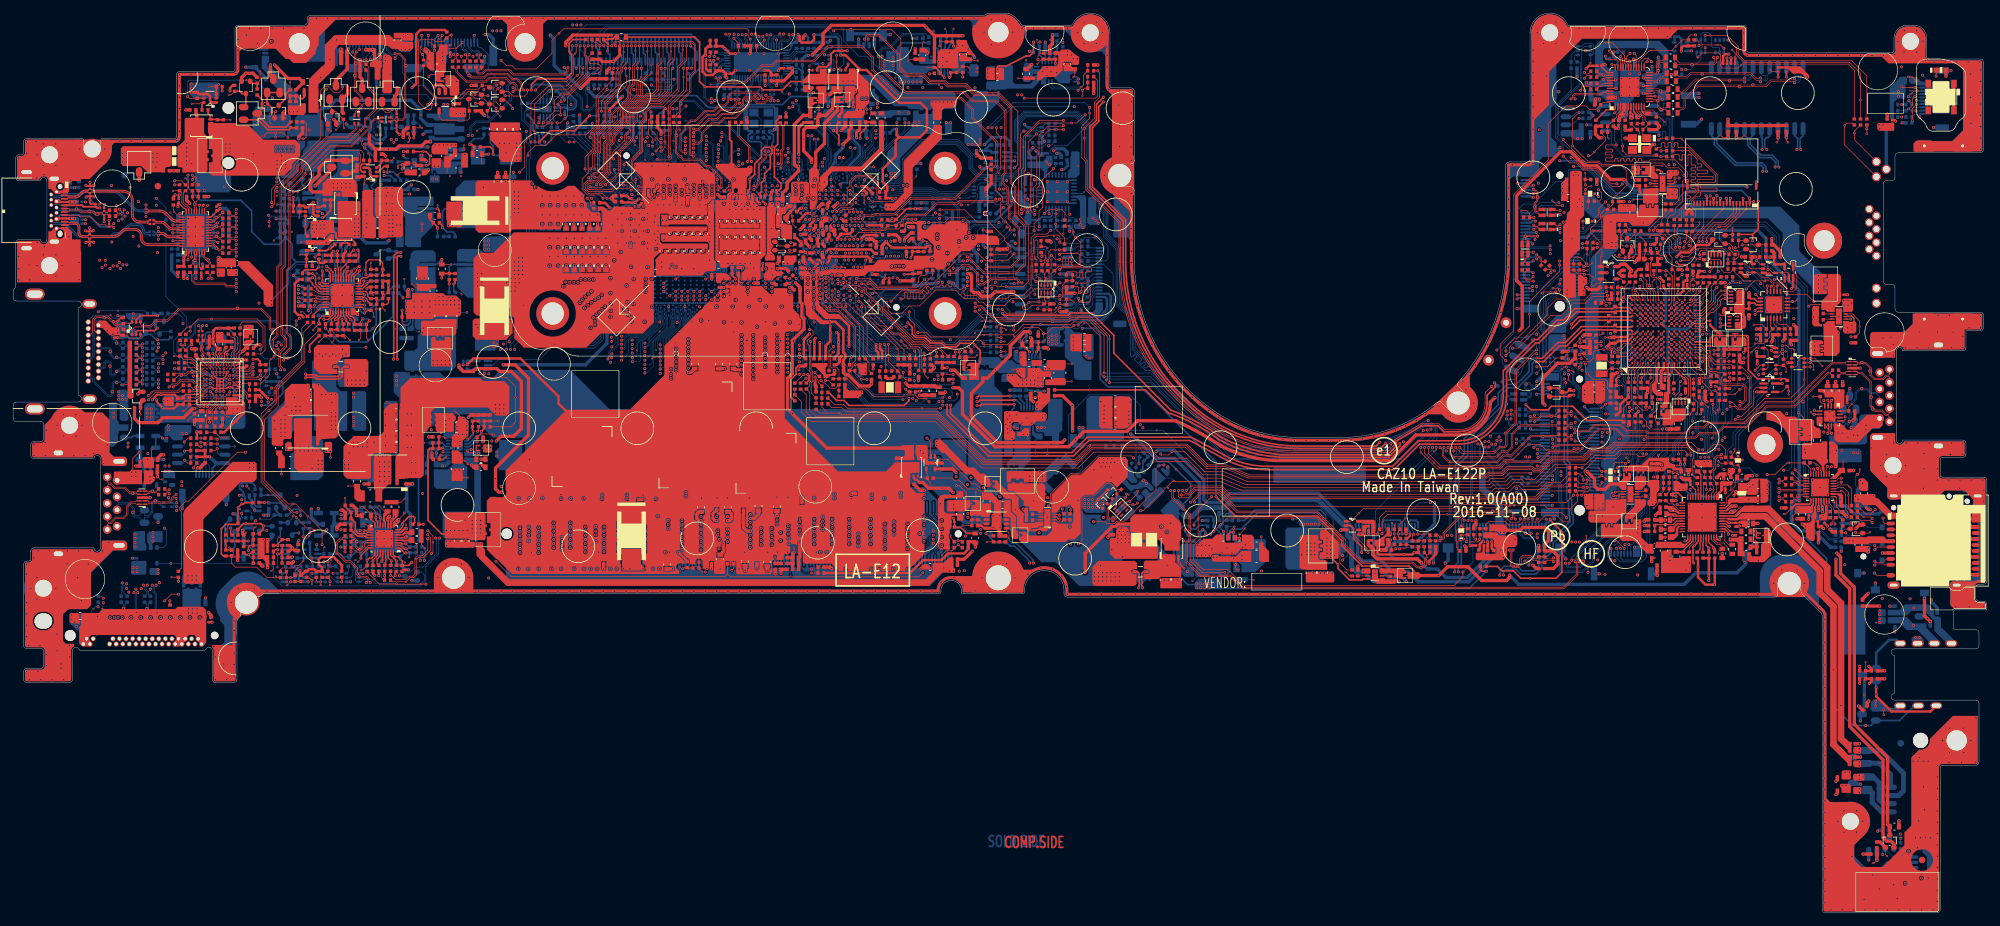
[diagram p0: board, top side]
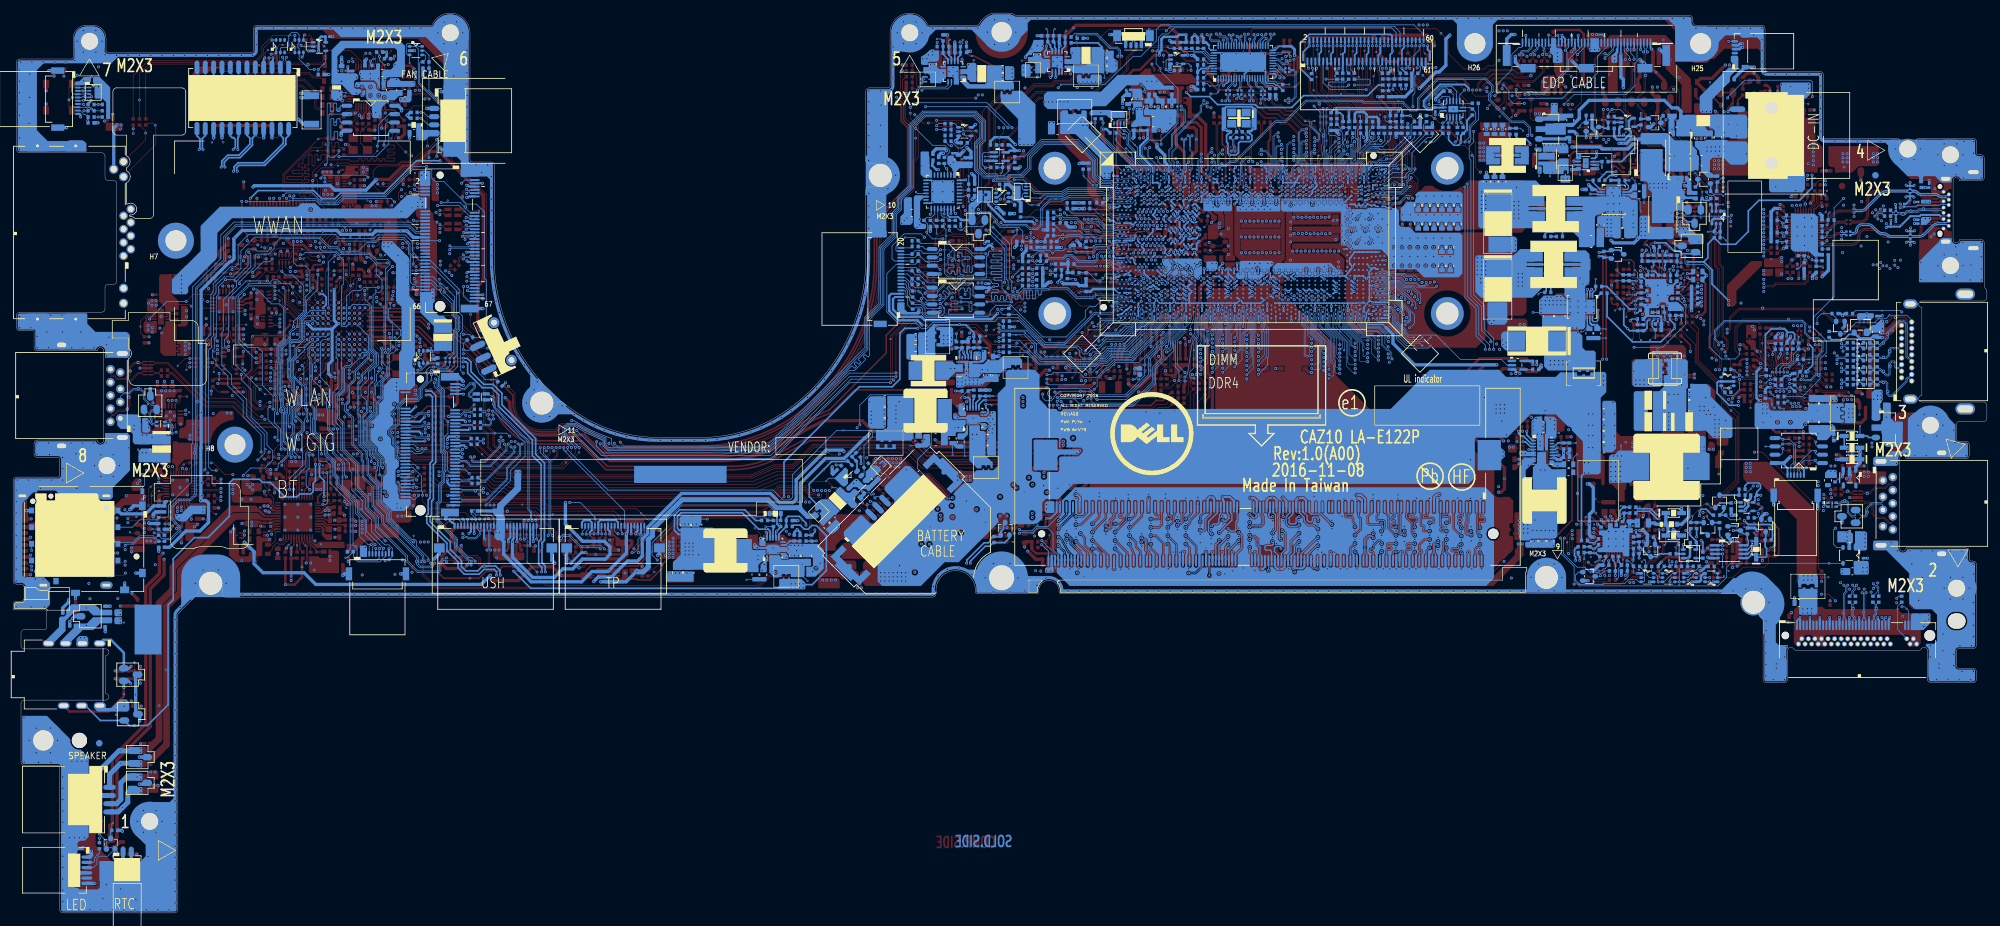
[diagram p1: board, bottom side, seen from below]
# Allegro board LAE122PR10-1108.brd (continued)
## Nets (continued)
ESPI_IO2: JESPI.5 RC368.2 UE1.G6
ESPI_IO2_R: RC368.1 UC1.BB13
ESPI_IO3: JESPI.6 RC369.2 UE1.L5
ESPI_IO3_R: RC369.1 UC1.AY12
ESPI_RESET#: UC1.BA11 UE1.K6
EXPANDER_ALERT#: T267.1(TP-1) UE2.7
EXPANDER_GPU_SMCLK: RE525.1 UE1.M4 UE2.19
EXPANDER_GPU_SMDAT: RE524.1 UE1.M7 UE2.20
FAN1_PWM: JFAN1.2 RE48.2 UE1.L10
FAN1_TACH: JFAN1.3 RE51.2 UE1.E3
FB_1.8VALW: PC503.2 PR501.2 PR506.1 PU501.6
FB_+1VALWP: PR306.2 PR308.2 PR311.1 PU301.4
FB_IA: PR645.2 PR648.2 PR650.1 PU602.17
FB_VSA: PR646.1 PR649.1 PR652.1 PU602.25
FCCM_GT: PR671.2 PU602.11
FCCM_IA: PR659.2 PU602.21
FCCM_VSA: PR679.2 PU602.29
FIVR_EN: RC217.1 RC218.1 RC219.1
FIVR_EN_R: JXDP1.45 RC126.2 RC132.1 RC217.2
GPIO126: RE5.1 UE1.E12
GPP_B23: RC317.1 UC1.AM7
GPP_C5: RC25.1 UC1.W1
GPP_C8: RC405.1 UC1.AB1
GPP_E23: T120.1(TP-1) UC1.N12
GPU_B+: PC664.1 PC665.1 PC672.1 PC673.1 PC679.1 PC688.1 PJP602.1 PU612.5
GT1P: PL612.3 PR674.2
GT_SNUB1: PC678.1 PR676.2
GT_SW1: PL612.4 PR676.1 PU612.4
H_CATERR#: RC79.1 UC1.D63
H_CPU_SVIDALRT#: RC153.1 UC1.B63
H_CPUPWRGD: CC300.1 RC77.2 UC1.A68
H_CPUPWRGD_R: RC77.1 T9.1(TP-1)
H_PROCHOT#: CC310.1 PC605.2 PR678.1 PR926.1 RC83.1 RC84.1 RE288.2
H_PROCHOT#_R: RC84.2 UC1.C65
H_PROCHOT#_R1: RE288.1 UE1.H13
H_THERMTRIP#: CC312.1 QE4.3 RC80.1 RD14.2 UC1.C63
H_VCCST_PWRGD_XDP: CC307.1 JXDP1.39 RC123.2 RC124.2
HDA_BIT_CLK: RC93.2 UC1.AY22
HDA_BIT_CLK_R: CC27.1 RA17.1 RC93.1 UA1.6
HDA_RST#: CC331.1 RC95.2 UC1.AW22
HDA_RST#_R: RA50.1 RC95.1
HDA_SDIN0: CC332.1 RA9.1 UC1.BA21
HDA_SDIN0_R: RA9.2 UA1.8
HDA_SDOUT: CC333.1 RC94.2 RC187.1 RC223.2 UC1.BB22
HDA_SDOUT_R: RC94.1 UA1.5
HDA_SYNC: RC92.2 UC1.BA22
HDA_SYNC_R: RC92.1 UA1.10
HDD_DET#: RPC4.1 UC1.H2
HDMI_CEC: JHDMI1.13 RV19.1
HDMI_CLKN: CV38.1 LV12.1 LV38.1 RV17.1
HDMI_CLKP: CV37.1 LV12.2 LV37.1 RV16.1
HDMI_CTRL_CLK: JHDMI1.15 QV3.6 RV22.1
HDMI_CTRL_DATA: JHDMI1.16 QV3.3 RV23.1
HDMI_HPD: JHDMI1.19 QV5.1 RV21.1
HDMI_L_CLKN: JHDMI1.12 LV12.4 LV38.2 RV35.1
HDMI_L_CLKP: JHDMI1.10 LV12.3 LV37.2 RV35.2
HDMI_L_TX_N0: JHDMI1.9 LV9.4 LV36.2 RV32.1
HDMI_L_TX_N1: JHDMI1.6 LV6.4 LV34.2 RV29.1
HDMI_L_TX_N2: JHDMI1.3 LV3.4 LV32.2 RV26.1
HDMI_L_TX_P0: JHDMI1.7 LV9.3 LV35.2 RV32.2
HDMI_L_TX_P1: JHDMI1.4 LV6.3 LV33.2 RV29.2
HDMI_L_TX_P2: JHDMI1.1 LV3.3 LV31.2 RV26.2
HDMI_OB: QV4.1 RV10.2 RV11.2 RV12.2 RV13.2 RV14.2 RV15.2 RV16.2 RV17.2
HDMI_TX_N0: CV36.2 LV9.1 LV36.1 RV15.1
HDMI_TX_N1: CV34.2 LV6.1 LV34.1 RV13.1
HDMI_TX_N2: CV32.2 LV3.1 LV32.1 RV11.1
HDMI_TX_P0: CV35.2 LV9.2 LV35.1 RV14.1
HDMI_TX_P1: CV33.2 LV6.2 LV33.1 RV12.1
HDMI_TX_P2: CV31.2 LV3.2 LV31.1 RV10.1
HOST_DEBUG_TX: JDEG1.8 RE73.2 RE306.2 RZ132.1 UE1.G11
HOST_SD_WP#: QR1.2 RC292.1 UC1.W10
HP_OUT_L: CA43.2 RA7.1 UA1.32
HP_OUT_R: CA44.2 RA8.1 UA1.33
HV_GATE1_A: RT64.1 UT5.B9
HV_GATE2_A: RT65.1 UT5.A9
HW_GPS_DISABLE#: DZ6.1 RE12.1 UE1.H5
HW_GPS_DISABLE#_R: DZ6.2 JNGFF2.18
I2C1_SCK_TP: RZ21.2 RZ29.1 UC1.U9
I2C1_SCK_TP_R: JKBTP1.2 RZ29.2 RZ117.2 RZ347.2
I2C1_SDA_TP: RZ20.2 RZ26.1 UC1.U8
I2C1_SDA_TP_R: JKBTP1.3 RZ26.2 RZ116.2 RZ346.2
I_ADP: PR935.2 UE1.B11
I_BATT: PR947.2 RE64.2
I_BATT_R: CE3.1 RE64.1 UE1.J4
I_SYS: PR620.1 PR936.2 RE312.2
I_SYS_R: CE4.1 RE312.1 RE313.1 UE1.J5
ILIM_SEL: RI13.1 UI3.4
ILMT_+1VALWP: PR307.2 PR310.1 PU301.3
ILMT_DDR: PR205.1 PR207.2 PU200.17
IMON_IA: PC625.2 PR629.2 PU602.14
IMON_VSA: PC643.1 PR651.1 PU602.23
IMVP_VR_ON: PR616.1 RE304.1 UE3.4 UE4.2
IMVP_VR_ON_EC: RE304.2 RPE10.2 UE1.N7 UE3.1
INT_SPK_L+: CA22.1 LA6.1 UA1.42
INT_SPK_L-: CA23.1 LA7.1 UA1.43
INT_SPK_R+: CA19.1 LA8.1 UA1.45
INT_SPK_R-: CA24.1 LA9.1 UA1.44
INT_SPKR_L+: DA6.3 JSPK1.1 LA6.2
INT_SPKR_L-: DA6.2 JSPK1.2 LA7.2
INT_SPKR_R+: DA7.2 JSPK1.3 LA8.2
INT_SPKR_R-: DA7.3 JSPK1.4 LA9.2
INTRUDER#: RC69.1 UC1.AP16
IR_CAM_DET#: JIR1.6 RC345.1 UC1.H5
ISH_I2C2_SCL: RC362.1 RZ76.1 UC1.AD12
ISH_I2C2_SCL_R: JNGFF2.32 RZ76.2
ISH_I2C2_SDA: RC363.1 RZ77.1 UC1.AD11
ISH_I2C2_SDA_R: JNGFF2.34 RZ77.2
ISH_UART0_CTS#: RZ80.1 UC1.U4
ISH_UART0_CTS#_R: JNGFF1.62 RZ80.2
ISH_UART0_RTS#: RZ81.1 UC1.U3
ISH_UART0_RTS#_R: JNGFF1.64 RZ81.2
ISH_UART0_RXD: RZ78.1 UC1.U1
ISH_UART0_RXD_R: JNGFF1.58 RZ78.2
ISH_UART0_TXD: RZ79.1 UC1.U2
ISH_UART0_TXD_R: JNGFF1.60 RZ79.2
ISUMN_GT: PC624.2 PC626.2 PC641.1 PH602.2 PL612.2 PR632.1 PR633.2 PR638.1
ISUMN_IA: PC642.2 PC645.1 PC646.2 PH605.2 PL610.2 PR640.2 PR644.2 PR656.2
ISUMN_VSA: PC633.2 PC637.2 PC644.1 PH604.2 PL614.2 PR636.2 PR641.2 PR643.1
ISUMP_GT: PC624.1 PC626.1 PR628.1 PR633.1 PR674.1 PU602.7
ISUMP_IA: PC642.1 PC646.1 PR656.1 PR657.1 PR661.2 PU602.19
ISUMP_VSA: PC633.1 PC637.1 PR624.2 PR642.1 PR643.2 PU602.27
ITP_PMODE: JXDP1.46 RC115.1 UC1.E8
JDIMM1_EVENT#: JDIMM1.134 RD14.1
JTAG_CLK: JDEG1.4 RPE7.3 UE1.C8
JTAG_RST#: CE30.1 JTAG1.1 RE63.1 RE65.1 UE1.G13
JTAG_TDI: JDEG1.2 RPE7.1 UE1.E9
JTAG_TDO: JDEG1.5 RPE7.4 UE1.F6
JTAG_TMS: JDEG1.3 RPE7.2 UE1.C5
KB_DET#: JKBTP1.20 RC288.1 UC1.D8
LAN_ACTLED_YEL#: QL1.6 RL14.1
LAN_ACTLED_YEL_R#: JLOM1.10 RL14.2
LAN_DISABLE#_R: RL5.1 RL7.2 RL9.1 UL1.3
LAN_MDIN0: RL72.1 UL1.14
LAN_MDIN0_L: RL72.2 TL1.11
LAN_MDIN1: RL74.1 UL1.18
LAN_MDIN1_L: RL74.2 TL1.5
LAN_MDIN2: RL76.1 UL1.21
LAN_MDIN2_L: RL76.2 TL1.7
LAN_MDIN3: RL78.1 UL1.24
LAN_MDIN3_L: RL78.2 TL1.1
LAN_MDIP0: RL71.1 UL1.13
LAN_MDIP0_L: RL71.2 TL1.12
LAN_MDIP1: RL73.1 UL1.17
LAN_MDIP1_L: RL73.2 TL1.6
LAN_MDIP2: RL75.1 UL1.20
LAN_MDIP2_L: RL75.2 TL1.8
LAN_MDIP3: RL77.1 UL1.23
LAN_MDIP3_L: RL77.2 TL1.2
LAN_TEST_EN: RL12.1 UL1.30
LAN_WAKE#: RC323.1 RL70.1 UC1.AM15 UE1.L3 UL1.2
LCD_CBL_DET#: JEDP1.40 RC287.1 UC1.AC3
LCD_TST: JEDP1.29 RE20.1 UE1.D1
LCD_VCC_TEST_EN: DV3.2 UE1.E1
LED_10_GRN#: QL2.6 RL19.1
LED_10_GRN_R#: JLOM1.11 RL19.2
LED_100_ORG#: QL1.3 RL20.1
LED_100_ORG_R#: JLOM1.13 RL20.2
LG1_ISL88738: PQ905.6 PU901.9
LG2_ISL88738: PQ904.6 PU901.7
LID_CL#: JLED1.5 RE26.1 UZ10.2
LID_CL#_NB: CE8.1 RE25.2 RE26.2 UE1.N11
LID_CL#_PCH: T268.1(TP-1) UC1.AW7
LINE1_L: CA43.1 UA1.22
LINE1_R: CA44.1 UA1.21
LM393_P: PC949.2 PC1201.2 PD1801.1 PR950.2 PU903.5 PU1201.8
LOM_ACTLED_YEL#: QL1.1 UL1.26
LOM_CABLE_DETECT#: RE505.1 UE1.D2 UL2.4
LOM_SPD10LED_GRN#: QL2.1 RL30.2 UL1.25 UL2.2
LOM_SPD100LED_ORG#: QL1.4 RL29.2 UL1.27 UL2.1
LPS_PROTECT#: PR1248.2 PT1.1(TP-1)
LPSS_UART2_RXD: JUART1.3 RC330.1 RC402.1 UC1.AD1
LPSS_UART2_TXD: JUART1.2 RC331.1 RC403.1 UC1.AD2
LX1_ISL88738: PC930.2 PL902.1 PQ905.7 PR923.1 PU901.10
LX2_ISL88738: PL902.2 PQ904.7 PR921.1 PR924.1 PU901.6
LX_1.8VALW: PL501.1 PR502.1 PU501.3
LX_1V_PRIM: PL404.1 PR409.1 PU402.2 PU402.3
LX_1VS_VCCIO: PL402.1 PR405.1 PU401.2 PU401.3
LX_3V: PC102.2 PL100.1 PR106.1 PU100.6 PU100.19 PU100.20
LX_5V: PC114.2 PL101.1 PR112.1 PU102.6 PU102.19 PU102.20
LX_DDR: PC205.2 PL201.1 PR202.1 PU200.11
M2280_DEVSLP: JNGFF3.38 RN37.2 UC1.J3
M2280_PCIE_SATA#: JNGFF3.69 RPC4.4 UC1.G4
M3042_DEVSLP: JNGFF2.30 UC1.J2
M3042_PCIE#_SATA: RPC4.2 UC1.H3 UE1.J12
MASK_BASE_LEDS#: QZ7.5 UZ10.4
ME_FW_EC: RC221.1 SW1.1 UE1.G12
ME_FWP: RC221.2 RC223.1 SW1.3
ME_RESET#: RC225.1 RC227.1 UC12.2
ME_SUS_PWR_ACK: RC74.1 UC1.AR13 UE1.B13
MEC_XTAL1: CE28.1 UE1.A1 YE1.1
MEC_XTAL2: CE29.1 RE290.2 YE1.2
MEC_XTAL2_R: RE290.1 UE1.A3
MEDIACARD_IRQ#: RR19.1 UC1.AN8 UR1.32
MEM_INTERLEAVED: RC371.1 RC372.1 UC1.P2
MEM_SMBCLK: CC320.1 QC2.6 RC12.1 UC1.R7
MEM_SMBDATA: QC2.3 RC14.1 UC1.R8
MPHYP_PWR_EN: RC387.1 UC1.AM10
MSCLK: JDEG1.6 RE30.1 RE72.2 UE1.H10
MSDATA: JDEG1.7 RE75.2 RE86.1 UE1.G9
MUX1_DP_SEL: RT89.1 UT9.23
MUX1_DPEQ0: RT139.1 RT140.1 RT306.1 UT9.14
MUX1_DPEQ1: RT247.1 RT248.1 RT303.1 UT9.2
MUX1_FLIP_SEL: RT69.1 RT375.1 UT9.21
MUX1_FLIP_SEL_R: RT69.2 UT5.B2
MUX1_I2C_EN: RT145.1 RT300.1 RT301.1 UT9.17
MUX1_SSEQ0: RT137.1 RT138.1 RT302.1 UT9.11
MUX1_SSEQ1: RT135.1 RT136.1 RT305.1 UT9.3
MUX1_USB_EQ0: RT143.1 RT144.1 RT304.1 UT9.38
MUX1_USB_EQ1: RT141.1 RT142.1 RT307.1 UT9.35
MUX1_USB_SEL: RT90.1 RT376.1 UT9.22
NB_PSID: PD4.2 PD4.3 PJPDC1.1 PL3.2
NRB_BIT: RC186.1 UC1.AR7
NTC_IA: PR635.2 PU602.15
NVME_LED#: JNGFF3.10 RN100.1
ONE_DIMM#: RC267.1 RC268.1 UC1.AP7
OTG_ID: RT74.1 UT5.E10
OTGEN/CMIN: PR919.2 PR960.2 PU901.20
PANEL_BKEN_EC: DV2.2 UE1.J9
PANEL_BKLEN: DV2.3 UC1.R12
PANEL_ID: CE47.1 RE300.2 UE1.J10
PBAT_CHARGER_SMBCLK: PD2.3 PR922.1 PRP1.3 RE43.1 UE1.N2
PBAT_CHARGER_SMBDAT: PD1.2 PR920.1 PRP1.2 RE37.1 UE1.M3
PBAT_PRES#: PD1.3 PR1.2 PR931.1 PRP1.1 UE1.F9
PBAT_PRES#_C: PBATT1.6 PRP1.8
PBAT_SMBCLK_C: PBATT1.4 PRP1.6
PBAT_SMBDAT_C: PBATT1.5 PRP1.7
PBATT+_C: PBATT1.1 PBATT1.2 PBATT1.3 PC1.1 PL1.1 PL2.1
PCH_ALW_ON: RPE10.3 RZ65.1 UE1.M8
PCH_BATLOW#: RC72.1 UC1.AU13
PCH_CL_CLK1: JNGFF1.42 UC1.G3
PCH_CL_DATA1: JNGFF1.40 UC1.G2
PCH_CL_RST1#: JNGFF1.38 UC1.G1
PCH_DPWROK: CC266.1 RC215.1 RC220.1 RE536.2 UC1.BB20 UE7.1
PCH_DPWROK_EC: RE34.1 UE1.F8
PCH_JTAG_TCK: JXDP1.55 RC86.1 UC1.B56
PCH_JTAG_TDI: CC304.1 RC81.1 RC229.2 UC1.D59
PCH_JTAG_TDO: CC303.1 RC82.1 RC230.2 UC1.A56
PCH_JTAG_TMS: RC130.1 RC228.2 UC1.C59
PCH_PCIE_WAKE#: RC67.1 RE274.2 UC1.BB15 UE1.L1
PCH_PLTRST#: RC60.1 RC62.1 RC244.1 UC1.AN10 UC7.1 UC7.2
PCH_PLTRST#_5105: RE340.1 UE1.K1 UE6.4
PCH_PLTRST#_AND: CZ61.1 JNGFF1.52 JNGFF1.66 JNGFF2.42 JNGFF3.50 RC65.1 RC325.1 RZ114.1 UC7.4 UR1.1
PCH_PLTRST#_EC: RC244.2 RE375.2 UE6.2
PCH_POPIRCOMP: RC89.1 UC1.AU16
PCH_PWROK: PR614.1 RC411.1 UC1.BA20
PCH_RSMRST#: RE342.1 RE363.2 RE364.2 UZ6.1
PCH_RSMRST#_AND: RC75.1 RC124.1 RC215.2 UC1.AY17 UZ6.4
PCH_RSMRST#_GPIO204: RE363.1 UE1.H2
PCH_RTCRST#: CC25.1 CMOS1.1 JAPS1.9 RC57.1 RE94.2 UC1.AM16
PCH_RTCX1: CC23.1 RC54.2 UC1.AM18 YC2.1
PCH_RTCX2: RC54.1 RC296.1 UC1.AM20
PCH_RTCX2_R: CC26.1 RC296.2 YC2.2
PCH_SMB_ALERT#: RC23.1 UC1.R10
PCH_SPI_CLK: JSPI1.13 RC35.1 UC1.AV2
PCH_SPI_CLK_0_R: RC29.1 RPC1.6 UC5.6
PCH_SPI_CLK_1_R: RC28.1 RC408.2 UC6.6
PCH_SPI_CLK_2_R: RZ60.2 RZ63.2 UZ12.19
PCH_SPI_CLK_R1: JSPI1.14 RC35.2 RC408.1 RPC1.3 RZ60.1
PCH_SPI_CS#0: JSPI1.11 RC36.1 UC1.AU3
PCH_SPI_CS#0_R1: JSPI1.12 RC36.2 RC37.1
PCH_SPI_CS#0_R2: RC37.2 UC5.1
PCH_SPI_CS#1: JSPI1.19 RC32.2 UC1.AU2
PCH_SPI_CS#1_R1: JSPI1.20 RC32.1 RC42.1
PCH_SPI_CS#1_R2: RC42.2 UC6.1
PCH_SPI_CS#2: RZ61.1 UC1.AU1
PCH_SPI_CS#2_R: RZ61.2 RZ113.1 UZ12.20
PCH_SPI_D0: JSPI1.17 RC10.2 RC33.1 UC1.AV3
PCH_SPI_D0_0_R: RPC1.7 UC5.5
PCH_SPI_D0_1_R: RC409.2 UC6.5
PCH_SPI_D0_2_R: RZ59.2 UZ12.21
PCH_SPI_D0_R1: JSPI1.18 RC33.2 RC409.1 RPC1.2 RZ59.1
PCH_SPI_D1: JSPI1.15 RC34.1 UC1.AW3
PCH_SPI_D1_0_R: RPC1.8 UC5.2
PCH_SPI_D1_1_R: RC410.2 UC6.2
PCH_SPI_D1_2_R: RZ58.2 UZ12.24
PCH_SPI_D1_R1: JSPI1.16 RC34.2 RC410.1 RPC1.1 RZ58.1
PCH_SPI_D2: JSPI1.9 RC11.2 RC38.1 UC1.AW2
PCH_SPI_D2_0_R: RC39.2 UC5.3
PCH_SPI_D2_1_R: RC43.2 UC6.3
PCH_SPI_D2_R1: JSPI1.10 RC30.1 RC38.2 RC39.1 RC43.1
PCH_SPI_D3: JSPI1.7 RC40.1 UC1.AU4
PCH_SPI_D3_0_R: RPC1.5 UC5.7
PCH_SPI_D3_1_R: RC407.2 UC6.7
PCH_SPI_D3_R1: JSPI1.8 RC31.1 RC40.2 RC316.1 RC407.1 RPC1.4
PCH_SPI_DO2_XDP: JXDP1.60 RC11.1
PCH_SPI_DO_XDP: RC10.1 RC128.1 RC133.1
PCI_CLK_LPC1: RC22.1 UC1.AY9
PCIE_PRX_C_DTX_N1: CR14.2 UR1.8
PCIE_PRX_C_DTX_N9: CL2.2 UL1.39
PCIE_PRX_C_DTX_P1: CR13.2 UR1.7
PCIE_PRX_C_DTX_P9: CL1.2 UL1.38
PCIE_PRX_DTX_N1: CR14.1 UC1.H13
PCIE_PRX_DTX_N3: JNGFF1.43 UC1.H16
PCIE_PRX_DTX_N4: JNGFF1.67 UC1.G15
PCIE_PRX_DTX_N9: CL2.1 UC1.E22
PCIE_PRX_DTX_N11: JNGFF3.29 UC1.E28
PCIE_PRX_DTX_N12: JNGFF3.43 UC1.E30
PCIE_PRX_DTX_P1: CR13.1 UC1.G13
PCIE_PRX_DTX_P3: JNGFF1.41 UC1.G16
PCIE_PRX_DTX_P4: JNGFF1.65 UC1.F15
PCIE_PRX_DTX_P9: CL1.1 UC1.E23
PCIE_PRX_DTX_P11: JNGFF3.31 UC1.E27
PCIE_PRX_DTX_P12: JNGFF3.41 UC1.F30
PCIE_PTX_C_DRX_N1: CR12.2 UR1.4
PCIE_PTX_C_DRX_N3: CZ13.2 JNGFF1.37
PCIE_PTX_C_DRX_N4: CZ15.2 JNGFF1.61
PCIE_PTX_C_DRX_N9: CL6.2 UL1.42
PCIE_PTX_C_DRX_N11: CN69.1 JNGFF3.35
PCIE_PTX_C_DRX_N12: CN71.1 JNGFF3.47
PCIE_PTX_C_DRX_P1: CR11.2 UR1.3
PCIE_PTX_C_DRX_P3: CZ12.2 JNGFF1.35
PCIE_PTX_C_DRX_P4: CZ14.2 JNGFF1.59
PCIE_PTX_C_DRX_P9: CL5.2 UL1.41
PCIE_PTX_C_DRX_P11: CN70.1 JNGFF3.37
PCIE_PTX_C_DRX_P12: CN72.1 JNGFF3.49
PCIE_PTX_DRX_N1: CR12.1 UC1.B17
PCIE_PTX_DRX_N3: CZ13.1 UC1.D17
PCIE_PTX_DRX_N4: CZ15.1 UC1.B19
PCIE_PTX_DRX_N9: CL6.1 UC1.B23
PCIE_PTX_DRX_N11: CN69.2 UC1.D24
PCIE_PTX_DRX_N12: CN71.2 UC1.A25
PCIE_PTX_DRX_P1: CR11.1 UC1.A17
PCIE_PTX_DRX_P3: CZ12.1 UC1.C17
PCIE_PTX_DRX_P4: CZ14.1 UC1.A19
PCIE_PTX_DRX_P9: CL5.1 UC1.A23
PCIE_PTX_DRX_P11: CN70.2 UC1.C24
PCIE_PTX_DRX_P12: CN72.2 UC1.B25
PCIE_RCOMPN: RC45.1 UC1.F5
PCIE_RCOMPP: RC45.2 UC1.E5
PCIE_WAKE#: JNGFF1.55 JNGFF1.70 JNGFF2.46 JNGFF3.54 RE274.1 RE275.2
PCIE_WAKE#_R: RE35.1 RE275.1 UE1.N13
PD1_GPIO2: RT71.1 UT5.D10
PD1_GPIO6: RT75.1 UT5.G10
PD1_GPIO7: RT339.1 UT5.D7
PD1_GPIO8: RT76.1 RT377.1 UT5.H6
PD#: CA31.1 DA8.2 RA18.1 RA48.2 RA50.2 UA1.47
PECI_EC: RE60.2 UC1.A54
PECI_EC_R: RE60.1 UE1.K13
PGOOD_3V: PR107.2 PR119.1 PU100.9
PGOOD_5V: PR113.2 PR120.1 PU102.9
PLTRST_LAN#: RC62.2 UL1.36
PLTRST_TPM#: RC60.2 RC325.2 UZ12.17
PM_LANPHY_ENABLE: RL7.1 UC1.AW17
PME#: T115.1(TP-1) UC1.AU11
POA_WAKE#: JUSH1.4 RE324.1 UE1.E4
PORT80_DET#: RE512.1 RE513.1 RZ131.1 UE1.K4
POWER_SW#_MB: CE10.1 JAPS1.11 RE33.2 SW3.2 SW3.4
POWER_SW_IN#: CE12.1 RE31.2 RE33.1 UE1.D5
PRIM_PWRGD_GPIO024: RE361.1 RE362.1 UE1.C1
PROCHOT#_ISL88738: PQ1216.1 PR926.2 PU901.23
PS_ID: PR4.1 PR5.2 UE1.L11
PWM1_GT: PR680.1 PU602.12 PU612.8
PWM_IA: PR662.1 PU602.22 PU610.8
PWM_SA: PR606.1 PU614.3
PWM_VSA: PR606.2 PU602.30
REM_DIODE1_N: CE24.1 CE35.1 QE3.3 UE1.A8
REM_DIODE1_P: CE24.2 CE35.2 QE3.1 QE3.2 UE1.A7
REM_DIODE2_N: CE26.1 CE37.2 CE46.2 QE5.3 QE7.1 QE7.2 UE1.A10
REM_DIODE2_P: CE26.2 CE37.1 CE46.1 QE5.1 QE5.2 QE7.3 UE1.A9
REM_DIODE4_N: CE27.1 CE39.1 QE6.3 UE1.A11
REM_DIODE4_P: CE27.2 CE39.2 QE6.1 QE6.2 UE1.B10
RES_BIAS: RL13.1 UL1.12
RESET_OUT#_R: CC33.1 JXDP1.47 RC128.2 RC129.2
RING2: LA10.1 RA5.2 UA1.17
RING2_R: CA4.1 CA13.2 DA3.3 JHP1.4 LA10.2
RJ45_MDIN0: JLOM1.2 TL1.14
RJ45_MDIN1: JLOM1.6 TL1.20
RJ45_MDIN2: JLOM1.5 TL1.18
RJ45_MDIN3: JLOM1.8 TL1.24
RJ45_MDIP0: JLOM1.1 TL1.13
RJ45_MDIP1: JLOM1.3 TL1.19
RJ45_MDIP2: JLOM1.4 TL1.17
RJ45_MDIP3: JLOM1.7 TL1.23
RTCRST_ON: QE12.2 RE93.1 RE514.2 RE515.2
RTCRST_ON_GPIO122: RE515.1 UE1.F11
RTCRST_ON_GPIO141: RE514.1 UE1.B6
RTD3_CIO_PWR_EN: T18.1(TP-1) UC1.AC2
RUN_ON: PR402.1 QE2.2 RE280.2 RE292.1 RZ320.1 RZ345.1 UE5.4 UZ3.5 UZ4.3 UZ35.2
RUN_ON#: QE2.5 QE2.6 RE68.1
RUN_ON_EC: RE292.2 RPE10.4 UE1.E8 UE5.2
RUNPWROK: QE2.3 RE67.1 UC8.1 UC8.4 UC8.10 UC8.13 UE1.G3
SA_LGATE: PQ501.8 PU614.5
SA_SNUB: PC622.1 PR627.2
SA_SW: PL614.4 PQ501.9 PR619.2 PR627.1 PU614.8
SA_UGATE: PQ501.1 PU614.1
SATA_LED_EN: QZ2.5 UE2.14
SATA_PRX_DTX_N1: JNGFF2.35 UC1.G21
SATA_PRX_DTX_P1: JNGFF2.33 UC1.F21
SATA_PTX_C_DRX_N1: CZ10.2 JNGFF2.39
SATA_PTX_C_DRX_P1: CZ11.2 JNGFF2.41
SATA_PTX_DRX_N1: CZ10.1 UC1.D21
SATA_PTX_DRX_P1: CZ11.1 UC1.C21
SATALED#: QZ2.4 RN100.2 RN101.2 RPC4.3 UC1.H1
SBIOS_TX: RE306.1 UC1.AB2
SD/MMCCD#: JSD1.9 UR1.30
SD/MMCCLK: RR5.1 UR1.17
SD/MMCCLK_R: CR21.1 JSD1.5 RR5.2
SD/MMCCMD: RR6.1 UR1.19
SD/MMCCMD_R: JSD1.3 RR6.2
SD/MMCDAT0/RCLK+: RR10.1 UR1.16
SD/MMCDAT0/RCLK+_R: JSD1.7 RR10.2
SD/MMCDAT1/RCLK-: RR9.1 UR1.15
SD/MMCDAT1/RCLK-_R: JSD1.8 RR9.2
SD/MMCDAT2: RR8.1 UR1.21
SD/MMCDAT2_R: JSD1.1 RR8.2
SD/MMCDAT3: RR7.1 UR1.20
SD/MMCDAT3_R: JSD1.2 RR7.2
SD_GPIO: RR3.2 UR1.28
SD_RCOMP: RC96.1 UC1.AB7
SD_UHS2_D0N: JSD1.19 UR1.25
SD_UHS2_D0P: JSD1.18 UR1.26
SD_UHS2_D1N: JSD1.21 UR1.23
SD_UHS2_D1P: JSD1.22 UR1.22
SDWP: QR1.1 UR1.29
SHD_CLK: RE374.1 UE1.J8
SHD_CLK_R1: RE374.2 UE9.6
SHD_CS#: RE98.1 RE364.1 UE1.M5 UE9.1
SHD_IO0: CE503.1 QE13.5 RE366.1 RE530.1 UE1.J7
SHD_IO0_R1: RE366.2 RE367.1
SHD_IO0_R2: RE367.2 UE9.5
SHD_IO1: RE368.1 UE1.L6
SHD_IO1_R1: RE368.2 RE369.1
SHD_IO1_R2: RE369.2 UE9.2
SHD_IO2: RE360.1 RE370.1 UE1.L7
SHD_IO2_R1: RE370.2 RE371.1 RE376.1
SHD_IO2_R2: RE371.2 UE9.3
SHD_IO3: RE372.1 UE1.M6
SHD_IO3_R1: RE372.2 RE373.1 RE377.1
SHD_IO3_R2: RE373.2 UE9.7
SIM_DET: JNGFF2.58 JSIM1.2
SIO_EXT_SCI#: RC237.1 RE341.1 UC1.AN7
SIO_EXT_SCI#_EC: RE341.2 UE1.M1
SIO_EXT_SMI#: RC346.1 RE338.1 UC1.A6
SIO_EXT_SMI#_EC: RE338.2 UE1.K7
SIO_EXT_WAKE#: RC283.1 UC1.AC1 UE1.M12
SIO_PWRBTN#: CC269.1 JXDP1.41 RC241.1 UC1.BA15 UE1.K11
SIO_RCIN#: RC13.1 RE339.1 UC1.AW13
SIO_RCIN#_EC: RE339.2 UE1.N3
SIO_SLP_A#: JAPS1.6 UC1.AN16 UE1.M11
SIO_SLP_LAN#: RC68.1 RC344.1 UC1.AW15 UE1.H9 UZ2.5
SIO_SLP_S0#: JAPS1.15 PR425.1 PR426.1 RZ112.1 RZ363.1 UC1.AT11 UZ35.1
SIO_SLP_S3#: JAPS1.2 QE11.2 RE280.1 UC1.AP15 UE1.K9 UE3.2 UE5.1
SIO_SLP_S4#: JAPS1.5 PR208.1 PR513.1 UC1.BA16 UE1.N12 UZ21.4 UZ34.2
SIO_SLP_S5#: JAPS1.4 UC1.AY16 UE1.N8
SIO_SLP_SUS#: PR312.2 PR406.1 PR504.1 RE349.1 RZ64.1 UC1.AN15 UZ34.1
SIO_SLP_WLAN#: RZ71.1 UC1.BB17 UE1.D9
SLEEVE: LA11.1 RA6.2 UA1.18
SLEEVE_R: CA1.2 CA12.1 DA3.2 JHP1.3 LA11.2
SLOT2_CONFIG_0: JNGFF2.13 RPE9.4 UE1.N9
SLOT2_CONFIG_1: JNGFF2.61 RPE9.3 UE1.M10
SLOT2_CONFIG_2: JNGFF2.67 RPE9.2 UE1.N10
SLOT2_CONFIG_3: JNGFF2.1 RPE9.1 UE1.F4
SLOT2_SATA_LED#: JNGFF2.10 RN101.1
SM_RCOMP0: RC5.1 UC1.AR18
SM_RCOMP1: RC6.1 UC1.AT18
SM_RCOMP2: RC7.1 UC1.AU18
SML0_SMBCLK: CC318.1 RC19.1 RC347.1 UC1.R9 UL1.28
SML0_SMBDATA: RC20.1 RC348.1 UC1.W2 UL1.31
SML1_SMBCLK: CC319.1 RC15.1 UC1.W3 UE1.D8
SML1_SMBDATA: RC17.1 UC1.V3 UE1.E11
SNB_+1VALWP: PC302.1 PR303.2
SNUB_1.8VALW: PC506.1 PR502.2
SNUB_1V_PRIM: PC419.1 PR409.2
SNUB_1VS_VCCIO: PC401.1 PR405.2
SNUB_CHG1: PC940.1 PR923.2
SNUB_CHG2: PC941.1 PR924.2
SPKR: RA12.2 RC183.1 UC1.AW5
SPKR_R: CA27.1 CA72.1 RA12.1 RA51.1
SRTCRST#: CC24.1 RC56.1 UC1.AN18
SS_1V_PRIM: PC420.1 PR428.1 PU402.7
SS_1VS_VCCIO: PC410.1 PR427.1 PU401.7
SUSACK#: UC1.AP11 UE1.K12
SUSCLK: RC48.1 RN99.2 RZ56.2 UC1.BA17
SUSCLK_R: JNGFF3.68 RN99.1
SW2_DP1_AUXN: CT81.1 CT116.1 RV70.1 UV7.29
SW2_DP1_AUXN_C: CT116.2 RT131.1 UT9.25
SW2_DP1_AUXP: CT80.1 CT115.1 RV76.1 UV7.28
SW2_DP1_AUXP_C: CT115.2 RT130.1 UT9.24
SW2_DP1_CADET: RV73.1 UV7.33
SW2_DP1_HPD: RT73.1 RT380.1 UV7.38
SW2_DP1_HPD_R: RT73.2 UT5.C10
SW2_DP1_N0: CT104.1 UV7.39
SW2_DP1_N0_C: CT104.2 UT9.10
SW2_DP1_N1: CT106.1 UV7.36
SW2_DP1_N1_C: CT106.2 UT9.13
SW2_DP1_N2: CT108.1 UV7.34
SW2_DP1_N2_C: CT108.2 UT9.16
SW2_DP1_N3: CT110.1 UV7.31
SW2_DP1_N3_C: CT110.2 UT9.19
SW2_DP1_P0: CT103.1 UV7.40
SW2_DP1_P0_C: CT103.2 UT9.9
SW2_DP1_P1: CT105.1 UV7.37
SW2_DP1_P1_C: CT105.2 UT9.12
SW2_DP1_P2: CT107.1 UV7.35
SW2_DP1_P2_C: CT107.2 UT9.15
SW2_DP1_P3: CT109.1 UV7.32
SW2_DP1_P3_C: CT109.2 UT9.18
SW2_DP2_AUXN: CV150.1 RV71.1 UV7.27
SW2_DP2_AUXN_C: CV150.2 JNGFF1.20
SW2_DP2_AUXP: CV149.1 RV77.1 UV7.26
SW2_DP2_AUXP_C: CV149.2 JNGFF1.22
SW2_DP2_CADET: RV74.1 UV7.43
SW2_DP2_HPD: JNGFF1.31 UV7.48
SW2_DP2_N0: CV156.1 UV7.49
SW2_DP2_N0_C: CV156.2 JNGFF1.32
SW2_DP2_N1: CV152.1 UV7.46
SW2_DP2_N1_C: CV152.2 JNGFF1.26
SW2_DP2_N2: CV148.1 UV7.44
SW2_DP2_N2_C: CV148.2 JNGFF1.25
SW2_DP2_N3: CV145.1 UV7.41
SW2_DP2_N3_C: CV145.2 JNGFF1.19
SW2_DP2_P0: CV157.1 UV7.50
SW2_DP2_P0_C: CV157.2 JNGFF1.34
SW2_DP2_P1: CV153.1 UV7.47
SW2_DP2_P1_C: CV153.2 JNGFF1.28
SW2_DP2_P2: CV147.1 UV7.45
SW2_DP2_P2_C: CV147.2 JNGFF1.27
SW2_DP2_P3: CV146.1 UV7.42
SW2_DP2_P3_C: CV146.2 JNGFF1.21
SW2_PS8338_CFG0: RV85.1 UV7.59
SW2_PS8338_P0: RV95.1 UV7.60
SW2_PS8338_P1: RV93.1 RV94.1 UV7.1
SW2_PS8338_PC10: RV90.1 RV91.1 UV7.56
SW2_PS8338_PC11: RV83.1 RV84.1 UV7.55
SW2_PS8338_PC20: RV81.1 RV82.1 UV7.54
SW2_PS8338_PC21: RV79.1 RV80.1 UV7.53
SW2_PS8338_PEQ: RV87.1 RV88.1 UV7.8
SW2_PS8338_SW: RV89.1 UV7.18
SW_+1VALWP: PL301.1 PR303.1 PR304.2 PU301.10
SW_USB20_N1: LI7.1 UI3.11
SW_USB20_P1: LI7.4 UI3.10
SYS_LED_MASK#: QL1.2 QL1.5 QL2.2 RE21.1 UE1.A12 UZ10.1
SYS_PWROK: RC129.1 RE56.1 UC1.B6 UE1.G4
SYS_RESET#: CC302.1 JAPS1.13 RC224.2 RC291.1 UC1.B5
SYS_RESET#_R: RC224.1 RC290.2 UC12.4
TBT_FORCE_PWR: T19.1(TP-1) UC1.B7
TBT_RESET_N_EC_R: RE95.2 UE1.L8
TBTA_AUXN_C: CT81.2 RT95.1 UT5.J2
TBTA_AUXP_C: CT80.2 RT96.1 UT5.J1
TBTA_BOT_N: RT122.2 UT5.L7
TBTA_BOT_N_R: DT20.1 JUSBC1.B7 RT122.1
TBTA_BOT_P: RT123.2 UT5.K7
TBTA_BOT_P_R: DT19.1 JUSBC1.B6 RT123.1
TBTA_CC1: CT86.1 DT7.1 JUSBC1.A5 RT104.2 UT5.L9
TBTA_CC2: CT85.1 DT16.1 JUSBC1.B5 RT105.2 UT5.L10
TBTA_DBG_CTL1: RT106.1 UT5.E4
TBTA_DBG_CTL2: RT107.1 UT5.D5
TBTA_DEBUG1: RT92.2 UT5.L2
TBTA_DEBUG2: RT93.2 UT5.K2
TBTA_DEBUG3: RT89.2 UT5.L3
TBTA_DEBUG4: RT90.2 UT5.K3
TBTA_LSRX_R: RT88.2 UT5.K4
TBTA_LSTX_R: RT87.2 UT5.L4
TBTA_MRESET: RT86.1 UT5.E11
TBTA_RESET_N_EC_R: RT110.2 UT5.F11
TBTA_ROM_CLK_PD: RT54.2 UT5.A3
TBTA_ROM_CLK_PD_R: JDB1.2 RT54.1 UT6.6
TBTA_ROM_CS#_PD: RT57.2 UT5.B3
TBTA_ROM_CS#_PD_R: JDB1.5 RT51.2 RT57.1 UT6.1
TBTA_ROM_DI_PD: RT55.2 UT5.B4
TBTA_ROM_DI_PD_R: JDB1.3 RT55.1 UT6.5
TBTA_ROM_DO_PD: RT56.2 UT5.A4
TBTA_ROM_DO_PD_R: JDB1.4 RT52.2 RT56.1 UT6.2
TBTA_ROM_HOLD#_PD: RT50.2 UT6.7
TBTA_ROM_WP#_PD: RT53.2 UT6.3
TBTA_ROSC: RT100.1 UT5.G2
TBTA_RX1N: DT14.1 JUSBC1.B10 UT9.31
TBTA_RX1P: DT13.1 JUSBC1.B11 UT9.30
TBTA_RX2N: DT9.1 JUSBC1.A10 UT9.39
TBTA_RX2P: DT10.1 JUSBC1.A11 UT9.40
TBTA_SBU1: DT8.1 JUSBC1.A8 RT108.2 RT132.2
TBTA_SBU1_R: RT108.1 UT5.K8
TBTA_SBU2: DT15.1 JUSBC1.B8 RT109.2 RT133.2
TBTA_SBU2_R: RT109.1 UT5.L8
TBTA_TOP_N: RT121.1 UT5.L6
TBTA_TOP_N_R: DT12.1 JUSBC1.A7 RT121.2
TBTA_TOP_P: RT120.1 UT5.K6
TBTA_TOP_P_R: DT11.1 JUSBC1.A6 RT120.2
TBTA_TX1N: CT96.1 UT9.34
TBTA_TX1N_C: CT96.2 DT6.1 JUSBC1.A3
TBTA_TX1P: CT95.1 UT9.33
TBTA_TX1P_C: CT95.2 DT5.1 JUSBC1.A2
TBTA_TX2N: CT98.1 UT9.36
TBTA_TX2N_C: CT98.2 DT18.1 JUSBC1.B3
TBTA_TX2P: CT97.1 UT9.37
TBTA_TX2P_C: CT97.2 DT17.1 JUSBC1.B2
TDI_XDP: JXDP1.56 RC229.1 UC8.5
TDO_XDP: CC306.1 JXDP1.52 RC230.1 UC8.2
THERMATRIP1#: RE301.1 UE1.B12
THERMATRIP2#: CE36.1 QE4.1 RE69.2 UE1.H3
TOUCH_SCREEN_DET#: JEDP1.32 RV8.1 UC1.AY5
TOUCH_SCREEN_PD#: JEDP1.5 RC272.1 UC1.A7
TOUCHPAD_INTR#: JKBTP1.5 RC414.1 RE318.2 UC1.BA5
TP_LAN_JTAG_TCK: RL2.1 UL1.35
TP_LAN_JTAG_TDI: T88.1(TP-1) UL1.32
TP_LAN_JTAG_TDO: T89.1(TP-1) UL1.34
TP_LAN_JTAG_TMS: RL1.1 UL1.33
TPM_GPIO4: T283.1(TP-1) UZ12.13
TPM_LPM#: QZ9.1 RZ111.1 RZ363.2 UZ12.3
TPM_PIRQ#: RZ69.2 UC1.AP8 UZ12.18
TPM_TYPE: RC349.1 UC1.AY7
TRST#_XDP: JXDP1.54 UC8.12
TUSB546A_SBU1_R: RT132.1 UT9.27
TUSB546A_SBU2_R: RT133.1 UT9.26
TYPEC_ID: CE62.1 RE343.1 UE1.F2
UART_MISO: RT82.1 RT83.1 UT5.F2
UART_MOSI: RT81.1 RT83.2 UT5.E2
UG1_ISL88738: PQ905.1 PU901.11
UG2_ISL88738: PQ904.1 PU901.5
UIM_CLK: CZ38.1 JNGFF2.24 JSIM1.C3
UIM_DATA: CZ39.1 JNGFF2.26 JSIM1.C7 RZ335.2
UIM_RESET: CZ40.1 JNGFF2.22 JSIM1.C2
UPD1_ALERT#: RE91.1 RT60.1 UE1.F10
UPD1_SMBCLK: QT1.1 RE303.1 RT58.1 UE1.C3
UPD1_SMBCLK_Q: QT1.6 RT58.2 RT67.1 RT92.1 RT375.2 UT5.B5
UPD1_SMBDAT: QT1.4 RE302.1 RT59.1 UE1.B4
UPD1_SMBDAT_Q: QT1.3 RT59.2 RT66.1 RT93.1 RT376.2 UT5.A5
UPD1_SMBUS_ALERT#: RT60.2 RT68.1 UT5.B6
UPD2_ALERT#: RE92.1 UE1.F5
UPD2_SMBCLK: RPE12.3 UE1.D7
UPD2_SMBDAT: RPE12.4 UE1.E7
USB2_ID: RC337.1 RT74.2 UC1.AG3
USB2_VBUSSENSE: RC338.1 UC1.AG4
USB3_PRX_C_DTX_N6: CT112.2 UT9.4
USB3_PRX_C_DTX_P6: CT111.2 UT9.5
USB3_PRX_DTX_N1: DI4.1 DI4.9 JUSB1.5 UC1.H8
USB3_PRX_DTX_N2: LI16.4 RI28.1 UC1.J6
USB3_PRX_DTX_N3: DI1.1 DI1.9 JUSB2.5 UC1.J10
USB3_PRX_DTX_N6: CT112.1 UC1.G11
USB3_PRX_DTX_P1: DI4.2 DI4.8 JUSB1.6 UC1.G8
USB3_PRX_DTX_P2: LI16.1 RI27.1 UC1.H6
USB3_PRX_DTX_P3: DI1.2 DI1.8 JUSB2.6 UC1.H10
USB3_PRX_DTX_P6: CT111.1 UC1.F11
USB3_PRX_L_DTX_N2: JNGFF2.21 LI16.3 RI28.2
USB3_PRX_L_DTX_P2: JNGFF2.23 LI16.2 RI27.2
USB3_PTX_C_DRX_N1: CI13.1 DI4.4 DI4.7 JUSB1.8
USB3_PTX_C_DRX_N2: CI29.1 LI17.1 RI30.1
USB3_PTX_C_DRX_N3: CI5.1 DI1.4 DI1.7 JUSB2.8
USB3_PTX_C_DRX_N6: CT114.2 UT9.7
USB3_PTX_C_DRX_P1: CI16.1 DI4.5 DI4.6 JUSB1.9
USB3_PTX_C_DRX_P2: CI30.1 LI17.4 RI29.1
USB3_PTX_C_DRX_P3: CI4.1 DI1.5 DI1.6 JUSB2.9
USB3_PTX_C_DRX_P6: CT113.2 UT9.8
USB3_PTX_DRX_N1: CI13.2 UC1.C13
USB3_PTX_DRX_N2: CI29.2 UC1.B13
USB3_PTX_DRX_N3: CI5.2 UC1.B15
USB3_PTX_DRX_N6: CT114.1 UC1.D16
USB3_PTX_DRX_P1: CI16.2 UC1.D13
USB3_PTX_DRX_P2: CI30.2 UC1.A13
USB3_PTX_DRX_P3: CI4.2 UC1.A15
USB3_PTX_DRX_P6: CT113.1 UC1.C16
USB3_PTX_L_DRX_N2: JNGFF2.27 LI17.2 RI30.2
USB3_PTX_L_DRX_P2: JNGFF2.29 LI17.3 RI29.2
USB20_N1: UC1.AB9 UI3.2
USB20_N1_R: DI5.2 JUSB1.2 LI7.2
USB20_N2: LI3.1 UC1.AD6
USB20_N2_R: DI2.3 JUSB2.2 LI3.2
USB20_N4: LI8.1 RI48.1 UC1.AD9
USB20_N4_L: JNGFF2.9 LI8.2 RI48.2
USB20_N5: LZ1.1 UC1.AJ1
USB20_N5_R: DV8.1 JEDP1.12 LZ1.2
USB20_N7: LI9.1 RI50.1 UC1.AH1
USB20_N7_L: JNGFF1.5 LI9.2 RI50.2
USB20_N8: LV27.3 UC1.AF8
USB20_N8_R: DV4.2 JEDP1.2 LV27.4
USB20_N9: UC1.AG1 UT5.K5
USB20_N10: JUSH1.8 UC1.AH7
USB20_P1: UC1.AB10 UI3.3
USB20_P1_R: DI5.3 JUSB1.3 LI7.3
USB20_P2: LI3.4 UC1.AD7
USB20_P2_R: DI2.2 JUSB2.3 LI3.3
USB20_P4: LI8.4 RI47.1 UC1.AD10
USB20_P4_L: JNGFF2.7 LI8.3 RI47.2
USB20_P5: LZ1.4 UC1.AJ2
USB20_P5_R: DV7.1 JEDP1.13 LZ1.3
USB20_P7: LI9.4 RI49.1 UC1.AH2
USB20_P7_L: JNGFF1.3 LI9.3 RI49.2
USB20_P8: LV27.2 UC1.AF9
USB20_P8_R: DV4.3 JEDP1.3 LV27.1
USB20_P9: UC1.AG2 UT5.L5
USB20_P10: JUSH1.9 UC1.AH8
USB_OC0#: RPC3.3 UC1.A9 UI3.13
USB_OC1#: RPC3.2 UC1.C9 UI1.3
USB_OC2#: RPC3.1 UC1.D9
USB_OC3#: RPC3.4 UC1.B9
USB_PWR_EN1#: RPE11.3 UE1.K3 UI1.4
USB_PWR_EN2#: RPE11.4 UE1.G5
USB_PWR_SHR_LFT_EN#: RPE11.2 UE1.J3 UI3.6
USB_PWR_SHR_VBUS_EN: RPE11.1 UE1.J2 UI3.5
USBCOMP: RC44.1 UC1.AB6
USH_DET#: DZ7.2 RE526.2 RZ87.1 UE1.C13
USH_DET#_R: DZ7.1 JUSH1.26 RZ87.2
USH_PWR_STATE#: JUSH1.22 RZ10.2 UE2.9
USH_RST#_R: JUSH1.21 RZ114.2
USH_SMBCLK: CZ62.1 JUSH1.11 RZ8.2 UE1.B3
USH_SMBDAT: CZ63.1 JUSH1.12 RZ9.2 UE1.E5
VCI_IN1#: RE507.1 UE1.B5
VCI_IN2#: RE508.1 UE1.D4
VCT_LAN_R1: RL3.1 UL1.6
VGA_ID: RE84.1 RE85.1 UE1.H11
VID0_PRIM_CORE: PR408.2 PR418.2 PR420.1 PU402.9
VID0_VCCIO: PR414.2 PR416.1 PU401.9
VID1_PRIM_CORE: PR411.2 PR417.2 PR419.1 PU402.8
VID1_VCCIO: PR413.2 PR415.1 PU401.8
VIDALERT_N: PR604.2 PR625.1 RC152.1 RC153.2
VIDALERT_N_B: PR625.2 PU602.36
VIDSCLK: CC321.1 PR601.2 PR618.1 UC1.A63
VIDSCLK_B: PR618.2 PU602.37
VIDSOUT: PR605.2 PR626.1 RC157.1 UC1.D64
VIDSOUT_B: PR626.2 PU602.35
VRALERT#: RC73.1 UC1.AM11
VSA_SEN+: PC640.2 PC650.1 PC652.1 PR649.2 RC168.2 UC1.H20
VSA_SEN-: PC649.1 PC650.2 PU602.26 RC166.1 UC1.H21
VSET_5105: CE38.1 RE77.1 UE1.C9
WIGIG_32KHZ: JNGFF1.50 RZ56.1
WLAN_COEX1: JNGFF1.48 RZ130.2
WLAN_COEX2: JNGFF1.46 RZ129.2
WLAN_COEX3: JNGFF1.44 RZ128.2
WLAN_WIGIG60GHZ_DIS#: DZ1.1 RE8.1 UE1.L13
WLAN_WIGIG60GHZ_DIS#_R: DZ1.2 JNGFF1.56
WRST#: CE500.1 RE6.2 UE2.4
WWAN_COEX1: JNGFF2.56 RZ130.1
WWAN_COEX2: JNGFF2.54 RZ129.1
WWAN_COEX3: JNGFF2.52 RZ128.1
WWAN_PWR_EN: CZ198.1 JNGFF2.6 RZ43.1
WWAN_RADIO_DIS#: DZ5.1 RE10.1 UE1.M2
WWAN_RADIO_DIS#_R: DZ5.2 JNGFF2.8
WWAN_WAKE#: JNGFF2.15 RE38.1 UE1.M13
XCLK_BIASREF: RC52.1 RC324.1 UC1.E42
XDP_DBRESET#: CC32.1 JXDP1.48 RC137.1 RC290.1 UC12.1
XDP_JTAGX: CC305.1 RC87.1 RC328.2 UC1.A59
XDP_OBS0: JXDP1.21 RC239.2
XDP_OBS0_R: RC239.1 UC1.C55
XDP_OBS1: JXDP1.23 RC240.2
XDP_OBS1_R: RC240.1 UC1.D55
XDP_OBS2_R: T10.1(TP-1) UC1.B54
XDP_OBS3_R: T11.1(TP-1) UC1.C56
XDP_PRSNT_PIN1: JXDP1.1 RC121.1 RC122.1
XDP_TMS: JXDP1.58 RC228.1 UC8.9
XTAL24_IN: CC21.1 RC46.2 UC1.E37 YC1.3
XTAL24_OUT: RC46.1 RC295.1 UC1.E35
XTAL24_OUT_R: CC22.1 RC295.2 YC1.1
XTALI: CL14.1 RL11.2 UL1.10 YL1.1
XTALO: RL11.1 RL34.2 UL1.9
XTALO_R: CL13.1 RL34.1 YL1.3
Z2805: RL18.1 TL1.22
Z2806: RL16.1 TL1.16
Z2807: RL17.1 TL1.21
Z2808: RL15.1 TL1.15
N04748: PC939.1 PR929.1 PU901.3
N16399089: PD901.1 PD903.1 PD904.1 PR916.2
N16400770: PR901.3 PR910.1
N16404606: PD905.3 PR939.2 PR950.1
N16404788: PD905.1 PU903.1
N16775301: PC208.2 PR204.2 PR206.1 PU200.16
N16775385: PC218.1 PU200.3
N16775433: PC204.1 PR202.2
N16775513: PC205.1 PR203.2
N16775517: PR203.1 PU200.12
N16776853: PC207.1 PU200.14
N16783014: PC111.1 PR104.1 PR105.1 PU100.16 PU100.17
N16783095: PC113.2 PR108.1
N16783134: PC127.2 PR117.1
N16783223: PC119.1 PU102.16 PU102.17
N16784595: PC102.1 PR100.2
N16784799: PC114.1 PR111.2
N17185092: PQ1204.6 PR1214.2 PR1218.2
N17188126: PR1211.2 PU1200.1
N17188417: PR1215.2 PU1200.2
N17263481: PR612.2 PR614.2 PU602.39
N17264741: PR616.2 PU602.40
N17335638: PC515.2 PR515.2 PR516.1 PU503.3
N17340170: PQ1205.1 PR1215.1 PR1226.2
N17370862: PC4.2 PQ4.4 PQ5.1 PR11.2 PR16.1
N17370885: PQ5.2 PR10.2 PR15.1
N17370921: PQ1.6 PR15.2
N17370927: PQ7.1 PR16.2
N17370961: PL3.1 PQ2.1 PR3.1 PR6.2
N17370983: PQ2.3 PR3.2 PR5.1
N17370995: PQ3.2 PR6.1 PR8.2
N17370999: PQ2.2 PQ3.1 PR7.2
N17371029: PC6.1 PQ9.4 PR12.2 PR18.1
N17371043: PQ6.1 PR18.2
N17371182: PQ6.2 PR23.2
N17371184: PR23.1 PU1.4
N17371196: PR21.2 PU1.1
N17371207: PQ8.1 PR22.1 PR27.1
N17372066: PQ1.3 PR17.2 PR19.2
N17372074: PQ1.5 PR25.1
N17372833: PC1206.1 PR1201.2 PR1203.1 PR1219.1 PU1201.3
N17479322: PQ1215.2 PR1251.2 PR1252.1
N17494434: PC1211.1 PD1205.1 PQ1212.1 PR1238.1 PR1239.2 PR1246.1 PR1255.2 PU1201.5
N17509431: PC947.1 PR935.1 PR947.1 PR949.2
N17509921: PD905.2 PR941.2
N17522701: PR942.2 PU903.2
N17670003: PR936.1 PR948.1 PU901.30
N17739728: PQ1205.3 PR1221.2 PR1224.1
N17747591: PQ8.3 PR26.2 PR28.1
N17747606: PQ8.2 PR29.2
N17765266: PR933.2 PR951.2 PU901.26
N17768164: PQ1210.5 PR1245.2
N17769037: PQ1207.6 PQ1211.4 PR1230.1 PR1258.2
N17769560: PQ1211.5 PR1233.1 PR1242.2
N17769738: PQ1211.2 PR1235.1 PR1257.2
N17770477: PQ1207.2 PQ1207.3 PR1232.1
N17771093: PQ1207.5 PR1241.2
N17771333: PQ1208.6 PQ1211.1 PR1234.1 PR1261.2
N17771663: PQ1208.2 PQ1208.3 PR1259.1
N17772624: PQ1208.5 PR1244.2 PR1260.2 PR1261.1
N17801240: PC1210.1 PQ1206.4 PR1228.2 PR1229.1
N17802718: PC1202.2 PQ1213.4 PQ1215.1 PR1205.2 PR1212.1
N17804163: PC1203.2 PQ1202.4 PQ1203.1 PR1207.2 PR1213.1
N17890941: PR1216.1 PU1200.4
N17892124: PQ1214.6 PR1252.2
N18264144: PQ7.2 PR20.1
N18265642: PQ1201.2 PR1216.2
N18265900: PQ1201.5 PR1220.2
N18266224: PC1213.1 PD1205.2 PR1238.2 PR1240.2 PR1243.1 PU1201.7
N18266545: PC1214.1 PQ1209.5 PR1243.2
N18267253: PQ1212.2 PR1248.1 PR1249.1 PR1250.1
N18268286: PQ1205.2 PR1225.2
N18277029: PR404.2 PR425.2 PU401.14
N18277134: PR410.2 PR426.2 PU402.14
N18278112: PR620.2 PU602.1
N18278782: PC930.1 PR914.2
N18278920: PR920.2 PU901.21
N18278998: PR922.2 PU901.22
N18287403: PQ1.2 PR19.1
N18287500: PR22.2 PU1.2
N18288083: PR946.1 PU903.4
N18288371: PQ1204.5 PR1218.1
N18288510: PQ1204.2 PR1223.1
N18290168: PR949.1 PU901.29
N18290418: PR423.1 PR424.1 PU402.5
N18325201: CL16.1 TL1.3
N18325205: CL17.1 TL1.4
N18325209: CL20.1 TL1.9
N18325213: CL21.1 TL1.10
N18364501: RV97.1 UV7.20
N18366912: CV96.1 UV7.17
N18421193: PL614.3 PR624.1
N18490882: RI14.2 UI3.16
N18762046: CA33.1 RA17.2
N18762152: CZ127.1 UZ5.10
N18762172: CZ126.1 UZ5.12
N18762349: CA51.1 RA44.1 UA1.27
N18762353: CA53.1 UA1.7
N18762355: CA52.1 UA1.39
N18762401: RA53.1 RA54.1 UA1.20
N18762411: CA29.1 UA1.35
N18762416: CA29.2 UA1.37
N18762426: CA35.1 UA1.28
N18762428: CA49.1 UA1.34
N18762438: CA25.1 UA1.19
N20151644: PR901.2 PR909.1
N20880735: PC307.2 PR308.1
N24606174: PC313.1 PU301.5
N27076067: PC944.1 PR934.2
N27077001: PR917.2 PR937.2
N28424999: T113.1(TP-1) UC1.AW71
N28425002: T114.1(TP-1) UC1.AW70
N28489601: RC222.1 SW1.2
N28769860: PR421.2 PR422.1 PU401.5
N28810563: CZ110.1 UZ2.10
N28811129: CZ114.1 UZ3.10
N28856399: T16.1(TP-1) UC1.BA70
N28856402: T17.1(TP-1) UC1.BA68
N28857231: T12.1(TP-1) UC1.BB68
N28857234: T13.1(TP-1) UC1.BB69
N28857237: T14.1(TP-1) UC1.AK13
N28857240: T15.1(TP-1) UC1.AK12
N28861827: RC120.1 UC1.C64
N28938912: CC8.1 RC29.2
N28938914: CC7.1 RC28.2
N29708559: T126.1(TP-1) UC1.AY4
N29708561: T127.1(TP-1) UC1.BB3
N29708639: T130.1(TP-1) UC1.BB5
N30342894: QV4.2 RV18.2
N31877076: JEDP1.21 LV1.1
N32590572: CZ117.1 UZ4.12
N32592963: CZ118.1 UZ4.10
N32594166: CZ109.1 UZ2.12
N32595008: RZ70.2 RZ71.2 UZ2.3
N32817808: CZ113.1 UZ3.12
N32818355: RZ64.2 RZ65.2 UZ3.3
N32819772: CZ121.1 UZ8.6
N33612393: CD31.2 RD18.1
N35551576: PQ1209.2 PQ1209.3 PR1236.1
N35551581: PQ1209.6 PR1229.2
N35551592: PC1212.1 PR1237.2 PR1247.1 PU1201.6
N35551655: PC1205.1 PR1208.2 PR1217.1 PU1201.2
N35551713: PQ1201.6 PR1212.2
N35551785: PQ1203.2 PR1202.2 PR1209.1
N35551806: PQ1204.3 PR1209.2
N35551822: PQ1201.3 PR1213.2
N36626863: CT90.1 RT111.2 UT7.3
N36827741: RZ120.2 UZ26.4 UZ34.4
N38749366: QV2.1 RV5.2
N38749387: QV7.1 QV8.2 RV6.1
N38798736: RT97.2 RT98.1 RT99.1 UT5.F10
N38798744: RT85.1 UT5.G4
N38798745: RT84.1 UT5.F4
N38798858: RT63.1 UT5.F1
N38798904: RT105.1 UT5.K10
N38798905: RT104.1 UT5.K9
N38798908: RT103.1 UT5.L11
N38798948: RT85.2 T220.1(TP-1)
N38798949: RT84.2 T219.1(TP-1)
N38799002: CT87.1 UT5.H7
N38799008: RT101.1 UT5.D6
N39468508: PC647.2 PR650.2
N39468570: PC629.2 PR639.1
N39469485: PH601.2 PR610.1 PR631.2
N39469718: PC627.1 PR632.2
N39469776: PH603.2 PR635.1 PR647.2
N39469798: PR679.1 PU614.7
N39469812: PH602.1 PR628.2
N39469818: PC631.1 PR630.2
N39469863: PC632.1 PR636.1 PU602.28
N39469888: PC627.2 PR638.2 PU602.8
N39469908: PC617.2 PR621.1
N39469972: PR678.2 PU602.38
N39469996: PC611.2 PU614.2
N39469998: PC611.1 PR619.1
N39470055: PC630.1 PR640.1 PU602.20
N39470129: PC640.1 PR646.2
N39470145: PC601.1 PR652.2
N39470169: PC630.2 PR644.1
N39470173: PC632.2 PR641.1
N39470189: PH604.1 PR642.2
N39470248: PC621.2 PR623.1
N39470250: PR621.2 PR622.2 PR623.2 PU602.5
N39470270: PH605.1 PR657.2
N39470326: PC616.2 PR617.2 PU602.4
N39470328: PC614.2 PR617.1
N39470344: PR610.2 PU602.3
N39470375: PC613.2 PR613.2 PU602.2
N39470446: PC603.1 PR602.1 PU602.34
N39470448: PC604.1 PR603.1 PU602.33
N39470528: PR608.1 PU602.32
N39470532: PR611.1 PU602.31
N39470546: PC639.2 PR645.1
N39473183: PL610.3 PR661.1
N39473185: PC671.2 PU612.7
N39473187: PR672.2 PU612.6
N39473189: PC671.1 PR672.1
N39473240: PR671.1 PU612.1
N39473270: PC655.2 PU610.7
N39473272: PR660.2 PU610.6
N39473274: PC655.1 PR660.1
N39473308: PR659.1 PU610.1
N41288260: JNGFF2.17 RZ326.1
N41303246: CZ38.2 RZ334.1
N44311288: QE11.3 RE70.1 RE90.2
N44311298: QE4.2 RE70.2
N44321668: RE57.1 RE58.1 UE1.B1
N44321726: RE318.1 UE1.G2
N44321827: RE349.2 UE1.N4
N44321953: CE57.1 RE350.2
N44725169: CZ197.1 RZ345.2 UZ8.3
N44851953: JNGFF2.59 T225.1(TP-1)
N44905504: JDIMM1.162 T50.1(TP-1)
N44907662: JDIMM1.165 T51.1(TP-1)
N45160305: JESPI.8 RE375.1
N45499007: QZ3.1 RZ25.1
N45523002: RE13.2 RE14.1 UE2.1
N45523004: RE15.2 RE16.1 UE2.2
N45523094: RE17.2 RE18.1 UE2.3
N45601552: RT378.1 UT5.D1
N45601554: RT379.1 UT5.D2
N46166384: RT380.2 UT9.32
N46226517: CZ56.1 RZ63.1
N46226641: RZ112.2 RZ362.2 UZ12.29
N46226670: RZ62.1 UZ12.27
N46226856: QZ9.2 RZ113.2
N46293588: JNGFF2.48 RZ131.2
N46293598: JNGFF2.50 RZ132.2
N46460386: QE12.1 RE94.1
N47527449: QE13.1 RE34.2 RE348.1 RE536.1 RE537.2 UE7.3
N47527453: QE13.3 QE13.6
N47527563: CE5.1 UE7.4
N119328643: PC938.1 PR930.1 PR931.2 PU901.25
N132000604: PC934.1 PR921.2
N132005053: PR917.3 PR938.2
N4758359918: PR932.1 PU901.27

Pads without a net: FD1 1; FD2 1; FD3 1; FD4 1; JAPS1 16 17 18; JDIMM1 87 88 91 92 95 97 100 101 104 105; JEDP1 16 20; JHDMI1 14; JIR1 3; JKBTP1 10 17; JNGFF1 6 16 17; JNGFF2 12 14 16 20 36 38 40 44 45 47 51 53 55 57 60; JNGFF3 5 6 7 8 11 13 17 19 20 22 23 24 25 26 28 30 32 34 36 40 42 44 46 48 56 58 67; JSD1 16; JSIM1 1 C4 C6 C8; JSPI1 4 21; JUSH1 2 17; PBATT1 11 12; PD2 2; PRP1 4 5; PU100 10 15; PU102 10; PU200 18 19; PU301 2; PU401 4; PU402 4; PU503 2 6 7; PU602 13; PU901 13; QL2 3 4 5; QZ7 1 2 6; RC22 2; RC405 2; RPE12 1 2 7 8; RT75 2; RT87 1; RT88 1; RT110 1; RT339 2; RZ326 2; UA1 4 11 12 15 23 24 48; UC1 A3 A4 A11 A21 A26 A27 A29 A31 A33 A36 A38 A45 A47 A52 A65 A69 AB3 AB4 AB12 AB13 AB62 AC63 AD3 AD4 AE62 AE63 AF6 AF7 AF11 AF12 AF13 AF64 AF65 AF66 AF67 AF68 AF69 AF70 AF71 AG62 AG69 AG70 AH3 AH9 AH10 AH11 AH12 AH65 AH66 AH68 AH69 AH70 AH71 AJ3 AJ62 AK6 AK7 AK9 AK10 AK62 AK64 AK65 AK66 AK67 AK70 AL25 AL27 AL61 AL63 AM1 AM2 AM3 AM4 AM5 AN1 AN2 AN3 AN21 AN22 AN25 AN27 AN43 AN45 AN46 AN48 AN50 AN52 AN53 AN55 AN56 AN60 AN61 AN65 AN66 AP1 AP2 AP3 AP4 AP13 AP21 AP22 AP25 AP27 AP30 AP33 AP37 AP40 AP43 AP45 AP46 AP48 AP50 AP52 AP53 AP55 AP56 AP60 AP61 AP65 AP66 AR21 AR22 AR25 AR27 AR30 AR32 AR33 AR37 AR38 AR40 AR56 AR60 AR61 AR65 AR66 AT5 AT21 AT22 AT25 AT27 AT30 AT32 AT33 AT37 AT38 AT40 AT60 AT61 AT65 AT66 AU5 AU21 AU22 AU25 AU27 AU30 AU33 AU37 AU40 AU56 AU58 AU60 AU61 AU63 AU65 AU66 AW1 AW20 AW42 AW44 AW46 AW48 AW68 AW69 AY1 AY2 AY20 AY21 AY42 AY43 AY44 AY46 AY47 AY48 B2 B3 B11 B21 B26 B27 B29 B31 B33 B36 B38 B45 B47 B52 B69 B70 BA3 BA4 BA7 BA8 BA9 BA42 BA43 BA44 BA46 BA47 BA48 BB2 BB4 BB7 BB9 BB11 BB42 BB44 BB46 BB48 BB57 BB66 C2 C4 C7 C8 C11 C12 C15 C19 C20 C23 C27 C28 C29 C31 C32 C33 C36 C37 C38 C54 C70 C71 D1 D3 D4 D5 D7 D12 D15 D19 D20 D23 D27 D28 D29 D31 D32 D33 D36 D37 D38 D54 D71 E1 E2 E3 E10 E16 E20 E25 E38 E40 E61 F6 F10 F16 F18 F20 F25 F52 F60 F61 F65 G18 G61 G65 H11 H63 J1 J4 J5 J68 J71 K45 K46 L6 M1 M2 M3 M4 N1 N2 N3 N9 N11 P1 P3 P62 U6 U7 V1 V2 V62 W4 W7 W12; UD1 1; UE1 B8 B9 F7 J6; UE2 5 6 8 10 11; UE4 1; UE6 1; UI3 9 15; UR1 31; UT5 C1; UT7 4; UV7 2 4 14 58; UV24 3; UZ12 2 4 5 6 7 10 11 12 15 25 26 28 30 31; YC1 2 4

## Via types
v1: diameter 0.305, hole 0.152, TOP to BOTTOM, 664 vias
v2: diameter 0.457, hole 0.203, TOP to BOTTOM, 5412 vias
v3: diameter 0.508, hole 0.254, TOP to BOTTOM, 81 vias
v4: diameter 0.406, hole 0.203, TOP to BOTTOM, 250 vias

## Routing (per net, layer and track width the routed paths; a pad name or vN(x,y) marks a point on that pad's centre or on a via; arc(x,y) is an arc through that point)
0.6V_DDR_VTT_ON: length 18.3
  TOP w0.112: v2(71.14,82.24) 71.78,81.61 75.21,81.61 76.54,80.27 v4(76.54,78.6) 76.54,74.83 75.84,74.13 PR210.1
  BOTTOM w0.112: RD19.1 69.2,82.86 UD1.4 70.97,82.86 71.14,82.69 v2(71.14,82.24)
1.8V_PRIM_PWRGD: length 124
  TOP w0.112: v2(263.68,81.42) RE360.2 ; RE361.2 247.13,77.72 248.18,76.67 248.91,76.67 v2(249.35,77.11)
  IN2 w0.124: v2(249.35,77.11) 248.96,77.51 247.97,77.51 246.62,78.85 245.73,78.85 245.31,79.28 244.42,79.28 244.22,79.08 242.08,79.08 240.86,80.3 237.39,80.3 234.62,77.53 234.62,76.85 234.21,76.44 231.29,76.44 230.73,75.89 230.73,75.19 226.8,71.25 226.25,71.25 225.25,70.25 220.8,70.25 220.56,70.01 216.64,70.01 216.23,70.42 v2(216.23,70.97)
  IN3 w0.135: v2(249.35,77.11) 251.31,77.11 252.75,78.56 253,78.56 255.24,80.81 260.7,80.81 260.91,80.61 262.86,80.61 v2(263.68,81.42)
  BOTTOM w0.112: PU501.5 171.06,67.08 PR517.1 171.07,67.92 171.07,71.28 169.8,72.55 169.8,73.26 170.1,73.57 v1(174.22,73.57) 175.21,73.57 181.96,66.81 181.96,63.36 182.35,62.98 183.42,62.98 184.92,64.48 210.08,64.48 216.23,70.62 v2(216.23,70.97)
2.5VSP: length 1.8
  TOP w0.112: PJP506.1 v1(146.66,64.2)
3.3V_CAM_EN#: length 155.7
  TOP w0.112: RC311.1 v1(128.93,87.4) 128.93,89.55 126.16,92.32 125.5,92.32 123.88,93.93 v2(123.88,94.16) ; QZ1.2 56.2,122.6 56.73,122.07 57.31,122.07 v2(57.76,122.52)
  IN2 w0.076: 127.78,95.66 126.22,95.66 126.07,95.5 124.8,95.5 124.33,95.03 124.33,94.61 v2(123.88,94.16)
  IN2 w0.124: v2(57.76,122.52) 58.66,123.42 60.35,123.42 63.88,126.95 72.01,126.95 73.69,125.27 74,125.27 74.17,125.44 75.37,125.44 75.99,124.82 79.48,124.82 81.75,127.09 89.18,127.09 90.24,128.15 104.01,128.15 104.28,128.43 108.51,128.43 109.01,128.93 117.3,128.93 117.81,128.42 118.92,128.42 119.62,129.12 122.88,129.12 124.02,127.98 125.31,127.98 125.69,128.37 130.98,128.37 131.54,127.81 138.83,127.81 139.53,127.1 139.53,125.3 138.61,124.38 138.61,122.59 139.63,121.57 139.63,119.18 137.41,116.95 137.41,112.77 138.39,111.8 138.39,110.96 141.84,107.5 141.84,105.35 140.26,103.76 140.26,101.23 138.71,99.68 138.71,98.37 137.56,97.23 137.56,95.9 136.34,94.67 133.73,94.67 133.31,95.08 130.15,95.08 129.77,95.46 129.16,95.46 128.97,95.66 127.78,95.66
  BOTTOM w0.102: UC1.AT15 124.14,94.45 123.88,94.2 v2(123.88,94.16)
3.3V_TS_EN: length 171.5
  TOP w0.112: v2(47.73,125.6) 47.28,125.16 47.28,121.61 47.95,120.94 QV7.2 ; RC282.1 144.85,85.8 144.49,85.8 144.28,86 141.87,86 141.41,86.47 139.72,86.47 138.77,87.41 137.29,87.41 132.66,92.04 132.66,93.37 130.88,95.15 v1(130.68,95.15) 130.44,95.15 129.66,95.93 v2(129.3,95.93)
  IN2 w0.124: v2(129.3,95.93) 129.62,95.93 130.23,95.32 133.4,95.32 133.82,94.89 136.18,94.89 137.31,96.02 137.31,97.36 138.46,98.51 138.46,101.05 139.77,102.36 139.77,103.59 141.62,105.44 141.62,107.41 138.16,110.87 138.16,111.7 137.18,112.68 137.18,117.04 139.41,119.27 139.41,121.48 138.36,122.53 138.36,124.51 139.28,125.42 139.28,127.02 138.72,127.58 131.39,127.58 130.83,128.14 125.79,128.14 125.4,127.75 123.93,127.75 122.79,128.9 119.71,128.9 118.89,128.08 109.78,128.08 109.66,128.2 104.37,128.2 104.1,127.93 90.41,127.93 89.29,126.81 81.79,126.81 79.58,124.6 75.89,124.6 75.27,125.22 74.26,125.22 74.09,125.05 73.59,125.05 71.92,126.72 63.97,126.72 59.1,121.85 56.08,121.85 53.1,124.84 48.49,124.84 v2(47.73,125.6)
  BOTTOM w0.076: UC1.AP5 129.48,95.75 v2(129.3,95.93)
3.3V_WWAN_EN: length 47.9
  TOP w0.107: UE1.C6 v2(247.88,87.46)
  TOP w0.112: v2(280,87.84) RZ40.2 281.32,88.47 v1(281.32,89.41) 281.32,90.23 280.2,91.34 UZ4.5
  IN1 w0.119: v2(280,87.84) 279.37,87.84 274.29,82.76 268.36,82.76 267.28,83.85 267.28,85.76 265.59,87.45 v2(265.59,87.48)
  IN3 w0.135: v2(265.59,87.48) 262.31,87.48 260.81,85.98 260.81,85.41 260.07,84.67 257.34,84.67 256.42,85.58 256.42,87.48 256.06,87.85 255.71,87.85 255.71,87.85 248.22,87.85 247.88,87.52 v2(247.88,87.46)
3V5V_EN: length 70.7
  TOP w0.254: v2(151.88,78.8) 147.06,78.8 v2(146.84,78.57)
  IN3 w0.203: v2(184.39,58.19) 183.46,57.26 180.13,57.26 179.85,57.54 174.5,57.54 173.12,58.91 168.5,58.91 167.66,58.08 166.61,58.08 166.28,57.75 161.1,57.75 160.4,58.44 160.4,64.04 157.38,67.07 150.62,67.07 146.01,71.68 146.01,77.9 146.68,78.57 v2(146.84,78.57)
  BOTTOM w0.112: v2(151.88,78.8) v1(151.37,78.8)
  BOTTOM w0.254: PU102.12 184.51,57.21 184.51,58.07 v2(184.39,58.19) 183.79,58.79 PR114.2 183.97,58.93 184.33,59.28 184.33,60.34 184.87,60.88 PD100.1 ; PU100.12 154.01,77.78 153.44,78.34 PC128.1 152.56,78.8 PR116.1 v2(151.88,78.8)
3V_FB: length 1.9
  BOTTOM w0.254: PU100.13 154.46,78.24 154.33,78.37 PC113.1
3V_SN: length 1.2
  BOTTOM w0.102: PC112.1 v1(163.99,71.26)
3V_VIN: length 0.7
  TOP w0.112: v2(154.54,72.95) v1(154.54,72.27)
  vias: v2(153.9,72.95)
5V_FB: length 3
  BOTTOM w0.112: v1(186.09,58.93) PC127.1
  BOTTOM w0.254: PC127.1 184.86,58.57 184.94,58.49 PU102.13
5V_SN: length 1.3
  TOP w0.112: PC125.1 v4(190.14,57.34)
5V_VIN: length 1
  BOTTOM w0.112: v1(179.67,50.62) 180.3,51.26 180.43,51.26
+0.6V_DDR_VTT: length 84.5
  TOP w1.016: 71.4,55.19 71.4,54.37 75.4,50.37 139.25,50.37 140.54,51.65
  IN3 w1.016: 72.27,57.14 72.27,59.1 72.67,59.5 72.67,69.28
  vias: v2(70.78,56.27) v2(71.41,56.27) v2(72.16,71) v2(72.73,71) v2(142.64,52.12) v2(143.25,52.12) v4(141.76,52.59)
+0.6VSP: length 0.9
  TOP w0.127: 69.96,70.17 69.43,70.17 v4(69.19,70.41)
  vias: v2(70.34,70.03) v2(70.92,70.04)
+0.9V_LAN: length 6
  TOP w0.203: UL1.40 244.04,126.93 v2(244.14,127.03) ; UL1.37 242.87,128.13 242,129 CL10.1 ; UL1.16 248.42,124.93 v2(248.37,124.98) ; UL1.22 v2(248.37,127.33) ; UL1.43 v2(244.19,125.73)
  TOP w0.381: v2(242.53,129.36) 242.19,129.36 CL10.1
  vias: v1(249.41,121.74) v2(244.14,124.34) v2(247.64,121.25) v2(248.58,121.97)
+1.0V_AMPHYPLL: length 23.9
  TOP w0.457: CC264.1 124.1,108.1 124.1,107.6 v2(123.97,107.47)
  IN2 w0.254: v2(130.06,122.54) 130.06,122.38 129.59,121.91 129.59,116.29 127.91,114.62 127.91,112.23 126.1,110.41 126.1,109.07 126.1,109.07 126.1,108.13 126.07,108.1 126.07,108.09 125.8,107.82 125.79,107.82 125.78,107.81 124.31,107.81 v2(123.97,107.47)
  BOTTOM w0.102: v2(130.06,122.54) v1(130.06,121.93)
  BOTTOM w0.254: RC169.2 130.58,123.58 129.65,123.58 CC219.1 130.06,122.62 v2(130.06,122.54) ; UC1.K15 v2(123.97,107.47) UC1.L15
+1.0V_APLL: length 9.7
  TOP w0.127: CC314.1 124.52,104.94 125.02,105.43 v4(125.02,106.27)
  IN2 w0.508: v2(130.1,118.12) 130.1,115.73 129.01,114.64 129.01,112.48
  BOTTOM w0.254: v2(124.59,104.15) 124.59,103.99 UC1.V15
  BOTTOM w0.508: LC2.2 129.94,118.27 v2(130.1,118.12)
+1.0V_APLLEBB: length 21.6
  TOP w0.254: v2(129.06,118.12) 129.06,118.82 v4(129.48,119.24) 129.89,119.66 CC325.1 130.9,120.6 RC310.2
  TOP w0.381: CC218.1 121.43,104.96 122.01,105.54 v2(122.01,105.76)
  IN2 w0.254: v2(122.01,105.76) 122.01,105.87 122.6,106.46 122.6,106.63 123.37,107.4 123.37,107.68 123.95,108.27 124.86,108.27 125.18,108.58 125.18,111.02 127.38,113.22 127.38,114.77 129.06,116.44 v2(129.06,118.12)
  BOTTOM w0.254: UC1.N18 122.31,106.2 122.01,105.83 v2(122.01,105.76)
+1.0V_CLK1: length 8.8
  TOP w0.508: v2(126.44,117.21) 126.47,117.21 127.34,118.08 127.34,119.33 127.66,119.64 RC302.2
  BOTTOM w0.203: 124.9,114.13 124.61,113.84 124.61,113.1 124.61,113.1 UC1.A14
  BOTTOM w0.508: v2(126.44,117.21) 126.44,116.72 v1(126.31,116.6) 125.25,115.53 125.25,114.48 124.9,114.13
+1.0V_CLK2: length 14
  TOP w0.508: v2(125.56,122.95) 125.56,122.32 v1(124.41,121.18) 123.62,120.38 123.62,117.33 122.27,115.99 122.27,113.9 122.07,113.7 122.07,113.37
  BOTTOM w0.254: UC1.K19 121.69,107.78 v2(122.01,107.46)
  BOTTOM w0.508: RC170.2 126.76,124.61 CC220.1 125.56,123.42 v2(125.56,122.95)
+1.0V_CLK3: length 11.4
  TOP w0.508: RC303.2 126.77,119.92 v2(126.13,119.29)
  IN2 w0.381: v2(126.13,119.29) 124,117.16 123.8,117.16 122.22,115.58 122.22,113.22 121.28,112.28 121.28,112.15
  BOTTOM w0.254: v2(120.79,107.46) 120.7,107.46 120.39,107.06 UC1.L21
+1.0V_CLK4: length 24.4
  IN2 w0.508: v2(124.17,122.95) 124.17,118.49 120.98,115.3 120.98,113.73 120.22,112.96 119.58,112.96 117.68,111.06 117.68,109.18 118.59,108.27 118.59,107.22 120.06,105.76 120.69,105.76 v2(120.71,105.74)
  BOTTOM w0.229: v2(120.71,105.74) 120.71,105.95 120.96,106.2 UC1.N20
  BOTTOM w0.508: RC173.2 CC226.1 v2(124.17,122.95)
+1.0V_CLK5: length 20.4
  TOP w0.127: v1(122.53,106.25) 121.8,106.25 121.39,106.66 v2(121.38,106.66)
  TOP w0.356: RC52.2 120.8,106.66 v2(121.38,106.66)
  IN2 w0.381: v2(121.38,106.66) 121.39,106.66 121.39,107.66 ; 122.91,111.59 122.91,112.41 124.51,114.01 124.51,116.88 125.86,118.22 126.19,118.22 127.34,119.38 v2(127.34,122.95)
  BOTTOM w0.254: v2(121.38,106.66) 121.39,106.66 121.39,106.67 121.67,107.04 UC1.L19
  BOTTOM w0.508: v2(127.34,122.95) 127.34,123.48 CC221.1 127.66,124.83 RC171.2
+1.0V_CLK6: length 8.7
  BOTTOM w0.203: 127.42,113.97 127.09,113.64 UC1.A10
  BOTTOM w0.381: 127.42,113.97 129.01,115.56 129.01,116.9 127.86,118.04 v1(127.86,118.37) CC216.1 127.87,119.31 RC300.2
+1.0V_DTS: length 18.4
  IN3 w0.381: v2(148.14,106.65) 145.48,106.65 144.87,107.26 142.86,107.26 142.27,107.85 140.46,107.85 139.25,106.64 134.64,106.64 v2(133.91,105.9)
  BOTTOM w0.203: UC1.T1 132.64,105.16 133.01,105.53 133.53,105.53
  BOTTOM w0.381: 133.53,105.53 v2(133.91,105.9)
  BOTTOM w0.508: RC301.2 148.17,106.63 v2(148.14,106.65)
+1.0V_MPHYAON: length 2.6
  TOP w0.508: CC203.1 123.2,108.1 122.66,107.56 v2(122.66,107.46)
  BOTTOM w0.254: v2(133.03,107.58) 132.32,107.58 UC1.L1 ; v2(122.66,107.46) UC1.K17
  vias: v2(133.63,107.58) v4(135.61,108.75)
+1.0V_MPHYGT: length 11.3
  BOTTOM w0.254: UC1.N17 122.99,106.12 v2(123.33,105.78) 123.64,105.47 UC1.P16 ; UC1.P15 124.6,105.67 v2(124.6,105.78) 124.6,105.89 UC1.N15 ; UC1.N16 v2(123.95,106.59)
  BOTTOM w0.356: CC281.1 131.13,125.27 130.83,124.98 RC169.1
  BOTTOM w0.457: RC169.1 131.3,124.72 131.66,124.37 v2(131.66,123.39)
  BOTTOM w2.032: 137.33,118.71 134.14,115.52 134.14,114.25
  vias: v2(133.75,112.75) v2(133.75,112.14) v2(134.39,112.75) v2(134.39,112.14) v2(137.07,120.07) v2(137.39,120.58) v2(137.71,120.07) v2(138.02,120.58) v4(134.99,122.05)
+1.0V_PRIM: length 41.3
  TOP w0.254: CZ105.1 118.46,126.77 117.18,125.49 114.26,125.49 113.8,125.94 v4(105.41,125.94) 104.57,126.78 104.57,132.83 103.85,133.55 RC216.1
  TOP w0.508: v2(121.36,101.54) 120.74,102.16 CC206.1
  BOTTOM w0.254: UC1.AK20 v2(121.36,98.24) ; UC1.P18 122.34,105.42 v2(122.67,105.76) ; v2(122.01,103.27) 122.34,102.94 UC1.Y18 122.34,102.66 UC1.AB17 ; UC1.AB19 v2(121.36,101.54) UC1.AB20
  BOTTOM w0.508: v2(150.92,107.57) 150.71,107.57 RC301.1
  vias: v2(126.45,126.8) v2(127.21,126.8) v2(127.97,126.8) v2(128.83,122.49) v2(129.42,122.5) v2(140.01,123.65) v2(140.6,123.65) v2(141.18,123.65) v2(141.77,123.65) v2(142.35,123.65) v2(142.93,123.65) v2(143.52,123.65) v2(157.73,87.72) v2(157.73,87.08) v2(158.29,88) v2(158.29,87.39) v2(158.29,86.78) v2(158.93,88) v2(158.93,87.39) v2(158.93,86.78)
+1.0V_PRIM_CORE: length 3.7
  TOP w0.127: v2(147.31,117.17) v4(147.31,118.02)
  TOP w0.457: v2(122.01,100.75) 121.88,100.62 CC205.1
  BOTTOM w0.254: 120.69,104.01 120.69,103.98 120.4,103.69 UC1.V21 ; 120.69,104.01 121.01,103.69 UC1.V20 ; 120.69,104.01 v2(120.69,104.11) ; UC1.AF19 121.69,100.43 v2(122.01,100.75) 122.01,100.66 UC1.AF18
  vias: v2(145.2,102.98) v2(145.5,117.17) v2(146.1,117.17) v2(146.27,102.97) v2(146.71,117.17) v2(147.07,101.71) v2(147.07,101.15)
+1.0V_PRIM_COREP: length 8.7
  TOP w0.254: v2(149.97,128.66) 149.97,128.98 150.14,129.14 151.33,129.14 154.32,130.67 v1(154.62,130.67) 154.86,130.67 155.46,131.27 v2(155.46,132.79)
  BOTTOM w0.254: PR423.2 v2(155.46,132.79)
  vias: v2(149.97,127.96) v2(149.97,127.38)
+1.0V_PRIM_XDP: length 29.1
  TOP w0.127: v4(90.51,131.44) 90.61,131.54 v2(90.61,132.22)
  TOP w0.254: RC216.2 91.65,133.55 91.36,133.26 CC29.1 CC28.1 90.55,133.17 RC115.2 90.61,132.51 v2(90.61,132.22)
  BOTTOM w0.254: JXDP1.43 90.91,130.86 90.61,131.16 v2(90.61,132.22) JXDP1.44 90.61,133.7 90.88,133.97 103.22,133.97 104.62,132.57 104.62,128.79 RC138.2
+1.0V_SRAM: length 17.3
  TOP w0.381: v2(120.72,100.7) 120.59,100.83 CC217.1
  TOP w0.762: RC309.2 132.29,116.41 129.34,113.45 124.74,113.45 123.65,112.36
  BOTTOM w0.254: UC1.T19 v2(121.33,104.08) UC1.T20 ; UC1.AF21 v2(120.72,100.7) UC1.AF20
  vias: v2(122.9,110.88) v2(122.9,110.23) v4(123.58,111.44)
+1.0V_VCCST: length 543.6
  TOP w0.254: RE59.2 255.04,98.61 254.81,98.84 253.8,98.84 v2(253.41,99.22) ; 265.02,103.45 v2(265.02,102.5) ; 265.02,103.45 265.86,104.29 v4(265.86,105.29) v2(265.86,108.49) ; 265.02,103.45 RE90.1
  TOP w0.381: v2(120.11,107.46) 119.9,107.46 CC202.1 ; v2(92.84,124.46) 90.89,122.52 v2(90.89,122.24)
  TOP w0.508: 125.27,123.91 124.86,123.51 124.86,122.69 123.79,121.61 RZ151.2 122.59,121.37 CC195.1 122.59,120.12 122.24,119.77 120.83,119.77 120.44,119.38 v2(120.44,117.97) 120.44,116.18 121.61,115.01 v2(121.61,114.48)
  IN1 w0.254: v2(161.11,56.22) 160.91,56.02 147.72,56.02 145.59,53.88 142.16,53.88 141.27,53 130.2,53 127.15,49.95 73.56,49.95 v2(72.44,51.06)
  IN1 w0.508: v2(53.59,117.23) 49.58,117.23 45.35,113.01 v2(45.35,112.7)
  IN2 w0.254: v2(121.61,114.48) 121.61,113.5 120.29,112.18 120.29,111.75 119.71,111.16 119.71,109.81 119.73,109.79 119.73,109.2 119.64,109.11 119.64,107.93 v2(120.11,107.46)
  IN2 w0.508: v2(63.21,116.79) 62.95,117.04 62.95,118.25 63.99,119.29 68.68,119.29 69.84,120.45 79.3,120.45 80.04,119.71 88.43,119.71 90.89,122.17 v2(90.89,122.24) 91.82,122.24 92.69,121.36 v2(94.5,121.36) 94.55,121.36 95.35,122.15 96.07,122.15 96.75,121.47 97.79,121.47 98.26,121.95 98.26,122.5 99.02,123.27 101.44,123.27 101.79,122.91 101.79,122.31 102.81,121.29 109.21,121.29 111.64,118.86 119.55,118.86 v2(120.44,117.97) ; v2(45.35,112.7) 45.35,108.94 44.22,107.81 44.22,96.15 44.34,96.03 44.34,94.21 44.99,93.56 v2(44.99,91.83)
  IN3 w0.254: v2(44.99,91.83) 44.99,89.65 42.51,87.16 42.51,83.01 40.47,80.97 39.39,80.97 38.31,79.89 38.31,77.15 37.78,76.62 37.78,71.87 34,68.08 34,60.45 37.03,57.41 37.03,55.61 38.68,53.96 40.66,53.96 43.46,51.17 50.95,51.17 51.03,51.08 54.5,51.08 54.84,50.74 59.29,50.74 59.76,51.22 62.71,51.22 66.07,54.57 68.78,54.57 70.99,52.36 71.91,52.36 72.44,51.83 v2(72.44,51.06) ; v2(265.02,102.5) 263.9,103.62 254.1,103.62 252.75,102.27 252.75,99.88 v2(253.41,99.22) ; v2(161.11,56.22) 161.11,56.02 161.51,55.62 178.69,55.62 179.63,56.55 183.95,56.55 185.24,57.84 185.24,58.31 185.42,58.5 195.5,58.5 196.25,57.75 198.65,57.75 199.11,57.29 199.11,54.32 200.1,53.33 203.86,53.33 204.68,54.14 209.36,54.14 210.56,52.94 213.23,52.94 213.94,52.23 218.62,52.23 219.48,53.1 225.61,53.1 225.81,52.9 227.56,52.9 230.49,49.97 247.72,49.97 250.16,52.41 250.16,56.2 249.2,57.16 249.2,62.44 250.75,63.99 256.84,63.99 257.54,63.3 262.58,63.3 263.42,64.15 263.42,67.5 264.06,68.13 264.06,69.43 263.79,69.7 263.79,72.72 265.91,74.84 269.82,74.84 270.74,73.92 278.15,73.92 280.63,76.4 280.63,80.34 275.59,85.38 275.59,93.36 274.47,94.47 274.47,96.11 270.98,99.6 270.98,103.38 v2(265.86,108.49)
  BOTTOM w0.152: v2(121.61,114.48) 121.97,114.12 121.97,113.15 UC1.A18
  BOTTOM w0.254: v2(120.11,107.46) 120.08,107.49 120.08,107.57 UC1.K21 120.39,107.94 120.54,108.09 120.82,108.09 UC1.K20
  BOTTOM w0.381: RC79.2 96.29,121.83 96.01,122.11 94.87,122.11 94.5,121.74 v2(94.5,121.36) ; RC218.2 v2(92.84,124.46) ; v2(94.5,121.36) 92.95,121.36 92.66,121.07 RC152.2 92.67,120.65 RC157.2 RC120.2 ; v2(94.5,121.36) RC80.2 ; RC71.2 v2(90.89,122.24)
  BOTTOM w0.508: v2(53.59,117.23) 53.95,117.23 54.68,116.5 58.65,116.5 58.94,116.79 v2(63.21,116.79) ; PR605.1 PR604.1 PR601.1 PC602.1 v2(44.99,91.83)
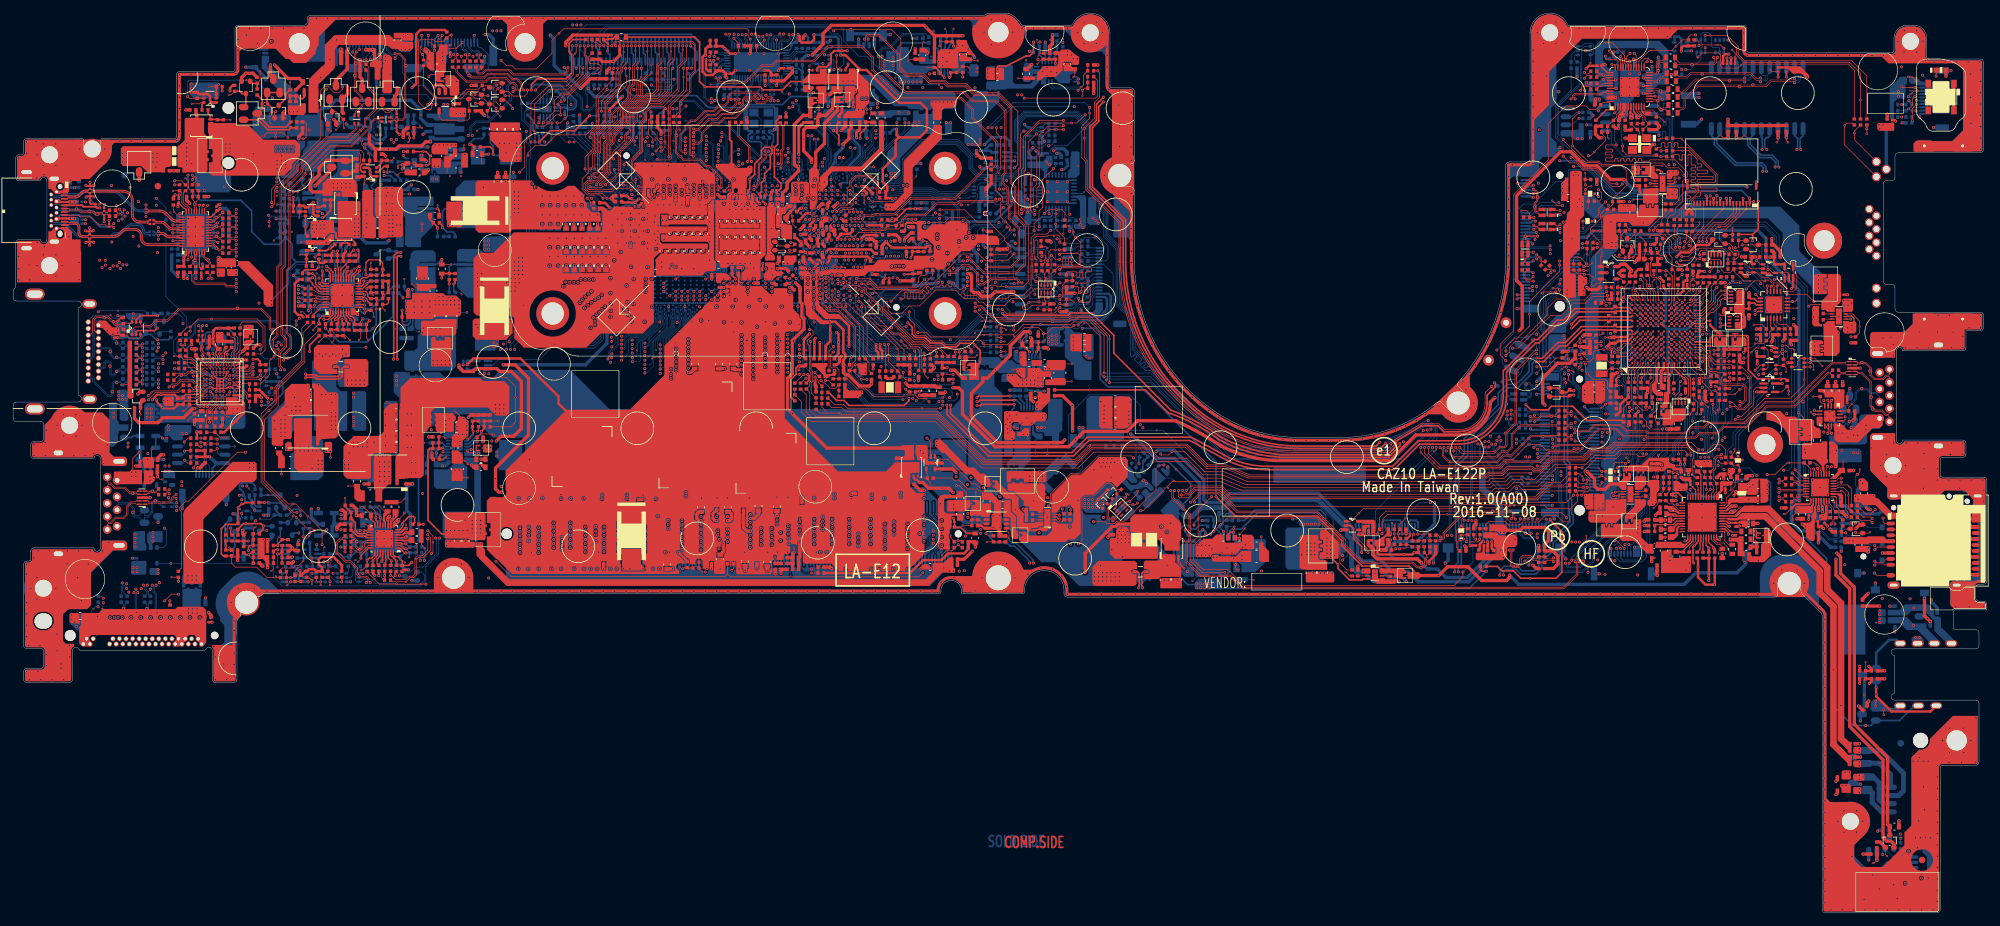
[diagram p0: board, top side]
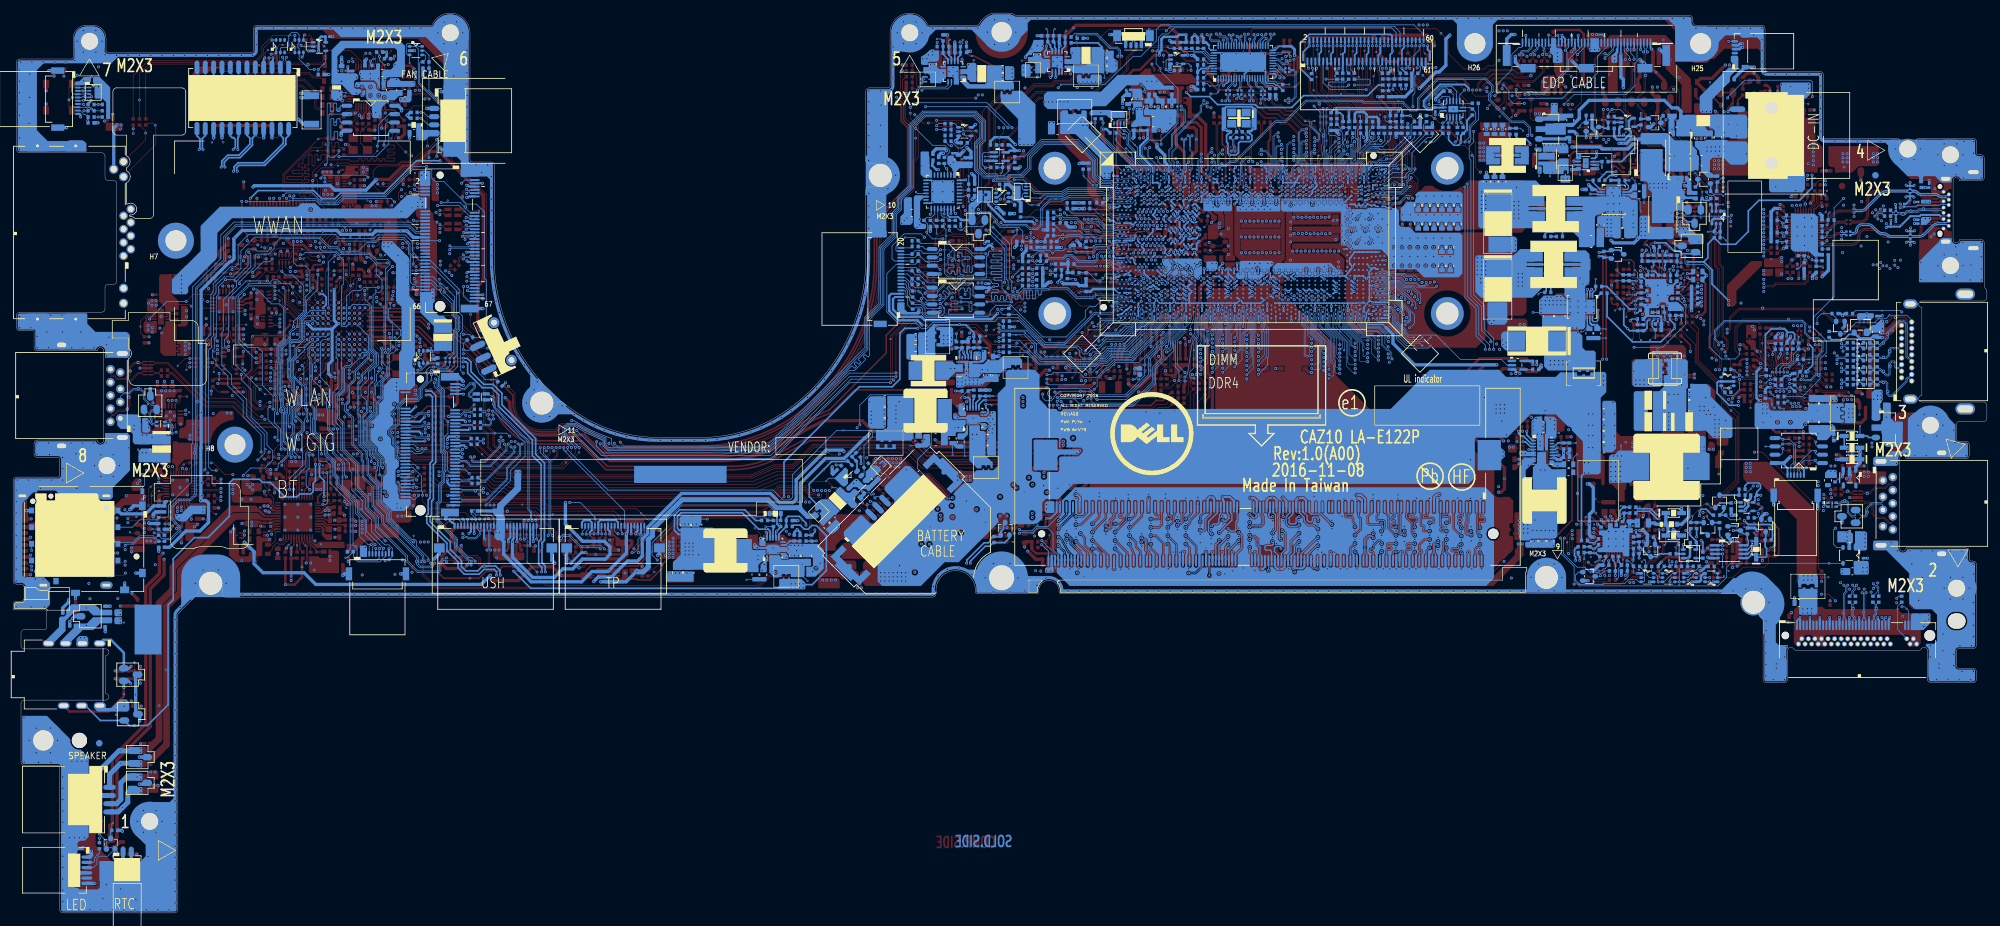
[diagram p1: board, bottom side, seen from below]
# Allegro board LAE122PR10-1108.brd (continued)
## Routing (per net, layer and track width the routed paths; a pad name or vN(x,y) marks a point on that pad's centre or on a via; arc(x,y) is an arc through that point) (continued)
+1.0V_VCCST_C: length 1.3
  BOTTOM w0.127: v2(128.31,125.23) 128.31,125.7 v1(128.92,126.31)
+1.0V_VCCSTG: length 79.7
  TOP w0.254: RC130.2 99.08,122.34 v2(99.39,122.64) ; v2(80.13,117.55) 81.84,119.27 v4(83.22,119.27) 85.54,119.27 v2(87.83,121.56)
  TOP w0.508: CC199.1 117.14,108.86 RC143.2 117.24,109.78 117.91,110.45 117.91,111.36 119.64,113.1 v2(119.64,113.86) 119.29,113.86 119.02,114.12 119.02,120.23 120.41,121.61 RZ151.1
  IN2 w0.254: v2(119.64,113.86) 119.86,113.86 120.18,114.17 120.18,116.76 118.61,118.33 111.49,118.33 109.01,120.81 101.22,120.81 v2(99.39,122.64)
  BOTTOM w0.203: v2(119.64,113.86) 119.65,113.84 UC1.A22
  BOTTOM w0.254: v2(80.13,117.55) 80.13,117.41 80.48,117.05 81.2,117.05 82,117.85 RC135.2 ; v2(99.39,122.64) 99.91,122.12 RC82.2 ; v2(99.39,122.64) 99.19,122.64 99.07,122.76 89.37,122.76 89.11,122.5 RC83.2 v2(87.83,121.56) ; v2(99.39,122.64) 99.02,122.27 RC81.2 98.53,122.01 98.07,121.55 RC87.2
  BOTTOM w0.305: v2(80.13,117.55) 80.13,118.52 RC134.2 79.74,118.87 79.21,119.4 79.21,120.84 RC131.2
+1.0V_VCCSTG_C: length 0.6
  TOP w0.102: 123.62,123.71 v1(124.24,123.71)
+1.0V_VCCSTG_R: length 0.5
  BOTTOM w0.254: v2(121.07,109.54) UC1.G20
  vias: v1(120.78,111.14)
+1.0VO_DSW: length 2.3
  TOP w0.102: v2(132.87,96.78) v1(132.87,97.31)
  TOP w0.381: CC204.1 132.54,96.45 v2(132.87,96.78)
  BOTTOM w0.305: v2(132.87,96.78) 132.66,96.99 132.3,96.99 UC1.AL1
+1.0VS_VCCIO: length 239.8
  TOP w0.254: v2(209.12,71.61) 208.3,70.8 195.99,70.8 arc(186.44,72.7) 178.35,78.11 177.51,78.95 arc(171.3,88.25) 169.11,99.23 169.11,105.51 164.06,110.56 164.06,119.9 165.04,120.88 165.04,123.29 v2(166.11,124.37)
  TOP w0.381: v2(253.41,100.04) 254.08,100.7 255.32,100.7 256.46,101.85 258.28,101.85 258.92,102.49 QE11.1
  TOP w0.508: RC2.2 102.75,109.02 v2(102.75,107.96)
  IN1 w0.254: v2(138.33,126.69) 138.33,126.38 138.01,126.06 138.01,125.68 138.33,125.36 138.96,125.36 139.89,126.29 146.93,126.29 147.41,125.8 155.28,125.8 156.2,124.88 158.42,124.88 158.94,124.37 v2(166.11,124.37)
  IN2 w0.254: v2(209.12,71.61) 209.85,72.35 210.82,72.35 211.12,72.65 216,72.65 217.65,74.31 222.73,74.31 224.59,76.16 224.59,78.93 225.54,79.88 232.67,79.88 233.37,80.58 233.37,87.56 242.14,96.33 242.34,96.33 244.64,98.63 247.36,98.63 248.27,99.54 249.91,99.54 250.51,98.94 252.32,98.94 v2(253.41,100.04)
  IN3 w0.508: v2(102.75,107.96) 103.51,107.2 106.51,107.2 107.15,106.56 107.15,97.78 v2(108.27,96.66)
  BOTTOM w0.203: UC1.AK30 115.35,98.22 v2(115.58,98.22) ; v2(115.58,98.22) 115.81,98.22 UC1.AK28 ; v2(115.58,98.22) UC1.AL30 ; UC1.AM30 115.12,97.07 UC1.AL30 ; UC1.AL30 v2(115.58,96.66)
  BOTTOM w0.254: RC132.2 92.72,126.24 94.34,124.61 104.1,124.61 105.9,122.81 111.04,122.81 111.48,123.25 117.21,123.25 118.43,124.47 121.31,124.47 v2(121.94,125.11) ; UC1.AL42 v2(109.18,96.66) UC1.AM42 v2(108.27,96.66) ; UC1.AM28 v2(115.58,96.66) ; v2(114.67,96.66) UC1.AM30
  vias: v2(135.15,126.69) v2(135.79,126.69) v2(136.42,126.69) v2(137.06,126.69) v2(137.69,126.69) v4(115.66,97.29)
+1.2V_DDR_B+: length 0.4
  BOTTOM w0.102: 65.61,73.18 v1(65.17,73.18)
  vias: v2(65.87,75.07) v2(65.87,74.43) v2(65.87,73.8) v2(66.51,75.32)
+1.2V_DDRP: length 22.8
  TOP w0.254: PR204.1 PC208.1 63.46,70.81 63.21,70.56 63.21,59.85 65.28,57.78 65.89,57.78 66.32,57.35
  TOP w0.508: v2(69.87,68.27) 70.18,67.97 PC209.1
  BOTTOM w1.016: 70.76,61.09 70.76,66.42
  vias: v2(66,58.3) v2(66.64,58.3) v2(67.27,58.3) v2(67.91,58.3) v2(68.54,58.3) v2(69.18,58.3) v2(69.94,59.83) v2(69.94,59.19) v2(69.94,58.56) v2(69.94,57.92) v2(70.57,59.83) v2(70.57,59.19) v2(70.57,58.56) v2(70.57,57.92) v2(71.21,59.83) v2(71.21,59.19) v2(71.21,58.56) v2(71.21,57.92) v4(68.87,59.89)
+1.2V_LDO: length 1.5
  TOP w0.127: v2(271.78,61.15) 271.75,61.15 271.14,60.54 v4(271.14,59.93)
  vias: v2(271.78,61.73) v2(275.41,60.11) v2(275.77,60.59)
+1.2V_MEM: length 77.7
  TOP w0.381: 84.29,76.46 83.08,77.67 83.08,78.75 77.29,84.54 70.12,84.54 v2(69.15,83.58)
  BOTTOM w0.152: v2(114.59,90.14) 114.58,90.14 UC1.BB32
  BOTTOM w0.178: v2(119.75,89.76) 119.61,89.9 119.61,91.05 UC1.BB23 ; v2(105.97,90.33) UC1.BB47
  BOTTOM w0.203: v2(109.52,90.1) 109.52,90.99 UC1.BB41 ; v2(103.47,90.11) 103.52,90.16 UC1.BB51
  BOTTOM w0.254: UC1.AU42 v2(109.17,94.12) ; UC1.AU28 v2(115.58,94.15) ; UC1.AU23 v2(118.32,94.16) ; UC1.AU35 v2(111.93,94.12)
  BOTTOM w0.305: JDIMM1.199 127.72,63.13 v2(127.68,63.18) ; JDIMM1.154 v2(116.48,55) ; JDIMM1.148 v2(114.98,55) ; v2(111.48,55) JDIMM1.142 ; JDIMM1.130 108.48,52.84 108.1,52.46 v2(107.72,52.46) 107.31,52.46 106.97,52.8 JDIMM1.124 ; v2(112.16,63.26) 111.66,63.26 111.22,62.82 JDIMM1.141 ; JDIMM1.241 138.23,62.83 138.17,62.88 138.17,63.31 138.63,63.78 v2(138.79,63.78) ; v2(95.98,63.71) 95.34,63.71 94.72,63.1 JDIMM1.75 ; v2(78.97,54.94) JDIMM1.12 ; JDIMM1.220 132.97,53.7 v2(132.97,52.46) ; JDIMM1.54 89.47,54.7 v2(89.18,55) ; JDIMM1.136 109.97,52.75 110.28,52.45 v2(110.59,52.45) ; JDIMM1.129 108.22,62.92 108.58,63.27 v2(108.83,63.27) 109.31,63.27 109.72,62.86 JDIMM1.135 ; v2(122.35,55) 122.47,54.87 JDIMM1.178 ; JDIMM1.33 84.22,63.38 83.81,63.8 v2(83.47,63.8) ; v2(117.97,55) 117.97,53.7 JDIMM1.160 ; JDIMM1.96 v2(99.97,55) ; JDIMM1.123 106.72,61.9 106.72,62.77 v2(107.25,63.3) ; JDIMM1.163 118.72,63.1 118.44,63.38 v2(118.06,63.38) 117.99,63.38 117.72,63.12 JDIMM1.159 ; JDIMM1.117 105.22,62.94 104.92,63.24 v2(104.88,63.24) 104.1,63.24 103.72,62.87 JDIMM1.111 ; JDIMM1.112 103.97,52.84 104.28,52.54 v2(105.69,52.54) 105.47,52.75 JDIMM1.118 ; JDIMM1.153 116.23,62.73 116.38,62.89 116.38,63.39 v2(116.37,63.39) 116.34,63.42 115.34,63.42 114.72,62.81 JDIMM1.147
  BOTTOM w0.381: UD1.5 69.16,84.16 CD32.1 v2(69.15,83.58)
  vias: v4(78.66,69.11)
+1.2V_MEM_CPUCLK: length 3.2
  TOP w0.127: v2(110.09,96.66) 109.97,96.66 v4(109.64,96.33)
  TOP w0.305: v2(110.09,96.66) 109.55,97.21 RC231.1 CC297.1
  BOTTOM w0.152: v2(110.09,96.66) 110.03,96.66 UC1.AM40
+1.8V_3.3V_ALW_VTR3: length 20.5
  TOP w0.254: UE1.N5 258.52,87.06 CE21.1 258.53,87.58 258.99,88.03 PJP21.2 PJP20.2 264.09,88.03 v4(264.23,87.9) 264.35,87.78 264.35,82.82 265.72,81.45 270,81.45 RE340.2
+1.8V_PGPPF: length 8.7
  TOP w0.381: v2(123.9,100.75) 123.9,100.86 124.26,101.22 125.28,101.22 v1(125.31,101.19) 125.77,101.19 125.8,101.16 130.66,101.16 131.25,100.57 RC304.2
  BOTTOM w0.254: UC1.AF16 123.89,100.59 123.89,100.68 123.87,100.7 123.87,100.72 v2(123.9,100.75)
+1.8V_PRIM: length 244.7
  TOP w0.381: v2(133.07,102.41) 133.07,102.23 133.86,101.45 139.01,101.45 139.22,101.65 v2(139.68,101.65) 139.7,101.64 139.7,100.87 RC234.1
  TOP w0.508: v2(154.98,88.43) 154.78,88.62 154.06,88.62 151.91,86.47 151.91,85.04 v4(149.68,82.82) 148.41,81.54 RC212.1 147.74,80.97 145.97,79.21 145.97,75.7 149.96,71.72 159.8,71.72 v2(160.23,72.15) ; v2(133.07,102.41) 132.4,101.74 CC212.1 RC304.1
  IN1 w0.508: v2(155.66,94.33) 155.66,94.7 156.02,95.06 156.5,95.06 157.01,94.55 157.01,90.13 156.25,89.37 155.66,89.37 155.58,89.29 155.58,89.28 154.98,88.68 v2(154.98,88.43) ; v2(262.36,86.65) 263.03,87.33 264.18,87.33 264.81,86.7 265.51,86.7 266.83,85.38 266.83,79.36 v2(267.31,78.88)
  IN2 w0.508: v2(247.51,51.53) 245.83,49.86 211.8,49.86 v2(211.17,50.48)
  IN3 w0.508: v2(170.25,73.04) 169.9,72.68 162.99,72.68 162.46,72.15 v2(160.23,72.15) ; v2(139.68,101.65) 139.68,103.25 142.93,106.5 144.79,106.5 145.61,105.67 148.49,105.67 149.82,104.34 150.66,104.34 152.31,102.69 153.08,102.69 155,100.77 155,95.81 155.66,95.15 v2(155.66,94.33) ; v2(267.31,78.88) 267.31,78.19 261.02,71.9 261.02,69.44 262.17,68.29 262.17,66.32 261.26,65.41 260.26,65.41 259.84,65.83 251.39,65.83 247.29,61.72 247.29,60.72 246.85,60.27 246.85,57.73 248.23,56.35 248.23,52.25 v2(247.51,51.53)
  BOTTOM w0.203: UC1.AA1 132.11,102.49 132.97,102.49 133.04,102.41 v2(133.07,102.41)
  BOTTOM w0.508: v2(205.68,52.12) 207.33,50.48 v2(211.17,50.48) ; 180.74,61.54 180.74,65.49 176.93,69.3 174.08,69.3 170.99,72.4 170.89,72.4 v2(170.25,73.04) ; v2(139.68,101.65) 139.53,101.8 RC313.1
  BOTTOM w0.762: v2(205.68,52.12) 205.55,51.99 204.69,51.99 203.93,52.75 203.93,56.89 203.28,57.54 203.28,58.5 198.77,63 185.69,63 184.47,61.78 180.99,61.78 179.67,60.46
+1.8V_RUN: length 169.4
  TOP w0.254: 213.41,51.55 213.41,52.16 212.67,52.89 205.53,52.89 202.42,56.01 202.42,56.77 198.69,60.49 186.23,60.49 v2(183.26,63.46)
  TOP w0.508: CA65.1 265.63,56.35 v2(265.45,56.53) ; CA65.1 264.76,55.83 RA3.2 ; CA65.1 CA66.1 ; 213.93,51.44 v4(217.2,51.44) 218.53,52.77 221.63,52.77 223.73,50.68 227.52,50.68 228,51.16 v2(228,51.48)
  IN2 w0.254: v2(162.89,89.14) 162.81,89.06 161.14,89.06 160.45,89.75 153.26,89.75 152.27,90.74 150.44,90.74 149.53,91.65 149.53,93 150.19,93.66 150.19,97.04 149.5,97.72 147.6,97.72 146.4,98.92 143.89,98.92 143.31,99.5 142.16,99.5 141.57,98.91 v2(141.57,96.15)
  BOTTOM w0.254: v2(141.57,96.15) 141.57,96.21 140.98,96.8 RC363.2 RC362.2 ; v2(162.89,89.14) 164.84,89.14 165.61,88.38 165.61,81.39 166.77,80.22 171.78,80.22 183.26,68.74 v2(183.26,63.46)
  BOTTOM w0.508: v2(228,51.48) 229.38,50.09 254.6,50.09 256.37,51.87 262.64,51.87 263.99,53.22 263.99,55.07 v2(265.45,56.53)
+1.8V_RUN_AUDIO: length 8.2
  TOP w0.127: CA69.1 263.54,53.73 v4(263.82,53.45)
  TOP w0.203: UA1.36 259.53,56.99 259.61,56.91 v2(259.99,56.91) ; v2(261.47,58.94) 261.31,58.94 260.92,59.34 UA1.40
  IN2 w0.508: v2(261.47,58.94) 260.69,58.94 259.99,58.24 v2(259.99,56.91) 261.62,56.91 v2(261.67,56.96)
+1.8V_RUN_CARD: length 20.2
  TOP w1.016: 283.13,62.7 283.92,62.7 286.08,60.54 293.64,60.54 295.13,59.04 297.71,59.04
  IN2 w1.016: 276.27,61.56 278.36,61.56 279.75,62.95
  vias: v2(275.66,61.78) v2(275.66,61.2) v2(280.67,63.49) v2(281.06,63.08) v4(283.42,63.64)
+1.8V_RUN_UZ8:
  vias: v1(209.93,52.3)
+1.8VALWP: length 11.9
  BOTTOM w0.254: 178.2,62.24 179.41,63.45 179.41,65.42 v4(177.19,67.64) 176.01,68.82 173.65,68.82 173.56,68.9 PC503.1 PR501.1
+1VALWP: length 8
  BOTTOM w0.254: 160.45,89.65 155.51,89.65 v4(155.22,89.36) 154.34,88.48 PC307.1 154.33,87.95 PR306.1
  vias: v2(161.5,87.83) v2(161.5,87.2) v2(161.5,86.56) v2(161.5,85.93)
+1VALWP_B+: length 0.9
  TOP w0.102: v2(153.08,82.84) 152.33,82.84 v1(152.26,82.76)
  vias: v2(153.35,82.32)
+1VS_VCCIOP: length 7.4
  BOTTOM w0.102: PC422.1 134.77,128.12 134.43,127.77 v1(134.43,127.33)
  BOTTOM w0.254: PC406.1 134.77,131.98 135.45,132.66 PR421.1
+2.5V_MEM: length 3.3
  TOP w0.127: v4(143.71,65.16) 144.16,65.16 145.2,64.12 145.2,62.74
  vias: v2(143.28,62.24) v2(143.28,61.61)
+2.5V_VIN:
  vias: v1(152.54,59.54)
+3.3V_1.8V_ESPI: length 1.9
  TOP w0.127: v1(146.9,85.06) 146.56,84.72 RC21.2
+3.3V_1.8V_PGPPA: length 34.5
  TOP w0.254: v2(136.29,89.99) 136.99,89.29 136.99,88.26 137.51,87.74 138.88,87.74 139.73,86.89 141.42,86.89 142,86.31 143.71,86.31 144.24,86.85 146.26,86.85 v1(146.43,86.69) 147.32,85.8 147.32,83.93 146.76,83.37
  IN1 w0.254: v2(136.29,89.99) 135.65,90.64 129.48,90.64 127.02,93.09 127.02,96.46 127.02,96.46 127.02,96.92 126.13,97.8 125.28,97.8 v2(124.73,97.25)
  BOTTOM w0.254: v2(124.73,97.25) 124.73,97.38 UC1.AK15
+3.3V_1.8V_PGPPG: length 18
  TOP w0.254: RC234.2 137.9,100.85 RC235.2 137.02,100.86 CC326.1 137.01,100.32 136.75,100.06 v2(136.75,99.9)
  IN2 w0.254: v2(136.75,99.9) 136.75,98.82 136.02,98.08 131.99,98.08 130.01,100.06 125.25,100.06 v2(124.6,100.7)
  BOTTOM w0.254: UC1.AD15 124.29,101.12 124.6,100.8 v2(124.6,100.7)
+3.3V_ALW: length 362.7
  TOP w0.127: v2(38.19,60.65) v4(38.89,60.65)
  TOP w0.254: v2(261.49,81.09) 260.96,81.09 RE37.2 ; UE2.18 265.58,92.72 265.31,92.99 CE1.1 CE2.1 263.59,92.12
  TOP w0.305: JAPS1.3 v2(263.56,108.96) ; v2(261.62,108.96) 261.56,108.9 JAPS1.7
  TOP w0.356: CE53.1 268.29,99.11 UE3.5
  TOP w0.381: v2(249.44,101.94) RE84.2 250.39,102.26 RE79.1 ; UE6.5 v2(269.52,80.73) ; CZ104.1 141.49,67.7 UZ34.5 ; v2(43.71,52.21) 43.71,51.59 PR1234.2 44.47,52.09 PR1232.2 45.03,52.4 45.88,52.4 PR1230.2 PR1233.2 47.08,52.65 46.57,53.16 46.57,53.92 46.89,54.24 48.86,54.24 v2(49.62,53.48) 50.06,53.03 PR1231.2 ; RE25.1 258.42,96.98 RE35.2 RE38.2 RE8.2 256.63,97.42 256.82,97.61 RE300.1 257.66,97.85 v2(257.71,97.8) ; RE362.2 248.79,77.72 RE343.2 248.8,77.19 v2(248.73,77.11) ; UE3.5 269.82,98.9 269.88,98.83 UE4.5 ; UE5.5 264.99,98.96 264.83,99.12 CE52.1 ; QZ2.2 v2(270.34,83.89) ; RE12.2 v2(261.52,79.96) ; PR933.1 54.82,51.74 v2(55.09,51.47) ; RE301.2 247.17,97.7 247.6,98.13 RE5.2 ; 265.72,84.83 265.64,84.91 265.64,85.61 v2(265.62,85.63) ; 265.72,84.83 CZ93.1 ; 265.72,84.83 UZ10.5 ; RE91.2 RE83.2 250.54,99.13 RE63.2 v2(251.17,99.77) ; v2(143.2,81.39) 142.63,81.39 RC68.2 ; v2(258.66,80.27) RE10.2 RE43.2 ; v2(38.77,78.48) 37.49,79.77 RT68.2
  TOP w0.457: RE15.1 RE13.1 v2(265.58,88.15) ; RE301.2 RE21.2 246.28,97.61 v2(246.53,97.86)
  TOP w0.508: CE60.1 RE98.2 261.42,85.96 v2(261.4,85.95) RE524.2 RE525.2 ; RE526.1 221.33,55.75 v2(221.13,55.95) ; CE52.1 v2(265.45,100.02) ; v2(59.43,118.24) 59.43,119.2 59.94,119.71 PR28.2 ; PR307.1 157.49,86.19 v2(157.69,85.99) ; v2(142,79.42) 141.83,79.25 RC214.1 ; v2(121.73,130.82) 123.39,132.48 123.39,134.07 124.66,135.34 138.77,135.34 v4(139.15,134.96) 140.36,133.75 ; CZ104.1 143.11,67.69 v2(143.66,67.14) ; RE303.2 RE512.2 239.27,86.35 238.65,86.35 v2(238.64,86.35) ; RE303.2 RE302.2 ; RE303.2 RE68.2 ; RE377.2 254.93,106.78 v2(255.37,107.22) 255.81,106.78 RE376.2 ; RE348.2 241.43,95.06 240.08,95.06 v2(239.75,95.39) ; RE69.1 268.29,100.63 CE53.1 v2(267.69,100.02) ; RZ9.1 234.67,52.51 235.35,53.2 235.35,54.4 234.55,55.21 RZ8.1 233.32,56.2 233.92,56.79 233.92,58.19 233.34,58.77 230.03,58.77 229.6,58.34 227.66,58.34 227.65,58.33 227.33,58.65 ; PR410.1 v2(165.25,129.3) ; PR4.2 44.09,118.93 43.53,118.37 v2(43.53,118.05) ; PR418.1 157.88,132.09 158.34,132.55 v2(158.34,133.88) ; 140.36,133.75 PR414.1 v2(144.69,133.75) ; 140.36,133.75 PR404.1 ; v2(269.58,87.18) 269.92,87.52 RE17.1 ; RE11.2 v2(247.04,79.39) ; UE7.5 244.61,98.56 244.94,98.89 CE6.1 245.63,98.89 246.53,97.99 v2(246.53,97.86) ; v2(270.93,86.64) 270.79,86.78 RE6.1 CE61.1
  IN1 w0.381: v2(221.13,55.95) 220.37,55.95 220.05,56.27 220.05,57.03 220.56,57.54 226.12,57.54 v2(226.59,58.01)
  IN1 w0.508: v2(63.71,73.67) 64.49,72.9 v2(64.49,70.1)
  IN2 w0.381: v2(49.62,53.48) 50.68,52.41 54.15,52.41 v2(55.09,51.47)
  IN2 w0.508: v2(143.66,67.14) 143.66,68.36 141.76,70.27 141.76,71.74 137.59,75.91 v2(137.59,78.14) ; v2(43.71,52.21) 43.51,52 41.86,52 40.99,52.87 40.99,59.75 40.09,60.65 v2(38.19,60.65) 39.01,61.48 39.01,63.05 37.74,64.32 37.74,76.44 38.86,77.56 v2(38.86,77.87) ; v2(288.25,4.51) 288.25,6.96 285.32,9.89 285.32,23.4 277.98,30.74 277.98,53.27 281.35,56.65 281.35,62.27 282.7,63.61 282.7,67.79 281.65,68.84 277.65,68.84 276.95,69.54 276.95,71.22 276.55,71.61 275.78,71.61 272.87,74.53 272.87,78.63 270.76,80.73 v2(269.52,80.73)
  IN3 w0.508: v2(162.24,62.91) 162.24,61.75 162.82,61.16 165.56,61.16 166.01,61.62 171,61.62 171.5,62.12 172.24,62.12 173.26,61.1 177.54,61.1 178.16,60.48 181.39,60.48 181.89,59.97 181.89,59.09 v2(181.25,58.45)
  BOTTOM w0.254: PU200.13 65.68,69.31
  BOTTOM w0.305: JKBTP1.15 207.05,58.13 207.27,57.91 v2(207.27,57.8)
  BOTTOM w0.381: v2(121.73,130.82) 121.78,130.77 UZ35.5 ; v2(43.71,52.21) 43.41,52.21 42.77,52.84 PR1259.2 ; PR413.1 144.68,133.74 v2(144.69,133.75) ; PR1235.2 50.07,53.02 v2(49.62,53.48) ; PR107.1 180.82,58.02 v2(181.25,58.45) 181.7,58.01 PR113.1
  BOTTOM w0.457: PR205.2 64.48,70.11 v2(64.49,70.1) PC206.1 64.59,69.48 64.87,69.2 64.88,69.2 64.98,69.1 65.47,69.1 65.68,69.31
  BOTTOM w0.508: v2(59.43,118.24) 59.43,118.95 60.15,119.66 PR29.1 ; 226.26,56.93 225.94,56.61 225.94,54.66 221.77,50.48 214.09,50.48 212.51,52.06 210.08,52.06 207.27,54.86 v2(207.27,57.8) ; RE74.1 v2(287.78,120.47) ; UE9.8 242.04,123.07 241.53,122.57 v2(241.53,122.31) ; PR1225.1 38.95,60.73 PR1224.2 v2(38.19,60.65) ; PR417.1 v2(158.34,133.88) ; JLED1.6 v2(288.25,4.51) ; 227.61,61.29 RE532.1 ; RE505.2 v2(252.63,127.84)
  BOTTOM w1.016: 226.46,61.35 226.46,62.06 223.82,64.7 223.82,66.33
  vias: v2(67.55,121.87) v2(68.16,121.87) v2(68.77,121.87) v2(152.91,85.62) v2(157.48,114.48) v2(157.91,114.07) v2(165.49,69.26) v2(165.49,68.63) v2(165.75,68.03) v2(166.13,69.26) v2(166.06,68.63) v2(166.38,68.03) v2(166.65,68.63) v2(166.76,69.26) v2(167.02,68.03) v2(167.23,68.67) v2(167.4,69.26) v2(167.82,68.71) v2(168.74,69.26) v2(169.3,69.26) v2(169.3,68.63) v2(223.48,67.2) v2(224.12,67.2) v2(227.15,58.01) v2(252.12,109.56) v2(252.27,112.99) v2(252.75,109.56) v2(252.91,112.99) v2(253.12,110.18) v2(253.39,109.56) v2(253.52,112.99) v2(253.54,75.93) v2(254.13,75.93) v2(260.83,86.73) v2(263.49,90.8) v2(263.49,89.8) v2(263.56,94.51) v2(263.56,93.51) v2(278.92,93.36) v2(278.92,92.66) v2(279.55,93.36) v2(279.55,92.66) v2(280.06,92.97) v2(287.23,125.23) v2(287.23,124.53) v4(164.64,67.55)
+3.3V_ALW2: length 95
  TOP w0.254: RE57.2 245.1,75.1 239.74,75.1 237.59,77.25 234.36,77.25 233.83,76.72 231.23,76.72 v2(230.47,77.48) ; PR104.2 v4(163.98,79.74) 172.49,79.74 176.07,76.16 176.33,76.16 arc(180.14,74.44) 183.67,72.2 arc(188.15,70.32) 192.94,69.48 209.55,69.48 211.25,71.18 v2(211.25,71.54)
  IN3 w0.254: v2(230.47,77.48) 225.02,77.48 219.86,72.32 211.58,72.32 211.25,71.99 v2(211.25,71.54)
+3.3V_ALW_DSW: length 176.8
  TOP w0.381: RC72.2 v2(131.02,82.94) ; v2(127.34,86.37) 127.34,89.48 126.05,90.77
  TOP w0.508: RC214.2 140.64,80.16 140.46,80.34 CC280.1 CC279.1 138.95,80.35 RC243.2 RC67.2 136.41,80.35 v2(135.98,80.78) ; v2(86.44,125.69) 87.95,127.2 v4(89.01,127.2) RC241.2
  IN1 w0.508: v2(131.02,82.94) 131.46,82.51 134.49,82.51 135.98,81.02 v2(135.98,80.78) ; v2(81.83,133.85) 82.11,134.13 107.31,134.13 109,132.45 116.29,132.45 119.45,129.28 122.74,125.99 129.97,125.99 131.55,124.42 132.66,124.42 132.9,124.66 139.02,124.66 139.18,124.82 146.31,124.82 146.4,124.74 v2(153.03,124.74) ; v2(148.13,101.46) 148.13,100.93 146.91,99.7 146.91,94.46 147.22,94.14 v2(147.22,91.97)
  IN2 w0.508: v2(127.34,86.37) 127.6,86.37 v2(131.02,82.94) 131.02,83.13 133.31,85.42 134.39,85.42 136.36,87.39 v2(142.78,87.39) ; v2(153.03,124.74) 152.47,124.18 150.74,124.18 147.01,120.45 147.01,118.86 147.55,118.32 148.18,118.32 149.09,117.4 149.09,102.42 v2(148.13,101.46) ; v2(122.65,100.73) 122.66,100.71 v2(122.66,98.24)
  IN3 w0.508: v2(142.78,87.39) 143.08,87.39 147.22,91.53 v2(147.22,91.97)
  BOTTOM w0.254: v2(122.65,100.73) 122.62,100.75 122.62,100.89 UC1.AD18 ; v2(122.66,98.24) 122.66,98.33 UC1.AJ17
  BOTTOM w0.305: UC1.AD17 122.65,100.83 v2(122.65,100.73)
  BOTTOM w0.508: v2(86.44,125.69) 83.91,128.22 83.44,128.22 82.42,129.24 82.42,133.25 v2(81.83,133.85) ; v2(148.13,101.46) 147.8,101.79 RC323.2
+3.3V_ALW_PCH: length 476.9
  TOP w0.254: v2(225.7,80.84) 225.8,80.73 225.8,80.19 224.56,78.94 224.56,77.78 arc(223.26,74.66) 220.15,73.37 217.96,73.37 217.04,74.28 214.59,74.28 210.72,71.93 210.72,71.18 209.4,69.86 193.25,69.86 arc(188.53,70.73) 184.07,72.5 arc(180.36,74.84) 176.38,76.67 167.69,85.35 167.69,88.07 164.29,91.48 161.05,91.48 160.71,91.13 151,91.13 v2(150.72,91.42) ; RC187.2 124.27,79.36 125.5,78.13 126.59,78.13 127.34,77.38 135.76,77.38 136.47,78.09 v2(136.47,78.45) ; RC23.2 133.51,105.42 134.19,105.42 RC12.2 136.16,107.39 v4(137.45,107.39) v2(138.31,107.39)
  TOP w0.305: JAPS1.1 v2(264.56,108.96)
  TOP w0.381: RC183.2 RC73.2 ; RC73.2 RC387.2 RC74.2 ; RC73.2 RC344.2 142.23,83.08 v2(142.29,83.15)
  TOP w0.457: CC209.1 121.39,102.8 v2(121.39,103.26)
  TOP w0.508: RC211.1 144.65,81.54 143.43,82.76 v2(142.8,82.76)
  TOP w1.016: 141.93,70.8 145.34,67.4 146.2,67.4 147.17,66.43
  IN2 w0.254: v2(225.7,80.84) 226.67,81.81 226.67,87.16 229.74,90.23 229.74,110.02 234.42,114.69 v2(235.63,114.69)
  IN2 w0.381: v2(119.8,99.02) 119.8,101.31 120.61,102.12 120.61,102.48 v2(121.39,103.26)
  IN2 w0.508: v2(138.87,105.24) 138.87,106.83 v2(138.31,107.39) 138.31,107.39 136.84,108.87 136.84,111.16 135.84,112.16 135.84,119.19 135.26,119.77 135.26,120.86 136.41,122.01 v2(136.46,122.01) ; v2(152.14,108.62) 152.26,108.74 152.26,112.32 151.6,112.98 151.6,117.78 v2(154.06,120.24)
  IN3 w0.254: v2(148.31,65.26) 150.34,65.26 151.76,63.84 151.76,61.33 156.06,57.03 162.38,57.03 163.44,55.97 178.46,55.97 179.4,56.91 183.79,56.91 184.88,57.99 184.88,58.46 185.28,58.85 195.65,58.85 196.4,58.1 200.8,58.1 202.68,56.21 208.37,56.21 211.28,53.3 213.41,53.3 214.1,52.61 218.46,52.61 219.3,53.45 225.76,53.45 225.96,53.25 227.71,53.25 230.63,50.33 247.58,50.33 249.01,51.76 249.01,56.65 248,57.66 248,61.75 251.49,65.24 259.54,65.24 259.99,64.78 261.52,64.78 262.92,66.18 262.92,69.33 263.41,69.82 263.41,73.1 267.66,77.35 277.65,77.35 278.73,78.43 278.73,80.02 278.22,80.53 278.22,82.05 275.16,85.11 275.16,93.15 274.06,94.24 274.06,95.88 270.34,99.6 270.34,102.31 264.56,108.09 v2(264.56,108.96)
  BOTTOM w0.254: v2(235.63,114.69) 239.25,114.69 244.21,109.73 250.86,109.73 251.69,108.9 253.67,108.9 254.91,110.15 263.37,110.15 v2(264.56,108.96) ; UC1.AK17 123,97.8 123,97.36 v2(122.93,97.28) ; UC1.AJ21 120.17,98.66 v2(119.8,99.02) ; v2(225.7,80.84) RC222.2 ; v2(121.39,103.26) 121.39,103.46 121.61,103.69 UC1.V19
  BOTTOM w0.305: JSPI1.5 166.35,93.91 166.65,93.61
  BOTTOM w0.381: v2(145.08,105.07) 145.43,105.43 149.57,105.43 152.14,108 v2(152.14,108.62) ; UC7.5 154.52,119.79 v2(154.06,120.24) ; 166.65,93.61 166.65,92.02 165.52,90.89 162.33,90.89 161.85,90.41 158.62,90.41 158.49,90.54 151.6,90.54 v2(150.72,91.42) ; RC347.2 v2(144.11,101.48) RC283.2
  BOTTOM w0.508: RC17.2 RC15.2 RC25.2 RC348.2 v2(143.79,104.15) ; RC331.2 RC330.2 146.91,100.44 146.36,100.99 v2(146.36,101.65) ; RC400.2 v2(138.31,107.39) RC371.2
  vias: v2(137.06,78.45) v2(140.69,71.89) v2(140.69,71.31)
+3.3V_ALW_PCH_UZ3: length 6.8
  TOP w1.016: 150.46,64.59 151.41,63.64 152.17,63.64 152.68,63.13 v1(152.68,61.48) 153.44,60.72 153.44,59.51
+3.3V_ALW_UE1: length 46.5
  TOP w0.127: v2(243.25,87.74) v4(242.52,87.74)
  TOP w0.203: UE1.K2 v2(254.28,84.26) ; 245.97,87.97 246.26,88.26 247.08,88.26 UE1.B7 ; CE13.1 258.06,90.3 257.62,89.86 v2(255.88,89.86)
  TOP w0.254: UE1.H1 252.15,83.72 252.15,82.33 252.28,82.19 ; UE1.M9 v2(255.88,89.86) ; UE1.G8 v2(251.08,89.86)
  TOP w0.356: v2(251.79,95.08) 251.46,95.41 CE19.1
  TOP w0.381: CE14.1 243.89,87.81 CE23.1 245.81,87.81 245.97,87.97 ; CE15.1 252.22,81.72 252.25,81.75 v2(252.25,81.8) 252.28,81.84 252.28,82.19
  TOP w0.508: v2(243.25,87.74) 243.83,87.74 CE14.1 ; RE314.2 252.21,79.34 252.21,81.15 CE15.1
  IN2 w0.381: v2(251.08,89.86) 251.08,89.27 250.59,88.78 246.22,88.78 245.18,87.74 v2(243.25,87.74)
  IN2 w0.457: v2(254.28,84.26) 252.25,82.22 v2(252.25,81.8)
  BOTTOM w0.457: 252.09,89.01 252.09,84.21 252.65,83.65 252.65,82.21 v2(252.25,81.8) ; 252.09,89.01 251.25,89.86 ; 252.09,89.01 255.04,89.01 v2(255.88,89.86) ; v2(251.79,95.08) 251.79,90.36 251.29,89.86 251.25,89.86 ; 251.25,89.86 v2(251.08,89.86)
+3.3V_ALWP: length 29.2
  IN1 w0.254: v2(155.73,78.59) 156.83,78.59 158.04,79.79 165.23,79.79 166.32,78.7 166.32,77.4 v2(166.2,77.29) ; v2(166.2,76.66) 166.43,76.66 166.7,76.92 166.7,78.88 165.4,80.17 157.72,80.17 v2(157.12,79.58)
  BOTTOM w0.254: v2(155.73,78.59) 155.16,78.59 154.91,78.33 PU100.14 ; PR108.2 v2(157.12,79.58)
  vias: v2(166.2,76.02) v2(166.2,75.39) v2(166.2,74.75) v4(165.7,77.95)
+3.3V_CAM:
  vias: v1(57.53,127.81) v2(56.7,130.58) v2(56.7,129.97)
+3.3V_CPS: length 24.7
  TOP w0.203: UT9.28 26.37,107.27 26.23,107.41 26.04,107.41 25.23,108.21 CT121.1 ; CT118.1 28.37,98.5 UT9.6 ; CT120.1 30.96,106.89 30.16,106.1 UT9.20
  TOP w0.356: v2(28.89,98.93) 28.89,98.44 CT118.1
  TOP w0.381: v2(24.7,109.48) 24.41,109.19 RT308.2 ; CT120.1 31.23,107.11 v2(31.55,107.43) ; RT246.1 v2(25.11,97.01) ; v2(25.11,107.71) 25.11,108.15 25.23,108.29 CT121.1
  TOP w0.508: v2(26.88,108.21) 26.43,108.67 RT131.2
  BOTTOM w0.508: RT141.2 25.11,106.3 v2(25.42,106.61) ; RT135.2 v2(27.84,96.72) ; v2(31.55,107.43) 32.36,107.43 32.87,106.92 RT145.2 RT139.2 RT137.2 ; v2(26.58,96.73) 26.58,97.08 RT247.2 ; v2(25.11,97.01) 24.15,97.97 RT143.2
  vias: v1(32.84,99.67) v2(31.27,99.92) v2(31.27,99.32)
+3.3V_CPS_R1: length 3.3
  TOP w0.203: 26.24,100.24 26.37,100.38 UT9.1
  TOP w0.381: 26.24,100.24 26,100 v1(26,99.81) CT122.1 RT246.2
+3.3V_HDD_M2:
  vias: v2(26.69,46.37) v2(26.69,45.73) v2(27.33,46.37) v2(27.33,45.73) v2(28.03,46.37) v2(28.03,45.73) v4(12.83,45.21) v4(18.85,45.83) v4(21.93,45.77)
+3.3V_LAN: length 341.3
  TOP w0.254: v2(166.11,123.66) 165.4,122.94 165.4,120.7 164.44,119.75 164.44,110.72 169.49,105.66 169.49,99.23 arc(171.65,88.4) 177.78,79.22 178.62,78.38 arc(186.59,73.05) 195.99,71.18 207.62,71.18 v2(208.2,71.77)
  TOP w0.381: v2(254.15,131.39) 254.15,131.9 254.46,132.21 RL29.1 RL30.1
  TOP w0.508: RL5.2 241.15,119.96 RL6.2 241.07,119.89 241.07,118.76 241.64,118.18 v2(242.02,118.18) ; v2(241.03,124.09) 241.03,123.3 RL4.2
  IN1 w0.254: v2(166.11,123.66) 158.63,123.66 157.98,124.31 156.08,124.31 155.03,125.36 146.98,125.36 v2(146.55,125.8)
  IN2 w0.254: v2(144.11,102.37) 143.25,103.23 143.25,107.91 145.11,109.77 145.11,115.25 144.7,115.66 144.7,124.61 145.89,125.8 v2(146.55,125.8) ; 241.17,119.42 v2(232.51,119.42)
  IN2 w0.508: 253.15,129.74 251.84,128.43 251.84,114.67 250.32,113.14 250.32,109.68 251.01,108.98 256.27,108.98 257.53,107.72 261.23,107.72 263.64,105.31 266.75,105.31 273.71,98.35 275.8,98.35 276.9,97.26 276.9,86.1 277.58,85.42 280.94,85.42 281.44,85.93 281.44,88.52 284.95,92.03 284.95,94.18 283.88,95.25 JLOM1.9
  IN2 w1.016: 284.58,120.99 284.58,127.54 282.64,129.49 255.87,129.49 255.14,130.21 254.27,130.21
  IN3 w0.254: v2(208.2,71.77) 209.13,72.15 210.39,72.15 211.1,72.86 219.73,72.86 224.86,77.99 224.86,78.4 228.95,82.48 228.95,89.3 229.6,89.95 229.6,98.03 230.05,98.47 230.05,110.6 232.51,113.07 v2(232.51,119.42)
  BOTTOM w0.254: RL70.2 v2(144.11,102.37) RC19.2 143.48,102.88 RC20.2
  BOTTOM w0.381: RL2.2 243.8,130.58 v2(243.8,131.27) RL1.2 ; v2(254.15,131.39) 254.15,133.23 253.77,133.61 CL15.1 253.11,132.78 UL2.5
  BOTTOM w0.508: v2(284.88,120.15) 285.38,119.66 JLOM1.12
  vias: v2(241.67,124.09) v2(246.78,113.36) v2(247.36,113.68) v2(247.36,112.98) v2(284.25,120.15) v4(284.35,119.52)
+3.3V_LAN_OUT: length 4.2
  TOP w0.203: UL1.15 v2(250.15,124.53) ; UL1.19 v2(248.39,126.13) ; v2(246.85,130.19) 246.88,130.16 UL1.29
  BOTTOM w0.508: CL29.1 247.1,129.93 v2(246.85,130.19)
  vias: v1(247.97,126.54) v2(244.82,121.49) v2(245.45,122.06)
+3.3V_LAN_UZ2: length 1.4
  TOP w0.102: 249.87,113.9 249.9,113.94 v1(251.24,113.94)
+3.3V_M_TPM: length 5.9
  TOP w0.112: v2(162.58,104.93) v4(162.58,105.76)
  BOTTOM w0.254: CZ54.1 156.72,106.12 158.05,106.12 158.33,106.4 UZ12.22
  BOTTOM w0.381: CZ54.1 156.25,105.65 QZ9.3
  vias: v2(154.54,107.48) v2(154.53,106.83) v2(162.99,104.53)
+3.3V_MMI_AUX:
  vias: v4(272.95,70.7)
+3.3V_MMI_IN: length 1.9
  TOP w0.127: v4(271.99,76.27) 272.78,75.49 272.78,74.71
  vias: v2(272.64,59.24) v2(273.07,58.86) v2(273.75,72.82) v2(273.76,72.26)
+3.3V_PDA_VOUT: length 2.6
  TOP w0.076: UT5.H2 30.27,83.22 30.27,84.09 30.09,84.27
  TOP w0.112: 30.09,84.27 30.06,84.3
  TOP w0.254: CT83.1 29.95,85.08 29.95,84.42 30.06,84.3
+3.3V_PGPPB: length 8.4
  TOP w0.381: v2(123.98,99.08) 124.32,99.42 CC265.1 124.46,100.09 v1(126.08,100.09) 126.57,100.09 126.57,100.09 130.17,100.09 130.64,99.62 RC305.2
  BOTTOM w0.254: UC1.AG15 124.29,99.39 v2(123.98,99.08)
+3.3V_PGPPC: length 18.1
  TOP w0.127: v1(137.6,101.92) 137.11,102.41 RC306.2
  TOP w0.457: v2(123.33,102.43) 123.33,101.95 CC207.1 ; v2(136.45,102.44) 136.83,102.82 RC306.2
  IN3 w0.457: v2(136.45,102.44) 136.45,102.86 135.42,103.88 125.15,103.88 124.59,103.33 123.9,103.33 123.33,102.75 v2(123.33,102.43)
  BOTTOM w0.254: v2(123.33,102.43) 123.64,102.74 UC1.Y16
+3.3V_PGPPD: length 14.5
  TOP w0.457: RC307.2 136.76,103.71 v1(136.02,102.96) 135.79,102.73 v2(135.79,102.44)
  IN3 w0.457: v2(135.79,102.44) 135.79,102.65 135.15,103.29 125.36,103.29 124.65,102.59 124.65,102.59 124.67,102.58 124.67,102.58 v2(124.68,102.58)
  BOTTOM w0.254: UC1.Y15 124.41,102.85 v2(124.68,102.58)
+3.3V_PGPPE: length 17
  TOP w0.127: v2(123.33,104.1) 123.27,104.1 122.85,103.68 v1(122.32,103.68)
  TOP w0.508: CC208.1 123.4,103.4 123.4,104.03 v2(123.33,104.1) ; RC308.2 136.49,104.6 v2(136.42,104.66)
  IN2 w0.254: v2(123.33,104.1) 123.33,104.06 123.9,103.49 130.61,103.49 131.52,104.4 136.17,104.4 v2(136.42,104.66)
  BOTTOM w0.254: v2(123.33,104.1) 123.33,104.21 UC1.T16
+3.3V_RTC_LDO: length 192.6
  TOP w0.508: PR105.2 159.89,78.85 v4(161.4,77.34) v2(161.4,73.49) ; v2(277.71,53.92) 277.71,51.51 279.8,49.41 279.8,28.41 284.88,23.33 284.88,11.5 285.46,10.93 286.09,10.93 286.55,10.47 PD3.3
  IN1 w0.508: v2(212.24,50.53) 224.22,50.53 225.85,52.16 228.61,52.16 229.83,50.95 237.2,50.95 240.08,53.83 v2(241.41,53.83)
  IN2 w0.508: v2(174.13,70.35) 173,70.35 172.62,70.74 163.23,70.74 161.4,72.57 v2(161.4,73.49) ; v2(241.41,53.83) 242.36,52.88 251.11,52.88 252.2,51.79 263.02,51.79 267.31,56.07 272.31,56.07 274.46,53.92 v2(277.71,53.92)
  BOTTOM w0.508: v2(212.24,50.53) 211.56,51.22 209.55,51.22 207.11,53.66 205.59,53.66 204.85,54.39 204.85,57.01 204.02,57.84 204.02,58.8 198.86,63.96 185.32,63.96 183.92,62.56 181.91,62.56 181.41,63.07 181.41,66.03 176.87,70.56 174.34,70.56 v2(174.13,70.35)
+3.3V_RUN: length 471.6
  TOP w0.254: RC282.2 145.96,85.9 v2(145.54,86.32) ; RC137.2 85.29,133.17 84.69,132.56 84.69,131.33 85.1,130.91 85.1,128.05 84.23,127.19 79.86,127.19 78.96,126.29 78.96,125.48 v2(78.95,125.47) ; v2(21.94,89.16) 21.56,88.78 18.95,88.78 18.76,88.59 QV3.2 ; v2(21.99,91.07) 19.39,91.07 18.76,90.43 QV3.5
  TOP w0.356: v2(55.75,130.92) 55.97,130.71 CA7.1
  TOP w0.381: v2(60.77,125.84) 61.42,126.48 61.42,134.01 62.04,134.63 65.76,134.63 RV8.2 ; RV87.2 115.49,126.87 CV82.1 116.36,126.17 v2(116.33,126.14) ; v2(134.59,119.52) 134.59,119.52 134.59,118.62 134.96,118.25 ; RD8.1 136.68,51.83 138.64,53.8 141.44,53.8 142.45,54.81 144.87,54.81 145.52,55.46 RD6.1 ; v2(133.91,108.98) 133.02,108.98 RC178.2 RC175.2 133.17,110.17 133.17,110.81 132.48,111.49 132.48,113.42 134.45,115.39 134.45,117.74 134.96,118.25 ; CV83.1 118.69,128.79 v2(118.72,128.81) ; 134.96,118.25 138.14,118.25 139.22,119.33 139.22,122.57 138.25,123.53 135.01,123.53 130.01,128.53 129.06,128.53 126.8,130.79 v2(126.06,130.79) ; CV81.1 106.2,133.06 RV70.2 105.87,132.17 105.48,131.79 v2(105.48,130.76) 105.3,130.76 105.03,130.49 105.03,128.28 105.56,127.75 106.58,127.75 107.08,128.26 RV71.2 ; v2(224.62,56.56) 224.66,56.52 CZ67.1 224.62,55.98 CZ72.1 ; v2(122.01,133.91) 122.01,133.17 121.56,132.73 120.1,132.73 119.81,133.02 CV85.1 119.81,133.69 v2(119.59,133.91)
  TOP w0.457: v2(108.73,127.31) 108.57,127.47 CV84.1 108.14,128.4 RV71.2 ; v2(135.1,102.44) 135.1,102.83 134.53,103.4 RC287.2 133.4,103.4 RC413.2 ; RC13.2 v2(136.61,82.88) RC27.2 RC414.2 RC186.2 ; PR612.1 43.5,92.53 v2(43.46,92.57)
  TOP w0.508: v2(118.72,128.81) 118.72,128.17 117.42,126.87 CV82.1 ; RV18.1 18.49,75.4 19.14,74.75 22.06,74.75 22.82,75.51 25.97,75.51 27.37,76.91 v2(27.58,76.91) ; v2(239.79,67.31) 240.92,66.18 240.92,65.1 241.43,64.59 242.51,64.59 243.32,65.41 244.56,65.41 ; v2(148.23,109.99) 148.23,110.48 148.99,111.25 RC176.2 ; v2(146.61,55.79) 146.61,56.44 RD10.1 146.45,56.59 RD4.1 RD6.1 ; v2(146.76,116.22) 146.76,115.79 147.46,115.09 RC177.2 ; v2(214.55,53.35) 213.92,53.99 207.8,53.99 207.16,54.62 207.16,55.13 ; v2(73.62,71.96) 74.34,72.68 76.25,72.68 77.43,73.86 77.43,81.04 75.91,82.56 74.13,82.56 73.7,82.99 70.51,82.99 70.08,82.56 68.58,82.56 67.92,83.22 v2(67.92,83.53) ; RC59.2 139.91,83.58 v2(140.36,83.13) 139.91,82.69 RC190.2 ; v2(50.95,125.93) 50.95,124.88 QV8.3 50.14,122.12 RV6.2 ; v2(58.51,125.82) 58.51,124.9 58.13,124.52 QZ1.3
  TOP w3.048: 27.46,54.11 27.46,60.65 33.9,67.1
  IN1 w0.508: v2(242.09,72.62) 241.07,72.62 239.98,73.71 239.98,77.55 239.61,77.93 239.04,77.93 238.53,78.43 238.53,80 237.6,80.93 237.6,83.8 v2(236.94,84.46) ; v2(108.21,124.06) 108.73,124.58 v2(108.73,127.31) ; v2(144.77,99.41) 143.83,98.47 143.83,97.47 v2(142.55,96.2) ; v2(146.61,55.79) 147.8,56.98 155.33,56.98 v2(156.3,57.96)
  IN2 w0.508: v2(158.51,116.22) 157.2,116.22 154.65,113.66 v2(154.65,112.73)
  IN2 w0.762: 154.15,66.36 149.35,66.36 148.82,66.89 148.13,66.89 143.94,71.08 143.94,72.12 140.28,75.78 140.28,79.28 141.71,80.71 141.71,82.21 140.78,83.13 v2(140.36,83.13)
  IN3 w0.508: v2(156.79,66) 156.79,64.5 156.3,64.01 v2(156.3,57.96) ; v2(154.65,112.73) 154.58,112.66 150.9,112.66 v2(148.23,109.99) ; v2(247.04,55.76) 247.04,54.94 244.46,52.36 241.51,52.36 240.45,51.31 231.4,51.31 228.26,54.44 226.53,54.44 225.41,55.56 224.99,55.56 224.62,55.93 v2(224.62,56.56) ; v2(236.94,84.46) 237.92,85.44 237.92,88.45 240.33,90.87 240.33,97.51 241.94,99.11 242.58,99.11 244.79,101.32 244.79,107.03 242.77,109.05 242.77,119.53 v2(240.69,121.61)
  BOTTOM w0.203: v2(108.73,127.31) 108.49,127.31 108.29,127.51 108.29,127.8 108.43,127.94 UV7.21 ; 118.51,132.28 118.51,131.84 118.22,131.54 UV7.51 ; UV7.5 115.51,126.78 115.8,126.49 115.93,126.49 116.21,126.21 116.25,126.21 v2(116.33,126.14) ; 107.21,132.14 107.81,132.15 108.42,131.54 UV7.30 ; UV7.57 118.39,129.14 v2(118.72,128.81)
  BOTTOM w0.254: RV93.2 RV95.2 RV85.2 ; RV85.2 RV91.2 ; RV85.2 119.7,128.76 118.78,128.76 v2(118.72,128.81) ; RC403.2 144.74,99.39 144.74,99.41 v2(144.77,99.41) ; RC345.2 134.5,108.47 134.16,108.47 133.91,108.72 v2(133.91,108.98) ; QC2.2 150.71,109.1 149.66,110.15 149.66,110.9 RC319.2 ; v2(55.75,130.92) JEDP1.10
  BOTTOM w0.305: JUSH1.19 224.45,57.07 224.62,56.89 v2(224.62,56.56) ; v2(78.95,125.47) 78.95,125.74 79.52,126.31 83.31,126.31 85.8,123.83 85.8,123.01 85.29,122.51 84.53,122.51 84.25,122.79 CC30.1 82.79,122.79 UC8.14 ; RC403.2 RC402.2
  BOTTOM w0.381: RC291.2 148.85,116.23 149.1,115.98 UC12.5 ; RC291.2 148.11,116.39 148.82,117.1 RC225.2 ; RC291.2 v2(147.37,116.23) ; RC267.2 139.24,97.62 RC237.2 139.99,97.74 RC292.2 ; 107.21,132.14 105.99,132.14 105.48,131.62 105.48,130.77 v2(105.48,130.76) ; 118.51,132.28 118.97,132.74 RV79.2 119.34,133.42 119.59,133.68 v2(119.59,133.91) ; RV19.2 21.68,91.39 v2(21.99,91.07) 22.31,91.39 RV20.2 ; v2(126.06,130.79) 126.06,131.25 125.75,131.56 125.75,133.24 125.4,133.59 123.34,133.59 123.02,133.91 v2(122.01,133.91) RV81.2 RV83.2 ; RC272.2 134.15,119.52 v2(134.59,119.52)
  BOTTOM w0.457: v2(21.94,89.16) 21.66,89.45 QV5.2 ; RC278.2 RC292.2 v2(139.99,99.64) ; RE48.1 240.24,122.06 v2(240.69,121.61) 240.24,121.17 RE51.1
  BOTTOM w0.508: v2(108.21,124.06) 108.35,124.21 RV89.2 ; v2(216.56,62.56) 216.56,59.3 213.92,56.67 210.62,56.67 209.76,55.81 209.76,54.66 210.49,53.94 213.97,53.94 v2(214.55,53.35) 215.44,52.46 216.94,52.46 218.26,51.14 221.53,51.14 224.62,54.24 v2(224.62,56.56) ; RC51.2 RC189.2 RC47.2 RC50.2 143.47,95.64 142.96,96.15 142.6,96.15 v2(142.55,96.2) ; v2(158.51,116.22) 158.8,116.51 160.06,116.51 160.56,116 RZ89.1 ; v2(154.65,112.73) 154.21,112.29 RZ362.1 ; RE67.2 236.26,84.62 236.42,84.46 v2(236.94,84.46) ; v2(67.92,83.53) 67.92,83.23 RD19.2 ; v2(55.38,125.82) 55.38,127.07 55.75,127.44 v2(55.75,130.92)
  vias: v2(26.63,51.38) v2(26.63,50.75) v2(27.27,51.38) v2(27.27,50.75) v2(27.9,51.38) v2(27.9,50.75) v2(34,97.95) v2(34,97.36) v2(36.03,68.54) v2(36.03,67.91) v2(36.03,67.27) v2(36.66,68.54) v2(36.66,67.91) v2(36.66,67.27) v2(148.23,109.36) v2(154.88,66.58) v2(154.89,66) v2(155.52,66.58) v2(155.52,66) v2(156.15,66.58) v2(156.16,66) v2(156.79,66.58) v2(267.51,76.21) v2(268.1,76.21) v4(156.4,67.27)
+3.3V_RUN_AUDIO: length 0.8
  TOP w0.127: 250.66,69.05 v4(250.66,69.81)
  vias: v2(248.94,67.64) v2(251.15,67.7) v2(261.49,67.6) v2(261.45,67)
+3.3V_RUN_AUDIO_DVDD: length 1.1
  TOP w0.127: v1(261.66,64.45) 261.71,64.5 LA14.1
+3.3V_RUN_AUDIO_IO: length 4.4
  TOP w0.203: CA55.1 256.33,64.49 UA1.9
  TOP w0.381: CA55.1 255.52,65.82 CA56.1
  TOP w0.508: CA56.1 254.42,66.11 LA12.1
+3.3V_RUN_CARD: length 7.2
  IN2 w1.016: 274.34,60.49 274.39,60.44 274.39,58.34 275.89,56.84 278.85,56.84
  vias: v2(275.08,61.91) v2(275.08,61.33) v2(279.73,56.72) v2(280.31,56.72) v4(279.08,56.55)
+3.3V_RUN_DIMM1: length 7.7
  TOP w0.254: RD10.2 145.46,57.86 v1(145.37,57.95) 145.19,57.95 144.4,58.75 143.55,58.75 CD27.1 143.42,59.6 CD28.1 143.38,60.06 v2(143.28,60.16)
  BOTTOM w0.254: JDIMM1.255 141.73,61.07 142.63,60.16 v2(143.28,60.16)
+3.3V_RUN_UZ3:
  vias: v4(155.47,62.8)
+3.3V_SPI: length 80.2
  TOP w0.508: RC30.2 RC31.2 161.72,94.51 v2(161.75,94.48) ; v2(145.36,97.46) 145.74,97.46 146.03,97.18 146.03,94.92 146.37,94.58 146.99,94.58 147.53,94.03 148.94,94.03 v4(149.59,94.69) v2(152.44,94.69) ; v2(151.47,101.29) 151.4,101.22 RC41.1
  IN2 w0.508: v2(161.75,94.48) 160.7,95.53 160.7,98.36 160.2,98.87 158.49,98.87 158.14,98.51 156.26,98.51 155.52,99.25 155.52,99.85 154.08,101.29 v2(151.47,101.29)
  IN3 w0.254: v2(145.36,97.46) 145.14,97.46 143.29,95.62 133.12,95.62 131.77,96.96 130.55,96.96 129.56,97.95 124.28,97.95 v2(123.94,98.29)
  IN3 w0.508: v2(152.44,94.69) 151.47,95.66 v2(151.47,101.29) ; v2(161.75,94.48) 161.69,94.42 161.69,90.74 162.23,90.21 v2(162.23,89.65)
  BOTTOM w0.254: UC1.AJ16 123.64,98.59 v2(123.94,98.29)
  BOTTOM w0.305: 167.22,94.11 166.92,94.41 JSPI1.6
  BOTTOM w0.381: UC6.8 152.64,101.23 CC9.1 151.81,101.83 151.47,101.48 v2(151.47,101.29) ; UC5.8 152,95.32 CC10.1 151.98,95.09 152.38,94.69 v2(152.44,94.69) ; v2(162.23,89.65) 162.94,90.36 165.79,90.36 167.22,91.79 167.22,94.11
+3.3V_TBTA_FLASH: length 78.2
  TOP w0.203: CT84.1 30.88,85.55 30.88,85.13 31.16,84.85 31.16,84.16 31.02,84.02 UT5.G1
  TOP w0.305: RT66.2 RT67.2 37.62,84.08 37.29,84.41 v2(36.55,84.41)
  TOP w0.381: RT53.1 27.98,73.28 27.96,73.29 27.96,73.34 ; RT52.1 RT50.1 29.23,70.48 CT70.1 ; CT70.1 27.99,69.56 RT51.1 ; CT70.1 v2(29.93,69.56) ; CT84.1 30.5,86.82 v2(30.5,87.96) 30.5,88.78 30.9,89.18 v4(31.49,89.18) RT378.2 RT379.2 ; 27.96,73.34 28.54,73.34 RT98.2 ; 27.96,73.34 v2(27.96,73.37) ; RT95.2 v2(27.19,86.62)
  IN1 w0.254: v2(27.19,86.62) 29.42,86.62 30.5,87.7 v2(30.5,87.96)
  IN2 w0.508: 29.49,72.65 29.55,72.59 30.31,72.59 31.14,73.42 33.58,73.42 35.3,75.14 35.3,83.6 36.12,84.41 v2(36.55,84.41) 36.55,86.02 35.86,86.7 27.27,86.7 v2(27.19,86.62) ; 29.49,72.65 28.78,73.37 v2(27.96,73.37) ; 29.49,72.65 29.49,70 v2(29.93,69.56)
  BOTTOM w0.254: RT107.2 33.74,82.95 33.74,88.16 32.85,89.05 30.83,89.05 30.31,88.53 ; 30.31,88.53 29.55,88.53 29.28,88.26 29.28,87.53 29.55,87.26 RT106.2 ; 30.31,88.53 30.5,88.34 v2(30.5,87.96) ; RT76.2 26.54,83.53 26.54,86.17 27,86.62 v2(27.19,86.62)
  BOTTOM w0.305: 31.14,68.59 30.38,67.83 JDB1.1
  BOTTOM w0.508: UT6.8 30.9,68.59 v2(29.93,69.56)
+3.3V_TP: length 19.7
  TOP w0.381: RZ116.1 214.08,54.95 RZ20.1 v2(213.45,54.94) 213.16,54.65 v4(211.92,54.65) 208.09,54.65 207.86,54.87 207.86,56.08 ; v2(215.72,53.33) 215.72,53.66 216.76,54.7 RZ21.1 216.75,54.95 RZ117.1
  TOP w0.508: v2(212.22,57.8) 212.22,58.47 RZ19.1
  IN3 w0.508: v2(209.8,57.8) 209.8,58.02 210.27,58.49 211.82,58.49 212.22,58.1 v2(212.22,57.8)
  BOTTOM w0.305: JKBTP1.9 210.05,58.44 209.8,58.19 v2(209.8,57.8)
  BOTTOM w0.381: v2(213.45,54.94) 214.13,54.94 215.72,53.35 v2(215.72,53.33)
+3.3V_TSP: length 6.1
  TOP w0.508: QV8.1 49.17,126.95 v4(50.42,128.2) 50.89,128.66 50.89,129.54 CV19.1 CV18.1
  BOTTOM w0.254: JEDP1.1 51.25,131.88 v2(51.08,131.71)
+3.3V_VCCHDA: length 18.9
  TOP w0.127: v2(122.01,98.24) 121.65,97.88 v4(121.65,97.76)
  TOP w0.254: LC1.2 137.89,97.43 CC324.1 137.02,97.39 136.29,97.39 136.27,97.37 v2(135.74,97.37) ; CC313.1 122.55,98.89 122.01,98.35 v2(122.01,98.24)
  IN2 w0.254: v2(135.74,97.37) 131.61,97.37 130.99,97.99 124.28,97.99 124.03,97.74 122.36,97.74 122.01,98.09 v2(122.01,98.24)
  BOTTOM w0.254: UC1.AJ19 v2(122.01,98.24)
+3.3V_VDD_DCIN: length 104.6
  TOP w0.508: 55.19,116.42 PC9.1 PR17.1 ; 55.19,116.42 54.25,117.36 v2(54.25,118.61) ; 55.19,116.42 55.22,116.44 v4(57.17,116.44) 58.29,116.44 58.81,116.96 62.23,116.96 62.85,117.57 v2(63.59,117.57) ; v2(38.76,56.91) 38.75,56.89 PR1206.1 PR1208.1
  IN2 w0.508: v2(46.61,96.78) 46.61,97.37 45.69,98.28 45.41,98.28 44.88,98.82 44.88,106.59 46.76,108.47 46.76,111.72 48.01,112.97 48.01,118.25 49.38,119.62 53.25,119.62 v2(54.25,118.61)
  IN3 w0.508: v2(46.61,96.78) 46.95,96.78 47.31,96.43 47.31,92.76 46.06,91.51 46.06,89.42 43.39,86.75 43.39,82.5 40.37,79.48 40.37,77.82 38.67,76.12 38.67,64.44 39.71,63.4 39.71,57.86 v2(38.76,56.91)
  BOTTOM w0.381: PU1.5 54.11,121.18 54.54,120.75 54.54,119.43 54.25,119.14 v2(54.25,118.61) 54.51,118.61 55.19,117.93 56.36,117.93 56.78,118.35 PR27.2
  BOTTOM w0.508: PU2.3 64.2,118.02 63.98,118.24 PC10.1 v2(63.59,117.57) ; PD1801.3 39.45,57.29 39.08,56.91 v2(38.76,56.91)
+3.3V_VDD_PIC: length 105.5
  TOP w0.254: v2(31.85,125.33) PR1236.2 ; PR1240.1 PR1254.2 34.25,58.5 35.11,59.36 v4(35.47,59.36) 37.77,59.36 v2(38.12,59) 38.12,58.56 37.5,57.94 PR1237.1 ; PR1253.1 v2(45.57,99.26)
  IN1 w0.254: v2(38.12,59) 38.12,59.51 37.3,60.34 36.47,60.34 35.77,61.03 35.77,62.49 35.27,63 v2(34.82,63)
  IN1 w1.016: 33.96,64.39 33.96,70.28 38.16,74.48 38.16,76.52
  IN2 w0.254: v2(31.85,125.33) 30.22,125.33 28.34,123.45 28.34,115.15 26.64,113.45 v2(26.64,112.49)
  IN2 w1.016: 26.54,65.72 31.24,65.72 33.62,63.35
  BOTTOM w0.254: v2(39.35,93.36) 41.88,95.89 41.88,98.04 43.1,99.26 43.14,99.26 ; PD1801.2 39.41,59 v2(38.12,59) ; QT1.2 40.9,81.04 41.1,80.84 41.1,79.25 39.25,77.4 37.87,77.4 v2(37.83,77.37) ; PC1204.1 34.48,63.7 v2(34.45,63.68) ; PC1204.1 35.06,64.17 34.49,64.74 34.49,65.29 34.76,65.56 36.42,65.56 36.84,65.14 PR1226.1 ; PC1204.1 35.33,63.43 35.33,62.88 PU1200.5 ; 43.14,99.26 v2(45.57,99.26) ; 43.14,99.26 42.51,99.9 42.51,102 PR1214.1 40.52,101.95 38.29,101.95 36.35,103.9 36.35,107.03 34.72,108.66 28.54,108.66 26.64,110.55 v2(26.64,112.49)
  BOTTOM w0.381: QT1.5 QT1.2
  vias: v2(25.69,65.75) v2(25.69,65.14) v2(35.42,88.9) v2(35.71,89.42) v2(37.83,77.98) v2(39.35,92.73)
+3.3V_VDD_PIC_PDA: length 10.4
  TOP w0.203: UT5.B1 33.52,83.7 34.46,84.64 34.46,85.1 v2(35,85.63) ; v2(30.43,84.59) 30.52,84.5 UT5.H1
  TOP w0.508: CT74.1 35.48,86.12 v2(35,85.63)
  IN2 w0.381: v2(35,85.63) 33.32,83.96 31.06,83.96 v2(30.43,84.59)
+3.3V_WLAN: length 19.4
  BOTTOM w2.032: 242.37,100.44 241.35,99.43 241.35,93.64 240.51,92.8 240.51,85.38 240.87,85.02 240.87,81.93
  vias: v2(241.63,61.73) v2(242.21,62.37) v2(242.21,61.73) v2(242.29,80.82) v2(242.29,80.24) v2(242.29,79.63) v2(243.57,102.22) v2(243.57,101.59) v2(244.21,102.22) v2(244.21,101.59) v4(243.02,102.07) v4(243.42,105.33) v4(248.36,105.22)
+3.3V_WLAN_UZ2: length 1.9
  TOP w0.102: 248.52,108.77 246.85,108.77 v1(246.71,108.63)
+3.3V_WWAN: length 7.2
  BOTTOM w2.54: 273.63,97.62 270.86,100.39 270.86,103.63
  vias: v2(236.76,94.95) v2(236.76,94.35) v2(236.76,93.76) v2(237.7,112.47) v2(238.09,112.91) v2(238.34,108.34) v2(238.34,107.71) v2(238.47,112.47) v2(238.66,108.85) v2(239.04,108.34) v2(239.04,107.71) v2(275.04,97.17) v2(275.04,96.53) v2(275.04,95.9) v2(275.04,95.26) v2(275.04,94.63) v4(237.51,102.78)
+3.3V_WWAN_UZ4: length 2.2
  TOP w0.127: 275.65,92.75 273.8,92.75 v4(273.57,92.52)
+5V_ALW: length 327.9
  TOP w0.203: v2(243.82,63.61) 243.83,63.6 244.57,63.6 244.81,63.83 UZ5.4 ; v2(253.21,111.47) 252.94,111.2 UZ2.4 ; v2(159.41,60.04) 159.29,60.04 159,60.34 UZ3.4 ; UZ4.4 279.49,90.94 279.55,91.01 280.11,91.01 280.44,90.68 280.44,90.12
  TOP w0.254: v2(200.75,54.21) v4(201.85,53.12) 201.85,52.53 203.61,50.76 205.54,50.76 205.66,50.89 UZ8.4
  TOP w0.305: v2(127.09,131.46) v4(126.22,131.46) 125.12,131.46 124.61,130.95 124.61,129.68 123.95,129.02 122.73,129.02 122.44,128.73 UZ19.3 ; v2(127.21,129.44) 127.21,129.16 126.83,128.78 UZ21.3 ; UZ26.3 137.19,66.3 137.44,66.05 137.69,66.05 138.11,65.63
  TOP w0.381: v2(225.26,56.59) 225.28,56.56 CZ64.1 225.28,55.56 CZ69.1 ; v2(44.19,90.87) 43.89,91.17 43.41,91.17 42.9,91.68 42.9,95.96 43.53,96.59 PR602.2 ; v2(33.04,125.33) 33.04,125.77 33.48,126.2 PR7.1
  TOP w0.457: v2(62.94,114.63) 62.94,114.64 62.69,114.9 PC685.1
  TOP w0.508: v2(143.2,64.12) 142.57,64.76 v4(141.54,64.76) 139.46,64.76 138.58,65.63 138.11,65.63 ; PC677.1 60.15,94.99 v2(60.22,95.07) ; LED3.2 v2(294.47,127.59) ; v2(248.5,58.18) RA53.2
  IN1 w0.508: v2(44.19,90.87) 45.13,90.87 46.28,92.01 52.07,92.01 52.45,91.63 v2(52.45,91.27) ; v2(159.41,60.04) 159.07,60.04 158.16,60.95 152.62,60.95 152.45,61.12 147.1,61.12 144.11,64.12 v2(143.2,64.12) ; v2(60.67,111.01) 61.77,112.11 61.77,113.96 62.44,114.63 v2(62.94,114.63)
  IN2 w0.508: 255.88,111.05 255.88,113.86 253.06,116.67 253.06,124.65 256.51,128.1 282.59,128.1 283.55,127.14 283.55,119.9 283.91,119.54 291.01,119.54 294.47,123.01 v2(294.47,127.59) ; 255.88,111.05 253.63,111.05 v2(253.21,111.47) ; 255.88,111.05 255.88,110.43 257.95,108.35 261.54,108.35 263.98,105.92 267.42,105.92 274.09,99.25 275.98,99.25 277.52,97.71 277.52,89.99 v2(278.34,89.16) ; v2(43.27,63.64) 43.27,63.96 39.8,67.42 39.8,75.64 43.56,79.4 43.56,88.7 44.19,89.33 v2(44.19,90.87) ; v2(60.67,111.01) 59.71,110.06 59.71,107.83 60.29,107.26 60.29,102.67 60.22,102.6 v2(60.22,95.07) 59.65,95.07 58.63,94.05 58.63,86.84 59.21,86.27 59.21,83.7 57.19,81.68 57.19,79.8 59.28,77.7 59.28,70.29 59.33,70.24 59.33,64.53 59.9,63.96 v2(62.38,63.96) ; v2(279.04,53.1) 278.64,52.69 278.64,31.1 285.98,23.76 285.98,10.48 287.04,9.41 v2(288.76,9.41)
  BOTTOM w0.203: PU610.2 59.29,109.92 59.68,110.31 ; v2(60.22,95.07) 60.5,94.8 PU612.2
  BOTTOM w0.254: PU614.6 62.87,114.56 v2(62.94,114.63)
  BOTTOM w0.305: v2(225.26,56.59) 225.26,56.95 224.95,57.25 JUSH1.18
  BOTTOM w0.508: 59.68,110.31 PC661.1 60.15,110.48 60.67,111 v2(60.67,111.01) ; JLED1.1 289.03,8.51 288.76,8.77 v2(288.76,9.41) ; DT1.2 v2(22.95,69.16) ; JUART1.1 v2(128.81,133.23)
  vias: v2(18.25,52.65) v2(18.25,52.02) v2(18.88,52.65) v2(18.88,52.02) v2(20.41,76.85) v2(20.41,76.21) v2(20.41,75.58) v2(21.04,76.85) v2(21.04,76.21) v2(21.04,75.58) v2(73.05,134.5) v2(73.68,134.5) v2(74.32,134.5) v2(85.24,135.39) v2(85.88,135.39) v2(86.51,135.39) v2(146.84,128.85) v2(146.84,128.22) v2(162.3,127.15) v2(162.28,126.55) v2(200.15,57.14) v2(200.15,56.55) v2(200.15,55.97) v2(200.15,55.38) v2(200.15,54.8) v2(200.16,54.21) v2(200.73,56.55) v2(200.73,55.97) v2(200.73,55.38) v2(200.73,54.8) v2(201.32,54.47) v2(275.18,74.53) v2(276.19,79.61) v2(276.82,79.61) v2(277.46,79.61) v2(278.09,79.61) v2(279.49,89.23) v2(279.49,88.59) v2(280.12,89.55) v2(280.12,88.91)
+5V_ALW2: length 2.9
  TOP w0.102: v2(185.96,58.04) v4(185.96,58.61)
  TOP w0.254: v2(185.96,58.04) 185.44,58.04 185.13,57.73 PC126.1
  BOTTOM w0.254: PU102.15 185.84,57.91 v2(185.96,58.04)
+5V_ALW_PDA: length 5
  TOP w0.203: v2(30.05,79.51) 30.52,79.04 UT5.H10
  IN1 w0.508: v2(33.51,77.47) 33.5,77.47 32.54,78.43 31.13,78.43 v2(30.05,79.51)
  vias: v2(33.51,76.83) v2(33.51,76.2) v2(34.15,77.47) v2(34.15,76.83) v2(34.15,76.2) v4(34.1,74.8)
+5V_ALWP: length 37.7
  BOTTOM w0.254: 198.86,57.72 199.34,57.72 199.95,58.33 199.95,60.67 199.16,61.45 189.2,61.45 187.58,59.83 186.68,59.83 PR117.2 ; PC120.1 199.17,58.34 199.49,58.66 199.49,60.49 198.98,61 189.6,61 187.11,58.51 185.65,58.51 185.39,58.25 PU102.14
  vias: v2(197.14,56.38) v2(197.14,55.79) v2(197.14,55.21) v2(197.14,54.63) v2(197.73,56.38) v2(197.73,55.79) v2(197.73,55.21) v2(197.73,54.63) v2(198.31,56.38) v2(198.31,55.79) v2(198.31,55.21) v2(198.31,54.63) v4(196.29,54.6)
+5V_PD_VDD: length 6.6
  TOP w0.127: RT393.1 21.09,70.7 v4(21.17,70.78)
  BOTTOM w0.508: v2(20.51,69.16) DT1.1 ; DT1.1 19.33,68.62 19.97,67.99 UT7.1 ; DT1.1 DT2.1
+5V_RUN: length 116.1
  TOP w0.381: v2(206.55,57.8) 206.5,57.85 CZ92.1 ; v2(223.99,56.59) 223.8,56.59 223.45,56.25 CZ66.1 223.45,55.5 CZ71.1
  IN1 w0.508: v2(223.99,56.59) 223.99,55.19 224.79,54.39 232.96,54.39 236.05,57.48 239.36,57.48 240.31,58.43 v2(240.31,60.51) v2(240.89,60.51) v2(241.48,60.51) v2(242.11,60.51)
  IN2 w1.016: 239.61,117.36 240.99,115.97 240.99,113.31 244.05,110.25 246.62,110.25 248.75,108.11 255.91,108.11 257.17,106.85 260.87,106.85 263.9,103.83 265.17,103.83 273.4,95.59 273.4,90.12 ; 33.68,65.23 32.03,66.88 25.49,66.88 25.17,67.19 ; 17.65,72.48 17.65,72.48 17.65,73.24 16.35,74.55 14.82,74.55 14.11,75.27 14.11,79.55 16.9,82.35 16.9,90.34
  IN3 w1.016: 22.31,68.4 21.8,68.91 21.8,70.37 20.85,71.32 18.38,71.32
  BOTTOM w0.305: JUSH1.20 223.95,56.63 v2(223.99,56.59) ; JKBTP1.16 v2(206.55,57.8)
  vias: v2(17.51,71.64) v2(17.5,71.06) v2(18.31,91.35) v2(18.31,90.75) v2(23.14,68.15) v2(23.77,68.15) v2(34.95,65.1) v2(35.58,65.1) v2(238.34,118.06) v2(239.04,118.06) v2(273.9,86.75) v2(273.9,86.12) v2(274.47,87.07) v2(274.47,86.43) v2(274.47,85.8) v2(274.47,85.16) v4(243.76,61.89)
+5V_RUN_AUDIO:
  vias: v2(247.52,59.68) v2(247.52,59.09) v2(247.52,58.52) v2(247.52,57.95) v2(264.21,65.34) v2(264.21,64.53) v2(264.62,64.93) v2(265.05,65.31) v4(248.46,55.92)
+5V_RUN_AUDIO_UZ5:
  vias: v1(247.69,61.57)
+5V_RUN_PVDD_L:
  vias: v1(261.5,59.51) v2(264.44,63.05) v2(264.36,59.6) v2(264.36,59.02) v2(265.81,63.05)
+5V_RUN_UZ4:
  vias: v4(278.06,88.44)
+5V_TBT_VBUS: length 4.3
  TOP w0.127: v2(22.75,72.41) v4(23.43,72.41)
  BOTTOM w0.254: DT2.2 DT3.1 22.44,72.72 v2(22.75,72.41) 23.15,72.01 CT93.1
+5V_TBTA_VBUS_D: length 4
  BOTTOM w0.127: DT3.2 v1(19.33,74.19)
  BOTTOM w0.254: UT8.3 17.99,72.49 18.22,72.72 DT3.2
+5V_USB_CHG_PWR:
  vias: v2(278.03,73.16) v2(278.66,73.16) v2(280.38,72.85) v2(281.01,72.85) v2(282.28,74.31) v2(282.28,73.67) v4(279.54,72.53)
+DV33_18:
  vias: v1(278.42,62.99)
+GND_CHASSIS: length 16.2
  TOP w0.508: RL15.2 RL16.2 268.87,120.05 v4(265.96,120.05) RL17.2 RL18.2 v2(261.26,121.02)
  IN1 w0.508: v2(261.26,121.02) v2(257.22,121.02)
  BOTTOM w0.508: CL22.2 256.47,120.26 v2(257.22,121.02)
+VBUS_DC_SS: length 63.9
  IN2 w0.508: v2(45.43,61.61) 46.95,63.13 56.36,63.13 58.11,64.88 58.11,69.51 57.06,70.56 56.35,70.56 54.99,71.92 54.99,83.8 57.3,86.11 57.3,94.61 58.3,95.62 58.3,97.89 57.55,98.64 57.55,102.28 v2(57.27,102.56)
  BOTTOM w0.508: v2(57.27,102.56) 56.88,102.17 53.76,102.17 v1(53.24,102.69) v2(52.67,103.26) ; v2(45.43,61.61) 45.43,60.34 46.51,59.26 PD903.2
  vias: v2(52.06,105.8) v2(52.06,105.17) v2(52.06,104.53) v2(52.06,103.9) v2(52.06,103.26) v2(52.67,105.8) v2(52.67,105.17) v2(52.67,104.53) v2(52.67,103.9)
+VCC1V8A_TBTA_LDO: length 2.5
  TOP w0.076: 28.15,84.53 28.09,84.59
  TOP w0.203: 28.15,84.53 28.21,84.53 28.47,84.26 28.73,84.26 UT5.K1
  TOP w0.508: CT73.1 27.85,84.83 28.09,84.59
+VCC1V8D_TBTA_LDO: length 14.3
  TOP w0.203: v2(34.49,83.15) 34.19,83.15 UT5.A2
  TOP w0.381: RT97.1 32.15,73.29 v1(32.61,73.74) 35.1,76.24 35.1,77.73 34.71,78.13 v2(34.49,78.13) ; CT72.1 35.3,83.15 v2(34.49,83.15)
  BOTTOM w0.381: v2(34.49,78.13) 34.72,78.13 35.1,78.51 35.1,82.54 v2(34.49,83.15)
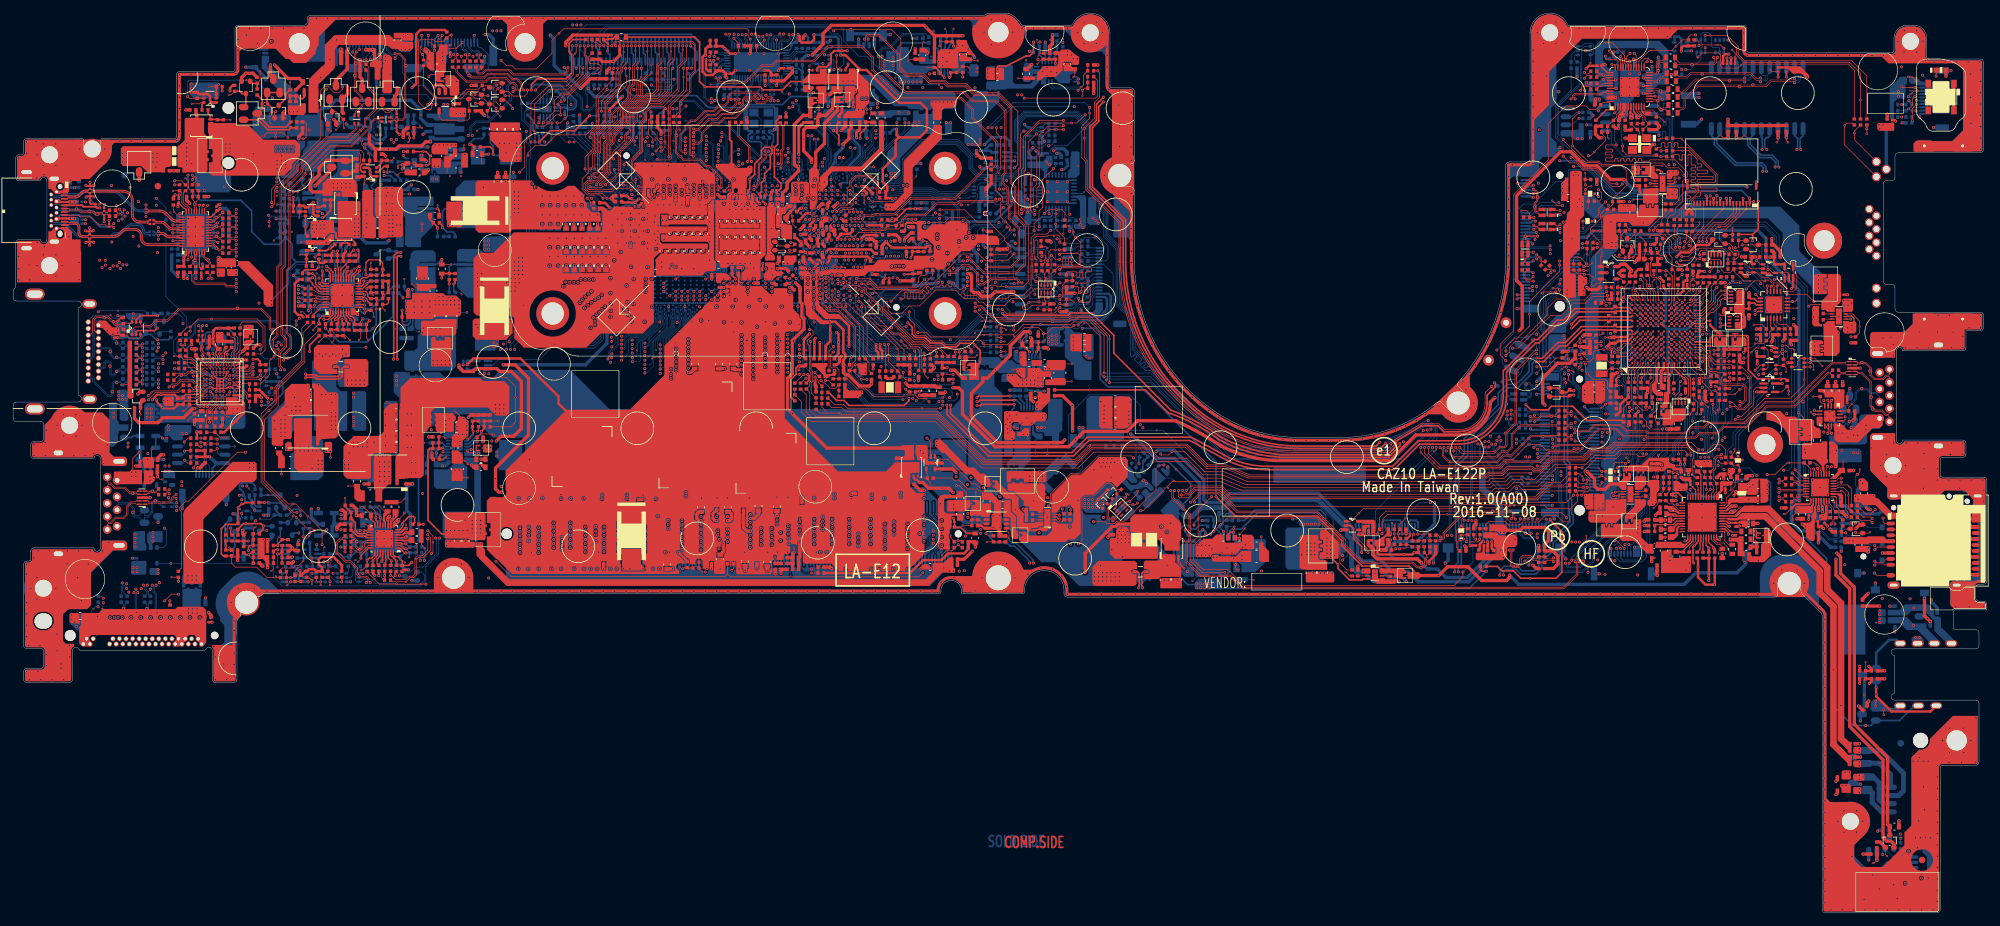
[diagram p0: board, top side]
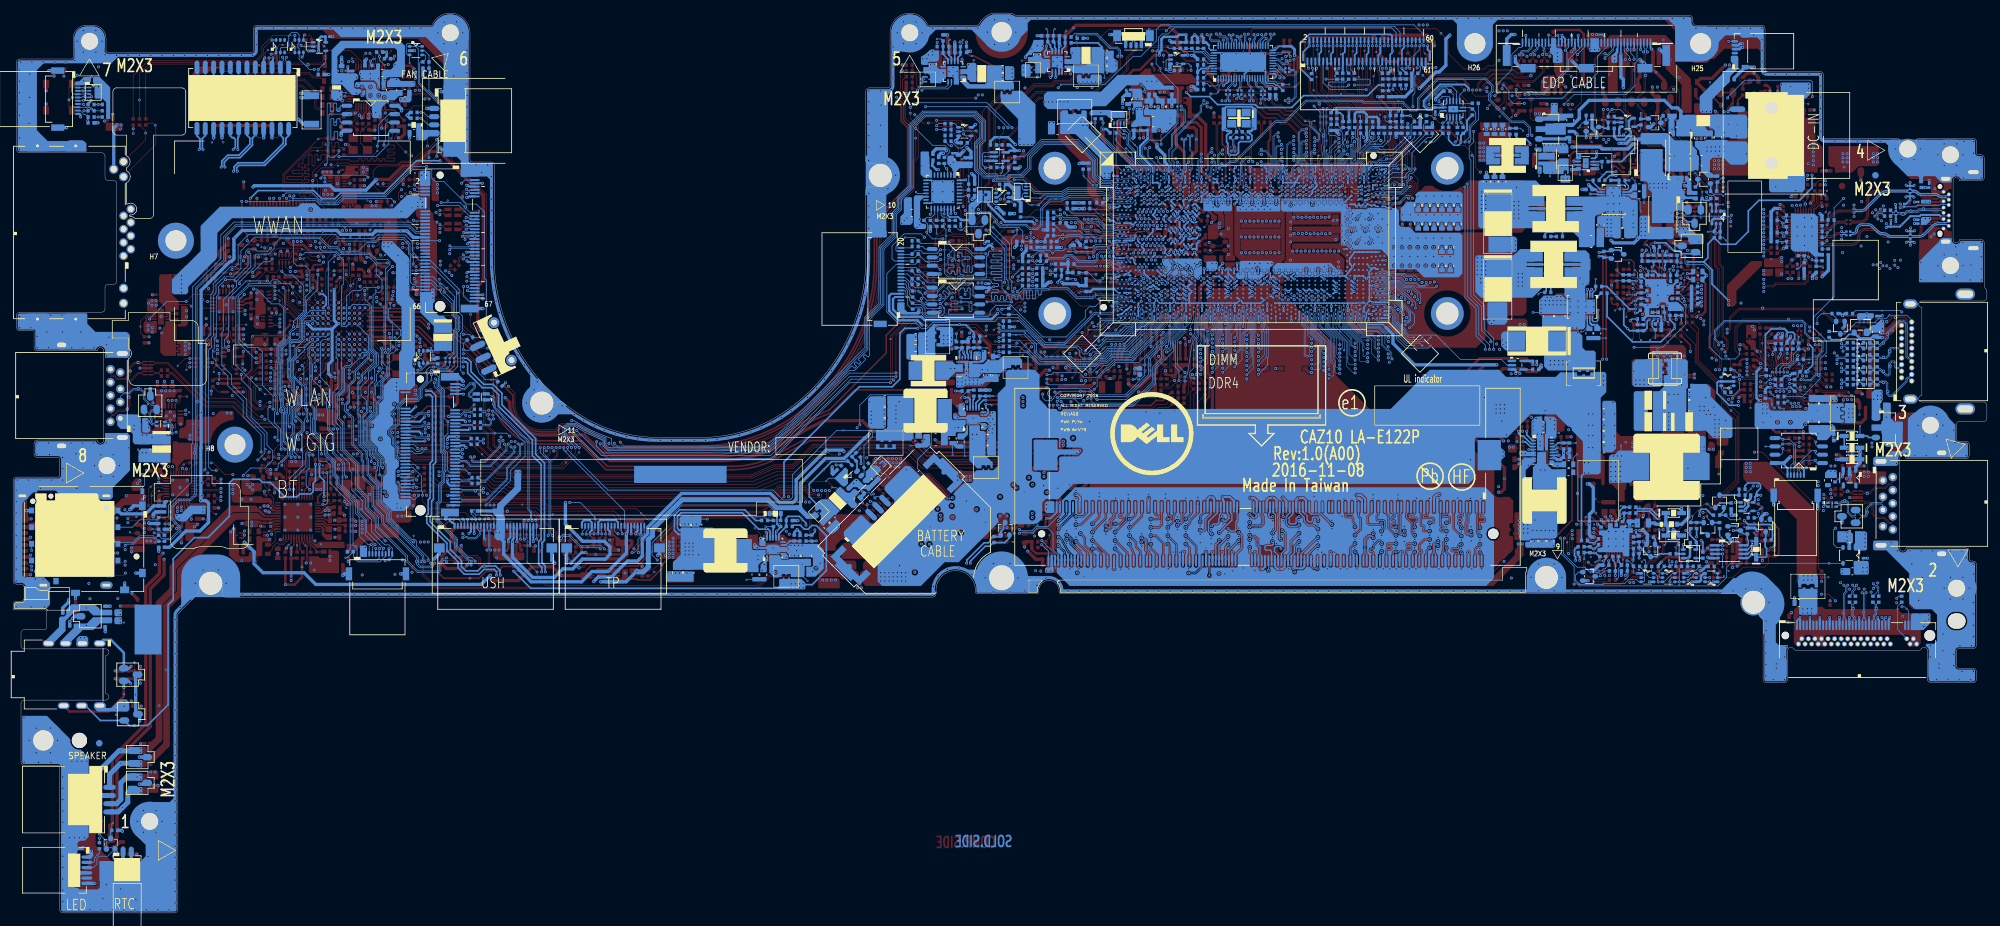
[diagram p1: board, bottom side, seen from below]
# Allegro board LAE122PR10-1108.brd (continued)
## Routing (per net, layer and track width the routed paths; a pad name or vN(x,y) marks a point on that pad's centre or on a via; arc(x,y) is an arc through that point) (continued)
+VCC_1P8: length 23.6
  TOP w0.127: v4(139.27,102.2) 138.99,102.47 v2(138.63,102.47)
  TOP w0.457: CC222.1 126.71,104.15 126.34,104.52 v2(126.34,104.81)
  IN3 w0.254: 131.23,104.36 126.64,104.36 126.34,104.66 v2(126.34,104.81) 126.34,105.01 126.67,105.34 131.18,105.34 131.47,105.05 131.47,104.6 131.23,104.36
  IN3 w0.508: 131.47,104.85 135.39,104.85 136.83,103.41 137.7,103.41 v2(138.63,102.47)
  BOTTOM w0.254: UC1.U12 UC1.U11 126.43,104.72 v2(126.34,104.81)
  BOTTOM w0.508: RC313.2 138.12,101.97 v2(138.63,102.47)
+VCC_CORE: length 47.9
  TOP w0.305: v2(114.69,109.62) 114.68,109.62 114.49,109.43 PC1050.1 ; RC140.2 109.17,117.92 109.45,117.64 109.45,114.26 v2(109.98,113.73)
  BOTTOM w0.127: UC1.K42 108.72,108.69 108.67,108.74 ; UC1.K42 108.72,107.98 ; UC1.K42 109.03,108.36 ; UC1.K37 111.16,108.36 ; UC1.K37 111.47,108.66 ; UC1.K37 111.47,108.02 ; UC1.AL40 110.42,97.53 110.42,97.53 ; UC1.AL40 109.77,97.53 109.77,97.53 ; UC1.AL40 110.09,97.88 ; UC1.AL40 110.09,97.2 ; 113.29,108.69 UC1.K33 ; UC1.K33 113.29,107.92 ; UC1.K33 112.99,108.36 ; UC1.J37 111.01,108.52 ; UC1.J37 110.68,108.83 ; UC1.J37 111.31,108.83 ; UC1.J37 111.01,109.16 ; 113.41,97.53 UC1.AL33 ; UC1.AL33 113.75,97.87 ; UC1.AL33 114.06,97.53 ; UC1.AL33 113.75,97.2 ; UC1.AK35 112.69,97.99 ; UC1.AK35 112.38,98.34 ; UC1.AK35 112.04,97.99 ; UC1.AK35 112.38,97.66 ; 109.18,109.16 UC1.J40 ; UC1.J40 108.86,108.83 ; UC1.J40 109.49,108.83 ; UC1.J40 109.18,108.52 ; UC1.K38 110.86,108.36 ; UC1.K38 110.55,108.68 ; UC1.K38 110.55,108 ; UC1.AK40 109.64,97.64 ; UC1.AK40 109.95,97.99 ; UC1.AK40 109.64,98.37 ; UC1.AK40 109.33,97.99 ; 111.47,97.63 111.47,97.64 UC1.AK37 ; 111.52,98.32 111.52,98.05 UC1.AK37 ; 107.81,108.69 UC1.K43 107.81,107.95 107.81,107.94 ; 112.84,108.5 UC1.J33 ; UC1.J33 113.14,108.83 ; UC1.J33 112.84,109.13 ; UC1.J33 112.49,108.83 ; UC1.AK33 112.99,97.99 ; UC1.AK33 113.29,97.63 ; UC1.AK33 113.29,98.34 ; UC1.AK33 113.63,97.99 ; UC1.AL37 111.6,97.53 111.6,97.53 ; UC1.AL37 111.92,97.18 111.93,97.17 ; UC1.AL37 111.92,97.83 111.93,97.83 ; UC1.AL37 112.23,97.53 ; UC1.AK38 110.55,97.65 110.55,97.65 ; UC1.AK38 110.55,98.4 ; UC1.AK38 110.23,97.99 ; 109.64,107.97 UC1.K40 ; UC1.K40 109.33,108.36 ; UC1.K40 109.64,108.68 ; 114.36,108.83 UC1.J30 114.67,109.12 ; UC1.AK37 111.5,97.96 111.85,97.96 ; 112.38,107.97 UC1.K35 ; UC1.K35 112.69,108.36 ; UC1.K35 112.38,108.69
  BOTTOM w0.203: UC1.A30 114.7,113.45 v2(114.45,113.7) ; v2(109.98,113.73) 109.74,113.49 UC1.A39 ; v2(112.22,113.7) UC1.A34 ; UC1.A44 107.26,113.96 v2(107.29,113.96)
  BOTTOM w0.254: UC1.G37 111.22,109.54 v2(111,109.54) 110.8,109.54 UC1.G38 ; UC1.G32 114.54,109.62 v2(114.69,109.62) 114.79,109.62 UC1.G30 ; UC1.G35 112.59,109.5 v2(112.83,109.5) 113.09,109.5 UC1.G33 ; UC1.G42 108.97,109.54 v2(109.17,109.54) 109.39,109.54 UC1.G40 ; UC1.AM35 v2(111.92,96.66) UC1.AM37 v2(111.01,96.66) UC1.AM38
  BOTTOM w0.508: PC1173.1 v2(85.43,109.29) ; PC1006.1 v2(83.02,106.44) ; PC1013.1 v2(84.22,106.44) ; PC1072.1 v2(85.43,106.44) ; PC1009.1 v2(83.02,109.29) ; PC1172.1 v2(84.22,109.29) ; PC1010.1 v2(81.81,109.29) ; PC1075.1 v2(86.64,106.44) ; PC1174.1 v2(86.64,109.29) ; PC1071.1 v2(80.61,109.29) ; PC1069.1 v2(80.61,106.44) ; PC1070.1 v2(81.81,106.44)
  vias: v2(71.33,108.47) v2(71.33,107.83) v2(71.33,107.2) v2(71.33,106.56) v2(71.33,105.93) v2(72.03,108.47) v2(72.03,107.83) v2(72.03,107.2) v2(72.03,106.56) v2(72.03,105.93) v2(73.81,111.52) v2(75.02,111.52) v2(75.14,106.75) v2(75.14,106.12) v2(75.75,106.75) v2(75.75,106.12) v2(76.22,111.52) v2(76.35,109.93) v2(76.35,109.29) v2(76.35,108.66) v2(76.35,108.02) v2(76.35,107.39) v2(76.35,106.75) v2(76.99,109.93) v2(76.99,109.29) v2(76.99,108.66) v2(76.99,108.02) v2(76.99,107.39) v2(76.99,106.75) v2(87.84,106.44) v2(89.05,106.44) v2(108.48,105.48) v2(108.48,103.07) v2(108.48,100.66) v2(108.91,99.02) v2(109.18,108.14) v2(109.18,107.28) v2(109.55,99.02) v2(109.62,107.71) v2(109.75,105.48) v2(109.75,103.07) v2(109.75,100.66) v2(110.09,107.28) v2(110.54,107.71) v2(110.77,99.02) v2(111.01,108.14) v2(111.01,107.28) v2(111.02,105.48) v2(111.02,103.07) v2(111.02,100.66) v2(111.45,107.71) v2(111.5,99.02) v2(111.92,107.28) v2(111.91,98.32) v2(112.29,105.48) v2(112.29,103.07) v2(112.29,100.66) v2(112.34,99.02) v2(112.39,107.71) v2(112.84,108.14) v2(112.84,98.32) v2(112.85,107.28) v2(113.31,107.71) v2(113.56,105.48) v2(113.56,103.07) v2(113.56,100.66) v2(113.77,107.28) v4(71.65,110.64)
+VCC_CORE_G0: length 1.2
  TOP w0.254: v2(114.62,108.07) 114.22,108.47 T122.1
  BOTTOM w0.254: UC1.K32 114.33,108.36 v2(114.62,108.07)
+VCC_CORE_G1: length 2.2
  TOP w0.254: T123.1 114.11,98.35 114.22,98.46 v2(114.22,99.05)
  BOTTOM w0.254: v2(114.22,99.05) 114.22,98.84 114.21,98.83 UC1.AK32
+VCC_GT: length 34.3
  BOTTOM w0.127: UC1.J50 104.05,108.83 104.05,108.83 ; UC1.J50 103.69,108.52 ; UC1.J50 103.35,108.83 ; UC1.K56 100.19,108.36 ; UC1.K56 100.49,108 ; UC1.K56 100.8,108.36 ; UC1.K56 100.49,108.7 ; UC1.J48 104.26,108.83 104.26,108.83 ; UC1.J48 104.61,108.52 ; UC1.J48 104.96,108.83 104.97,108.83 ; UC1.R63 96.68,105.34 ; UC1.R63 97.29,105.34 ; UC1.R63 96.99,105.02 ; UC1.R63 96.99,105.68 ; UC1.K58 99.58,107.99 ; UC1.K58 99.58,108.67 ; UC1.K58 99.27,108.36 ; UC1.K58 99.88,108.36 ; UC1.K53 102.32,108.06 ; UC1.K53 102.02,108.36 ; UC1.K53 102.32,108.7 ; 99.46,108.83 99.45,108.83 UC1.J58 ; 97.48,107.97 97.46,107.95 UC1.L62 97.84,107.62 ; UC1.J52 102.78,108.52 ; UC1.J52 103.14,108.83 ; UC1.J52 102.43,108.83 ; 97.17,106.71 UC1.M62 ; UC1.M62 97.46,107.02 ; UC1.M62 97.77,106.71 ; UC1.M62 97.46,106.44 ; 104.15,108.67 UC1.K50 ; UC1.K50 103.85,108.36 ; UC1.K50 104.15,108.05 ; UC1.K50 104.46,108.36 ; UC1.J58 98.79,108.83 98.76,108.8 ; UC1.J58 99.12,108.52 ; UC1.J55 101.32,108.83 ; UC1.J55 100.58,108.83 ; UC1.J55 100.95,108.52 ; 97.46,102.72 UC1.Y62 ; UC1.Y62 97.18,103.05 ; UC1.Y62 97.77,103.05 ; 98.66,108.01 UC1.K60 ; UC1.K60 98.36,108.36 ; UC1.K60 98.97,108.36 ; UC1.K60 98.66,108.67 ; 102.27,108.83 UC1.J53 ; UC1.J53 101.56,108.83 ; UC1.J53 101.86,108.52 ; 107.05,108.83 UC1.J43 107.35,108.46 ; 101.71,108.36 UC1.K55 ; UC1.K55 101.41,108.67 ; UC1.K55 101.1,108.36 ; UC1.K55 101.41,108.01 101.4,108.01 ; UC1.N63 96.69,106.25 ; UC1.N63 96.99,106.56 ; UC1.N63 96.99,105.91 ; UC1.N63 97.27,106.25 ; 104.76,108.36 UC1.K48 ; UC1.K48 105.07,108.63 ; UC1.K48 105.37,108.36 ; UC1.K48 105.07,107.99 ; UC1.J45 106.79,108.83 ; UC1.J45 106.44,108.52 ; UC1.J45 106.09,108.83 106.09,108.83 ; UC1.J46 105.15,108.83 105.15,108.83 ; UC1.J46 105.52,108.52 ; UC1.J46 105.9,108.83 105.91,108.83 ; 98.21,108.52 UC1.J60 98.55,108.83 ; UC1.T62 97.46,105.19 ; UC1.T62 97.17,104.88 ; UC1.T62 97.76,104.88 ; UC1.T62 97.46,104.59 ; UC1.K52 103.24,107.97 ; UC1.K52 103.24,108.7 ; UC1.K52 103.54,108.36 ; 96.99,107.46 UC1.L63 ; UC1.L63 97.31,107.17 ; UC1.L63 96.99,106.86 ; UC1.L63 96.68,107.17 ; 96.73,102.6 UC1.AA63 ; UC1.AA63 97.27,102.6 ; UC1.AA63 96.99,102.29 ; UC1.AA63 96.99,102.9 ; 97.27,103.51 UC1.W63 ; UC1.W63 96.99,103.21 ; UC1.W63 96.68,103.51 ; 100.37,108.83 UC1.J56 ; UC1.J56 100.04,108.52 ; UC1.J56 99.69,108.83 99.69,108.83
  BOTTOM w0.203: v2(94.87,113.98) UC1.A66 ; v2(97.35,113.92) UC1.A62 ; v2(104.93,113.47) 104.84,113.38 104.84,113.04 UC1.A48 ; v2(102.34,113.9) 102.28,113.85 102.28,113.02 UC1.A53 ; v2(99.83,113.93) UC1.A58
  vias: v2(70.76,97.48) v2(70.76,96.85) v2(70.76,96.21) v2(70.76,95.58) v2(71.4,97.48) v2(71.4,96.85) v2(71.4,96.21) v2(71.4,95.58) v2(75.21,96.72) v2(75.21,96.09) v2(75.21,95.45) v2(75.21,94.82) v2(75.84,96.72) v2(75.84,96.09) v2(75.84,95.45) v2(75.84,94.82) v2(76.35,99.26) v2(76.35,98.63) v2(76.35,97.99) v2(76.35,97.36) v2(76.48,96.72) v2(76.48,96.09) v2(76.48,95.45) v2(76.48,94.82) v2(76.99,99.9) v2(76.99,99.26) v2(76.99,98.63) v2(76.99,97.99) v2(76.99,97.36) v2(77.11,96.72) v2(77.11,96.09) v2(77.62,99.9) v2(77.62,99.26) v2(77.62,98.63) v2(77.62,97.99) v2(77.62,97.36) v2(81.75,102.88) v2(81.75,100.09) v2(83.02,102.88) v2(83.02,100.09) v2(84.29,102.88) v2(84.29,100.09) v2(85.49,102.88) v2(85.49,100.09) v2(86.7,102.88) v2(86.7,100.09) v2(87.91,102.88) v2(87.91,100.09) v2(89.11,102.88) v2(89.11,100.09) v2(90.32,102.88) v2(90.32,100.09) v2(92.11,105.8) v2(92.11,103.97) v2(92.11,102.14) v2(92.76,106.65) v2(92.76,104.88) v2(92.76,103.05) v2(93.41,105.8) v2(93.41,102.14) v2(94.06,106.65) v2(94.06,104.88) v2(94.06,103.97) v2(94.06,103.05) v2(94.71,105.8) v2(94.71,102.14) v2(95.36,106.65) v2(95.36,104.88) v2(95.36,103.05) v2(96.01,103.97) v2(96.64,106.65) v2(96.61,105.78) v2(96.64,102.15) v2(96.66,101.26) v2(97.72,105.34) v2(97.72,103.51) v2(97.81,106.24) v2(97.86,102.53) v2(98.14,101.99) v2(98.22,107.96) v2(98.24,103.97) v2(98.24,103.04) v2(98.27,104.85) v2(98.77,100.91) v2(99.13,107.96) v2(100.05,107.96) v2(100.04,100.91) v2(100.07,103.57) v2(100.22,106.09) v2(100.96,107.96) v2(101.34,103.57) v2(101.31,100.91) v2(101.39,106.06) v2(101.88,107.96) v2(102.51,103.57) v2(102.56,106.06) v2(102.58,100.91) v2(103.72,106.06) v2(103.67,103.6) v2(103.85,100.91) v2(104.62,107.96) v2(104.94,106.06) v2(104.89,103.57) v2(105.12,100.91) v2(105.48,107.96) v4(91.29,104.91)
+VCC_GTUS: length 27.7
  TOP w0.112: v2(100.96,98.51) 100.57,98.51 v4(100.34,98.74)
  BOTTOM w0.127: 102.88,97.05 UC1.AM52 ; UC1.AM52 103.24,97.37 ; UC1.AM52 103.58,97.05 ; 99.58,97.36 UC1.AM58 ; UC1.AM58 99.91,97.05 ; UC1.AM58 99.26,97.05 ; 102.78,97.2 UC1.AL53 ; UC1.AL53 103.07,97.53 ; UC1.AL53 102.43,97.53 ; UC1.AL53 102.78,97.86 ; UC1.AM56 100.14,97.05 ; UC1.AM56 100.49,97.38 ; UC1.AM56 100.87,97.05 ; UC1.AK53 102.32,98.31 ; UC1.AK53 102.65,97.99 ; UC1.AK53 102.32,97.66 ; 101.41,97.64 UC1.AK55 ; UC1.AK55 101.41,98.35 ; UC1.AK55 101.05,97.99 101.05,97.99 ; 107.81,98.31 UC1.AK43 ; UC1.AK43 108.14,97.99 ; UC1.AK43 107.81,97.66 ; UC1.AK43 107.44,97.99 ; 106.89,97.64 UC1.AK45 ; UC1.AK45 106.89,98.32 ; UC1.AK45 107.22,97.99 ; UC1.AK45 106.6,97.99 ; 104.15,97.65 UC1.AK50 ; UC1.AK50 104.15,98.32 ; UC1.AK50 104.51,97.99 ; UC1.AK56 100.86,97.99 100.86,97.99 ; UC1.AK56 100.49,97.7 ; UC1.AK56 100.49,98.4 ; 102.67,97.05 UC1.AM53 ; UC1.AM53 102.32,97.38 ; UC1.AM53 101.96,97.05 ; 104.5,97.05 UC1.AM50 ; UC1.AM50 104.15,97.41 ; UC1.AM50 103.79,97.05 ; UC1.AL60 99.12,97.86 ; UC1.AL60 99.48,97.53 ; UC1.AL60 98.8,97.53 ; UC1.AL60 99.12,97.2 ; 105.58,97.99 UC1.AK46 ; UC1.AK46 106.31,97.99 ; UC1.AK46 105.98,98.31 ; UC1.AK46 105.98,97.62 ; 108.72,98.34 UC1.AK42 ; UC1.AK42 108.42,97.99 ; UC1.AK42 108.72,97.72 ; UC1.AL43 108.27,97.88 ; UC1.AL43 108.52,97.53 ; UC1.AL43 107.92,97.53 ; UC1.AK52 103.24,97.65 ; UC1.AK52 102.87,97.99 ; UC1.AK52 103.24,98.3 ; 105.42,97.99 UC1.AK48 ; UC1.AK48 104.75,97.99 ; UC1.AK48 105.07,98.3 ; UC1.AK48 105.07,97.69 ; UC1.AM48 105.07,97.42 ; UC1.AM48 105.42,97.05 ; UC1.AM48 104.7,97.05 ; UC1.AL56 100.95,97.2 ; UC1.AL56 100.53,97.53 ; UC1.AL56 100.95,97.8 ; UC1.AL56 101.31,97.53 ; 104.95,97.53 UC1.AL50 ; UC1.AL50 104.61,97.18 ; UC1.AL50 104.61,97.86 ; UC1.AL50 104.28,97.53 ; 99.58,97.66 UC1.AK58 ; UC1.AK58 99.58,98.32 ; UC1.AK58 99.26,97.99 ; 98.37,97.99 UC1.AK60 ; UC1.AK60 98.66,97.62 ; UC1.AK60 98.99,97.99 ; 106.08,97.53 UC1.AL46 ; UC1.AL46 106.44,97.9 ; UC1.AL46 106.75,97.53
+VCC_SA: length 25.4
  TOP w0.254: PC1147.1 116.69,110.17 117.02,110.5 117.02,111.19 115.97,112.23 115.97,116.7 116.48,117.21 116.48,119.77 116.23,120.03 116.23,120.74 RC168.1
  TOP w0.381: PC1147.1 116.31,109.78 v2(116.52,109.57)
  BOTTOM w0.127: UC1.AK25 117.87,98.34 ; UC1.AK25 117.56,97.99 117.55,98 ; UC1.AK25 118.22,97.99 118.22,97.99 ; UC1.K23 119.09,108.36 ; UC1.K23 118.48,108.36 ; UC1.K23 118.78,108.06 ; UC1.K23 118.78,108.67 ; UC1.J27 116.8,108.83 ; UC1.J27 116.5,108.52 ; UC1.J27 116.19,108.83 ; 119.24,108.52 UC1.J22 118.93,108.83 ; 116.84,108.09 116.95,108.2 UC1.K27 ; UC1.K25 117.87,108.06 ; UC1.K25 118.17,108.36 ; UC1.K25 117.87,108.67 ; 115.12,108.67 UC1.K30 115.12,108.06 ; UC1.J23 118.02,108.83 ; UC1.J23 118.63,108.83 ; UC1.J23 118.32,108.52 ; UC1.K27 116.65,108.36 ; UC1.K27 116.95,108.67 ; 118.43,97.99 118.44,97.99 UC1.AK23 118.78,98.36 118.78,98.36 ; UC1.K28 116.34,108.36 ; UC1.K28 116.04,108.06 ; UC1.K28 116.04,108.67
  BOTTOM w0.203: UC1.G27 UC1.G25
  BOTTOM w0.254: UC1.G27 116.67,109.57 v2(116.52,109.57) 116.32,109.57 UC1.G28 ; UC1.G25 118.12,109.54 v2(118.3,109.54) 118.53,109.54 UC1.G23
  vias: v2(74.13,117.36) v2(74.83,117.36) v2(75.59,117.36) v2(76.66,117.37) v2(76.66,116.67) v2(76.66,116.04) v2(76.66,115.4) v2(76.66,114.77) v2(77.24,117.37) v2(77.24,116.67) v2(77.24,116.04) v2(77.24,115.4) v2(77.24,114.77) v2(116.5,108.14) v2(116.94,105.14) v2(116.94,104.51) v2(117.41,99.01) v2(117.87,107.64) v2(118.01,99.01) v4(75.09,115.89)
+VCC_SFR_OC: length 41.7
  TOP w0.508: 135.74,70.88 123.98,70.88 v4(118.71,76.15) 117.99,76.86 117.99,81.54 118.71,82.26 118.71,87.26 120.48,89.04 120.48,90.63 120.17,90.94 120.17,92.9 119.89,93.18 CC288.1 119.89,95.39 v2(119.2,96.07)
  BOTTOM w0.254: v2(119.24,98.22) UC1.AL23
+VDDA_AVDD1: length 1.3
  TOP w0.203: 254.93,56.21 255.53,56.81 UA1.26
  vias: v1(253.8,56.2)
+VSS_PLL:
  vias: v1(251.09,82.41)
GND: length 2614.3
  TOP w0.127: v4(67.28,76.58) 68.05,75.82 PC203.2
  TOP w0.203: v2(30.94,79.51) 31.02,79.6 UT5.G8 ; UT5.E6 UT5.F6 ; UT5.E6 UT5.E7 ; UT5.E6 UT5.E5 ; UT5.F6 UT5.F5 ; UT5.F6 UT5.F7 ; UT5.F6 UT5.G6 ; UT5.B7 UT5.A7 34.17,80.33 34.39,80.33 v2(34.49,80.22) 34.24,79.97 UT5.A8 ; UT5.F5 UT5.E5 ; UT5.F5 UT5.G5 ; UZ5.11 v2(246.4,63.83) ; UT5.E8 UT5.D8 32.69,80.15 v2(32.99,80.15) 33.35,80.15 UT5.B8 ; UT5.E8 UT5.E7 ; UT5.E8 32.02,79.6 v2(32.1,79.51) ; UT5.E8 UT5.F8 ; UT5.E7 UT5.F7 ; UT5.F7 UT5.G7 ; UT5.F7 UT5.F8 ; UT5.A6 v2(34.49,80.97) ; UT5.F8 UT5.G8 ; UT5.F8 v2(31.52,79.51) ; UT5.G8 UT5.H8 30.34,80.15 v2(30.05,80.15) ; UT5.G8 UT5.G7 ; UT5.G5 UT5.H4 30.52,82.29 v2(30.35,82.46) ; UT5.G5 UT5.G6 ; UZ2.11 249.45,111.2 v2(249.39,111.26) ; v2(30.05,81.9) 30.09,81.9 UT5.H5 ; UT5.L1 28.85,83.47 v2(28.6,83.73) ; v2(34.49,83.75) 34.3,83.75 UT5.A1 ; UT5.G6 UT5.G7 ; UT5.E5 32.49,81.94 32.49,82.26 v2(32.69,82.46) ; UZ3.11 v2(157.57,60.34) ; UZ4.11 v2(278.17,90.94)
  TOP w0.254: DT7.2 11.83,108.11 11.71,108.23 v2(11.71,108.74) DT6.2 ; DT6.2 12.23,109.27 v2(12.33,109.17) ; DT6.2 11.25,109.27 v2(11.12,109.14) ; PC621.1 45.17,86.57 v2(45.17,85.61) ; DT10.2 12.16,102.35 v2(12.27,102.25) ; DT10.2 11.19,102.35 v2(11.06,102.22) ; DT10.2 v2(11.64,101.82) ; UE1.A13 v2(246.28,93.86) ; CE1.2 264.7,93.65 265.28,93.65 265.72,93.22 UE2.17 ; v2(113.66,109.6) 113.99,109.93 113.99,111.34 v2(114.47,111.82) 114.47,112.73 115.35,113.61 v2(115.35,115.57) 115.62,115.84 115.62,116.39 115.26,116.75 114.48,116.75 113.99,116.27 113.99,115.25 112.98,114.24 112.98,112.62 v2(112.22,111.85) 112.22,110.37 PC1085.2 ; DT5.2 12.16,110.84 v2(12.29,110.97) ; DT5.2 v2(11.71,111.37) ; DT5.2 11.19,110.84 v2(11.08,110.95) ; v2(11.02,104.02) 11.12,103.92 DT9.2 ; RPE10.6 259.68,100.66 v2(259.91,100.89) 260.18,100.61 RPE10.5 ; v2(13.93,108.02) 13.87,107.96 DT11.2 ; v2(165.02,62.42) 165.02,62.75 PD2.1 PD1.1 ; RPE10.7 259.18,100.69 v2(258.93,100.95) 258.68,100.7 RPE10.8 ; CZ111.2 250.77,113.29 v2(251.1,112.96) ; DT9.2 v2(11.64,104.45) ; DT9.2 12.1,103.92 v2(12.23,104.05) ; v2(243.57,85.94) 243.5,85.87 243.5,84.97 CE29.2 ; CC27.2 118.48,78.69 118.48,81.34 119.28,82.14 119.28,83.07 119.59,83.39 v2(119.78,83.39) ; v2(121.05,82.08) 121.25,81.88 121.25,81.2 CC332.2 ; v2(247.88,85.86) UE1.C4 ; DT8.2 v2(14.63,105.61) ; v2(257.94,86.46) CE21.2 ; v2(277.38,75.77) 277.63,75.52 UI3.14 ; UE1.E6 v2(249.48,87.46) ; DT12.2 v2(13.87,105.4) ; UE1.A6 246.28,87.46 ; UE1.H4 v2(252.68,85.86)
  TOP w0.305: PC1148.2 119.09,107.61 118.46,106.98 CC202.2 ; DV8.2 v2(58.42,122.52) ; JUSBC1.A1 6.65,109.9 JUSBC1.B12 ; JAPS1.10 260.06,108.9 v2(260.12,108.96) ; DV7.2 58.42,119.14 v2(58.84,118.72) ; JAPS1.8 261.06,108.9 v2(261,108.96) ; v2(257.93,109.33) 258.06,109.21 JAPS1.14 ; v2(212.81,57.78) 212.81,57.52 212.4,57.11 CZ81.2 ; JAPS1.12 v2(259.06,108.96) ; v2(270.91,95.18) 271.18,95.45 UE4.3
  TOP w0.356: CR6.2 v2(273.56,60.01) ; CC313.2 122.83,99.57 v2(123.33,99.08) ; v2(263.66,85.47) 263.9,85.71 CE22.2 ; CR3.2 274.98,59.61 274.98,58.99 CR26.2 ; v2(250.87,96.9) 251.46,96.31 CE19.2 ; CE13.2 258.53,89.63 259.61,88.56 v2(260.08,88.56) ; v2(276.43,58.99) 275.96,59.46 CR7.2
  TOP w0.381: RC1.2 126.52,105.49 v2(126.16,105.85) ; JAPS1.19 v2(265.56,111.47) ; UE5.3 263.83,97.06 v2(264.21,97.06) ; PC1084.2 112.08,109.45 v2(111.97,109.55) 111.97,109.56 PC1085.2 ; v2(110.03,131.01) 109.24,131.01 v4(108.44,131.82) 108.09,132.17 RV76.2 107.1,132.18 CV81.2 ; DI1.3 v2(20.92,63.32) ; v2(286.79,120.73) 286.78,120.73 286.62,120.89 CL19.2 ; UE6.3 v2(265.63,79.43) ; v2(110.03,128.47) 109.52,127.96 CV84.2 ; CC264.2 125.05,107.71 v2(125.61,108.27) ; PQ1.1 54.65,112.33 54.38,112.6 v2(54.38,112.91) 54.38,113.36 54.11,113.63 PQ1.4 ; CR19.1 282.61,61.48 v2(282.95,61.48) ; v2(55.7,51.45) 55.71,51.46 PR932.2 ; v2(262.98,58.98) 262.77,58.98 262.7,58.9 CA45.2 ; PC1042.2 100.93,108.64 100.93,109.53 v2(100.95,109.54) ; CE20.2 250.99,78.32 v2(250.54,78.32) ; PC644.2 47.37,99.12 v2(46.58,99.12) 46.59,99.13 PQ1214.4 ; PC651.1 PC654.1 56.31,96.33 PC645.2 v2(57.17,95.71) PC647.1 ; v2(31.52,108.02) 31.29,108.02 CT120.2 ; PC1052.2 110.29,109.35 v2(110.09,109.54) 109.96,109.54 109.66,109.24 PC1053.2 ; v2(115.5,109.6) 115.5,109.95 PC1147.2 ; CN61.2 v2(30.31,44.33) ; v2(125.54,102.65) 125.54,102.87 126.08,103.41 CC323.2 126.17,103.54 127.49,103.54 127.86,103.91 CC222.2 ; CV85.2 120.39,133.63 v2(120.67,133.91) ; CI19.2 v2(279.4,77.76) ; PR1222.2 44.3,107.83 PQ1201.4 44.95,107.59 v2(45.72,108.37) 45.72,106.61 46.04,106.29 PQ1201.1 ; v2(267.57,97.43) 267.19,97.43 267.03,97.6 UE3.3 ; CV83.2 116.9,128.79 v2(116.58,128.47) ; CT72.2 35.05,84.31 v2(34.49,83.75) ; v2(60.25,52.3) 59.5,52.3 PC937.1 ; CE14.2 244.17,86.87 244.52,87.22 CE23.2 246.05,87.22 246.28,87.46 ; CL10.2 240.09,129.17 v2(239.63,128.71) ; v2(15.92,87.73) 15.45,87.73 CV40.2 ; v2(126.26,122.95) 126.26,122.06 125.82,121.61 RC3.2 ; CE57.2 247.1,75.93 v2(247.64,76.46) ; CD29.2 102.7,53.65 v2(101.35,55) ; v2(113.75,108.14) 113.28,108.61 PC1051.2 ; PC649.2 PC652.2 50.3,100.43 50.62,100.75 v2(50.62,100.93) ; v2(262.43,64.27) 262.43,63.96 CA47.2 ; v2(114.4,128.47) 115.12,128.47 115.48,128.12 RV88.2 115.49,127.79 CV82.2 ; CT88.2 19.32,68.87 CT89.2 ; CE15.2 251.64,81.63 v2(251.67,81.67) ; CC314.2 123.94,104.14 v2(123.98,104.1) ; CE12.2 244.35,75.94 244.87,76.46 244.87,77.54 245.64,78.31 245.76,78.31 RE58.2 v2(246.09,79.39) ; CL17.2 261.73,130.35 v2(261.71,130.38) ; CL16.2 260.53,130.66 260.82,130.95 v2(261.39,130.95) ; v2(221.95,55.98) 221.99,56.02 CZ66.2 ; v2(246.55,101.72) QE12.3 246.19,100.56 RE93.2 ; CT121.2 25.23,109.42 v2(25.3,109.48) ; CZ101.2 v2(127.98,122.95) ; PC1152.2 PC1153.2 119.33,102.91 119.83,102.4 v2(120.03,102.4) ; 280.19,83.07 v2(281.39,83.07) ; v2(113.66,109.6) 113.9,109.36 PC1050.2 ; CC320.2 132.29,104.85 v2(130.08,104.85) ; RC89.2 125.49,83.56 125.91,83.98 CC270.2 125.91,84.59 v2(126.19,84.87) ; v2(95.34,107.65) 95.34,107.81 PC1044.2 ; PQ1214.1 v2(45.62,101.02) ; CC28.2 CC29.2 ; CC214.2 132.4,85.7 132.07,86.02 v2(132.07,86.69) ; CA10.2 v2(260.86,64.07) ; v2(94.06,102.14) 94.07,102.13 PC1043.2 ; v2(255.04,95.29) CE25.2 ; PC1040.2 v2(99.12,109.54) ; v2(125.63,97.3) 125.72,97.22 CC223.2 ; PQ1209.1 30.33,123.57 30,123.9 30,124.53 29.66,124.87 PQ1209.4 28.28,124.87 PC1214.2 v2(27.15,125.12) ; v2(104.61,109.54) 104.61,109.54 PC1041.2 ; CZ119.2 v2(279.49,94.24) ; UZ10.3 268.26,86.13 267.99,86.4 v2(267.86,86.4) ; CZ122.2 247.79,109.97 CZ109.2 ; v2(90.94,107.49) 90.15,108.28 RC163.2 ; v2(105.56,130.16) 105.56,128.74 105.9,128.4 RV77.2 ; CV12.2 v2(66.58,130.62) ; CZ93.2 v2(265.71,83.7) ; v2(28.66,96.72) CT118.2 ; RC166.2 v2(117.75,121.99) ; JAPS1.20 v2(255.06,111.67) ; v2(244.56,119.66) CL7.2 ; CC204.2 v2(133.45,96.78)
  TOP w0.457: RT64.2 RT65.2 ; v2(64.16,125.93) 64.51,126.29 65.2,126.29 65.85,125.64 UV24.2 ; v2(106.44,96.66) 106.44,96.66 CC250.2 ; v2(118.32,95.37) 118.6,95.37 CC288.2 ; v2(250.79,119.84) 250.4,119.45 CL14.2 ; PC207.2 63.84,69.34 v2(63.84,70.11) ; RV73.2 RV74.2 112.34,131.14 v2(112.22,131.01) ; CC211.2 122.27,104.59 121.99,104.31 v2(121.99,104.08) ; CE40.2 254.14,98.12 v2(254.28,97.98) ; CC205.2 121.39,99.71 v2(122.03,99.08) ; RC316.2 160.36,91.69 v2(159.47,91.69) ; v2(120.71,98.19) 120.55,98.35 CC213.2 ; v2(118.32,96.01) 117.85,96.01 CC176.2 ; v2(29.88,87.96) RT96.2 29.88,86.33 CT83.2 ; v2(107.19,59.8) 106.92,59.8 106.6,60.12 106.6,60.86 CD14.2 ; CC217.2 120.03,101.82 v2(120.03,102.4) ; CE31.2 v2(254.79,79.26) ; RC114.2 96.77,109.41 v2(97.2,108.98) ; v2(123.31,106.57) 123.31,107.15 CC203.2 ; CC208.2 124.31,103.07 123.98,102.74 v2(123.98,102.43) ; v2(115.5,109.6) 115.43,109.53 CC199.2 ; CE5.2 245.06,97.12 v2(244.63,97.55) 245.06,97.98 CE6.2 ; CE47.2 v2(255.93,97.23) ; v2(122.7,103.24) 122.7,102.94 122.53,102.77 CC209.2 122.53,102.11 122.67,101.96 CC207.2 ; CC26.2 133.2,81.48 v2(133.58,81.48) 133.93,81.48 CC23.2 ; v2(116.42,98.26) 117.72,98.26 RC167.2 ; v2(118.13,105.28) 117.75,105.66 PC1060.2 117.75,106.21 CC202.2 ; v2(122.17,81.1) 122.17,80.45 CC333.2 122.31,79.46 CC331.2 ; v2(95.98,63.1) 95.87,62.99 CD13.2 ; CC206.2 120,103.48 v2(119.92,103.4) ; RL9.2 244.09,119.66 v2(244.56,119.66) ; PC1207.2 42.18,56.01 v2(42.54,55.64) 42.04,55.13 PC1206.2 ; v2(280.3,75.07) 280.58,75.35 RI14.1 ; v2(56.74,115.38) 56.41,115.71 PC9.2 ; RE14.2 v2(265.58,89.04) ; v2(128.47,118.2) 128.47,119.01 128.98,119.52 CC325.2 ; UE7.2 v2(242.84,97.61) ; v2(108.27,95.37) 108.26,95.38 CC251.2 ; v2(92.41,132.22) 92.41,130.77 91.45,129.8 v4(91.39,129.8) 89.74,129.8 CC32.2 CC306.2 ; CC308.2 RC86.2 98.21,119.72 98.71,119.22 v2(98.71,118.69) ; v2(115.58,96.01) 116,96.01 CC177.2 ; v2(112.84,96.01) 112.86,96.04 CC179.2 ; v2(37.62,86.62) 37.12,86.62 CT74.2 ; v2(108.27,94.74) 108.74,94.74 CC178.2 ; v2(251.15,68.31) 250.98,68.48 CA68.2 CA67.2 ; CC224.2 130.99,97.34 v2(130.89,97.45) ; RT99.2 31.9,74.42 v2(31.9,74.81) RT86.2 ; PC1212.2 v2(38.12,56.91) ; CE52.2 v2(263.29,100.02) ; v2(250.52,104.07) 250.58,104.01 RZ38.1 ; v2(119.68,115.68) 119.68,119.77 120.45,120.53 CC195.2 ; CE36.2 v2(267.94,102.86) ; CL13.2 246.43,119.37 v2(245.58,119.37) RL3.2 ; PR1227.2 v2(26.31,122.44) ; v2(242.81,86.27) 242.81,86.35 243.33,86.87 CE14.2 ; PR1219.2 v2(42.54,54.24) ; RE77.2 CE38.2
  TOP w0.508: CD12.2 v2(106.4,52.45) ; v2(123.28,100.73) 123.28,100.08 CC265.2 ; RC90.2 91.48,109.36 v2(91.1,108.98) 91.62,108.47 RC91.2 ; CA24.2 277.93,18.26 v2(277.71,18.04) ; CT89.2 v2(18.69,68.15) ; CD7.2 v2(100.47,52.46) ; PC218.2 v2(71.59,71.85) ; PC1131.2 v2(89.11,101.48) ; CE62.2 248.8,79.14 v2(249.01,79.35) CE54.2 RE20.2 ; PC1008.2 v2(73.81,112.91) ; CD9.2 89.98,52.46 v2(89.97,52.46) ; CR22.2 278.66,61.1 v2(279.36,60.4) ; CD1.2 109.13,61.16 109.45,60.84 109.45,60.13 109.12,59.8 v2(108.83,59.8) ; CA31.2 264.35,66.67 v2(264.95,66.67) ; PC1072.2 v2(85.43,105.04) ; YL1.4 249.74,117.17 v2(250.07,117.17) ; CI34.2 v2(276.44,81.04) ; v2(108.21,56.29) 108.2,56.29 108.2,55.1 CD6.2 ; v2(146.12,55.15) 144.89,53.92 CD23.2 CD24.2 ; v2(61.11,114.31) 61.44,113.98 PC685.2 ; v2(281.46,23.76) CA22.2 ; v2(239.15,87.93) 239.39,88.17 240.18,88.17 RE513.2 ; RA52.1 260.04,66.88 CA61.2 v2(260.63,66.2) ; PC1.2 167.16,57.68 v2(166.78,57.3) ; PR206.2 v2(63.33,72.59) ; CR15.2 280.34,67.45 v2(280.36,67.47) ; CC296.2 109.95,82.81 v2(110.97,82.81) ; PC1133.2 v2(87.91,101.48) ; CC218.2 v2(119.9,104.18) ; v2(158.11,102.28) 157.9,102.5 CC7.2 ; CC269.2 90.44,128.39 v2(90.84,128.79) ; v2(111.13,98.34) 111.05,98.41 CC297.2 ; YL1.2 v2(245.58,118.13) ; PR1249.2 PR1210.2 v2(34.2,53.74) ; CA23.2 v2(281.27,25.79) ; JSD1.6 v2(284.78,54.87) ; v2(111.76,121.25) 111.76,120.64 RC141.2 ; v2(41.38,122.24) 41.12,121.98 QV2.3 ; DV4.1 53.17,127.14 52.84,127.47 CA6.2 v2(52.84,130.12) ; v2(22.95,69.85) 22.52,69.85 22.01,69.34 RT393.2 ; RA38.2 281.75,47.86 v2(282.61,48.72) ; RA37.2 248.73,59.95 248.5,59.73 v2(248.5,59.7) ; v2(116.41,99.03) 116.65,99.27 PC1057.2 ; CD11.2 111.28,58.75 111.81,58.21 v2(112.31,58.21) ; v2(67.02,123.3) 67.02,123.33 67.09,123.4 CV17.2 ; PC219.2 v2(71.27,69.18) ; PC1286.2 PR945.2 50.21,61.42 v2(49.95,61.42) ; RD16.2 CD25.2 CD26.2 119.85,54.35 v2(119.85,56.46) ; PC1216.2 v2(24.47,113.17) PC1208.2 ; PR953.2 42.94,55.24 v2(42.54,55.64) ; v2(39.2,129.3) 39.2,127.61 PD4.1 ; CC326.2 v2(136.09,100.06) ; v2(28.15,67.86) 28.45,67.86 CT70.2 ; CE16.2 253.5,73.79 CE59.2 v2(251.89,73.79) ; RD9.2 124.47,52.72 v2(124.71,52.48) ; JSD1.14 v2(297.94,60.08) ; v2(138.8,64.42) 138.19,64.42 CZ102.2 ; CC294.2 103.25,82.41 v2(102.87,82.41) ; CD16.2 120.18,63.36 v2(120.19,63.37) ; RR4.2 v2(269.39,61.76) ; CZ104.2 139.14,68.6 ; v2(48.87,120.97) 49.25,120.58 QV7.3 ; DT4.1 v2(19.2,111.71) ; v2(27.65,74.46) RT103.2 27.7,75.13 CT82.2 ; PR1217.2 PC1205.2 v2(38.75,52.67) ; RE85.2 249.44,100.85 v2(249.44,101.32) ; QR1.3 281.33,59.21 v2(280.73,58.61) ; RT130.2 v2(29.81,109.23) ; v2(116.39,60.56) 116.36,60.59 CD5.2 ; v2(119.78,83.39) 120.56,83.39 RC5.2 ; v2(250.47,51.45) 250.47,51.51 250.46,51.52 RA36.2 RA35.2 ; PC1217.2 v2(248.94,98.93) ; v2(49.33,58.43) 49.33,58.76 49.82,59.26 PR960.1 ; CI33.2 v2(277.65,81.04) ; CE3.2 v2(256.89,81.47) ; PC1136.2 v2(86.7,98.69) ; CT73.2 27.19,85.99 v2(27.18,86) ; v2(71.27,68.48) 71.78,67.97 PC209.2 ; CZ63.2 232.05,52.51 v2(231.54,53.02) ; CD10.2 v2(113.31,52.59) ; PC1138.2 v2(85.49,98.69) ; CA64.2 v2(249.64,53.58) ; JSD1.20 298.3,54.28 v2(298.04,54.54) ; PC2.1 v2(281.84,8.96) ; CR5.2 v2(271.74,60.09) ; RE18.2 RE16.2 268.07,87.25 v2(267.87,87.04) ; v2(291.2,47.95) 291.2,45.3 v2(291.62,44.88) 292.07,44.42 v2(292.07,44.41) ; PC1137.2 v2(85.49,101.48) ; PR310.2 v2(156.18,88.57) ; RL13.2 250.79,120 v2(250.79,119.84) ; CC28.2 85.28,133.84 84.2,132.77 v2(84.2,132.22) ; PC1013.2 v2(84.22,105.04) ; RE95.1 260.6,91.93 v2(260.6,91.49) ; RD18.2 v2(116.1,51.7) ; v2(71.82,121.61) 71.32,122.1 RV2.2 RV3.1 ; v2(277.71,20.08) 277.93,20.29 CA19.2 ; CC295.2 v2(108.35,83.01) ; RZ40.1 v2(280.01,86.93) ; PC1180.2 v2(84.29,101.48) ; v2(260.39,54.81) 260.39,54.11 ; CE1.2 v2(264.45,94.55) ; v2(222.86,59.84) 222.86,59.29 222.53,58.96 RZ10.1 ; PR407.2 PC411.2 v2(164.63,124.94) ; v2(29.74,45.79) 30.14,45.4 CN60.2 ; PC1134.2 v2(87.91,98.69) ; CE53.2 269.2,100.91 268.25,101.86 CE36.2 ; v2(275.79,58.61) 275.49,58.91 CR26.2 ; RA39.2 v2(281.16,31.53) ; v2(246.09,79.39) RE55.2 ; CR21.2 277.19,58.1 v2(276.81,58.48) ; CZ197.2 v2(204.87,52.87) ; PC1064.2 v2(89.05,105.04) ; v2(271.27,89.67) 271.7,89.24 CE500.2 271.69,89.06 CE61.2 ; CD3.2 v2(111.53,52.21) ; PC1129.2 v2(90.32,98.69) ; PC1130.2 v2(90.32,101.48) ; PR8.1 36.54,128.04 v2(35.47,128.04) 34.81,127.38 PQ3.3 ; CC215.2 v2(148.36,103.91) ; v2(127.68,63.79) 127.86,63.97 CD15.2 ; v2(135.13,96.38) 136.92,96.38 CC324.2 ; CZ198.2 v2(241.27,111.07) ; v2(258.04,77.94) 257.78,78.19 RE313.2 CE4.2 ; v2(236.9,85.64) 236.14,85.64 RE56.2 ; RV1.2 v2(69.79,126.19) ; CZ110.2 v2(247.17,111.77) ; v2(298.04,57.27) 298.3,57.01 JSD1.17 ; PC111.2 155.03,78.34 v2(155.45,77.93) ; PC1132.2 v2(89.11,98.69) ; CD4.2 v2(114.9,52.14) ; PC1179.2 v2(84.29,98.69) ; PC313.2 155.15,87.55 v2(154.99,87.72) ; v2(37.79,78.57) 37.49,78.88 RT64.2 ; v2(120.68,99.02) 120.41,99.3 PC1058.2 ; CE38.2 243.51,93.59 v2(242.95,93.59) ; CE8.2 v2(260.82,96.09) ; CA46.2 v2(265.83,59.38) ; CC280.2 CC279.2 138.94,78.92 v2(138.11,78.92) ; CC8.2 v2(158.58,92.86) ; CZ109.2 v2(247.17,110.88) ; v2(139.72,52.46) 139.41,52.78 CD22.2 138.63,52.78 v2(138.31,52.47) ; v2(263.65,83.91) 263.26,83.91 RE342.2 CE60.2 ; CD8.2 113.56,60.81 112.9,60.14 v2(112.31,60.14) ; PC1075.2 v2(86.64,105.04) ; v2(107.33,109.57) 107.74,109.15 RC324.2 ; QV4.3 19.33,79.46 v2(19,79.13) ; CI31.2 v2(278.73,81.04) ; v2(285.52,121.78) CL18.2 ; v2(34.99,58.32) 34.99,57.77 PC1213.2 ; RE537.1 v2(245.39,108.47) ; v2(69.35,75.56) 69.71,75.92 PC221.2 PR209.2 PR212.2 PC222.2 ; CZ62.2 v2(232.43,56.03) ; CR25.2 CR4.2 v2(275.06,56.42) ; RE65.2 CE30.2 247.78,99.91 JTAG1.2 v2(247.05,99.19) ; PC1011.2 v2(87.84,105.04) ; RC349.2 v2(137.95,81.16) ; CD2.2 104.48,61.16 104.16,60.84 104.16,60.15 104.51,59.8 v2(104.79,59.8) ; JSD1.23 v2(298.04,51.55) ; SW3.1 v2(295.67,125.35) ; UZ6.3 202.31,58.42 v2(202.25,58.35) ; CE2.2 v2(264.45,90.59) ; CT122.2 v2(26,96.75) ; v2(255.23,66.81) CA56.2 ; SW3.3 v2(295.67,123.38) ; PC401.2 v2(137.44,131.77) ; v2(129.96,102.71) 130.01,102.75 RC44.2 130.92,102.75 131.33,102.35 RC96.2 131.48,102.31 CC212.2 ; PC1135.2 v2(86.7,101.48) ; PC1012.2 v2(75.02,112.91) ; v2(39.83,129.28) 41.87,127.24 43.61,127.24 CV15.2 44.16,126.58 CV14.2 ; PC3.2 v2(287.3,14.04)
  GND1 w0.203: 10.99,83.56 JHDMI1.5 ; JHDMI1.5 10.99,82.64 ; JHDMI1.5 11.91,82.64 ; JHDMI1.5 11.91,83.56 ; JHDMI1.5 10.87,83.1 ; JHDMI1.5 12.03,83.1 ; 6.27,101.63 JUSBC1.2 ; JUSBC1.2 6.27,103.07 ; JUSBC1.2 7.43,102.35 ; JUSBC1.2 5.12,101.63 ; JUSBC1.2 7.43,101.63 ; H24.1 4.6,51.23 ; H24.1 3.33,50.77 ; H24.1 5.87,50.77 ; H24.1 5.87,48.23 ; H24.1 6.33,49.5 ; H24.1 3.33,48.23 ; H24.1 4.6,47.77 ; H24.1 2.87,49.5 ; JUSB1.7 285.87,79.73 ; JUSB1.7 285.04,78.9 ; JUSB1.7 285.87,78.07 ; JUSB1.7 285.23,78.27 ; JUSB1.7 285.23,79.54 ; JUSB1.7 286.5,78.27 ; JUSB1.7 286.5,79.54 ; 14.8,56.05 JUSB2.12 ; JUSB2.12 17.47,55.22 ; JUSB2.12 16.13,55.22 ; JUSB2.12 14.8,56.88 ; JUSB2.12 16.13,56.88 ; JUSB2.12 14.8,55.22 ; JUSB2.12 17.47,56.88 ; JUSB2.12 17.47,56.05 ; 10.37,91.97 JHDMI1.20 ; JHDMI1.20 12.93,93.73 ; JHDMI1.20 10.37,93.73 ; JHDMI1.20 11.65,91.97 ; JHDMI1.20 12.93,92.85 ; JHDMI1.20 11.65,93.73 ; 285.37,49.97 JSD1.10 ; JSD1.10 287.63,49.97 ; JSD1.10 285.37,50.7 ; JSD1.10 286.5,49.25 ; JSD1.10 287.63,50.7 ; JSD1.10 286.5,50.7 ; JSD1.10 285.37,49.25 ; JSD1.10 287.63,49.25 ; 164.1,132.47 H38.1 ; H38.1 165.37,135.47 ; H38.1 165.37,132.93 ; H38.1 162.83,132.93 ; H38.1 165.83,134.2 ; H38.1 162.83,135.47 ; H38.1 164.1,135.93 ; H38.1 162.37,134.2 ; 299.3,62.85 JSD1.12 ; JSD1.12 299.3,64.3 ; JSD1.12 298.17,64.3 ; JSD1.12 298.17,63.57 ; 279.9,12.22 H16.1 ; H16.1 278.63,15.22 ; H16.1 281.17,15.22 ; H16.1 281.17,12.68 ; H16.1 278.63,12.68 ; H16.1 278.17,13.95 ; H16.1 281.63,13.95 ; H16.1 279.9,15.68 ; 139.87,91.4 H3.1 ; H3.1 143.56,89.84 ; H3.1 140.44,89.84 ; H3.1 142,89.27 ; H3.1 143.56,92.96 ; H3.1 144.13,91.4 ; H3.1 140.44,92.96 ; H3.1 142,93.53 ; H2.1 143.56,111.99 ; H2.1 144.13,113.55 ; H2.1 142,111.42 ; H2.1 140.44,111.99 ; H2.1 143.56,115.11 ; H2.1 140.44,115.11 ; H2.1 139.87,113.55 ; H2.1 142,115.68 ; 13.7,63.08 JUSB2.7 ; JUSB2.7 14.33,63.28 ; JUSB2.7 13.7,61.81 ; JUSB2.7 15.16,62.45 ; JUSB2.7 14.97,61.81 ; JUSB2.7 14.33,61.62 ; JUSB2.7 14.97,63.08 ; 287.78,131.63 H29.1 ; H29.1 287.32,132.9 ; H29.1 289.05,131.17 ; H29.1 289.05,134.63 ; H29.1 290.32,131.63 ; H29.1 290.78,132.9 ; H29.1 290.32,134.17 ; H29.1 287.78,134.17 ; 1.62,94.35 JHDMI1.21 ; JHDMI1.21 1.62,95.38 ; JHDMI1.21 3.3,95.38 ; JHDMI1.21 4.98,94.35 ; JHDMI1.21 4.98,95.38 ; JUSB1.4 284.36,83.23 ; JUSB1.4 284.36,81.57 ; JUSB1.4 283.54,82.4 ; JUSB1.4 283.73,81.76 ; JUSB1.4 285,81.76 ; JUSB1.4 283.73,83.03 ; JUSB1.13 294.5,87.43 ; JUSB1.13 293.31,87.43 ; JUSB1.13 292.13,87.43 ; JUSB1.13 294.5,86.6 ; JUSB1.13 292.13,86.6 ; JSD1.11 287.63,62.85 ; JSD1.11 287.63,64.3 ; JSD1.11 286.5,62.85 ; JSD1.11 286.5,64.3 ; JSD1.11 287.63,63.57 ; JSD1.11 285.37,62.85 ; JSD1.11 285.37,63.57 ; JSD1.11 285.37,64.3 ; H9.1 235.37,135.47 ; H9.1 232.83,132.93 ; H9.1 235.83,134.2 ; H9.1 232.37,134.2 ; H9.1 232.83,135.47 ; H9.1 234.1,135.93 ; H9.1 235.37,132.93 ; H9.1 234.1,132.47 ; H37.1 152.08,134.3 ; H37.1 148.12,134.3 ; H37.1 150.1,132.32 ; H37.1 151.55,135.75 ; H37.1 148.65,132.85 ; H37.1 150.1,136.28 ; H37.1 151.55,132.85 ; H37.1 148.65,135.75 ; 296.1,49.25 JSD1.13 ; JSD1.13 297.23,49.97 ; JSD1.13 297.23,50.7 ; JSD1.13 296.1,50.7 ; JSD1.13 294.97,50.7 ; JSD1.13 294.97,49.25 ; JSD1.13 297.23,49.25 ; JSD1.13 294.97,49.97 ; JUSBC1.3 2.05,113.67 ; JUSBC1.3 3.27,113.67 ; JUSBC1.3 2.05,112.23 ; JUSBC1.3 0.83,112.95 ; JUSBC1.3 0.83,113.67 ; JUSBC1.3 3.27,112.95 ; JUSBC1.3 3.27,112.23 ; JUSBC1.3 0.83,112.23 ; 5.7,54.75 JUSB2.13 ; JUSB2.13 8.07,53.92 ; JUSB2.13 8.07,54.75 ; JUSB2.13 6.88,53.92 ; JUSB2.13 5.7,53.92 ; JUSB2.11 8.07,70.15 ; JUSB2.11 6.88,70.98 ; JUSB2.11 8.07,70.98 ; JUSB2.11 5.7,70.98 ; JUSB2.11 5.7,70.15 ; JUSB1.10 285.4,72.5 ; JUSB1.10 285.4,71.67 ; JUSB1.10 282.73,72.5 ; JUSB1.10 284.06,73.33 ; JUSB1.10 285.4,73.33 ; JUSB1.10 282.73,71.67 ; JUSB1.10 282.73,73.33 ; JUSB1.10 284.06,71.67 ; 274.41,101.01 H7.1 ; H7.1 277.93,102.5 ; H7.1 273.87,102.5 ; H7.1 277.39,101.01 ; H7.1 275.9,104.53 ; H7.1 277.39,103.99 ; H7.1 274.41,103.99 ; H7.1 275.9,100.47 ; 1.62,76.85 JHDMI1.23 ; JHDMI1.23 1.62,75.82 ; JHDMI1.23 3.3,75.82 ; JHDMI1.23 4.98,76.85 ; JHDMI1.23 4.98,75.82 ; JUSB1.12 285.4,86.13 ; JUSB1.12 285.4,85.3 ; JUSB1.12 282.73,85.3 ; JUSB1.12 284.06,84.47 ; JUSB1.12 285.4,84.47 ; JUSB1.12 282.73,86.13 ; JUSB1.12 284.06,86.13 ; JUSB1.12 282.73,84.47 ; 12.54,84.14 JHDMI1.8 ; JHDMI1.8 12.42,84.6 ; JHDMI1.8 12.54,85.06 ; JHDMI1.8 13.58,84.6 ; JHDMI1.8 13.46,85.06 ; JHDMI1.8 13.46,84.14 ; SW1.4 225.54,83.52 ; SW1.4 225.54,85.04 ; SW1.4 225.78,84.28 ; SW1.4 224.78,85.29 ; SW1.4 223.78,84.28 ; SW1.4 224.02,83.52 ; SW1.4 224.02,85.04 ; SW1.4 224.78,83.28 ; 82.2,111.42 H1.1 ; H1.1 80.64,115.11 ; H1.1 80.64,111.99 ; H1.1 82.2,115.68 ; H1.1 84.33,113.55 ; H1.1 80.07,113.55 ; H1.1 83.76,111.99 ; H1.1 83.76,115.11 ; 226.44,89.99 SW1.5 ; SW1.5 226.68,89.23 ; SW1.5 228.45,89.99 ; SW1.5 228.2,89.23 ; SW1.5 227.44,91 ; SW1.5 227.44,88.99 ; SW1.5 226.68,90.75 ; SW1.5 228.2,90.75 ; 147.76,51.1 H10.1 ; H10.1 150.1,53.44 ; H10.1 148.4,49.4 ; H10.1 152.44,51.1 ; H10.1 151.8,49.4 ; H10.1 148.4,52.8 ; H10.1 151.8,52.8 ; 8.6,72.62 H23.1 ; H23.1 10.33,74.35 ; H23.1 9.87,73.08 ; H23.1 6.87,74.35 ; H23.1 7.33,73.08 ; H23.1 8.6,76.08 ; H23.1 9.87,75.62 ; H23.1 7.33,75.62 ; 76.51,131.06 H26.1 ; H26.1 76.51,134.04 ; H26.1 79.49,131.06 ; H26.1 80.03,132.55 ; H26.1 75.97,132.55 ; H26.1 78,130.52 ; H26.1 78,134.58 ; H26.1 79.49,134.04 ; JUSB2.10 17.47,68.85 ; JUSB2.10 16.13,68.02 ; JUSB2.10 16.13,69.68 ; JUSB2.10 14.8,68.02 ; JUSB2.10 14.8,69.68 ; JUSB2.10 14.8,68.85 ; JUSB2.10 17.47,69.68 ; JUSB2.10 17.47,68.02 ; 64.92,51.15 H28.1 ; H28.1 67.1,53.33 ; H28.1 68.7,49.55 ; H28.1 67.1,48.97 ; H28.1 65.5,52.75 ; H28.1 68.7,52.75 ; H28.1 65.5,49.55 ; H28.1 69.28,51.15 ; H20.1 297.55,24.85 ; H20.1 296.1,24.32 ; H20.1 294.65,24.85 ; H20.1 296.1,28.28 ; H20.1 294.65,27.75 ; H20.1 298.08,26.3 ; H20.1 294.12,26.3 ; H20.1 297.55,27.75 ; H8.1 268.93,71.4 ; H8.1 265.41,69.91 ; H8.1 265.41,72.89 ; H8.1 266.9,73.43 ; H8.1 268.39,72.89 ; H8.1 268.39,69.91 ; H8.1 266.9,69.37 ; H8.1 264.87,71.4 ; 0.83,101.35 JUSBC1.4 ; JUSBC1.4 3.27,101.35 ; JUSBC1.4 3.27,102.07 ; JUSBC1.4 0.83,102.07 ; JUSBC1.4 2.05,102.07 ; JUSBC1.4 3.27,100.63 ; JUSBC1.4 2.05,100.63 ; JUSBC1.4 0.83,100.63 ; 12.54,82.06 JHDMI1.2 ; JHDMI1.2 13.58,81.6 ; JHDMI1.2 13.46,81.14 ; JHDMI1.2 13.46,82.06 ; JHDMI1.2 12.54,81.14 ; JHDMI1.2 12.42,81.6 ; JHDMI1.2 13,81.02 ; H4.1 84.33,91.4 ; H4.1 82.2,89.27 ; H4.1 83.76,92.96 ; H4.1 83.76,89.84 ; H4.1 80.07,91.4 ; H4.1 80.64,92.96 ; H4.1 80.64,89.84 ; H4.1 82.2,93.53 ; JLOM1.15 298.68,89.72 ; JLOM1.15 298.68,90.55 ; JLOM1.15 297,89.72 ; JLOM1.15 295.32,89.72 ; JLOM1.15 295.32,90.55 ; 4.28,116.87 H14.1 ; H14.1 7.28,115.6 ; H14.1 3.82,115.6 ; H14.1 5.55,117.33 ; H14.1 6.82,114.33 ; H14.1 5.55,113.87 ; H14.1 6.82,116.87 ; H14.1 4.28,114.33 ; H33.1 287.67,69.47 ; H33.1 286.4,66.47 ; H33.1 287.67,66.93 ; H33.1 288.13,68.2 ; H33.1 285.13,66.93 ; H33.1 285.13,69.47 ; H33.1 286.4,69.93 ; H33.1 284.67,68.2 ; 5.55,96.97 H15.1 ; H15.1 6.82,97.43 ; H15.1 3.82,98.7 ; H15.1 4.28,99.97 ; H15.1 5.55,100.43 ; H15.1 6.82,99.97 ; H15.1 7.28,98.7 ; H15.1 4.28,97.43 ; JLOM1.14 292.83,89.72 ; JLOM1.14 289.47,89.72 ; JLOM1.14 291.15,89.72 ; JLOM1.14 292.83,90.55 ; JLOM1.14 289.47,90.55 ; JUSB1.11 294.5,71.2 ; JUSB1.11 293.31,70.37 ; JUSB1.11 294.5,70.37 ; JUSB1.11 292.13,70.37 ; JUSB1.11 292.13,71.2 ; JLOM1.17 298.68,116.95 ; JLOM1.17 298.68,117.78 ; JLOM1.17 295.32,116.95 ; JLOM1.17 295.32,117.78 ; JLOM1.17 297,117.78 ; JHDMI1.22 12.93,79.23 ; JHDMI1.22 10.37,77.47 ; JHDMI1.22 11.65,77.47 ; JHDMI1.22 11.65,79.23 ; JHDMI1.22 10.37,79.23 ; JHDMI1.22 12.93,77.47 ; JHDMI1.22 12.93,78.35 ; 15.2,59.58 JUSB2.4 ; JUSB2.4 16.47,58.31 ; JUSB2.4 16.66,58.95 ; JUSB2.4 15.83,59.78 ; JUSB2.4 15.83,58.12 ; JUSB2.4 16.47,59.58 ; JLOM1.16 292.83,116.95 ; JLOM1.16 292.83,117.78 ; JLOM1.16 291.15,117.78 ; 10.87,86.1 JHDMI1.11 ; JHDMI1.11 11.91,86.56 ; JHDMI1.11 12.03,86.1 ; JHDMI1.11 10.99,85.64 ; JHDMI1.11 11.91,85.64 ; JHDMI1.11 10.99,86.56 ; H25.1 43.6,134.58 ; H25.1 42.11,131.06 ; H25.1 45.09,131.06 ; H25.1 43.6,130.52 ; H25.1 45.09,134.04 ; H25.1 42.11,134.04 ; H25.1 41.57,132.55 ; H25.1 45.63,132.55 ; 5.12,112.67 JUSBC1.1 ; JUSBC1.1 6.27,111.23 ; JUSBC1.1 7.43,111.95 ; JUSBC1.1 7.43,112.67 ; JUSBC1.1 6.27,112.67 ; JUSBC1.B12 6.99,109.56 ; JUSBC1.B12 7.08,109.95 ; JUSBC1.B12 6.6,109.47 ; JUSBC1.B12 6.21,110.34 ; JUSBC1.B1 6.99,104.74 ; JUSBC1.B1 6.6,104.83 ; JUSBC1.B1 6.21,103.96 ; JHDMI1.17 12.03,89.1 ; JHDMI1.17 10.99,89.56 ; JHDMI1.17 10.87,89.1 ; JHDMI1.17 11.91,88.64 ; JHDMI1.17 10.99,88.64 ; JHDMI1.17 11.91,89.56
  VCC w0.203: JUSB2.4 16.47,59.58 ; JUSB2.4 15.83,59.78 ; JUSB2.4 15.2,59.58 ; JUSB2.4 16.66,58.95 ; JUSB2.4 16.47,58.31 ; JUSB2.4 15.83,58.12 ; 291.15,89.72 JLOM1.14 ; JLOM1.14 292.83,89.72 ; JLOM1.14 289.47,89.72 ; JUSBC1.1 7.43,112.67 ; JUSBC1.1 6.27,112.67 ; JUSBC1.1 7.43,111.95 ; H20.1 297.55,27.75 ; H20.1 296.1,24.32 ; H20.1 294.65,27.75 ; H20.1 297.55,24.85 ; H20.1 296.1,28.28 ; H20.1 294.65,24.85 ; H20.1 298.08,26.3 ; H20.1 294.12,26.3 ; 284.06,84.47 JUSB1.12 ; JUSB1.12 282.73,85.3 ; JUSB1.12 284.06,86.13 ; JUSB1.12 282.73,84.47 ; JUSB1.12 282.73,86.13 ; JUSB1.12 285.4,86.13 ; JUSB1.12 285.4,84.47 ; JUSB1.12 285.4,85.3 ; JSD1.10 287.63,50.7 ; JSD1.10 287.63,49.25 ; JSD1.10 285.37,49.97 ; JSD1.10 286.5,49.25 ; JSD1.10 285.37,49.25 ; JSD1.10 287.63,49.97 ; JSD1.10 286.5,50.7 ; JSD1.10 285.37,50.7 ; 294.97,50.7 JSD1.13 ; JSD1.13 297.23,50.7 ; JSD1.13 294.97,49.25 ; JSD1.13 296.1,49.25 ; JSD1.13 297.23,49.25 ; JSD1.13 297.23,49.97 ; JSD1.13 296.1,50.7 ; JSD1.13 294.97,49.97 ; H14.1 6.82,114.33 ; H14.1 5.55,113.87 ; H14.1 3.82,115.6 ; H14.1 4.28,114.33 ; H14.1 6.82,116.87 ; H14.1 7.28,115.6 ; H14.1 4.28,116.87 ; 283.54,82.4 JUSB1.4 ; JUSB1.4 284.36,81.57 ; JUSB1.4 284.36,83.23 ; JUSB1.4 285,81.76 ; JUSB1.4 283.73,81.76 ; JUSB1.4 283.73,83.03 ; JUSB2.7 14.97,61.81 ; JUSB2.7 14.97,63.08 ; JUSB2.7 15.16,62.45 ; 285.13,69.47 H33.1 ; H33.1 286.4,69.93 ; H33.1 285.13,66.93 ; H33.1 287.67,69.47 ; H33.1 288.13,68.2 ; H33.1 287.67,66.93 ; H33.1 286.4,66.47 ; H33.1 284.67,68.2 ; JSD1.11 287.63,62.85 ; JSD1.11 286.5,62.85 ; JSD1.11 285.37,62.85 ; JSD1.11 285.37,64.3 ; JSD1.11 287.63,63.57 ; JSD1.11 285.37,63.57 ; JSD1.11 287.63,64.3 ; JSD1.11 286.5,64.3 ; H16.1 281.17,12.68 ; H16.1 278.63,12.68 ; H16.1 281.63,13.95 ; H16.1 279.9,15.68 ; H16.1 278.17,13.95 ; H16.1 278.63,15.22 ; H16.1 281.17,15.22 ; H16.1 279.9,12.22 ; JUSBC1.B1 6.6,104.83 ; JUSBC1.B1 6.83,104.86 ; JUSBC1.B1 6.99,104.74 ; 292.72,70.37 JUSB1.11 ; JUSB1.11 292.13,70.79 ; JUSB1.11 292.13,70.37 ; JUSB1.10 285.4,71.67 ; JUSB1.10 285.4,73.33 ; JUSB1.10 282.73,73.33 ; JUSB1.10 282.73,72.5 ; JUSB1.10 284.06,71.67 ; JUSB1.10 285.4,72.5 ; JUSB1.10 282.73,71.67 ; JUSB1.10 284.06,73.33 ; 12.54,84.14 JHDMI1.8 ; JHDMI1.8 13.46,84.14 ; JHDMI1.8 12.42,84.6 ; JHDMI1.8 13.58,84.6 ; JHDMI1.8 12.54,85.06 ; JHDMI1.8 13.46,85.06 ; JHDMI1.20 12.93,93.73 ; JHDMI1.20 11.65,93.73 ; JHDMI1.20 12.93,92.85 ; JHDMI1.20 11.65,91.97 ; 14.8,68.02 JUSB2.10 ; JUSB2.10 16.13,69.68 ; JUSB2.10 16.13,68.02 ; JUSB2.10 14.8,68.85 ; JUSB2.10 14.8,69.68 ; JHDMI1.17 12.03,89.1 ; JHDMI1.17 11.91,88.64 ; JHDMI1.17 11.91,89.56 ; 292.13,87.43 JUSB1.13 ; JUSB1.13 293.31,87.43 ; JUSB1.13 294.5,87.43 ; JHDMI1.21 4.98,95.38 ; JHDMI1.21 3.3,95.38 ; JHDMI1.21 1.62,95.38 ; 16.13,55.22 JUSB2.12 ; JUSB2.12 16.13,56.88 ; JUSB2.12 14.8,55.22 ; JUSB2.12 14.8,56.88 ; JUSB2.12 14.8,56.05 ; 299.3,62.85 JSD1.12 ; JSD1.12 298.17,63.57 ; JSD1.12 298.17,64.3 ; JSD1.12 299.3,64.3 ; H15.1 6.82,99.97 ; H15.1 3.82,98.7 ; H15.1 4.28,99.97 ; H15.1 7.28,98.7 ; H15.1 5.55,96.97 ; H15.1 4.28,97.43 ; H15.1 5.55,100.43 ; H15.1 6.82,97.43 ; JUSBC1.3 3.27,112.95 ; JUSBC1.3 2.05,113.67 ; JUSBC1.3 3.27,113.67 ; JUSBC1.B12 7.08,109.95 ; JUSBC1.B12 6.99,109.56 ; JUSBC1.B12 7.11,109.72 ; 13,81.02 JHDMI1.2 ; JHDMI1.2 12.42,81.6 ; JHDMI1.2 13.46,82.06 ; JHDMI1.2 13.58,81.6 ; JHDMI1.2 12.54,81.14 ; JHDMI1.2 13.46,81.14 ; JHDMI1.2 12.54,82.06 ; 5.7,70.98 JUSB2.11 ; JUSB2.11 6.88,70.98 ; JUSB2.11 8.07,70.98 ; JHDMI1.11 12.03,86.1 ; JHDMI1.11 11.91,86.56 ; JHDMI1.11 11.91,85.64 ; JUSBC1.4 3.27,101.35 ; JUSBC1.4 3.27,100.63 ; JUSBC1.4 2.05,100.63 ; H24.1 5.87,48.23 ; H24.1 6.33,49.5 ; H24.1 4.6,47.77 ; H24.1 3.33,48.23 ; H24.1 3.33,50.77 ; H24.1 5.87,50.77 ; H24.1 4.6,51.23 ; 5.7,53.92 JUSB2.13 ; JUSB2.13 6.88,53.92 ; JUSB2.13 8.07,53.92 ; 6.87,74.35 H23.1 ; H23.1 9.87,75.62 ; H23.1 7.33,75.62 ; H23.1 7.33,73.08 ; H23.1 10.33,74.35 ; H23.1 9.87,73.08 ; H23.1 8.6,72.62 ; H23.1 8.6,76.08 ; JHDMI1.22 11.65,79.23 ; JHDMI1.22 12.93,78.35 ; JHDMI1.22 11.65,77.47 ; JHDMI1.22 12.93,77.47 ; JHDMI1.22 12.93,79.23 ; 295.32,89.72 JLOM1.15 ; JLOM1.15 295.32,90.34 ; JLOM1.15 296.16,89.72 ; 6.27,101.63 JUSBC1.2 ; JUSBC1.2 7.43,102.35 ; JUSBC1.2 7.43,101.63 ; 285.04,78.9 JUSB1.7 ; JUSB1.7 285.23,79.54 ; JUSB1.7 285.23,78.27 ; JHDMI1.5 11.91,83.56 ; JHDMI1.5 12.03,83.1 ; JHDMI1.5 11.91,82.64
  GND2 w0.203: JUSBC1.4 2.05,102.07 ; JUSBC1.4 0.83,101.35 ; JUSBC1.4 3.27,102.07 ; JUSBC1.4 3.27,101.35 ; JUSBC1.4 3.27,100.63 ; JUSBC1.4 0.83,102.07 ; JUSBC1.4 0.83,100.63 ; JUSBC1.4 2.05,100.63 ; 226.68,89.23 SW1.5 ; SW1.5 227.44,88.99 ; SW1.5 228.2,89.23 ; SW1.5 227.44,91 ; SW1.5 228.45,89.99 ; SW1.5 226.68,90.75 ; SW1.5 226.44,89.99 ; SW1.5 228.2,90.75 ; JUSB2.13 8.07,54.75 ; JUSB2.13 5.7,54.75 ; JUSB2.13 8.07,53.92 ; JUSB2.13 5.7,53.92 ; JUSB2.13 6.88,53.92 ; 232.83,135.47 H9.1 ; H9.1 235.37,132.93 ; H9.1 232.37,134.2 ; H9.1 235.83,134.2 ; H9.1 232.83,132.93 ; H9.1 234.1,132.47 ; H9.1 234.1,135.93 ; H9.1 235.37,135.47 ; JUSBC1.3 3.27,113.67 ; JUSBC1.3 0.83,113.67 ; JUSBC1.3 0.83,112.95 ; JUSBC1.3 2.05,113.67 ; JUSBC1.3 0.83,112.23 ; JUSBC1.3 3.27,112.95 ; JUSBC1.3 3.27,112.23 ; JUSBC1.3 2.05,112.23 ; H29.1 289.05,134.63 ; H29.1 290.32,134.17 ; H29.1 287.78,134.17 ; H29.1 289.05,131.17 ; H29.1 287.78,131.63 ; H29.1 287.32,132.9 ; H29.1 290.32,131.63 ; H29.1 290.78,132.9 ; 42.11,134.04 H25.1 ; H25.1 43.6,134.58 ; H25.1 42.11,131.06 ; H25.1 45.63,132.55 ; H25.1 43.6,130.52 ; H25.1 45.09,134.04 ; H25.1 45.09,131.06 ; H25.1 41.57,132.55 ; 67.1,48.97 H28.1 ; H28.1 69.28,51.15 ; H28.1 68.7,52.75 ; H28.1 67.1,53.33 ; H28.1 68.7,49.55 ; H28.1 65.5,52.75 ; H28.1 64.92,51.15 ; H28.1 65.5,49.55 ; JHDMI1.20 11.65,93.73 ; JHDMI1.20 10.37,93.73 ; JHDMI1.20 10.37,91.97 ; JHDMI1.20 11.65,91.97 ; JHDMI1.20 12.93,93.73 ; JHDMI1.20 12.93,92.85 ; H23.1 8.6,76.08 ; H23.1 6.87,74.35 ; H23.1 10.33,74.35 ; H23.1 7.33,73.08 ; H23.1 7.33,75.62 ; H23.1 8.6,72.62 ; H23.1 9.87,75.62 ; H23.1 9.87,73.08 ; 293.31,70.37 JUSB1.11 ; JUSB1.11 294.5,71.2 ; JUSB1.11 292.13,70.37 ; JUSB1.11 292.13,71.2 ; JUSB1.11 294.5,70.37 ; JUSBC1.1 6.27,112.67 ; JUSBC1.1 5.12,112.67 ; JUSBC1.1 7.43,111.95 ; JUSBC1.1 6.27,111.23 ; JUSBC1.1 7.43,112.67 ; 6.27,101.63 JUSBC1.2 ; JUSBC1.2 5.12,101.63 ; JUSBC1.2 6.27,103.07 ; JUSBC1.2 7.43,102.35 ; JUSBC1.2 7.43,101.63 ; 78,130.52 H26.1 ; H26.1 80.03,132.55 ; H26.1 79.49,131.06 ; H26.1 75.97,132.55 ; H26.1 78,134.58 ; H26.1 79.49,134.04 ; H26.1 76.51,131.06 ; H26.1 76.51,134.04 ; JUSB2.4 15.83,59.78 ; JUSB2.4 15.2,59.58 ; JUSB2.4 16.47,59.58 ; JUSB2.4 15.83,58.12 ; JUSB2.4 16.66,58.95 ; JUSB2.4 16.47,58.31 ; JUSB2.11 6.88,70.98 ; JUSB2.11 8.07,70.15 ; JUSB2.11 8.07,70.98 ; JUSB2.11 5.7,70.98 ; JUSB2.11 5.7,70.15 ; 286.5,49.25 JSD1.10 ; JSD1.10 287.63,50.7 ; JSD1.10 287.63,49.25 ; JSD1.10 286.5,50.7 ; JSD1.10 285.37,49.25 ; JSD1.10 287.63,49.97 ; JSD1.10 285.37,50.7 ; JSD1.10 285.37,49.97 ; JUSB2.10 16.13,69.68 ; JUSB2.10 17.47,68.02 ; JUSB2.10 14.8,68.85 ; JUSB2.10 16.13,68.02 ; JUSB2.10 17.47,69.68 ; JUSB2.10 14.8,68.02 ; JUSB2.10 17.47,68.85 ; JUSB2.10 14.8,69.68 ; H15.1 5.55,100.43 ; H15.1 4.28,99.97 ; H15.1 6.82,99.97 ; H15.1 5.55,96.97 ; H15.1 7.28,98.7 ; H15.1 3.82,98.7 ; H15.1 6.82,97.43 ; H15.1 4.28,97.43 ; H3.1 143.56,89.84 ; H3.1 142,93.53 ; H3.1 142,89.27 ; H3.1 143.56,92.96 ; H3.1 140.44,92.96 ; H3.1 144.13,91.4 ; H3.1 139.87,91.4 ; H3.1 140.44,89.84 ; JUSB1.10 284.06,73.33 ; JUSB1.10 285.4,71.67 ; JUSB1.10 282.73,72.5 ; JUSB1.10 285.4,73.33 ; JUSB1.10 285.4,72.5 ; JUSB1.10 282.73,73.33 ; JUSB1.10 282.73,71.67 ; JUSB1.10 284.06,71.67 ; H38.1 165.37,132.93 ; H38.1 164.1,132.47 ; H38.1 165.83,134.2 ; H38.1 162.37,134.2 ; H38.1 162.83,132.93 ; H38.1 162.83,135.47 ; H38.1 165.37,135.47 ; H38.1 164.1,135.93 ; 297,89.72 JLOM1.15 ; JLOM1.15 298.68,89.72 ; JLOM1.15 295.32,89.72 ; JLOM1.15 295.32,90.55 ; JLOM1.15 298.68,90.55 ; JHDMI1.21 4.98,94.35 ; JHDMI1.21 4.98,95.38 ; JHDMI1.21 1.62,95.38 ; JHDMI1.21 1.62,94.35 ; JHDMI1.21 3.3,95.38 ; H4.1 83.76,92.96 ; H4.1 80.07,91.4 ; H4.1 80.64,92.96 ; H4.1 84.33,91.4 ; H4.1 80.64,89.84 ; H4.1 82.2,89.27 ; H4.1 82.2,93.53 ; H4.1 83.76,89.84 ; 148.65,135.75 H37.1 ; H37.1 152.08,134.3 ; H37.1 148.12,134.3 ; H37.1 148.65,132.85 ; H37.1 151.55,135.75 ; H37.1 151.55,132.85 ; H37.1 150.1,132.32 ; H37.1 150.1,136.28 ; 3.33,48.23 H24.1 ; H24.1 5.87,50.77 ; H24.1 6.33,49.5 ; H24.1 4.6,51.23 ; H24.1 2.87,49.5 ; H24.1 4.6,47.77 ; H24.1 5.87,48.23 ; H24.1 3.33,50.77 ; JLOM1.16 292.83,116.95 ; JLOM1.16 292.83,117.78 ; JLOM1.16 291.15,117.78 ; JSD1.11 287.63,63.57 ; JSD1.11 287.63,62.85 ; JSD1.11 286.5,64.3 ; JSD1.11 287.63,64.3 ; JSD1.11 286.5,62.85 ; JSD1.11 285.37,63.57 ; JSD1.11 285.37,64.3 ; JSD1.11 285.37,62.85 ; 4.28,114.33 H14.1 ; H14.1 6.82,114.33 ; H14.1 3.82,115.6 ; H14.1 5.55,117.33 ; H14.1 5.55,113.87 ; H14.1 4.28,116.87 ; H14.1 7.28,115.6 ; H14.1 6.82,116.87 ; H2.1 143.56,111.99 ; H2.1 140.44,111.99 ; H2.1 143.56,115.11 ; H2.1 142,111.42 ; H2.1 142,115.68 ; H2.1 139.87,113.55 ; H2.1 144.13,113.55 ; H2.1 140.44,115.11 ; JUSB1.4 285,81.76 ; JUSB1.4 284.36,83.23 ; JUSB1.4 283.73,81.76 ; JUSB1.4 284.36,81.57 ; JUSB1.4 283.73,83.03 ; JUSB1.4 283.54,82.4 ; 284.06,84.47 JUSB1.12 ; JUSB1.12 285.4,85.3 ; JUSB1.12 282.73,85.3 ; JUSB1.12 285.4,84.47 ; JUSB1.12 284.06,86.13 ; JUSB1.12 285.4,86.13 ; JUSB1.12 282.73,84.47 ; JUSB1.12 282.73,86.13 ; 286.4,66.47 H33.1 ; H33.1 284.67,68.2 ; H33.1 287.67,66.93 ; H33.1 286.4,69.93 ; H33.1 285.13,69.47 ; H33.1 288.13,68.2 ; H33.1 287.67,69.47 ; H33.1 285.13,66.93 ; 6.21,110.34 JUSBC1.B12 ; JUSBC1.B12 6.37,110.46 ; JUSBC1.B12 6.09,110.18 ; H7.1 275.9,104.53 ; H7.1 277.39,101.01 ; H7.1 274.41,101.01 ; H7.1 273.87,102.5 ; H7.1 274.41,103.99 ; H7.1 277.93,102.5 ; H7.1 275.9,100.47 ; H7.1 277.39,103.99 ; 285.04,78.9 JUSB1.7 ; JUSB1.7 285.23,78.27 ; JUSB1.7 285.87,78.07 ; JUSB1.7 285.23,79.54 ; JUSB1.7 286.5,79.54 ; JUSB1.7 285.87,79.73 ; JUSB1.7 286.5,78.27 ; JHDMI1.17 12.03,89.1 ; JHDMI1.17 10.87,89.1 ; JHDMI1.17 11.91,88.64 ; JHDMI1.17 10.99,89.56 ; JHDMI1.17 10.99,88.64 ; JHDMI1.17 11.91,89.56 ; 278.63,12.68 H16.1 ; H16.1 281.17,15.22 ; H16.1 278.63,15.22 ; H16.1 279.9,12.22 ; H16.1 281.63,13.95 ; H16.1 281.17,12.68 ; H16.1 279.9,15.68 ; H16.1 278.17,13.95 ; JHDMI1.5 12.03,83.1 ; JHDMI1.5 10.87,83.1 ; JHDMI1.5 11.91,82.64 ; JHDMI1.5 10.99,83.56 ; JHDMI1.5 10.99,82.64 ; JHDMI1.5 11.91,83.56 ; 14.33,61.62 JUSB2.7 ; JUSB2.7 13.7,63.08 ; JUSB2.7 15.16,62.45 ; JUSB2.7 14.33,63.28 ; JUSB2.7 14.97,63.08 ; JUSB2.7 14.97,61.81 ; JUSB2.7 13.7,61.81 ; H10.1 151.8,49.4 ; H10.1 148.4,52.8 ; H10.1 147.76,51.1 ; H10.1 150.1,53.44 ; H10.1 148.4,49.4 ; H10.1 151.8,52.8 ; H10.1 152.44,51.1 ; 12.54,81.14 JHDMI1.2 ; JHDMI1.2 13.58,81.6 ; JHDMI1.2 13.46,82.06 ; JHDMI1.2 13.46,81.14 ; JHDMI1.2 13,81.02 ; JHDMI1.2 12.54,82.06 ; JHDMI1.2 12.42,81.6 ; JHDMI1.11 12.03,86.1 ; JHDMI1.11 11.91,85.64 ; JHDMI1.11 11.91,86.56 ; JHDMI1.11 10.87,86.1 ; JHDMI1.11 10.99,86.56 ; JHDMI1.11 10.99,85.64 ; JUSB1.13 293.31,87.43 ; JUSB1.13 292.13,86.6 ; JUSB1.13 292.13,87.43 ; JUSB1.13 294.5,86.6 ; JUSB1.13 294.5,87.43 ; 224.02,83.52 SW1.4 ; SW1.4 224.78,83.28 ; SW1.4 224.78,85.29 ; SW1.4 223.78,84.28 ; SW1.4 225.78,84.28 ; SW1.4 224.02,85.04 ; SW1.4 225.54,83.52 ; SW1.4 225.54,85.04 ; 264.87,71.4 H8.1 ; H8.1 268.93,71.4 ; H8.1 268.39,72.89 ; H8.1 265.41,72.89 ; H8.1 266.9,73.43 ; H8.1 265.41,69.91 ; H8.1 266.9,69.37 ; H8.1 268.39,69.91 ; 294.97,50.7 JSD1.13 ; JSD1.13 294.97,49.25 ; JSD1.13 294.97,49.97 ; JSD1.13 297.23,50.7 ; JSD1.13 296.1,50.7 ; JSD1.13 296.1,49.25 ; JSD1.13 297.23,49.97 ; JSD1.13 297.23,49.25 ; JHDMI1.22 12.93,79.23 ; JHDMI1.22 10.37,77.47 ; JHDMI1.22 11.65,77.47 ; JHDMI1.22 11.65,79.23 ; JHDMI1.22 10.37,79.23 ; JHDMI1.22 12.93,77.47 ; JHDMI1.22 12.93,78.35 ; JSD1.12 299.3,64.3 ; JSD1.12 299.3,62.85 ; JSD1.12 298.17,63.57 ; JSD1.12 298.17,64.3 ; H1.1 83.76,115.11 ; H1.1 84.33,113.55 ; H1.1 82.2,111.42 ; H1.1 80.64,111.99 ; H1.1 80.64,115.11 ; H1.1 82.2,115.68 ; H1.1 83.76,111.99 ; H1.1 80.07,113.55 ; JLOM1.17 297,117.78 ; JLOM1.17 295.32,116.95 ; JLOM1.17 295.32,117.78 ; JLOM1.17 298.68,117.78 ; JLOM1.17 298.68,116.95 ; 14.8,56.88 JUSB2.12 ; JUSB2.12 17.47,56.88 ; JUSB2.12 14.8,56.05 ; JUSB2.12 14.8,55.22 ; JUSB2.12 17.47,56.05 ; JUSB2.12 16.13,56.88 ; JUSB2.12 17.47,55.22 ; JUSB2.12 16.13,55.22 ; 1.62,76.85 JHDMI1.23 ; JHDMI1.23 4.98,75.82 ; JHDMI1.23 3.3,75.82 ; JHDMI1.23 1.62,75.82 ; JHDMI1.23 4.98,76.85 ; 12.54,85.06 JHDMI1.8 ; JHDMI1.8 13.46,84.14 ; JHDMI1.8 13.58,84.6 ; JHDMI1.8 13.46,85.06 ; JHDMI1.8 12.42,84.6 ; JHDMI1.8 12.54,84.14 ; H20.1 296.1,28.28 ; H20.1 298.08,26.3 ; H20.1 297.55,24.85 ; H20.1 294.65,24.85 ; H20.1 294.12,26.3 ; H20.1 296.1,24.32 ; H20.1 294.65,27.75 ; H20.1 297.55,27.75 ; 289.47,90.55 JLOM1.14 ; JLOM1.14 291.15,89.72 ; JLOM1.14 292.83,90.55 ; JLOM1.14 292.83,89.72 ; JLOM1.14 289.47,89.72
  BOTTOM w0.127: PC124.2 v4(194.94,60.04) ; v4(69.14,91.57) v2(67.92,91.57)
  BOTTOM w0.152: UC1.AW10 126.89,92.99 128.05,92.99 UC1.AW8
  BOTTOM w0.178: UC1.H71 91.22,109.1 v2(91.1,108.98) ; UC1.BB26 118.26,90.61 118.26,90.1 v2(118.32,90.05) ; UC1.BB64 96.21,90.48 v2(96.21,90.13) ; UC1.AT71 91.19,94.49 v2(91.01,94.49) ; UC1.BB34 113.28,90.74 113.28,89.43 v2(113.31,89.4) ; UC1.BB60 98.56,90.14 v2(98.52,90.1) ; UC1.AM71 91.83,96.84 91.08,96.84 v2(91.02,96.79) ; UC1.BB30 115.91,90.36 115.91,89.97 v2(116.04,89.84) ; UC1.BB55 101.16,90.62 v2(101.16,90.03) ; v2(108.3,90.06) 108.33,90.08 UC1.BB43 ; UC1.BB38 110.94,91 110.94,90.05 v2(110.97,90.03)
  BOTTOM w0.203: UC1.C1 132.98,112.35 v2(133.06,112.42) ; v2(115.61,108.14) 115.61,108.8 UC1.J28 ; v2(94.55,92.83) UC1.AY66 UC1.BA66 ; v2(94.55,92.83) 94.66,92.83 94.93,93.1 UC1.AW66 95.09,93.01 96.06,93.01 UC1.AW64 96.59,92.96 96.62,92.99 96.92,92.99 96.95,92.96 UC1.AW62 97.82,92.96 97.85,92.99 98.14,92.99 98.17,92.96 UC1.AW60 99.04,92.96 99.08,92.99 99.37,92.99 99.4,92.96 UC1.AW57 100.32,92.96 100.35,92.99 100.64,92.99 100.68,92.96 UC1.AW55 101.55,92.96 101.58,92.99 101.87,92.99 101.9,92.96 UC1.AW53 102.77,92.96 102.8,92.99 103.1,92.99 103.13,92.96 UC1.AW51 103.94,92.96 103.97,92.99 104.26,92.99 104.29,92.96 UC1.AW49 105.2,92.96 105.23,92.99 105.52,92.99 105.55,92.96 UC1.AW47 106.36,92.96 106.39,92.99 106.69,92.99 106.72,92.96 UC1.AW45 107.59,92.96 107.64,93.01 107.79,93.01 107.81,92.99 107.87,92.99 107.87,93 107.88,92.99 107.91,92.99 107.94,92.96 108.43,92.96 UC1.AW43 ; v2(94.55,92.83) 94.1,93.29 UC1.AV68 ; UC1.AV68 94.06,93.3 94.06,93.67 94.11,93.72 94.11,93.9 94.06,94.07 UC1.AT68 94.06,94.88 94.09,94.91 94.09,95.2 94.06,95.23 UC1.AP68 94.06,96.1 94.09,96.13 94.09,96.43 94.06,96.46 UC1.AM68 ; UC1.AV68 93.87,93.29 93.68,93.1 ; v2(60.83,95.07) 60.9,95.01 PU612.3 ; v2(126.55,93.51) UC1.AU10 ; v2(126.55,93.51) UC1.AW10 126.86,92.96 126.86,92.7 v2(126.86,92.47) 126.86,91.75 UC1.BA10 ; v2(126.55,93.51) 126.01,92.96 UC1.AW12 125.27,92.96 125.24,92.99 124.95,92.99 124.92,92.96 UC1.AW14 124.1,92.96 v2(123.83,93.23) 123.55,92.95 123.26,92.95 UC1.AW16 122.85,92.96 122.82,92.99 122.53,92.99 122.5,92.96 UC1.AW18 121.58,92.96 121.55,92.99 121.25,92.99 121.22,92.96 UC1.AW21 120.43,92.96 120.4,92.99 120.11,92.99 120.08,92.96 UC1.AW23 119.11,92.96 119.08,92.99 118.78,92.99 118.75,92.96 UC1.AW26 117.88,92.96 117.85,92.99 117.55,92.99 117.52,92.96 UC1.AW28 116.65,92.96 116.62,92.99 116.33,92.99 116.3,92.96 UC1.AW30 115.43,92.96 115.39,92.99 115.1,92.99 115.07,92.96 UC1.AW32 114.24,92.96 v2(113.75,93.45) 113.38,93.09 UC1.AW34 112.9,92.96 112.87,92.99 112.57,92.99 112.54,92.96 UC1.AW36 111.67,92.96 111.64,92.99 111.35,92.99 111.32,92.96 UC1.AW38 110.6,92.96 v2(110.09,93.47) ; v2(133.06,100.13) 132.79,99.86 UC1.AF1 ; v2(94.55,96.64) 94.25,96.94 UC1.AM68 ; v2(110.09,108.14) UC1.J38 ; UC1.F40 v2(110.09,109.54) UC1.F38 ; v2(101.86,98.22) UC1.AL55 ; UC1.F1 132.48,110.47 v2(132.59,110.58) ; v2(100.04,98.22) UC1.AL58 ; UC1.K70 93.1,107.74 93.25,107.95 ; UC1.K71 91.61,107.74 91.36,107.49 v2(90.94,107.49) ; v2(117.23,107.91) 117.41,108.09 UC1.J25 ; v2(111.92,108.14) UC1.J35 ; UC1.BA1 132.35,91.21 131.96,91.32 UC1.BA2 ; UC1.D39 v2(109.74,111.85) UC1.B39 ; RV97.2 107.76,125.9 107.76,125.95 108.01,126.2 108.33,126.2 108.61,126.48 109.62,126.48 109.91,126.77 UV7.19 ; UC1.AL64 96.24,97.16 96.19,97.11 95.81,97.11 95.77,97.16 UC1.AL65 95.6,97.16 95.56,97.11 95.18,97.11 95.13,97.16 UC1.AL66 ; UC1.AM68 94.06,97.33 94.15,97.42 94.15,97.69 93.74,98.1 UC1.AK68 93.8,98.17 v2(94.14,98.51) 94.14,98.63 94.39,98.87 UC1.AH67 ; PU610.3 59.35,109.52 59.44,109.62 v2(60.41,109.62) ; UC1.P20 120.92,105.25 120.52,105.25 120.41,105.36 UC1.P21 ; v2(113.75,108.14) UC1.J32 ; UC1.G43 107.61,109.29 v2(107.33,109.57) ; UC1.AG71 v2(91.59,99.5) ; UC1.AF15 124.37,100.25 124.8,100.25 125.2,100.65 v2(125.45,100.65) 125.13,100.96 UC1.AD13 125.13,101.32 v2(125.53,101.71) ; v2(59.46,133.93) 58.57,133.93 58.25,133.61 JEDP1.15 ; UC1.AF63 97.09,99.75 97.09,99.04 UC1.AH63 ; UC1.AV1 132.96,93.17 v2(133.05,93.09) ; UC1.D48 UC1.D47 105.85,111.36 105.88,111.33 106.17,111.33 106.2,111.36 106.58,111.36 UC1.D45 UC1.D44 ; v2(103.69,98.22) UC1.AL52
  BOTTOM w0.254: UC1.G60 98.36,109.59 v2(98.26,109.59) ; UC1.AM60 98.52,97.05 98.45,97.12 97.82,97.12 UC1.AM61 ; v2(122.67,104.08) 122.67,104.21 UC1.T17 UC1.P17 ; UC1.AP18 122.41,95.73 v2(121.98,95.37) ; UV2.2 20.47,88.21 20.99,88.21 21.8,87.4 v2(21.99,87.4) 23.67,87.4 RV21.2 ; v2(121.98,95.37) 121.8,95.37 UC1.AR20 v2(121.07,94.74) 121.35,94.45 UC1.AT20 UC1.AU20 121.52,93.02 121.55,92.99 ; v2(121.98,95.37) UC1.AP20 121.1,95.94 v2(121.08,95.94) 121.52,96.39 UC1.AN20 ; UC1.AN63 96.72,96.31 96.58,96.16 96.56,96.16 v2(96.38,96.01) ; UC1.L20 121.04,106.98 120.59,106.54 120.59,106.41 UC1.N21 120.39,106.25 120.01,106.63 v2(120.01,106.72) ; UC1.AW18 v2(122.01,92.27) UC1.BA18 ; v2(59.4,93.8) 59.4,93.88 PH601.1 ; UC1.BB18 121.94,90.94 121.94,90.19 v2(122.04,90.09) ; JXDP1.26 v2(96.01,132.22) 96.01,131.15 96.31,130.85 JXDP1.25 ; v2(12.27,102.25) 12.16,102.35 DT10.2 ; v2(122.7,103.24) 122.34,103.6 UC1.V18 ; v2(122.7,103.24) 122.99,102.95 UC1.Y17 ; v2(122.7,103.24) 122.99,103.53 UC1.V17 ; UC1.AU15 124.18,93.82 123.89,93.6 v2(123.83,93.23) ; UC1.AL45 107.35,97.45 ; 107.35,97.45 106.96,97.05 UC1.AM45 v2(106.44,96.66) ; 107.35,97.45 107.35,97.43 107.72,97.05 UC1.AM43 ; CC21.2 115.52,118.8 115.59,118.8 115.82,118.56 115.82,117.54 115.64,117.36 v4(115.64,116.93) 115.64,115.87 v2(115.35,115.57) 114.38,115.57 114.02,115.94 114.02,117.38 113.79,117.61 112.23,117.61 111.97,117.87 111.97,118.55 112.23,118.81 112.24,118.81 CC22.2 ; UC1.AR28 v2(115.58,94.74) UC1.AT28 ; v2(94.55,96.64) 95.04,97.13 UC1.AL66 ; DT6.2 12.23,109.27 v2(12.33,109.17) ; DT6.2 11.25,109.27 v2(11.12,109.14) ; DT6.2 v2(11.71,108.74) 12.33,108.11 DT15.2 ; UC1.D62 97.36,111.33 v2(97.36,111.85) 97.35,111.85 UC1.B62 ; JNGFF3.1 28.95,44.53 v2(28.45,45.03) ; UC1.U10 127.08,103.85 UC1.W9 v2(128.07,102.7) ; UC1.A5 130.6,113.77 v2(131.09,113.77) ; JNGFF1.36 238.04,71.9 v2(237.97,71.97) ; UC1.AB18 122.34,101.89 v2(122.01,101.57) 122.01,101.5 UC1.AD19 ; v2(100.03,110.81) 100.01,110.81 100.47,110.59 UC1.E56 ; UC1.E11 126.1,110.77 125.99,110.87 v2(125.99,111.12) 126.34,111.36 UC1.D11 UC1.D10 UC1.B10 ; UZ12.16 160.83,108.22 v2(160.6,108.44) ; UC1.C5 129.96,112.01 v2(129.72,111.77) 129.72,111.5 UC1.D6 ; UC1.AT2 131.05,94.56 v2(130.94,94.44) 130.83,94.56 UC1.AT4 ; UC1.D14 v2(124.61,111.81) UC1.B14 ; UC1.AD16 123.28,100.81 v2(123.28,100.73) 123.28,100.62 UC1.AF17 ; UC1.D58 v2(99.83,111.84) UC1.B58 ; UC1.G45 106.63,109.55 v2(106.47,109.55) ; DT9.2 12.1,103.92 v2(12.23,104.05) ; DT9.2 11.12,103.92 v2(11.02,104.02) ; DT9.2 v2(11.64,104.45) ; UC1.W6 v2(129.96,102.71) 130.16,102.51 UC1.AA4 UC1.AA2 ; v2(108.27,96.01) UC1.AN42 ; UC1.AW36 v2(112.11,92.45) UC1.BA36 ; UC1.D44 v2(107.26,111.84) UC1.B44 ; v2(111.92,95.37) UC1.AP35 ; UC1.AR11 126.36,95.1 v2(126.55,95.3) 127.01,95.75 UC1.AP10 127.33,95.44 127.59,95.44 UC1.AR8 ; v2(59.46,115.48) 59.46,115.28 59.68,115.06 PU614.4 ; v2(96.38,95.37) UC1.AP63 ; UC1.AR50 v2(103.71,94.78) UC1.AR52 v2(102.78,94.78) ; v2(96.64,98.48) UC1.AK63 UC1.AM61 ; v2(96.64,98.48) UC1.AH63 ; v2(96.64,98.48) UC1.AH64 ; UC1.AK11 125.74,97.3 v2(125.63,97.3) 125.47,97.3 125.22,97.05 UC1.AM13 ; DT5.2 12.16,110.84 v2(12.29,110.97) ; DT5.2 11.19,110.84 v2(11.08,110.95) ; DT5.2 v2(11.71,111.37) ; UC1.AP32 v2(114.67,95.37) ; UC1.AL35 v2(112.84,96.66) ; v2(127.47,108.23) UC1.J8 ; v2(111.13,98.34) 111.01,98.22 UC1.AL38 ; UZ12.23 v2(157.83,106.62) ; UC1.AL2 131.2,97.45 v2(130.89,97.45) ; UC1.B53 v2(102.31,111.84) UC1.D53 102.1,111.11 102.1,110.79 102.29,110.59 UC1.E53 102.78,110.13 102.78,109.75 UC1.G52 ; JXDP1.8 v2(101.41,132.22) 101.41,131.3 101.71,131 JXDP1.7 ; v2(232.09,79.09) 232.15,79.15 JNGFF1.7 ; UC1.AW62 v2(97.38,92.45) UC1.BA62 ; UC1.AP38 v2(110.09,96.02) ; JXDP1.13 99.91,130.96 99.61,131.26 v2(99.61,132.22) JXDP1.14 ; PR428.2 157.25,131.19 PU402.6 ; v2(130.89,97.45) UC1.AJ4 ; v2(130.89,97.45) 130.65,97.21 UC1.AL4 ; UV7.11 113.11,127.92 112.55,128.47 v2(112.22,128.47) ; UC1.AR43 v2(108.27,95.37) UC1.AP42 ; UC1.BA23 v2(119.57,92.45) UC1.AW23 ; UC1.D66 v2(94.87,111.84) UC1.B66 ; UC1.D25 117.22,111.36 ; 117.22,111.36 117.29,111.44 117.29,111.86 ; 117.22,111.36 UC1.D26 ; UC1.AA65 v2(96.01,102.14) ; UC1.AT35 v2(111.92,94.74) UC1.AR35 ; v2(104.82,90.33) 104.74,90.41 UC1.BA49 ; JXDP1.50 v2(88.81,132.22) 88.81,131.92 89.11,131.62 JXDP1.49 ; UC1.AF4 130.2,99.86 v2(129.88,99.54) 129.88,99.12 UC1.AH6 ; UC1.L4 130.64,107.64 v2(130.93,107.64) 131.26,107.64 UC1.L2 ; UC1.AF2 UC1.AF1 ; v2(30.05,81.9) 30.77,81.9 RT101.2 ; UC1.AT63 v2(96.38,94.74) UC1.AR63 ; UC1.AN28 v2(115.58,96.01) UC1.AN30 ; UC1.BA71 91.28,91.15 v2(91.01,90.88) 91.21,90.69 UC1.BB70 ; UV7.19 109.91,128.35 v2(110.03,128.47) ; UC1.G6 128.4,109.52 v2(128.39,109.53) ; UC1.BA32 114.58,92.36 114.67,92.45 ; UC1.F32 114,109.94 v2(113.66,109.6) 113.33,109.94 UC1.F33 ; v2(91.06,92.92) 91.24,93.1 UC1.AV71 UC1.AV70 UC1.AV69 v2(93.57,93.1) 93.68,93.1 ; JXDP1.2 v2(103.21,132.22) 104.16,131.27 JXDP1.62 ; JXDP1.61 85.51,129.08 v2(85.8,128.79) 85.8,128.94 86.11,129.25 JXDP1.59 ; UC1.T21 120.16,104.52 119.9,104.27 v2(119.9,104.18) ; UC1.AP70 v2(93.45,95.67) UC1.AP68 ; v2(119.28,109.6) 119.58,109.29 UC1.G22 119.63,109.22 119.63,108.43 UC1.K22 ; v2(119.28,109.6) UC1.F22 ; v2(119.28,109.6) 119.13,109.6 UC1.F23 ; v2(171.53,68.5) 171.52,68.51 171.52,69.4 PR506.2 ; 114.67,92.45 114.58,92.54 UC1.AW32 ; 114.67,92.45 v2(114.67,92.46) ; v2(94.06,102.14) UC1.AA68 ; v2(11.06,102.22) 11.19,102.35 DT10.2 ; DT11.2 13.87,107.96 v2(13.93,108.02) ; PU401.6 141.38,132.02 v2(141.18,132.21) ; UC1.AW53 v2(102.34,92.45) UC1.BA53 ; UC1.BA28 v2(117.09,92.45) UC1.AW28 ; UC8.7 81.05,122.3 v2(81.3,122.55) ; UC1.U67 v2(94.71,103.97) UC1.U66 ; UC1.J42 v2(108.27,108.14) ; v2(125.54,102.65) 125.54,102.79 UC1.W13 ; v2(105.52,96.66) 105.62,96.66 105.98,96.97 UC1.AM46 105.98,97.07 UC1.AL48 ; UC1.U69 v2(92.76,103.97) UC1.U70 ; UC1.B18 v2(122.13,111.81) UC1.D18 ; v2(95.26,110.81) UC1.E65 ; UC1.K61 97.75,108.43 v2(97.2,108.98) 96.83,109.35 UC1.G63 ; v2(121.99,104.08) 121.99,104.17 UC1.T18 122.34,104.71 UC1.P19 ; DT12.2 v2(13.87,105.4) ; UC1.AB8 128.41,102.13 128.7,101.85 v2(128.7,101.73) 128.7,101.49 128.38,101.18 UC1.AD8 128.38,100.96 128.69,100.65 v2(128.69,100.61) ; v2(112.84,96.01) UC1.AN33 ; UC1.AM61 v2(97.29,96.66) ; v2(99.12,109.54) UC1.G58 ; v2(99.12,95.37) UC1.AP58 ; JEDP1.25 v2(63.25,133.81) ; UC1.B48 104.81,112.31 104.82,112.31 105.02,112.11 105.02,111.81 UC1.D47 105.46,111.11 105.58,110.99 v2(105.58,110.86) 105.6,110.84 105.73,110.84 UC1.E46 ; JXDP1.31 94.51,130.87 94.21,131.17 v2(94.21,132.22) JXDP1.32 ; v2(111.92,96.01) UC1.AN35 ; v2(127.47,96.65) 127.48,96.65 127.88,97.05 UC1.AM8 128.38,97.51 UC1.AK8 ; UC1.BA2 UC1.AY3 130.96,91.97 130.49,92.44 v2(130.39,92.44) ; UC1.L18 122.3,107.04 v2(122.02,106.67) 121.69,106.25 UC1.N19 121.69,106.09 v2(121.35,105.76) 121.35,105.63 121.08,105.36 UC1.P20 ; v2(111.78,119.7) 111.76,119.72 v2(111.76,121.25) 111.76,122.69 111.96,122.9 115.92,122.9 116.08,122.74 116.08,119.57 v2(115.97,119.47) ; UC1.B34 v2(112.22,111.85) UC1.D34 ; UC1.R13 125.42,105.62 v2(125.42,105.85) 125.42,106.11 UC1.N13 ; RC122.2 98.11,128.06 JXDP1.19 98.11,130.98 97.81,131.28 97.81,132.22 v2(97.81,132.22) JXDP1.20 ; UC1.AR58 v2(99.12,94.74) UC1.AT58 ; v2(115.58,95.37) UC1.AP28 ; UC1.Y19 121.58,102.74 121.15,102.74 UC1.Y20 UC1.Y21 120.39,102.94 v2(119.92,103.4) ; v2(91.06,91.8) UC1.AY71 ; UC1.F35 111.99,109.55 v2(111.97,109.55) 111.85,109.55 UC1.F37 ; v2(30.05,80.15) 29.88,80.15 CT87.2 ; UC1.G10 126.84,109.46 v2(126.56,109.46) ; v2(118.32,96.01) UC1.AN23 ; UC1.AW41 v2(109.63,92.45) UC1.BA41 ; UC1.BB6 UC1.BA6 v2(129.27,92.42) 129.27,92.92 UC1.AW6 ; UC1.AW57 v2(99.86,92.45) UC1.BA57 ; UC1.K63 UC1.K64 v2(95.99,107.65) UC1.K65 v2(95.34,107.65) UC1.K66 ; UC1.AR16 123.72,94.74 v2(123.81,94.74) UC1.AR15 ; UC1.BA14 v2(124.43,92.44) UC1.AW14 ; UC1.L8 v2(128.67,106.86) ; 117.29,111.86 v2(117.29,111.86) ; 117.29,111.86 117.69,111.86 UC1.C25 ; UC1.L16 v2(123.31,106.57) UC1.L17 ; v2(115.5,109.6) 115.85,109.94 UC1.F28 116.3,110.2 116.69,110.2 UC1.F27 ; UZ12.9 160.83,111.72 v2(160.6,111.49) ; v2(109.18,96.01) UC1.AN40 ; UC1.U63 v2(96.66,103.97) UC1.U64 ; PU200.15 65.59,70.21 v2(65.49,70.31) ; v2(100.95,109.54) UC1.G55 ; JNGFF1.51 v2(232.2,68.15) ; v2(97.94,101.22) UC1.AD62 ; UC1.AR55 v2(100.95,94.78) ; UC1.N6 129.69,106.09 v2(129.41,105.81) ; UC1.J11 126.07,107.99 v2(125.61,108.27) 125.18,108.01 UC1.J13 ; JNGFF1.1 232.68,80.65 232.47,80.44 232.12,80.44 232.12,80.44 v2(232.11,80.44) ; UC1.AB16 123.98,102.35 v2(123.98,102.43) 124.29,102.12 UC1.AB15 ; v2(107.15,92.45) UC1.BA45 ; UC1.AT23 v2(118.32,94.74) UC1.AR23 ; v2(118.32,95.37) UC1.AP23 ; v2(120.03,102.4) 120.39,102.05 UC1.AB21 ; v2(126.79,100.61) 126.79,100.3 UC1.AF10 ; PU200.4 v2(69.79,70.66) ; v2(155.57,111.78) 155.64,111.72 UZ12.32 ; UC1.AT42 v2(108.27,94.74) UC1.AR42 ; v2(94.2,90.16) UC1.BB67 ; UC1.K16 124.27,108.51 UC1.H15 v2(123.81,108.93) ; 93.25,107.95 UC1.K68 UC1.K67 v2(94.75,107.65) ; JXDP1.37 92.71,130.79 92.41,131.09 v2(92.41,132.22) JXDP1.38 ; JEDP1.39 v2(70.25,133.81) ; UC1.AR45 v2(106.44,94.74) UC1.AR46 ; JEDP1.28 v2(64.75,133.81) 64.25,133.31 JEDP1.27 ; v2(104.61,109.54) UC1.G48 ; UC1.F2 v2(130.96,110.55) UC1.F4 ; v2(94.24,109.54) UC1.G66 ; UC1.T15 123.98,104.21 v2(123.98,104.1) 123.98,104.02 UC1.V16 ; v2(121.98,110.81) UC1.E18 ; UC1.E50 104.1,110.59 v2(103.69,111) ; UC1.F68 UC1.D69 93.01,110.97 v2(93.01,110.97) ; UC1.L11 126.71,107.07 126.71,106.8 127.08,106.43 UC1.N10 126.54,105.85 v2(126.16,105.85) ; v2(91.1,111.03) 91.24,110.9 UC1.E71 ; UC1.A67 94.2,113.49 93.78,113.91 v2(93.78,114.09) ; v2(100.95,96.66) 100.99,96.66 101.41,97.02 UC1.AM55 ; UC1.F13 v2(124.71,110.21) UC1.E15 ; v2(127.47,110.18) UC1.F8 ; DT10.2 v2(11.64,101.82) ; v2(116.41,99.03) 116.41,98.99 116.95,98.45 UC1.AK27 ; UC1.AR53 v2(101.86,94.78) ; UC1.F42 108.98,110.2 v2(109.16,110.2) ; v2(89.11,128.79) 89.11,128.67 CC33.2 ; JEDP1.8 v2(54.75,131.65) ; v2(114.67,98.22) UC1.AL32 ; v2(62.86,131.71) 62.75,131.82 JEDP1.24 ; UC1.B22 v2(119.65,111.85) UC1.D22 ; JEDP1.23 v2(62.25,133.81) ; v2(96.01,105.8) UC1.N65 ; v2(121.92,108.93) UC1.H18 UC1.K18 ; UC1.B71 91.59,113.05 v2(91.59,113.37) 92.19,113.37 UC1.A70 ; UV7.52 116.71,131.14 v2(116.58,131.01) ; v2(92.58,100.77) UC1.AE69 UC1.AE68 UC1.AE67 UC1.AE66 UC1.AE65 UC1.AE64 UC1.AF63 ; UC1.B30 114.47,112.11 v2(114.47,111.82) 114.47,111.55 UC1.D30 ; UC1.AN37 v2(111.01,96.01) UC1.AN38 ; UC1.AU38 v2(110.09,93.47) ; UC1.E6 v2(128.36,110.91) ; UC1.AM25 UC1.AM27 v2(116.5,96.66) ; UC1.AL28 116.5,98.19 v2(116.42,98.26) ; UC1.R6 130.08,104.85 v2(130.08,104.85) 130.08,104.85 130.4,105.16 UC1.T4 UC1.T2 ; UC1.G5 v2(129.35,109.6) ; v2(94.06,105.8) UC1.N68 ; UC1.E21 120.37,110.83 v2(120.16,110.83) ; JEDP1.4 v2(52.75,131.65) ; UC1.AK69 93.07,98.17 93.25,98.35 93.56,98.35 UC1.AK68 ; UC1.AN32 v2(114.67,96.02) ; v2(99.12,96.01) UC1.AN58 ; v2(104.61,94.74) UC1.AR48 ; v2(129.3,94.74) UC1.AR5 ; v2(113.75,93.45) UC1.AU32 ; JEDP1.6 v2(53.75,131.65) ; v2(100.04,94.1) UC1.AT56 ; DT8.2 v2(14.63,105.61)
  BOTTOM w0.305: v2(232.32,69.42) 232.4,69.42 232.63,69.65 JNGFF1.45 ; JXDP1.63 84.86,131.3 85.19,131.63 v2(85.19,132.22) ; JUSH1.10 228.95,57.08 v2(228.82,56.95) ; JUSH1.25 v2(221.45,56.61) ; JNGFF1.18 240.14,76.4 v2(239.37,77.18) ; v2(14.8,45.03) 14.8,44.86 14.95,44.71 JNGFF3.57 ; v2(243.45,55.54) JESPI.9 ; v2(231.9,105.48) 231.43,105.48 231.2,105.25 JNGFF2.19 ; v2(11.02,108.39) 11.01,108.41 CT99.2 ; JNGFF1.24 238.72,74.9 v2(238,75.63) ; JNGFF1.33 234.27,72.65 234.54,72.38 v2(234.54,72.17) ; JNGFF2.31 231.25,102.25 v2(231.48,102.02) ; v2(234.53,66.05) 234.53,65.54 234.14,65.15 JNGFF1.63 ; JKBTP1.12 208.55,59.55 208.88,59.88 211.24,59.88 211.55,59.57 JKBTP1.6 211.55,57.88 v2(211.62,57.81) ; JNGFF3.15 v2(25.45,45.03) ; JKBTP1.1 214.05,59.54 213.75,59.85 212.85,59.85 212.55,59.54 JKBTP1.4 212.55,58.34 212.81,58.08 v2(212.81,57.78) ; JNGFF1.29 231.33,73.65 v2(231.17,73.81) ; JNGFF1.75 v2(234.49,62.15) ; v2(231.61,110.95) 231.41,110.95 231.21,110.75 JNGFF2.5 ; v2(231.77,74.89) 232.03,75.15 JNGFF1.23 ; v2(234.49,63.65) JNGFF1.69 ; JNGFF2.63 v2(229.14,94.25) ; v2(16.63,45.03) 16.63,44.81 16.45,44.63 JNGFF3.51 ; v2(231.68,70.96) 231.99,71.27 232.5,71.27 232.62,71.15 JNGFF1.39 ; JNGFF2.65 229.26,93.75 v2(229.14,93.62) ; v2(28.15,67.86) 27.88,67.59 JDB1.6 ; JKBTP1.19 205.05,57.94 v2(205.22,57.77) ; v2(290.41,121.36) 290.41,121.61 290.64,121.84 JDEG1.10 ; v2(205.84,57.83) 205.84,57.95 205.55,58.24 JKBTP1.18 ; v2(232.05,103.78) 231.99,103.72 231.38,103.72 231.35,103.75 JNGFF2.25 ; v2(231.57,99.43) 231.39,99.25 JNGFF2.43 ; JNGFF2.37 v2(231.61,100.75) ; v2(231.27,57.86) 230.95,58.18 JUSH1.6 ; v2(231.61,109.1) 231.35,109.1 231.21,109.25 JNGFF2.11 ; v2(28.45,45.03) JNGFF3.3 ; UC1.AB21 UC1.AD21 120.48,101.26 120.95,101.26 UC1.AD20 ; JUSH1.24 v2(221.95,55.98) ; PR412.1 v2(136.99,133.36) ; JNGFF1.30 238.86,73.4 v2(238.46,73) ; v2(230.45,57.85) JUSH1.7 ; JNGFF3.39 v2(19.45,45.03) ; JNGFF3.21 v2(23.95,45.03) ; JNGFF3.33 v2(20.95,45.03) ; v2(96.38,96.64) 96.34,96.69 UC1.AL64 ; v2(231.57,97.6) 231.42,97.75 JNGFF2.49 ; JNGFF1.57 v2(234.53,66.65) ; JNGFF3.45 v2(17.95,45.03) ; JNGFF2.3 v2(229.21,111.25) ; JNGFF3.27 v2(22.45,45.03) ; JNGFF3.9 v2(26.95,45.03)
  BOTTOM w0.356: CC30.2 v2(84.03,121.69) ; v2(159.74,113.33) 160.06,113.33 160.68,113.96 160.68,114.29 160.55,114.41 CZ75.2 ; UC12.3 v2(152.58,114.68)
  BOTTOM w0.381: JIR1.4 37.69,131.7 37.43,131.96 v2(37.23,131.96) ; CZ51.2 156.89,115.83 CZ52.2 ; v2(29.88,87.96) 29.88,87.76 30.44,87.2 RT100.2 ; PC604.2 43.31,97.8 v2(42.7,97.19) 43.29,96.59 PC603.2 ; v2(37.23,132.54) 37.62,132.54 37.85,132.3 JIR1.5 ; v2(97.18,122.14) CC305.2 ; RC227.2 151.8,117.65 151.18,118.27 v4(150.49,118.27) 149.12,118.27 v2(148,117.16) ; CC9.2 152.36,102.41 v2(152.68,102.09) ; CI7.2 v2(18.18,54.09) ; PC944.2 55.7,52.11 v2(55.7,51.45) ; PU1201.4 42.39,54.09 v2(42.54,54.24) ; v2(238.59,83.2) 238.86,83.46 QE2.1 ; CZ54.2 v2(156.32,104.62) ; CT100.2 v2(8.79,111.71) ; CT101.2 11.01,105.69 v2(11.02,105.7) ; RT81.2 32.22,87.89 v2(31.77,88.34) ; PH603.1 PR662.2 v2(56.04,111.09) ; CD32.2 v2(68.57,83.58) ; RT71.2 33.74,79.83 33.42,80.15 v2(32.99,80.15) ; CC22.2 112.42,119.21 112.1,119.21 111.78,119.53 v2(111.78,119.7) ; RV80.2 120.23,133.47 v2(120.67,133.91) 121.12,133.47 RV82.2 ; PQ1207.4 v2(45.53,51.78) ; CL8.2 CL3.2 v2(249.71,129.04) ; v2(247.55,124.66) 247.25,124.95 CL9.2 ; v2(94.7,117.68) 94.42,117.96 94.42,118.46 94.5,118.54 CC321.2 CC312.2 ; PQ1208.1 v2(41.68,50.48) ; v2(43.46,93.2) 43.53,93.13 43.71,93.13 43.99,92.85 PC602.2 ; PC601.2 50.62,101.4 v2(50.62,100.93) ; PC949.1 45.25,54.35 v2(45.5,54.1) PU903.3 ; v2(152.53,95.95) 152.51,95.93 CC10.2 ; v2(56.01,118.63) 56.01,119.59 PU1.3 ; DE1.2 v2(239.74,120.15) ; v2(40.04,107.01) PQ1204.1 ; v2(40.07,105.85) 40.15,105.85 40.16,105.85 41.6,105.85 41.89,105.57 PQ1204.4 ; v2(15.95,91.07) 16,91.02 CV39.2 ; PQ1210.1 v2(53.3,51.78) ; v2(288.82,123.84) 289.28,123.38 RE86.2 ; v2(115.97,119.47) 115.73,119.23 115.35,119.23 CC21.2 ; CL15.2 v2(252,133.61) ; CC316.2 v2(148.11,89.36) ; PQ1208.4 43.15,51.78 43.56,51.37 43.56,50.75 43.83,50.48 PQ1207.1 v2(44.94,50.48) ; RT82.2 31.14,87.91 v2(31.14,88.34) ; PC1204.2 35.98,63.26 36.35,62.89 36.35,62.03 36.78,61.6 v2(36.78,61.4) 36.88,61.3 PU1200.3 ; PQ1210.4 v2(51.42,50.48) ; UV2.2 19.36,87.62 17.66,87.62 17.38,87.89 CV41.2 ; RT377.2 29.69,82.26 v2(30.05,81.9) ; v2(11.02,105.12) 11.01,105.1 CT102.2 ; UD1.3 71.95,82.86 71.78,82.69 v2(71.78,82.24) ; v2(236.9,85.64) 236.99,85.73 QE2.4
  BOTTOM w0.406: UL2.3 v2(255.7,131.44) ; v2(157.12,117.65) 157.12,117.75 156.68,118.2 UC7.3
  BOTTOM w0.457: v2(90.84,128.79) 90.84,128.39 CC307.2 ; v2(83.99,123.96) 83.99,124.2 82.89,125.3 RC136.2 ; PC206.2 63.57,69.85 v2(63.84,70.11) 63.59,70.37 PR207.1 ; v2(90,118.25) CC301.2 CC310.2 ; CC303.2 CC304.2 99.02,119 v2(98.71,118.69) ; RC338.2 RC337.2 138.21,114.32 v2(138.3,114.23) ; PC1201.1 35.37,58.7 v2(34.99,58.32) ; QE13.2 v2(239.55,131.48) ; v2(154.84,131.39) 155.27,131.39 PR424.2 ; v2(109.4,124.06) 109.24,124.22 CV96.2 ; v2(159.47,91.69) 159.65,91.51 UC5.4 ; RC65.2 156.89,117.42 v2(157.12,117.65) ; CC318.2 v2(140.98,101.47) ; PC410.2 PR427.2 141.3,132.33 v2(141.18,132.21) ; CMOS1.2 129.72,83.04 v2(129.82,82.94)
  BOTTOM w0.508: JRTC1.2 v2(282.7,8.05) ; v2(292.25,47.71) 292.25,47.39 293.14,46.51 CA13.1 ; UT7.2 20.92,66.88 20.85,66.81 v2(20.85,66.5) ; PC1012.2 v2(75.02,112.91) ; JFAN1.6 235.31,116.36 v2(235.66,116.71) ; PC1061.2 v2(76.22,112.91) ; JNGFF1.76 234.77,60.43 v2(234.77,60.06) ; CL4.2 v2(250.66,130.48) ; v2(236.57,53.96) 235.77,54.75 JUSH1.28 ; JKBTP1.21 v2(216.37,53.34) ; DA3.1 291.27,45.22 v2(291.62,44.88) ; v2(282.95,61.48) 282.36,62.07 JSIM1.5 ; JESPI.11 250.21,51.7 v2(250.47,51.45) ; CN64.2 v2(29.3,48.03) ; JUSH1.27 218.62,53.77 v2(218.18,53.33) ; JEDP1.44 70.93,128.8 71.83,129.7 v2(71.83,130.62) ; v2(291.75,5.29) JLED1.8 ; JDEG1.12 v2(295.24,128.44) ; DA1.1 282.03,36.05 v4(282.03,33.26) 282.03,30.64 DA2.1 281.43,30.05 v2(281.43,29.27) ; PC1013.2 v2(84.22,105.04) ; PC1174.2 v2(86.64,107.9) ; JSIM1.6 v2(282.02,51.82) ; PC312.2 150.65,84.85 v2(150.52,84.97) ; JNGFF2.69 v2(229.13,92.15) ; v2(159.47,97.42) UC6.4 ; v2(158.99,115.83) 159.36,115.83 159.69,115.49 RZ111.2 ; RC372.2 v2(138.36,108.28) RC401.2 ; v2(15.92,87.73) 16.75,87.73 CV41.2 ; v2(126.26,122.95) 126.26,122.41 CC220.2 ; JEDP1.42 52.1,129.38 v2(52.84,130.12) ; CA12.2 v2(292.07,44.41) ; JSIM1.8 v2(291.2,47.95) ; v2(280.03,59.47) 279.93,59.37 CZ40.2 ; CE32.2 v2(240.31,118.17) ; v2(154.99,87.72) 155.22,87.49 PR311.2 PR302.2 ; PC1071.2 v2(80.61,107.9) ; v2(133.63,133.93) 132.69,133.93 JUART1.5 132.2,134.06 127.81,134.06 JUART1.6 ; CC319.2 140.28,105.02 139.85,104.58 v2(138.87,104.58) ; JKBTP1.22 202.22,54.83 v2(202.54,54.52) ; CZ39.2 v2(278.52,55.14) ; JRTC1.3 v2(280.15,8.61) ; PQ909.3 51.73,56.34 PR927.2 51.73,57.7 52.34,58.32 v2(52.87,58.32) ; PR948.2 59.04,53.03 59.78,52.3 v2(60.25,52.3) ; PC1176.2 v2(83.02,101.48) ; v2(127.98,122.95) 127.98,122.41 CC221.2 ; PC1075.2 v2(86.64,105.04) ; PC10.2 62.9,119.15 v2(62.44,118.69) ; JFAN1.5 v2(235.48,125.21) ; PC1070.2 v2(81.81,105.04) ; CZ52.2 156.42,115.62 v2(155.84,116.2) ; v2(86.31,121.67) RC113.2 86.32,120.65 RC112.2 RC110.2 ; JFAN1.1 v2(237.68,122.66) ; CE503.2 v2(238.26,127.53) ; CC300.2 RC109.2 v2(84.48,120.47) ; RV84.2 124.19,132.74 v2(124.49,133.04) ; v2(50.73,120.31) 51.23,119.82 PQ6.3 ; v2(232.13,81.04) 232.84,81.75 JNGFF1.77 ; v2(154.59,108.78) 154.21,109.16 RZ62.2 ; PC1009.2 v2(83.02,107.9) ; v2(276.81,58.48) 276.82,58.49 RZ334.2 ; v2(157.24,132.78) PC420.2 PR428.2 ; PC416.2 v2(148.49,127.46) ; PC1177.2 v2(81.75,101.48) ; JEDP1.45 73.15,133.26 72.48,133.93 v2(71.91,133.93) ; PC1072.2 v2(85.43,105.04) ; v2(121.15,130.75) 120.83,130.75 120.27,130.19 RV90.2 ; DI5.1 v2(279.8,79.96) ; PC128.2 PR116.2 v2(151.84,79.72) ; v2(35.43,128.95) JIR1.8 38.49,127.29 CZ3.2 ; PC1146.2 v2(73.8,119.48) ; v2(250.72,118.57) 250.72,118.95 250.4,119.26 UE9.4 ; JDB1.7 v2(32.48,62.24) ; JSIM1.4 v2(291.02,64.74) ; CZ41.2 CZ37.2 278.99,61.15 279.36,60.78 v2(279.36,60.4) ; v2(290.11,9.93) 290.24,9.81 JLED1.7 ; JSIM1.C5 v2(298.67,61.35) ; PC1008.2 v2(73.81,112.91) ; RZ25.2 284.19,12.58 v2(284.06,12.46) ; JRTC1.4 v2(286.5,4.3) ; v2(281.46,19.63) 280.95,19.63 280.76,19.82 DA7.1 ; JESPI.12 v2(241.67,51.7) ; PR505.2 PC505.2 175.91,67.04 v2(175.91,68.01) ; RC268.2 RC4.2 138.31,95.65 138.58,95.93 140.71,95.93 v2(140.93,96.15) ; JEDP1.43 62.1,128.8 v2(63.23,129.93) ; PC1172.2 v2(84.22,107.9) ; PC1142.2 v2(76.21,119.48) ; PC1175.2 v2(81.75,98.69) ; PC1178.2 v2(83.02,98.69) ; UZ35.3 124.47,129.36 124.47,128.64 v2(124.43,128.6) ; PC1010.2 v2(81.81,107.9) ; JSIM1.7 v2(283.71,50.3) ; PC1173.2 v2(85.43,107.9) ; v2(160.96,103.95) CZ56.2 ; PC415.2 v2(148.49,128.66) ; JDEG1.11 v2(292.57,119.74) ; JUART1.4 v2(131.21,133.23) ; v2(121.25,126.03) 120.95,126.03 120.47,125.55 RV94.2 ; v2(33.5,60.86) 33.85,60.86 34.35,60.35 PQ1212.3 ; PC1069.2 v2(80.61,105.04) ; PC661.2 v2(61.68,110.31) ; JLED1.4 v2(290.73,6.11) ; JDB1.8 v2(25.78,61.63) ; JEDP1.41 48.91,130.75 v2(49.87,131.71) ; v2(155.38,116.69) 154.77,116.08 CZ58.2 CZ57.2 ; PC1006.2 v2(83.02,105.04) ; PR103.2 v2(181.15,59.83) ; PQ1216.3 v2(60.77,50.67) ; RC219.2 88.62,124.46 87.6,125.48 v2(87.6,125.69) RC139.2 ; PC1144.2 v2(75,119.48) ; v2(147.27,113.78) 147.51,113.54 CC302.2 ; v2(256.86,124.32) 255.53,124.32 CL22.1 255.6,124.98 v2(256.86,124.98) ; DI2.1 v2(22.08,59.51) ; DA6.1 v2(281.46,23.76)
  vias: v2(0.85,115.12) v2(0.85,100.06) v2(0.84,98.21) v2(0.84,96.52) v2(0.87,112.08) v2(0.86,102.22) v2(2.03,117.57) v2(2.03,115.85) v2(2.04,51.65) v2(2.07,53.16) v2(2.06,47.32) v2(2.06,45.59) v2(2.06,43.86) v2(2.06,42.14) v2(2.06,36.83) v2(2.44,98.79) v2(2.37,40.75) v2(2.51,96.52) v2(2.49,35.55) v2(2.69,49.5) v2(3.14,54.14) v2(3.17,71.45) v2(3.17,69.72) v2(3.52,117.65) v2(3.64,115.6) v2(3.58,112.06) v2(3.64,98.7) v2(3.65,51.15) v2(3.65,47.85) v2(3.68,102.23) v2(3.82,55.21) v2(3.78,36.83) v2(4.1,40.75) v2(4.21,35.55) v2(4.6,117.25) v2(4.6,113.95) v2(4.6,100.35) v2(4.6,97.05) v2(4.72,112.57) v2(4.75,101.57) v2(4.86,71.7) v2(4.9,69.72) v2(5.04,73.61) v2(5.05,39.42) v2(5.05,37.69) v2(5.55,55.21) v2(5.55,51.15) v2(5.55,47.85) v2(5.94,35.55) v2(6.5,117.25) v2(6.5,113.95) v2(6.5,100.35) v2(6.5,97.05) v2(6.5,49.5) v2(6.69,74.35) v2(6.67,42.52) v2(6.7,39.97) v2(7.29,37.96) v2(7.29,37.32) v2(7.45,115.6) v2(7.45,98.7) v2(7.65,76) v2(7.65,72.7) v2(7.67,35.55) v2(7.92,110.42) v2(8.05,103.52) v2(8.23,53.2) v2(8.27,55.21) v2(8.51,103.11) v2(8.61,40.77) v2(8.61,39.04) v2(8.85,45.41) v2(8.85,44.78) v2(9.23,69.71) v2(9.36,44.33) v2(9.55,76) v2(9.55,72.7) v2(9.61,43.7) v2(9.8,51.12) v2(10.04,99.17) v2(10.04,96.56) v2(9.99,55.21) v2(10.14,116.5) v2(10.5,74.35) v2(10.96,69.71) v2(11.1,114.85) v2(11.44,53.2) v2(11.72,55.21) v2(12.29,70.05) v2(13,114.85) v2(13.61,55.19) v2(13.75,68.51) v2(13.95,116.5) v2(14.37,71.36) v2(14.59,56.5) v2(14.76,98.26) v2(15.01,110.91) v2(15.04,102.3) v2(15.33,76.21) v2(15.33,75.58) v2(15.78,107.8) v2(16.05,105.54) v2(16.18,99.17) v2(16.27,117.66) v2(16.34,98.25) v2(16.63,50.31) v2(17.42,106.75) v2(17.64,48.91) v2(17.8,110.63) v2(17.99,117.66) v2(18.29,103.13) v2(18.69,49.37) v2(19.07,108.47) v2(19.15,101.69) v2(19.51,49.44) v2(19.72,117.66) v2(19.71,85.56) v2(19.71,83.7) v2(19.71,81.88) v2(20.24,107.94) v2(20.24,106.18) v2(20.85,65.9) v2(20.91,49.35) v2(21.3,57.99) v2(21.3,57.35) v2(21.3,56.72) v2(21.45,117.66) v2(21.42,66.24) v2(21.84,107.91) v2(21.92,85.66) v2(21.98,100.68) v2(22.12,104.5) v2(22.12,102.73) v2(22.15,83.73) v2(22.15,80.1) v2(22.06,52.36) v2(22.06,51.76) v2(22.3,50.36) v2(22.83,83.78) v2(22.95,78.12) v2(23.14,67.32) v2(23.18,117.66) v2(23.24,85.38) v2(23.52,78.12) v2(23.65,74.27) v2(23.65,73.67) v2(23.67,63.31) v2(23.77,67.32) v2(24.9,117.73) v2(24.9,61.35) v2(25.35,127.82) v2(25.35,126.1) v2(25.35,124.37) v2(25.35,122.64) v2(25.35,120.91) v2(25.35,119.19) v2(25.74,73.1) v2(26.38,73.1) v2(26.66,104.6) v2(26.66,103.19) v2(27.07,127.82) v2(27.15,126.38) v2(27.15,125.74) v2(27.49,81.85) v2(27.77,106.02) v2(27.77,104.6) v2(27.77,103.19) v2(27.77,101.78) v2(28.8,127.82) v2(28.89,104.6) v2(28.89,103.19) v2(29.13,110.15) v2(29.46,89.55) v2(30.53,127.82) v2(30.57,40.61) v2(30.8,39.04) v2(30.82,35.56) v2(31.27,97.42) v2(32.09,37.96) v2(32.09,37.33) v2(32.26,127.82) v2(32.55,35.56) v2(33.19,47.35) v2(33.65,44.51) v2(33.67,43.06) v2(33.67,41.34) v2(33.67,39.61) v2(33.67,37.88) v2(33.67,36.16) v2(33.93,128) v2(34,107.26) v2(34,105.48) v2(34,103.71) v2(34,101.93) v2(34,100.15) v2(34,96.59) v2(34,94.75) v2(34.24,131.49) v2(34.24,129.77) v2(34.28,134.88) v2(34.28,133.16) v2(34.37,49.4) v2(35.55,133.85) v2(36,134.88) v2(36.73,49.4) v2(37.73,134.88) v2(38.66,49.08) v2(39.46,134.88) v2(40.09,116.79) v2(40.09,116.15) v2(40.09,86.5) v2(40.73,116.79) v2(40.73,116.15) v2(40.79,75.19) v2(40.79,74.56) v2(40.79,73.92) v2(40.79,73.29) v2(40.79,72.65) v2(40.92,49.08) v2(41.18,134.88) v2(41.36,116.79) v2(41.36,116.15) v2(41.43,75.89) v2(41.43,75.19) v2(41.43,74.56) v2(41.43,73.92) v2(41.43,73.29) v2(41.43,72.65) v2(42,116.79) v2(42,116.15) v2(42.12,76.02) v2(42.44,76.59) v2(42.51,49.08) v2(42.63,116.79) v2(42.63,116.15) v2(42.76,76.02) v2(43.08,77.23) v2(43.08,76.59) v2(43.46,95.06) v2(43.58,90.64) v2(43.71,77.23) v2(43.71,76.59) v2(44.23,49.08) v2(44.32,134.88) v2(45.3,79.39) v2(45.3,78.75) v2(45.3,76.6) v2(45.3,75.97) v2(45.96,49.08) v2(46.19,136.41) v2(47.69,49.08) v2(47.92,136.41) v2(48.61,95.69) v2(48.61,94.17) v2(48.61,92.64) v2(49.41,49.08) v2(49.64,136.41) v2(50.13,95.69) v2(50.13,94.17) v2(50.13,92.64) v2(50.49,68.97) v2(50.49,68.34) v2(50.49,67.7) v2(51.09,68.97) v2(51.09,68.34) v2(51.09,67.7) v2(51.14,49.08) v2(51.37,136.41) v2(51.66,95.69) v2(51.66,94.17) v2(51.66,92.64) v2(51.84,79.26) v2(51.84,78.62) v2(51.84,71.7) v2(51.84,71.07) v2(51.9,75.58) v2(51.9,74.94) v2(51.9,74.31) v2(52.54,71.7) v2(52.54,71.07) v2(52.87,49.08) v2(53.1,136.41) v2(53.24,71.7) v2(53.24,71.07) v2(53.94,71.7) v2(53.94,71.07) v2(54.6,49.08) v2(54.82,136.41) v2(55.08,130.12) v2(55.4,58.15) v2(55.4,57.04) v2(55.4,55.92) v2(55.98,110.51) v2(55.98,109.32) v2(55.98,108.13) v2(55.98,106.93) v2(56.02,106.35) v2(56.32,49.08) v2(56.52,58.15) v2(56.52,57.04) v2(56.52,55.92) v2(56.55,136.41) v2(56.63,106.35) v2(56.73,76.08) v2(56.73,74.37) v2(56.73,72.72) v2(56.73,71.26) v2(56.86,110.51) v2(56.86,109.32) v2(56.86,108.13) v2(56.86,106.93) v2(57.24,106.35) v2(57.25,105.69) v2(57.25,105.1) v2(57.25,104.52) v2(57.25,103.94) v2(57.25,103.33) v2(57.64,58.15) v2(57.64,57.04) v2(57.64,55.92) v2(57.73,110.51) v2(57.73,109.32) v2(57.73,108.13) v2(57.73,106.93) v2(57.85,106.35) v2(57.83,105.69) v2(57.83,105.1) v2(57.83,104.52) v2(57.83,103.94) v2(57.83,103.33) v2(58.05,49.08) v2(58.28,136.41) v2(58.32,76.08) v2(58.32,74.37) v2(58.32,72.72) v2(58.32,71.26) v2(58.44,104.89) v2(58.46,106.35) v2(59.03,104.89) v2(59.78,49.08) v2(59.9,93.28) v2(59.9,92.4) v2(59.9,91.53) v2(60.01,136.41) v2(60.09,133.93) v2(61.1,93.28) v2(61.1,92.4) v2(61.1,91.53) v2(61.5,49.08) v2(61.73,136.41) v2(62.29,93.28) v2(62.29,92.4) v2(62.29,91.53) v2(63.23,49.08) v2(63.27,131.32) v2(63.46,136.41) v2(63.49,93.28) v2(63.49,92.4) v2(63.49,91.53) v2(64.29,117.1) v2(64.29,93.36) v2(64.29,92.72) v2(64.74,51.15) v2(64.92,117.1) v2(64.9,93.99) v2(64.9,93.36) v2(64.9,92.72) v2(65.19,136.41) v2(65.51,93.99) v2(65.51,93.36) v2(65.51,92.72) v2(65.61,123.25) v2(65.56,117.1) v2(65.92,53.2) v2(65.92,49.1) v2(66,56.69) v2(66.13,117.1) v2(66.09,93.36) v2(66.09,92.72) v2(66.22,123.25) v2(66.32,104.84) v2(66.41,93.86) v2(66.62,105.32) v2(66.58,56.69) v2(66.67,93.36) v2(66.67,92.72) v2(66.76,117.1) v2(66.91,136.41) v2(66.98,104.84) v2(67,93.86) v2(67.17,56.69) v2(67.26,93.36) v2(67.26,92.72) v2(67.4,117.1) v2(67.61,74.75) v2(67.61,74.14) v2(67.61,73.54) v2(67.84,72.97) v2(67.75,56.69) v2(67.92,93.36) v2(67.92,92.72) v2(67.92,92.14) v2(68.04,71.85) v2(68.04,71.27) v2(68.29,130.62) v2(68.34,56.69) v2(68.28,53.2) v2(68.28,49.1) v2(68.48,72.97) v2(68.64,136.41) v2(68.67,75.39) v2(68.92,56.69) v2(69.14,74.88) v2(69.14,74.24) v2(69.14,73.61) v2(69.11,72.97) v2(69.46,51.15) v2(70.06,130.62) v2(70.37,136.41) v2(70.48,89.74) v2(70.81,89.22) v2(70.9,49.08) v2(71.12,89.74) v2(71.8,102.46) v2(71.8,101.83) v2(71.8,101.19) v2(72.1,136.41) v2(72.41,102.46) v2(72.41,101.83) v2(72.41,101.19) v2(72.63,49.08) v2(73.24,86.94) v2(73.24,86.31) v2(73.75,86.62) v2(73.68,70.29) v2(73.68,69.66) v2(73.82,136.41) v2(74.36,49.08) v2(75.08,90.31) v2(75.46,89.86) v2(75.55,136.41) v2(75.84,90.31) v2(76.08,49.08) v2(77.04,63.2) v2(76.97,52.46) v2(77.23,58.1) v2(77.23,56.83) v2(77.23,55.56) v2(77.28,136.41) v2(77.81,49.08) v2(78.54,56.72) v2(78.47,52.46) v2(78.56,58.88) v2(78.67,63.18) v2(79.01,136.41) v2(79.54,49.08) v2(80.06,58.1) v2(80.06,56.83) v2(80.06,55.56) v2(80.07,52.45) v2(80.64,63.26) v2(80.73,136.41) v2(81.27,49.08) v2(82,52.46) v2(82.35,58.85) v2(82.35,57.58) v2(82.35,56.31) v2(82.46,136.41) v2(82.99,49.08) v2(83.48,63.15) v2(83.47,52.46) v2(83.61,57.26) v2(83.61,55.35) v2(84.19,136.41) v2(84.17,96.2) v2(84.72,49.08) v2(84.94,63.19) v2(84.89,58.85) v2(84.89,57.58) v2(84.89,56.31) v2(85.47,52.46) v2(85.91,136.41) v2(86.05,96.15) v2(86.45,49.08) v2(86.9,63.22) v2(86.97,52.46) v2(87.17,93.94) v2(87.17,58.21) v2(87.17,56.94) v2(87.17,55.67) v2(87.64,136.41) v2(87.78,96.58) v2(87.97,52.46) v2(88.09,93.1) v2(88.17,49.08) v2(88.42,90.79) v2(88.75,58.91) v2(88.76,56.62) v2(88.97,52.46) v2(89.2,93.81) v2(89.37,136.41) v2(89.71,92.01) v2(89.73,63.74) v2(89.72,63.13) v2(89.9,49.08) v2(90.02,58.21) v2(90.02,56.94) v2(90.02,55.67) v2(91.03,83.96) v2(90.97,52.46) v2(91.1,136.41) v2(91.21,85.24) v2(91.63,49.08) v2(91.97,52.46) v2(92.21,58.81) v2(92.19,57.56) v2(92.19,55.74) v2(92.33,117.77) v2(92.7,86.73) v2(92.7,84.9) v2(92.82,136.41) v2(92.97,52.46) v2(93.36,49.08) v2(93.49,63.78) v2(93.5,63.14) v2(93.48,58.47) v2(93.48,56.57) v2(93.97,52.46) v2(94.33,86.68) v2(94.33,84.65) v2(94.55,136.41) v2(95.08,49.08) v2(95.97,52.46) v2(96.24,84.97) v2(96.24,83) v2(96.28,136.41) v2(96.27,58.24) v2(96.27,56.97) v2(96.27,55.7) v2(96.81,49.08) v2(97.47,52.46) v2(97.94,63.13) v2(98,136.41) v2(98.22,60.5) v2(98.47,52.46) v2(98.54,49.08) v2(98.59,85.35) v2(98.59,82.94) v2(98.78,99.24) v2(98.78,98.51) v2(98.96,105.61) v2(99.18,102.68) v2(99.35,55) v2(99.4,100.91) v2(99.59,105.61) v2(99.73,136.41) v2(99.79,59.86) v2(99.79,58.59) v2(100.22,81.51) v2(100.26,49.08) v2(100.67,100.91) v2(100.8,106.06) v2(100.75,103.57) v2(101.02,84.69) v2(101,82.75) v2(101.46,136.41) v2(101.92,103.55) v2(101.94,100.91) v2(101.91,59.16) v2(101.91,57.89) v2(101.91,56.62) v2(101.91,55.35) v2(101.97,106.06) v2(101.99,49.08) v2(102.42,117.02) v2(102.49,64.11) v2(102.5,63.51) v2(102.87,86.24) v2(102.87,84.34) v2(103.14,106.06) v2(103.09,103.55) v2(103.19,136.41) v2(103.21,100.91) v2(103.65,118.37) v2(103.65,116.62) v2(103.72,49.08) v2(104.28,103.6) v2(104.36,106.06) v2(104.48,100.91) v2(104.79,58.53) v2(104.79,57.26) v2(104.79,55.99) v2(104.91,136.41) v2(105.45,49.08) v2(105.54,103.6) v2(105.59,118.4) v2(105.56,116.52) v2(105.61,114.76) v2(105.58,106.09) v2(105.75,100.91) v2(106.09,107.88) v2(106.07,105.37) v2(106.07,104.35) v2(106.07,103.34) v2(106.07,102.32) v2(106.09,99.53) v2(106.64,136.41) v2(106.89,123.86) v2(107.17,49.08) v2(107.35,57.67) v2(107.38,130.25) v2(107.48,115.82) v2(107.8,117.71) v2(107.85,105.48) v2(107.85,103.07) v2(107.85,100.66) v2(108.37,136.41) v2(108.83,58.53) v2(108.83,57.26) v2(108.9,49.08) v2(109.12,105.48) v2(109.12,103.07) v2(109.12,100.66) v2(110.09,136.41) v2(110.39,105.48) v2(110.39,103.07) v2(110.39,100.66) v2(110.64,123.48) v2(110.63,49.08) v2(110.97,86.81) v2(110.97,84.84) v2(111.12,114.23) v2(111.66,105.48) v2(111.66,103.07) v2(111.66,100.66) v2(111.82,136.41) v2(112.31,56.33) v2(112.36,49.08) v2(112.75,87.45) v2(112.75,85.48) v2(112.75,83.45) v2(112.75,81.41) v2(112.93,105.48) v2(112.93,103.07) v2(112.93,100.66) v2(113.03,124.57) v2(113.55,136.41) v2(113.97,58.66) v2(113.97,57.39) v2(113.97,56.12) v2(114.08,49.08) v2(114.4,131.01) v2(114.58,86.43) v2(114.58,84.53) v2(114.68,124.67) v2(115.28,136.41) v2(115.56,104.34) v2(115.59,101.69) v2(115.56,100.4) v2(115.6,58.02) v2(115.6,56.75) v2(115.81,49.08) v2(116.42,86.88) v2(116.42,84.97) v2(116.42,83.07) v2(116.39,59.29) v2(116.53,123.84) v2(116.68,103.5) v2(117,136.41) v2(117.54,49.08) v2(117.68,115.53) v2(118.01,87.51) v2(118.01,85.61) v2(118.01,83.7) v2(118.11,58.43) v2(118.21,122.77) v2(118.17,57.11) v2(118.18,56.27) v2(118.73,136.41) v2(119.3,123.85) v2(119.26,49.08) v2(119.78,85.29) v2(119.85,59) v2(119.85,57.73) v2(120.15,96.81) v2(120.46,136.41) v2(120.99,49.08) v2(121.25,125.42) v2(121.62,52.46) v2(121.98,97.28) v2(122.03,63.25) v2(122.04,59.42) v2(122.04,58.15) v2(122.04,56.88) v2(122.19,136.41) v2(122.72,49.08) v2(122.98,55) v2(123.33,98.24) v2(123.32,60.37) v2(123.32,58.47) v2(123.58,115.01) v2(123.91,136.41) v2(123.98,55) v2(124.45,49.08) v2(124.78,59.42) v2(124.78,58.15) v2(124.78,56.88) v2(124.91,98.48) v2(124.99,119.29) v2(125.12,82.69) v2(125.13,63.85) v2(125.13,63.23) v2(125.31,125.14) v2(125.42,99.53) v2(125.64,136.41) v2(125.94,125.14) v2(126.17,49.08) v2(126.68,99.55) v2(126.85,52.43) v2(127.37,136.41) v2(127.37,59.42) v2(127.37,58.15) v2(127.37,56.88) v2(127.9,49.08) v2(128.77,57.82) v2(128.77,55.91) v2(129.09,136.41) v2(129.26,79.44) v2(129.36,124.17) v2(129.63,49.08) v2(129.82,82.31) v2(129.96,124.17) v2(130.62,59.42) v2(130.62,58.15) v2(130.62,56.88) v2(130.71,52.45) v2(130.82,136.41) v2(130.82,63.8) v2(130.82,63.19) v2(131.35,49.08) v2(131.95,52.41) v2(132.55,136.41) v2(132.68,129.83) v2(132.68,129.24) v2(132.74,63.23) v2(132.81,58.68) v2(132.81,57.41) v2(132.81,56.14) v2(133.08,49.08) v2(134.07,130.38) v2(134.07,129.8) v2(134.07,129.22) v2(134.08,52.44) v2(134.21,59.64) v2(134.21,57.73) v2(134.28,136.41) v2(134.81,49.08) v2(135.03,98.63) v2(135.21,64.01) v2(135.25,63.46) v2(136,136.41) v2(136.26,58.68) v2(136.26,57.41) v2(136.26,56.14) v2(136.29,52.43) v2(136.54,49.08) v2(137.73,136.41) v2(138.23,70.47) v2(138.26,49.08) v2(138.66,70.06) v2(138.79,63.19) v2(138.77,59.83) v2(138.77,58.56) v2(138.77,57.29) v2(139.46,136.41) v2(139.99,49.08) v2(140.19,58.24) v2(140.19,56.37) v2(141.01,129.8) v2(141.18,136.41) v2(141.35,50.39) v2(141.46,59.2) v2(141.46,57.94) v2(141.46,56.65) v2(141.63,130.43) v2(141.63,129.18) v2(142.18,120.5) v2(142.25,129.8) v2(142.82,120.5) v2(142.91,136.41) v2(143.22,98.31) v2(143.33,51.09) v2(143.91,132.15) v2(144.64,136.41) v2(144.68,132.24) v2(144.73,49.95) v2(145.5,131.71) v2(146.37,136.41) v2(146.45,130.49) v2(146.56,49.1) v2(147.59,51.1) v2(147.94,134.3) v2(148.49,128.07) v2(148.84,53.28) v2(148.84,48.92) v2(149.02,136.17) v2(149.02,132.43) v2(149.3,60.54) v2(149.3,58.74) v2(150.34,60.54) v2(150.34,58.74) v2(151.18,136.17) v2(151.18,132.43) v2(151.36,53.28) v2(151.36,48.92) v2(151.48,76.26) v2(151.48,75.3) v2(151.48,73.8) v2(151.53,73.19) v2(151.66,81.95) v2(151.82,75.78) v2(151.87,74.79) v2(151.87,74.23) v2(152.04,73.59) v2(152.14,75.28) v2(152.2,72.32) v2(152.26,134.3) v2(152.27,81.95) v2(152.61,51.1) v2(153.71,134.91) v2(153.69,74.7) v2(153.8,81.23) v2(153.8,80.63) v2(153.88,61.54) v2(154.41,81.23) v2(154.41,80.63) v2(154.46,75.45) v2(154.62,51.6) v2(155.01,81.23) v2(155.01,80.63) v2(155.22,74.69) v2(155.43,134.91) v2(155.46,82.57) v2(155.46,81.9) v2(155.61,81.23) v2(155.61,80.63) v2(156.14,81.58) v2(156.14,80.97) v2(156.14,80.36) v2(156.58,52.6) v2(156.78,81.58) v2(156.78,80.97) v2(156.78,80.36) v2(156.84,75.5) v2(156.88,128.28) v2(157.16,134.91) v2(157.22,75.93) v2(157.5,128.9) v2(157.5,127.66) v2(157.55,111.49) v2(157.55,109.97) v2(157.55,108.44) v2(158.13,128.28) v2(158.34,52.41) v2(158.89,134.91) v2(159.08,111.49) v2(159.08,109.97) v2(159.08,108.44) v2(159.78,51.37) v2(160.49,49.77) v2(160.62,134.91) v2(160.64,131.39) v2(160.62,130.82) v2(160.6,109.97) v2(160.62,48.6) v2(161.25,130.82) v2(161.5,130.25) v2(162.14,130.25) v2(162.2,134.2) v2(162.34,48.6) v2(162.39,73.99) v2(162.69,91.93) v2(162.99,73.99) v2(163.15,135.85) v2(163.15,132.55) v2(163.21,87.83) v2(163.21,87.23) v2(163.21,86.62) v2(163.21,85.99) v2(163.27,63) v2(163.27,62.42) v2(163.27,61.83) v2(163.45,84.87) v2(163.85,63) v2(163.85,62.42) v2(163.85,61.83) v2(164.01,84.62) v2(164.07,48.6) v2(164.44,63.05) v2(164.44,62.42) v2(164.44,61.83) v2(164.51,105.97) v2(164.93,105.56) v2(165.02,61.81) v2(165.05,135.85) v2(165.05,132.55) v2(165.33,105.15) v2(165.58,62.24) v2(165.8,48.6) v2(166.01,134.2) v2(166.01,62.7) v2(166.24,112.45) v2(166.64,132.04) v2(166.66,130.73) v2(166.66,129) v2(166.66,127.28) v2(166.93,125.54) v2(167.42,114.5) v2(167.42,110.4) v2(167.52,48.6) v2(167.99,77.23) v2(167.99,76.64) v2(167.99,76.06) v2(167.99,75.47) v2(167.99,74.89) v2(167.99,74.31) v2(168.45,123.18) v2(168.58,125.35) v2(168.55,120.1) v2(168.58,116.83) v2(169.25,48.6) v2(169.98,76.46) v2(169.98,75.88) v2(169.98,75.25) v2(169.98,74.66) v2(170.31,125.35) v2(170.34,123.68) v2(170.34,121.96) v2(170.34,120.23) v2(170.34,118.5) v2(170.34,116.77) v2(170.34,114.74) v2(170.34,109.71) v2(170.36,107.81) v2(170.36,106.08) v2(170.36,104.35) v2(170.36,102.63) v2(170.36,100.9) v2(170.36,99.17) v2(170.46,97.43) v2(170.64,95.81) v2(170.93,94.12) v2(170.98,48.6) v2(171.3,92.56) v2(171.73,91.04) v2(172.21,65.92) v2(172.26,89.53) v2(172.64,65.49) v2(172.71,48.6) v2(172.85,88.1) v2(173.51,86.71) v2(174.26,85.33) v2(174.43,48.6) v2(174.95,58.91) v2(175.18,83.86) v2(175.41,50.75) v2(175.77,58.1) v2(176.01,82.68) v2(176.05,50.75) v2(176.16,48.6) v2(176.74,50.75) v2(177.05,81.35) v2(177.38,50.75) v2(177.89,48.6) v2(178.28,79.98) v2(178.9,52.03) v2(179.61,48.6) v2(179.67,78.62) v2(180.47,56.05) v2(180.47,54.47) v2(180.81,77.63) v2(181.05,56.05) v2(181.05,54.47) v2(181.34,48.6) v2(181.64,56.05) v2(181.64,54.47) v2(182.17,76.58) v2(182.22,56.05) v2(182.22,54.47) v2(182.62,55.51) v2(183.07,48.6) v2(183.68,75.55) v2(184.17,54.89) v2(184.8,48.6) v2(184.94,55.64) v2(185.09,74.74) v2(185.7,54.87) v2(186.52,48.6) v2(186.74,73.95) v2(187.32,55.69) v2(187.7,56.12) v2(188.25,48.6) v2(188.35,73.32) v2(190.04,72.81) v2(189.98,48.6) v2(191.7,48.6) v2(191.78,72.41) v2(193.43,48.6) v2(193.46,72.19) v2(195.21,72.05) v2(195.16,48.6) v2(196.62,59.28) v2(196.94,72.05) v2(196.89,48.6) v2(197.2,59.28) v2(197.79,59.28) v2(198.02,51.83) v2(198.37,59.28) v2(198.6,51.83) v2(198.61,48.6) v2(198.66,72.05) v2(198.96,59.28) v2(199.19,51.83) v2(199.77,51.83) v2(200.34,48.6) v2(200.39,72.05) v2(200.36,51.83) v2(200.94,51.83) v2(202.09,72.06) v2(202.07,48.6) v2(203.83,72.11) v2(203.8,48.6) v2(205.52,48.6) v2(205.57,72.29) v2(207.25,48.6) v2(207.28,72.59) v2(207.48,51.83) v2(208.43,55.32) v2(208.98,73.04) v2(208.98,48.6) v2(209.83,56.84) v2(210.6,73.59) v2(210.7,48.6) v2(212.11,74.24) v2(212.43,48.6) v2(213.76,75.09) v2(214.16,48.6) v2(215.21,75.98) v2(215.89,48.6) v2(217.05,77.33) v2(217.61,48.6) v2(218.34,70.45) v2(218.97,75.7) v2(219.34,48.6) v2(219.48,70.45) v2(220.85,81) v2(221.05,59.87) v2(221.07,48.6) v2(221.33,79.8) v2(221.33,75.7) v2(221.99,82.42) v2(222.51,77.75) v2(222.81,83.54) v2(222.79,48.6) v2(223.79,85.06) v2(224.23,71.86) v2(224.52,48.6) v2(224.66,86.64) v2(224.81,71.86) v2(225.45,88.3) v2(226.1,89.97) v2(226.25,48.6) v2(226.38,72.57) v2(226.63,91.55) v2(226.66,55.32) v2(227.1,93.29) v2(227.29,55.32) v2(227.44,94.98) v2(227.62,75.91) v2(227.68,96.68) v2(227.85,112.28) v2(227.85,110.55) v2(227.85,108.82) v2(227.85,107.1) v2(227.85,105.37) v2(227.85,103.64) v2(227.85,101.92) v2(227.85,100.19) v2(227.81,98.45) v2(227.98,48.6) v2(228.42,114.06) v2(228.45,63.92) v2(229.32,112.85) v2(229.7,48.6) v2(230.15,114.06) v2(231.43,48.6) v2(231.54,131.56) v2(231.54,129.83) v2(231.54,128.1) v2(231.54,126.38) v2(231.54,124.65) v2(231.54,122.92) v2(231.54,121.19) v2(231.54,119.47) v2(231.54,117.74) v2(231.54,116.01) v2(231.54,114.29) v2(231.75,75.88) v2(232.19,134.2) v2(233.15,135.85) v2(233.15,132.55) v2(233.16,48.6) v2(233.58,127.62) v2(233.87,97.2) v2(234.19,100.52) v2(234.88,48.6) v2(235.05,135.85) v2(235.05,132.55) v2(235.62,99.38) v2(235.69,103.77) v2(236,134.2) v2(236.05,111.07) v2(236.05,110.44) v2(236.05,109.8) v2(236.14,105.32) v2(236.27,106.81) v2(236.29,88.01) v2(236.29,87.45) v2(236.61,48.6) v2(237.99,74.81) v2(238.34,48.6) v2(238.59,134.91) v2(239.3,96.21) v2(239.29,94.88) v2(239.29,94.31) v2(239.39,79.68) v2(239.39,79.04) v2(239.55,63.69) v2(239.65,126.64) v2(239.57,96.73) v2(239.75,62.09) v2(240.07,48.6) v2(240.32,134.91) v2(241.79,48.6) v2(242.05,134.91) v2(242.28,127.07) v2(243.52,48.6) v2(243.77,134.91) v2(244.02,53.71) v2(244.4,82.36) v2(245.01,127.2) v2(245.01,125.93) v2(245.01,124.66) v2(245.25,48.6) v2(245.39,107.83) v2(245.5,134.91) v2(246.02,107.83) v2(246.3,127.95) v2(246.28,127.2) v2(246.28,125.93) v2(246.28,124.66) v2(246.98,48.6) v2(247.23,134.91) v2(247.55,127.2) v2(247.55,125.93) v2(247.8,127.95) v2(248.7,48.6) v2(248.96,134.91) v2(249.81,62.27) v2(250.19,62.72) v2(250.43,48.6) v2(250.68,134.91) v2(251.29,111.2) v2(252.16,48.6) v2(252.41,134.91) v2(253.86,64.57) v2(253.88,48.6) v2(254.14,134.91) v2(254.44,64.57) v2(255.36,62.3) v2(255.36,60.34) v2(255.36,58.37) v2(255.61,48.6) v2(255.87,134.91) v2(257.33,62.3) v2(257.33,60.34) v2(257.33,58.37) v2(257.34,48.6) v2(257.59,134.91) v2(257.65,68.81) v2(258.26,68.82) v2(259.07,48.6) v2(259.32,134.91) v2(259.29,62.3) v2(259.29,60.34) v2(259.29,58.37) v2(260.07,90.56) v2(260.79,48.6) v2(261.05,134.91) v2(262.52,48.6) v2(262.77,134.91) v2(263.66,134.15) v2(263.66,132.42) v2(264.2,130.76) v2(264.25,48.6) v2(265.76,48.6) v2(265.92,130.76) v2(267.1,58.56) v2(267.19,93.78) v2(267.19,91.67) v2(267.23,65.23) v2(267.23,64.59) v2(267.23,63.96) v2(267.55,58.11) v2(267.65,130.76) v2(268.25,92.72) v2(268.24,50.25) v2(269.3,93.78) v2(269.3,91.67) v2(269.38,130.76) v2(269.42,52.3) v2(271.11,130.76) v2(271.78,52.3) v2(272.83,130.76) v2(272.96,50.25) v2(273.33,127.46) v2(274.15,65.99) v2(274.15,63.75) v2(274.28,91.83) v2(274.28,90.88) v2(274.56,130.76) v2(275.27,64.87) v2(275.26,46.57) v2(275.87,78.14) v2(275.87,73.32) v2(276.03,44.71) v2(276.03,42.99) v2(276.03,41.26) v2(276.03,39.53) v2(276.03,37.81) v2(276.03,36.08) v2(276.03,34.35) v2(276.03,32.62) v2(276.03,30.9) v2(276.03,29.17) v2(276.03,27.44) v2(276.03,25.72) v2(276.03,23.99) v2(276.03,22.26) v2(276.03,20.53) v2(276.03,18.81) v2(276.03,17.08) v2(276.03,15.35) v2(276.03,13.63) v2(276.03,11.9) v2(276.03,10.17) v2(276.03,8.44) v2(276.03,6.72) v2(276.03,4.99) v2(276.03,3.26) v2(276.03,1.53) v2(276.13,75.77) v2(276.29,130.76) v2(276.39,65.99) v2(276.39,63.75) v2(276.76,76.39) v2(276.76,75.14) v2(276.93,0.44) v2(277.61,68.06) v2(277.79,70.5) v2(278.01,130.76) v2(277.99,13.95) v2(278.6,70.5) v2(278.66,0.44) v2(278.95,15.6) v2(278.95,12.3) v2(279.74,130.76) v2(280.03,74.01) v2(280.41,70.17) v2(280.39,0.44) v2(280.85,15.6) v2(280.85,12.3) v2(281.02,70.17) v2(281.39,65.92) v2(281.47,130.76) v2(281.77,65.48) v2(281.8,13.95) v2(281.99,2.04) v2(282.12,0.44) v2(282.66,55.66) v2(282.66,55.07) v2(283.2,130.76) v2(283.31,5.78) v2(283.84,0.44) v2(284.33,3.64) v2(284.49,68.2) v2(284.76,47.93) v2(284.94,130.76) v2(284.88,87.67) v2(285.45,69.85) v2(285.45,66.55) v2(285.57,0.44) v2(286.46,86.64) v2(286.46,84.91) v2(286.52,71.66) v2(286.69,130.87) v2(287.04,2.2) v2(287.14,132.9) v2(287.3,51.47) v2(287.3,0.44) v2(287.35,69.85) v2(287.35,66.55) v2(288.1,134.55) v2(288.1,131.25) v2(288.33,86.16) v2(288.3,68.2) v2(288.43,71.65) v2(289,47.9) v2(289.03,0.44) v2(289.16,50.23) v2(289.46,23.12) v2(289.84,11.44) v2(290,134.55) v2(290,131.25) v2(290.05,86.16) v2(290.16,71.65) v2(290.22,23.12) v2(290.4,88.58) v2(290.6,11.44) v2(290.75,0.44) v2(290.95,132.9) v2(290.98,23.12) v2(291.11,70.04) v2(291.13,67.7) v2(291.08,51.47) v2(291.06,19.21) v2(291.18,15.71) v2(291.31,130) v2(291.36,11.44) v2(291.74,23.12) v2(291.78,86.16) v2(291.89,71.65) v2(292.12,11.44) v2(292.48,0.44) v2(292.66,129.75) v2(293.17,88.58) v2(293.15,69.45) v2(293.15,67.73) v2(293.15,66) v2(293.15,22.45) v2(293.15,20.72) v2(293.15,19) v2(293.15,17.27) v2(293.15,15.54) v2(293.15,13.82) v2(293.15,12.09) v2(293.15,10.36) v2(293.15,8.63) v2(293.15,6.91) v2(293.15,5.18) v2(293.15,3.45) v2(293.15,1.73) v2(293.27,91.15) v2(293.94,26.3) v2(294.38,129.75) v2(294.46,51.52) v2(294.88,66) v2(294.99,91.15) v2(295.02,28.17) v2(295.02,24.43) v2(294.96,22.95) v2(295.16,69.9) v2(295.32,86.18) v2(295.31,71.65) v2(295.55,88.56) v2(295.93,46.66) v2(296.11,129.75) v2(296.12,50.91) v2(296.54,64.74) v2(296.61,66) v2(296.84,22.95) v2(297.04,71.65) v2(297.04,69.92) v2(297.05,87.91) v2(297.05,86.18) v2(297.18,28.17) v2(297.18,24.43) v2(297.32,52.08) v2(297.31,50.91) v2(297.84,129.75) v2(298,89.22) v2(298,46.66) v2(298.19,127.93) v2(298.19,124.34) v2(298.27,120.38) v2(298.33,66) v2(298.26,26.3) v2(299.05,29.77) v2(299.01,22.97) v2(299.57,129.75) v2(299.74,128.52) v2(299.74,126.8) v2(299.74,125.07) v2(299.74,123.34) v2(299.74,121.61) v2(299.74,119.89) v2(299.74,118.16) v2(299.74,116.43) v2(299.73,90.94) v2(299.73,89.22) v2(300.06,66) v2(300.24,64.45) v2(300.24,62.72) v2(300.24,61) v2(300.24,59.27) v2(300.24,57.54) v2(300.24,55.81) v2(300.24,54.09) v2(300.24,52.36) v2(300.24,50.63) v2(300.24,46.66) v4(10.39,47.64) v4(26.72,105.9) v4(31.29,126.33) v4(32.18,110.7) v4(39.79,75.04) v4(39.9,73.73) v4(40.89,115.45) v4(41.58,77.15) v4(42.85,78.57) v4(51.2,70.11) v4(55.01,71.77) v4(56.96,77.86) v4(57.1,109.83) v4(66.04,55.97) v4(73.81,87.36) v4(104.49,97.6) v4(124.41,120.33) v4(128.67,78.9) v4(141.29,62.39) v4(142.64,131.18) v4(151.23,74.46) v4(152.84,75.94) v4(153.19,80.61) v4(158.95,128.1) v4(170.28,77.91) v4(177.75,53.33) v4(181.33,55.26) v4(227.02,54.16) v4(265.89,53.71) v4(283.08,70.9) v4(286.1,87.77) v4(290.3,14.01) v4(290.42,23.71)
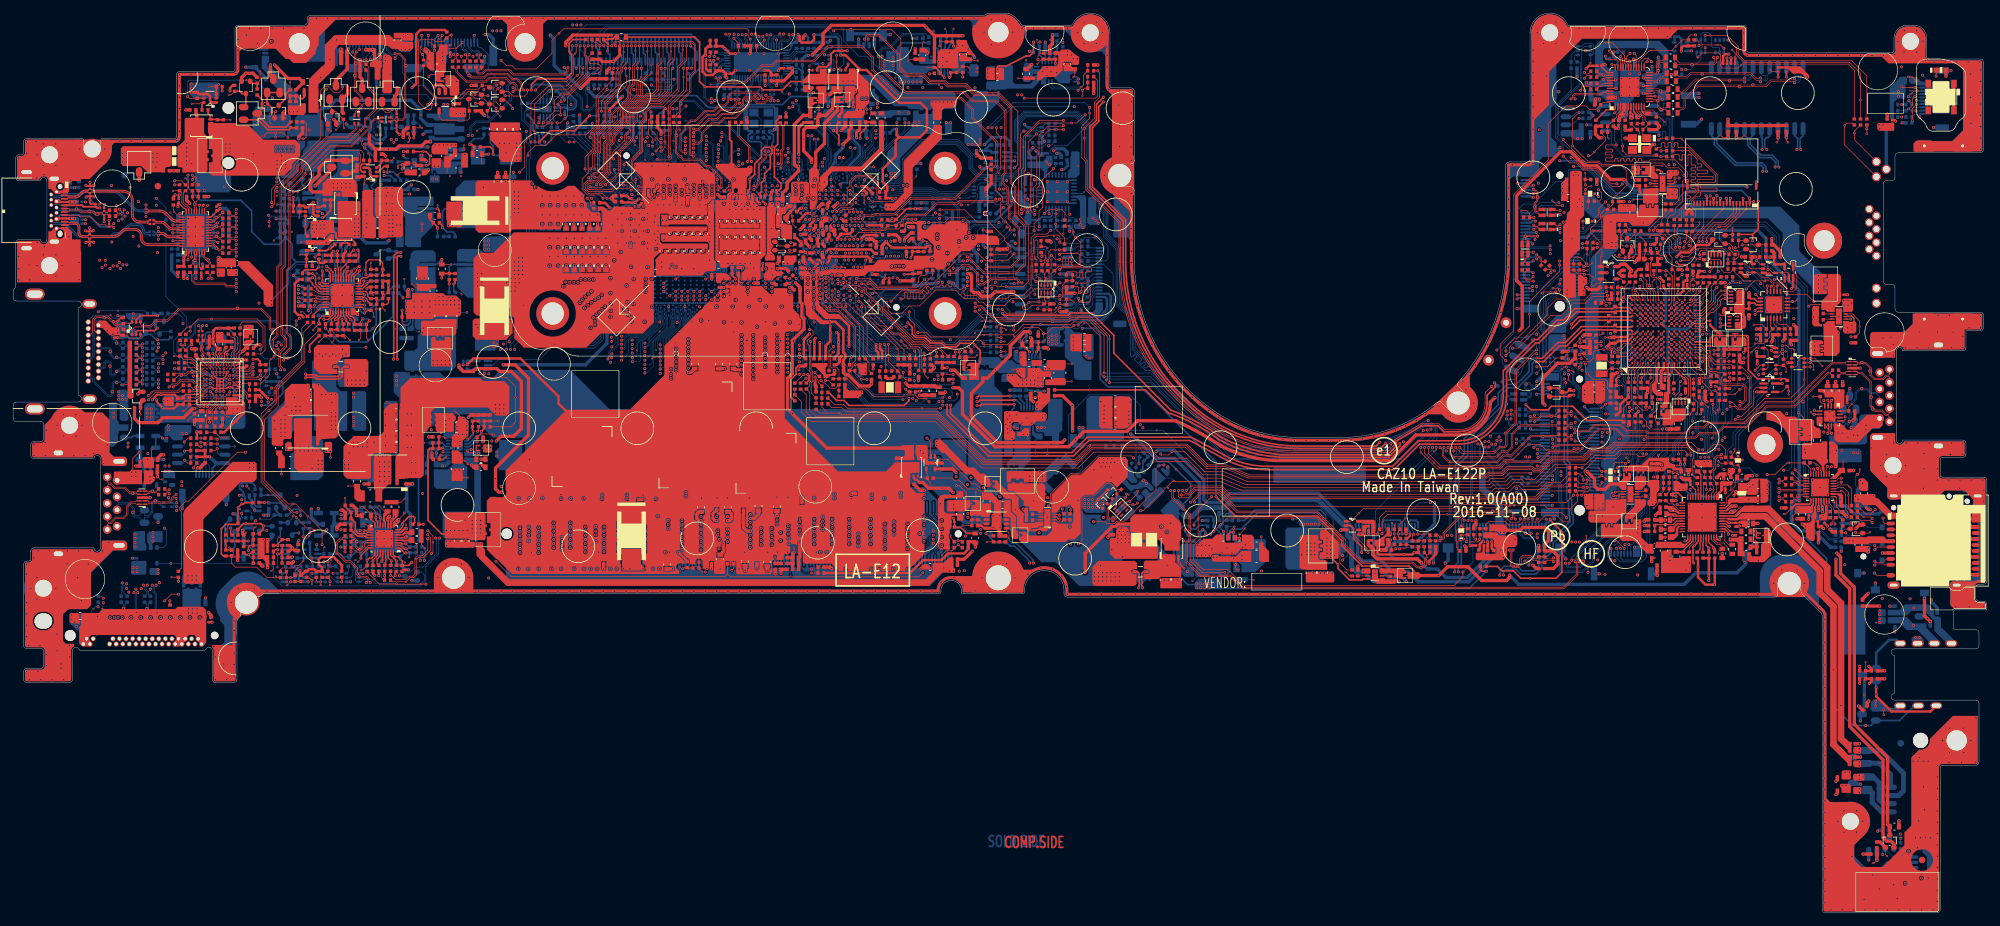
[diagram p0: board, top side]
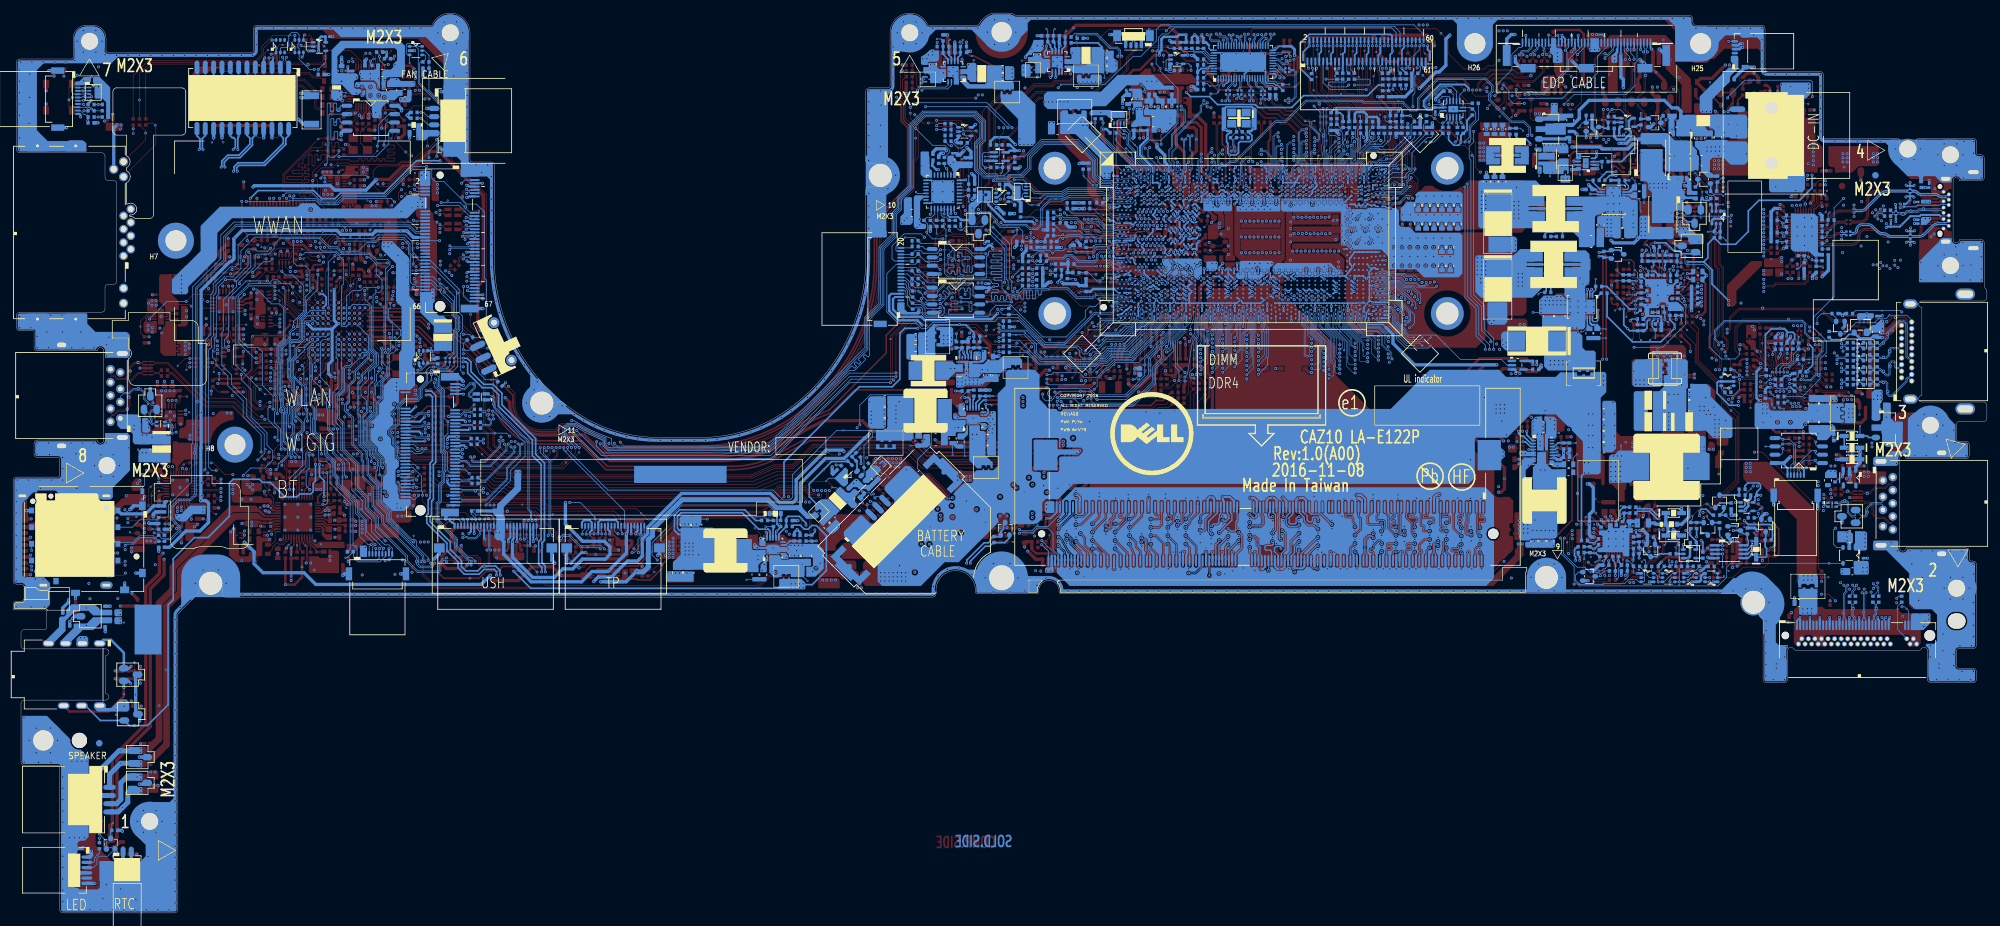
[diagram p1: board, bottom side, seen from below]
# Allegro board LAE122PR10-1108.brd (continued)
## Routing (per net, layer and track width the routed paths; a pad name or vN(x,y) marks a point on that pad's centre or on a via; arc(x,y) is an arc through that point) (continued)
GNDA: length 43
  TOP w0.102: v2(284.99,30.95) v4(284.99,30.21)
  TOP w0.127: v2(283.77,32.29) v4(283.77,31.51)
  TOP w0.203: v2(254.72,56.72) 254.93,56.72 255.13,56.92 UA1.25 ; v2(261.33,57.73) 261.33,58.01 260.8,58.54 UA1.38
  TOP w0.381: v2(253.34,62.88) 252.7,62.88 CA41.2 ; CA57.2 v2(261.96,57.58)
  TOP w0.508: CA2.2 v2(285.14,35.7) ; RA37.1 250.16,59.89 CA25.2 v2(251.74,59.89) ; RA38.1 v2(284.36,46.79) ; RA39.1 282.45,32.05 v2(282.71,32.31) ; CA3.2 v2(285.14,36.9)
  GND1 w0.203: 286.42,30.92 JHP1.5 ; JHP1.5 287.5,30.92 ; JHP1.5 288.58,30.92 ; JHP1.5 288.58,31.6 ; JHP1.5 286.42,31.6 ; 289.07,41.77 JHP1.7 ; JHP1.7 289.07,41.1 ; JHP1.7 290.15,41.77 ; JHP1.7 291.23,41.1 ; JHP1.7 291.23,41.77
  VCC w0.203: 289.07,41.77 JHP1.7 ; JHP1.7 291.23,41.77 ; JHP1.7 290.15,41.77 ; JHP1.5 288.58,30.92 ; JHP1.5 287.5,30.92 ; JHP1.5 286.42,30.92
  GND2 w0.203: JHP1.7 291.23,41.1 ; JHP1.7 291.23,41.77 ; JHP1.7 290.15,41.77 ; JHP1.7 289.07,41.77 ; JHP1.7 289.07,41.1 ; JHP1.5 288.58,31.6 ; JHP1.5 286.42,30.92 ; JHP1.5 288.58,30.92 ; JHP1.5 286.42,31.6 ; JHP1.5 287.5,30.92
  BOTTOM w0.508: CA1.1 286.66,43.58 v2(286.66,42.87) ; CA4.2 v2(285.9,46.76) ; DA2.2 v2(283.77,32.29)
  vias: v2(252.44,54.37) v2(252.44,53.73) v2(255.36,53.35) v2(265.45,58.24) v2(265.45,57.61) v2(289.84,41.97) v2(290.45,41.97) v4(254.85,52.28)
VBAT1_ISL88738: length 4.5
  TOP w0.203: PU901.31 57.52,54.53 v2(58.38,53.67)
  TOP w0.254: PR940.2 v2(58.38,53.67)
  BOTTOM w0.112: v1(59.66,53.45) 59.45,53.67 v2(58.38,53.67)
  BOTTOM w0.203: v2(58.38,53.67) 58.06,53.99 PC950.2
VBUS1_ECOK: length 406.7
  TOP w0.112: v2(264.05,95.13) 265.28,96.37 v4(266.89,96.37) 267.63,96.37 268.31,95.68 268.31,95.32 268.25,95.26 UE2.13
  TOP w0.254: PR1220.1 PR1222.1 42.7,107.85 v2(42.7,109.1)
  IN2 w0.124: v2(47.32,53.53) 46.7,52.91 43.71,52.91 43.33,52.53 42.12,52.53 41.54,53.11 41.54,61.38 38.19,64.73 38.19,76.27 39.9,77.99 39.9,81.1 39.2,81.8 39.2,83.7 41.3,85.8 41.3,92.82 40.89,93.23 40.89,103.92 41.55,104.58 41.55,107.76 42.7,108.9 v2(42.7,109.1) 42.57,108.97 39.48,108.97 36.94,111.52 32.92,111.52 31.56,112.88 31.56,117.88 37.15,123.47 39.74,123.47 42.34,126.07 46.15,126.07 47.8,127.72 62.18,127.72 62.81,128.36 74.85,128.36 75.13,128.08 79.85,128.08 83.48,131.71 103.72,131.71 104.29,132.28 109.12,132.28 109.37,132.03 117.36,132.03 117.78,132.45 134.17,132.45 136.17,134.44 144.68,134.44 148.47,130.64 154.72,130.64 155.22,131.14 156.59,131.14 159,128.73 159,124.09 161.67,121.42 161.67,118.22 163.29,116.6 163.29,110.6 167.69,106.19 167.69,90.43 169.61,88.51 169.61,86.03 172.1,83.54 172.1,80.97 181.65,71.42 184.74,71.42 186.43,69.73 206.48,69.73 207.76,68.44 221.11,68.44 221.79,69.12 225.87,69.12 226.88,70.12 228.77,70.12 231.53,72.89 232.49,72.89 233.8,74.2 234.73,74.2 235.18,74.66 235.18,75.61 235.86,76.28 235.86,77.13 236.57,77.84 240.05,77.84 240.74,77.15 244.56,77.15 245.94,75.77 249.34,75.77 249.76,76.19 252.47,76.19 253.34,77.05 257.86,77.05 258.77,76.14 v2(260.45,76.14)
  BOTTOM w0.112: PR1257.1 47.38,53.47 v2(47.32,53.53) ; v2(260.45,76.14) 260.45,78.76 260.68,78.99 260.68,83.92 260.49,84.11 260.49,86.51 259.5,87.5 259.5,92.28 260.07,92.86 261.32,92.86 263.59,95.13 v2(264.05,95.13)
VBUS2_ECOK: length 398.5
  TOP w0.112: v2(47.97,53.54) v1(47.97,53.03) PR1242.1 ; UE2.16 266.05,93.72 v2(265.48,94.3)
  IN2 w0.124: v2(47.97,53.54) 47.01,54.49 44.92,54.49 43.2,52.78 42.31,52.78 41.77,53.33 41.77,61.55 38.44,64.88 38.44,76.17 40.16,77.89 40.16,81.23 39.46,81.93 39.46,83.58 41.53,85.65 41.53,93.05 41.2,93.38 41.2,103.85 41.98,104.63 41.98,107.78 43.1,108.9 43.1,109.31 42.91,109.5 39.28,109.5 39.14,109.63 39.14,111.06 40.13,112.05 v2(40.18,112.05) 41.17,112.05 43.36,114.24 43.36,117.01 38.78,121.59 38.78,122.54 39.42,123.18 39.8,123.18 42.38,125.75 46.2,125.75 47.71,127.26 62.53,127.26 63.35,128.08 74.75,128.08 75.11,127.72 79.81,127.72 83.52,131.43 103.82,131.43 104.35,131.96 108.99,131.96 109.18,131.77 117.49,131.77 117.93,132.22 134.33,132.22 136.29,134.19 143.6,134.19 144.45,133.34 145.4,133.34 148.35,130.39 154.85,130.39 155.34,130.88 156.46,130.88 158.77,128.58 158.77,123.99 161.44,121.32 161.44,118.13 163.06,116.51 163.06,110.5 167.47,106.1 167.47,90.33 169.38,88.41 169.38,85.94 171.85,83.47 171.85,80.91 181.56,71.2 184.64,71.2 186.36,69.48 206.37,69.48 207.63,68.22 221.24,68.22 221.92,68.89 225.97,68.89 226.97,69.9 228.86,69.9 231.3,72.33 232.29,72.33 233.9,73.95 234.83,73.95 235.43,74.55 235.43,75.51 236.11,76.18 236.11,77.06 236.66,77.62 239.94,77.62 240.64,76.92 244.44,76.92 245.84,75.52 249.36,75.52 249.76,75.12 250.29,75.12 251.1,75.93 252.6,75.93 253.47,76.8 257.79,76.8 258.95,75.64 260.79,75.64 261.1,75.95 v2(261.1,76.82)
  BOTTOM w0.112: v2(40.18,112.05) 40.44,112.05 PR24.1 ; v2(261.1,76.82) 261.1,78.81 262.72,80.43 262.72,85.57 263.35,86.19 264.92,86.19 266.19,87.46 266.19,93.56 265.48,94.27 v2(265.48,94.3)
  BOTTOM w0.254: PR20.2 41.16,111.33 PR24.1
VBUS3_ECOK: length 2
  TOP w0.107: UE1.F13 250.68,94.51
  TOP w0.112: T264.1 250.52,94.68 250.68,94.51
VCC_GT_SENSE: length 61.7
  TOP w0.112: v2(87.46,108.98) 88.02,108.42 88.02,107.83 RC161.1
  TOP w0.203: PC620.1 50.28,88.9 PC617.1 50.25,89.79 PR622.1 50.11,89.95 v2(50.11,90.51)
  IN1 w0.119: v2(87.46,108.98) 87.2,108.72 80.21,108.72 78.37,106.87 78.37,105.91 72.16,99.71 72.16,93.53 68.63,90 57.38,90 56.75,90.63 55.01,90.63 54.63,91.01 54.04,91.01 53.65,90.61 52.2,90.61 51.64,91.16 50.76,91.16 50.52,90.93 50.49,90.93 50.11,90.55 v2(50.11,90.51)
  BOTTOM w0.076: UC1.J70 92.29,108.43 92.15,108.29 91.97,108.17 91.46,108.17 91.35,108.28 89.6,108.28 89.42,108.45 89.42,108.48 89.41,108.49
  BOTTOM w0.112: 89.41,108.49 88.49,109.41 87.9,109.41 v2(87.46,108.98)
  BOTTOM w0.203: PC618.2 50.11,90.21 v2(50.11,90.51)
VCCIO_SENSE: length 99.5
  TOP w0.112: v2(118.32,96.71) 117.83,96.71 RC165.1 ; v2(131.82,130.62) 131.99,130.45 131.99,128.87 135.87,124.99 144.78,124.99 146.09,123.69 149.62,123.69 151.03,122.27 151.03,112.91 150.64,112.51 150.64,111.25 151.4,110.49 151.4,108.02 151.64,107.79 151.64,105.82 153.11,104.35 153.11,99.71 152,98.61 148.46,98.61 v2(148.26,98.8)
  IN3 w0.135: v2(148.26,98.8) 148.11,98.65 146.53,98.65 146.19,99 145.03,99 142.92,96.89 142.31,96.89 141.8,97.4 137.45,97.4 137,96.94 135.56,96.94 134.64,97.86 131.85,97.86 130.58,99.13 125.13,99.13 124.26,99.99 119.44,99.99 118.48,99.04 118.48,97.62 118.73,97.37 118.73,96.88 118.55,96.71 v2(118.32,96.71)
  BOTTOM w0.076: UC1.AM23 v2(118.32,96.71)
  BOTTOM w0.112: v2(131.82,130.62) 131.99,130.8 131.99,131.55 132.45,132.01 133.46,132.01 135.57,134.12 138.95,134.12 PR422.2
VCCSA_B+: length 0.5
  BOTTOM w0.102: 66.56,112.8 v1(66.56,112.32)
  vias: v2(64.16,113.85) v2(64.77,113.85)
VCCSENSE: length 91.2
  TOP w0.112: RC140.1 110.39,120.22 110.39,118.44 112.03,116.8 112.03,114.74 v2(111.85,114.56)
  TOP w0.203: PC639.1 54.52,94.56 PR648.1 PC653.1 ; PC653.1 54.15,95.44 v2(53.9,95.18) ; PC653.1 55.37,95.44 PC651.2
  IN1 w0.119: v2(53.9,95.18) 54.14,95.43 55.74,95.43 59.76,99.45 59.76,101.52 61.13,102.89 70.81,102.89 71.14,103.22 74.62,103.22 77.71,106.31 77.71,107.12 80.47,109.87 91.07,109.87 93.55,112.36 95.63,112.36 96.67,111.31 96.67,110.12 97.88,108.91 107.58,108.91 108.02,109.36 108.02,113.65 109.39,115.02 111.39,115.02 v2(111.85,114.56)
  BOTTOM w0.076: UC1.E32 113.71,111.09 113.71,111.52 113.78,111.6 113.78,111.84 113.68,111.94 113.68,112.09 113.78,112.19 113.78,112.46
  BOTTOM w0.102: 113.78,112.46 113.71,112.54 113.71,114.47 112.89,115.28 112.3,115.28 112.06,115.05 112.06,114.77 v2(111.85,114.56)
VCCST_PWRGD: length 331.9
  TOP w0.112: UE4.4 271.18,97.9 271.74,97.34 271.74,95.3 271.2,94.76 270.38,94.76 270.13,95.01 270.13,95.46 269.02,96.57 v2(268.32,96.57) ; RE308.1 262.22,100.4 261.49,101.13 v2(261.49,101.36)
  IN1 w0.119: v2(74.38,65) 74.43,65.05 138.94,65.05 140.69,63.3 140.69,61.94 143.42,59.21 146.45,59.21 146.67,59.42 156.87,59.42 158.44,57.85 162.28,57.85 164.44,55.69 171.96,55.69 172.7,54.95 178.16,54.95 180.11,52.99 184.63,52.99 187.73,49.9 238.54,49.9 242.04,53.39 242.04,58.16 248.41,64.53 250.41,64.53 252.13,66.24 259.83,66.24 260.3,65.77 261.2,65.77 262.91,67.49 v2(262.91,70.28)
  IN3 w0.135: v2(79.17,111.16) 78.69,111.64 78.69,115.12 80.67,117.1 87.63,117.1 88.8,118.27 88.8,118.68 91.52,121.4 v2(91.69,121.4) ; v2(75.78,85.93) 75.75,85.9 75.75,73.19 74.52,71.96 74.52,65.14 v2(74.38,65)
  BOTTOM w0.112: v2(262.91,70.28) 262.91,72.91 265.66,75.65 265.66,78.08 267.99,80.41 267.99,81.84 269.8,83.64 269.8,84.17 270.35,84.73 270.35,85.79 270.05,86.09 270.05,87.54 269.75,87.85 269.75,93.94 269.39,94.3 269.39,95.54 268.35,96.57 v2(268.32,96.57) 267.02,96.57 264.92,98.68 264.92,100.07 265.25,100.4 265.25,100.88 264.9,101.23 263.83,101.23 263.5,100.9 261.95,100.9 v2(261.49,101.36) ; v2(91.69,121.4) 91.69,120.88 91.45,120.65 RC71.1 RC123.1 CC301.1 RC78.1 ; v2(75.78,85.93) 75.78,86.62 77.41,88.25 77.41,92.3 v1(77.76,92.65) 79.08,93.97 79.08,111.07 v2(79.17,111.16)
VCCST_PWRGD_CPU: length 9.5
  BOTTOM w0.076: UC1.B65 95.85,112.96 95.85,114.12 94.97,115 94.97,115.86 93.97,116.86 93.63,116.86
  BOTTOM w0.112: 93.63,116.86 91.98,116.86 v1(91.21,117.64) 90.89,117.96 RC78.2
VCCST_PWRGD_EC: length 18.1
  TOP w0.107: UE1.K10 v2(254.28,91.46)
  TOP w0.112: v2(254.23,100.09) 255.23,100.09 256.31,101.17 v1(256.65,101.17) 256.84,101.36 260.46,101.36 RE308.2
  IN1 w0.119: v2(254.23,100.09) 254.47,99.85 254.47,98.83 253.85,98.21 253.85,96.12 253.57,95.85 253.57,94.12 253.89,93.8 253.89,91.86 v2(254.28,91.46)
VCCSTG_EN: length 146.6
  TOP w0.112: v2(150.34,63.43) 149.43,64.35 147.18,64.35 146.88,64.64 145.44,64.64 144.09,65.99 143.34,65.99 143.03,66.3 RZ120.1 ; v2(121.25,128.47) 121.26,128.49 UZ19.4
  IN2 w0.124: v2(171.72,74.43) 171.55,74.6 171.55,78.8 170.27,80.08 170.27,82.82 167.8,85.28 167.8,87.76 165.88,89.68 165.88,103.68 165.88,103.68 165.88,105.44 161.48,109.85 161.48,115.85 159.02,118.31 159.02,120.96 154.22,125.76 154.03,125.76 148.34,125.76 147.01,127.1 146.4,127.1 146.4,127.09 145.79,127.09 144.76,128.12 141.04,128.12 140.55,128.61 138.5,128.61 138.26,128.37 132.35,128.37 131.9,128.82 126.73,128.82 126.51,129.04 124.73,129.04 124.26,129.5 v2(123.37,129.5) ; v2(150.34,63.43) 157.49,63.43 v2(157.61,63.32)
  BOTTOM w0.112: UZ35.4 122.88,129.04 RZ320.2 ; UZ35.4 122.53,129.54 123.33,129.54 v2(123.37,129.5) ; UZ35.4 121.61,129.47 v1(121.32,129.18) 121.25,129.11 v2(121.25,128.47) ; v2(171.72,74.43) 171.72,77.4 170.11,79 163.9,79 160.81,75.91 160.81,71.25 162.89,69.17 162.89,67.72 158.4,63.23 157.7,63.23 v2(157.61,63.32)
VDD_ISL88738: length 20.9
  TOP w0.112: PR919.1 50.49,58.43 v2(49.93,58.43)
  TOP w0.203: v2(53.45,58.32) 53.74,58.32 54.02,58.04 PU901.18
  TOP w0.254: v2(62.48,59.26) PR915.2
  IN1 w0.254: v2(49.93,58.43) 51.27,58.43 51.78,58.94 53.05,58.94 53.45,58.53 v2(53.45,58.32)
  IN2 w0.254: v2(62.48,59.26) 59.74,62 58.22,62 57.29,61.07 55.03,61.07 53.45,59.5 v2(53.45,58.32)
  BOTTOM w0.254: PC933.1 53.14,57.34 PR918.2 53.45,57.96 v2(53.45,58.32)
VDDP_ISL88738: length 5.7
  TOP w0.203: PU901.8 58.89,58.44 59.33,58.88 v2(59.33,59.26)
  TOP w0.254: PR915.1 61.16,59.51 61.16,60.31 v1(61.12,60.35) 61.03,60.44 60.29,60.44 59.33,59.49 v2(59.33,59.26)
  BOTTOM w0.254: PC932.2 59.19,59.26 v2(59.33,59.26)
VIN_1.8VALW: length 1.8
  BOTTOM w0.102: 168.72,67.37 168.34,66.99 167.87,66.99 v1(167.3,66.42)
VIN_1V_PRIM: length 1.3
  TOP w0.112: v1(161.5,127.42) 161.69,127.61 PC418.1
  vias: v2(160.3,129.4) v2(160.93,129.4)
VIN_1VS_VCCIO: length 1.3
  TOP w0.112: PC408.1 146.07,130.17 146.29,129.96 v1(147.01,129.96)
  vias: v2(144.42,130.86) v2(145.06,130.86)
VSS_GT_SENSE: length 62.6
  TOP w0.112: v2(88.1,108.98) 88.47,108.61 RC163.1
  TOP w0.203: PC620.2 50.7,90.26 v2(50.7,90.51) 50.7,90.61 50.33,90.97 PU602.6
  IN1 w0.119: v2(88.1,108.98) 87.59,108.47 80.31,108.47 78.61,106.77 78.61,105.81 72.41,99.6 72.41,93.43 68.73,89.76 57.27,89.76 56.65,90.38 54.91,90.38 54.53,90.76 54.15,90.76 53.75,90.37 52.09,90.37 51.54,90.92 50.86,90.92 50.7,90.75 v2(50.7,90.51)
  BOTTOM w0.076: UC1.J69 92.88,108.43 92.62,108.17 92.33,108.17 92.07,108 91.34,108 91.27,108.08 89.51,108.08 89.28,108.31 89.25,108.31 89.24,108.32
  BOTTOM w0.102: PC619.2 v1(50.52,87.64)
  BOTTOM w0.112: v2(88.1,108.98) 88.25,109.13 88.43,109.13 89.24,108.32
  BOTTOM w0.203: v2(50.7,90.51) 51,90.21 51,89.39 PC619.2
VSSIO_SENSE: length 98.5
  TOP w0.112: v2(119.31,96.71) 119.27,96.71 RC167.1 ; v2(132.4,130.62) 132.23,130.45 132.23,128.97 135.97,125.23 144.88,125.23 146.19,123.93 149.71,123.93 151.27,122.37 151.27,112.81 150.87,112.41 150.87,111.35 151.64,110.59 151.64,108.12 151.88,107.88 151.88,105.92 153.35,104.45 153.35,99.61 152.1,98.37 148.41,98.37 v2(148.26,98.22)
  IN3 w0.135: v2(119.31,96.71) 119.12,96.71 118.99,96.85 118.99,97.48 118.74,97.72 118.74,98.93 119.55,99.73 124.15,99.73 125.02,98.87 130.48,98.87 131.75,97.6 134.53,97.6 135.45,96.68 137.1,96.68 137.56,97.13 141.69,97.13 142.2,96.62 143.03,96.62 145.14,98.73 146.08,98.73 146.42,98.39 148.09,98.39 v2(148.26,98.22)
  BOTTOM w0.076: UC1.AM22 v2(119.31,96.71)
  BOTTOM w0.112: PR412.2 138.77,133.54 138.77,133.77 138.66,133.88 135.67,133.88 133.56,131.77 132.55,131.77 132.23,131.46 132.23,130.8 v2(132.4,130.62)
VSSSENSE: length 91
  TOP w0.112: RC141.1 110.63,120.22 110.63,118.53 112.27,116.9 112.27,114.78 v2(112.48,114.56)
  TOP w0.203: PC654.2 55.37,96.35 PC653.2 54.33,96.35 v2(53.9,95.92) 53.9,95.85 53.22,95.17 PU602.18
  IN1 w0.119: v2(53.9,95.92) 54.14,95.68 55.64,95.68 59.52,99.55 59.52,101.63 61.03,103.13 70.71,103.13 71.04,103.47 74.52,103.47 77.47,106.42 77.47,107.22 80.37,110.12 90.96,110.12 93.44,112.6 95.73,112.6 96.92,111.42 96.92,110.22 97.98,109.15 107.47,109.15 107.78,109.46 107.78,113.75 109.29,115.26 111.79,115.26 v2(112.48,114.56)
  BOTTOM w0.076: UC1.E33 113.29,111.39 113.15,111.54 113.15,111.79 113.23,111.87 113.23,112.16 113.16,112.22 113.16,112.53
  BOTTOM w0.102: 113.16,112.53 113.48,112.84 113.48,114.38 112.8,115.06 112.39,115.06 112.29,114.95 112.29,114.76 v2(112.48,114.56)
32KHZ_OUT: length 5.2
  TOP w0.107: UE1.F3 v2(250.28,85.06)
  TOP w0.112: CE54.1 249.5,81.42 v2(249.5,81.6)
  IN2 w0.124: v2(250.28,85.06) 250.28,82.38 v2(249.5,81.6)
+AC_IN: length 60.3
  TOP w0.254: PR1251.1 52.08,102.23 51.6,102.72 49.44,102.72 49.19,102.97 49.19,103.64 48.93,103.89 PQ1213.3
  IN3 w0.254: v2(36.96,59.82) 37.43,60.29 37.43,62.81 38.19,63.57 38.19,76.34 39.8,77.95 39.8,79.6 42.89,82.69 42.89,87.04 45.49,89.65 45.49,92.28 45.36,92.4 45.36,96.28 45.05,96.59 45.05,97.74 46.06,98.75 46.06,99.39 46.51,99.83 46.51,101.1 45.9,101.71 v2(45.9,103.8)
  BOTTOM w0.254: v2(36.96,59.82) 36.35,59.21 32.93,59.21 32.68,58.95 32.68,57.07 PR1255.1
  vias: v2(32.41,117.23) v2(32.41,116.62) v2(32.41,116.03) v2(33.04,117.23) v2(33.04,116.62) v2(33.04,116.03) v2(40.22,114.69) v2(40.22,114.08) v2(40.22,113.49) v2(40.85,114.69) v2(40.85,114.08) v2(40.85,113.49) v2(41.49,114.69) v2(41.49,114.08) v2(41.49,113.49) v2(45.59,104.89) v2(45.59,104.3) v2(46.2,104.89) v2(46.2,104.3) v2(46.51,105.42) v2(46.79,104.89) v2(46.79,104.3) v2(47.14,105.42) v2(47.37,104.89) v2(47.37,104.3) v4(36.61,115.76)
+BL_PWR_SRC: length 12.9
  TOP w1.524: 47.64,128.52 48.25,129.13 v4(48.25,130.14) 48.25,132.05 v4(49.3,133.11) 56.92,133.11
  vias: v2(59.14,131.65) v2(59.75,131.65) v2(60.35,131.65) v4(46.86,127.39)
+CHARGER_SRC:
  vias: v2(46.53,80.53) v2(47.01,79.07) v2(47.65,79.07) v2(48.47,79.07) v2(48.47,76.27) v2(48.47,75.64) v2(48.47,75) v2(48.47,74.37) v2(48.47,73.73) v2(49.11,79.07) v2(49.11,76.27) v2(49.11,75.64) v2(49.11,75) v2(49.11,74.37) v2(49.11,73.73) v4(48.56,77.84)
+COINCELL: length 4
  TOP w0.127: v1(283.31,7.59) 283.51,7.59 v2(283.95,8.03)
  TOP w0.508: v2(283.95,8.03) 283.95,8.03 PC2.2 283.93,8.98 PR2.1
  BOTTOM w0.508: JRTC1.1 v2(283.95,8.03)
+DC_IN: length 95.9
  TOP w0.508: v2(42.71,53.56) 42.5,53.35 PR1201.1
  IN2 w0.508: v2(45.13,119.38) 46,118.51 46,114.76 44.32,113.08 44.32,108.93 43.56,108.16 43.56,96.61 42.49,95.54 42.49,88.76 42.85,88.4 42.85,79.58 39.17,75.89 39.17,67.04 42.57,63.64 42.57,56.65 43.2,56.02 43.2,53.93 42.83,53.56 v2(42.71,53.56)
  BOTTOM w0.508: PU2.2 65.81,120.15 PC11.1 63.08,120.15 62.1,121.13 v1(62.1,121.66) 62.1,122.41 60.62,123.9 49.13,123.9 47.99,122.76 47.14,122.76 46.62,122.24 PR12.1
+DC_IN_SS: length 76.7
  TOP w0.127: v2(56.04,117.36) v1(55.41,117.36)
  IN2 w0.508: v2(46.51,61.67) 47.34,62.49 56.59,62.49 58.72,64.63 58.72,69.89 57.55,71.05 57.55,77.61 55.76,79.4 55.76,83.71 57.96,85.91 57.96,94.37 58.95,95.36 58.95,98.28 58.27,98.97 58.27,101.75 59.66,103.15 59.66,106.81 58.93,107.54 58.93,110.46 58.09,111.3 58.09,115.31 v2(56.04,117.36)
  BOTTOM w0.508: PD5.3 54.27,117.99 54.9,117.36 v2(56.04,117.36) ; PD904.2 v2(46.51,61.67)
+DCIN_JACK: length 4.9
  TOP w0.127: v2(40,118.95) 41.16,118.95 v4(41.86,118.25) ; v2(40,118.95) 38.64,118.95 v4(38.15,118.45) ; v2(40,118.95) v4(40,118.27)
+DCPRTC: length 9
  TOP w0.381: CC214.1 131.81,85.39 131.47,85.74 v2(131.47,86.69)
  BOTTOM w0.203: UC1.BB10 126.85,90.35 127.23,89.98 127.81,89.98 128.37,89.42 128.74,89.42 v1(130.76,87.39) v2(131.47,86.69)
+DDR_VREF_A_CA: length 6.4
  TOP w0.127: v2(118.97,55) v1(118.97,55.65)
  TOP w0.508: RD16.1 CD25.1 ; CD25.1 117.89,53.29 RD17.1 ; CD25.1 CD26.1 ; CD26.1 118.76,54.78 v2(118.97,55) ; CD26.1 RD15.2
  BOTTOM w0.305: v2(118.97,55) 118.97,53.7 JDIMM1.164
+DDR_VREF_A_DQ: length 1.1
  TOP w0.254: T132.1 v2(93.09,91.98)
  BOTTOM w0.203: v2(93.09,91.98) 93.34,91.73 UC1.AY68
+DDR_VREF_B_DQ: length 1.3
  TOP w0.254: v2(93.7,91.22) 94.13,90.79 T226.1
  BOTTOM w0.203: v2(93.7,91.22) 93.81,91.34 UC1.BA67
+DDR_VREF_CA: length 104.9
  TOP w0.508: RD17.2 CD31.1 v2(116.99,51.76) ; v2(74.38,64.15) 74,64.15 73.49,64.65 v4(73.49,66.2) 73.49,67.83 78.51,72.85 78.51,81.54 76.48,83.58 v2(74.67,83.58)
  IN1 w0.508: v2(74.38,64.15) 76.54,61.99 76.54,54.56 77.24,53.86 116.36,53.86 116.99,53.22 v2(116.99,51.76)
  BOTTOM w0.203: UC1.AY67 94.2,91.85 94.55,91.51 94.55,90.8 94.72,90.63 94.72,90.05 94.4,89.74 92.01,89.74 91.53,89.25
  BOTTOM w0.508: v2(74.67,83.58) 87.2,83.58 90.47,86.85 90.47,88.2 91.53,89.25
+EC_DEBUG_VCC: length 1.4
  TOP w0.127: v2(289.93,126.88) 289.33,127.48 v4(288.76,127.48)
+EDP_VDD:
  vias: v4(67.59,126.76)
+LCDVDD: length 5.2
  TOP w0.127: v4(68.43,132.73) 67.54,131.84 66,131.84 ; v4(63.33,127.53) 63.63,127.82 64.79,127.82 ; v4(66.58,132.31) 65.81,132.31
  vias: v2(65.43,131.13) v2(65.43,130.55) v2(65.43,129.98)
+LINE1-VREFO-L: length 2.3
  TOP w0.203: UA1.31 257.53,56.55 257.45,56.47 v1(257.45,56.03) RA57.1
+LINE1-VREFO-R: length 2.5
  TOP w0.203: RA58.1 257.01,55.46 257.01,56.5 257.13,56.61 UA1.30
+MIC2-VREFO: length 16.2
  TOP w0.203: 256.5,56.36 256.5,56.46 256.73,56.69 UA1.29
  TOP w0.254: v2(256.06,53.35) 255.93,53.48 255.93,55.79 v1(256.14,56.01) 256.5,56.36
  TOP w0.508: v2(250.22,60.63) 250.56,60.97 RA6.1 RA5.1
  IN2 w0.508: v2(250.22,60.63) 250.22,60.06 251.08,59.19 251.86,59.19 252.82,58.24 252.82,57.22 256.06,53.99 v2(256.06,53.35)
+PBATT: length 126.2
  TOP w0.254: v2(58.22,51.46) 58.22,51.9 PR940.1
  TOP w0.508: PL1.2 170.75,59.28 168.35,59.28 167.97,58.91 167.44,58.91 163.32,54.79 v2(163.32,51.93)
  IN1 w0.508: v2(163.32,51.93) 161.95,51.93 159.35,54.53 148.68,54.53 145.69,51.55 144.67,51.55 144.16,51.96 v2(144.14,52.11)
  IN3 w0.508: v2(58.22,51.46) 58.22,51.97 59.13,52.88 63.69,52.88 65.87,55.06 69.18,55.06 71.22,53.02 72.06,53.02 74.8,50.28 138.99,50.28 141.5,52.79 143.46,52.79 v2(144.14,52.11)
  vias: v4(176.35,59.42)
+PECI_VREF: length 7
  TOP w0.254: UE1.J11 v2(253.48,92.26)
  TOP w0.381: v2(253.96,94.37) 254.46,94.87 254.46,96.14 254.76,96.44 CE25.1 RE59.1
  BOTTOM w0.254: v2(253.48,92.26) 253.01,92.73 253.01,93.89 253.49,94.37 v2(253.96,94.37)
+PWR_SRC: length 145.4
  TOP w0.254: v2(224.46,52.11) 223.72,52.11 223.53,52.3 RZ85.1
  IN2 w0.508: v2(47.79,58.43) 48.58,59.22 52.07,59.22 54.57,61.72 57.02,61.72 57.94,62.63 62.7,62.63 63.21,63.14 63.21,64.23 60.67,66.77 v2(60.67,67.07)
  IN2 w1.524: 57.17,119.29 56.51,119.95 55.03,119.95 52.3,122.68 46,122.68 44.95,121.63
  IN3 w1.524: 58,116.47 58,112.22 59.14,111.07 59.14,107.58 60.48,106.25 60.48,99.07 58.57,97.16 58.57,95.13 57.62,94.18 57.62,86.31 56.41,85.1 56.41,83.26 57.36,82.31
  BOTTOM w0.254: PR102.2 181.82,59.12 180.77,59.12 180.16,58.51 179.59,58.51 179.03,59.07 178.33,59.07 176.81,57.54 176.81,52.2 178.95,50.05 180.2,50.05 v2(180.32,50.17) ; v2(224.46,52.11) 221.84,49.49 183.72,49.49 ; v2(61.3,67.07) 61.76,66.61 PR929.2
  BOTTOM w0.508: PD901.2 46.9,57.54 v2(47.79,58.43)
  vias: v2(42.13,122.17) v2(42.73,122.17) v2(43.31,122.17) v2(57.62,117.93) v2(58,117.49) v2(58.38,117.93) v2(58.42,81.86) v2(58.4,81.16) v2(58.42,80.49) v2(60.03,76.08) v2(60.03,74.37) v2(60.03,72.78) v2(60.03,70.94) v2(60.67,76.08) v2(60.67,74.37) v2(60.67,72.78) v2(60.67,70.94) v2(60.67,68.65) v2(61.3,68.65) v2(73.49,77.48) v2(73.49,76.85) v2(73.49,76.21) v2(74.13,77.48) v2(74.13,76.85) v2(74.13,76.21) v2(74.76,77.48) v2(74.76,76.85) v2(74.76,76.21) v2(164.72,51.88) v2(164.72,51.24) v2(164.72,50.61) v2(165.35,51.88) v2(165.35,51.24) v2(165.35,50.61) v2(165.99,51.88) v2(165.99,51.24) v2(165.99,50.61) v2(166.62,51.88) v2(166.62,51.24) v2(166.62,50.61) v2(167.26,51.88) v2(167.26,51.24) v2(167.26,50.61) v2(167.89,51.88) v2(167.89,51.24) v2(167.89,50.61) v2(168.53,51.88) v2(168.53,51.24) v2(168.53,50.61) v2(180.32,49.58) v2(180.9,50.17) v2(180.9,49.57) v2(181.54,50.17) v2(181.54,49.57) v2(182.17,50.17) v2(182.17,49.57) v4(165.66,52.94)
+PWR_SRC_AC:
  vias: v2(50.95,81.23) v2(50.95,80.59) v2(51.59,81.23) v2(51.59,80.59) v2(52.22,81.23) v2(52.22,80.59) v2(52.86,81.23) v2(52.86,80.59) v2(53.49,81.23) v2(53.49,80.59) v4(53.81,82.61)
+PWR_SRC_R: length 22.9
  TOP w0.254: v2(234.16,60.03) 234.16,59.9 235.95,58.11 235.95,51.92 235.06,51.03 v4(231.09,51.03) 229.69,51.03 228.57,52.14 226.82,52.14 226.12,52.84 RZ85.2
  BOTTOM w0.305: v2(234.16,60.03) 234.16,59.82 233.86,59.51 233.68,59.51 233.45,59.28 JUSH1.1
+REGCTL_PNP10: length 1.5
  BOTTOM w0.127: LL1.1 v1(249.96,125.07)
  vias: v2(246.53,121.78) v2(246.53,121.2) v2(250.79,124.41) v2(251.24,124.06)
+RREF: length 5.1
  TOP w0.127: v1(269.78,60.81) 270.04,60.81 RR4.1
  TOP w0.203: UR1.9 273.87,62.5 273.68,62.32
  TOP w0.305: RR4.1 271.55,62.32 273.68,62.32
+RSVD_VCC3P3_1: length 4
  TOP w0.203: RL6.1 v1(242.07,121.8) 242.71,122.44 243.87,122.44 244.08,122.64 UL1.1
+RTC_CELL: length 399.1
  TOP w0.381: v2(124.42,90.13) 125.27,90.13 126.49,88.91 126.49,85.46 126.77,85.18 126.77,84.62 CC270.1 126.49,83.95 RC69.2
  TOP w0.508: PD3.1 PC3.1 285.58,13.47 285.58,23.7 280.5,28.78 280.5,49.67 278.41,51.76 278.41,54.29 v2(277.84,54.85) ; v2(248.5,59.07) RA54.2 ; v2(143.18,80.08) 144.03,80.08 144.63,79.49 144.63,76.06 149.6,71.08 160.81,71.08 v4(161.88,72.15) 163.16,73.43 169.71,73.43 171.32,75.04 177.14,75.04 arc(180.69,73.24) 184.1,71.16 arc(188.1,69.64) 192.33,68.97 209.78,68.97 213.69,72.88 220.34,72.88 arc(223.62,74.32) 225.05,77.59 225.05,77.87 v2(225.74,78.56) ; v2(233.37,77.43) 233.03,77.77 233.03,81.56 235.29,83.82 237.13,83.82 237.81,84.5 RE507.2 RE508.2 ; v2(245.07,78.64) RE31.1 RE32.1 ; RC56.2 v2(130.77,80.66) 130.45,80.34 128.93,80.34 127.21,82.05 126.83,82.05 126.5,82.38 RC57.2 RC69.2 ; v2(229.45,88.78) 229.91,89.24 229.91,95.57 229.06,96.41 229.06,109.37 235.76,116.06 237.31,116.06 239.46,113.92 241.32,113.92 243.41,111.83 v2(245.42,111.83) ; RE324.2 246.21,74.43 v2(246.05,74.27)
  IN1 w0.508: v2(233.37,77.43) 237.82,77.43 239.13,76.13 239.13,73.18 241.16,71.14 242.5,71.14 243.64,72.27 243.64,72.53 245.31,74.21 245.99,74.21 v2(246.05,74.27) 246.05,75.38 245.07,76.36 v2(245.07,78.64) ; v2(130.77,80.66) 130.77,78.43 131.67,77.53 138.28,77.53 140.82,80.08 v2(143.18,80.08) ; v2(225.74,78.56) 225.77,78.59 225.77,79.4 229.45,83.08 v2(229.45,88.78)
  IN2 w0.508: v2(225.74,78.56) 231.01,78.56 232.14,77.43 v2(233.37,77.43) ; v2(277.84,54.85) 274.43,54.85 272.58,56.7 267.04,56.7 262.76,52.42 252.46,52.42 250.75,54.13 250.75,56.95 248.63,59.07 v2(248.5,59.07)
  IN3 w0.508: v2(277.84,54.85) 277.84,57.66 278.61,58.43 278.61,61.5 279.37,62.27 281.58,62.27 282.43,63.11 282.43,71.43 281.65,72.21 281.65,80.15 276.08,85.71 276.08,96.97 275.27,97.78 273.49,97.78 271.74,99.53 271.74,103.62 264.67,110.69 v2(264.16,110.69)
  BOTTOM w0.178: UC1.BB14 124.43,90.15 v2(124.42,90.13)
  BOTTOM w0.254: UC1.AK19 v2(121.07,97.34)
  BOTTOM w0.508: v2(245.42,111.83) 245.42,111.74 246.94,110.21 251.71,110.21 252.37,110.88 263.97,110.88 v2(264.16,110.69)
+RTC_CELL_VBAT: length 6.3
  TOP w0.127: v1(245.17,80.41) RE32.2
  TOP w0.254: RE32.2 244.24,81.14 CE11.1 244.22,81.39 v2(244.65,81.82) ; v2(246.18,84.28) 246.3,84.28 UE1.A2
  IN1 w0.254: v2(246.18,84.28) 246.18,83.35 v2(244.65,81.82)
+SDC_IN: length 49.3
  TOP w0.508: PR944.1 51.73,62.14 52.31,61.56 v2(52.31,60.59) PR943.1 ; PR10.1 51.84,114.96 51.59,114.7 PQ5.3 50.53,114.77 47.79,114.77 46.61,113.59 46.61,112.56 45.24,111.19 45.24,110.37 45.68,109.93 47.15,109.93 PC1203.1
  IN3 w0.508: v2(46.12,84.91) 46.06,84.85 46.06,81.23 44.47,79.64 44.47,74.62 40.85,71 40.85,69.07 46.82,63.11 51.2,63.11 52.31,61.99 v2(52.31,60.59)
  vias: v2(46.63,85.23) v2(47.14,84.91) v2(47.65,85.23) v2(48.16,84.91) v2(48.66,85.23) v2(48.79,111.2) v2(48.79,110.56) v2(49.17,84.91) v2(49.43,111.2) v2(49.43,110.56) v2(49.68,85.23) v2(50.06,111.2) v2(50.06,110.56) v2(50.19,84.91) v2(50.7,111.2) v2(50.7,110.56) v2(50.7,85.23) v2(51.33,111.2) v2(51.33,110.56) v4(50.18,85.9)
+SDREG2: length 1.4
  TOP w0.127: CR15.1 v1(278.79,68.86)
+SIM_PWR: length 100.1
  TOP w0.127: v2(240.71,103.99) v4(241.67,103.99)
  IN3 w0.508: v2(277.39,62.71) 277.22,62.89 v2(272.1,62.89)
  BOTTOM w0.305: JNGFF2.28 239,103
  BOTTOM w0.508: RZ335.1 276.87,55.75 274.39,58.23 272.24,58.23 270.93,59.54 270.93,62.44 271.33,62.85 272.07,62.85 v2(272.1,62.89) 272.1,70.85 272.07,70.89 272.07,94.92 267.66,99.32 267.47,99.32 267.07,99.73 267.07,102.8 265.81,104.06 251.38,104.06 250.79,103.47 245.95,103.47 245.43,103.99 v2(240.71,103.99) 239.72,103 239,103 ; v2(277.39,62.71) 277.65,62.46 CZ41.1 CZ37.1 279.28,62.06 280.5,60.84 284.22,60.84 JSIM1.C1
+TBTA_LDO_BMC: length 3.4
  TOP w0.203: UT5.E1 32.02,84.15 32.18,84.31 32.18,85.35 32.43,85.61 32.68,85.61 CT71.1
+TBTA_VBUS: length 1.2
  BOTTOM w0.381: CT100.1 v2(9.36,110.59) 9.38,110.62 CT189.1
  vias: v2(8.74,108.39) v2(8.74,105.88) v2(9.32,108.39) v2(9.35,105.88) v2(16.66,115.77) v2(16.66,115.14) v2(16.66,114.5) v2(17.3,115.77) v2(17.3,115.14) v2(17.3,114.5) v2(21.3,115.77) v2(21.3,115.14) v2(21.3,114.5) v2(21.93,115.77) v2(21.93,115.14) v2(21.93,114.5) v4(21.74,113.73)
+TBTA_VBUS_1: length 36.5
  TOP w0.508: v2(38.05,52.89) 37.96,52.89 PR1239.1 ; PR1227.1 27.85,121.81 27.99,121.68 PQ1206.5
  IN2 w0.508: 21.68,74.88 21.68,67.84 22.73,66.79 22.73,60.49 30.33,52.89 v2(38.05,52.89)
  vias: v2(16.09,79.45) v2(16.09,78.88) v2(16.09,78.31) v2(16.66,78.88) v2(16.66,78.31) v2(17.23,78.31) v2(26.44,117.3) v2(26.44,116.66) v2(26.44,116.03) v2(26.44,115.39) v2(26.44,114.69) v2(26.44,114.06) v2(28.47,77.2) v2(28.71,77.71) v2(29.04,77.2) v2(29.28,77.71) v2(29.6,77.2) v2(29.84,77.71) v2(34.49,78.88) v4(27.2,114.25)
+USB_EX2_PWR: length 3.5
  TOP w0.127: v4(19.2,70.27) 18.22,69.29 18.22,67.36 v2(18.06,67.19)
  vias: v2(18.06,66.56) v2(18.57,57.73) v2(18.57,57.1) v2(18.57,56.46) v2(18.57,55.83) v2(18.69,67.19) v2(18.69,66.56)
+UZ12_TPM:
  vias: v1(162.25,113.89)
+VCHGR:
  vias: v1(175.92,53)
+VHDMI_VCC: length 1.1
  TOP w0.254: RV22.2 16.46,90.77 v2(15.9,90.21)
  vias: v2(15.9,89.08) v2(15.9,88.47) v4(14.34,88.77)
+VR_CAP: length 24.8
  TOP w0.254: CE31.1 254.79,81.24 v2(254.53,81.49) v1(253.99,82.04) 253.08,82.94 UE1.J1 ; UE1.C10 v2(247.88,91.46)
  IN2 w0.381: v2(244.91,83.09) 249.17,83.09 v2(249.5,82.76)
  IN3 w0.381: v2(247.88,91.46) 246.99,91.46 245.88,90.35 245.88,85.21 244.91,84.24 v2(244.91,83.09) ; v2(249.5,82.76) 249.63,82.89 253.13,82.89 v2(254.53,81.49)
+Z4012: length 3.1
  TOP w0.102: v1(285.51,8.63) 285.25,8.89 PD3.2
  TOP w0.508: PD3.2 284.42,10.82 PR2.2
AC1_DISC#: length 51
  TOP w0.112: PR1244.1 40.71,52.3 41.01,52.59 42.7,52.59 43.08,52.98 43.52,52.98 43.52,52.97 v1(44.22,53.67) v2(44.22,57.35) ; RT72.1 v2(29.93,74.81)
  IN1 w0.119: v2(29.93,74.81) 28.73,74.81 26.91,73 26.91,67.84 24.42,65.35 23.58,65.35 22.95,64.72 22.95,60.4 26,57.35 v2(44.22,57.35)
  BOTTOM w0.254: PR939.1 v2(44.22,57.35)
AC1_DISC#_R: length 2.6
  TOP w0.076: UT5.G11 31.02,77.74 30.59,77.31
  TOP w0.112: 30.59,77.31 29.93,76.66 RT72.2
AC_DIS: length 306.2
  TOP w0.107: UE1.H12 252.7,93.08 252.7,95.13 252.82,95.25 252.82,97.1 252,97.92 v2(251.8,97.92) RE83.1
  IN2 w0.124: v2(49.91,55.79) 51.36,55.79 52.5,54.65 58.71,54.65 59.41,53.95 60.29,53.95 61.91,55.57 69.27,55.57 70.25,54.59 71.29,54.59 74.8,51.08 138.65,51.08 142.24,53.87 146.5,53.87 148.25,55.62 158.55,55.62 160.87,53.3 169.92,53.3 173.28,49.95 178.6,49.95 179.83,51.18 182.78,51.18 184.07,49.88 209.31,49.88 210.82,51.39 213.11,51.39 213.71,50.79 237.87,50.79 240.42,53.33 240.42,54.12 242.56,56.26 244.28,56.26 246.15,58.13 246.15,59.98 249.86,63.69 252.22,63.69 252.68,64.15 257.38,64.15 257.83,63.69 258.67,63.69 259.74,64.76 260.89,64.76 263.44,67.31 268.64,67.31 271.65,70.32 271.65,77.48 267.74,81.39 267.74,84.27 267.23,84.78 267.23,87.34 270.52,90.63 v2(271.28,90.63)
  IN3 w0.135: v2(251.8,97.92) 253.2,97.92 254.93,99.65 254.93,101.92 255.87,102.86 263.22,102.86 264.16,101.92 266.83,101.92 268.37,100.37 268.37,98.94 270.46,96.86 270.46,91.45 v2(271.28,90.63)
  BOTTOM w0.254: v2(49.91,55.79) 50.14,55.79 PQ909.2 50.55,57.03 PR927.1
AC_DISC#: length 388.5
  TOP w0.112: PR25.2 53.41,115.83 52.97,116.28 48.47,116.28 v1(47.59,115.4) 45.81,113.61 45.81,112.57 43.18,109.94 v2(42.7,109.94) ; PC1217.1 249.29,96.87 v2(249.29,95.64) 249.28,95.64 249.28,95.32 249.88,94.72 UE1.E13 ; PR1231.1 v2(50.06,50.48)
  IN2 w0.124: v2(265.94,82.09) 265.94,82.84 264.97,83.81 264.97,87.67 262.9,89.74 262.9,92.21 261.97,93.14 260.75,93.14 259.15,94.74 259.15,98.79 258.85,99.09 257.7,99.09 257.53,98.92 256.95,98.92 254.68,96.65 251.77,96.65 250.77,95.64 v2(249.29,95.64) ; v2(265.65,66.69) 265.17,66.21 262.74,66.21 261.06,64.53 259.87,64.53 258.8,63.46 257.73,63.46 257.3,63.89 252.78,63.89 252.34,63.45 249.95,63.45 246.43,59.93 246.43,58.06 244.39,56.01 242.67,56.01 240.67,54.02 240.67,53.23 238,50.56 213.62,50.56 213.02,51.16 210.91,51.16 209.4,49.65 183.98,49.65 182.68,50.95 179.97,50.95 178.71,49.69 173.18,49.69 169.79,53.08 160.77,53.08 158.46,55.39 148.38,55.39 146.6,53.62 142.29,53.62 138.72,50.86 74.71,50.86 71.2,54.36 70.15,54.36 69.17,55.35 62.14,55.35 61.43,54.63 61.43,52.06 60.31,50.93 50.95,50.93 50.49,50.48 v2(50.06,50.48) 50.06,51.51 48.73,52.84 48.73,53.54 47.52,54.75 44.79,54.75 43.08,53.03 42.44,53.03 42.02,53.45 42.02,61.64 38.7,64.97 38.7,76.08 40.41,77.8 40.41,81.35 39.71,82.05 39.71,83.45 41.81,85.55 41.81,93.28 41.48,93.61 41.48,103.69 42.24,104.46 42.24,107.68 43.36,108.8 43.36,109.43 42.85,109.94 v2(42.7,109.94)
  BOTTOM w0.112: v2(42.7,109.94) 42.7,109.79 42.27,109.36 41.61,109.36 PR1223.2 ; v2(265.65,66.69) 264.51,67.83 262.36,67.83 261.15,69.04 261.15,70.45 262.02,71.33 262.02,73.2 264.44,75.62 264.44,79.81 265.94,81.31 v2(265.94,82.09) ; PR1245.1 51.07,52.08 PQ1210.6 50.58,51.78 50.19,51.38 50.19,50.61 v2(50.06,50.48) PQ1211.3 49.19,50.48 47.89,51.78 PQ1211.6
AC_PRESENT: length 187.8
  TOP w0.107: UE1.K8 v2(254.28,89.86)
  TOP w0.112: v2(138.11,79.54) 137.6,79.54 RC243.1
  IN2 w0.124: v2(143.84,79.11) 145.01,77.94 145.01,74.48 147.12,72.37 147.12,71.99 149.68,69.43 150.06,69.43 150.59,68.9 159.18,68.9 162.58,65.49 170.7,65.49 174.07,62.12 202.45,62.12 203.62,60.95 213.97,60.95 215.02,59.91 220.13,59.91 221.09,58.94 236.05,58.94 236.35,59.23 242.07,59.23 243,60.17 243,61.15 245.33,63.48 245.33,64.93 247.62,67.22 249.12,67.22 251.23,69.33 256.94,69.33 v2(257.1,69.48)
  BOTTOM w0.076: UC1.AY15 123.55,91.53 123.55,91.25 123.44,91.14 123.44,89.28 125.42,87.3
  BOTTOM w0.112: v2(254.28,89.86) 254.69,90.27 256.1,90.27 256.37,90 256.37,87.36 257.76,85.97 257.76,84.96 258.45,84.27 258.45,81.77 257.82,81.13 257.82,79.81 256.95,78.94 256.95,77.32 257.68,76.59 257.68,75.65 256.72,74.69 256.72,73.71 257.88,72.54 257.88,70.27 v2(257.1,69.48) ; v2(143.84,79.11) 143.84,78.52 143.41,78.09 142.54,78.09 142.14,78.5 142.14,78.67 141.27,79.54 v2(138.11,79.54) 136.65,79.54 135.86,78.75 131.05,78.75 127.72,82.08 127.72,84.59 126.26,86.05 126.26,86.46 125.42,87.3
ACAV_IN: length 311.8
  TOP w0.107: UE1.C7 v2(247.88,88.26)
  TOP w0.112: v2(244.33,111.17) 243.48,111.17 241.17,113.49 239.31,113.49 237.62,115.17 v2(237.35,115.17)
  TOP w0.254: v2(43.52,56.78) 43.46,56.72 PR953.1
  IN1 w0.119: v2(247.88,88.26) 247.46,87.83 247.46,87.26 247.2,87.01 246.68,87.01 244.17,89.52 244.17,90.51 241.87,92.81 241.87,103.03 243.97,105.13 243.97,110.81 v2(244.33,111.17)
  IN2 w0.124: v2(230.32,53.64) 229.79,54.17 209.2,54.17 208.97,53.94 204.77,53.94 203.99,53.15 202.67,53.15 202.12,53.7 202.12,56.52 200.43,58.2 196.37,58.2 195.55,59.02 183.92,59.02 183.4,58.5 183.4,58.04 182.35,56.98 180.11,56.98 179.4,57.69 178.19,57.69 176.1,55.6 164.73,55.6 162.87,57.47 v2(145.08,57.47) ; v2(236.35,82.2) 236,82.54 236,85.41 237.59,87 237.59,87.5 238.69,88.6 240.44,88.6 241.27,87.77 242.52,87.77 242.94,87.35 246.06,87.35 246.97,88.26 v2(247.88,88.26)
  IN3 w0.135: v2(43.52,56.78) 44.54,56.78 44.98,57.22 50.1,57.22 52.81,54.52 58.61,54.52 59.07,54.06 60.63,54.06 62.48,55.92 69.77,55.92 71.83,53.86 72.62,53.86 75.26,51.22 135.79,51.22 138.63,54.06 142.7,54.06 145.08,56.45 v2(145.08,57.47)
  BOTTOM w0.112: v2(230.32,53.64) 230.33,53.64 230.83,54.15 231.23,54.15 232.98,55.9 232.98,57.04 235.84,59.9 235.84,62.3 235.43,62.71 235.43,65.19 234.95,65.67 234.95,67.17 234.78,67.34 234.78,70.12 235.19,70.52 235.19,79.58 235.92,80.31 235.92,81.77 v2(236.35,82.2) ; v2(237.35,115.17) 237.35,116.14 235.23,118.26 235.23,123.02 238.76,126.55 238.76,129.6 238.61,129.75 RE530.2 237.89,130.12 237.89,130.72 238.01,130.83 QE13.4
  BOTTOM w0.254: v2(43.52,56.78) 43.27,56.53 v1(43.27,56.14) PR946.2
ACAV_IN1: length 7.3
  BOTTOM w0.254: PR942.1 v1(49.33,54.75) 49.86,54.75 50.3,54.31 PQ909.1 51.4,54.31 52.81,55.71 PR928.1 PR918.1 53.72,56.58 PR925.1
ACAV_IN_NB: length 374.7
  TOP w0.107: v2(257.4,88.23) 257.03,87.86 UE1.N6
  TOP w0.203: PC1207.1 PR1203.2 40.28,56.22 v2(40.28,56.02) PR1206.2
  IN2 w0.124: v2(257.4,88.23) 257.91,87.72 258.25,87.72 261.21,84.76 261.8,84.76 262.22,84.34 262.22,80.29 262.38,80.12 262.38,76.41 260.81,74.84 259.11,74.84 258.29,75.66 255.58,75.66 255.38,75.46 251.32,75.46 250.52,74.66 249.55,74.66 249.19,75.02 242.05,75.02 240.82,76.24 238.99,76.24 238.29,76.94 237.02,76.94 236.84,76.76 236.84,75.88 236.19,75.23 236.19,74.24 235.14,73.19 234.22,73.19 232.6,71.58 231.69,71.58 229.33,69.22 227.48,69.22 226.45,68.18 222.91,68.18 222.25,67.52 207.31,67.52 206.04,68.79 186.09,68.79 184.36,70.52 181.2,70.52 171.17,80.54 171.17,83.19 168.71,85.66 168.71,88.13 166.79,90.05 166.79,105.82 162.38,110.22 162.38,116.23 160.76,117.85 160.76,121.04 155.08,126.73 148.66,126.73 147.28,128.11 147.28,129.02 146.68,129.61 144.54,129.61 142.77,131.39 141.42,131.39 140.18,132.63 135.89,132.63 134.62,131.37 131.07,131.37 130.14,130.44 127.01,130.44 126.52,129.94 125.1,129.94 124.46,130.58 124.46,130.8 124.03,131.23 118.79,131.23 117.63,130.06 108.54,130.06 108.04,129.56 104.83,129.56 103.95,130.44 83.81,130.44 80.19,126.82 74.59,126.82 74.23,127.17 63.78,127.17 60.33,123.72 58.32,123.72 v2(57.1,122.5)
  IN3 w0.135: v2(40.28,56.02) 40.38,56.02 41.6,54.8 43.6,54.8 44.92,53.48 v2(45.6,53.48)
  IN3 w0.254: v2(40.28,56.02) 40.28,63.57 39.2,64.65 39.2,75.89 40.94,77.63 40.94,79.37 43.87,82.3 43.87,86.53 46.57,89.23 46.57,91.26 47.88,92.57 47.88,96.57 48.54,97.23 52.86,97.23 54.85,99.22 54.85,109.84 53.57,111.12 53.57,114.73 55.37,116.54 v2(55.37,118.63)
  BOTTOM w0.112: PR1241.1 PR1258.1 v2(45.6,53.48) ; v2(55.37,118.63) 54.98,119.02 54.98,121.61 55.87,122.5 v2(57.1,122.5) 57.69,121.91 PR21.1
  BOTTOM w0.203: PR941.1 40.73,57.52 v1(40.59,57.38) 40.28,57.07 v2(40.28,56.02) 40.31,56.04 PU1201.1
ACIN_ISL88738: length 8.2
  TOP w0.127: PR944.2 v1(50.58,63.27)
  TOP w0.203: 53.71,57.85 53.92,57.64 PU901.19
  TOP w0.254: PR944.2 50.58,61.96 PR945.1 PC1286.1 52.13,59.5 52.13,58.34 52.63,57.85 53.71,57.85
ACOK_ISL88738: length 3.8
  TOP w0.112: v2(52.98,54.11) 52.98,53.99 v1(52.55,53.55)
  TOP w0.203: PU901.24 54.15,55.64 52.98,54.47 v2(52.98,54.11)
  BOTTOM w0.254: PR928.2 v2(52.98,54.11)
ADP_ISL88738: length 4
  TOP w0.112: 54.51,60.59 54.51,60.79 53.36,61.94 v1(52.89,61.94)
  TOP w0.203: PU901.16 55.12,59.44 54.51,60.06 54.51,60.59
ALW_PWRGD_3V_5V: length 38.7
  TOP w0.254: v2(205.43,54.95) 205.43,55.87 v1(204.7,56.6) 204.21,57.08 204.21,58.58 203.73,59.07 UZ6.2
  IN1 w0.254: v2(190.19,52.13) 190.77,51.55 195.9,51.55 196.73,52.39 202.87,52.39 v2(205.43,54.95)
  IN2 w0.254: v2(190.19,52.13) 185.9,52.13 184.71,53.33 180.06,53.33 178.33,55.05 v2(178.33,56.73)
  BOTTOM w0.254: v2(178.33,56.73) 178.37,56.69 PR119.2 179.04,56.7 PR120.2
ALWON: length 103.5
  TOP w0.107: v2(244.58,86.09) 245.32,86.83 246.45,86.83 UE1.A5
  TOP w0.112: v2(239.67,56.57) v1(239.67,57.5)
  IN2 w0.124: v2(202.56,53.81) 203.81,53.81 204.23,54.23 208.89,54.23 209.06,54.4 229.57,54.4 229.8,54.62 234.94,54.62 237.28,56.97 239.27,56.97 v2(239.67,56.57)
  BOTTOM w0.112: v2(244.58,86.09) 244.58,83.61 244.47,83.5 244.47,82.97 245.36,82.08 245.36,80.99 245.7,80.65 245.7,79.18 245.79,79.08 245.79,76.4 247.1,75.09 247.1,71.75 245.97,70.61 245.97,69.96 244.98,68.97 244.98,68.24 245.18,68.03 245.18,67.5 245.41,67.27 245.41,66.08 244.79,65.46 244.79,62.57 243.32,61.1 243.32,60.02 239.86,56.57 v2(239.67,56.57) ; v2(202.56,53.81) 203.35,54.59 203.35,56.44 201.12,58.67 201.12,59.89 198.83,62.19 185.63,62.19 184.33,60.88 PD100.2
  BOTTOM w0.254: PR114.1 183.74,59.89 PD100.2
AR_DET#: length 7.7
  BOTTOM w0.076: RC401.1 RC400.1 136.56,107.29 v1(135.66,107.29) 134.09,107.29 133.13,106.34 132.44,106.34 131.99,106.12 130.76,106.12 UC1.P4
AUD_HP_NB_SENSE: length 74.2
  TOP w0.254: RA60.2 254.67,68.45 v2(254.63,68.41)
  BOTTOM w0.254: v2(254.63,68.41) 254.63,65.85 254.99,65.49 254.99,64.25 255.34,63.89 257.02,63.89 257.48,63.43 259.28,63.43 261.5,65.64 262.71,65.64 263.19,66.13 267.18,66.13 267.74,65.57 267.74,60.51 271.03,57.22 273.09,57.22 276.31,54 276.31,47.75 277.09,46.98 277.09,31.74 280.26,28.56 v2(282.23,28.56) 282.99,28.56 DA2.3 287.41,29.34 289.67,31.6 JHP1.6
AUD_HP_OUT_L: length 41.1
  TOP w0.381: RA57.2 RA7.2 v4(258.34,51.36) v2(258.34,50.68) ; RA55.1 v2(281.32,37.6)
  IN3 w0.381: v2(258.34,50.68) 265.25,50.68 269.12,54.56 272.07,54.56 281.32,45.31 v2(281.32,37.6)
AUD_HP_OUT_L1: length 11.3
  TOP w0.102: RA55.2 v1(282.23,38.21)
  TOP w0.381: RA55.2 CA3.1 283.09,37.23 v2(282.73,37.6)
  BOTTOM w0.381: v2(282.73,37.6) 283.03,37.3 DA1.2 283.83,39.66 285.8,41.63 286.97,41.63 JHP1.1
AUD_HP_OUT_R: length 47.7
  TOP w0.381: RA58.2 256.69,53.97 v4(256.69,52.77) 256.69,51.19 257.83,50.05 v2(259.23,50.05) RA8.2 ; RA56.1 v2(281.32,35)
  IN3 w0.381: v2(259.23,50.05) 265.57,50.05 269.44,53.92 271.75,53.92 280.63,45.05 280.63,35.69 v2(281.32,35)
AUD_HP_OUT_R1: length 15.7
  TOP w0.381: JHP1.2 292.11,30.71 286.17,30.71 283.83,33.04 v4(283.83,33.35) v2(283.83,34.38) ; v2(282.79,35) 283.09,35.3 CA2.1 RA56.2
  BOTTOM w0.381: v2(283.83,34.38) DA1.3 283.16,35.37 v2(282.79,35)
AUD_NB_MUTE#: length 77.7
  TOP w0.107: v2(243.95,85.46) 244.07,85.46 244.16,85.38 245.8,85.38 UE1.A4
  TOP w0.112: DA8.1 262.79,69.38 262.6,69.19 v2(262.38,69.19) 262.37,69.2 262.24,69.2 261.95,69.49 RA48.1 261.77,69.8 262.23,70.25 v1(262.23,70.7)
  IN2 w0.124: v2(266.23,95.96) 266.07,95.8 266.07,84.34 266.56,83.85 266.56,78.82 266.09,78.35 266.09,74.92 262.38,71.21 v2(262.38,69.19)
  BOTTOM w0.112: v2(266.23,95.96) 266.23,96.18 263.83,98.59 263.83,100.33 263.72,100.44 261.8,100.44 260.93,101.31 260.93,101.97 260.09,102.8 254.02,102.8 252.58,101.36 251.43,101.36 250.7,100.62 246.35,100.62 245.38,99.66 243.66,99.66 243.29,99.29 243.29,98.86 243.95,98.19 v2(243.95,85.46)
AUD_PC_BEEP: length 5.5
  TOP w0.112: v1(249.93,61.73) 250.59,62.39 250.59,62.55 CA28.2 CA27.2 252.3,62.37 252.84,62.37 253.87,61.34 UA1.16
AUD_PWR_EN: length 171.5
  TOP w0.112: UZ5.3 244.45,64.23 244.38,64.16 v2(244.08,64.16) 243.97,64.04 v1(243.56,64.04) 243.43,63.92 243.43,63.33 243.55,63.21 244.55,63.21 244.77,63.43 UZ5.5
  IN2 w0.124: v2(144.71,105.55) 144.56,105.4 144.56,102.94 144.8,102.7 144.8,102.47 146.58,100.7 147.45,100.7 147.72,100.98 149.58,100.98 151.74,98.82 151.74,93.15 154.1,90.79 162.75,90.79 166.4,87.15 166.4,84.7 168.84,82.26 168.84,79.52 169.52,78.84 169.52,74.33 170.37,73.48 171.34,72.51 175.77,72.51 179.85,68.43 183.5,68.43 185.27,66.66 204.62,66.66 205.97,65.31 226.89,65.31 228.09,66.52 230.11,66.52 230.63,66 233.32,66 235.87,68.54 239.78,68.54 242.22,70.99 242.93,70.99 243.3,71.36 244.6,71.36 245.41,72.17 v2(248.47,72.17)
  IN3 w0.135: v2(144.71,105.55) 144.25,105.55 139.78,101.08 139.29,101.08 138.5,101.86 130.19,101.86 129.88,102.17 129.18,102.17 128.67,102.69 v2(128.67,102.71) ; v2(244.08,64.16) 244.36,64.16 247.01,66.81 247.01,69.58 247.45,70.01 247.45,71.15 v2(248.47,72.17)
  BOTTOM w0.076: UC1.W8 128.38,102.99 v2(128.67,102.71)
  BOTTOM w0.112: v2(144.71,105.55) 145.27,106.11 RC279.1
AUD_SENSE_A: length 11.2
  TOP w0.127: v2(254.02,68.41) 253.83,68.22 v1(253.5,68.22)
  TOP w0.254: v2(253.34,63.46) 253.19,63.61 252.86,63.61 CA41.1 252.93,64.02 253.67,64.02 254.28,63.41 UA1.13 ; v2(254.02,68.41) 254.02,68.9 RA60.1 RA59.2
  BOTTOM w0.254: v2(254.02,68.41) 254.02,66.61 253.34,65.92 v2(253.34,63.46)
AUD_SENSE_B: length 7
  TOP w0.112: RA61.2 252.72,67.31 v2(252.91,67.12) ; v2(253.52,62.29) 253.67,62.14 UA1.14
  BOTTOM w0.112: v2(253.52,62.29) 253.06,62.29 252.83,62.52 252.83,67.04 v2(252.91,67.12)
AUX1_SNOOP_EN#: length 2.6
  TOP w0.112: UT9.29 25.31,106.1 v1(24.53,106.87) 24.41,107 RT308.1
AUX_EN_WOWL: length 47.8
  TOP w0.107: v2(248.68,85.06) UE1.D3
  TOP w0.112: v2(249.91,104.07) 249.91,104.23 v1(250.18,104.5) 250.61,104.93 RZ38.2 251.17,105.73 RZ70.1
  IN1 w0.119: v2(257.38,84.06) 258.14,84.83 258.14,85.98 259.57,87.41 259.57,91.77 259.1,92.24 259.1,96.61 259.38,96.88 259.38,101.94 v2(259.54,102.09)
  IN2 w0.124: v2(249.91,104.07) 250.59,103.39 258.24,103.39 v2(259.54,102.09)
  IN3 w0.135: v2(257.38,84.06) 255.7,85.74 255.7,86.62 255.27,87.06 248.52,87.06 248.29,86.82 248.29,85.45 v2(248.68,85.06)
BAT1_LED#: length 131.9
  TOP w0.112: UE1.D10 v2(248.68,91.46)
  IN2 w0.124: v2(287.55,11.38) 287.04,11.89 287.04,12.27 288.14,13.36 288.14,23.6 280.02,31.72 280.02,54.2 282.14,56.32 282.14,61.91 283.49,63.26 283.49,69.48 281.33,71.64 277.9,71.64 277.2,72.34 275.97,72.34 273.71,74.6 273.71,79.01 270.46,82.26 v2(269.31,82.26) ; v2(255.97,94.94) 255.83,94.8 254.91,94.8 254.56,95.15 252.97,95.15 251.36,93.54 250.19,93.54 249.08,92.44 249.08,91.86 v2(248.68,91.46)
  IN3 w0.135: v2(255.97,94.94) 256.46,95.44 256.46,97.7 258.88,100.11 259.86,100.11 260.68,100.93 264.12,100.93 264.41,101.23 265.3,101.23 269.87,96.66 269.87,89.49 268.88,88.51 268.88,82.69 v2(269.31,82.26)
  BOTTOM w0.112: v2(269.31,82.26) v1(269.31,81.25) ; RZ28.1 v2(287.55,11.38)
BAT2_LED#: length 58.8
  TOP w0.112: v2(242.69,92.63) 242.32,93 RZ361.1 ; QZ2.1 271.38,84.94 v1(271.38,85.81) 271.13,86.07 270.61,86.07 270.2,86.47 v2(269.57,86.47) ; UE1.D11 v2(248.68,92.26)
  IN2 w0.124: v2(248.68,92.26) 248.68,92.6 251.79,95.7 v2(255.96,95.7)
  IN3 w0.135: v2(248.68,92.26) 249.07,92.64 249.07,94.86 247.87,96.06 243.5,96.06 242.37,94.93 242.37,92.94 v2(242.69,92.63) ; v2(269.57,86.47) 269.12,86.92 269.12,88.18 270.18,89.24 270.18,96.76 265.35,101.59 264.31,101.59 264.11,101.38 263.09,101.38 262.63,101.84 260.2,101.84 259.42,101.06 259.42,100.7 259.12,100.39 258.27,100.39 255.37,97.5 255.37,96.29 v2(255.96,95.7)
BAT2_LED#_R: length 93.4
  TOP w0.112: QZ2.3 271.6,83.24 271.87,83.51 271.87,84.08 272.33,84.54 QZ2.6 273.76,84.54 v2(273.77,84.53) 274.52,84.53 v1(275.63,83.42)
  IN2 w0.124: v2(287.55,12.01) 288.39,12.85 288.39,23.73 280.29,31.83 280.29,54.04 282.41,56.16 282.41,61.72 283.77,63.08 283.77,69.58 281.43,71.92 278,71.92 277.33,72.59 276.04,72.59 274.01,74.61 274.01,82.03 274.19,82.21 274.19,84.11 v2(273.77,84.53)
  BOTTOM w0.112: QZ3.2 286.49,10.95 v2(287.55,12.01)
BATT_WHITE#: length 148.3
  TOP w0.112: v2(237.44,53.76) 237.62,53.94 238.73,53.94 239.93,52.75 v2(239.93,51.93) ; RZ361.2 241.04,93.35 241.16,93.46 242.29,93.46 242.65,93.1 243.14,93.1 v2(243.27,92.97)
  IN2 w0.124: v2(239.93,51.93) 240.45,52.46 250.93,52.46 252.02,51.37 263.64,51.37 267.92,55.65 272.14,55.65 274.28,53.5 276.46,53.5 277.56,52.41 277.56,30.57 284.9,23.23 284.9,10.51 284.82,10.44 v2(284.82,8.9)
  BOTTOM w0.112: v2(237.44,53.76) 237.44,54.15 239.24,55.95 239.24,56.68 239.51,56.95 239.94,56.95 243.11,60.11 243.11,61.19 244.57,62.65 244.57,66.53 244.01,67.09 244.01,68.21 244.31,68.51 244.31,69.28 245.28,70.25 245.28,70.83 246.46,72.01 246.46,74.83 245.12,76.17 245.12,77.7 244.47,78.35 244.47,80.86 243.39,81.94 243.39,85.07 243.07,85.38 242.78,85.38 242.39,85.76 242.39,87.32 241.69,88.03 241.69,88.88 243.53,90.72 243.53,91.97 243.27,92.23 v2(243.27,92.97) ; v2(284.82,8.9) 284.82,9.39 QZ3.3 286.3,8.63 287.57,8.63 287.93,8.27 287.93,7.45 288.48,6.91 JLED1.3
BATT_YELLOW#: length 3.5
  BOTTOM w0.112: RZ28.2 287.55,9.13 v1(287.87,8.81) 288.26,8.42 288.26,7.91 288.47,7.71 JLED1.2
BBS_BIT6: length 12.6
  TOP w0.112: v2(130.24,95.95) 130.52,95.95 131.41,95.07 138.01,95.07 v1(139.61,96.67) 140.1,97.17 RC184.1
  BOTTOM w0.102: v2(130.24,95.95) 129.79,96.4 UC1.AN5
BC_CLK_ECE1117: length 79.3
  TOP w0.112: UE1.D13 248.98,93.57 248.98,94.64 248.35,95.26 248.35,96.23 247.97,96.61 v2(247.94,96.61) ; v2(208.53,57.81) 208.68,57.96 208.68,60.04 209.42,60.77 v1(218.5,60.77) 219.9,60.77 220.88,61.75 227.61,61.75 v2(228.05,62.19)
  IN3 w0.135: v2(247.94,96.61) 247.9,96.57 242.2,96.57 241.04,95.4 241.04,90.02 240.38,89.37 240.38,80.96 241.01,80.34 241.01,78.33 241.64,77.7 241.64,69.79 240.23,68.38 240.23,66.88 239.83,66.48 237.59,66.48 235.74,64.63 234,64.63 233.06,63.7 230.39,63.7 229.35,62.65 228.28,62.65 228.05,62.41 v2(228.05,62.19)
  BOTTOM w0.112: v2(208.53,57.81) 208.68,57.81 209.05,58.18 JKBTP1.11
BC_DAT_ECE1117: length 79.9
  TOP w0.107: UE1.D12 248.62,93.12 248.62,94.3 247.83,95.09 v2(247.83,95.54)
  TOP w0.112: v2(227.44,62.19) 227.38,62.25 v1(223.12,62.25) 220.68,62.25 219.7,61.26 209.15,61.26 208.19,60.3 RE365.1 207.9,58.2 v2(207.9,57.8)
  IN3 w0.135: v2(227.44,62.19) 227.44,61.6 227.64,61.39 228.83,61.39 230.62,63.18 233.28,63.18 234.21,64.12 236.01,64.12 237.23,65.33 239.92,65.33 240.74,66.16 240.74,68.16 243.29,70.71 243.29,73.53 242.19,74.64 242.19,77.91 241.58,78.52 241.58,80.53 240.9,81.21 240.9,89.16 243.74,92 243.74,94.8 244.75,95.82 247.55,95.82 v2(247.83,95.54)
  BOTTOM w0.112: v2(207.9,57.8) 207.9,57.97 208.05,58.13 JKBTP1.13
BC_INT#_ECE1117: length 59
  TOP w0.112: v1(216.51,70.38) 216.81,70.69 v2(216.81,70.97) ; UE1.E2 v2(249.48,84.26)
  IN2 w0.124: v2(249.48,84.26) 249.01,83.79 244.58,83.79 243.76,82.97 243.76,81.72 243.46,81.42 241.47,81.42 240.57,80.52 237.28,80.52 234.36,77.61 234.36,76.92 234.11,76.67 229.92,76.67 229.41,77.18 227.25,77.18 225.87,75.79 225.87,72.74 225.4,72.27 217.45,72.27 216.81,71.64 v2(216.81,70.97)
  BOTTOM w0.112: v2(216.81,70.97) 216.81,70.57 207.55,61.31 JKBTP1.14
BCM5882_ALERT#: length 56.1
  TOP w0.112: v2(230.22,60.01) 230.22,61.17 v1(230.45,61.4) ; UE1.G10 v2(251.08,91.46)
  IN3 w0.135: v2(251.08,91.46) 250.68,91.06 247.46,91.06 246.26,89.86 246.26,85.04 245.72,84.49 245.72,82.89 245.11,82.28 245.11,81.72 244.67,81.28 244.67,74.41 245.57,73.51 245.57,70.19 243.76,68.38 243.76,65.89 240.42,62.55 237.61,62.55 236.46,61.39 231.17,61.39 230.22,60.44 v2(230.22,60.01)
  BOTTOM w0.112: JUSH1.13 227.45,60.17 227.95,60.67 230.24,60.67 RE532.2 230.86,60.79 230.22,60.15 v2(230.22,60.01)
BEEP: length 28.4
  TOP w0.107: UE1.L9 v2(255.08,90.66)
  TOP w0.112: v2(249.93,66.46) RA13.2
  IN1 w0.119: v2(252.56,77.19) 252.56,81.23 253.08,81.76 253.08,90.05 253.29,90.26 254.84,90.26 255.08,90.5 v2(255.08,90.66)
  BOTTOM w0.112: v2(249.93,66.46) 250.24,66.76 250.24,68.64 251.84,70.24 251.84,73.06 252.56,73.78 v2(252.56,77.19)
BEEP_R: length 2.9
  TOP w0.112: CA28.1 251.43,64.3 CA62.1 RA45.1 RA13.1
BGATE_ISL88738: length 130.8
  TOP w0.203: PU901.32 57.92,54.64 58.25,54.3 58.63,54.3 v1(59.03,53.91) 59.27,53.67 PC937.2
  TOP w0.254: v2(60.73,53.47) 60.25,52.98 PC937.2 ; PQ906.4 177.54,53.4 v2(178.39,52.55)
  IN1 w0.254: v2(144.93,52.18) 145.36,52.18 148.21,55.03 159.84,55.03 161.54,53.33 177.61,53.33 v2(178.39,52.55)
  IN3 w0.254: v2(144.93,52.18) 143.52,53.6 138.78,53.6 136.02,50.84 75.05,50.84 72.35,53.54 71.61,53.54 69.59,55.56 62.89,55.56 60.79,53.47 v2(60.73,53.47)
BIA_PWM: length 14.8
  TOP w0.112: LV1.2 62.52,126.08 64.26,124.34 67.89,124.34 v1(68.64,125.09) 69.14,125.59 70.88,125.59 RV1.1 71.54,126.12 72.35,126.12 DV1.1
BIA_PWM_EC: length 241.9
  TOP w0.107: UE1.N1 v2(256.68,83.46)
  TOP w0.112: DV1.2 75.51,125.22 76.2,124.53 77.9,124.53 78.36,125 v2(78.36,125.47)
  IN2 w0.124: v2(255.85,75.01) 254.54,75.01 251.63,75.01 250.16,73.54 249.06,73.54 248.83,73.32 245.79,73.32 245.03,74.08 241.51,74.08 238.63,71.19 237.66,71.19 236.65,70.19 235.36,70.19 233.71,68.54 227.76,68.54 225.99,66.77 207.02,66.77 205.69,68.11 185.81,68.11 184.08,69.84 180.83,69.84 170.49,80.18 170.49,82.91 168.03,85.37 168.03,87.85 166.11,89.77 166.11,105.54 161.7,109.94 161.7,115.94 159.25,118.4 159.25,121.05 154.31,125.99 148.44,125.99 147.1,127.32 145.88,127.32 144.86,128.34 141.14,128.34 140.64,128.84 138.41,128.84 138.16,128.6 132.44,128.6 132,129.04 126.82,129.04 126.6,129.26 124.82,129.26 124.18,129.91 118.53,129.91 118,129.38 108.83,129.38 108.32,128.88 104.55,128.88 103.75,129.68 84.01,129.68 80.45,126.12 79.02,126.12 v2(78.36,125.47)
  BOTTOM w0.112: v2(256.68,83.46) 256.4,83.17 256.4,80.67 256.03,80.3 256.03,77 255.83,76.8 255.83,75.03 v2(255.85,75.01)
BL_PWR_SRC_ON: length 4.8
  TOP w0.254: RV4.1 CV14.1 ; CV14.1 43.32,124.59 43.74,124.17 44.1,124.17 44.35,124.42 QV1.3 ; CV14.1 RV5.1 CV13.1
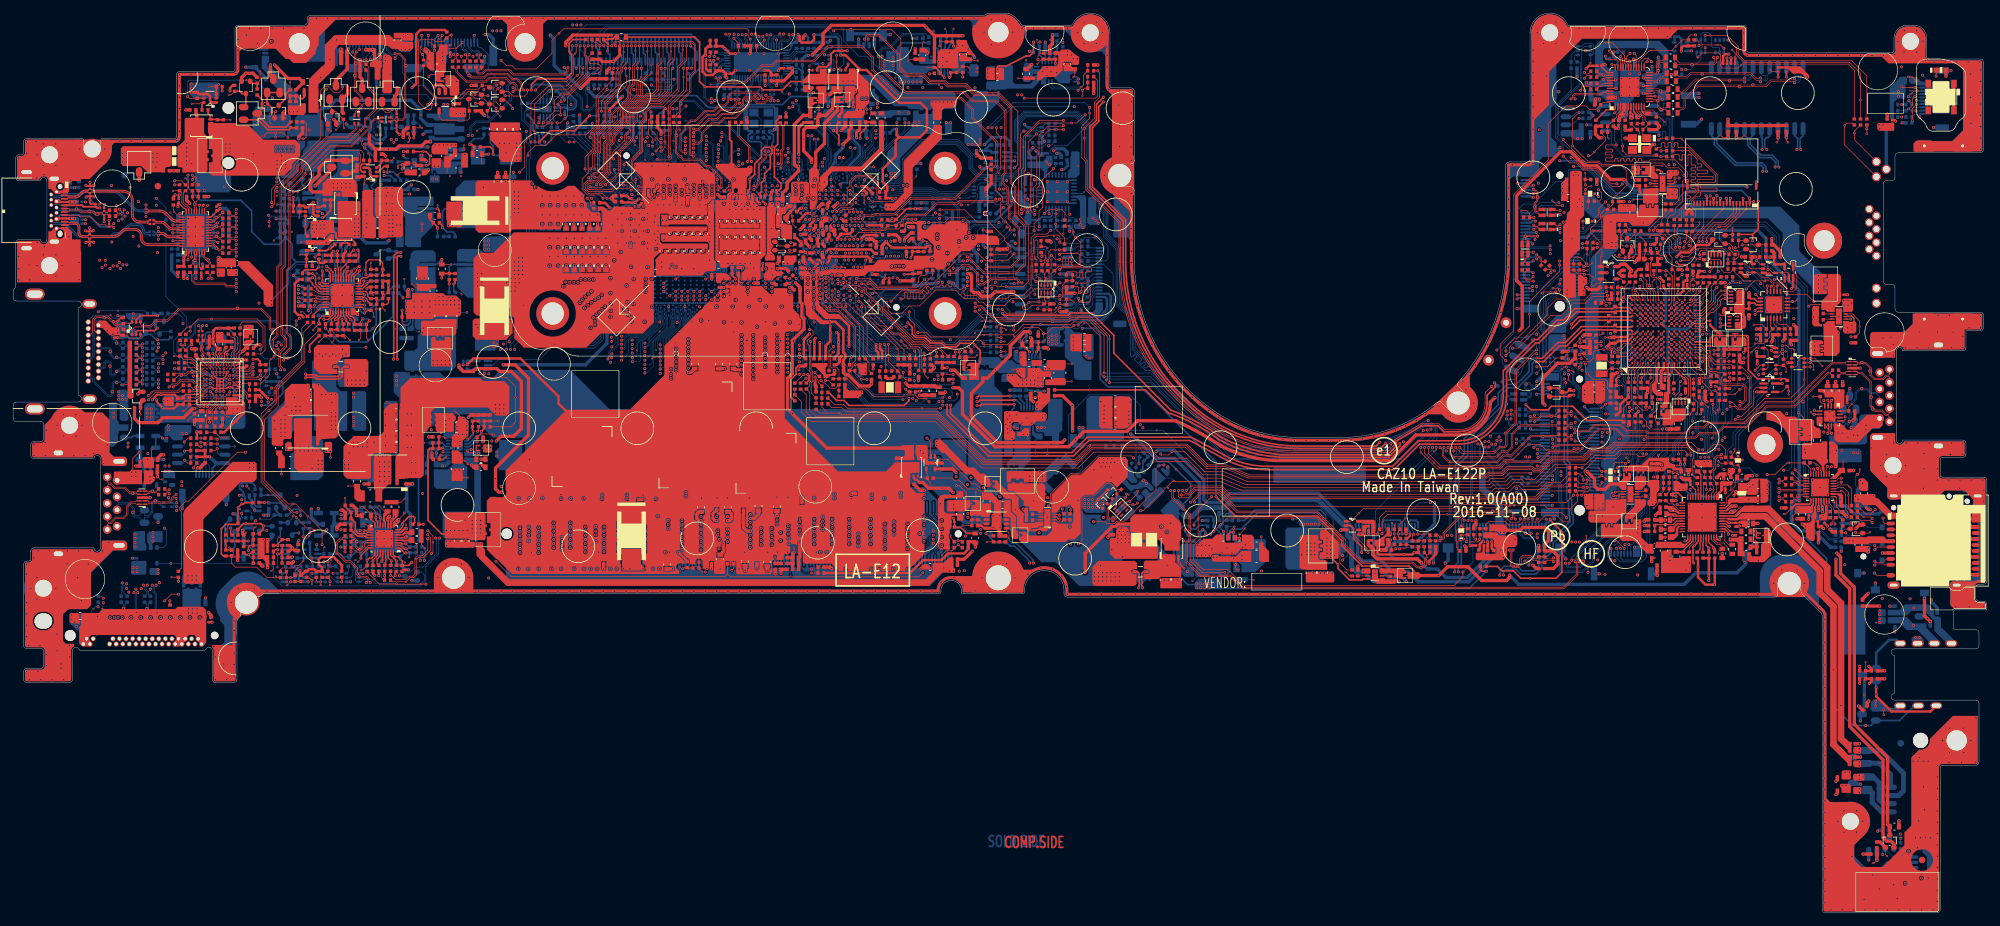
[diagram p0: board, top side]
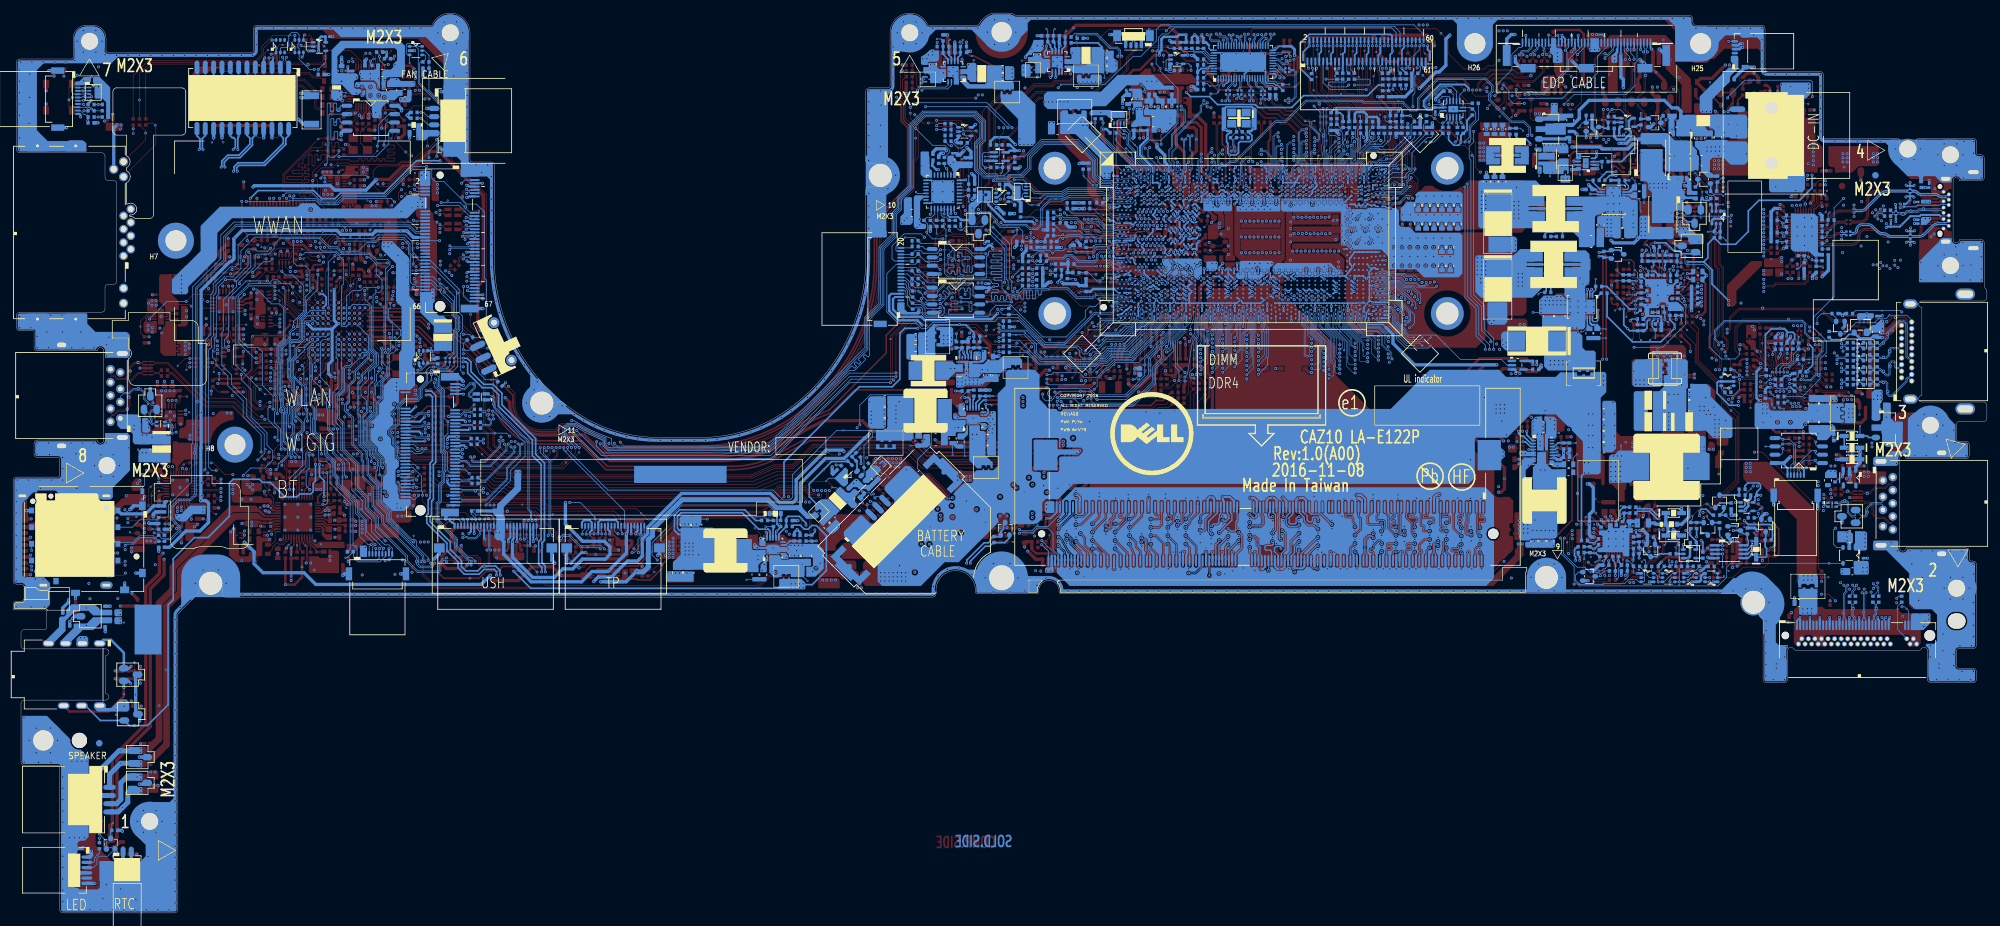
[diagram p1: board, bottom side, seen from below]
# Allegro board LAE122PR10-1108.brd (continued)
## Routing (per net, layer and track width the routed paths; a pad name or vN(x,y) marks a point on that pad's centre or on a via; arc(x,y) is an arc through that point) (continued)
BOARD_ID: length 12.6
  TOP w0.107: CE40.1 253.08,97.78 UE1.J13
  TOP w0.112: v1(249.3,103.06) 249.52,103.28 250.84,103.28 RE79.2 251.7,102.82 252.3,102.22 252.3,100.42 252.74,99.97 CE40.1
BOOT1_ISL88738: length 1.6
  TOP w0.112: PR914.1 56.62,61.22 v1(55.79,62.05)
BOOT2_ISL88738: length 2.2
  TOP w0.112: v1(61.54,54.95) 61.54,56.09 PC934.2
BREATH_LED#: length 36.1
  TOP w0.107: UE1.C11 v2(247.88,92.26)
  TOP w0.112: QZ7.4 266.17,83.53 v1(265.75,83.11) v2(265.39,82.75)
  IN2 w0.124: v2(247.88,92.26) 248.02,92.26 251.92,96.16 256.22,96.16 256.61,96.56 256.61,98.03 257.2,98.61 257.73,98.61 257.99,98.87 258.67,98.87 258.9,98.64 258.9,94.67 260.66,92.91 261.84,92.91 262.68,92.08 262.68,89.64 264.75,87.58 264.75,83.39 v2(265.39,82.75)
BREATH_LED#_Q: length 2.4
  TOP w0.112: v1(270.11,82.47) 270.11,83.09 RZ32.1 268.59,83.5 QZ7.3
BREATH_WHITE_LED_SNIFF#: length 112.5
  TOP w0.112: RZ32.2 269.71,85.16 v2(269.57,85.3) 269.88,85.61 v1(270.06,85.61) ; LED3.1 v2(292.97,127.59)
  IN3 w0.135: v2(292.97,127.59) 292.97,122.27 290.6,119.9 286.73,119.9 286.28,120.34 286.28,121.99 285.84,122.44 285.84,128.15 285.21,128.78 257.76,128.78 253.48,124.5 253.48,123.43 252.4,122.35 252.4,116.27 257.28,111.39 257.28,106.59 258.95,104.91 266.57,104.91 269.09,102.4 269.09,99.05 272.21,95.92 272.21,86.21 271.3,85.3 v2(269.57,85.3)
BST_3V: length 3.2
  BOTTOM w0.112: v1(155.73,69.7) 155.73,72.08 156.17,72.53 PR100.1
BST_5V: length 1
  TOP w0.112: v4(186.6,52.25) 186.24,52.6 v2(186.24,53.12)
BST_+1VALWP:
  vias: v1(154.14,85.22) v2(153.53,85.34) v2(153.53,84.73)
BST_+1VALWP_C: length 1.3
  TOP w0.112: PR304.1 v1(156.42,85.16)
BT_RADIO_DIS#: length 22.6
  TOP w0.107: UE1.C2 247.88,84.26 247.88,83.57 247.04,82.73 v2(247.04,81.54) RE11.1
  TOP w0.112: DZ2.1 243.84,67.54 v1(243.84,68.41) 244.12,68.69 245.45,68.69 v2(245.64,68.5)
  IN3 w0.135: v2(247.04,81.54) 247.76,80.82 247.76,79.12 247.14,78.5 247.11,78.5 245.79,77.18 245.79,75.98 246.91,74.86 246.91,70.19 245.64,68.92 v2(245.64,68.5)
BT_RADIO_DIS#_R: length 2.5
  TOP w0.112: v1(241.53,67.82) v2(242.04,67.32) DZ2.2
  BOTTOM w0.102: JNGFF1.54 241.96,67.4 v2(242.04,67.32)
CAM_MIC_CBL_DET#: length 128
  TOP w0.112: RC413.1 132.09,103.77 128.83,103.77 v1(128.22,103.16) 126.92,103.16 126.74,102.98 v2(126.74,102.7)
  IN2 w0.124: v2(71.72,125.55) 72.26,125.55 73.67,124.14 74.32,123.49 79.81,123.49 81.76,125.44 84.95,125.44 85.62,124.76 90.33,124.76 91.08,125.51 93.78,125.51 94.18,125.1 97.28,125.1 97.93,125.76 104.64,125.76 105.08,126.2 113.76,126.2 114.32,126.76 120.25,126.76 120.59,127.1 122.16,127.1 122.89,126.37 132.13,126.37 134.16,124.34 134.16,121.24 133.73,120.81 133.73,117.9 134.94,116.69 134.94,106.24 135.86,105.32 136.83,105.32 137.13,105.01 137.13,103.76 136.53,103.16 127.2,103.16 v2(126.74,102.7)
  BOTTOM w0.102: UC1.AB11 v2(126.74,102.7)
  BOTTOM w0.107: 59.31,130.66 57.75,132.21 JEDP1.14
  BOTTOM w0.112: v2(71.72,125.55) 71.72,124.61 71.26,124.16 64.73,124.16 62.69,126.2 61.19,126.2 59.31,128.08 59.31,130.66
CFG0: length 37.6
  TOP w0.112: v2(90.5,125.53) 89.22,124.25 v1(89.22,121.03) 89.22,120.21 87.91,118.9 v2(87.91,118.25)
  IN2 w0.124: v2(90.5,125.53) 90.7,125.74 94.34,125.74 v2(94.55,125.53)
  BOTTOM w0.076: 90.96,115.52 91.6,115.52 92.18,114.95 92.57,114.95 92.9,114.62 94.07,114.62 94.38,114.3 94.38,113.93 94.63,113.69 94.63,113.54 94.63,113.54 94.63,113.18 94.63,113.17 94.6,113.08 94.6,112.94 94.61,112.85 94.63,112.77 94.63,112.71 94.63,112.6 94.63,112.59 94.63,112.55 94.61,112.49 94.58,112.4 94.53,112.22 94.49,111.96 94.42,111.69 UC1.E68
  BOTTOM w0.112: RC126.1 90.5,125.99 v2(90.5,125.53) ; 90.96,115.52 90.64,115.52 v2(87.91,118.25) 87.72,118.44 87.72,120.17 RC113.1 ; v2(94.55,125.53) 100.06,125.53 101.11,126.58 JXDP1.9
CFG1: length 30.8
  TOP w0.112: v2(100.51,128.79) 100.29,128.57 v1(100.29,126.19) 100.29,125.16 98.58,123.44 97.09,123.44 95.96,122.32 95.96,121.02 95.48,120.53 95.48,116.28 93.69,114.49 93.34,114.49 93.06,114.21 v2(93.06,114.08)
  BOTTOM w0.076: UC1.B67 93.84,113.02 93.84,113.44 93.2,114.08 v2(93.06,114.08)
  BOTTOM w0.112: JXDP1.11 v2(100.51,128.79) ; v2(93.06,114.08) 92.82,114.08 92.51,114.39 90.44,114.39 86.32,118.5 RC112.1
CFG2: length 25.8
  TOP w0.112: v2(91.84,115.89) 93.39,117.44 93.39,118.53 94.1,119.23 94.1,121.59 96.69,124.19 98.22,124.19 99.31,125.28 v1(99.31,127.6) v2(99.31,128.79)
  BOTTOM w0.076: v2(91.84,115.89) 92.48,115.89 92.91,116.32 93.88,116.32 94.51,115.68 94.51,114.9 95.23,114.18 95.23,113.65 95.12,113.54 95.12,113.18 95.15,113.08 95.15,112.89 95.12,112.8 95.12,112.55 95.26,112.07 95.26,111.96 95.33,111.69 UC1.D65
  BOTTOM w0.112: JXDP1.15 v2(99.31,128.79)
CFG3: length 31.3
  TOP w0.112: v2(98.71,128.79) 98.71,125.19 v1(98.38,124.86) 97.96,124.44 96.64,124.44 93.88,121.68 93.88,119.35 93.17,118.63 93.17,117.8 91.34,115.97 91.34,115.1 v2(91.46,114.97)
  BOTTOM w0.076: v2(91.46,114.97) 91.69,114.74 92.54,114.74 92.83,114.45 94,114.45 94.21,114.24 94.21,113.88 94.47,113.62 94.47,113.21 94.41,113.09 94.41,112.94 94.47,112.75 94.47,112.58 94.38,112.32 UC1.D67
  BOTTOM w0.112: RC121.2 99.02,128.48 v2(98.71,128.79) JXDP1.17 ; v2(91.46,114.97) 90.44,114.97 87.21,118.2 RC110.1
CFG4: length 34
  TOP w0.112: v2(95.71,128.79) v1(95.71,127.46) 95.71,127.37 95.32,126.99 95.32,124.7 92.82,122.19 92.82,120.87 90.63,118.68 90.63,117.79 90.14,117.31 90.14,113.32 88.99,112.17 v2(88.62,112.17)
  BOTTOM w0.076: UC1.E70 92.16,111.01 91.96,111.21 91.63,111.21 91.34,111.49
  BOTTOM w0.112: JXDP1.27 v2(95.71,128.79) ; RC109.1 84.48,118.44 84.67,118.25 85.24,118.25 87.58,115.91 87.58,113.27 87.83,113.02 88.11,113.02 88.62,112.51 88.62,112.17 v2(88.62,112.17) 90.67,112.17 91.34,111.49
CFG5: length 23.2
  TOP w0.112: v2(89.69,113.45) 89.91,113.68 89.91,117.44 90.4,117.92 90.4,118.83 92.48,120.91 v1(92.48,121.72) 92.48,122.21 95.02,124.75 95.02,127.09 95.11,127.18 v2(95.11,128.79)
  BOTTOM w0.076: 91.51,112.53 92.05,112.53 92.23,112.36 92.54,112.36 93.28,111.62 UC1.C68
  BOTTOM w0.112: 91.51,112.53 90.57,113.47 89.71,113.47 v2(89.69,113.45) ; JXDP1.29 v2(95.11,128.79)
CFG6: length 23.6
  TOP w0.112: v2(88.62,113.45) 88.62,115.73 89.03,116.14 89.03,118.65 90.93,120.56 v1(90.93,121.13) 90.93,121.65 93.57,124.29 93.57,125.89 93.91,126.23 v2(93.91,128.79)
  BOTTOM w0.076: 91.59,111.84 91.98,111.84 92.29,111.54 UC1.D68
  BOTTOM w0.112: 91.59,111.84 90.52,112.91 89.15,112.91 v2(88.62,113.45) ; JXDP1.33 v2(93.91,128.79)
CFG7: length 25.8
  TOP w0.112: v2(93.31,128.79) 93.31,127.7 v1(93.44,127.58) 93.45,127.57 93.45,126.2 90.48,123.23 90.48,120.47 88.8,118.78 88.8,116.22 88.24,115.66 88.24,113.68 v2(88.01,113.45)
  BOTTOM w0.076: 92.29,113.85 92.57,113.57 92.57,113.11 92.73,112.95 92.73,112.54 92.97,112.3 UC1.C67
  BOTTOM w0.112: JXDP1.35 v2(93.31,128.79) ; 92.29,113.85 89.89,113.85 89.69,114.06 88.62,114.06 v2(88.01,113.45)
CFG8: length 30
  TOP w0.112: v2(100.81,132.22) 100.81,130.07 v1(100.27,129.53) 99.95,129.21 99.95,125.17 98.47,123.7 96.84,123.7 95.14,122 95.14,120.68 94.54,120.08 94.54,118.1 94.31,117.87 94.31,117.7 92.51,115.89 92.51,112.74 91.24,111.47 90.7,111.47 v2(90.27,111.03)
  BOTTOM w0.076: UC1.F71 92.17,110.45 90.7,110.45 90.27,110.88 v2(90.27,111.03)
  BOTTOM w0.112: JXDP1.10 v2(100.81,132.22)
CFG9: length 35.9
  TOP w0.112: v2(100.21,132.22) v1(100.21,131.35) 100.21,130.17 99.71,129.67 99.71,125.29 98.37,123.95 96.78,123.95 94.91,122.08 94.91,120.81 94.31,120.2 94.31,118.2 94.05,117.94 94.05,117.74 92.28,115.96 92.28,112.9 91.15,111.77 90.42,111.77 89.86,111.21 89.86,110.81 89.64,110.58 88.06,110.58 v2(87.88,110.75)
  BOTTOM w0.076: 89.9,109.62 91.5,109.62 91.63,109.49 91.89,109.49 92.01,109.55 92.15,109.55 92.38,109.48 92.51,109.48 92.73,109.56 92.98,109.56 UC1.G69
  BOTTOM w0.102: v2(87.88,110.75) 89.02,109.62 89.9,109.62
  BOTTOM w0.112: JXDP1.12 v2(100.21,132.22)
CFG10: length 30.9
  TOP w0.112: v2(89.46,111.03) 89.46,111.24 91.06,112.84 91.06,116.89 91.55,117.38 91.55,118.25 93.67,120.36 93.67,121.8 96.57,124.7 97.61,124.7 98.3,125.39 98.3,129.14 99.01,129.86 v2(99.01,132.22)
  BOTTOM w0.076: v2(89.46,111.03) 89.89,111.47 90.42,111.47 90.7,111.19 90.7,110.88 90.95,110.63 91.94,110.63 91.96,110.65 92.56,110.65 UC1.F70
  BOTTOM w0.112: JXDP1.16 v2(99.01,132.22)
CFG11: length 31.9
  TOP w0.112: v2(88.85,111.03) 90.83,113.02 90.83,116.98 91.31,117.46 91.31,118.35 93.46,120.49 93.46,121.89 96.5,124.94 97.42,124.94 98.04,125.56 98.04,129.3 98.41,129.67 v1(98.41,130.92) v2(98.41,132.22)
  BOTTOM w0.076: v2(88.85,111.03) 89.61,110.27 91.77,110.27 92.33,110.03 92.59,110.03 92.66,109.95 93.13,109.95 93.2,109.93 UC1.G68
  BOTTOM w0.112: JXDP1.18 v2(98.41,132.22)
CFG12: length 33.5
  TOP w0.112: v2(95.41,132.22) 95.41,129.84 v1(95.24,129.67) 94.64,129.07 94.64,126.25 94.03,125.64 94.03,124.09 92.1,122.16 92.1,120.91 89.48,118.3 89.48,115.96 89.28,115.76 89.28,112.99 88.96,112.68 88.58,112.68 88.16,112.26 88.16,111.95 87.91,111.69 87.48,111.69 86.94,111.16 86.94,110.4 87.6,109.74 89.71,109.74 v2(90.47,108.98)
  BOTTOM w0.076: v2(90.47,108.98) 90.85,108.6 91.25,108.6 91.52,108.86 91.92,108.86 92.06,108.81 92.16,108.81 92.29,108.86 92.53,108.86 UC1.H70
  BOTTOM w0.112: JXDP1.28 v2(95.41,132.22)
CFG13: length 29.6
  TOP w0.112: v2(87.7,112.1) 88.49,112.89 88.87,112.89 89.05,113.07 89.05,115.86 89.25,116.06 89.25,118.55 91.27,120.57 91.27,121.66 93.8,124.19 93.8,125.79 94.38,126.38 94.38,129.2 94.81,129.62 v1(94.81,131.47) v2(94.81,132.22)
  BOTTOM w0.076: 87.94,111.74 88.24,111.44 88.24,110.81 89.22,109.82 91.72,109.82 UC1.G71
  BOTTOM w0.112: JXDP1.30 v2(94.81,132.22) ; 87.94,111.74 87.7,111.97 v2(87.7,112.1)
CFG14: length 33.3
  TOP w0.112: v2(89.86,108.98) 89.36,109.48 87.5,109.48 86.69,110.3 86.69,111.92 87.6,112.84 87.6,115.35 88.57,116.32 88.57,118.88 90.26,120.58 90.26,123.42 92.58,125.74 92.58,128 92.86,128.28 92.86,129 v1(93.42,129.56) 93.61,129.76 v2(93.61,132.22)
  BOTTOM w0.076: UC1.H69 93.14,109.37 92.68,109.37 92.52,109.31 92.37,109.31 92.16,109.37 92.04,109.37 91.93,109.33 91.52,109.33 91.45,109.39 90.28,109.39 v2(89.86,108.98)
  BOTTOM w0.112: JXDP1.34 v2(93.61,132.22)
CFG15: length 29.8
  TOP w0.112: v2(93.01,132.22) v1(93.01,131.27) 93.01,129.8 92.61,129.4 92.61,128.36 92.3,128.05 92.3,125.84 90.05,123.59 90.05,120.7 88.34,118.98 88.34,116.44 87.15,115.25 v2(87.15,113.45)
  BOTTOM w0.076: 88.16,111.9 88.44,111.62 88.44,110.86 89.27,110.02 91.46,110.02 91.48,110.05 91.84,110.05 92.14,109.91 92.14,109.9 92.15,109.9 92.29,109.76 UC1.G70
  BOTTOM w0.112: JXDP1.36 v2(93.01,132.22) ; v2(87.15,113.45) 87.15,113.14 87.55,112.74 87.91,112.74 88.16,112.48 88.16,111.9
CFG16: length 29.1
  TOP w0.112: v2(95.24,110.23) 94.84,110.63 94.84,111.26 94.19,111.92 94.19,114.68 95.7,116.19 95.7,120.44 96.28,121.03 96.28,122.19 97.27,123.19 98.78,123.19 101.22,125.63 101.22,129.02 102.01,129.81 v1(102.01,131.63) v2(102.01,132.22)
  BOTTOM w0.102: v2(95.24,110.23) 95.34,110.33 96.4,110.33 96.73,110.65 UC1.E63
  BOTTOM w0.112: JXDP1.6 v2(102.01,132.22)
CFG17: length 30.2
  TOP w0.112: v2(95.24,109.64) 95.65,110.06 95.65,112.02 94.41,113.27 94.41,114.6 95.91,116.1 95.91,120.33 96.49,120.91 96.49,122.11 97.32,122.93 99.08,122.93 v1(100.62,124.48) 101.45,125.3 101.45,128.87 102.61,130.03 v2(102.61,132.22)
  BOTTOM w0.102: UC1.F63 96.74,110 96.43,109.69 95.29,109.69 v2(95.24,109.64)
  BOTTOM w0.112: JXDP1.4 v2(102.61,132.22)
CFG18: length 35.2
  TOP w0.112: v2(94.14,110.81) 93.83,110.5 91.78,110.5 91.3,110.02 87.68,110.02 87.2,110.5 87.2,111.06 87.6,111.47 87.98,111.47 88.19,111.67 88.8,111.67 90.37,113.24 90.37,117.21 90.85,117.69 90.85,118.55 93.03,120.73 93.03,122.07 95.58,124.62 95.58,126.81 96.61,127.84 v1(96.61,131.37) v2(96.61,132.22)
  BOTTOM w0.102: UC1.E66 v2(94.14,110.81)
  BOTTOM w0.112: JXDP1.24 v2(96.61,132.22)
CFG19: length 36.6
  TOP w0.112: v2(97.21,132.22) v1(97.21,129.35) 97.21,128.06 95.86,126.71 95.86,124.6 93.24,121.98 93.24,120.64 91.08,118.48 91.08,117.59 90.6,117.1 90.6,113.12 88.92,111.44 88.29,111.44 88.06,111.21 87.73,111.21 87.45,110.93 87.45,110.58 87.76,110.27 91.11,110.27 92.23,111.39 94.19,111.39 94.54,111.05 94.54,110.6 v2(94.14,110.21)
  BOTTOM w0.102: UC1.F66 v2(94.14,110.21)
  BOTTOM w0.112: JXDP1.22 v2(97.21,132.22)
CFG_RCOMP: length 2.5
  TOP w0.127: RC114.1 v1(97.69,109.12)
  TOP w0.381: RC114.1 98.18,110.59 v2(98.18,110.89)
  BOTTOM w0.254: UC1.E60 v2(98.18,110.89)
CLK_ITPXDP_N: length 16
  TOP w0.104: RC297.1 101.32,120.34 101.32,119.39 101.09,119.16 v3(101.09,118.53) 101.09,116.01 102.15,114.96 104.64,114.96 105.64,113.96 106.11,113.96 106.77,113.29 106.78,113.29 107.12,112.95 107.12,112.95 108,112.06 108,110.58 107.82,110.4 107.54,110.4 v2(107.38,110.25)
  BOTTOM w0.089: v2(107.38,110.25) 107.69,109.94 UC1.F43
CLK_ITPXDP_N_R: length 26.2
  TOP w0.104: RC297.2 101.5,121.94 101.72,122.17 v3(101.72,123.37) 101.72,123.65 103.27,125.2 103.27,127.61 103.98,128.32 103.98,132.42 103.55,132.85 91.63,132.85 91.4,132.63 91.4,132.41 v2(91.21,132.22)
  BOTTOM w0.104: JXDP1.42 v2(91.21,132.22)
CLK_ITPXDP_P: length 15.9
  TOP w0.104: v2(107.38,110.83) 107.61,110.6 107.74,110.6 107.8,110.66 107.8,111.98 v3(106.8,112.97) 106.02,113.75 105.55,113.75 104.55,114.76 102.06,114.76 100.89,115.93 100.89,118.21 100.86,118.24 100.86,118.84 100.89,118.87 100.89,119.25 101.12,119.47 101.12,120.12 100.71,120.52 RC298.1
  BOTTOM w0.089: v2(107.38,110.83) 107.62,110.59 UC1.E43
CLK_ITPXDP_P_R: length 26
  TOP w0.104: v2(91.81,132.22) 91.72,132.22 91.6,132.33 91.6,132.55 91.71,132.65 103.47,132.65 103.78,132.34 103.78,128.41 103.07,127.7 103.07,125.28 101.49,123.71 101.49,123.08 101.52,123.05 101.52,122.25 101.04,121.77 101.04,121.72 100.76,121.44 RC298.2
  BOTTOM w0.104: JXDP1.40 v2(91.81,132.22)
CLK_PCIE_N0: length 229.5
  TOP w0.104: v2(269.03,64.13) 269.24,64.35 272.73,64.35 272.81,64.27 UR1.6
  IN1 w0.119: v2(226.66,72.05) 226.55,71.94 226.55,70.49 225.6,69.54 196.16,69.54 arc(186.24,71.51) 177.83,77.13 177.1,77.86 arc(170.39,87.9) 168.03,99.75 168.03,106.47 163.76,110.74 163.76,112.98 155.17,121.58 139.18,121.58 138.76,121.15 133.55,121.15 132.8,120.39 119.82,120.39 116.84,117.41 113.36,117.41 113.04,117.09 110.22,117.09 107.88,114.75 107.54,114.75 v2(107.39,114.6) ; v2(230.45,69.53) 230.45,70.55 230.85,70.95 230.85,71.31 231.27,71.73 232.74,71.73 234.11,70.36 243.69,70.36 246.28,72.95 249.12,72.95 250.8,74.62 252.19,74.62 252.84,75.27 254.93,75.27 255.3,75.64 260.85,75.64 262.19,76.98 268.58,76.98 271.46,74.09 271.46,69.39 270.41,68.34 270.41,64.73 269.92,64.24 269.13,64.24 v2(269.03,64.13)
  BOTTOM w0.076: v2(107.39,114.6) 107.56,114.77 107.69,114.77 107.85,114.61 107.85,114.04 107.66,113.86 107.66,113.72 107.51,113.56 107.51,113.18 107.54,113.08 107.54,112.89 107.51,112.8 107.51,112.55 107.55,112.41 107.61,112.2 107.65,112.07 107.65,111.8 UC1.D42
  BOTTOM w0.104: v2(226.66,72.05) 226.66,71.08 228.85,68.89 230.57,68.89 230.67,68.99 230.67,69.31 v2(230.45,69.53)
CLK_PCIE_N1: length 170.3
  IN1 w0.119: v2(107.47,117.18) 107.74,116.9 107.92,116.9 109.14,118.12 112.7,118.12 112.97,118.39 116.56,118.39 119.44,121.27 132.44,121.27 133.82,122.65 138.97,122.65 139.17,122.45 155.51,122.45 164.62,113.34 164.62,111.11 168.91,106.82 168.91,99.75 arc(171.2,88.24) 177.72,78.48 178.45,77.75 arc(186.59,72.31) 196.19,70.4 212.96,70.4 214.17,71.61 220.83,71.61 222.04,70.4 225.24,70.4 225.46,70.62 225.46,71.29 v2(225.27,71.48)
  BOTTOM w0.076: UC1.B42 108.21,112.93 108.21,113.68 108.43,113.9 108.43,116.72 108.18,116.98 107.66,116.98 v2(107.47,117.18)
  BOTTOM w0.104: JNGFF1.49 232.73,68.65 232.73,68.65 232.58,68.8 231.77,68.8 231.04,68.07 227.93,68.07 225.45,70.55 225.45,71.3 v2(225.27,71.48)
CLK_PCIE_N2: length 174.7
  IN1 w0.119: v2(107.97,118.96) 108.17,118.76 112.3,118.76 112.59,119.05 116.21,119.05 119.11,121.96 132.19,121.96 133.57,123.34 139.26,123.34 139.48,123.11 155.76,123.11 165.26,113.61 165.26,111.38 169.57,107.07 169.57,99.75 arc(171.81,88.49) 178.19,78.95 178.92,78.22 arc(186.85,72.92) 196.21,71.05 212.49,71.05 213.7,72.26 221.25,72.26 222.46,71.04 223.25,71.04 223.37,71.16 223.37,71.31 v2(223.17,71.5)
  BOTTOM w0.076: v2(107.97,118.96) 108.17,118.77 108.42,118.77 108.77,118.42 108.77,113.76 108.57,113.56 108.57,112.69 108.8,112.46 108.8,112.15 108.5,111.85 UC1.D41
  BOTTOM w0.104: JNGFF1.73 232.48,62.65 232.33,62.8 228.62,62.8 225.35,66.07 225.35,67.85 223.39,69.81 223.39,71.29 v2(223.17,71.5)
CLK_PCIE_N3: length 154.6
  IN1 w0.119: v2(43.13,89.68) 43.31,89.86 45.48,89.86 46.53,90.91 47.56,90.91 48.97,89.51 56.2,89.51 56.79,88.91 61.42,88.91 61.99,88.34 68.52,88.34 73.25,93.07 73.25,99.24 79.48,105.47 79.48,106 80.55,107.08 87.77,107.08 88.71,108.02 91.15,108.02 93.67,110.55 93.67,111.06 93.84,111.22 95.58,111.22 95.83,110.97 95.83,109.41 96.87,108.37 107.93,108.37 108.7,109.14 108.7,113 109.84,114.14 110.37,114.14 v2(110.56,113.95)
  IN3 w0.135: v2(15.99,45.06) 15.82,45.23 15.82,46.57 16.38,47.13 21.74,47.13 23.77,49.16 23.77,53.48 29.42,59.13 29.42,65.01 37.29,72.87 37.29,79.92 39.33,81.97 39.33,86.62 42.56,89.85 42.96,89.85 v2(43.13,89.68)
  BOTTOM w0.076: v2(110.56,113.95) 110.36,114.16 109.57,114.16 109.5,114.08 109.5,113.16 109.48,113.08 109.47,113.03 109.45,112.99 109.45,112.97 109.46,112.92 109.46,112.89 109.5,112.8 109.5,112.55 109.49,112.53 109.36,112.07 109.36,111.96 109.28,111.69 UC1.D40
  BOTTOM w0.104: v2(15.99,45.06) 15.8,44.87 15.8,44.62 15.95,44.47 JNGFF3.53
CLK_PCIE_N4: length 224.5
  TOP w0.104: v2(237.98,124.11) 237.78,124.32 237.78,124.57 237.95,124.74 242.04,124.74 242.39,125.1 242.67,125.1 242.83,124.93 UL1.45
  IN1 w0.119: v2(110.55,116.42) 110.82,116.15 112.84,116.15 113.66,116.98 117.18,116.98 120.15,119.95 132.28,119.95 133.18,119.04 137.28,119.04 139.38,121.14 155,121.14 163.34,112.81 163.34,110.56 167.6,106.29 167.6,99.75 arc(169.99,87.74) 176.8,77.56 177.52,76.83 arc(186.07,71.12) 196.14,69.12 225.78,69.12 227.1,70.44 227.1,72.64 226.16,73.58 226.16,77.17 227.09,78.1 227.09,78.68 230.74,82.33 230.74,93.27 232.48,95.01 232.48,99.51 232.85,99.88 232.85,113.57 233.59,114.31 233.59,122.5 235.92,124.84 237.52,124.84 237.76,124.59 237.76,124.33 v2(237.98,124.11)
  BOTTOM w0.076: UC1.B40 109.07,112.91 108.81,113.16 108.81,113.56 108.94,113.69 108.94,115.35 109.82,116.24 110.36,116.24 v2(110.55,116.42)
CLK_PCIE_P0: length 229.2
  TOP w0.104: v2(269.03,64.72) 269.19,64.55 272.72,64.55 272.84,64.67 UR1.5
  IN1 w0.119: v2(107.39,115.24) 107.39,115.11 107.53,114.97 107.79,114.97 110.13,117.31 112.95,117.31 113.27,117.63 116.75,117.63 119.73,120.61 132.71,120.61 133.46,121.37 138.66,121.37 139.09,121.79 155.26,121.79 163.98,113.07 163.98,110.83 168.25,106.56 168.25,99.75 arc(170.59,87.99) 177.26,78.02 177.98,77.29 arc(186.32,71.72) 196.16,69.76 225.51,69.76 226.34,70.59 226.34,71.78 v2(226.07,72.05) ; v2(231.03,69.53) 231.03,69.57 230.67,69.94 230.67,70.46 231.07,70.86 231.07,71.22 231.36,71.51 232.65,71.51 234.02,70.14 243.78,70.14 246.37,72.73 249.21,72.73 250.89,74.4 252.29,74.4 252.93,75.05 255.02,75.05 255.4,75.42 260.95,75.42 262.28,76.76 268.48,76.76 271.25,74 271.25,69.48 270.19,68.43 270.19,64.82 269.83,64.46 269.29,64.46 v2(269.03,64.72)
  BOTTOM w0.076: v2(107.39,115.24) 107.35,115.2 107.35,115.09 107.49,114.95 107.76,114.95 108.02,114.68 108.02,113.97 107.84,113.78 107.84,113.66 107.67,113.49 107.67,113.21 107.73,113.09 107.73,112.94 107.67,112.75 107.67,112.58 107.76,112.32 107.78,112.31 107.78,112.25 107.82,112.1 107.82,112.09 107.9,112.01 UC1.C42
  BOTTOM w0.104: v2(226.07,72.05) 226.46,71.66 226.46,70.99 228.77,68.69 230.65,68.69 230.87,68.91 230.87,69.37 v2(231.03,69.53)
CLK_PCIE_P1: length 170.1
  IN1 w0.119: v2(225.85,71.48) 225.68,71.3 225.68,70.53 225.33,70.18 221.95,70.18 220.74,71.4 214.26,71.4 213.05,70.18 196.19,70.18 arc(186.5,72.11) 178.29,77.6 177.56,78.32 arc(171,88.16) 168.69,99.75 168.69,106.73 164.4,111.02 164.4,113.25 155.42,122.24 139.08,122.24 138.88,122.43 133.91,122.43 132.53,121.05 119.53,121.05 116.65,118.17 113.06,118.17 112.79,117.9 109.23,117.9 108.02,116.68 107.74,116.68 v2(107.47,116.41)
  BOTTOM w0.076: v2(107.47,116.41) 107.29,116.41 107.15,116.55 107.15,116.73 107.23,116.81 108.11,116.81 108.26,116.65 108.26,113.97 108.04,113.75 108.04,113.41 UC1.A42
  BOTTOM w0.104: JNGFF1.47 232.73,69.15 232.58,69 231.69,69 230.96,68.27 228.01,68.27 225.65,70.64 225.65,71.27 v2(225.85,71.48)
CLK_PCIE_P2: length 174.7
  IN1 w0.119: v2(107.97,118.33) 108.19,118.55 112.39,118.55 112.68,118.83 116.3,118.83 119.2,121.74 132.28,121.74 133.66,123.12 139.17,123.12 139.39,122.9 155.66,122.9 165.05,113.52 165.05,111.29 169.35,106.98 169.35,99.75 arc(171.61,88.41) 178.03,78.79 178.76,78.06 arc(186.77,72.71) 196.21,70.84 212.59,70.84 213.79,72.04 221.16,72.04 222.37,70.83 223.34,70.83 223.59,71.07 223.59,71.34 v2(223.75,71.5)
  BOTTOM w0.076: v2(107.97,118.33) 107.97,118.47 108.09,118.59 108.35,118.59 108.6,118.34 108.6,113.83 108.39,113.63 108.39,112.69 108.09,112.39 108.09,112.29 108.35,112.03 108.42,112.03 108.5,112.11 UC1.C41
  BOTTOM w0.104: v2(223.75,71.5) 223.59,71.34 223.59,69.89 225.55,67.93 225.55,66.15 228.7,63 232.33,63 232.48,63.15 JNGFF1.71
CLK_PCIE_P3: length 154.6
  IN1 w0.119: v2(43.13,90.26) 43.31,90.08 45.39,90.08 46.44,91.13 47.65,91.13 49.06,89.72 56.29,89.72 56.88,89.13 61.51,89.13 62.08,88.56 68.43,88.56 73.03,93.16 73.03,99.34 79.26,105.56 79.26,106.1 80.46,107.3 87.68,107.3 88.62,108.24 91.06,108.24 93.46,110.64 93.46,111.15 93.75,111.44 95.67,111.44 96.05,111.06 96.05,109.5 96.96,108.59 107.84,108.59 108.48,109.23 108.48,113.09 109.75,114.36 110.39,114.36 v2(110.56,114.54)
  IN3 w0.135: v2(15.41,45.06) 15.58,45.23 15.58,46.67 16.28,47.37 21.64,47.37 23.53,49.26 23.53,53.58 29.18,59.23 29.18,65.11 37.04,72.97 37.04,80.02 39.09,82.07 39.09,86.72 42.46,90.09 42.96,90.09 v2(43.13,90.26)
  BOTTOM w0.076: v2(110.56,114.54) 110.36,114.33 109.5,114.33 109.33,114.15 109.33,113.18 109.31,113.13 109.3,113.09 109.3,113.06 109.29,113.02 109.29,112.94 109.3,112.9 109.3,112.85 109.31,112.82 109.33,112.77 109.33,112.58 109.25,112.32 UC1.C40
  BOTTOM w0.104: v2(15.41,45.06) 15.6,44.87 15.6,44.62 15.45,44.47 JNGFF3.55
CLK_PCIE_P4: length 224.4
  TOP w0.104: v2(237.35,124.11) 237.58,124.34 237.58,124.65 237.86,124.94 241.95,124.94 242.31,125.3 242.8,125.3 242.83,125.33 UL1.44
  IN1 w0.119: v2(237.35,124.11) 237.55,124.31 237.55,124.5 237.43,124.62 236.02,124.62 233.8,122.41 233.8,114.22 233.07,113.48 233.07,99.79 232.7,99.42 232.7,94.92 230.96,93.18 230.96,82.24 227.31,78.59 227.31,78.01 226.38,77.08 226.38,73.67 227.32,72.73 227.32,70.35 225.87,68.9 196.14,68.9 arc(185.98,70.92) 177.37,76.67 176.64,77.4 arc(169.79,87.66) 167.38,99.75 167.38,106.2 163.12,110.47 163.12,112.72 154.91,120.93 139.47,120.93 137.37,118.83 133.09,118.83 132.19,119.73 120.24,119.73 117.27,116.76 113.75,116.76 112.93,115.94 110.78,115.94 v2(110.51,115.67)
  BOTTOM w0.076: UC1.A40 109.07,113.57 109.11,113.62 109.11,115.28 109.89,116.06 110.84,116.06 110.92,115.99 110.92,115.7 110.84,115.62 110.56,115.62 v2(110.51,115.67)
CLK_TP_SIO_I2C_DAT: length 82.3
  TOP w0.112: CZ81.1 RZ23.2 ; CZ81.1 212.63,56.2 213.02,55.81 RZ346.1 ; CZ81.1 212.24,55.76 211.99,55.51 v2(211.22,55.51) ; UE1.E10 v2(249.48,91.46) ; v2(217.38,56.74) 217.56,56.91 217.83,56.91 218.08,57.16 218.08,57.86 221.24,61.02 228.2,61.02 228.41,60.81 228.41,60.29 v2(228.24,60.12)
  IN3 w0.135: v2(249.48,91.46) 249.08,91.86 248.52,91.86 248.29,92.09 248.29,92.88 248.58,93.17 248.58,94.46 248,95.03 247.62,95.03 247.32,95.34 246.73,95.34 246.66,95.27 245.69,95.27 243.99,93.57 243.99,91.65 241.21,88.86 241.21,85.86 241.58,85.48 242.99,85.48 243.12,85.35 243.12,74.16 243.55,73.73 243.55,70.59 241,68.04 241,66.02 240.23,65.25 240.23,64.73 239.98,64.47 237.42,64.47 235.87,62.93 230.82,62.93 228.45,60.55 228.45,60.37 228.27,60.2 228.27,60.15 v2(228.24,60.12)
  BOTTOM w0.112: v2(211.22,55.51) 211.22,55.51 211.44,55.73 214.3,55.73 215.99,57.41 216.87,57.41 217.03,57.25 217.03,57.1 v2(217.38,56.74)
CLK_TP_SIO_R: length 4.9
  TOP w0.112: RZ23.1 211.02,57.44 v2(211.02,57.8) 211.02,58.24 RZ19.2 211.28,59.32 v1(212.11,60.15)
  BOTTOM w0.112: JKBTP1.7 211.05,57.82 v2(211.02,57.8)
CLKDET#: length 9.9
  BOTTOM w0.076: UC1.AY8 127.79,92.01 127.79,90.92 128.57,90.13 129.11,90.13 130.33,88.91
  BOTTOM w0.102: 134.64,87.49 T258.1
  BOTTOM w0.112: 130.33,88.91 130.83,88.91 131.9,87.84 134.29,87.84 134.64,87.49
CLKREQ_PCIE#0: length 215.2
  TOP w0.112: UR1.2 272.24,65.87 271.04,67.07 v2(271.04,67.08) ; v2(235.62,98.79) 235.62,97.83 231,93.21 v4(231,91.26) 231,89.47 229.04,87.51 228.65,87.51 227.42,86.29 v2(227.42,85.67) ; v2(146.56,92.37) 146.58,92.39 147.48,92.39 149.34,90.54 160.91,90.54 161.16,90.79 163.89,90.79 166.7,87.98 166.7,81.38 v2(166.56,81.25)
  IN1 w0.119: v2(244.7,100.3) 244.96,100.56 244.96,105.28 246.49,106.82 246.49,108.19 v2(246.24,108.45) ; v2(215.42,73.65) 215.7,73.37 216.25,73.37 216.42,73.53 221.98,73.53 223.98,75.53 223.98,81.05 226.53,83.6 226.53,84.78 v2(227.42,85.67)
  IN2 w0.124: v2(235.62,98.79) 236.84,100.01 244.41,100.01 v2(244.7,100.3) ; v2(246.24,108.45) 248.73,105.96 260.46,105.96 267.01,99.4 268.17,99.4 272.38,95.2 272.38,90.69 271.89,90.21 270.46,90.21 267.46,87.2 267.46,84.88 267.97,84.37 267.97,81.49 271.88,77.57 271.88,70.23 271.04,69.39 v2(271.04,67.08) ; v2(147.6,96.99) 147.99,96.59 147.99,96.09 146.97,95.07 146.97,92.78 v2(146.56,92.37)
  BOTTOM w0.112: v2(147.6,96.99) 147.17,97.42 RC373.1 ; v2(215.42,73.65) 215.47,73.6 215.47,73.39 211.39,69.31 185.13,69.31 173.05,81.39 166.71,81.39 v2(166.56,81.25)
CLKREQ_PCIE#0_R: length 24.3
  IN3 w0.135: v2(145.38,96.85) 143.85,95.32 132.15,95.32 130.85,96.62 129.17,96.62 128.65,97.14 127.38,97.14 127.02,96.78 127.02,95.95 127.49,95.48 v2(127.49,94.87)
  BOTTOM w0.102: UC1.AR10 127.26,95.1 v2(127.49,94.87)
  BOTTOM w0.112: RC189.1 144.81,97.42 v2(145.38,96.85) 145.95,97.42 RC373.2
CLKREQ_PCIE#1: length 114.1
  TOP w0.112: v2(174.82,69.98) 174.82,69.93 174.93,69.82 176.03,69.82 v4(176.55,70.34) 178.44,70.34 181.51,67.27 184.44,67.27 187.94,65.81 224.7,65.81 225.12,66.23 227.13,66.23 227.99,67.1 230.83,67.1 230.84,67.09 231.14,67.09 v2(231.23,67)
  IN2 w0.124: v2(147.6,96.4) 145.59,94.4 145.59,88.04 150.39,83.24 150.39,73.29 152.07,71.61 160.97,71.61 162.26,70.32 172.45,70.32 173.26,69.51 174.35,69.51 v2(174.82,69.98)
  BOTTOM w0.112: v2(231.23,67) 231.23,67.01 231.87,67.65 JNGFF1.53 ; RC374.1 147.04,96.4 v2(147.6,96.4)
CLKREQ_PCIE#1_R: length 22.5
  IN2 w0.124: v2(129.31,94.12) 129.85,93.58 129.85,92.03 130.86,91.03 136.65,91.03 140.57,94.94 142.91,94.94 144.03,96.07 145.19,96.07 v2(145.37,96.24)
  BOTTOM w0.097: UC1.AT7 129.17,94.12 v2(129.31,94.12)
  BOTTOM w0.112: RC374.2 145.66,96.53 v2(145.37,96.24) 145.08,96.53 RC47.1
CLKREQ_PCIE#2: length 124
  TOP w0.112: v1(241.76,65.14) 242.06,65.44 v2(242.06,65.67)
  IN2 w0.124: v2(242.06,65.67) 241.32,65.67 240.98,65.33 237.63,65.33 236.37,64.07 233.63,64.07 233.12,63.56 230.46,63.56 230.35,63.45 227.87,63.45 227.66,63.66 204.86,63.66 203.65,64.88 184.81,64.88 182.84,66.85 176.01,66.85 174.9,67.96 174.9,69.33 175.21,69.63 175.21,70.34 174.39,71.15 169.67,71.15 167.41,73.41 167.41,81.68 165,84.09 165,86.63 163.36,88.26 160.41,88.26 159.68,88.99 154.13,88.99 153.29,88.15 150.25,88.15 148.12,90.27 148.12,94.33 v2(147.72,94.73)
  BOTTOM w0.112: v2(242.06,65.67) 241.91,65.52 241.91,64.19 241.62,63.9 JNGFF1.68 ; RC375.1 146.91,95.54 v2(147.72,94.73)
CLKREQ_PCIE#2_R: length 23.6
  IN2 w0.124: v2(145.38,95.64) 145.21,95.81 144.13,95.81 143.01,94.69 140.63,94.69 136.74,90.8 130.32,90.8 128,93.12 128,93.58 127.54,94.04 v2(127.48,94.04)
  BOTTOM w0.097: UC1.AT8 127.71,94.45 127.48,94.22 v2(127.48,94.04)
  BOTTOM w0.112: RC375.2 v2(145.38,95.64) RC50.1
CLKREQ_PCIE#3: length 178.2
  TOP w0.112: v2(139.74,85.29) RC376.1
  IN1 w0.119: v2(145.41,65.31) 141.71,65.31 140.6,66.42 73.55,66.42 72.54,65.42 72.54,63.19 73.05,62.69 73.05,56.37 72.08,55.4 69.98,55.4 69.23,56.15 63.81,56.15 63.05,55.39 61.8,55.39 59.1,52.69 52.53,52.69 51.46,53.76 49.91,53.76 49.37,54.3 47.27,54.3 45.88,52.91 41.36,52.91 40.12,51.66 33.54,51.66 31.44,49.56 23.29,49.56 21.03,47.29 v2(13.74,47.29)
  IN3 w0.135: JNGFF3.52 16.2,42.51 13.74,44.97 v2(13.74,47.29) ; v2(145.41,65.31) 145.41,68.59 143.36,70.65 143.36,77.68 143,78.04 142.49,78.04 142.16,78.37 142.16,78.73 141.86,79.03 141.5,79.03 139.74,80.8 v2(139.74,85.29)
CLKREQ_PCIE#3_R: length 20
  TOP w0.112: RC59.1 RC376.2 138.82,85.3 v2(138.77,85.35)
  IN3 w0.127: 133.56,90.31 128.17,90.31 126.07,92.4 126.07,93.68 v2(126.57,94.17)
  IN3 w0.135: v2(138.77,85.35) 138.52,85.35 133.56,90.31
  BOTTOM w0.097: v2(126.57,94.17) 126.85,94.45 UC1.AT10
CLKREQ_PCIE#4: length 163.7
  TOP w0.112: v2(227.42,84.21) 226.57,85.06 226.57,86.73 228.63,88.79 228.63,109.55 233.88,114.81 233.88,120.38 236.55,123.05 239.65,123.05 240.18,122.52 241.16,122.52 RL4.1 242.23,123.58 243.15,123.58 UL1.48 ; v2(166.2,82.33) 166.2,88.03 163.7,90.54 161.31,90.54 160.92,90.14 v4(158.35,90.14) 158.26,90.24 148.2,90.24 146.68,91.76 v2(146.56,91.76)
  IN1 w0.119: v2(211.81,71.84) 212.65,72.68 222.33,72.68 224.84,75.19 224.84,80.68 227.42,83.26 v2(227.42,84.21)
  IN2 w0.124: v2(148.44,96.96) 148.27,96.79 148.27,96.04 147.2,94.96 147.2,94.49 147.7,93.99 147.7,91.7 147.5,91.5 146.81,91.5 v2(146.56,91.76)
  BOTTOM w0.112: v2(211.81,71.84) 211.81,71.16 210.79,70.14 185.48,70.14 173.31,82.31 166.23,82.31 v2(166.2,82.33) ; RC377.1 147.09,98.31 v2(148.44,96.96)
CLKREQ_PCIE#4_R: length 26.6
  IN2 w0.124: v2(127.55,93.41) 127.55,93.06 130.04,90.57 136.84,90.57 140.7,94.44 144.76,94.44 145.85,95.52 145.85,97.77 145.54,98.08 v2(145.36,98.08)
  BOTTOM w0.097: v2(127.55,93.41) 127.55,93.43 127.93,93.8 UC1.AU8
  BOTTOM w0.112: RC51.1 145.13,98.31 v2(145.36,98.08) 145.6,98.31 RC377.2
CLKREQ_PCIE#5_R: length 18.3
  TOP w0.112: v1(139.33,81.61) 138.82,82.12 RC190.1 138.35,83.16 138.35,85.89 137.84,86.4 136.78,86.4 135.05,88.12 134.06,88.12 132.68,89.51 131.98,89.51 129.91,91.58 129.91,92.44 129.11,93.24 v2(128.84,93.24)
  BOTTOM w0.076: UC1.AU7 v2(128.84,93.24)
CLKRUN#: length 162.2
  TOP w0.107: RE337.1 255.99,76.63 v2(255.42,76.06)
  TOP w0.112: v2(136.61,85.1) RC27.1
  IN2 w0.124: v2(136.61,85.1) 137.15,84.57 143.1,84.57 147.7,79.97 147.7,72.17 149.91,69.96 150.24,69.96 150.85,69.35 159.44,69.35 162.84,65.94 170.93,65.94 174.03,62.85 178.34,62.85 178.86,63.37 180.38,63.37 181.17,62.57 202.64,62.57 203.81,61.4 214.16,61.4 215.2,60.36 218.66,60.36 219.37,61.07 225.85,61.07 227.53,59.39 235.87,59.39 236.16,59.68 241.88,59.68 242.55,60.35 242.55,61.36 244.88,63.69 244.88,65.16 248.01,68.29 249.48,68.29 251.18,69.99 v2(253.72,69.99)
  BOTTOM w0.076: 128.62,88.96 128.47,88.96 127.71,89.72 127.05,89.72 126.56,90.22 126.56,92.15 126.24,92.46 UC1.AW11
  BOTTOM w0.112: 128.62,88.96 131.28,86.31 134.3,86.31 v1(134.59,86.02) 135.06,85.55 136.17,85.55 v2(136.61,85.1) ; v2(253.72,69.99) 253.72,71.44 255.42,73.15 v2(255.42,76.06)
CLKRUN#_EC: length 7.6
  TOP w0.107: UE1.L2 255.1,84.24 255.1,82.05 v1(255.31,81.85) 255.52,81.63 255.52,78.09 RE337.2
CMOUT: length 16.3
  BOTTOM w0.112: PQ1216.2 62.2,51.97 62.66,51.51 62.66,50.75 62.02,50.1 58.52,50.1 v1(58.42,50.2) 55.19,50.2 54.6,50.8 53.35,50.8 53.03,50.48 PQ1210.3 52.3,50.48 52.16,50.62 52.16,51 52.28,51.13 ; PR951.1 52.16,52.09 52.16,51.26 52.28,51.13 ; PQ1210.2 52.28,51.13
COMP_IA: length 4.3
  TOP w0.203: PU602.16 53.42,94.37 v2(53.54,94.24)
  BOTTOM w0.112: v2(53.54,94.24) v1(54.86,94.24)
  BOTTOM w0.203: v2(53.54,94.24) 53.24,94.55 PR639.2 52.12,94.55 PC636.2
COMP_ISL88738: length 5.4
  TOP w0.203: PU901.28 56.32,53.8 v2(56.16,53.64)
  BOTTOM w0.112: PR934.1 55.66,52.96 56.13,52.49 56.13,51.14 v1(56.37,50.9)
  BOTTOM w0.254: PC943.1 56.12,53.68 v2(56.16,53.64) 55.66,53.14 PR934.1
COMP_VSA: length 3.5
  TOP w0.203: v2(51,97.88) 50.73,97.61 PU602.24
  BOTTOM w0.203: PC628.1 49.99,97.23 PR630.1
  BOTTOM w0.229: v2(51,97.88) 50.64,97.88 50,97.24 PC628.1
CONTACTLESS_DET#: length 172.3
  TOP w0.112: v2(220.87,51.98) 220.87,51.27 219.53,49.93 187.51,49.93 185.06,52.37 181.3,52.37 v1(180.52,53.15) 179.83,53.84 179.83,56.04 181.53,57.75 v2(182.45,57.75)
  IN1 w0.119: v2(142.52,98.94) 142.16,98.59 140.41,98.59 137.01,101.99 137.01,102.68 136.57,103.11 126.54,103.11 v2(126.13,102.7)
  IN2 w0.124: v2(182.45,57.75) 182.14,57.43 180.01,57.43 179.5,57.95 178.1,57.95 176.01,55.85 164.83,55.85 161.44,59.24 148.41,59.24 146.68,60.97 146.68,64.83 145.16,66.36 145.16,67.57 142.34,70.39 142.34,71.84 138.59,75.59 138.59,80.41 140.08,81.9 v2(140.89,81.9)
  IN3 w0.135: v2(140.89,81.9) 141.2,82.21 141.2,83.27 141.77,83.85 143.64,83.85 144.83,85.04 144.83,88.11 148.85,92.13 148.85,92.52 149.26,92.93 149.26,94.5 148.68,95.08 148.68,96.35 149.28,96.95 149.28,98.65 148.43,99.5 148.15,99.5 147.62,100.03 146.36,100.03 145.67,100.71 144.91,100.71 144.52,100.32 144.16,100.32 142.78,98.94 v2(142.52,98.94)
  BOTTOM w0.102: UC1.W11 v2(126.13,102.7)
  BOTTOM w0.107: v2(220.87,51.98) 222.4,53.51 222.4,57.19 222.45,57.24
  BOTTOM w0.112: JUSH1.23 222.45,57.24 ; RC278.1 v2(142.52,98.94)
CORE_SW: length 1
  TOP w0.112: v2(62.28,105.08) v4(62.28,104.05)
CORE_VID0: length 71.1
  TOP w0.112: v2(156.13,130.12) 156.13,130.72 156.5,131.09 PR408.1
  IN1 w0.119: v2(138.58,125.85) 139.3,126.57 147.27,126.57 147.66,126.19 155.69,126.19 156.13,126.63 v2(156.13,130.12)
  IN2 w0.124: v2(138.58,125.85) 137.84,125.11 137.84,122.09 138.73,121.2 138.73,119.55 136.5,117.32 136.5,112.4 137.48,111.42 137.48,110.1 139.63,107.95 139.63,106.06 140.13,105.55 140.13,104.6 138.76,103.23 138.52,103.23 137.91,102.63 137.91,98.72 136.8,97.61 136.8,96.28 135.87,95.34 134.01,95.34 133.58,95.77 131.36,95.77 130.02,97.1 126.37,97.1 126.06,96.79 126.06,96.41 v2(125.64,95.99)
  BOTTOM w0.102: v2(125.64,95.99) 125.68,95.99 UC1.AN11
CORE_VID1: length 80.4
  IN1 w0.119: v2(136.33,125.85) 135.04,125.85 134.64,126.25 134.64,126.95 135.02,127.33 138.58,127.33 139.11,126.8 146.56,126.8 147.47,127.71 147.47,128.92 149.17,130.62 156.6,130.62 158.71,132.73 v2(159.92,132.73)
  IN2 w0.076: 125.81,96.94 125.35,96.94 125.14,96.73 125.14,96.4 v2(124.8,96.06)
  IN2 w0.124: 125.81,96.94 126.26,97.39 130.05,97.39 131.45,95.99 133.68,95.99 134.1,95.57 135.72,95.57 136.55,96.4 136.55,97.74 137.69,98.88 137.69,102.72 138.42,103.46 138.67,103.46 139.91,104.69 139.91,105.46 139.4,105.96 139.4,107.86 137.26,110.01 137.26,111.33 136.28,112.31 136.28,117.42 138.5,119.64 138.5,121.11 137.56,122.05 137.56,124.61 v2(136.33,125.85)
  BOTTOM w0.102: UC1.AN13 125.14,96.4 v2(124.8,96.06)
  BOTTOM w0.112: v2(159.92,132.73) 159.93,132.71 PR411.1
CPU_B+: length 15.1
  TOP w0.254: PR603.2 44.08,97.72 44.41,98.05 46.12,98.05 v2(46.58,98.51)
  IN3 w0.254: v2(46.58,98.51) 46.79,98.51 47.67,99.4 52.56,99.4 53.87,100.71 v2(53.87,104.53)
  vias: v2(53.87,107.07) v2(53.87,106.44) v2(53.87,105.17) v2(63.9,111.91) v2(63.97,84.21) v2(63.97,83.58) v2(64.54,111.91) v2(64.6,84.21) v2(64.6,83.58) v2(65.24,84.21) v2(65.24,83.58) v2(65.87,84.21) v2(65.87,83.58) v2(66.51,84.21) v2(66.51,83.58) v4(53.36,103.24)
CPU_DP1_AUXN: length 14.9
  IN1 w0.076: v2(103.71,109.54) 103.55,109.54 103.16,109.94 103.16,111.22 103.56,111.62 103.56,111.78 103.54,111.8 103.54,111.85 103.51,111.87 103.51,111.88
  IN1 w0.119: v2(102.42,117.6) 102.68,117.86 102.86,117.86 102.98,117.74 102.98,114.14 103.51,113.61 103.51,111.88
  BOTTOM w0.102: UC1.G50 104.1,109.47 103.89,109.59 v2(103.71,109.54)
  BOTTOM w0.104: v2(102.42,117.6) 102.34,117.67 101.92,117.67 101.68,117.92 101.68,118.78 102.96,120.06 102.96,120.56 102.77,120.75 T281.1
CPU_DP1_AUXP: length 15.2
  IN1 w0.076: v2(103.71,110.3) 103.73,110.27 103.73,109.98 103.66,109.9 103.44,109.9 103.33,110.01 103.33,111.15 103.73,111.55 103.73,111.88
  IN1 w0.119: v2(102.42,118.19) 102.52,118.08 102.97,118.08 103.2,117.85 103.2,114.23 103.73,113.7 103.73,111.88
  BOTTOM w0.102: UC1.F50 103.75,110.16 103.7,110.29 v2(103.71,110.3)
  BOTTOM w0.104: T282.1 103.27,120.72 103.16,120.61 103.16,119.97 101.88,118.69 101.88,118 102.01,117.87 102.17,117.87 102.42,118.12 v2(102.42,118.19)
CPU_DP1_CTRL_CLK: length 140.5
  TOP w0.112: RC175.1 131.82,110.15 131.82,111.31 130.67,112.47 128.4,112.47 127.42,111.49 127.42,110.83 127.08,110.5 127.08,107.93 126.97,107.82 125.79,107.82 124.92,106.94 v2(124.82,106.94) ; v2(39.58,88.42) 39.01,88.98 39.01,90.67 37.72,91.96 25.32,91.96 23.55,90.2 21.88,90.2 21.03,89.35 18.56,89.35 18.11,88.9 QV3.1
  IN1 w0.076: v2(124.82,106.94) 125.05,107.17 125.05,107.28 124.49,107.83 121.72,107.83 121.49,107.61 121.49,107.35 120.87,106.74 120.87,106.7 120.86,106.69
  IN1 w0.119: v2(39.58,88.42) 39.75,88.59 42.11,88.59 42.54,88.16 55.55,88.16 56.21,87.5 60.7,87.5 61.31,86.89 70.57,86.89 74.58,90.9 78.02,90.9 81.28,87.64 88.87,87.64 90.35,89.11 96.49,89.11 98.73,91.35 98.73,93.36 100.58,95.21 103.48,95.21 107.92,99.65 116.27,99.65 117.05,100.43 117.05,101.46 119.23,103.64 119.23,104.89 120.64,106.3 120.64,106.47 120.86,106.69
  BOTTOM w0.102: UC1.L13 v2(124.82,106.94)
CPU_DP1_CTRL_DATA: length 139.3
  TOP w0.112: v2(39.58,89) 39.33,89 39.25,89.08 39.25,90.77 37.82,92.2 v3(34.17,92.2) 25.22,92.2 23.46,90.43 21.78,90.43 20.94,89.59 19.58,89.59 19.41,89.76 QV3.4 ; RC178.1 131.59,109.5 131.59,111.21 130.57,112.23 128.5,112.23 127.66,111.39 127.66,110.82 127.98,110.5 127.98,108.02 127.47,107.52 126.05,107.52 v2(125.47,106.94)
  IN1 w0.076: 120.68,106.87 120.7,106.88 120.73,106.88 121.28,107.44 121.28,107.69 121.63,108.04 124.57,108.04 125.25,107.36 125.25,107.17 v2(125.47,106.94)
  IN1 w0.119: v2(39.58,89) 39.75,88.83 42.21,88.83 42.65,88.4 55.65,88.4 56.31,87.74 60.81,87.74 61.42,87.13 70.47,87.13 74.48,91.15 78.12,91.15 81.38,87.89 88.77,87.89 90.24,89.36 96.39,89.36 98.48,91.45 98.48,93.46 100.48,95.46 103.38,95.46 107.82,99.9 116.17,99.9 116.8,100.53 116.8,101.57 118.98,103.75 118.98,104.99 120.39,106.4 120.39,106.57 120.68,106.87
  BOTTOM w0.102: UC1.L12 v2(125.47,106.94)
CPU_DP1_HPD: length 177.8
  IN1 w0.119: v2(40.21,109.99) 40.46,109.74 40.46,105.69 38.2,103.43 38.2,92.82 34.71,89.33 30.39,89.33 29.08,88.02 26.58,88.02 25.87,88.73 v2(25.87,89.86)
  IN2 w0.124: v2(40.21,109.99) 40.26,109.99 45.43,115.16 45.43,118.34 44.3,119.47 42.49,119.47 40.94,121.02 40.94,122.51 42.19,123.76 53.2,123.76 55.83,121.13 59.55,121.13 62.28,123.86 69.26,123.86 70.92,122.2 72.17,122.2 73.1,121.27 81.71,121.27 82.8,122.36 86.69,122.36 86.82,122.24 88.53,122.24 89.47,123.18 97.64,123.18 98.63,124.17 102.89,124.17 103.99,123.07 111,123.07 111.3,123.38 116.67,123.38 117.32,124.03 117.32,124.8 117.83,125.31 119.68,125.31 120.81,124.18 128.48,124.18 129.3,125 131.55,125 132.56,123.99 132.56,122.11 132.1,121.65 132.1,115.68 130.55,114.13 130.55,110.17 130.99,109.74 130.99,108.34 130.35,107.71 130.35,107 129.74,106.39 128.53,106.39 v2(128.04,106.88)
  BOTTOM w0.076: v2(128.04,106.88) UC1.L9
  BOTTOM w0.112: QV5.3 22.96,90.7 23.6,91.34 RV20.1 v1(24.87,91.39) 25.17,91.39 25.87,90.69 v2(25.87,89.86)
CPU_DP1_N0: length 132.5
  IN1 w0.076: 100.65,111.26 100.65,111.17 100.56,111.09 100.56,110.72 100.65,110.63 100.81,110.63 100.94,110.75 v2(100.94,110.86)
  IN1 w0.119: 100.65,111.26 100.65,112.34 101.18,112.87 101.18,116.64 100.71,117.11 100.71,119.76 95.38,125.1 88.31,125.1 88.13,125.27 82.94,125.27 80.99,123.33 72.59,123.33 72.28,123.02 69.56,123.02 69.19,123.39 67.82,123.39 67.28,123.94 48.76,123.94 46.36,121.54 38.18,121.54 35.34,118.69 35.34,94.48 34.02,93.17 25.61,93.17 23.54,91.09 23.54,86.58 21.43,84.48 21.43,82.17 21.77,81.82 22.45,81.82 22.62,81.65 22.62,81.33 22.44,81.16 22.28,81.16 22.17,81.27 v2(22.15,81.27)
  BOTTOM w0.076: UC1.E55 101.26,110.54 101,110.67 v2(100.94,110.86)
  BOTTOM w0.104: CV32.1 21.62,81.07 21.96,81.07 v2(22.15,81.27)
CPU_DP1_N1: length 126.7
  IN1 w0.119: v2(99.12,110.81) 98.92,110.62 98.59,110.62 98.46,110.49 97.98,110.49 97.8,110.66 97.8,111.38 99.43,113.01 99.43,118.91 98.96,119.37 97.06,119.37 95.14,121.3 95.14,121.86 94.1,122.9 89.44,122.9 88.96,123.38 88.13,123.38 87.61,123.9 84.52,123.9 82.11,121.5 72.72,121.5 72.34,121.12 71.35,121.12 71.05,121.42 66.99,121.42 66.56,121.85 48.74,121.85 46.98,120.09 39.18,120.09 37.13,118.05 37.13,93.66 34.12,90.65 25.32,90.65 24.88,90.21 24.88,85.12 22.68,82.92 22.34,82.92 v2(22.15,83.11)
  BOTTOM w0.089: v2(99.12,110.81) 99.34,110.59 UC1.E58
  BOTTOM w0.104: v2(22.15,83.11) 21.96,82.92 21.62,82.92 CV34.1
CPU_DP1_N2: length 128.7
  IN1 w0.076: v2(101.88,110.22) 101.88,110.12 101.75,109.99 101.6,109.99 101.51,110.08 101.51,111.15 101.8,111.44 101.8,111.85 101.82,111.87 101.82,111.9
  IN1 w0.119: v2(22.15,86.79) 22.33,86.61 22.53,86.61 22.77,86.84 22.77,91.53 25.11,93.86 33.81,93.86 34.65,94.71 34.65,118.97 38.62,122.94 44.49,122.94 46.68,125.13 67.47,125.13 68.51,124.09 80.85,124.09 83.1,126.34 95.04,126.34 101.36,120.03 101.36,117.37 101.82,116.91 101.82,111.9
  BOTTOM w0.076: v2(101.88,110.22) 101.9,110.16 UC1.F53
  BOTTOM w0.104: v2(22.15,86.79) 21.96,86.6 21.62,86.6 CV36.1
CPU_DP1_N3: length 127.7
  IN1 w0.076: v2(100.04,110.23) 100.04,110.08 99.94,109.99 99.75,109.99 99.67,110.07 99.67,111.16 99.36,111.46 99.36,111.9
  IN1 w0.119: 99.36,111.9 99.36,111.93 100.54,113.1 100.54,116.37 100.07,116.84 100.07,119.49 99.4,120.17 98.4,120.17 95.02,123.55 89.73,123.55 89.25,124.03 88.42,124.03 87.84,124.61 83.39,124.61 82.16,123.39 82.16,122.83 81.48,122.14 72.47,122.14 72.24,122.38 69.29,122.38 68.95,122.72 60.94,122.72 60.4,123.25 49.1,123.25 46.67,120.83 38.44,120.83 36.05,118.44 36.05,93.73 33.62,91.29 24.89,91.29 24.22,90.63 24.22,85.8 23.18,84.77 23.02,84.77 v2(22.83,84.95)
  BOTTOM w0.076: v2(100.04,110.23) 100.03,110.21 100.06,110.09 100.41,109.91 UC1.F56
  BOTTOM w0.104: v2(22.83,84.95) 22.64,84.76 21.62,84.76 CV38.2
CPU_DP1_P0: length 132.5
  IN1 w0.076: 100.43,111.26 100.43,111.2 100.39,111.16 100.39,110.65 100.58,110.45 100.83,110.45 100.92,110.36 v2(100.92,110.18)
  IN1 w0.119: v2(22.15,80.68) 22.41,80.94 22.53,80.94 22.84,81.24 22.84,81.75 22.54,82.04 21.87,82.04 21.65,82.26 21.65,84.39 23.76,86.49 23.76,91 25.7,92.95 34.11,92.95 35.56,94.39 35.56,118.6 38.27,121.32 46.45,121.32 48.85,123.72 67.19,123.72 67.73,123.17 69.1,123.17 69.47,122.8 72.37,122.8 72.68,123.11 81.08,123.11 83.03,125.06 88.04,125.06 88.22,124.88 95.29,124.88 100.5,119.67 100.5,117.01 100.96,116.55 100.96,112.96 100.43,112.43 100.43,111.26
  BOTTOM w0.076: UC1.F55 101.35,110.11 101.11,110.24 v2(100.92,110.18)
  BOTTOM w0.104: CV31.1 21.62,80.87 21.96,80.87 v2(22.15,80.68)
CPU_DP1_P1: length 126.7
  IN1 w0.119: v2(22.15,82.52) 22.32,82.7 22.77,82.7 25.1,85.03 25.1,90.12 25.41,90.43 34.21,90.43 37.35,93.57 37.35,117.96 39.27,119.87 47.07,119.87 48.83,121.64 66.46,121.64 66.9,121.2 70.96,121.2 71.26,120.9 72.43,120.9 72.81,121.28 82.2,121.28 84.61,123.68 87.52,123.68 88.04,123.16 88.87,123.16 89.35,122.68 94,122.68 94.92,121.77 94.92,121.21 96.97,119.16 98.87,119.16 99.21,118.82 99.21,113.1 97.59,111.47 97.59,110.57 97.89,110.27 98.55,110.27 98.68,110.4 98.9,110.4 v2(99.12,110.18)
  BOTTOM w0.076: v2(99.12,110.18) UC1.F58
  BOTTOM w0.104: v2(22.15,82.52) 21.96,82.71 21.62,82.71 CV33.1
CPU_DP1_P2: length 128.6
  IN1 w0.076: 101.6,111.9 101.6,111.87 101.63,111.84 101.63,111.51 101.33,111.22 101.33,110 101.52,109.82 101.75,109.82 101.86,109.7 v2(101.86,109.54)
  IN1 w0.119: 101.6,111.9 101.6,116.81 101.14,117.28 101.14,119.94 94.95,126.12 83.19,126.12 80.94,123.87 68.42,123.87 67.38,124.91 46.77,124.91 44.58,122.72 38.71,122.72 34.87,118.88 34.87,94.62 33.9,93.65 25.2,93.65 22.99,91.44 22.99,86.75 22.62,86.39 22.33,86.39 v2(22.15,86.21)
  BOTTOM w0.076: UC1.G53 102.31,109.32 101.9,109.55 v2(101.86,109.54)
  BOTTOM w0.104: v2(22.15,86.21) 21.96,86.4 21.62,86.4 CV35.1
CPU_DP1_P3: length 127.7
  IN1 w0.076: 99.14,111.9 99.16,111.89 99.16,111.42 99.49,111.08 99.49,110 99.67,109.82 99.95,109.82 100.04,109.73 v2(100.04,109.54)
  IN1 w0.119: v2(22.83,84.36) 23.02,84.55 23.27,84.55 24.44,85.71 24.44,90.53 24.98,91.08 33.71,91.08 36.27,93.64 36.27,118.35 38.53,120.61 46.76,120.61 49.19,123.03 60.31,123.03 60.85,122.5 68.86,122.5 69.2,122.16 72.15,122.16 72.38,121.92 81.57,121.92 82.38,122.74 82.38,123.3 83.48,124.39 87.75,124.39 88.33,123.81 89.16,123.81 89.64,123.33 94.93,123.33 98.31,119.95 99.31,119.95 99.85,119.4 99.85,116.75 100.32,116.28 100.32,113.19 99.14,112.02 99.14,111.9
  BOTTOM w0.076: UC1.G56 100.45,109.46 100.2,109.59 v2(100.04,109.54)
  BOTTOM w0.104: v2(22.83,84.36) 22.64,84.56 21.62,84.56 CV37.2
CPU_DP2_AUXN: length 22.6
  IN1 w0.076: 105.22,111.88 105.22,111.86 105.2,111.84 105.2,111.54 105.02,111.37 104.45,111.37 104.22,111.14 104.22,110.68 104.33,110.58 104.44,110.58 104.61,110.74 v2(104.61,110.81)
  IN1 w0.119: v2(106.37,123.56) 106.19,123.74 105.99,123.74 105.87,123.62 105.87,122.93 106.25,122.55 106.25,114.49 106.16,114.4 106.16,113.63 105.22,112.69 105.22,111.88
  BOTTOM w0.076: v2(104.61,110.81) UC1.E48
  BOTTOM w0.104: CV95.1 106.12,128.62 105.57,128.62 105.23,128.28 105.23,124.36 105.85,123.75 106.18,123.75 v2(106.37,123.56)
CPU_DP2_AUXN_C: length 2.5
  BOTTOM w0.104: CV95.2 107.07,128.59 107.2,128.59 107.34,128.73 107.34,128.77 107.75,129.18 107.79,129.18 108.07,129.46 108.39,129.46 108.47,129.54 UV7.25
CPU_DP2_AUXP: length 22.7
  IN1 w0.076: 105,111.88 105,111.86 105.02,111.84 105.02,111.61 104.95,111.54 104.37,111.54 104.04,111.21 104.04,110.61 104.25,110.4 104.53,110.4 104.61,110.32 v2(104.61,110.18)
  IN1 w0.119: 105,111.88 105,112.79 105.94,113.72 105.94,114.49 106.03,114.58 106.03,122.46 105.65,122.84 105.65,123.71 105.89,123.96 106.19,123.96 v2(106.37,124.14)
  BOTTOM w0.076: v2(104.61,110.18) UC1.F48
  BOTTOM w0.104: CV94.1 106.08,128.42 105.66,128.42 105.43,128.2 105.43,124.45 105.93,123.95 106.18,123.95 v2(106.37,124.14)
CPU_DP2_AUXP_C: length 2.4
  BOTTOM w0.104: UV7.24 108.47,129.14 108.36,129.26 108.15,129.26 v3(107.71,128.81) 107.28,128.39 107.04,128.39 CV94.2
CPU_DP2_CTRL_CLK: length 84.7
  TOP w0.076: v2(128.83,105.85) 128.75,105.92 128.75,106.05 128.9,106.2 129.65,106.2 129.67,106.18 129.69,106.18
  TOP w0.112: 129.69,106.18 131.09,106.18 131.32,106.41 134.36,106.41 136.74,108.79 143.54,108.79 148.36,113.61 148.69,113.61 RC176.1 149.31,113.62 149.62,113.62 149.92,113.92 149.92,117.63 146.28,121.27 146.28,122.56 144.47,124.37 135.29,124.37 131.07,128.59 131.07,130.48 129.33,132.22 124.12,132.22 121.92,130.02 116.25,130.02 115.56,129.32 114.06,129.32 111.48,126.74 107.71,126.74 107.52,126.93 107.52,127.13 v2(107.72,127.33)
  BOTTOM w0.102: UC1.N7 129.04,106.01 128.87,105.85 v2(128.83,105.85)
  BOTTOM w0.112: v2(107.72,127.33) 107.68,127.29 107.61,127.29 107.49,127.41 107.49,127.56 107.64,127.71 107.97,127.71 108.02,127.77 108.02,128.09 108.27,128.34 UV7.22
CPU_DP2_CTRL_DATA: length 84.9
  TOP w0.076: 129.69,106.42 129.67,106.42 129.65,106.4 128.82,106.4 v2(128.24,105.83)
  TOP w0.112: v2(107.08,127.33) 107.28,127.13 107.28,126.83 107.61,126.5 111.58,126.5 114.16,129.08 115.65,129.08 116.35,129.78 122.02,129.78 124.22,131.98 129.23,131.98 130.83,130.38 130.83,128.49 135.2,124.13 144.37,124.13 146.04,122.46 146.04,121.17 149.68,117.53 149.68,114.02 149.52,113.86 149.31,113.86 RC177.1 148.67,113.85 148.26,113.85 143.44,109.03 136.64,109.03 134.27,106.65 131.22,106.65 130.99,106.42 129.69,106.42
  BOTTOM w0.076: v2(128.24,105.83) 128.38,105.97 UC1.N8
  BOTTOM w0.112: v2(107.08,127.33) 107.08,127.5 108.33,128.74 UV7.23
CPU_DP2_HPD: length 38.1
  IN2 w0.124: v2(129.28,106.84) 129.28,106.99 130.76,108.47 130.76,109.56 130.3,110.02 130.3,114.41 131.85,115.96 131.85,121.75 132.32,122.23 132.32,123.87 131.42,124.78 129.39,124.78 128.57,123.95 120.71,123.95 119.78,124.88 v2(118.24,124.88)
  BOTTOM w0.102: UC1.L7 v2(129.28,106.84)
  BOTTOM w0.107: v2(118.24,124.88) 117.39,124.88 v1(117.13,125.14) 116.99,125.28 116.99,126.12 116.31,126.8 UV7.3
CPU_DP2_N0: length 26.5
  TOP w0.104: v2(115.37,123.82) 115.48,123.82 115.54,123.88 115.54,123.99 115.59,124.04 115.59,124.14 115.48,124.24 115.09,124.24 114.99,124.14 114.99,123.88 114.54,123.43 113.31,123.43 112.5,124.24 111.56,124.24 111.3,123.99 111.3,123.27 109.74,121.72 108.08,121.72 107.27,120.9 106.03,120.9 104.47,119.34 104.03,119.34 103.82,119.13 103.75,119.13 103.65,119.03 v2(103.65,118.96)
  BOTTOM w0.076: 104.42,114.07 104.41,114.06 104.41,114.05 104.37,114.01 104.37,114 104.27,113.9 104.27,113.78 104.28,113.78 arc(104.3,113.62) 104.36,113.48 arc(104.41,113.34) 104.38,113.2 arc(104.34,113) 104.38,112.79 arc(104.39,112.69) 104.39,112.59 arc(104.35,112.49) 104.29,112.41 arc(104.29,112.4) 104.28,112.4 104.25,112.37 104.09,112.37 104.02,112.29 104.02,112.18 103.99,112.15 103.99,112.09 104.07,112.01 UC1.C50
  BOTTOM w0.089: 104.42,114.07 104.68,114.33 104.68,118.96 104.29,119.35 104.1,119.35 104.01,119.27 104.01,118.81 103.92,118.72 103.73,118.72 103.63,118.83 103.63,118.93 v2(103.65,118.96)
  BOTTOM w0.104: v2(115.37,123.82) 115.45,123.82 115.56,123.93 115.56,124.6 CV87.1
CPU_DP2_N0_C: length 2.3
  BOTTOM w0.104: UV7.7 114.71,126.86 114.81,126.75 114.81,126.45 115.52,125.73 115.52,125.58 CV87.2
CPU_DP2_N1: length 26.4
  TOP w0.104: v2(113.46,124.14) 113.46,124.14 113.56,124.04 113.76,124.04 113.89,124.17 113.89,124.42 113.33,124.98 109.53,124.98 108.99,124.44 108.99,123.55 108.44,123 107.58,123 106.76,122.17 105.47,122.17 104,120.71 103.29,120.71 102.44,119.86 102.44,119.38 101.78,118.72 101.78,116.37 101.98,116.17 102.23,116.17 102.42,116.35 v2(102.42,116.43)
  BOTTOM w0.076: UC1.C52 103.08,112.11 103.08,112.27 103.01,112.34 102.83,112.34 102.78,112.38 102.72,112.58 102.72,112.75 102.78,112.94 102.78,113.09 102.76,113.13 102.73,113.16 102.73,113.2 102.72,113.21 102.72,113.47 102.75,113.49 102.75,113.49 102.86,113.59 102.86,113.69 102.87,113.7
  BOTTOM w0.089: v2(102.42,116.43) 102.39,116.4 102.39,116.29 102.5,116.18 102.83,116.18 103.01,116 103.01,113.85 102.87,113.7
  BOTTOM w0.104: CV89.1 113.77,124.61 113.77,124.52 113.89,124.39 113.89,124.17 113.76,124.04 113.56,124.04 v2(113.46,124.14)
CPU_DP2_N1_C: length 2
  BOTTOM w0.104: UV7.10 113.51,126.87 113.62,126.77 113.62,125.91 113.77,125.76 113.77,125.6 CV89.2
CPU_DP2_N2: length 19.6
  TOP w0.104: v2(111.75,123.82) 111.85,123.82 111.92,123.75 111.92,123.65 111.99,123.59 111.99,123.31 109.99,121.31 108.3,121.31 107.47,120.47 106.37,120.47 104.88,118.98 104.88,117.91 104.37,117.4 103.99,117.4 103.65,117.74 v2(103.65,117.79)
  BOTTOM w0.076: 104.06,117.79 104.24,117.79 104.51,117.52 104.51,114.47 104.02,113.97 104.02,113.92 103.85,113.75 103.85,113.14 103.98,113.02 104.11,113.02 104.16,113.07 104.16,113.26 UC1.A50
  BOTTOM w0.089: 104.06,117.79 v2(103.65,117.79)
  BOTTOM w0.104: CV91.1 111.94,124.6 111.94,124 111.76,123.82 v2(111.75,123.82)
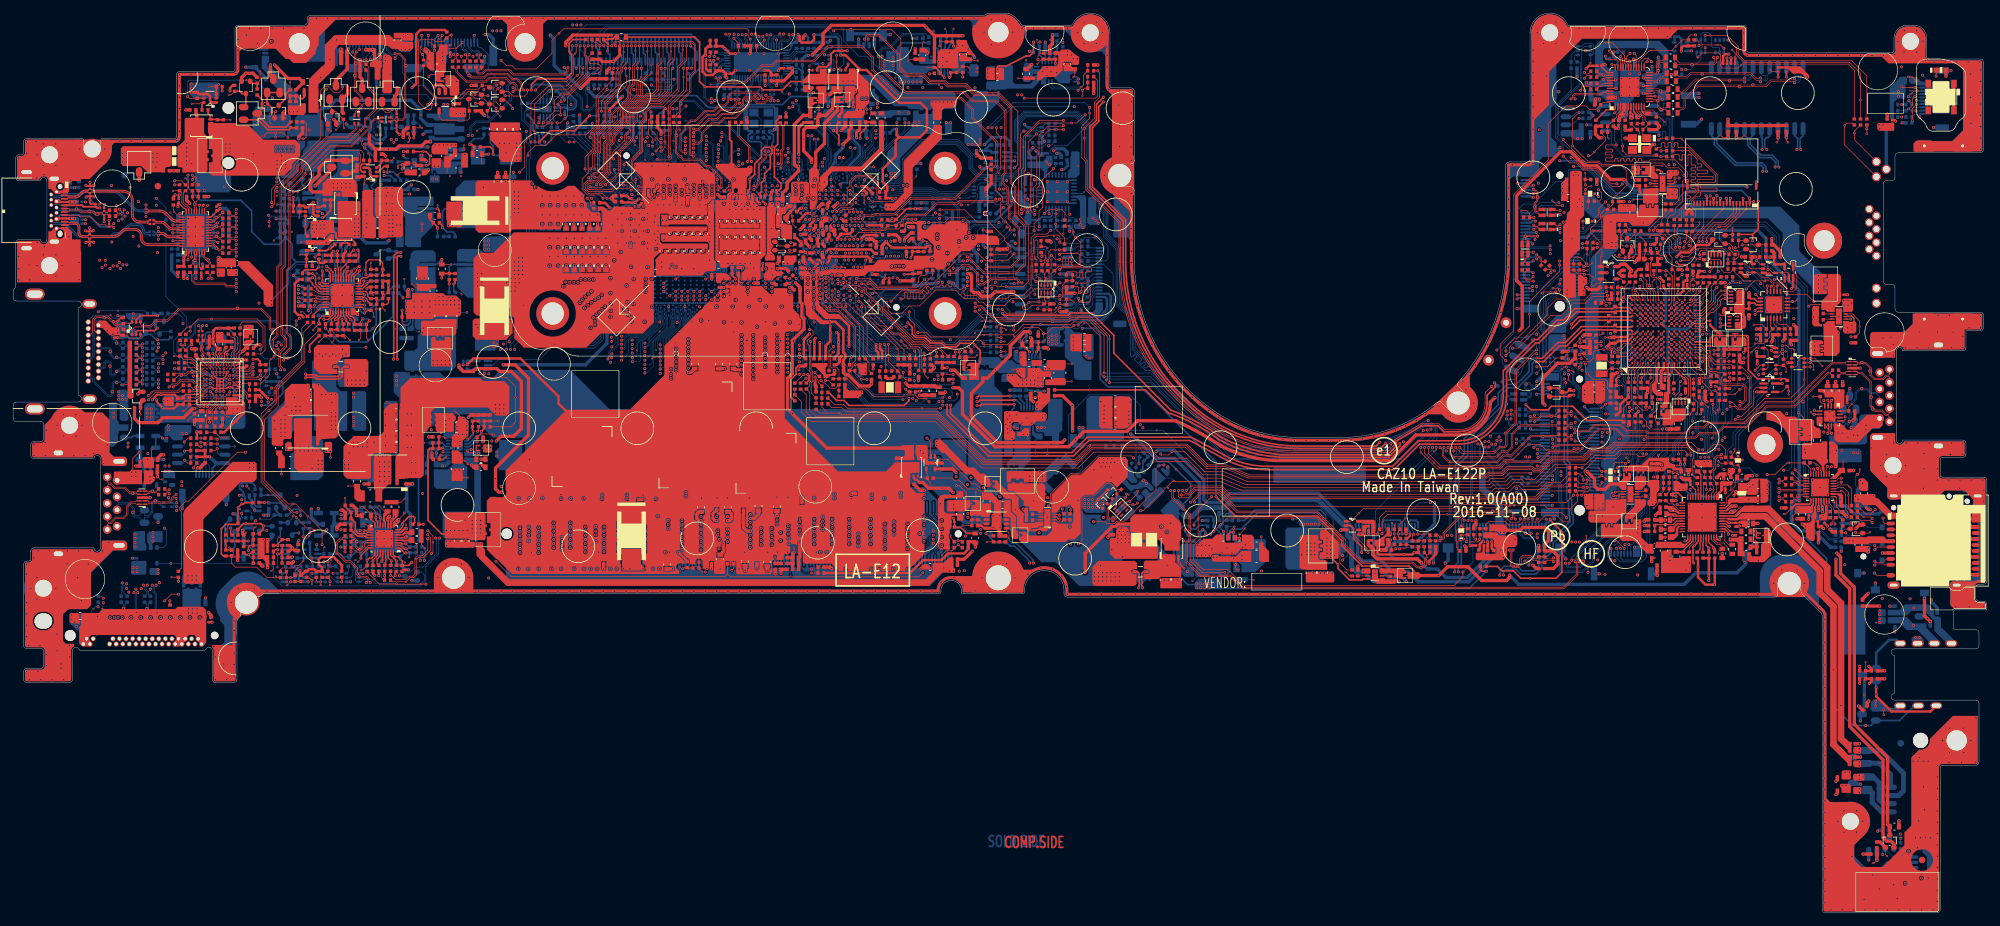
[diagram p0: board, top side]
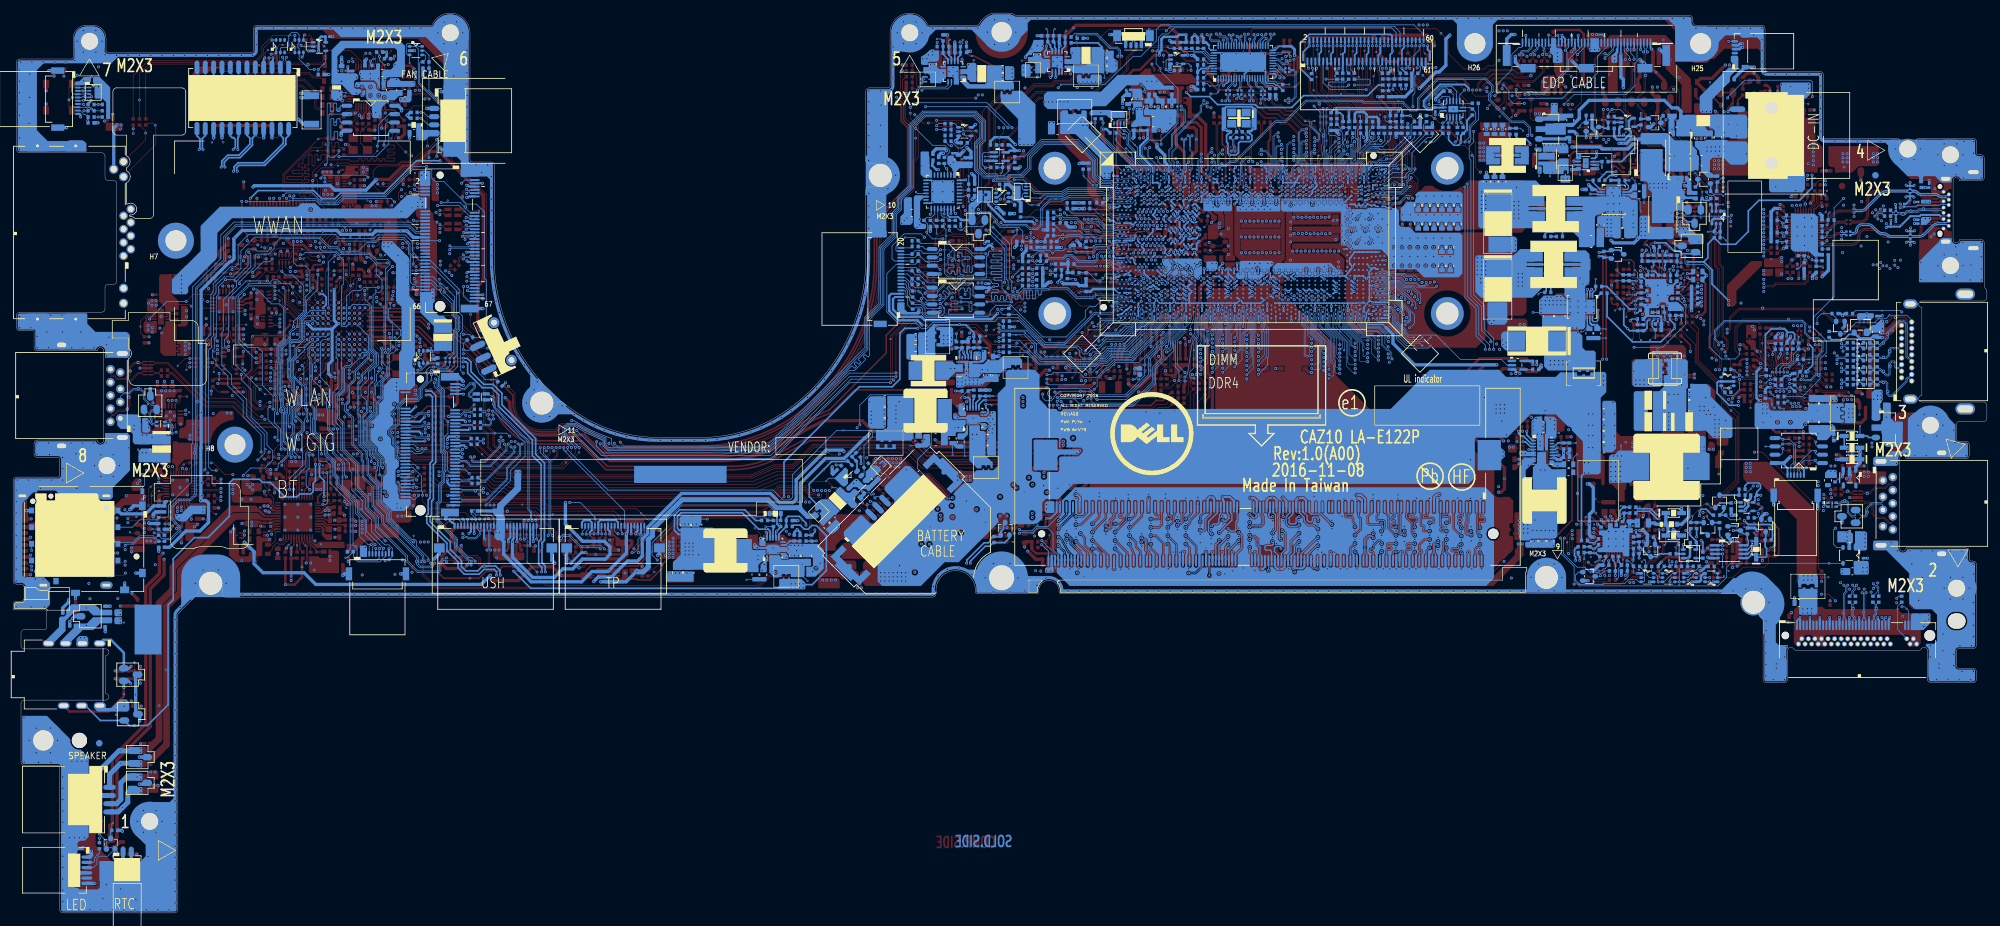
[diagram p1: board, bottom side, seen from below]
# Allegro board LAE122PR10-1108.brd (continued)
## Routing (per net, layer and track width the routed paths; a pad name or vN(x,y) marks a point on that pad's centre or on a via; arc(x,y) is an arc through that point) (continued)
CPU_DP2_N2_C: length 2.2
  BOTTOM w0.104: CV91.2 111.98,125.53 111.98,125.96 112.42,126.4 112.42,126.76 112.31,126.87 UV7.13
CPU_DP2_N3: length 19.8
  TOP w0.104: v2(109.98,124.08) 109.98,123.3 109.23,122.55 107.74,122.55 106.93,121.74 105.67,121.74 104.16,120.23 103.45,120.23 103.01,119.79 103.01,115.72 103.23,115.5 103.51,115.5 v2(103.63,115.37)
  BOTTOM w0.076: UC1.D51 103.55,111.82 103.27,112.1 103.27,112.51 103.47,112.72 103.47,112.79 103.29,112.98 103.29,113.96 103.43,114.11 103.43,114.27 104,114.84 104,115.51 103.91,115.61 103.71,115.61 103.63,115.53 v2(103.63,115.37)
  BOTTOM w0.104: v2(109.98,124.08) 110.16,124.26 110.16,124.6 CV93.1
CPU_DP2_N3_C: length 2.7
  BOTTOM w0.104: CV93.2 110.19,125.52 110.19,125.69 110.5,125.99 110.94,125.99 111.21,126.26 111.21,126.69 111.11,126.8 UV7.16
CPU_DP2_P0: length 26.6
  TOP w0.104: v2(115.95,123.82) 115.79,123.99 115.79,124.22 115.57,124.45 115.01,124.45 114.79,124.22 114.79,123.96 114.46,123.63 113.39,123.63 112.58,124.44 111.47,124.44 111.1,124.07 111.1,123.36 109.66,121.92 107.99,121.92 107.18,121.11 105.95,121.11 104.38,119.54 v2(103.65,119.54)
  BOTTOM w0.076: 104.55,113.94 104.45,113.83 104.45,113.78 arc(104.46,113.67) 104.5,113.57 arc(104.57,113.36) 104.54,113.14 arc(104.51,112.99) 104.53,112.85 arc(104.56,112.7) 104.55,112.56 arc(104.53,112.49) 104.51,112.43 arc(104.51,112.43) 104.51,112.43 arc(104.5,112.41) 104.49,112.39 104.49,112.36 104.49,112.36 arc(104.49,112.36) 104.49,112.35 104.49,112.35 104.49,112.35 104.49,112 104.11,111.62 UC1.D50
  BOTTOM w0.089: v2(103.65,119.54) 104.37,119.54 104.87,119.04 104.87,114.25 104.55,113.94
  BOTTOM w0.104: v2(115.95,123.82) 115.76,124.02 115.76,124.66 CV86.1
CPU_DP2_P0_C: length 2.3
  BOTTOM w0.104: UV7.6 115.11,126.88 115.01,126.78 115.01,126.53 115.72,125.82 115.72,125.59 CV86.2
CPU_DP2_P1: length 26.4
  TOP w0.104: v2(102.42,115.83) 102.28,115.97 101.9,115.97 101.58,116.29 101.58,118.8 102.24,119.46 102.24,119.94 103.21,120.91 103.92,120.91 105.38,122.38 106.67,122.38 107.5,123.2 108.35,123.2 108.79,123.63 108.79,124.52 109.45,125.18 113.41,125.18 114.09,124.5 114.09,124.35 v2(114.3,124.14)
  BOTTOM w0.076: UC1.D52 102.77,111.69 102.69,111.96 102.69,112.07 102.63,112.29 102.61,112.35 102.55,112.55 102.55,112.77 102.61,112.97 102.61,113.04 102.56,113.09 102.56,113.16 102.55,113.17 102.55,113.54 102.69,113.67 102.69,113.77 102.73,113.81 102.73,113.82 102.74,113.83
  BOTTOM w0.089: v2(102.42,115.83) 102.42,115.86 102.55,116 102.75,116 102.83,115.92 102.83,113.92 102.74,113.83
  BOTTOM w0.104: v2(114.3,124.14) 114.09,124.35 114.09,124.47 113.99,124.58 113.99,124.67 CV88.1
CPU_DP2_P1_C: length 2
  BOTTOM w0.104: CV88.2 113.97,125.56 113.97,125.84 113.82,125.99 113.82,126.82 113.91,126.91 UV7.9
CPU_DP2_P2: length 19.6
  TOP w0.104: v2(103.65,117.2) 104.45,117.2 105.08,117.83 105.08,118.9 106.45,120.27 107.55,120.27 108.39,121.11 110.07,121.11 112.19,123.23 112.19,123.68 v2(112.33,123.82)
  BOTTOM w0.076: UC1.B50 104.08,112.66 103.67,113.07 103.67,113.82 103.85,113.99 103.85,114.05 104.34,114.54 104.34,117.45 104.18,117.61 103.98,117.61 103.65,117.28 v2(103.65,117.2)
  BOTTOM w0.104: CV90.1 112.14,124.54 112.14,124.49 112.14,124.48 112.14,124.02 v2(112.33,123.82)
CPU_DP2_P2_C: length 2.2
  BOTTOM w0.104: CV90.2 112.18,125.51 112.18,125.88 112.62,126.32 112.62,126.77 112.71,126.86 UV7.12
CPU_DP2_P3: length 20
  TOP w0.104: v2(110.56,124.08) 110.56,124.08 110.18,123.7 110.18,123.22 109.31,122.35 107.82,122.35 107.01,121.54 105.75,121.54 104.25,120.03 103.54,120.03 103.21,119.71 103.21,115.8 103.32,115.7 103.43,115.7 103.63,115.9 v2(103.63,116)
  BOTTOM w0.076: v2(103.63,116) 103.63,115.91 103.71,115.83 103.93,115.83 104.17,115.59 104.17,114.77 103.61,114.2 103.61,114.04 103.46,113.89 103.46,113.05 103.85,112.66 103.85,112.25 103.72,112.11 103.62,112.11 103.55,112.18 UC1.C51
  BOTTOM w0.104: CV92.1 110.36,124.53 110.36,124.28 v2(110.56,124.08)
CPU_DP2_P3_C: length 2.7
  BOTTOM w0.104: UV7.15 111.51,126.8 111.41,126.7 111.41,126.18 111.03,125.79 110.58,125.79 110.39,125.6 110.39,125.52 CV92.2
CPU_DP3_AUXN: length 1.1
  TOP w0.102: v2(105.6,109.6) 105.58,109.57 T1.1
  BOTTOM w0.102: UC1.G46 105.98,109.29 105.68,109.6 v2(105.6,109.6)
CPU_DP3_AUXP: length 2
  TOP w0.112: T2.1 105.07,110.75 v2(105.58,110.23)
  BOTTOM w0.102: UC1.F46 105.69,110.23 v2(105.58,110.23)
CPU_POPIRCOMP: length 11.9
  TOP w0.381: v2(124.48,89.52) v4(124.48,88.44) 124.48,87.16 123.79,86.46 RC88.1
  IN2 w0.254: v2(122.86,94.25) 122.67,94.25 122.41,93.99 122.41,92.7 122.83,92.28
  IN2 w0.381: v2(124.48,89.52) 124.26,89.52 123.77,90 123.77,91.34 122.83,92.28
  BOTTOM w0.254: UC1.AT16 123.29,94.45 123,94.23 v2(122.86,94.25)
CPU_XDP_PRDY#: length 19.8
  TOP w0.112: v2(102.13,128.79) v1(102.13,127.46) 102.13,125.36 99.85,123.07 99.85,115.33 v2(99.9,115.28)
  BOTTOM w0.076: v2(99.9,115.28) 99.9,114.82 100.22,114.5 100.22,113.69 100.07,113.54 100.07,113.17 100.11,113.1 100.11,112.89 100.1,112.86 100.1,112.83 100.08,112.82 100.07,112.8 100.07,112.55 100.09,112.51 100.13,112.35 100.21,112.07 100.21,111.96 100.29,111.69 UC1.D56
  BOTTOM w0.112: JXDP1.5 102.31,128.97 v2(102.13,128.79)
CPU_XDP_PREQ#: length 23
  TOP w0.112: v2(98.1,114.93) 98.22,114.82 100.02,114.82 100.29,115.09 100.29,115.54 100.1,115.73 100.1,122.95 v1(102.58,125.42) 102.58,128.62 v2(102.74,128.79)
  BOTTOM w0.076: v2(98.1,114.93) 98.32,114.71 98.32,112.48 98.3,112.46 98.3,112.22 98.32,112.2 98.32,111.83 98.3,111.81 98.3,111.63 UC1.D61
  BOTTOM w0.112: RC138.1 102.74,128.13 v2(102.74,128.79) 102.91,128.96 JXDP1.3
CPU_XDP_TCLK: length 26.2
  IN1 w0.119: v2(96.59,118.25) 96.59,118.66 93.32,121.94 91.27,121.94 91.14,121.8 89.49,121.8 88.65,122.64 87.73,122.64 v2(87.45,122.93)
  BOTTOM w0.076: UC1.B61 97.82,112.87 97.82,113.09 97.76,113.21 97.76,113.47 97.94,113.64 97.94,114.36 96.84,115.46 96.84,116.46 96.48,116.81 96.48,117.24 96.8,117.55 96.8,118.04 v2(96.59,118.25)
  BOTTOM w0.112: RC328.1 v2(96.59,118.25) ; JXDP1.57 86.71,129.37 86.33,128.99 86.33,128.38 RC139.1 87.15,127.57 87.15,125.01 87.45,124.71 v2(87.45,122.93)
CPU_XDP_TDI: length 28.8
  TOP w0.112: v2(80.1,120.48) v4(80.1,121.27)
  IN1 w0.119: v2(97.41,116.91) 97.09,116.6 96.29,116.6 95.59,117.3 95.59,118.33 93.57,120.36 90.86,120.36 90.42,120.79 86.96,120.79 86.21,120.04 80.54,120.04 v2(80.1,120.48)
  BOTTOM w0.076: UC1.D60 98.59,111.93 98.88,112.22 98.88,112.46 98.66,112.68 98.66,115.11 97.41,116.37 v2(97.41,116.91)
  BOTTOM w0.112: UC8.6 80.3,120.75 80.1,120.54 v2(80.1,120.48) 80.03,120.48 79.78,120.23 RC134.1
CPU_XDP_TDO: length 23.2
  IN1 w0.119: v2(82.09,120.45) 82.65,121.01 90.52,121.01 90.95,120.58 93.66,120.58 95.81,118.42 95.81,117.46 96.23,117.04 v2(96.84,117.04)
  BOTTOM w0.076: UC1.A61 98.11,113.4 98.11,114.42 97,115.53 97,116.88 v2(96.84,117.04)
  BOTTOM w0.112: RC135.1 82,120.37 v2(82.09,120.45) 82.09,120.52 81.8,120.8 UC8.3
CPU_XDP_TMS: length 32
  TOP w0.112: v2(79.51,117.55) 79.51,119.08 v4(79.35,119.24)
  IN1 w0.119: v2(79.51,117.55) 80.16,116.9 84.4,116.9 84.89,116.4 94.83,116.4 95.55,115.69 v2(97.43,115.69)
  BOTTOM w0.076: UC1.C60 98.5,112.43 98.5,115.04 97.85,115.69 v2(97.43,115.69)
  BOTTOM w0.112: v2(79.51,117.55) 79.51,117.61 78.87,118.25 78.87,119.93 77.87,120.93 77.87,122.07 RC131.1 78.61,122.8 UC8.8
CPU_XDP_TRST#: length 38.2
  TOP w0.112: CC308.1 96.8,120.93 96.8,118.73 97.41,118.12 v2(97.41,117.55)
  IN1 w0.119: v2(97.41,117.55) 97.34,117.61 v2(96.35,117.61) 96.03,117.93 96.03,118.51 93.75,120.8 91.04,120.8 90.61,121.23 89.35,121.23 88.45,122.14 86.11,122.14 v2(84.99,123.26)
  BOTTOM w0.076: UC1.B59 98.83,112.99 98.83,115.18 97.93,116.08 97.93,117.03 v2(97.41,117.55) ; UC1.C61 98.03,112.08 97.63,112.47 97.63,113.08 97.61,113.14 97.6,113.17 97.6,113.54 97.77,113.71 97.77,114.3 96.67,115.39 96.67,116.34 96.19,116.83 96.19,117.45 v2(96.35,117.61)
  BOTTOM w0.112: UC8.11 81.3,124.8 RC136.1 81.8,125.32 82.27,125.79 83.09,125.79 84.99,123.89 v2(84.99,123.26)
CSI2_COMP: length 10.9
  TOP w0.254: v2(125.8,117.21) v1(125.8,117.75) 125.8,118.6 125.5,118.91 125.5,120.2 RC3.1
  IN2 w0.254: v2(125.8,117.21) 125.8,115.89 125.37,115.45 125.37,111.77 124.71,111.11 v2(124.71,110.84)
  BOTTOM w0.254: UC1.E13 v2(124.71,110.84)
CSIN_ISL88738: length 6
  TOP w0.112: v1(55.64,60.77) 55.92,60.48 v2(55.92,60.27)
  TOP w0.203: PU901.14 v2(55.92,60.27)
  BOTTOM w0.254: PC927.1 56.45,59.79 55.97,60.27 v2(55.92,60.27) 55.92,61.33 55.38,61.87 PC925.2 54.41,61.87 PR910.2
CSIP_ISL88738: length 5.7
  TOP w0.112: v2(55.27,60.27) 55.27,61.16 v1(54.41,62.02)
  TOP w0.203: v2(55.27,60.27) 55.27,59.85 55.52,59.6 PU901.15
  BOTTOM w0.254: PC926.1 55.27,59.92 v2(55.27,60.27) PC925.1 54.41,60.96 PR909.2
CSON_ISL88738: length 5.2
  TOP w0.203: v2(59.84,54.87) 59.65,54.87 58.89,55.64 PU901.1
  BOTTOM w0.112: PR938.1 v1(61.35,53.96)
  BOTTOM w0.254: PR938.1 60.49,54.94 PC945.1 60.43,54.87 v2(59.84,54.87) 59.59,54.87 59.07,54.35 PC946.1
CSOP_ISL88738: length 5.6
  TOP w0.112: v1(60.35,54.23) 60.35,55 v2(59.84,55.51)
  TOP w0.203: v2(59.84,55.51) 59.52,55.51 59,56.04 PU901.2
  BOTTOM w0.254: PR937.1 60.49,55.83 PC945.2 60.36,55.84 60.03,55.51 v2(59.84,55.51) 59.79,55.51 PC942.1
CV2_ON: length 62.2
  TOP w0.112: RE539.2 257.61,100.43 256.97,99.79 v2(256.97,99.77)
  IN3 w0.135: v2(256.97,99.77) 256.94,99.77 254.98,97.8 254.98,96.02 255.55,95.45 255.55,94.63 255.93,94.24 255.93,91.64 255.35,91.06 254.12,91.06 253.88,90.82 253.88,90.48 253.66,90.26 247.55,90.26 246.63,89.34 246.63,83.37 245.69,82.43 245.69,80.84 246.48,80.04 246.48,78.54 245.31,77.37 245.31,74.11 245.81,73.61 245.81,70.09 244,68.28 244,65.79 240.09,61.88 240.09,61.25 239.1,60.26 237.83,60.26 237.14,60.95 234.48,60.95 v2(233.56,60.03)
  BOTTOM w0.112: JUSH1.3 232.45,59.59 232.89,60.03 v2(233.56,60.03)
CV2_ON_R: length 17.6
  TOP w0.112: RPE10.1 258.47,99.13 257.97,99.63 RE539.1 257.61,99.3 v2(258.47,98.44) ; UE1.H8 252.68,89.86 v2(252.69,89.86)
  IN2 w0.124: v2(258.47,98.44) 258.35,98.31 257.46,98.31 257.12,97.98 257.12,96.39 256.55,95.82 256.55,94.82 256.11,94.38 254.81,94.38 254.39,94.8 253.2,94.8 252.2,93.8 252.2,90.4 252.69,89.9 v2(252.69,89.86)
DAT_TP_SIO_I2C_CLK: length 78.3
  TOP w0.107: UE1.C12 247.86,93.08 247.86,93.67 247.65,93.89 247.65,94.37 v2(247.14,94.88)
  TOP w0.112: v2(228.85,60.06) 228.65,60.26 228.65,60.91 228.3,61.26 v3(225.42,61.26) 221.14,61.26 217.84,57.96 217.84,57.26 217.73,57.15 217.57,57.15 217.45,57.27 v2(217.45,57.32) 217.37,57.4 217.32,57.4 217.12,57.61 RZ347.1 ; v2(210.63,55.51) 210.44,55.32 CZ80.1 209.97,55.7 RZ22.2
  IN3 w0.135: v2(228.85,60.06) 228.73,60.18 228.73,60.47 230.93,62.67 235.98,62.67 237.53,64.21 240.09,64.21 240.49,64.62 240.49,65.14 241.26,65.91 241.26,67.93 243.81,70.48 243.81,73.84 243.38,74.27 243.38,85.46 243.1,85.74 241.69,85.74 241.47,85.96 241.47,88.75 244.25,91.54 244.25,93.47 245.79,95.01 246.55,95.01 246.65,94.91 247.12,94.91 v2(247.14,94.88)
  BOTTOM w0.112: v2(217.45,57.32) 217.3,57.32 216.97,57.65 215.89,57.65 214.2,55.97 211.09,55.97 v2(210.63,55.51)
DAT_TP_SIO_R: length 3.8
  TOP w0.112: v1(210.04,59.49) 210.41,59.12 RZ18.2 210.41,57.81 v2(210.42,57.8) 210.46,57.76 RZ22.1
  BOTTOM w0.112: JKBTP1.8 210.55,58.33 210.42,58.2 v2(210.42,57.8)
DCIN1_EN: length 282
  TOP w0.112: v2(268.75,95.59) UE2.12
  IN2 w0.124: v2(43.78,60.58) 44.63,60.58 48.11,57.1 50.81,57.1 52.76,55.15 58.85,55.15 59.58,54.43 60.09,54.43 61.69,56.03 69.45,56.03 70.44,55.04 71.48,55.04 74.99,51.54 113.27,51.54 114.97,53.25 140.64,53.25 141.17,53.64 142.12,54.35 146.33,54.35 148.05,56.07 158.74,56.07 161.05,53.76 176.05,53.76 178.51,51.29 179.22,51.29 179.56,51.63 182.96,51.63 184.26,50.33 209.12,50.33 210.63,51.84 213.3,51.84 213.85,51.29 225.35,51.29 226.25,52.19 228.25,52.19 228.93,51.51 237.92,51.51 239.94,53.53 239.94,54.32 242.37,56.74 243.1,56.74 245.54,59.19 245.54,60.03 249.68,64.17 252.02,64.17 253.06,65.21 256.16,65.21 256.46,65.52 260.98,65.52 263.23,67.76 268.45,67.76 271.09,70.4 271.09,77.28 267.28,81.1 267.28,84.1 266.78,84.59 266.78,87.88 271.69,92.79 271.69,93.48 271.02,94.15 270.19,94.15 v2(268.75,95.59)
  BOTTOM w0.254: PR1221.1 41.86,60.65 42.76,61.56 43.48,61.56 v1(43.78,61.26) v2(43.78,60.58)
DCIN2_EN: length 336.9
  TOP w0.112: v1(60.22,117.54) 60.4,117.71 v2(60.4,118.17) 60.4,118.57 PR26.1 ; UE2.15 v2(267.25,95.58)
  IN2 w0.124: v2(60.4,118.17) 60.4,115.82 60.09,115.52 60.09,113.14 62.28,110.96 70.08,110.96 70.25,110.78 70.25,104.71 71.32,103.64 72.34,103.64 72.85,103.13 72.85,89.19 72.49,88.83 72.49,85.28 61.97,74.76 61.97,66.94 63.92,65 63.92,60 62.6,58.68 62.6,56.9 63.25,56.25 69.55,56.25 70.53,55.27 72.53,55.27 76.04,51.77 102.55,51.77 104.3,53.52 140.55,53.52 142.02,54.62 146.28,54.62 147.95,56.3 158.84,56.3 161.15,53.99 176.15,53.99 178.61,51.52 179.12,51.52 179.47,51.88 183.06,51.88 184.38,50.56 209,50.56 210.5,52.07 213.39,52.07 213.92,51.54 225.24,51.54 226.16,52.46 228.95,52.46 229.67,51.74 237.83,51.74 239.72,53.63 239.72,54.41 242.27,56.97 243,56.97 245.31,59.28 245.31,60.13 249.6,64.43 251.92,64.43 252.93,65.44 256.01,65.44 256.31,65.75 260.88,65.75 263.12,67.99 268.36,67.99 270.81,70.44 270.81,77.18 267.04,80.95 267.04,84.01 266.55,84.5 266.55,88.11 271.47,93.02 271.47,93.38 270.95,93.9 269.79,93.9 268.68,95.01 267.82,95.01 v2(267.25,95.58)
DCIN3_EN: length 4.5
  TOP w0.107: UE1.F12 250.28,93.06 250.28,94.62 249.7,95.2 249.7,96.22 T262.1
DCIN_ISL88738: length 2.9
  TOP w0.112: v1(53.27,59.29) 53.68,59.29 54.06,58.91
  BOTTOM w0.508: PR916.1 53.52,59.7 PC931.2 v2(54.44,59)
DDR_A_ACT#: length 44.4
  IN3 w0.076: 95.94,77.35 95.94,79.45 97.71,81.21 97.71,83.44 98.41,84.15 v2(98.59,84.15)
  IN3 w0.183: 95.94,77.35 95.94,68.42 96.63,67.73 96.63,67.08 99.31,64.4 99.31,60.98 100.24,60.05 100.24,57.95 100.7,57.49 101.68,57.49 v2(101.91,57.26)
  BOTTOM w0.076: v2(98.59,84.15) 99.34,84.9 99.34,87.68 100.8,89.14 100.8,89.86 100.79,89.88 100.79,90.27 100.93,90.41 100.93,90.82 100.88,90.96 100.88,91.07 100.93,91.2 100.93,91.43 UC1.BA55
  BOTTOM w0.183: v2(101.91,57.26) 101.96,57.26 104.47,54.74 JDIMM1.114
DDR_A_ALERT#: length 53
  IN3 w0.076: v2(104.56,92.42) 104.21,92.78 104.21,94.12 103.92,94.41 100.79,94.41 100.49,94.11 100.49,84.1 99.08,82.69 99.08,81.59 98.65,81.16
  IN3 w0.183: 98.65,81.16 97.33,79.85 97.33,69.02 98.04,68.31 98.04,67.92 101.58,64.39 101.58,62 102.72,60.86 102.72,55.06 102.9,54.87 104.31,54.87 v2(104.79,55.35)
  BOTTOM w0.076: v2(104.56,92.42) 104.35,92.64 UC1.AW50
  BOTTOM w0.183: v2(104.79,55.35) 104.79,55.04 104.97,54.86 JDIMM1.116
DDR_A_BA0: length 45.6
  IN3 w0.076: 106.54,79.66 106.15,80.06 106.15,87.73 104.11,89.76 104.11,91.58 102.78,92.91 v2(102.78,93.46)
  IN3 w0.183: v2(113.97,56.75) 113.96,56.75 113.06,57.65 113.06,59.3 113.1,59.35 113.1,64.93 107.11,70.93 107.11,79.1 106.54,79.66
  BOTTOM w0.076: UC1.AU52 102.78,93.47 v2(102.78,93.46)
  BOTTOM w0.183: v2(113.97,56.75) 115.48,55.25 JDIMM1.150
DDR_A_BA1: length 45.8
  IN3 w0.076: 108.95,78.73 108.95,78.93 107.16,80.72 107.16,90.92 104.98,93.1 104.98,94.04 104.91,94.1 v2(104.61,94.1)
  IN3 w0.183: v2(115.6,58.66) 115.6,58.97 114.95,59.62 114.95,65.74 108.95,71.74 108.95,78.73
  BOTTOM w0.076: v2(104.61,94.1) UC1.AT48
  BOTTOM w0.183: v2(115.6,58.66) 115.16,58.22 114.6,58.22 114.42,58.4 114.42,59.64 114.22,59.84 114.22,61.9 JDIMM1.145
DDR_A_BG0: length 46.7
  IN3 w0.076: v2(98.6,83.57) 98.6,83.7 98.52,83.78 98.28,83.78 97.87,83.38 97.87,81.14 96.41,79.67 96.41,77.35
  IN3 w0.183: 96.41,77.35 96.41,68.62 97.1,67.93 97.1,67.27 99.77,64.59 99.77,61.17 100.7,60.24 100.7,58.14 100.89,57.96 101.34,57.96 101.52,58.14 101.52,58.42 101.63,58.53 v2(101.91,58.53)
  BOTTOM w0.076: v2(98.6,83.57) 98.6,83.44 98.84,83.2 99.16,83.2 99.24,83.28 99.24,84.14 99.58,84.48 99.58,87.68 101.53,89.64 101.53,90.19 101.39,90.33 101.39,90.83 101.4,90.86 101.44,90.94 101.44,91.06 101.37,91.28 101.37,91.42 101.43,91.58 101.43,91.76 101.4,91.83 101.27,91.96 101.08,91.96 100.99,92.05 100.99,92.24 UC1.AY55
  BOTTOM w0.183: v2(101.91,58.53) 102.52,59.14 103.41,59.14 103.99,59.72 103.99,60.26 104.72,61 JDIMM1.115
DDR_A_BG1: length 47.3
  IN3 w0.076: 96.87,77.35 96.87,79.81 98.07,81.02 98.07,82.19 98.17,82.28 98.58,82.28 v2(98.6,82.27)
  IN3 w0.183: v2(101.91,59.8) 101.91,59.79 101.65,59.53 101.35,59.53 101.17,59.71 101.17,60.24 101.79,60.87 101.79,61.13 101.56,61.36 101.3,61.36 100.93,61 100.67,61 100.24,61.43 100.24,61.71 100.42,61.89 100.93,61.89 101.12,62.08 101.12,62.44 100.93,62.62 100.42,62.62 100.24,62.81 100.24,63.17 100.42,63.36 100.93,63.36 101.12,63.54 101.12,63.9 100.93,64.09 100.42,64.09 100.24,64.27 100.24,64.78 99.46,65.56 99.46,65.85 99.09,66.22 98.8,66.22 98.42,66.59 98.42,66.89 98.05,67.26 97.76,67.26 97.56,67.46 97.56,68.12 96.87,68.81 96.87,77.35
  BOTTOM w0.076: v2(98.6,82.27) 99.04,82.27 99.4,82.62 99.4,83.82 99.79,84.21 99.79,87.65 101.7,89.56 101.7,90.31 101.56,90.45 101.56,90.79 101.61,90.91 101.61,91.05 101.55,91.28 101.55,91.41 101.62,91.63 101.62,91.89 UC1.AY54
  BOTTOM w0.183: JDIMM1.113 104.22,61.19 103.55,60.52 103.55,59.9 103.27,59.62 102.92,59.62 102.74,59.81 102.74,60.23 102.61,60.37 102.09,60.37 101.91,60.19 v2(101.91,59.8)
DDR_A_CKE0: length 45.9
  IN3 w0.076: v2(98.6,85.98) 98.39,85.98 97.27,84.86 97.27,81.26 95.48,79.47 95.48,77.35
  IN3 w0.183: v2(99.79,59.23) 99.63,59.23 99.35,58.95 99.35,57.75 99.16,57.57 98.48,57.57 98.3,57.75 98.3,59.94 98.85,60.49 98.85,64.21 96.17,66.89 96.17,67.54 95.48,68.23 95.48,77.35
  BOTTOM w0.076: v2(98.6,85.98) 98.28,85.98 98.21,86.05 98.21,87.26 100.31,89.36 100.31,89.69 100.29,89.7 100.29,90.42 100.23,90.49 100.23,90.79 100.23,90.79 100.35,91.04 100.35,91.04 100.36,91.05 100.5,91.19 UC1.BA56
  BOTTOM w0.183: v2(99.79,59.23) 99.79,59.23 101.37,60.81 102.95,60.81 103.22,61.08 JDIMM1.109
DDR_A_CKE1: length 45
  IN3 w0.076: v2(98.59,86.62) 97.11,85.14 97.11,81.42 95.02,79.33 95.02,77.35
  IN3 w0.183: 95.02,77.35 95.02,68.04 95.71,67.35 95.71,66.69 98.39,64.02 98.39,61.57 97.78,60.96 97.78,57.33 99.11,55.99 v2(101.91,55.99)
  BOTTOM w0.076: v2(98.59,86.62) 98.59,87.4 100.47,89.29 100.47,89.75 100.46,89.76 100.46,90.65 UC1.BB56
  BOTTOM w0.183: v2(101.91,55.99) 102.08,55.99 103.47,54.6 JDIMM1.110
DDR_A_CKE2: length 10.3
  TOP w0.107: v2(98.58,84.75) 97.56,84.75 T3.1
  BOTTOM w0.076: v2(98.58,84.75) 99.08,85.25 99.08,87.66 100.64,89.22 100.64,89.8 100.62,89.82 100.62,90.35 100.76,90.49 100.76,90.79 100.71,90.9 100.71,91.12 100.76,91.23 100.76,91.44 100.73,91.52 100.73,91.8 100.74,91.8 100.76,91.86 100.76,92.17 100.71,92.22 100.71,92.42 UC1.AW56
DDR_A_CKE3: length 7.3
  BOTTOM w0.076: T4.1 97.89,85.84 97.89,87.17 100.13,89.41 100.13,89.62 100.07,89.68 100.07,90.82 100.09,90.87 100.09,90.87 100.23,91.23 100.23,91.52 100.5,91.78 UC1.AY56
DDR_A_CLK0: length 46.8
  IN3 w0.076: v2(101.86,94.04) 101.84,94.06 101.59,94.06 101.48,93.94 101.48,91.52 101.66,91.34 102.72,91.34 102.81,91.24 102.81,89.94 105.05,87.7 105.05,87.67
  IN3 w0.117: v2(112.31,58.85) 112.28,58.88 111.69,58.88 111.45,59.12 111.45,64.69 105.76,70.38 105.76,78.94 105.18,79.51 105.18,87.53 105.05,87.67
  BOTTOM w0.076: v2(101.86,94.04) 101.86,94.28 102.04,94.45 UC1.AT53
  BOTTOM w0.104: v2(112.31,58.85) 110.65,58.85 110.19,59.31 110.19,60.42 110.39,60.62 110.39,60.89 110.22,61.06 JDIMM1.137
DDR_A_CLK1: length 47.2
  IN3 w0.076: v2(100.95,94.04) 101.31,93.69 101.31,93.12 101.31,93.11 101.31,91.42 102.09,90.64 102.09,89.99 104.31,87.77 104.34,87.77 104.34,87.77
  IN3 w0.117: 104.34,87.77 104.72,87.39 104.72,78.89 105.13,78.48 105.13,70.12 110.83,64.42 110.83,58.5 111.81,57.52 112.25,57.52 v2(112.31,57.58)
  BOTTOM w0.076: UC1.AT55 100.95,94.1 v2(100.95,94.04)
  BOTTOM w0.104: v2(112.31,57.58) 112.2,57.47 111.52,57.47 111.02,56.97 111.02,56.17 110.64,55.78 110.64,54.65 110.48,54.48 JDIMM1.138
DDR_A_CLK#0: length 46.9
  IN3 w0.076: 105.2,87.82 105.18,87.82 102.98,90.02 102.98,91.31 102.79,91.51 101.73,91.51 101.65,91.59 101.65,93 101.74,93.09 102.13,93.09 102.23,93.2 102.23,93.38 102.12,93.48 101.89,93.48 v2(101.86,93.46)
  IN3 w0.117: v2(112.31,59.53) 112.31,59.43 111.97,59.09 111.78,59.09 111.66,59.21 111.66,64.78 105.97,70.47 105.97,79.03 105.4,79.6 105.4,87.62 105.2,87.82
  BOTTOM w0.076: UC1.AU53 102.42,93.7 102.42,93.44 102.26,93.28 102.02,93.28 101.86,93.43 v2(101.86,93.46)
  BOTTOM w0.104: JDIMM1.139 110.72,61.05 110.59,60.92 110.59,60.54 110.39,60.34 110.39,59.4 110.74,59.05 111.94,59.05 112.31,59.42 v2(112.31,59.53)
DDR_A_CLK#1: length 47.2
  IN3 w0.076: 104.19,87.62 104.19,87.65 101.92,89.92 101.92,90.57 101.14,91.35 101.14,93.04 101.08,93.1 100.87,93.1 100.79,93.18 100.79,93.41 100.85,93.47 100.94,93.47 v2(100.95,93.46)
  IN3 w0.117: v2(112.31,56.94) 112.31,56.99 111.99,57.31 111.72,57.31 110.62,58.41 110.62,64.33 104.92,70.03 104.92,78.4 104.51,78.8 104.51,87.3 104.19,87.62
  BOTTOM w0.076: v2(100.95,93.46) 100.95,93.6 101.23,93.8 UC1.AU55
  BOTTOM w0.104: v2(112.31,56.94) 112.31,57 112.05,57.27 111.61,57.27 111.23,56.88 111.23,56.08 110.84,55.7 110.84,54.65 110.97,54.52 JDIMM1.140
DDR_A_CS#0: length 50.3
  IN3 w0.076: 110.34,78.55 110.34,78.9 107.83,81.4 107.83,91.13 105.88,93.09 105.88,93.98 105.99,94.09 106.36,94.09 106.44,94.02 v2(106.44,93.47)
  IN3 w0.183: 110.34,78.55 110.34,72.31 116.82,65.83 116.82,65.55 116.64,65.37 116.52,65.37 116.34,65.18 116.34,64.82 116.52,64.64 116.64,64.64 116.82,64.45 116.82,62.95 116.64,62.77 116.52,62.77 116.34,62.58 116.34,62.22 116.52,62.03 116.64,62.03 116.82,61.85 116.82,61.41 117.35,60.89 117.35,59.15 117.67,58.83 117.67,57.98 117.48,57.79 117.15,57.79 v2(116.94,58)
  BOTTOM w0.076: v2(106.44,93.47) 106.32,93.47 106.26,93.53 106.26,93.89 106.44,94.07 106.71,94.07 106.89,93.89 UC1.AU45
  BOTTOM w0.183: v2(116.94,58) 116.9,58 115.02,59.88 115.02,60.82 115.22,61.02 115.22,61.9 JDIMM1.149
DDR_A_CS#1: length 52
  IN3 w0.076: 111.27,78.27 111.27,78.67 108.94,81 108.94,91.65 107.35,93.24 v2(107.35,93.46)
  IN3 w0.183: 111.27,78.27 111.27,72.7 117.75,66.22 117.75,64.48 119.29,62.94 119.29,60.42 118.59,59.72 118.59,58.52 119.15,57.95 119.15,55.99 118.92,55.76 117.9,55.76 117.71,55.95 117.71,57.37 v2(118.11,57.77)
  BOTTOM w0.102: UC1.AU43 v2(107.35,93.46)
  BOTTOM w0.183: v2(118.11,57.77) 118.57,58.22 118.57,59.68 117.22,61.02 117.22,61.9 JDIMM1.157
DDR_A_D0: length 61.6
  IN3 w0.117: v2(77.23,57.47) 76.82,57.88 76.82,59.28 75.63,60.47 75.63,66.15 76.83,67.35 76.83,83.8 76.95,83.91 77.17,83.91 77.29,84.03 77.29,84.27 77.17,84.38 76.95,84.38 76.83,84.5 76.83,84.73 76.95,84.85 77.17,84.85 77.29,84.97 77.29,85.2 77.17,85.32 76.95,85.32 76.83,85.43 76.83,86.41 76.95,86.52 77.17,86.52 77.29,86.64 77.29,86.87 77.17,86.99 76.95,86.99 76.83,87.11 76.83,87.42 76.95,87.53 77.17,87.53 77.29,87.65 77.29,87.88 77.17,88 76.95,88 76.83,88.12 76.83,93.29 81.02,97.48 87.51,97.48 v2(88.42,96.58)
  BOTTOM w0.076: 89.14,97.14 90.14,97.14 90.49,97.49 91.76,97.49 UC1.AL71
  BOTTOM w0.102: 89.14,97.14 88.98,97.14 v2(88.42,96.58)
  BOTTOM w0.112: JDIMM1.7 77.73,60.92 77.66,60.86 77.66,57.9 v2(77.23,57.47)
DDR_A_D1: length 62.4
  IN3 w0.117: v2(83.82,95.57) 83.82,95.99 83.48,96.32 81.32,96.32 78.29,93.28 78.29,76.81 77.83,76.35 77.83,64.57 76.63,63.37 76.63,62.9 76.74,62.78 77.29,62.78 77.41,62.67 77.41,60.11 78.12,59.4 78.12,54.23 78,54.11 77.35,54.11 77.23,54.23 v2(77.23,54.93)
  BOTTOM w0.076: 84.24,95.32 86.85,95.32 87.24,95.71 88.71,95.71 89.43,96.43 91.23,96.43 91.41,96.61 91.93,96.61 91.96,96.6 92.04,96.57 92.16,96.57 92.37,96.63 92.52,96.63 92.68,96.58 92.86,96.58 93.04,96.67 93.53,96.67 93.69,96.83 93.69,97.46 UC1.AL68
  BOTTOM w0.089: 84.07,95.32 v2(83.82,95.57)
  BOTTOM w0.112: JDIMM1.4 76.97,54.67 v2(77.23,54.93) ; 84.24,95.32 84.07,95.32
DDR_A_D2: length 63.4
  IN3 w0.117: v2(80.06,58.74) 80.06,59.32 79.79,59.59 79.79,62.15 79.68,62.26 79.29,62.26 79.17,62.38 79.17,62.67 79.29,62.79 79.64,62.79 79.76,62.9 79.76,63.14 79.64,63.25 79.35,63.25 79.24,63.37 79.24,63.6 79.35,63.72 79.64,63.72 79.76,63.84 79.76,64.07 79.64,64.19 79.41,64.19 79.3,64.3 79.3,64.54 79.41,64.65 79.64,64.65 79.76,64.77 79.76,65.01 79.64,65.12 79.41,65.12 79.3,65.24 79.3,65.47 79.41,65.59 79.64,65.59 79.76,65.71 79.76,65.94 79.64,66.06 79.41,66.06 79.3,66.17 79.3,66.41 79.41,66.52 79.64,66.52 79.76,66.64 79.76,66.87 79.64,66.99 79.41,66.99 79.3,67.11 79.3,67.34 79.41,67.46 79.64,67.46 79.76,67.58 79.76,67.81 79.64,67.93 79.41,67.93 79.3,68.04 79.3,68.28 79.41,68.39 79.64,68.39 79.76,68.51 79.76,68.74 79.64,68.86 79.41,68.86 79.3,68.98 79.3,69.21 79.41,69.33 79.64,69.33 79.76,69.45 79.76,69.68 79.64,69.8 79.41,69.8 79.3,69.91 79.3,70.13 79.41,70.25 79.64,70.25 79.76,70.36 79.76,70.6 79.64,70.72 79.41,70.72 79.3,70.83 79.3,71.07 79.41,71.18 79.64,71.18 79.76,71.3 79.76,71.53 79.64,71.65 79.41,71.65 79.3,71.77 79.3,72 79.41,72.12 79.64,72.12 79.76,72.23 79.76,72.47 79.64,72.58 79.41,72.58 79.3,72.7 79.3,72.94 79.41,73.05 79.64,73.05 79.76,73.17 79.76,73.4 79.64,73.52 79.41,73.52 79.3,73.64 79.3,73.87 79.41,73.99 79.64,73.99 79.76,74.1 79.76,74.34 79.64,74.45 79.41,74.45 79.3,74.57 79.3,74.8 79.41,74.92 79.64,74.92 79.76,75.04 79.76,75.27 79.64,75.39 79.41,75.39 79.3,75.51 79.3,75.74 79.41,75.86 79.64,75.86 79.76,75.97 79.76,85.66 79.95,85.86 80.95,85.86 84.9,89.82 84.9,90.03 85.23,90.36 85.23,92.55 85.23,92.56 85.23,93.55 86.89,95.21 87.86,95.21 88.11,94.96 v2(88.11,94.77)
  BOTTOM w0.076: UC1.AN68 93.74,96.36 93.64,96.46 93.49,96.46 93.39,96.36 93.39,96.14 93.19,95.93 93.09,95.93 93.01,95.96 92.91,95.99 92.8,96.01 92.63,95.96 92.43,95.75 91.49,95.75 91.49,95.75 89.83,95.75 88.98,94.91 88.24,94.91 v2(88.11,94.77)
  BOTTOM w0.112: JDIMM1.17 80.22,61.02 80.13,60.93 79.96,60.93 79.84,60.82 79.84,60.64 79.96,60.53 80.43,60.53 80.54,60.42 80.54,60.24 80.43,60.13 80.17,60.13 80.06,60.01 80.06,59.8 80.17,59.69 80.43,59.69 80.54,59.58 80.54,59.35 80.43,59.24 80.17,59.24 80.06,59.13 v2(80.06,58.74)
DDR_A_D3: length 62.5
  IN3 w0.117: v2(80.06,54.93) 79.53,54.93 79.37,54.77 79.37,53.84 79.58,53.63 82.14,53.63 82.37,53.86 82.37,55.03 81.84,55.55 81.84,57.31 81.43,57.72 81.43,63.67 80.76,64.35 80.76,66.25 81.21,66.7 81.21,66.92 81.09,67.04 80.87,67.04 80.76,67.15 80.76,67.39 80.87,67.51 81.09,67.51 81.21,67.62 81.21,67.86 81.09,67.97 80.87,67.97 80.76,68.09 80.76,68.32 80.87,68.44 81.09,68.44 81.21,68.56 81.21,68.79 81.09,68.91 80.87,68.91 80.76,69.02 80.76,69.26 80.87,69.37 81.09,69.37 81.21,69.49 81.21,69.73 81.09,69.84 80.87,69.84 80.76,69.96 80.76,70.19 80.87,70.31 81.09,70.31 81.21,70.43 81.21,70.66 81.09,70.78 80.87,70.78 80.76,70.89 80.76,71.13 80.87,71.24 81.09,71.24 81.21,71.36 81.21,71.59 81.09,71.71 80.87,71.71 80.76,71.83 80.76,72.06 80.87,72.18 81.09,72.18 81.21,72.3 81.21,72.53 81.09,72.65 80.87,72.65 80.76,72.76 80.76,73 80.87,73.11 81.09,73.11 81.21,73.23 81.21,73.46 81.09,73.58 80.87,73.58 80.76,73.7 80.76,73.93 80.87,74.05 81.09,74.05 81.21,74.17 81.21,84.71 85.9,89.4 85.9,89.61 86.23,89.94 86.23,92.93 v2(86.35,93.05)
  BOTTOM w0.076: UC1.AN69 92.98,96.38 92.73,96.38 92.51,96.46 92.38,96.46 92.15,96.39 92.05,96.39 92.04,96.39 92.03,96.39 92.01,96.39 91.89,96.45 91.49,96.45 91.29,96.24 89.5,96.24 88.79,95.53 87.44,95.53
  BOTTOM w0.102: 87.44,95.53 86.26,94.35 86.26,93.14 v2(86.35,93.05)
  BOTTOM w0.112: v2(80.06,54.93) 79.97,54.84 JDIMM1.16
DDR_A_D4: length 62.6
  IN3 w0.117: v2(77.23,58.74) 77.23,59.34 75.96,60.61 75.96,66.01 76.27,66.32 76.95,66.32 77.16,66.53 77.16,77.44 77.28,77.56 77.5,77.56 77.62,77.67 77.62,77.91 77.5,78.02 77.28,78.02 77.16,78.14 77.16,78.37 77.28,78.49 77.5,78.49 77.62,78.61 77.62,78.84 77.5,78.96 77.28,78.96 77.16,79.07 77.16,79.31 77.28,79.43 77.5,79.43 77.62,79.54 77.62,79.78 77.5,79.89 77.28,79.89 77.16,80.01 77.16,80.24 77.28,80.36 77.5,80.36 77.62,80.48 77.62,80.71 77.5,80.83 77.28,80.83 77.16,80.94 77.16,81.18 77.28,81.29 77.5,81.29 77.62,81.41 77.62,81.64 77.5,81.76 77.28,81.76 77.16,81.88 77.16,82.11 77.28,82.23 77.5,82.23 77.62,82.35 77.62,82.56 77.5,82.68 77.28,82.68 77.16,82.8 77.16,83.03 77.28,83.15 77.5,83.15 77.62,83.27 77.62,93.57 81.15,97.1 86.63,97.1 v2(87.15,96.58)
  BOTTOM w0.076: 88.47,97.01 88.78,97.33 90.07,97.33 90.4,97.65 91.51,97.65 91.63,97.78 91.87,97.78 91.99,97.74 92.11,97.68 92.29,97.51 UC1.AL70
  BOTTOM w0.102: 88.47,97.01 87.58,97.01 v2(87.15,96.58)
  BOTTOM w0.112: v2(77.23,58.74) 77.3,58.81 77.3,59.55 77.2,59.65 76.59,59.65 76.48,59.77 76.48,60.15 76.59,60.26 77.2,60.26 77.3,60.36 77.3,60.72 77.2,60.82 76.83,60.82 76.73,60.92 JDIMM1.3
DDR_A_D5: length 63.4
  IN3 w0.117: v2(77.23,56.2) 77.42,56.01 77.67,56.01 77.78,56.13 77.78,59.26 77.07,59.97 77.07,60.5 76.95,60.63 76.41,60.63 76.29,60.75 76.29,61.75 76.41,61.87 76.79,61.87 76.91,61.98 76.91,62.22 76.79,62.33 76.41,62.33 76.29,62.45 76.29,63.51 77.05,64.27 77.05,64.49 76.94,64.6 76.41,64.6 76.29,64.72 76.29,64.95 76.41,65.07 76.94,65.07 77.05,65.19 77.05,65.41 76.94,65.52 76.41,65.52 76.29,65.64 76.29,65.87 76.41,65.99 77.38,65.99 77.49,66.11 77.49,76.49 77.95,76.95 77.95,93.42 81.27,96.73 86.36,96.73 v2(86.51,96.58)
  BOTTOM w0.076: UC1.AL69 92.88,97.51 92.62,97.78 92.45,97.78 92.26,97.85 92.26,97.85 92.13,97.89 92.05,97.9 91.98,97.91 91.92,97.93 91.85,97.95 91.55,97.95 91.41,97.82 90.33,97.82 90,97.49 88.64,97.49 88.39,97.24 87.17,97.24
  BOTTOM w0.102: 87.17,97.24 v2(86.51,96.58)
  BOTTOM w0.112: JDIMM1.8 77.97,55.46 v2(77.23,56.2)
DDR_A_D6: length 61.1
  IN3 w0.117: v2(87.63,94.37) 86.52,94.37 85.56,93.41 85.56,92.69 85.56,92.69 85.56,90.22 85.23,89.89 85.23,89.68 81.08,85.53 80.28,85.53 80.16,85.41 80.16,85.18 80.28,85.06 80.43,85.06 80.55,84.94 80.55,84.72 80.43,84.61 80.21,84.61 80.09,84.49 80.09,84.23 80.21,84.12 80.43,84.12 80.55,84 80.55,83.77 80.43,83.65 80.21,83.65 80.09,83.53 80.09,83.3 80.21,83.18 80.43,83.18 80.55,83.06 80.55,82.83 80.43,82.71 80.21,82.71 80.09,82.6 80.09,82.36 80.21,82.25 80.43,82.25 80.55,82.13 80.55,81.9 80.43,81.78 80.21,81.78 80.09,81.66 80.09,81.43 80.21,81.31 80.43,81.31 80.55,81.2 80.55,80.96 80.43,80.84 80.21,80.84 80.09,80.73 80.09,80.49 80.21,80.38 80.43,80.38 80.55,80.26 80.55,80.03 80.43,79.91 80.21,79.91 80.09,79.79 80.09,79.56 80.21,79.44 80.43,79.44 80.55,79.33 80.55,79.09 80.43,78.98 80.21,78.98 80.09,78.86 80.09,62.57 80.24,62.41 80.65,62.41 80.77,62.3 80.77,62.06 80.65,61.95 80.24,61.95 80.13,61.83 80.13,61.61 80.24,61.49 80.65,61.49 80.77,61.38 80.77,61.14 80.65,61.03 80.24,61.03 80.13,60.91 80.13,60.68 80.24,60.56 80.65,60.56 80.77,60.44 80.77,60.21 80.65,60.09 80.26,60.09 80.13,59.96 80.13,59.73 80.24,59.61 80.65,59.61 80.77,59.49 80.77,59.27 80.65,59.16 80.59,59.16 80.48,59.04 80.48,58.81 80.59,58.69 80.65,58.69 80.77,58.57 80.77,57.35 80.65,57.24 80.29,57.24 v2(80.06,57.47)
  BOTTOM w0.076: UC1.AN70 92.17,95.92 91.43,95.92 91.42,95.91 89.75,95.91 88.97,95.13 87.86,95.13 87.63,94.91
  BOTTOM w0.102: 87.63,94.91 v2(87.63,94.37)
  BOTTOM w0.112: JDIMM1.21 81.22,58.63 v2(80.06,57.47)
DDR_A_D7: length 60.5
  IN3 w0.117: v2(86.71,93.51) 86.13,93.51 85.9,93.28 85.9,90.08 85.57,89.75 85.57,89.54 80.88,84.85 80.88,78.47 80.76,78.36 80.54,78.36 80.42,78.24 80.42,78.01 80.54,77.89 80.76,77.89 80.88,77.77 80.88,77.54 80.76,77.42 80.54,77.42 80.42,77.31 80.42,77.07 80.54,76.95 80.76,76.95 80.88,76.84 80.88,76.6 80.76,76.49 80.54,76.49 80.42,76.37 80.42,76.14 80.54,76.02 80.76,76.02 80.88,75.9 80.88,75.67 80.76,75.55 80.54,75.55 80.42,75.44 80.42,75.2 80.54,75.09 80.76,75.09 80.88,74.97 80.88,74.73 80.76,74.62 80.54,74.62 80.42,74.5 80.42,64.21 81.1,63.54 81.1,57.58 81.38,57.3 81.38,54.09 81.27,53.98 80.59,53.98 80.48,54.09 80.48,55.93 80.21,56.2 v2(80.06,56.2)
  BOTTOM w0.076: UC1.AN71 91.46,96.18 91.36,96.08 89.61,96.08 88.87,95.34 87.65,95.34 86.71,94.4 v2(86.71,93.51)
  BOTTOM w0.112: JDIMM1.20 80.97,54.69 80.9,54.76 80.6,54.76 80.5,54.86 80.5,55.07 80.6,55.17 81.42,55.17 81.53,55.28 81.53,55.44 81.42,55.55 80.59,55.55 80.52,55.62 80.52,56.02 80.34,56.2 v2(80.06,56.2)
DDR_A_D8: length 50.3
  IN3 w0.117: v2(82.35,58.21) 82.46,58.1 82.77,58.1 82.89,58.22 82.89,62.22 82.39,62.71 82.39,64.07 82.17,64.29 82.17,81.19 82.29,81.31 82.37,81.31 82.48,81.43 82.48,81.66 82.37,81.78 82.29,81.78 82.17,81.89 82.17,82.13 82.29,82.24 82.37,82.24 82.48,82.36 82.48,82.59 82.37,82.71 82.29,82.71 82.17,82.83 82.17,83.06 82.29,83.18 82.37,83.18 82.48,83.3 82.48,83.53 82.37,83.65 82.29,83.65 82.17,83.76 82.17,84.32 86.86,89.01 86.86,89.22 87.19,89.55 87.19,91.79 87.72,92.33 87.72,92.5 v2(87.55,92.67)
  BOTTOM w0.076: 88.82,94.45 89.05,94.45 90.02,95.42 91.63,95.42 91.63,95.42 92.02,95.42 92.29,95.15 UC1.AR70
  BOTTOM w0.102: v2(87.55,92.67) 87.55,93.18 88.82,94.45
  BOTTOM w0.112: JDIMM1.29 83.22,59.07 83.15,58.99 82.96,58.99 82.84,58.87 82.84,58.71 82.96,58.59 83.15,58.59 83.22,58.51 83.22,58.32 83.12,58.21 v2(82.35,58.21)
DDR_A_D9: length 51.5
  IN3 w0.117: v2(82.35,59.48) 82.55,59.69 82.55,60.22 82.44,60.34 82.17,60.34 82.06,60.46 82.06,60.69 82.17,60.81 82.44,60.81 82.55,60.93 82.55,61.16 82.44,61.28 82.17,61.28 82.06,61.39 82.06,61.63 82.17,61.74 82.44,61.74 82.55,61.86 82.55,62.08 82.06,62.57 82.06,63.93 81.84,64.16 81.84,64.59 81.72,64.7 81.5,64.7 81.38,64.82 81.38,65.05 81.5,65.17 81.72,65.17 81.84,65.29 81.84,65.52 81.72,65.64 81.5,65.64 81.38,65.75 81.38,65.99 81.5,66.1 81.72,66.1 81.84,66.22 81.84,84.45 86.53,89.14 86.53,89.36 86.85,89.68 86.85,92.05 v2(87.04,92.24)
  BOTTOM w0.076: UC1.AR68 93.81,95.12 93.81,95.24 93.72,95.33 93.59,95.33 93.48,95.21 93.33,95.21 93.21,95.34 93.21,95.35 93.18,95.38 93.09,95.39 93.03,95.38 92.92,95.33 92.86,95.32 92.71,95.35 92.43,95.59 91.56,95.59 91.56,95.58 89.95,95.58 89.02,94.65 88.64,94.65
  BOTTOM w0.102: v2(87.04,92.24) 87.04,93.05 88.64,94.65
  BOTTOM w0.112: JDIMM1.25 82.22,60.9 82.33,60.8 82.79,60.8 82.88,60.7 82.88,60.51 82.8,60.43 81.9,60.43 81.83,60.36 81.83,59.56 81.92,59.48 v2(82.35,59.48)
DDR_A_D10: length 48.4
  IN3 w0.117: v2(84.89,59.48) 85.31,59.48 85.49,59.66 85.49,60.02 85.37,60.13 85.14,60.13 85.03,60.25 85.03,60.48 85.14,60.6 85.37,60.6 85.49,60.72 85.49,60.95 85.37,61.07 85.16,61.07 85.04,61.18 85.04,61.42 85.16,61.53 85.37,61.53 85.49,61.65 85.49,61.89 85.37,62 85.14,62 85.03,62.12 85.03,62.35 85.14,62.47 85.37,62.47 85.49,62.59 85.49,63.59 84.63,64.45 84.63,65.16 84.51,65.27 84.44,65.27 84.33,65.39 84.33,65.62 84.44,65.74 84.51,65.74 84.63,65.86 84.63,66.09 84.51,66.21 84.44,66.21 84.33,66.33 84.33,66.56 84.44,66.68 84.51,66.68 84.63,66.79 84.63,67.03 84.51,67.14 84.44,67.14 84.33,67.26 84.33,67.49 84.44,67.61 84.51,67.61 84.63,67.73 84.63,67.96 84.51,68.08 84.44,68.08 84.33,68.2 84.33,68.43 84.44,68.55 84.51,68.55 84.63,68.66 84.63,68.88 84.51,69 84.42,69 84.3,69.11 84.3,69.35 84.42,69.47 84.51,69.47 84.63,69.58 84.63,83.75 88.19,87.32 89.21,88.33 89.21,88.38 89.92,89.09 89.92,89.99 89.45,90.45 89.45,90.6 v2(88.85,91.2)
  BOTTOM w0.076: v2(88.85,91.2) 88.85,92.05 90.57,93.76 91.72,93.76 UC1.AU71
  BOTTOM w0.112: JDIMM1.37 85.22,60.71 85.3,60.63 85.78,60.63 85.89,60.51 85.89,60.34 85.78,60.22 84.38,60.22 84.25,60.1 84.25,59.61 84.38,59.48 v2(84.89,59.48)
DDR_A_D11: length 50.4
  IN3 w0.117: v2(82.35,55.67) 82.98,56.3 82.98,56.72 83.13,56.87 83.13,57.38 83.55,57.8 83.55,62.49 83.06,62.99 83.06,64.35 82.83,64.57 82.83,75.74 82.95,75.85 83.04,75.85 83.16,75.97 83.16,76.2 83.04,76.32 82.95,76.32 82.83,76.44 82.83,76.67 82.95,76.79 83.04,76.79 83.16,76.9 83.16,84.19
  IN3 w0.119: v2(87.96,89.22) 87.91,89.22 87.52,88.83 87.52,88.73 83.16,84.36 83.16,84.19
  BOTTOM w0.076: UC1.AU68 93.74,94.2 93.72,94.59 93.63,94.69 93.39,94.83 93.16,94.74 93.07,94.74 92.68,94.76 92.52,94.7 92.37,94.7 92.16,94.77 92.04,94.77 91.96,94.74 91.93,94.72 91.51,94.72 91.39,94.84 90.85,94.84 87.65,91.64 87.63,91.64 87.52,91.53
  BOTTOM w0.107: 87.52,91.53 87.21,91.22 87.21,89.85 87.85,89.22 v2(87.96,89.22)
  BOTTOM w0.112: v2(82.35,55.67) 82.35,54.99 81.97,54.62 JDIMM1.24
DDR_A_D12: length 48.8
  IN3 w0.117: v2(82.35,56.94) 82.79,57.38 82.79,57.53 83.22,57.96 83.22,62.35 82.72,62.85 82.72,64.21 82.5,64.43 82.5,77.09 82.62,77.2 82.71,77.2 82.82,77.32 82.82,77.53 82.71,77.65 82.64,77.65 82.5,77.79 82.5,78.02 82.62,78.14 82.71,78.14 82.82,78.26 82.82,78.49 82.71,78.61 82.62,78.61 82.5,78.72 82.5,78.96 82.62,79.07 82.71,79.07 82.82,79.19 82.82,79.42 82.71,79.54 82.62,79.54 82.5,79.66 82.5,79.88 82.62,79.99 82.71,79.99 82.82,80.11 82.82,80.34 82.71,80.46 82.67,80.46 82.55,80.58 82.55,80.8 82.67,80.91 82.71,80.91 82.82,81.03 82.82,82.2 82.82,82.2 82.82,84.5 87.19,88.87 87.19,89.08 87.52,89.41 87.52,91.66 88.64,92.78 v2(88.64,93.48)
  BOTTOM w0.076: UC1.AR71 91.69,95.25 90.16,95.25 89.13,94.22
  BOTTOM w0.102: 89.13,94.22 88.97,94.22 88.64,93.89 v2(88.64,93.48)
  BOTTOM w0.112: v2(82.35,56.94) 82.79,56.5 82.79,55.18 82.97,54.99 JDIMM1.28
DDR_A_D13: length 49.5
  IN3 w0.117: v2(84.89,55.67) 85.84,55.67 86.49,56.33 86.49,64 85.62,64.87 85.62,81.5 86.01,81.89 86.01,83.72 88.61,86.32 90.21,87.92 90.21,87.97 90.92,88.68 90.92,90.23 91.45,90.77 91.45,91.96 91.07,92.34 90.83,92.34 89.7,93.47 v2(89.7,94.23)
  BOTTOM w0.076: UC1.AR69 92.98,94.95 92.73,94.95 92.51,94.88 92.38,94.88 92.15,94.94 92.05,94.94 92.04,94.95 92.03,94.94 92.01,94.94 91.89,94.89 91.63,94.89 91.43,95.09 90.55,95.09 v2(89.7,94.23)
  BOTTOM w0.112: v2(84.89,55.67) 85.34,55.22 85.34,54.75 85.47,54.62 JDIMM1.38
DDR_A_D14: length 48.6
  IN3 w0.117: v2(89.32,91.58) 89.32,91.24 89.83,90.72 89.83,90.56 89.83,90.55 90.25,90.12 90.25,88.95 89.54,88.25 89.54,88.19 88.33,86.98 84.96,83.61 84.96,64.59 85.82,63.73 85.82,59.31 85.71,59.2 85.48,59.2 85.37,59.08 85.37,58.85 85.48,58.73 85.71,58.73 85.82,58.61 85.82,57.58 85.71,57.47 85.42,57.47 85.3,57.58 85.3,57.94 85.03,58.21 v2(84.89,58.21)
  BOTTOM w0.076: v2(89.32,91.58) 89.32,92.25 90.64,93.57 92.18,93.57 UC1.AU70
  BOTTOM w0.112: v2(84.89,58.21) 85.76,58.21 85.88,58.32 85.88,58.53 85.72,58.68 85.72,58.92 85.84,59.04 86.12,59.04 86.22,59.14 JDIMM1.41
DDR_A_D15: length 49.2
  IN3 w0.117: v2(84.89,56.94) 85.03,56.94 85.34,56.63 85.34,56.31 85.54,56.11 85.8,56.11 86.16,56.46 86.16,63.86 85.29,64.73 85.29,83.47 88.47,86.65 89.88,88.06 89.88,88.11 90.58,88.82 90.58,90.26 90.16,90.68 90.16,92.42 v2(90.14,92.44)
  BOTTOM w0.076: UC1.AU69 92.84,93.83 92.42,93.41 90.93,93.41 90.14,92.62 v2(90.14,92.44)
  BOTTOM w0.112: JDIMM1.42 86.47,54.79 86.37,54.89 86.18,54.89 86.08,54.99 86.08,55.19 86.18,55.29 86.37,55.29 86.47,55.4 86.47,56.16 85.69,56.94 v2(84.89,56.94)
DDR_A_D16: length 45.4
  IN3 w0.117: v2(91.21,86.31) 90.42,86.31 89.14,85.03 87.43,83.31 87.43,75.35 86.91,74.84 86.91,65.4 88.11,64.21 88.11,60.71 87.92,60.53 87.92,57.05 v2(87.17,56.31)
  BOTTOM w0.076: v2(91.21,86.31) 91.72,86.82 91.72,88.17 92.65,89.1 94.74,89.1 95.48,89.84 95.48,90.62 UC1.BB65
  BOTTOM w0.112: v2(87.17,56.31) 88.26,56.31 88.37,56.2 88.37,55.93 88.25,55.82 87.82,55.82 87.72,55.72 87.72,55.51 87.82,55.41 88.35,55.41 88.47,55.28 JDIMM1.50
DDR_A_D17: length 46.7
  IN3 w0.117: v2(87.17,55.04) 87.38,55.04 88.25,55.91 88.25,60.39 88.44,60.57 88.44,64.36 87.25,65.55 87.25,74.7 87.36,74.82 87.5,74.82 87.76,75.07 87.76,83.17 88.27,83.68 90.48,85.89 91.46,85.89 91.91,86.34 91.91,87.16 v2(92.7,87.95)
  BOTTOM w0.076: UC1.AW65 96.25,92.64 96.44,92.45 96.44,91.85 96.47,91.81 96.47,91.58 96.42,91.42 96.42,91.28 96.48,91.06 96.48,90.94 96.44,90.83 96.44,90.45 96.62,90.27 96.62,90.02 94.98,88.39 93.64,88.39 93.19,87.95 v2(92.7,87.95)
  BOTTOM w0.112: v2(87.17,55.04) 87.47,54.74 JDIMM1.46
DDR_A_D18: length 48.1
  IN3 w0.117: v2(92.7,84.29) 92.63,84.22 92.63,82.64 92.16,82.17 90.23,80.24 90.23,66.08 90.94,65.37 90.94,64.61 91.15,64.4 91.15,57.11 91.47,56.79 91.47,54.06 91.21,53.81 89.81,53.81 89.56,54.06 89.56,54.8 89.8,55.04 v2(90.02,55.04)
  BOTTOM w0.076: v2(92.7,84.29) 92.71,84.29 93.74,85.32 93.74,87.29 94.19,87.73 95.33,87.73 97.3,89.7 97.3,91.34 97.08,91.56 97.06,91.7 97.06,91.83 97.09,91.95 97.09,92.12 97.08,92.13 97.08,92.13 96.77,92.44 UC1.AW63
  BOTTOM w0.102: JDIMM1.58 90.47,54.95 90.39,55.04 v2(90.02,55.04)
DDR_A_D19: length 47.3
  IN3 w0.117: v2(90.02,58.85) 90.09,58.92 90.09,60.15 89.91,60.33 89.91,60.56 90.03,60.68 90.03,60.68 90.15,60.8 90.15,61.03 90.03,61.15 90.03,61.15 89.91,61.26 89.91,61.5 90.03,61.61 90.03,61.61 90.15,61.73 90.15,61.96 90.03,62.08 90.03,62.08 89.91,62.2 89.91,62.43 90.03,62.55 90.03,62.55 90.15,62.67 90.15,63.91 89.94,64.12 89.94,64.96 89.68,65.21 89.66,65.21 88.72,66.16 88.72,68.15 88.83,68.26 89.11,68.26 89.23,68.38 89.23,68.61 89.11,68.73 88.83,68.73 88.72,68.85 88.72,69.08 88.83,69.2 89.11,69.2 89.23,69.31 89.23,69.53 89.11,69.65 88.84,69.65 88.72,69.77 88.72,70 88.84,70.12 89.11,70.12 89.23,70.23 89.23,70.47 89.11,70.58 88.84,70.58 88.72,70.7 88.72,70.94 88.84,71.05 89.11,71.05 89.23,71.17 89.23,71.4 89.11,71.52 88.84,71.52 88.72,71.64 88.72,71.87 88.84,71.99 89.11,71.99 89.23,72.1 89.23,81.54 89.54,81.85 90.43,81.85 91.62,83.04 91.62,85.58 92.24,86.21 92.24,86.88 v2(92.7,87.34)
  BOTTOM w0.076: v2(92.7,87.34) 92.84,87.34 93.73,88.23 95.05,88.23 96.78,89.96 96.78,90.37 96.6,90.55 96.6,90.79 96.66,90.91 96.66,91.05 96.59,91.28 96.59,91.41 96.67,91.63 96.67,91.89 UC1.AY63
  BOTTOM w0.112: JDIMM1.59 90.72,61.13 90.61,61.02 90.57,61.02 90.21,60.66 90.21,60.5 90.32,60.39 90.54,60.39 90.65,60.28 90.65,59.97 90.54,59.85 90.3,59.85 90.18,59.74 90.18,59.43 90.3,59.32 90.56,59.32 90.68,59.21 90.68,58.91 90.56,58.8 90.26,58.8 90.21,58.85 v2(90.02,58.85)
DDR_A_D20: length 46.7
  IN3 w0.117: v2(87.17,57.58) 87.59,57.99 87.59,61.19 87.77,61.37 87.77,64.07 86.58,65.26 86.58,74.98 86.94,75.34 86.94,75.65 86.83,75.77 86.7,75.77 86.58,75.89 86.58,76.12 86.7,76.24 86.98,76.24 87.09,76.35 87.09,76.59 86.98,76.7 86.7,76.7 86.58,76.82 86.58,77.05 86.7,77.17 86.98,77.17 87.09,77.29 87.09,77.52 86.98,77.64 86.7,77.64 86.58,77.75 86.58,77.99 86.7,78.11 86.98,78.11 87.09,78.22 87.09,83.45 89,85.36 90.78,87.13 v2(91.18,87.13)
  BOTTOM w0.076: UC1.BA65 95.54,91.19 95.4,91.05 95.4,91.04 95.39,91.04 95.29,90.82 95.29,89.88 94.67,89.27 92.53,89.27 91.54,88.27 91.54,87.49 v2(91.18,87.13)
  BOTTOM w0.112: JDIMM1.49 88.22,61.06 88.44,60.85 88.44,60.31 87.59,59.46 87.59,57.99 v2(87.17,57.58)
DDR_A_D21: length 47.1
  IN3 w0.117: v2(91.16,87.77) 90.94,87.77 88.87,85.69 86.76,83.59 86.76,82.4 86.64,82.28 86.64,81.96 86.76,81.83 86.76,81.5 86.62,81.36 86.37,81.36 86.25,81.24 86.25,81.01 86.37,80.89 86.64,80.89 86.76,80.77 86.76,80.54 86.64,80.42 86.37,80.42 86.25,80.31 86.25,80.07 86.37,79.96 86.64,79.96 86.76,79.84 86.76,79.61 86.64,79.49 86.37,79.49 86.25,79.37 86.25,79.14 86.37,79.02 86.64,79.02 86.76,78.91 86.76,78.67 86.64,78.55 86.37,78.55 86.25,78.44 86.25,65.13 87.44,63.94 87.44,62.35 87.17,62.09 v2(87.17,58.85)
  BOTTOM w0.076: v2(91.16,87.77) 91.16,88.17 92.44,89.46 94.6,89.46 95.12,89.98 95.12,90.85 95.15,90.92 95.15,92.14 95.23,92.21 95.47,92.21 95.54,92.14 UC1.AY65
  BOTTOM w0.112: v2(87.17,58.85) 87.17,59.54 87.06,59.65 86.93,59.65 86.82,59.76 86.82,60.12 86.93,60.23 87.9,60.23 88.01,60.35 88.01,60.66 87.9,60.77 87.33,60.77 87.22,60.87 JDIMM1.45
DDR_A_D22: length 47
  IN3 w0.117: v2(92.7,85.51) 92.28,85.09 92.28,82.76 89.89,80.37 89.89,65.94 90.61,65.23 90.61,64.4 90.81,64.19 90.81,56.97 91.13,56.65 91.13,55.5 91.02,55.38 90.64,55.38 90.52,55.5 90.52,56.09 90.31,56.31 v2(90.02,56.31)
  BOTTOM w0.076: v2(92.7,85.51) 93.35,86.16 93.35,87.15 94.1,87.9 95.23,87.9 97.13,89.8 97.13,90.86 96.87,91.12 UC1.BA63
  BOTTOM w0.112: JDIMM1.62 91.47,55.31 91.37,55.41 90.85,55.41 90.73,55.53 90.73,55.7 90.85,55.82 91.26,55.82 91.36,55.92 91.36,56.19 91.24,56.31 v2(90.02,56.31)
DDR_A_D23: length 45.6
  IN3 w0.117: v2(90.02,57.58) 90.02,57.49 90.18,57.33 90.36,57.33 90.48,57.45 90.48,64.05 90.27,64.26 90.27,65.09 89.56,65.81 89.56,66.29 89.44,66.41 89.17,66.41 89.05,66.53 89.05,66.76 89.17,66.88 89.44,66.88 89.56,67 89.56,67.23 89.44,67.35 89.17,67.35 89.05,67.46 89.05,67.7 89.17,67.81 89.44,67.81 89.56,67.93 89.56,81.4 89.68,81.52 90.57,81.52 91.95,82.9 91.95,85.44 92.62,86.12 v2(92.7,86.12)
  BOTTOM w0.076: UC1.BB63 96.95,90.61 96.95,89.88 95.13,88.06 93.8,88.06 93.19,87.45 93.19,86.23 92.96,86 92.81,86 v2(92.7,86.12)
  BOTTOM w0.112: JDIMM1.63 91.72,61.11 91.17,60.55 91.17,58.68 90.07,57.58 v2(90.02,57.58)
DDR_A_D24: length 44.3
  IN3 w0.117: v2(94.32,86.04) 93.9,85.62 93.9,85.29 93.59,84.97 93.59,82.24 91.18,79.84 91.18,66.48 91.89,65.77 91.9,65.77 91.9,65.01 92.1,64.8 92.1,61.97 92.22,61.85 92.81,61.85 92.93,61.73 92.93,61.5 92.81,61.38 92.22,61.38 92.1,61.27 92.1,61.05 92.22,60.93 92.81,60.93 92.93,60.82 92.93,60.58 92.81,60.46 92.22,60.46 92.1,60.35 92.1,60.13 92.23,60.01 92.74,60.01 92.9,59.85 92.9,59.63 92.72,59.44 v2(92.19,59.44)
  BOTTOM w0.076: v2(94.32,86.04) 94.65,86.04 94.92,86.31 94.92,86.81 97.63,89.52 97.63,90.85 97.9,91.11 UC1.BA61
  BOTTOM w0.112: v2(92.19,59.44) 92.41,59.22 94.09,59.22 94.33,59.47 94.33,60.41 93.72,61.02 JDIMM1.71
DDR_A_D25: length 45.4
  IN3 w0.117: v2(92.2,56.32) 92.09,56.43 92.09,57.05 91.77,57.37 91.77,64.66 91.56,64.87 91.56,65.63 90.85,66.34 90.85,79.98 93.25,82.38 93.25,85.12 93.56,85.43 93.56,85.75 93.91,86.1 93.91,86.93 v2(94.32,87.34)
  BOTTOM w0.076: UC1.AW61 98,92.51 97.68,92.19 97.68,91.95 97.7,91.83 97.7,91.61 97.7,91.61 97.7,91.6 97.46,91.37 97.46,89.61 95.19,87.34 v2(94.32,87.34)
  BOTTOM w0.112: JDIMM1.70 93.47,54.95 93.59,55.06 93.88,55.06 93.99,55.18 93.99,55.4 93.88,55.51 93.59,55.51 93.47,55.62 93.47,55.99 92.69,56.78 92.41,56.78 92.2,56.57 v2(92.2,56.32)
DDR_A_D26: length 44
  IN3 w0.117: v2(96.25,84.28) 96.3,84.28 96.87,83.7 96.87,81.45 94.36,78.93 94.36,67.77 95.05,67.08 95.05,66.42 97.06,64.41 97.06,64.07 97.18,63.95 97.52,63.95 97.64,63.83 97.64,63.6 97.52,63.48 97.18,63.48 97.06,63.36 97.06,63.13 97.18,63.01 97.34,63.01 97.46,62.9 97.46,62.66 97.34,62.55 97.24,62.55 97.12,62.43 97.12,57.57 96.94,57.39 96.49,57.39 v2(96.27,57.61)
  BOTTOM w0.076: UC1.BB59 99.32,90.58 99.32,89.88 99.16,89.71 99.16,89.3 v1(98.51,88.66) 97.17,87.31 97.17,85.2 v2(96.25,84.28)
  BOTTOM w0.112: v2(96.27,57.61) 95.4,58.48 95.4,60.15 95.72,60.47 JDIMM1.79
DDR_A_D27: length 45.8
  IN3 w0.117: v2(96.25,85.58) 96.25,85.57 95.82,85.14 95.82,81.27 93.36,78.81 93.36,67.35 94.05,66.67 94.05,65.9 95.09,64.87 95.09,56.38 95.2,56.27 95.64,56.27 95.76,56.15 95.76,55.91 95.64,55.8 95.2,55.8 95.09,55.68 95.09,54.76 95.2,54.64 95.85,54.64 v2(96.27,55.07)
  BOTTOM w0.076: UC1.AW59 98.52,92.64 98.33,92.45 98.33,92.17 98.37,92.14 98.37,91.92 98.29,91.82 98.29,91.57 98.34,91.44 98.34,91.21 98.33,91.2 98.33,91.2 98.33,91.2 98.29,91.11 98.29,90.91 98.33,90.82 98.33,90.46 98.13,90.26 98.13,89.32 95.86,87.05 95.86,85.97 v2(96.25,85.58)
  BOTTOM w0.112: JDIMM1.80 95.97,54.77 v2(96.27,55.07)
DDR_A_D28: length 44
  IN3 w0.117: v2(94.32,85.36) 94.32,85.22 93.92,84.83 93.92,82.1 91.54,79.72 91.54,66.6 92.23,65.91 92.23,65.14 92.74,64.63 92.74,64.47 92.62,64.35 92.55,64.35 92.44,64.23 92.44,64 92.55,63.88 92.62,63.88 92.74,63.77 92.74,63.48 92.62,63.36 92.55,63.36 92.44,63.25 92.44,63.05 92.66,62.83 92.66,62.66 92.44,62.44 92.44,62.27 92.52,62.18 93.15,62.18 93.26,62.07 93.26,59.36 93.15,59.24 92.99,59.24 92.65,58.91 92.65,58.19 92.53,58.07 92.36,58.07 v2(92.23,58.2)
  BOTTOM w0.076: v2(94.32,85.36) 94.81,84.87 94.98,84.87 95.03,84.92 v1(95.03,85.79) 95.03,85.86 95.12,85.95 95.12,86.78 97.8,89.45 97.8,90.58 UC1.BB61
  BOTTOM w0.112: JDIMM1.67 92.72,60.7 92.94,60.49 92.94,59.97 92.83,59.86 91.92,59.86 91.77,59.71 91.77,58.65 v2(92.23,58.2)
DDR_A_D29: length 44.8
  IN3 w0.117: v2(94.33,84.05) 94.33,82.05 91.87,79.59 91.87,66.74 92.56,66.05 92.56,65.29 93.07,64.78 93.07,62.84 93.19,62.73 93.47,62.73 93.6,62.6 93.6,59.01 93.47,58.89 93.1,58.89 92.98,58.77 92.98,56.48 93.7,55.77 93.7,55.22 93.58,55.1 v2(92.19,55.1)
  BOTTOM w0.076: v2(94.33,84.05) 95.41,84.05 95.59,84.23 95.59,87.01 97.96,89.38 97.96,90.33 98.16,90.53 98.16,90.79 98.13,90.88 98.13,90.89 98.13,91.14 98.16,91.23 98.16,91.44 98.13,91.52 98.13,91.52 98.1,91.62 98.1,91.89 UC1.AY61
  BOTTOM w0.102: v2(92.19,55.1) 92.47,54.81 JDIMM1.66
DDR_A_D30: length 45.2
  IN3 w0.117: v2(96.27,58.88) 96.61,58.88 96.73,58.99 96.73,61.24 96.61,61.36 95.87,61.36 95.75,61.47 95.75,61.71 95.87,61.82 96.61,61.82 96.73,61.94 96.73,62.17 96.61,62.29 96.21,62.29 96.1,62.41 96.1,62.64 96.21,62.76 96.61,62.76 96.73,62.88 96.73,63.29 96.61,63.4 96.51,63.4 96.39,63.52 96.39,63.75 96.51,63.87 96.61,63.87 96.73,63.99 96.73,64.27 94.72,66.28 94.72,66.94 94.03,67.63 94.03,78.89 96.67,81.53 96.67,83.21 v2(96.25,83.63)
  BOTTOM w0.076: UC1.BA59 99.43,90.93 99.49,90.78 99.49,89.24 97.36,87.11 97.36,83.91 97.08,83.63 v2(96.25,83.63)
  BOTTOM w0.112: JDIMM1.83 96.72,61.9 96.72,60.85 96.83,60.74 97.58,60.74 97.7,60.63 97.7,60.46 97.58,60.34 96.69,60.34 96.57,60.22 96.57,59.63 96.27,59.33 v2(96.27,58.88)
DDR_A_D31: length 45.8
  IN3 w0.117: v2(96.25,82.34) 96.46,82.13 96.46,81.62 93.7,78.85 93.7,67.49 94.39,66.8 94.39,66.14 95.42,65.11 95.42,61.02 95.54,60.91 96.17,60.91 96.29,60.79 96.29,60.56 96.17,60.44 95.54,60.44 95.42,60.32 95.42,60.09 95.54,59.97 96.17,59.97 96.29,59.86 96.29,59.62 96.17,59.51 95.54,59.51 95.42,59.39 95.42,56.73 95.55,56.6 95.78,56.6 96.04,56.34 v2(96.27,56.34)
  BOTTOM w0.076: v2(96.25,82.34) 96.53,82.34 97.56,83.37 97.56,87.07 99.65,89.17 99.65,90.82 99.62,90.89 99.49,91.32 99.49,91.52 99.22,91.78 UC1.AY59
  BOTTOM w0.112: v2(96.27,56.34) 96.97,55.63 JDIMM1.84
DDR_A_D32: length 48.2
  IN3 w0.076: 112.59,78.6 110.98,80.21 v2(110.98,82.13)
  IN3 w0.117: 112.59,78.6 113.05,78.14 113.05,73.45 118.16,68.34 120.27,68.34 120.46,68.16 120.46,67.79 120.62,67.63 120.99,67.63 121.29,67.33 121.29,66.93 121.4,66.82 121.8,66.82 121.92,66.7 121.92,66.47 121.8,66.35 121.4,66.35 121.29,66.23 121.29,66 121.4,65.88 122.41,65.88 122.53,65.76 122.53,65.52 122.41,65.41 121.4,65.41 121.29,65.29 121.29,58.53 121.41,58.41 121.66,58.41 v2(122.04,58.78)
  BOTTOM w0.076: UC1.AY39 110.27,91.78 110,91.52 110,91.23 109.9,90.98 109.9,90.96 109.83,90.83 109.83,90.43 109.91,90.35 109.91,89.68 109.43,89.2 109.43,84.78 109.59,84.62
  BOTTOM w0.112: JDIMM1.169 120.22,61.9 120.22,60.99 121.41,59.8 121.41,59.41 v2(122.04,58.78) ; v2(110.98,82.13) 109.59,83.51 109.59,84.62
DDR_A_D33: length 46
  IN3 w0.076: v2(110.98,88.09) 110.45,87.56 110.45,80.16 112.39,78.22 112.39,77.35
  IN3 w0.117: 112.39,77.35 112.39,73.17 117.91,67.65 118.48,67.65 119.22,66.91 120.05,66.91 120.62,66.34 120.62,57.66 v2(122.04,56.24)
  BOTTOM w0.076: UC1.AW39 110.92,92.64 111.21,92.35 111.21,91.85 111.19,91.56 111.17,91.5 111.17,91.18 111.19,91.11 111.2,90.89 111.17,90.78 111.17,90.44 111.36,90.25 111.36,88.48 v2(110.98,88.09)
  BOTTOM w0.112: JDIMM1.174 121.47,55.68 v2(122.04,56.24)
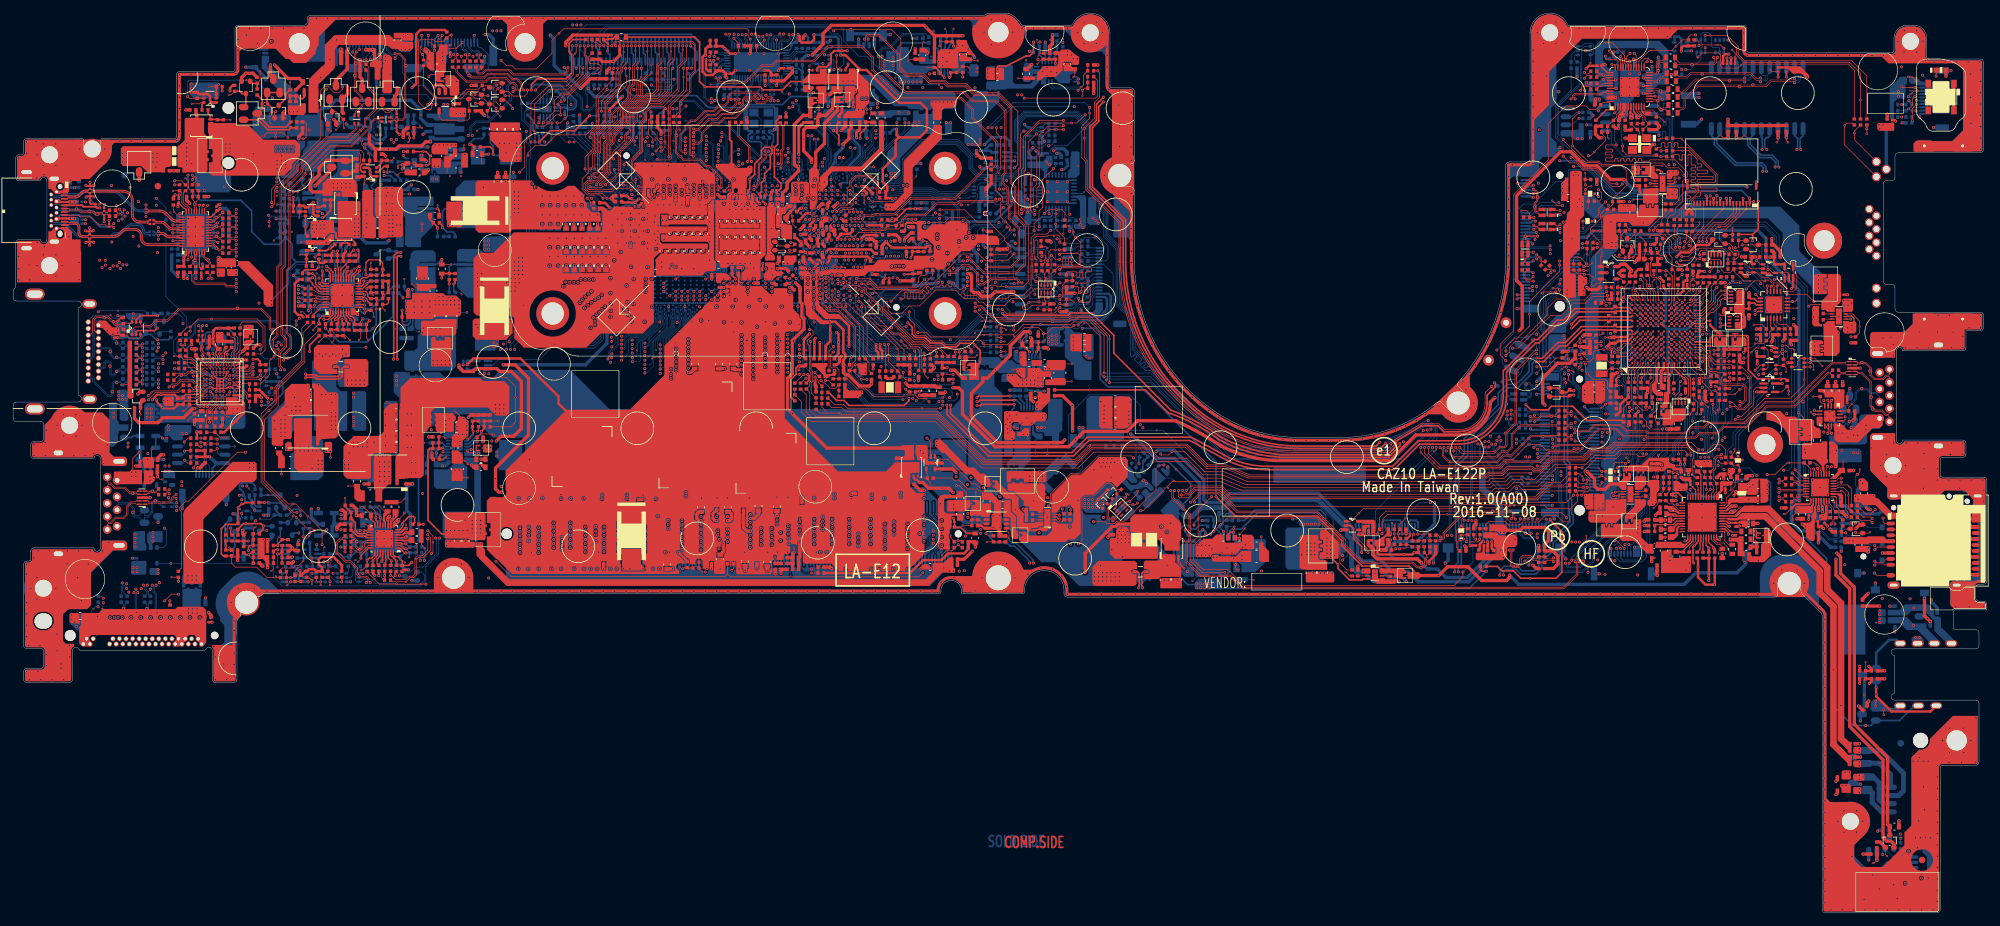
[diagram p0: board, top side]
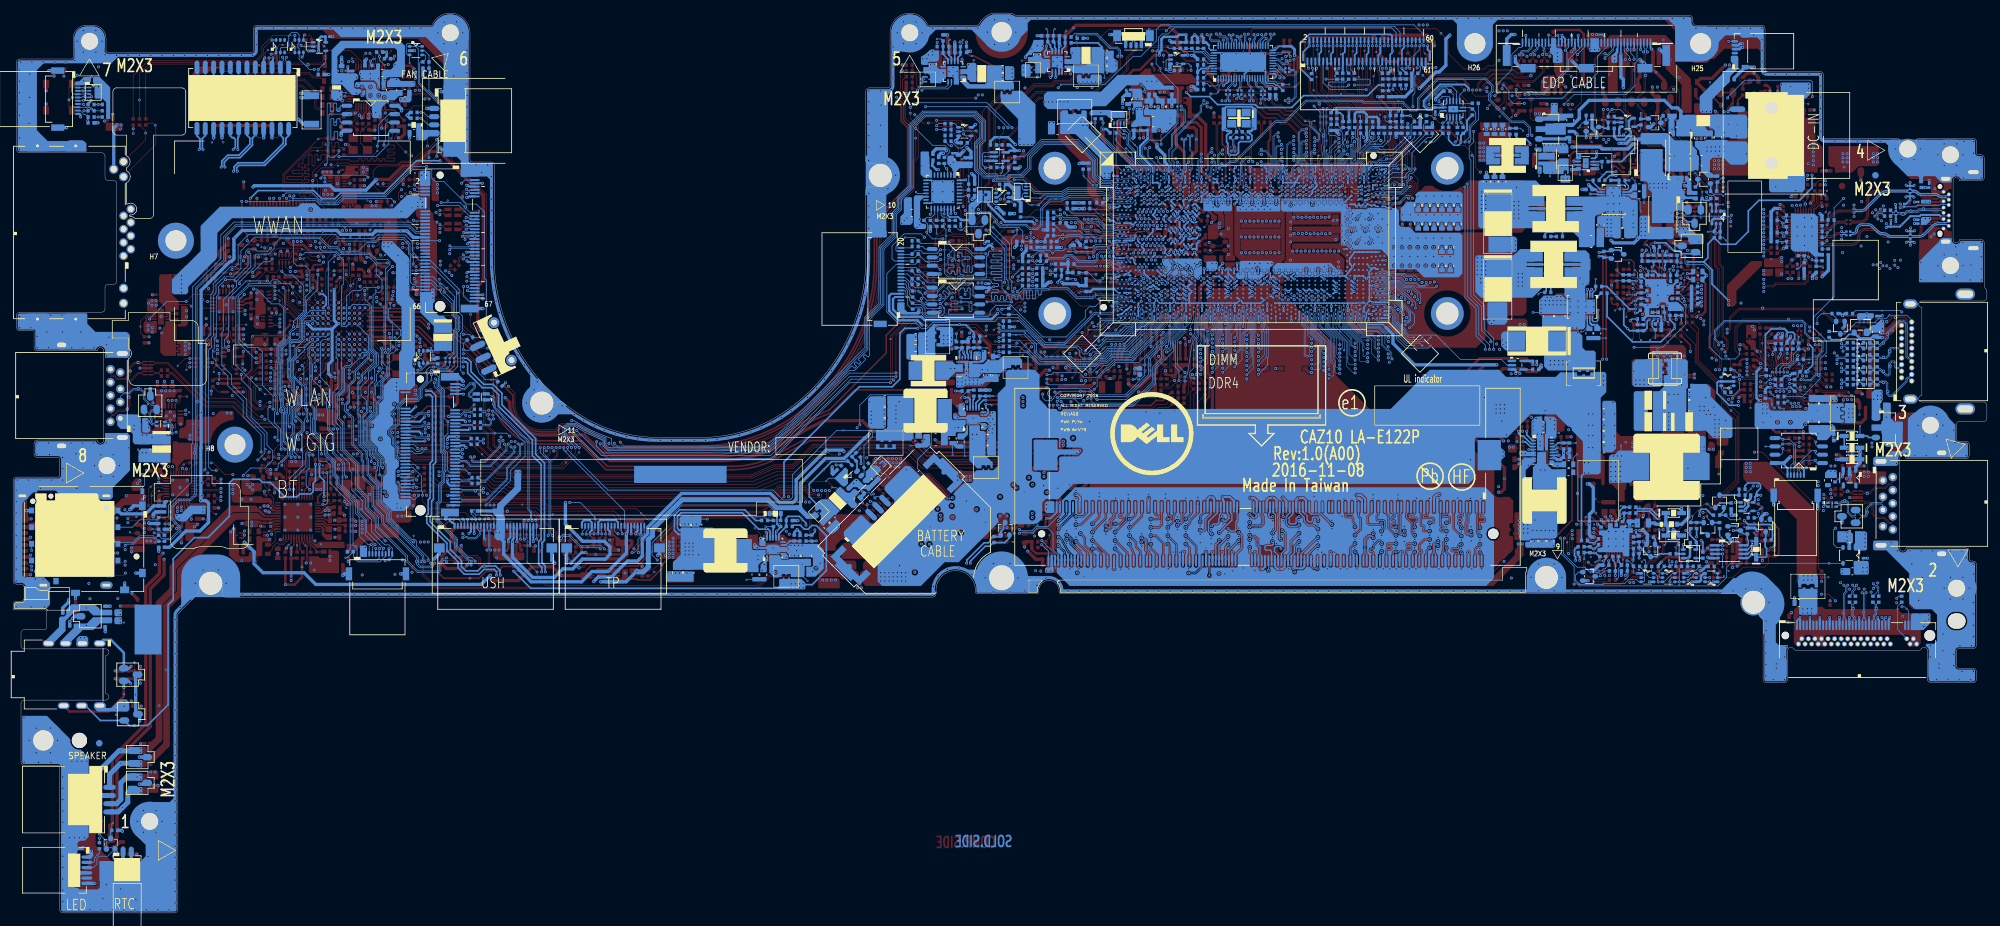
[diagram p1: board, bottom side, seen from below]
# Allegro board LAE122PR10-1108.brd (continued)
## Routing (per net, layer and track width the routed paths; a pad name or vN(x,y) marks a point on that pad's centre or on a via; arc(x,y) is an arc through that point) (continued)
DDR_A_D34: length 47.7
  IN3 w0.076: 113.8,78.87 112.06,80.61 112.06,87.74 111.97,87.83 111.37,87.83 v2(110.98,87.44)
  IN3 w0.117: v2(124.78,60.05) 124.78,60.82 124.98,61.01 124.98,61.3 124.8,61.47 124.32,61.47 124.2,61.59 124.2,61.85 124.32,61.96 124.86,61.96 124.98,62.08 124.98,62.37 124.86,62.48 124.47,62.48 124.35,62.6 124.35,64.68 124.47,64.8 124.87,64.8 124.98,64.91 124.98,65.15 124.87,65.27 124.47,65.27 124.35,65.38 124.35,65.62 124.47,65.73 125.01,65.73 125.13,65.85 125.13,66.08 125.01,66.2 124.47,66.2 124.35,66.32 124.35,66.85 121.04,70.16 118.97,70.16 114.88,74.26 114.88,77.51 114.76,77.63 114.57,77.63 114.42,77.78 114.42,77.92 114.57,78.07 114.7,78.07 114.83,78.19 114.83,78.37 114.48,78.73 113.94,78.73 113.8,78.87
  BOTTOM w0.076: v2(110.98,87.44) 111.53,87.99 111.53,90.32 111.34,90.51 111.34,90.76 111.38,90.96 111.38,91.08 111.34,91.24 111.34,91.48 111.39,91.63 111.39,91.89 UC1.AY37
  BOTTOM w0.112: v2(124.78,60.05) 124.38,60.05 124.27,60.17 124.27,60.5 124.38,60.62 124.61,60.62 124.72,60.73 JDIMM1.187
DDR_A_D35: length 48.8
  IN3 w0.076: v2(112.75,84.19) 112.32,84.19 112.23,84.1 112.23,81.01 112.25,81.01
  IN3 w0.117: 112.25,81.01 112.93,80.33 113.39,80.33 113.88,79.83 113.88,79.67 113.71,79.5 113.71,79.34 113.88,79.17 114.04,79.17 114.21,79.34 114.38,79.34 115.21,78.51 115.21,74.41 119.11,70.51 121.18,70.51 125.46,66.23 125.46,65.96 125.58,65.85 125.79,65.85 125.9,65.73 125.9,65.44 125.73,65.26 125.43,65.26 125.32,65.15 125.32,64.85 125.31,64.84 125.31,64.41 125.16,64.26 124.79,64.26 124.69,64.16 124.69,62.95 124.82,62.81 125.18,62.81 125.31,62.69 125.31,61.94 125.43,61.81 125.55,61.81 125.7,61.66 125.7,61.26 125.56,61.12 125.37,61.12 125.31,61.05 125.31,60.87 125.12,60.68 125.12,60.3 125.31,60.11 125.31,58.9 125.19,58.78 v2(124.78,58.78)
  BOTTOM w0.076: UC1.AW37 111.49,92.42 111.8,92.11 111.8,91.56 112.02,91.34 112.02,90.32 112.02,84.92 v2(112.75,84.19)
  BOTTOM w0.112: JDIMM1.183 123.72,60.76 123.94,60.54 123.94,59.63 v2(124.78,58.78)
DDR_A_D36: length 46.1
  IN3 w0.076: 111.38,80.15 111.25,80.27 111.25,80.78 111.43,80.96 111.43,81.34 111.38,81.39 111.25,81.39 111.17,81.47 111.17,81.65 111.25,81.72 111.35,81.72 111.43,81.8 111.43,84.11 111.35,84.19 v2(110.98,84.19)
  IN3 w0.117: 111.38,80.15 113.38,78.14 113.38,73.62 118.33,68.67 120.41,68.67 122.25,66.84 122.25,66.48 122.35,66.38 122.7,66.38 122.86,66.22 122.86,65.19 122.75,65.07 121.74,65.07 121.62,64.96 121.62,64.76 121.77,64.6 122.76,64.6 122.86,64.5 122.86,64.25 122.75,64.14 121.76,64.14 121.65,64.02 121.65,63.78 121.76,63.67 122.75,63.67 122.86,63.55 122.86,62.96 122.75,62.84 121.78,62.84 121.62,62.68 121.62,60.2 121.77,60.05 v2(122.04,60.05)
  BOTTOM w0.076: UC1.BB39 110.25,90.66 110.25,88.78 110.06,88.59 110.06,85.11 v2(110.98,84.19)
  BOTTOM w0.112: JDIMM1.173 121.22,61.9 121.22,60.87 v2(122.04,60.05)
DDR_A_D37: length 47
  IN3 w0.076: v2(110.98,83.54) 110.61,83.18 110.61,80.28 112.72,78.17 112.72,77.35
  IN3 w0.117: 112.72,77.35 112.72,73.31 118.04,67.98 119.1,67.98 119.22,67.87 119.22,67.39 119.36,67.24 119.57,67.24 119.69,67.36 119.69,67.87 119.8,67.98 120.01,67.98 120.13,67.87 120.13,67.41 120.24,67.3 120.76,67.3 120.96,67.1 120.96,57.8 121.24,57.51 v2(122.04,57.51)
  BOTTOM w0.076: v2(110.98,83.54) 109.75,84.76 v1(109.75,88.59) 109.75,89 110.08,89.33 110.08,90.42 110,90.5 110,90.79 110.12,91.04 110.12,91.04 110.13,91.05 110.27,91.19 UC1.BA39
  BOTTOM w0.112: JDIMM1.170 120.47,55.95 v2(122.04,57.51)
DDR_A_D38: length 47.8
  IN3 w0.076: v2(112.75,82.76) 112.39,82.4 112.39,81.27 112.9,80.76
  IN3 w0.117: v2(124.78,57.51) 125.09,57.21 125.53,57.21 125.64,57.33 125.64,60.73 126.04,61.13 126.04,61.8 125.64,62.19 125.64,64.7 126.24,65.3 126.24,65.92 121.31,70.85 119.25,70.85 115.54,74.56 115.54,78.47 113.25,80.76 112.9,80.76
  BOTTOM w0.076: UC1.BA37 111.59,91.12 111.86,90.86 111.86,90.39 111.86,90.39 111.86,87.7 111.8,87.64 v3(111.8,87.3) 111.8,86.93 111.86,86.87 111.86,83.66 v2(112.75,82.76)
  BOTTOM w0.112: JDIMM1.182 123.47,53.7 123.47,56.21 v2(124.78,57.51)
DDR_A_D39: length 46.7
  IN3 w0.076: 115.39,78.91 113.1,81.2 113.1,81.7 v2(112.75,82.05)
  IN3 w0.117: 115.39,78.91 115.87,78.42 115.87,74.74 119.39,71.22 121.43,71.22 126.57,66.08 126.57,65.16 125.97,64.57 125.97,62.33 126.37,61.93 126.37,60.99 125.97,60.59 125.97,56.16 125.73,55.92 125.11,55.92 v2(124.78,56.24)
  BOTTOM w0.076: UC1.BB37 111.59,90.49 111.69,90.39 111.69,87.84 111.59,87.74 111.59,86.87 111.69,86.77 111.69,83.11 112.39,82.42
  BOTTOM w0.112: JDIMM1.186 124.47,53.7 124.47,55.94 v2(124.78,56.24) ; 112.39,82.42 v2(112.75,82.05)
DDR_A_D40: length 48.6
  IN3 w0.076: v2(112.75,86.14) 113.14,86.52 113.36,86.52 113.43,86.45 113.43,81.41 116.43,78.41 116.44,78.41
  IN3 w0.117: 116.44,78.41 116.83,78.02 116.83,75.15 119.78,72.2 121.82,72.2 127.72,66.29 127.72,64.96 126.93,64.17 126.93,62.74 127.33,62.35 127.33,60.59 126.93,60.2 126.93,58.9 127.05,58.78 v2(127.37,58.78)
  BOTTOM w0.076: v2(112.75,86.14) 112.75,85.98 112.99,85.75 113.23,85.75 113.31,85.83 113.31,88.34 112.68,88.97 112.68,90.01 112.89,90.22 112.89,90.79 112.85,90.88 112.85,90.89 112.85,91.14 112.89,91.23 112.89,91.44 112.86,91.52 112.82,91.62 112.82,91.89 UC1.AY35
  BOTTOM w0.112: v2(127.37,58.78) 126.11,58.78 125.72,59.17 JDIMM1.191
DDR_A_D41: length 50.1
  IN3 w0.076: v2(112.75,84.84) 113.27,84.33 113.27,81.29 116.34,78.22
  IN3 w0.117: v2(127.37,57.51) 127.37,57.46 126.97,57.06 126.72,57.06 126.6,57.18 126.6,57.78 126.72,57.89 126.81,57.89 126.92,58.01 126.92,58.24 126.81,58.36 126.72,58.36 126.6,58.48 126.6,60.34 126.99,60.73 126.99,62.19 126.6,62.59 126.6,64.31 127.19,64.9 127.19,66.34 121.69,71.84 119.65,71.84 116.5,75 116.5,78.06 116.34,78.22
  BOTTOM w0.076: UC1.AW35 112.72,92.42 112.4,92.1 112.4,91.58 112.19,91.37 112.19,90.25 112.19,90.25 112.19,85.41 v2(112.75,84.84)
  BOTTOM w0.112: JDIMM1.190 125.47,56.37 126.61,57.51 v2(127.37,57.51)
DDR_A_D42: length 49.2
  IN3 w0.076: v2(114.58,83.89) 115.02,83.45 115.02,82.04 119.32,77.74 119.32,77.35
  IN3 w0.117: v2(130.62,58.78) 130.21,59.2 130.21,64.28 130.33,64.4 130.79,64.4 130.9,64.51 130.9,64.75 130.79,64.86 130.33,64.86 130.21,64.98 130.21,65.21 130.33,65.33 130.79,65.33 130.9,65.45 130.9,65.68 130.79,65.8 130.33,65.8 130.21,65.92 130.21,66.15 130.33,66.27 130.79,66.27 130.9,66.38 130.9,66.62 130.79,66.73 130.33,66.73 130.21,66.85 130.21,67.43 122.83,74.81 120.77,74.81 119.32,76.26 119.32,77.26 119.32,77.26 119.32,77.35
  BOTTOM w0.076: UC1.AY33 113.95,91.78 114.22,91.51 114.22,91.17 114.27,91.06 114.38,90.83 114.38,90.46 114.25,90.34 114.25,90.34 114.2,90.28 114.2,89.96 114.5,89.66 114.5,88.86 115.04,88.32 115.04,84.36 v2(114.58,83.89)
  BOTTOM w0.112: v2(130.62,58.78) 130.42,58.78 128.72,60.48 JDIMM1.203
DDR_A_D43: length 48.4
  IN3 w0.076: 118.99,77.35 118.99,77.81 114.58,82.22 v2(114.58,83.26)
  IN3 w0.117: v2(130.62,56.24) 130.13,56.73 130.13,58.55 129.88,58.8 129.88,67.29 122.69,74.48 120.63,74.48 118.99,76.12 118.99,77.24 118.99,77.35
  BOTTOM w0.076: UC1.AW33 113.29,92.64 113.09,92.43 113.09,91.92 113.02,91.82 113.02,91.57 113.06,91.44 113.06,91.21 113.06,91.2 113.05,91.2 113.05,91.2 113.02,91.11 113.02,90.91 113.05,90.82 113.05,90.82 113.05,90.15 112.96,90.05 112.96,88.93 113.48,88.41 113.48,84.36 v2(114.58,83.26)
  BOTTOM w0.112: JDIMM1.208 129.97,53.7 129.97,54.83 v2(130.62,56.24)
DDR_A_D44: length 47.5
  IN3 w0.076: 113.94,81.21 113.6,81.54 113.6,87.02 113.51,87.11 113.07,87.11 v2(112.75,86.79)
  IN3 w0.117: v2(127.37,60.05) 127.94,60.05 128.05,60.17 128.05,60.71 127.94,60.83 127.78,60.83 127.66,60.95 127.66,61.18 127.78,61.3 127.94,61.3 128.05,61.42 128.05,61.7 127.94,61.81 127.78,61.81 127.66,61.93 127.66,62.16 127.78,62.28 127.94,62.28 128.05,62.4 128.05,62.65 127.94,62.76 127.38,62.76 127.27,62.88 127.27,64.03 127.43,64.2 127.65,64.2 128.05,64.61 128.05,66.47 121.94,72.58 119.89,72.58 117.16,75.3 117.16,77.98 116.62,78.52 116.62,78.68 116.69,78.75 116.69,78.91 116.52,79.08 116.36,79.08 116.29,79.01 116.13,79.01 115.96,79.18 115.96,79.35 116.03,79.41 116.03,79.57 115.86,79.74 115.7,79.74 115.63,79.68 115.47,79.68 115.3,79.84 115.3,80.01 115.37,80.07 115.37,80.24 115.2,80.4 115.03,80.4 114.97,80.34 114.81,80.34 114.64,80.5 114.64,80.67 114.7,80.73 114.7,80.9 114.54,81.06 114.37,81.06 114.31,81 114.14,81 113.94,81.21
  BOTTOM w0.076: v2(112.75,86.79) 113.03,86.79 113.15,86.91 113.15,88.27 112.52,88.9 112.52,90.12 112.52,90.12 112.52,90.58 UC1.BB35
  BOTTOM w0.112: JDIMM1.195 126.72,60.8 126.59,60.66 126.19,60.66 126.05,60.53 126.05,60.17 126.16,60.05 v2(127.37,60.05)
DDR_A_D45: length 48
  IN3 w0.076: 117.35,78.51 113.76,82.1 113.76,87.69 113.36,88.09 v2(112.75,88.09)
  IN3 w0.117: v2(127.37,56.24) 127.37,55.89 127.5,55.76 127.96,55.76 128.2,56 128.2,58.31 128.39,58.5 128.39,66.65 122.1,72.93 120.04,72.93 117.5,75.48 117.5,78.37 117.35,78.51
  BOTTOM w0.076: v2(112.75,88.09) 112.35,88.49 112.35,90.18 112.35,90.19 112.35,90.85 112.62,91.11 UC1.BA35
  BOTTOM w0.112: JDIMM1.194 126.47,54.72 126.47,54.72 127.37,55.62 v2(127.37,56.24)
DDR_A_D46: length 47.7
  IN3 w0.076: v2(114.58,87.7) 115.54,86.75 115.54,82.06 119.99,77.6 119.99,77.35
  IN3 w0.117: v2(130.62,57.51) 131.04,57.93 131.04,59.53 132.01,60.51 132.01,62.49 131.7,62.8 131.7,66.91 123.11,75.5 121.05,75.5 119.99,76.56 119.99,77.35
  BOTTOM w0.076: UC1.BA33 113.95,91.19 114.09,91.05 114.09,91.04 114.1,91.04 114.21,90.79 114.21,90.53 114.04,90.35 114.04,89.89 114.32,89.6 114.32,87.96 v2(114.58,87.7)
  BOTTOM w0.112: v2(130.62,57.51) 129.64,56.53 129.64,55.79 128.97,55.12 128.97,53.7 JDIMM1.204
DDR_A_D47: length 46.5
  IN3 w0.076: 119.65,77.35 119.65,77.66 115.27,82.05 115.27,86.38 v2(114.58,87.07)
  IN3 w0.117: 119.65,77.35 119.65,77.28 119.66,77.28 119.66,76.41 120.91,75.16 122.97,75.16 131.37,66.76 131.37,62.83 131.27,62.72 130.75,62.72 130.62,62.6 130.62,62.38 130.74,62.26 131.54,62.26 131.68,62.12 131.68,61.91 131.56,61.8 130.74,61.8 130.62,61.68 130.62,61.45 130.74,61.33 131.56,61.33 131.68,61.21 131.68,60.65 131.46,60.43 131.23,60.43 131.11,60.55 131.11,60.74 131,60.86 130.74,60.86 130.62,60.74 v2(130.62,60.05)
  BOTTOM w0.076: UC1.BB33 113.95,90.54 113.87,90.46 113.87,89.82 114.12,89.57 114.12,87.53 v2(114.58,87.07)
  BOTTOM w0.112: JDIMM1.207 129.72,60.65 130.32,60.05 v2(130.62,60.05)
DDR_A_D48: length 50.8
  IN3 w0.076: 121.28,77.35 121.28,77.43 119.56,79.15 119.23,79.15 116.42,81.96 v2(116.42,82.43)
  IN3 w0.117: v2(132.81,59.32) 133.18,59.32 133.3,59.44 133.3,60.12 133.42,60.24 133.75,60.24 133.9,60.39 133.9,60.59 133.79,60.7 133.42,60.7 133.3,60.82 133.3,61.06 133.42,61.17 133.88,61.17 134.01,61.31 134.01,61.52 133.9,61.64 133.42,61.64 133.3,61.76 133.3,61.99 133.42,62.11 133.8,62.11 133.93,62.24 133.93,62.46 133.82,62.58 133.6,62.58 133.49,62.69 133.49,63.81 133.38,63.92 133.11,63.92 132.99,64.03 132.99,64.32 133.11,64.44 133.39,64.44 133.53,64.57 133.53,64.78 133.41,64.9 133.11,64.9 132.99,65.02 132.99,66.71 133.22,66.94 133.22,67.27 123.65,76.85 121.73,76.85 121.28,77.29 121.28,77.35
  BOTTOM w0.076: UC1.AY31 115.25,91.78 114.98,91.52 114.98,91.23 114.82,90.82 114.82,90.46 114.99,90.29 114.99,89.41 115.3,89.09 115.3,83.55 v2(116.42,82.43)
  BOTTOM w0.112: v2(132.81,59.32) 132.01,59.32 131.53,59.8 131.53,60.17 131.64,60.29 132.1,60.29 132.22,60.4 132.22,60.66 132.11,60.77 131.84,60.77 131.72,60.88 JDIMM1.215
DDR_A_D49: length 50.7
  IN3 w0.076: v2(116.42,88.15) 115.74,87.47 115.74,82.11 119.2,78.65 119.5,78.65 120.62,77.53 120.62,77.35
  IN3 w0.117: 120.62,77.35 120.62,76.85 121.33,76.13 123.37,76.13 132.14,67.36 132.15,67.36 132.33,67.19 132.33,63.06 132.64,62.75 132.64,60.25 131.66,59.28 131.66,56.97 131.85,56.78 v2(132.81,56.78)
  BOTTOM w0.076: UC1.AW31 115.94,92.64 116.16,92.42 116.16,91.85 116.18,91.83 116.18,91.57 116.12,91.42 116.12,91.28 116.19,91.06 116.19,90.94 116.15,90.86 116.14,90.83 116.14,90.3 116.44,90.01 116.44,88.17 v2(116.42,88.15)
  BOTTOM w0.112: v2(132.81,56.78) 130.97,54.94 130.97,53.7 JDIMM1.212
DDR_A_D50: length 50
  IN3 w0.076: 122.07,78.7 121.49,78.7 119.84,80.35 119.28,80.35 117.42,82.21 117.42,86.51 v2(116.42,87.51)
  IN3 w0.117: v2(136.26,55.51) 135.84,55.94 135.84,63.13 135.7,63.27 135.7,64.11 135.35,64.46 135.35,67.75 124.41,78.7 122.07,78.7
  BOTTOM w0.076: v2(116.42,87.51) 116.79,87.88 116.79,88.42 116.6,88.6 116.6,90.08 116.31,90.37 116.31,90.79 116.36,90.91 116.36,91.05 116.3,91.28 116.3,91.41 116.37,91.63 116.37,91.89 UC1.AY29
  BOTTOM w0.112: JDIMM1.228 134.97,53.7 134.97,54.99 135.49,55.51 v2(136.26,55.51)
DDR_A_D51: length 51.1
  IN3 w0.076: 122.07,79.06 121.87,79.06 121.69,79.23 121.28,79.23 119.91,80.61 119.28,80.61 117.63,82.26 117.63,83.96 v2(118.01,84.34)
  IN3 w0.117: v2(136.26,59.32) 136.41,59.46 136.41,63.4 136.29,63.52 136.21,63.52 136.09,63.63 136.09,63.87 136.21,63.98 136.29,63.98 136.41,64.1 136.41,64.34 136.29,64.45 135.83,64.45 135.69,64.6 135.69,64.8 135.8,64.92 136.29,64.92 136.41,65.04 136.41,65.27 136.29,65.39 135.83,65.39 135.69,65.53 135.69,65.74 135.8,65.86 136.29,65.86 136.41,65.97 136.41,66.22 136.29,66.33 135.85,66.33 135.74,66.45 135.74,66.68 135.85,66.8 136.29,66.8 136.41,66.92 136.41,67.18 136.24,67.35 135.8,67.35 135.69,67.46 135.69,67.89 124.52,79.06 122.07,79.06
  BOTTOM w0.076: v2(118.01,84.34) 117.3,85.05 117.3,88.72 117.1,88.92 117.1,90.3 117.01,90.39 117.01,91.34 116.77,91.58 116.77,91.83 116.79,91.95 116.79,92.12 116.61,92.3 116.59,92.3 116.47,92.42 UC1.AW29
  BOTTOM w0.112: v2(136.26,59.32) 135.23,60.36 JDIMM1.229
DDR_A_D52: length 48.9
  IN3 w0.076: v2(116.42,84.34) 116.08,84.34 115.92,84.19 115.92,82.21 119.25,78.88 119.5,78.88 120.95,77.43 120.95,77.35
  IN3 w0.117: v2(132.81,58.05) 132.44,57.68 132.11,57.68 131.99,57.8 131.99,58.16 132.11,58.28 132.27,58.28 132.38,58.4 132.38,58.6 132.24,58.75 132.11,58.75 131.99,58.86 131.99,59.14 132.97,60.11 132.97,62.87 133.15,63.06 133.15,63.4 132.66,63.9 132.66,67.33 123.49,76.49 121.56,76.49 120.95,77.1 120.95,77.35
  BOTTOM w0.076: v2(116.42,84.34) 115.63,85.13 115.63,89.23 115.32,89.54 115.32,90.61 UC1.BB31
  BOTTOM w0.112: v2(132.81,58.05) 131.06,59.8 131.06,60.55 130.72,60.89 JDIMM1.211
DDR_A_D53: length 49.2
  IN3 w0.076: 121.7,77.35 121.66,77.35 119.67,79.35 119.29,79.35 116.77,81.86 116.77,83.35 v2(116.42,83.7)
  IN3 w0.117: 121.7,77.35 121.85,77.2 123.77,77.2 133.63,67.35 133.63,66.88 133.32,66.57 133.32,65.46 133.86,64.92 133.86,63 134.35,62.52 134.35,60.36 133.63,59.65 133.63,57.3 133.52,57.19 133.34,57.19 133.23,57.07 133.23,56.84 133.34,56.72 133.52,56.72 133.63,56.6 133.63,55.82 133.32,55.51 v2(132.81,55.51)
  BOTTOM w0.076: v2(116.42,83.7) 115.47,84.66 115.47,89.16 115.15,89.47 115.15,90.36 114.98,90.53 114.98,90.79 115.1,91.04 115.1,91.04 115.11,91.05 115.25,91.19 UC1.BA31
  BOTTOM w0.112: JDIMM1.216 131.97,53.7 131.97,54.67 v2(132.81,55.51)
DDR_A_D54: length 49.7
  IN3 w0.076: 121.86,79.72 121.39,79.72 119.95,81.16 119.55,81.16 118.72,82 118.72,82.36 v2(118.01,83.07)
  IN3 w0.117: 121.86,79.72 124.81,79.72 137.07,67.46 137.07,57.59 v2(136.26,56.78)
  BOTTOM w0.076: UC1.BA29 116.57,91.11 116.84,90.84 116.84,90.3 116.93,90.21 116.93,88.85 117.14,88.65 117.14,83.94 v2(118.01,83.07)
  BOTTOM w0.112: JDIMM1.224 133.97,53.7 133.97,54.59 136.17,56.78 v2(136.26,56.78)
DDR_A_D55: length 48.5
  IN3 w0.076: 122.07,79.39 121.89,79.39 121.79,79.49 121.33,79.49 120.01,80.81 119.48,80.81 118.49,81.8 118.49,82.21 118.26,82.43 v2(118.01,82.43)
  IN3 w0.117: 122.07,79.39 124.67,79.39 136.74,67.32 136.74,58.17 136.62,58.05 v2(136.26,58.05)
  BOTTOM w0.076: v2(118.01,82.43) 116.97,83.48 116.97,86.79 116.91,86.85 v3(116.91,87.25) 116.91,87.57 116.97,87.63 116.97,88.52 116.77,88.72 116.77,90.14 116.57,90.34 UC1.BB29
  BOTTOM w0.112: JDIMM1.225 134.23,60.2 135.77,58.66 135.77,58.54 v2(136.26,58.05)
DDR_A_D56: length 52.9
  IN3 w0.076: 119.19,85.63 119.19,82.12 119.63,81.67 119.71,81.67
  IN3 w0.117: 119.71,81.67 120.08,81.67 121.04,80.71 125.2,80.71 138.03,67.87 138.03,60.35 138.15,60.24 138.22,60.24 138.34,60.12 138.34,59.89 138.22,59.77 138.15,59.77 138.03,59.65 138.03,59.43 138.15,59.32 138.24,59.32 138.36,59.2 138.36,58.97 138.24,58.85 138.15,58.85 138.03,58.73 138.03,58.45 138.12,58.35 138.39,58.35 138.57,58.17 138.57,57.92 138.4,57.75 138.21,57.75 v2(138.11,57.85) ; v2(118.01,86.24) 118.85,86.24 119.19,85.9 119.19,85.63
  BOTTOM w0.076: v2(118.01,86.24) 118.54,86.78 118.54,88.38 118.2,88.72 118.2,88.95 117.76,89.39 117.76,90.42 117.87,90.53 117.87,90.79 117.83,90.88 117.83,90.89 117.83,91.14 117.87,91.23 117.87,91.44 117.84,91.52 117.8,91.62 117.8,91.89 UC1.AY27
  BOTTOM w0.112: v2(138.11,57.85) 137.44,57.17 137.44,56.03 135.98,54.57 JDIMM1.232
DDR_A_D57: length 53.3
  IN3 w0.076: v2(118.01,84.97) 118.34,84.97 118.95,84.36 118.95,82 119.53,81.42 120,81.42 121.07,80.35 121.23,80.35
  IN3 w0.117: 121.23,80.35 125.07,80.35 137.7,67.72 137.7,56.19 137.81,56.07 138.65,56.07 138.77,56.19 v2(138.77,56.65)
  BOTTOM w0.076: v2(118.01,84.97) 117.59,85.39 117.59,88.85 117.26,89.18 117.26,90.37 117.17,90.46 117.17,91.37 117.38,91.58 117.38,91.59 117.41,91.61 117.41,91.83 117.38,91.95 117.38,92.13 117.7,92.45 UC1.AW27
  BOTTOM w0.112: v2(138.77,56.65) 136.98,54.86 JDIMM1.236
DDR_A_D58: length 52.8
  IN3 w0.117: v2(138.77,60.46) 138.47,60.46 138.36,60.57 138.36,60.94 138.5,61.07 139.04,61.07 139.17,61.2 139.17,61.45 139.04,61.58 138.5,61.58 138.37,61.71 138.37,61.96 138.5,62.09 139.04,62.09 139.17,62.22 139.17,62.47 139.04,62.6 138.5,62.6 138.37,62.72 138.37,64.9 138.49,65.01 139.05,65.01 139.17,65.14 139.17,65.36 139.05,65.48 138.49,65.48 138.37,65.6 138.37,65.83 138.49,65.95 139.05,65.95 139.17,66.06 139.17,66.3 139.05,66.41 138.49,66.41 138.37,66.53 138.37,66.77 138.49,66.88 139.05,66.88 139.17,67 139.17,67.22 139.04,67.35 138.49,67.35 138.37,67.47 138.37,68.01 125.32,81.06 124.49,81.06 122.76,82.79 121.38,82.79 121.13,82.54 120.34,82.54 119.92,82.12 v2(119.78,82.12)
  BOTTOM w0.076: UC1.AY25 118.93,91.78 119.2,91.51 119.2,91.17 119.22,91.13 119.29,90.99 119.37,90.81 119.37,90.49 119.37,90.49 119.37,89.63 119.84,89.16 119.84,87.39 120.23,86.99 120.23,82.43 119.91,82.12 v2(119.78,82.12)
  BOTTOM w0.112: v2(138.77,60.46) 137.72,60.46 137.22,60.96 137.22,61.9 JDIMM1.237
DDR_A_D59: length 53.4
  IN3 w0.117: v2(138.77,59.19) 138.96,59 139.13,59 139.5,59.37 139.5,59.79 139.38,59.91 139.3,59.91 139.18,60.03 139.18,60.26 139.3,60.38 139.38,60.38 139.5,60.49 139.5,62.98 139.38,63.1 139.33,63.1 139.21,63.21 139.21,63.45 139.33,63.56 139.38,63.56 139.5,63.68 139.5,63.91 139.38,64.03 139.33,64.03 139.21,64.15 139.21,64.38 139.33,64.5 139.38,64.5 139.5,64.62 139.5,67.37 125.47,81.4 124.63,81.4 122.9,83.13 121.24,83.13 120.99,82.88 120.83,82.88 120.72,82.99 120.72,83.6 120.6,83.71 120.37,83.71 120.25,83.6 120.25,82.92 120.09,82.76 119.78,82.76 v2(119.73,82.8)
  BOTTOM w0.076: UC1.AW25 118.29,92.64 118.01,92.35 118.01,91.53 118.04,91.44 118.04,91.21 118.04,91.2 118.03,91.2 118.03,91.2 118,91.11 118,90.91 118.03,90.82 118.03,90.46 117.96,90.39 117.96,89.66 118.51,89.1 118.51,88.85 v1(118.64,88.72) 118.72,88.64 118.72,83.83 119.73,82.81 v2(119.73,82.8)
  BOTTOM w0.112: JDIMM1.233 136.23,60.98 138.01,59.19 v2(138.77,59.19)
DDR_A_D60: length 51.8
  IN3 w0.117: v2(141.47,57.29) 141.87,57.69 141.87,58.45 142.22,58.79 142.22,67.7 139.86,70.05 139.86,70.39 126.36,83.89 125.46,83.89 123.6,85.76 121.81,85.76 120.59,86.98 118.1,86.98 v2(118.01,86.88)
  BOTTOM w0.076: v2(118.01,86.88) 118.37,87.25 118.37,88.29 118.01,88.66 118.01,88.91 117.59,89.33 117.59,90.68 UC1.BB27
  BOTTOM w0.112: JDIMM1.246 139.47,54.6 139.93,55.05 141.12,57.19 v2(141.47,57.29)
DDR_A_D61: length 51.8
  IN3 w0.117: v2(118.01,88.15) 118.82,87.34 120.7,87.34 121.94,86.09 123.77,86.09 125.61,84.25 126.48,84.25 140.2,70.53 140.2,70.19 142.58,67.8 142.58,58.67 142.24,58.33 142.24,56.79 v2(141.47,56.02)
  BOTTOM w0.076: v2(118.01,88.15) 117.82,88.34 117.82,88.87 117.43,89.26 117.43,90.44 117.34,90.53 117.34,90.85 117.6,91.11 UC1.BA27
  BOTTOM w0.112: JDIMM1.250 140.47,55.02 v2(141.47,56.02)
DDR_A_D62: length 51.4
  IN3 w0.117: v2(141.47,58.56) 141.89,58.97 141.89,65.64 141.65,65.88 141.65,66.05 141.89,66.28 141.89,66.62 141.77,66.74 141.48,66.74 141.33,66.89 141.33,67.12 141.43,67.22 141.7,67.22 141.82,67.34 141.82,67.61 141.7,67.73 141.44,67.73 141.33,67.84 141.33,68.12 139.53,69.91 139.53,70.25 126.25,83.54 125.31,83.54 123.88,84.97 123.27,84.97 123.15,85.09 123.15,85.31 123.04,85.43 122.8,85.43 122.69,85.31 122.69,85.09 122.57,84.97 122.11,84.97 121.99,85.09 121.99,85.31 121.88,85.43 121.67,85.43 121.14,85.95 120.98,85.95 120.72,85.7 120.56,85.7 120.39,85.86 120.39,86.03 120.6,86.23 120.6,86.4 120.44,86.56 v2(119.78,86.56)
  BOTTOM w0.076: v2(119.78,86.56) 119.78,87.06 119.63,87.21 119.63,89.04 119.2,89.47 119.2,90.77 119.14,90.91 119.14,90.91 119.08,91.04 118.93,91.19 UC1.BA25
  BOTTOM w0.112: v2(141.47,58.56) 139.23,60.8 JDIMM1.245
DDR_A_D63: length 50.7
  IN3 w0.117: v2(141.47,59.83) 141.11,59.83 140.99,59.94 140.99,60.35 141.11,60.46 141.44,60.46 141.55,60.58 141.55,60.81 141.44,60.93 141.11,60.93 140.99,61.05 140.99,61.28 141.11,61.4 141.44,61.4 141.55,61.51 141.55,61.75 141.44,61.86 141.11,61.86 140.99,61.98 140.99,62.21 141.11,62.33 141.44,62.33 141.55,62.45 141.55,62.68 141.44,62.8 141.11,62.8 140.99,62.92 140.99,63.15 141.11,63.27 141.44,63.27 141.55,63.38 141.55,63.62 141.44,63.73 141.11,63.73 140.99,63.85 140.99,64.08 141.11,64.2 141.41,64.2 141.53,64.32 141.53,64.55 141.41,64.67 141.11,64.67 140.99,64.79 140.99,65.02 141.11,65.14 141.41,65.14 141.53,65.25 141.53,65.49 141.41,65.6 141.11,65.6 140.99,65.72 140.99,65.95 141.11,66.07 141.21,66.07 141.33,66.19 141.33,66.42 141.21,66.54 141.11,66.54 140.99,66.65 140.99,67.98 139.2,69.77 139.2,70.12 126.13,83.18 125.14,83.18 123.71,84.62 121.78,84.62 121.11,85.29 120.42,85.29 v2(119.78,85.93)
  BOTTOM w0.076: v2(119.78,85.93) 119.4,86.31 119.4,88.96 119.04,89.33 119.04,90.57 UC1.BB25
  BOTTOM w0.112: v2(141.47,59.83) 141.13,59.83 140.23,60.74 JDIMM1.249
DDR_A_DQS0: length 62.9
  IN3 w0.124: v2(78.56,57.59) 78.95,57.59 79.33,57.98 79.33,59.16 79,59.49 79,59.7 78.25,60.46 78.25,63.46 78.67,63.88 78.67,76 79.13,76.46 79.13,86.58 79.25,86.71 80.17,86.71 80.41,86.96 80.41,87.51 80.17,87.76 79.25,87.76 79.13,87.88 79.13,88.25 79.25,88.38 79.88,88.38 80.13,88.63 80.13,89.18 79.88,89.43 79.25,89.43 79.13,89.55 79.13,92.93 80.66,94.46 84.88,94.46 85.21,94.8 85.21,95.94 v2(85.42,96.15)
  BOTTOM w0.076: UC1.AM69 93.22,96.94 93.18,96.98 93.18,97.12 93.11,97.18 92.91,97.28 92.62,97.28 92.54,97.24 92.33,97.24 92.22,97.3 92,97.3 91.89,97.24 91.63,97.24 91.55,97.32 90.77,97.32 90.3,96.86 89.23,96.86 88.51,96.13 86.97,96.13 86.52,95.69 86.51,95.69
  BOTTOM w0.102: 86.51,95.69 85.73,95.69 85.42,96 v2(85.42,96.15)
  BOTTOM w0.112: JDIMM1.13 79.22,59.67 79.4,59.5 79.4,57.92 79.17,57.69 78.66,57.69 v2(78.56,57.59)
DDR_A_DQS1: length 50.1
  IN3 w0.124: v2(88.64,89.65) 88.8,89.65 88.93,89.52 88.93,89.29 88.37,88.73 88.37,88.68 83.78,84.1 83.78,75.71 83.46,75.39 83.46,74.78 83.78,74.46 83.78,74.04 83.46,73.72 83.46,73.11 83.78,72.79 83.78,72.37 83.46,72.05 83.46,71.44 83.78,71.12 83.78,70.7 83.46,70.37 83.46,64.83 83.78,64.51 83.78,64.1 84.18,63.7 84.18,56.51 84.12,56.44 83.8,56.44 v2(83.62,56.62)
  BOTTOM w0.076: 87.97,91.7 87.99,91.7 88.77,92.48 88.77,92.48 90.38,94.09 91.27,94.09 91.43,94.26 91.92,94.26 92.06,94.21 92.16,94.21 92.29,94.26 92.57,94.26 92.65,94.22 92.87,94.22 92.98,94.28 93.01,94.31 93.01,94.47 92.94,94.54 92.81,94.54 UC1.AT70
  BOTTOM w0.112: JDIMM1.34 84.47,54.72 84.33,54.87 84.33,56.22 84.12,56.42 83.68,56.42 83.62,56.49 v2(83.62,56.62) ; 87.97,91.7 87.83,91.56 87.83,90.28 88.06,90.05 88.24,90.05 88.64,89.65 v2(88.64,89.65)
DDR_A_DQS2: length 46.8
  IN3 w0.124: v2(88.75,57.64) 88.88,57.77 89.2,57.77 89.45,58.02 89.45,59.9 89.28,60.07 89.28,64.7 88.09,65.9 88.09,72.54 88.21,72.67 88.29,72.67 88.54,72.92 88.54,73.47 88.29,73.72 88.21,73.72 88.09,73.84 88.09,74.21 88.21,74.34 88.29,74.34 88.6,74.64 88.6,82.72 88.72,82.84 89.94,82.84 90.19,83.09 90.19,84.42 90.35,84.58 90.53,84.58 v2(90.63,84.48)
  BOTTOM w0.076: v2(90.63,84.48) 90.63,84.48 90.66,84.51 90.66,85.45 91.16,85.95 91.36,85.95 92.1,86.7 92.1,88.1 92.84,88.83 94.79,88.83 95.66,89.71 95.66,90.4 95.8,90.54 95.8,90.79 95.76,90.89 95.76,91.12 95.81,91.23 95.81,91.44 95.77,91.52 95.77,91.81 95.86,92 95.88,92.03 96.11,92.26 UC1.AY64
  BOTTOM w0.112: v2(88.75,57.64) 88.8,57.68 89.32,57.68 89.56,57.93 89.56,60.88 89.72,61.04 JDIMM1.55
DDR_A_DQS3: length 45.1
  IN3 w0.124: v2(96.25,86.88) 95.96,86.59 95.31,86.59 94.97,86.25 94.97,81.78 92.51,79.32 92.51,67 93.2,66.31 93.2,65.54 94.23,64.51 94.23,57.56 94.1,57.42 93.9,57.42 v2(93.48,57.84)
  BOTTOM w0.076: UC1.BA60 98.61,91.71 98.69,91.71 98.79,91.61 98.79,91.2 98.84,91.07 98.84,90.96 98.79,90.82 98.79,90.46 98.95,90.31 98.95,89.97 98.63,89.66 98.63,89.52 96.74,87.64 96.74,86.62 96.64,86.51 96.47,86.51 96.25,86.73 v2(96.25,86.88)
  BOTTOM w0.112: v2(93.48,57.84) 93.48,57.78 93.69,57.57 94.23,57.57 94.82,56.98 94.82,54.75 94.97,54.59 JDIMM1.76
DDR_A_DQS4: length 47.3
  IN3 w0.124: v2(110.98,85.49) 110.92,85.55 110.92,85.71 110.97,85.76 111.13,85.76 111.32,85.95 111.32,85.98 111.39,86.05 111.58,86.05 111.65,85.98 111.65,80.31 113.82,78.14 113.82,77.56 114.03,77.35 114.03,73.88 118.6,69.31 120.68,69.31 123.5,66.49 123.5,62.34 123.36,62.21 122.52,62.21 122.26,61.94 122.26,61.2 122.52,60.93 123.61,60.93 123.93,60.62 123.93,59.63 123.79,59.48 123.49,59.48 123.32,59.65 v2(123.32,59.74)
  BOTTOM w0.076: UC1.AY38 110.63,92.05 110.54,91.91 110.5,91.8 110.5,91.52 110.53,91.44 110.53,91.23 110.48,91.12 110.48,90.9 110.53,90.79 110.53,90.43 110.42,90.32 110.42,88.69 110.32,88.59 110.32,86.1 110.49,85.92 110.69,85.92 110.82,85.8 110.82,85.65 v2(110.98,85.49)
  BOTTOM w0.112: JDIMM1.179 122.72,60.94 122.68,60.9 122.68,59.73 122.88,59.52 123.24,59.52 123.32,59.6 v2(123.32,59.74)
DDR_A_DQS5: length 48.6
  IN3 w0.124: v2(128.77,56.55) 129.49,57.27 129.49,58.28 129.24,58.52 129.24,67.01 122.4,73.85 120.34,73.85 118.34,75.85 118.34,78.14 114.17,82.31 114.17,85.09 114.28,85.2 114.54,85.2 v2(114.58,85.16)
  BOTTOM w0.076: v2(114.58,85.16) 114.25,85.49 114.05,85.49 113.72,85.82 113.72,89.5 113.51,89.71 113.51,90.83 113.57,90.94 113.57,90.96 113.57,91.07 113.52,91.2 113.52,91.47 113.55,91.55 113.55,91.77 113.52,91.83 113.47,91.91 113.43,91.93 113.35,91.93 113.28,91.87 UC1.BA34
  BOTTOM w0.112: v2(128.77,56.55) 128.49,56.83 128.31,56.83 128.2,56.72 128.2,55.28 127.82,54.9 127.82,54.67 127.98,54.52 JDIMM1.200
DDR_A_DQS6: length 49.9
  IN3 w0.124: v2(134.21,59) 134.47,58.75 134.86,58.75 135,58.88 135,62.78 134.51,63.27 134.51,65.35 134.4,65.46 134.22,65.46 133.95,65.73 133.95,66.31 134.22,66.58 134.38,66.58 134.5,66.69 134.5,67.37 124.01,77.86 121.6,77.86 119.67,79.78 119.19,79.78 117.02,81.95 117.02,85.83 116.91,85.94 116.75,85.94 v2(116.42,85.61)
  BOTTOM w0.076: v2(116.42,85.61) 116.13,85.9 116.05,85.9 115.85,86.1 115.85,89.25 115.48,89.61 115.48,90.15 115.51,90.18 115.51,90.79 115.46,90.9 115.46,91.07 arc(115.47,91.12) 115.48,91.16 115.5,91.2 arc(115.51,91.23) 115.51,91.26 115.51,91.8 115.81,92.1 UC1.AY30
  BOTTOM w0.112: v2(134.21,59) 133.94,58.73 133.73,58.73 133.62,58.84 133.62,59.86 133.05,60.43 133.05,60.9 133.23,61.08 JDIMM1.221
DDR_A_DQS7: length 52.8
  IN3 w0.124: v2(119.78,84.02) 120.21,84.44 120.76,84.44 121.43,83.78 123.14,83.78 124.86,82.06 125.72,82.06 140.13,67.65 140.13,59.11 139.33,58.31 139.33,57.45 139.6,57.19 139.97,57.19 v2(140.19,56.96)
  BOTTOM w0.076: v2(119.78,84.02) 119.55,84.25 119.18,84.25 118.92,84.52 v3(118.92,87.2) 118.92,88.97 118.7,89.19 118.7,90.22 118.49,90.43 118.49,90.83 118.54,90.93 118.54,90.94 118.54,91.08 118.54,91.09 118.49,91.19 118.49,91.47 118.53,91.55 118.53,91.77 118.5,91.83 118.45,91.91 118.41,91.93 118.32,91.93 118.26,91.87 UC1.BA26
  BOTTOM w0.112: v2(140.19,56.96) 139.99,57.16 139.81,57.16 139.57,56.92 139.57,56.29 138.33,55.04 138.33,54.74 138.47,54.59 JDIMM1.242
DDR_A_DQS#0: length 62.9
  IN3 w0.124: v2(78.59,58.18) 78.82,57.94 79,57.94 79.12,58.07 79.12,59.07 78.79,59.4 78.79,59.61 78.03,60.37 78.03,63.54 78.46,63.96 78.46,76.09 78.92,76.55 78.92,86.67 79.16,86.92 80.08,86.92 80.2,87.05 80.2,87.42 80.08,87.54 79.16,87.54 78.92,87.79 78.92,88.34 79.16,88.59 79.79,88.59 79.92,88.72 79.92,89.09 79.79,89.21 79.16,89.21 78.92,89.46 78.92,93.02 80.58,94.68 84.79,94.68 85,94.89 85,95.94 v2(84.78,96.15)
  BOTTOM w0.076: 86.57,95.49 87.04,95.96 88.58,95.96 89.3,96.69 90.37,96.69 90.84,97.16 91.48,97.16 91.56,97.08 91.92,97.08 92.06,97.13 92.16,97.13 92.29,97.08 92.57,97.08 92.65,97.11 92.87,97.11 93.01,97.04 93.01,96.93 92.93,96.84 UC1.AM70
  BOTTOM w0.102: v2(84.78,96.15) 85.19,95.74 85.39,95.74 85.64,95.49 86.57,95.49
  BOTTOM w0.112: JDIMM1.11 78.73,61.01 78.84,60.89 78.91,60.89 79.02,60.78 79.02,59.59 79.2,59.41 79.2,58.01 79.08,57.89 78.84,57.89 78.59,58.15 v2(78.59,58.18)
DDR_A_DQS#1: length 50
  IN3 w0.124: v2(83.62,55.99) 83.62,56.05 83.8,56.23 84.21,56.23 84.4,56.42 84.4,63.79 84,64.19 84,64.6 83.68,64.92 83.68,70.29 84,70.61 84,71.21 83.68,71.53 83.68,71.96 84,72.28 84,72.88 83.68,73.2 83.68,73.63 84,73.95 84,74.55 83.68,74.87 83.68,75.3 84,75.62 84,84.01 88.58,88.59 88.58,88.64 89.14,89.2 89.14,89.77 88.89,90.02 88.86,90.02 v2(88.64,90.23)
  BOTTOM w0.076: 88.05,91.49 88.11,91.55 88.11,91.58 88.89,92.36 90.46,93.93 91.34,93.93 91.5,94.09 91.89,94.09 92,94.04 92.22,94.04 92.33,94.09 92.54,94.09 92.62,94.06 92.91,94.06 93.1,94.15 93.1,94.15 93.41,94.46 UC1.AT69
  BOTTOM w0.112: 88.05,91.49 88.03,91.47 88.03,90.37 88.14,90.26 88.62,90.26 v2(88.64,90.23) ; JDIMM1.32 83.97,54.72 84.12,54.87 84.12,56.13 84.04,56.22 83.85,56.22 v2(83.62,55.99)
DDR_A_DQS#2: length 46.9
  IN3 w0.124: v2(91.18,84.65) 90.94,84.9 90.37,84.9 89.98,84.51 89.98,83.18 89.86,83.05 88.64,83.05 88.39,82.8 88.39,74.73 88.21,74.55 88.13,74.55 87.88,74.3 87.88,73.75 88.13,73.5 88.21,73.5 88.33,73.38 88.33,73 88.21,72.88 88.13,72.88 87.88,72.63 87.88,65.81 89.07,64.62 89.07,59.98 89.23,59.81 89.23,58.12 89.12,58.01 88.96,58.01 v2(88.75,58.22)
  BOTTOM w0.076: UC1.BA64 96.21,91.68 96.13,91.76 96.01,91.71 95.94,91.63 95.94,91.55 95.98,91.47 95.98,91.19 95.93,91.08 95.93,90.93 95.97,90.83 95.97,90.47 95.83,90.33 95.83,89.64 94.86,88.66 92.91,88.66 92.27,88.03 92.27,86.63 91.43,85.78 91.23,85.78 90.83,85.38 90.83,84.9 91.07,84.65 v2(91.18,84.65)
  BOTTOM w0.112: v2(88.75,58.22) 88.75,58.22 89.07,57.89 89.23,57.89 89.36,58.02 89.36,60.94 89.22,61.08 JDIMM1.53
DDR_A_DQS#3: length 45
  IN3 w0.124: v2(93.48,57.2) 93.71,57.2 93.72,57.21 94.18,57.21 94.44,57.47 94.44,64.6 93.41,65.63 93.41,66.4 92.72,67.09 92.72,79.23 95.18,81.69 95.18,86.16 95.4,86.38 96.1,86.38 v2(96.25,86.23)
  BOTTOM w0.076: v2(96.25,86.23) 96.36,86.35 96.71,86.35 96.91,86.55 96.91,87.56 98.8,89.45 98.8,89.59 99.12,89.9 99.12,90.37 98.96,90.53 98.96,90.79 99.01,90.9 99.01,91.12 98.96,91.23 98.96,91.68 98.66,91.98 UC1.AY60
  BOTTOM w0.112: JDIMM1.74 94.47,54.61 94.61,54.75 94.61,56.89 94.14,57.36 93.65,57.36 v2(93.48,57.2)
DDR_A_DQS#4: length 47.3
  IN3 w0.124: v2(123.32,59.1) 123.32,59.15 123.44,59.27 123.87,59.27 124.14,59.54 124.14,60.71 123.7,61.15 122.61,61.15 122.47,61.29 122.47,61.85 122.61,61.99 123.45,61.99 123.71,62.25 123.71,66.57 120.76,69.52 118.69,69.52 114.25,73.97 114.25,77.44 114.03,77.65 114.03,78.23 111.86,80.4 111.86,86.07 111.66,86.26 111.1,86.26 v2(110.98,86.14)
  BOTTOM w0.076: v2(110.98,86.14) 110.93,86.09 110.56,86.09 110.49,86.17 110.49,88.52 110.59,88.62 110.59,90.25 110.7,90.36 110.7,90.79 110.7,90.82 110.64,90.96 110.64,91.07 110.7,91.2 110.7,91.44 arc(110.69,91.47) 110.68,91.5 110.67,91.53 arc(110.67,91.55) 110.66,91.57 110.66,91.75 arc(110.66,91.77) 110.67,91.78 110.68,91.8 arc(110.69,91.83) 110.71,91.86 110.73,91.89 arc(110.74,91.91) 110.75,91.93 110.77,91.95 arc(110.79,91.96) 110.81,91.96 110.82,91.96 arc(110.9,91.9) 110.93,91.81 110.93,91.67 UC1.BA38
  BOTTOM w0.112: v2(123.32,59.1) 123.1,59.32 122.8,59.32 122.47,59.64 122.47,60.75 122.23,60.99 JDIMM1.177
DDR_A_DQS#5: length 48.7
  IN3 w0.124: v2(128.77,57.18) 129.1,57.18 129.27,57.35 129.27,58.19 129.03,58.43 129.03,66.92 122.31,73.63 120.26,73.63 118.13,75.76 118.13,78.05 113.95,82.22 113.95,85.17 v2(114.58,85.8)
  BOTTOM w0.076: v2(114.58,85.8) 114.44,85.66 114.12,85.66 113.89,85.89 113.89,89.56 113.68,89.78 113.68,90.79 113.73,90.9 113.73,91.12 113.68,91.23 113.68,91.44 113.72,91.52 113.72,91.8 113.67,91.91 113.59,92.05 113.46,92.1 113.4,92.1 113.38,92.12 UC1.AY34
  BOTTOM w0.112: v2(128.77,57.18) 128.63,57.04 128.23,57.04 127.99,56.81 127.99,55.36 127.62,54.99 127.62,54.67 127.47,54.53 127.47,54.53 JDIMM1.198
DDR_A_DQS#6: length 49.8
  IN3 w0.124: v2(116.42,86.24) 116.51,86.15 117,86.15 117.23,85.92 117.23,82.04 119.28,80 119.76,80 121.68,78.07 124.09,78.07 134.71,67.46 134.71,66.6 134.47,66.36 134.31,66.36 134.17,66.22 134.17,65.81 134.31,65.67 134.49,65.67 134.73,65.44 134.73,63.35 135.21,62.87 135.21,58.79 134.95,58.53 134.37,58.53 v2(134.21,58.37)
  BOTTOM w0.076: v2(116.42,86.24) 116.41,86.24 116.26,86.09 116.09,86.09 116.02,86.17 116.02,89.31 115.65,89.68 115.65,90.08 115.68,90.11 115.68,90.83 115.63,90.94 115.63,90.96 115.63,91.07 115.68,91.2 115.68,91.56 115.78,91.66 UC1.BA30
  BOTTOM w0.112: JDIMM1.219 132.72,61.07 132.84,60.96 132.84,60.35 133.41,59.78 133.41,58.76 133.64,58.52 134.05,58.52 v2(134.21,58.37)
DDR_A_DQS#7: length 52.8
  IN3 w0.124: v2(140.19,57.6) 139.99,57.4 139.69,57.4 139.55,57.54 139.55,58.22 140.34,59.02 140.34,67.74 125.81,82.27 124.95,82.27 123.23,83.99 121.52,83.99 120.85,84.66 v2(119.78,84.66)
  BOTTOM w0.076: v2(119.78,84.66) 119.55,84.42 119.26,84.42 119.19,84.5 119.19,88.94 118.87,89.26 118.87,90.29 118.66,90.5 118.66,90.79 118.7,90.86 118.71,90.91 118.71,91.11 118.69,91.16 118.66,91.23 118.66,91.44 118.7,91.52 118.7,91.8 118.65,91.91 118.57,92.05 118.44,92.1 118.38,92.1 118.36,92.12 UC1.AY26
  BOTTOM w0.112: v2(140.19,57.6) 139.96,57.37 139.73,57.37 139.37,57.01 139.37,56.37 138.12,55.13 138.12,54.73 137.98,54.59 JDIMM1.240
DDR_A_MA0: length 43
  IN3 w0.076: v2(102.87,87.51) 104.19,86.19 104.19,77.35
  IN3 w0.183: v2(112.31,55.72) 112.29,55.72 109.93,58.08 109.93,63.88 104.19,69.62 104.19,77.35
  BOTTOM w0.076: v2(102.87,87.51) 103.46,88.1 103.46,89.21 104.04,89.79 104.04,90.42 103.91,90.54 103.91,90.79 103.94,90.87 103.95,90.88 103.97,90.91 103.97,91.05 103.9,91.28 103.9,91.41 103.98,91.63 104.18,91.83 UC1.AY50
  BOTTOM w0.183: JDIMM1.144 111.97,54.67 112.31,55 v2(112.31,55.72)
DDR_A_MA1: length 43.4
  IN3 w0.076: v2(102.87,86.88) 103.27,86.88 103.86,86.29 103.86,80.92 103.56,80.62 103.56,78.21 103.73,78.04 103.73,77.35
  IN3 w0.183: v2(108.83,60.43) 108.83,60.41 109.02,60.22 109.29,60.22 109.47,60.4 109.47,61.09 109.29,61.27 108.79,61.27 108.61,61.45 108.61,61.82 108.79,62 109.29,62 109.47,62.18 109.47,62.63 109.27,62.83 108.57,62.83 108.39,63.01 108.39,63.46 108.99,64.06 108.99,64.17 103.73,69.42 103.73,77.35
  BOTTOM w0.076: v2(102.87,86.88) 102.87,86.75 103.22,86.39 103.22,85.08 103.3,85 103.76,85 103.85,85.09 103.85,89.35 104.26,89.77 104.26,90.6 UC1.BB50
  BOTTOM w0.183: v2(108.83,60.43) 108.96,60.3 109.22,60.3 109.43,60.51 109.43,60.89 109.22,61.09 JDIMM1.133
DDR_A_MA2: length 45.5
  IN3 w0.076: 103.27,77.35 103.27,77.94 103.1,78.11 103.1,80.48 103.48,80.86 103.48,85 v2(102.87,85.61)
  IN3 w0.183: v2(108.86,56.63) 109.34,57.1 109.34,59.1 109.15,59.28 108.33,59.28 108.14,59.47 108.14,62.5 107.92,62.72 107.92,64.58 103.27,69.23 103.27,77.35
  BOTTOM w0.076: v2(102.87,85.61) 102.06,86.42 102.06,87.22 103.29,88.46 103.29,89.33 103.87,89.91 103.87,90.35 103.75,90.48 103.75,90.83 103.79,90.94 103.79,91.06 103.73,91.28 103.73,91.42 103.78,91.58 103.78,92.08 UC1.AY51
  BOTTOM w0.183: JDIMM1.132 108.97,55.12 109.16,55.31 109.81,55.31 109.99,55.49 109.99,55.86 109.81,56.04 108.9,56.04 108.72,56.22 108.72,56.48 v2(108.86,56.63)
DDR_A_MA3: length 43.8
  IN3 w0.076: 102.79,77.35 102.79,80.53 103.25,80.98 103.25,84.59 v2(102.87,84.97)
  IN3 w0.183: v2(108.83,57.89) 108.83,57.89 108.33,57.39 107.99,57.39 107.81,57.57 107.81,59.15 107.68,59.28 107.68,62.22 106.8,63.1 106.8,63.48 107.26,63.94 107.26,64.59 102.79,69.06 102.79,77.35
  BOTTOM w0.076: v2(102.87,84.97) 103.05,84.8 103.81,84.8 104.01,85 104.01,89.25 104.43,89.67 104.43,91.08 UC1.BA50
  BOTTOM w0.183: JDIMM1.131 108.72,61.06 108.39,60.72 108.39,58.34 108.83,57.9 v2(108.83,57.89)
DDR_A_MA4: length 44.2
  IN3 w0.076: v2(101,85.32) 101.44,85.32 101.62,85.14 101.62,81.44 101.14,80.96 101.14,78.67 100.73,78.27 100.73,77.35
  IN3 w0.183: 100.73,77.35 100.73,76.56 99.69,75.52 99.69,69.94 100.36,69.28 100.36,68.88 104.43,64.8 104.43,62.74 105.55,61.62 105.55,57.12 107.15,55.52 v2(107.54,55.52)
  BOTTOM w0.076: v2(101,85.32) 101.36,85.69 101.36,87.24 102.75,88.63 102.75,90.59 UC1.BB52
  BOTTOM w0.183: JDIMM1.128 107.97,54.52 108.53,55.07 108.53,55.68 108.35,55.86 107.73,55.86 107.54,55.68 v2(107.54,55.52)
DDR_A_MA5: length 46.3
  IN3 w0.076: v2(102.87,83.68) 102.31,83.68 102.13,83.5 102.13,81.16 102.06,81.09 102.06,78.53 101.7,78.17 101.7,77.35
  IN3 w0.183: v2(107.36,58.28) 107.28,58.2 106.66,58.2 106.47,58.39 106.47,58.71 106.58,58.81 106.73,58.81 106.93,59.02 106.93,59.29 106.75,59.47 106.66,59.47 106.47,59.66 106.47,62.06 105.88,62.65 105.88,64.66 102.33,68.21 102.33,68.21 101.81,68.73 101.81,69.88 101.6,70.09 100.86,70.09 100.64,70.31 100.64,70.99 100.87,71.22 100.87,71.72 100.64,71.95 100.64,72.45 100.87,72.68 100.87,73.18 100.64,73.41 100.64,73.91 100.87,74.14 100.87,74.65 100.64,74.87 100.64,75.16 101.7,76.22 101.7,77.35
  BOTTOM w0.076: v2(102.87,83.68) 101.9,83.68 101.71,83.88 101.71,87.11 103.09,88.49 103.09,90.26 103.28,90.46 103.28,90.82 103.28,90.82 103.25,90.91 103.25,91.11 103.28,91.2 103.28,91.2 103.29,91.2 103.29,91.21 103.29,91.44 UC1.BA51
  BOTTOM w0.183: JDIMM1.126 107.47,54.82 106.9,55.39 106.9,57.88 107.31,58.28 v2(107.36,58.28)
DDR_A_MA6: length 44.7
  IN3 w0.076: 101.22,77.35 101.22,78.12 101.6,78.5 101.6,81.03 101.88,81.31 101.88,85.15 v2(101.01,86.02)
  IN3 w0.183: v2(107.59,56.96) 107.3,57.25 106.75,57.25 106.01,57.98 106.01,61.84 105.36,62.49 105.36,64.53 100.82,69.07 100.82,69.47 100.18,70.11 100.18,75.35 101.22,76.39 101.22,77.35
  BOTTOM w0.076: UC1.BA52 102.59,91.07 102.59,88.69 101.2,87.31 101.2,86.21 v2(101.01,86.02)
  BOTTOM w0.183: JDIMM1.127 107.72,61.04 107.81,60.96 107.81,57.17 v2(107.59,56.96)
DDR_A_MA7: length 45.9
  IN3 w0.076: v2(101.01,84.02) 100.76,84.02 100.64,83.9 100.64,82.74 100.37,82.48 100.06,82.48 99.46,81.88 99.46,80.89 98.26,79.69 98.26,77.35
  IN3 w0.183: v2(104.79,57.89) 104.37,57.47 104.05,57.47 103.87,57.66 103.87,61.34 103.04,62.16 103.04,64.23 98.97,68.3 98.97,68.7 98.26,69.42 98.26,77.35
  BOTTOM w0.076: v2(101.01,84.02) 100.64,84.38 100.64,86.27 100.88,86.5 v1(100.88,86.93) 100.88,87.22 102.42,88.76 102.42,91.37 102.63,91.58 102.63,92.24 UC1.AW52
  BOTTOM w0.183: v2(104.79,57.89) 106.02,56.67 106.02,54.99 106.47,54.53 JDIMM1.122
DDR_A_MA8: length 44.6
  IN3 w0.076: 102.18,77.35 102.18,78.09 102.41,78.32 102.41,80.96 102.51,81.06 102.51,82.37 102.34,82.55 102.34,83.17 102.44,83.27 102.77,83.27 102.87,83.18 v2(102.87,83.04)
  IN3 w0.183: v2(107.19,60.43) 107.2,60.44 107.2,60.7 106.98,60.93 106.98,61.37 107.22,61.61 107.22,62 106.34,62.88 106.34,63.67 106.8,64.13 106.8,64.39 102.27,68.92 102.27,70.36 102.06,70.57 101.54,70.57 101.38,70.73 101.38,71.09 101.56,71.27 102.11,71.27 102.27,71.43 102.27,71.8 102.09,71.98 101.54,71.98 101.35,72.16 101.35,72.53 101.54,72.71 102.11,72.71 102.29,72.89 102.29,73.18 102.11,73.36 101.51,73.36 101.33,73.54 101.33,73.91 101.49,74.07 102.14,74.07 102.32,74.25 102.32,74.62 102.14,74.8 101.72,74.8 101.51,75.01 101.51,75.37 101.69,75.56 101.98,75.56 102.18,75.76 102.18,77.35
  BOTTOM w0.076: UC1.AY52 103.18,91.99 103.26,91.91 103.26,91.69 103.15,91.59 103.15,91.58 103.12,91.55 103.12,91.23 103.08,91.14 103.08,90.88 103.12,90.79 103.12,90.53 102.92,90.33 102.92,88.55 101.54,87.17 101.54,83 101.65,82.89 102.72,82.89 v2(102.87,83.04)
  BOTTOM w0.183: v2(107.19,60.43) 107.22,60.47 JDIMM1.125
DDR_A_MA9: length 43.6
  IN3 w0.076: v2(100.22,82.1) 99.97,82.1 99.74,81.88 99.74,80.61 99.18,80.04
  IN3 w0.183: 99.18,80.04 99.18,79.74 99.36,79.55 99.89,79.55 100.07,79.37 100.07,79 99.89,78.82 98.95,78.82 98.73,78.6 98.73,69.6 99.43,68.9 99.43,68.49 103.5,64.42 103.5,62.36 104.33,61.53 104.33,59.35 104.51,59.16 v2(104.79,59.16)
  BOTTOM w0.076: v2(100.22,82.1) 99.97,81.85 99.64,81.85 99.57,81.93 99.57,83.55 99.99,83.98 99.99,87.62 101.93,89.55 101.93,90.34 101.82,90.44 UC1.BB54
  BOTTOM w0.183: v2(104.79,59.16) 104.79,59.16 105.07,58.88 106.3,58.88 106.75,59.33 106.75,60.47 106.22,60.99 JDIMM1.121
DDR_A_MA10: length 46.2
  IN3 w0.076: 107.57,78.92 107.57,79.08 106.4,80.25 106.4,87.79 104.34,89.85 104.34,91.71 103.31,92.74 103.31,93.66 v2(103.69,94.04)
  IN3 w0.183: v2(113.97,58.02) 113.88,58.02 113.52,58.38 113.52,58.92 113.57,58.97 113.57,65.15 107.57,71.15 107.57,78.92
  BOTTOM w0.076: UC1.AT50 104.15,94.41 103.69,94.07 v2(103.69,94.04)
  BOTTOM w0.183: JDIMM1.146 114.48,54.64 113.51,55.6 113.51,57.56 v2(113.97,58.02)
DDR_A_MA11: length 44.7
  IN3 w0.076: 97.79,77.35 97.79,79.81 99.24,81.26 99.24,81.93 v2(100.22,82.91)
  IN3 w0.183: v2(104.79,56.62) 104.79,56.62 104.03,55.86 103.59,55.86 103.41,56.04 103.41,61.14 102.04,62.51 102.04,64.58 98.51,68.11 98.51,68.51 97.79,69.23 97.79,77.35
  BOTTOM w0.076: v2(100.22,82.91) 100.22,82.9 100.22,87.32 v1(101.42,88.52) 102.09,89.19 102.09,90.86 101.82,91.12 UC1.BA54
  BOTTOM w0.183: v2(104.79,56.62) 105.5,55.92 105.5,54.89 105.97,54.41 JDIMM1.120
DDR_A_MA12: length 45.5
  IN3 w0.076: v2(101.01,83.37) 101.38,83 101.38,81.58 100.67,80.88
  IN3 w0.183: v2(104.79,60.42) 104.9,60.42 105.09,60.61 105.09,61.43 103.97,62.55 103.97,64.61 99.9,68.68 99.9,69.09 99.21,69.77 99.21,76.77 99.36,76.92 100.01,76.92 100.24,77.15 100.24,77.41 100.06,77.6 99.24,77.6 99.06,77.78 99.06,78.14 99.24,78.33 100.21,78.33 100.67,78.79 100.67,80.88
  BOTTOM w0.076: v2(101.01,83.37) 100.9,83.37 100.39,83.88 100.39,86.96 102.26,88.83 102.26,91.34 102.03,91.56 102.03,92.23 101.95,92.32 101.43,92.32 101.33,92.42 101.33,92.56 101.4,92.64 UC1.AW54
  BOTTOM w0.183: JDIMM1.119 105.72,60.83 106.31,60.25 106.31,59.51 106.12,59.32 105.42,59.32 105.24,59.5 105.24,60.12 104.94,60.42 v2(104.79,60.42)
DDR_A_MA13: length 48.1
  IN3 w0.076: v2(105.52,93.52) 105.52,93.2 107.64,91.09 107.64,81.1 109.88,78.86 109.88,78.52
  IN3 w0.183: 109.88,78.52 109.88,72.12 115.88,66.12 115.88,61.7 116.88,60.7 116.88,59.15 116.05,58.32 116.05,56.17 116.33,55.89 116.76,55.89 116.94,56.07 v2(116.94,56.78)
  BOTTOM w0.076: UC1.AU46 105.7,93.52 v2(105.52,93.52)
  BOTTOM w0.183: v2(116.94,56.78) 116.94,56.68 117.47,56.14 JDIMM1.158
DDR_A_MA14: length 44.7
  IN3 w0.076: 109.42,78.65 109.42,78.96 107.39,80.98 107.39,90.97 105.15,93.2 105.15,94.03 105.23,94.1 v2(105.52,94.1)
  IN3 w0.183: v2(116.39,59.93) 116.39,59.92 115.99,59.53 115.69,59.53 115.42,59.81 115.42,60.25 115.6,60.43 115.76,60.43 115.94,60.61 115.94,60.98 115.76,61.16 115.6,61.16 115.42,61.34 115.42,65.93 109.42,71.93 109.42,78.65
  BOTTOM w0.076: UC1.AT46 106.04,94.39 106.04,94.26 105.78,93.99 105.58,93.99 105.52,94.05 v2(105.52,94.1)
  BOTTOM w0.183: JDIMM1.151 115.72,60.9 115.46,60.63 115.46,60.2 115.94,59.71 116.2,59.71 116.39,59.9 v2(116.39,59.93)
DDR_A_MA15: length 45.6
  IN3 w0.076: 108.49,78.82 108.49,79.08 106.91,80.67 106.91,88.45 105.48,89.87 105.48,92.19 104.61,93.06 v2(104.61,93.47)
  IN3 w0.183: v2(115.6,57.39) 115.3,57.39 115.1,57.59 115.1,58.82 114.49,59.42 114.49,65.53 108.49,71.53 108.49,78.82
  BOTTOM w0.076: v2(104.61,93.47) UC1.AU48
  BOTTOM w0.183: JDIMM1.156 116.98,56.01 115.6,57.38 v2(115.6,57.39)
DDR_A_MA16: length 45.4
  IN3 w0.076: v2(103.69,93.46) 103.98,93.17 103.98,92.42 105.26,91.15 105.26,89.75 106.65,88.35 106.65,80.38 108.03,79.01 108.03,78.82
  IN3 w0.183: v2(115.6,56.12) 115.59,56.12 114.47,57.24 114.47,58.79 114.03,59.23 114.03,65.34 108.03,71.34 108.03,78.82
  BOTTOM w0.076: UC1.AU50 103.69,93.47 v2(103.69,93.46)
  BOTTOM w0.183: v2(115.6,56.12) 115.97,55.74 JDIMM1.152
DDR_A_ODT0: length 50
  IN3 w0.076: 110.8,78.47 110.8,78.75 108.74,80.82 108.74,91.48 106.91,93.3 106.91,93.75 v2(107.33,94.17)
  IN3 w0.183: 110.8,78.47 110.8,72.51 117.28,66.03 117.28,63.11 117.47,62.93 118.64,62.93 118.82,62.74 118.82,62.38 118.64,62.2 117.47,62.2 117.28,62.01 117.28,61.61 117.6,61.28 118.64,61.28 118.82,61.1 118.82,60.61 118.55,60.34 117.99,60.34 117.81,60.15 117.81,59.34 v2(118.11,59.04)
  BOTTOM w0.076: UC1.AT45 106.89,94.71 107.21,95.03 107.42,95.03 107.53,94.92 107.53,94.37 v2(107.33,94.17)
  BOTTOM w0.183: JDIMM1.155 116.72,60.91 116.89,60.74 116.89,60.26 117.02,60.13 117.02,59.55 117.27,59.3 117.85,59.3 v2(118.11,59.04)
DDR_A_ODT1: length 52.4
  IN3 w0.076: 111.73,78.24 111.73,78.54 109.14,81.12 109.14,91.79 108.72,92.21 108.72,93.97 108.64,94.04 v2(108.26,94.04)
  IN3 w0.183: 111.73,78.24 111.73,72.89 117.62,66.99 118.21,66.99 118.39,66.81 118.39,64.48 118.57,64.3 118.94,64.3 119.12,64.48 119.12,66.07 119.3,66.25 119.78,66.25 119.96,66.07 119.96,63.78 119.75,63.56 119.75,62.98 119.96,62.76 119.96,62.25 119.75,62.03 119.75,61.51 119.96,61.3 119.96,60.78 119.75,60.57 119.75,60.23 119.05,59.53 119.05,58.71 119.49,58.27 119.75,58.27 v2(119.85,58.37)
  BOTTOM w0.102: UC1.AT43 107.75,94.39 107.76,94.24 107.99,94.03 v2(108.26,94.04)
  BOTTOM w0.183: v2(119.85,58.37) 119.72,58.24 119.33,58.24 119,58.57 119,59.98 118.22,60.75 118.22,61.9 JDIMM1.161
DDR_A_PARITY: length 42.7
  IN3 w0.076: 105.96,79.81 105.84,79.93 105.84,87.7 103.86,89.68 103.86,91.5 102.39,92.97 102.39,94.09 102.47,94.17 102.65,94.17 v2(102.78,94.04)
  IN3 w0.183: 105.96,79.81 106.64,79.13 106.64,70.74 112.64,64.74 112.64,64.37 112.32,64.05 112.32,63.73 112.64,63.41 112.64,63.1 112.32,62.78 112.32,61.93 112.64,61.61 112.64,60.92 112.48,60.75 v2(112.31,60.75)
  BOTTOM w0.076: v2(102.78,94.04) 102.89,93.93 102.97,93.93 103.31,94.27 103.31,94.38 UC1.AT52
  BOTTOM w0.183: JDIMM1.143 111.72,61.14 111.3,60.71 111.3,60.46 111.52,60.24 111.78,60.24 112.29,60.75 v2(112.31,60.75)
DDR_DRAMRST#: length 93.1
  TOP w0.112: RD11.2 RD12.2 104.49,52.44 104.95,51.98 v2(105.45,51.98)
  IN1 w0.119: v2(124.78,94.85) 125.25,94.39 125.25,92.97 129.88,88.34 133.06,88.34 134.33,87.07 134.33,86.18 137.31,83.2 v2(137.31,82.12)
  IN3 w0.135: v2(137.31,82.12) 136.8,81.61 136.8,80.47 137.62,79.64 137.62,78.76 138.02,78.37 138.02,77.1 141.41,73.71 141.41,69.87 143.22,68.07 143.22,64.74 143.71,64.25 143.71,58.76 143.13,58.18 143.13,55.55 142.56,54.98 137.92,54.98 137.5,54.56 106.13,54.56 104.96,53.39 104.96,52.46 v2(105.45,51.98)
  BOTTOM w0.076: v2(124.78,94.85) UC1.AT13
DDR_DRAMRST#_R: length 4.1
  TOP w0.112: RD12.1 102.74,52.59 CD29.1 102.2,52.63 v2(102.03,52.46) 101.9,52.46 v1(101.61,52.75)
  BOTTOM w0.112: JDIMM1.108 102.97,52.9 102.54,52.46 v2(102.03,52.46)
DDR_VTT_CTRL: length 26.7
  BOTTOM w0.076: 89.82,91.37 90.18,91.73 90.18,91.95 90.73,92.5 91.4,92.5 91.7,92.8 92.97,92.8 93.03,92.73 93.67,92.73 93.77,92.63 UC1.AW67
  BOTTOM w0.112: 89.82,91.37 89.7,91.25 89.7,90.07 88.5,88.87 88.5,88.52 88.09,88.1 83.93,88.1 v1(82.52,86.69) 80.22,84.4 73.98,84.4 73.09,83.51 UD1.2
DDR_XDP_WAN_SMBCLK: length 153.3
  IN1 w0.119: v2(152.44,89.45) 152.61,89.28 153.26,89.28 154.12,90.14 154.12,103.78 151.35,106.54 151.35,108.76 150.46,109.65 150.46,110.18 v2(150.26,110.37)
  IN3 w0.135: v2(150.26,110.37) 150.45,110.19 150.45,110 150.15,109.7 149.3,109.7 148.47,108.87 146.44,108.87 145.02,110.3 140.64,110.3 135.76,115.17 131.42,115.17 129.94,113.7 125.98,113.7 125.12,114.56 125.12,115.07 123.59,116.6 121.04,116.6 119.92,117.72 119.92,120.48 120.53,121.09 120.53,123.9 117.44,126.99 109.9,126.99 109.66,126.76 106.52,126.76 103.47,129.8 88.57,129.8 88.07,129.31 88.07,128.95 v2(87.91,128.79) ; v2(147.4,58.46) 147.55,58.32 147.71,58.32 147.98,58.59 147.98,63.32 147.13,64.16 147.13,65.65 147.31,65.83 147.31,69.22 145.15,71.38 145.15,79.68 146.16,80.69 146.16,85.05 147.01,85.9 147.01,87.5 150.06,90.55 150.82,90.55 152.08,89.29 152.28,89.29 v2(152.44,89.45)
  BOTTOM w0.112: JXDP1.53 87.91,129.36 88.1,129.17 88.1,128.98 v2(87.91,128.79) ; v2(147.4,58.46) 147.22,58.28 145.46,58.28 144.83,58.91 143.05,58.91 141.23,60.74 JDIMM1.253 ; RC319.1 150.26,110.93 v2(150.26,110.37) 150.88,109.75 QC2.1
DDR_XDP_WAN_SMBDAT: length 160.3
  IN1 w0.119: v2(152.44,88.87) 152.61,89.04 153.36,89.04 154.37,90.04 154.37,103.88 151.6,106.65 151.6,108.86 150.71,109.76 150.71,110.18 v2(150.9,110.37)
  IN3 w0.135: v2(88.5,128.79) 88.33,128.95 88.33,129.2 88.67,129.54 103.36,129.54 106.41,126.5 109.77,126.5 110.01,126.73 117.33,126.73 120.27,123.8 120.27,121.19 119.66,120.58 119.66,117.61 120.94,116.34 123.49,116.34 124.86,114.96 124.86,114.46 125.87,113.44 130.05,113.44 131.53,114.91 135.65,114.91 140.53,110.03 144.91,110.03 146.33,108.61 148.58,108.61 149.4,109.44 150.26,109.44 150.71,109.89 150.71,110.19 v2(150.9,110.37) ; v2(152.44,88.87) 152.28,89.03 151.97,89.03 150.71,90.29 150.16,90.29 147.27,87.39 147.27,85.79 146.42,84.94 146.42,80.58 145.41,79.57 145.41,71.49 147.57,69.33 147.57,65.72 147.39,65.54 147.39,64.27 148.24,63.43 148.24,58.48 147.82,58.05 147.58,58.05 v2(147.4,57.88)
  BOTTOM w0.112: v2(147.4,57.88) 147.24,58.04 145.37,58.04 144.73,58.67 143.08,58.67 142.26,57.86 142.26,55.38 141.47,54.59 JDIMM1.254 ; RC318.1 148.61,108.45 QC2.4 149.26,108.45 149.68,108.04 151.23,108.04 151.53,108.34 151.53,110.15 151.31,110.37 v2(150.9,110.37) ; v2(88.5,128.79) 88.34,128.95 88.34,129.17 88.51,129.34 JXDP1.51
DEBUG_TX: length 2.9
  BOTTOM w0.112: RE74.2 RE30.2 289.67,121.75 289.9,121.75 290.49,122.34 JDEG1.9
DIMM1_SA0: length 6.5
  TOP w0.112: v1(142.81,57.57) 142.81,57.25 143.36,56.7 RD5.1 143.53,56.77 v2(143.98,56.77) 144.42,56.77 RD4.2
  BOTTOM w0.112: JDIMM1.256 141.98,54.76 v2(143.98,56.77)
DIMM1_SA1: length 6.8
  TOP w0.112: v1(141.53,54.61) 142.12,55.21 142.98,55.21 143.36,55.59 RD7.1 143.55,55.7 v2(143.99,56.14) 144.44,55.7 RD6.2
  BOTTOM w0.112: JDIMM1.260 142.98,55.13 v2(143.99,56.14)
DIMM1_SA2: length 5.3
  TOP w0.112: RD9.1 RD8.2 v2(121.63,51.83)
  BOTTOM w0.112: JDIMM1.166 119.47,52.9 120.55,51.83 v2(121.63,51.83)
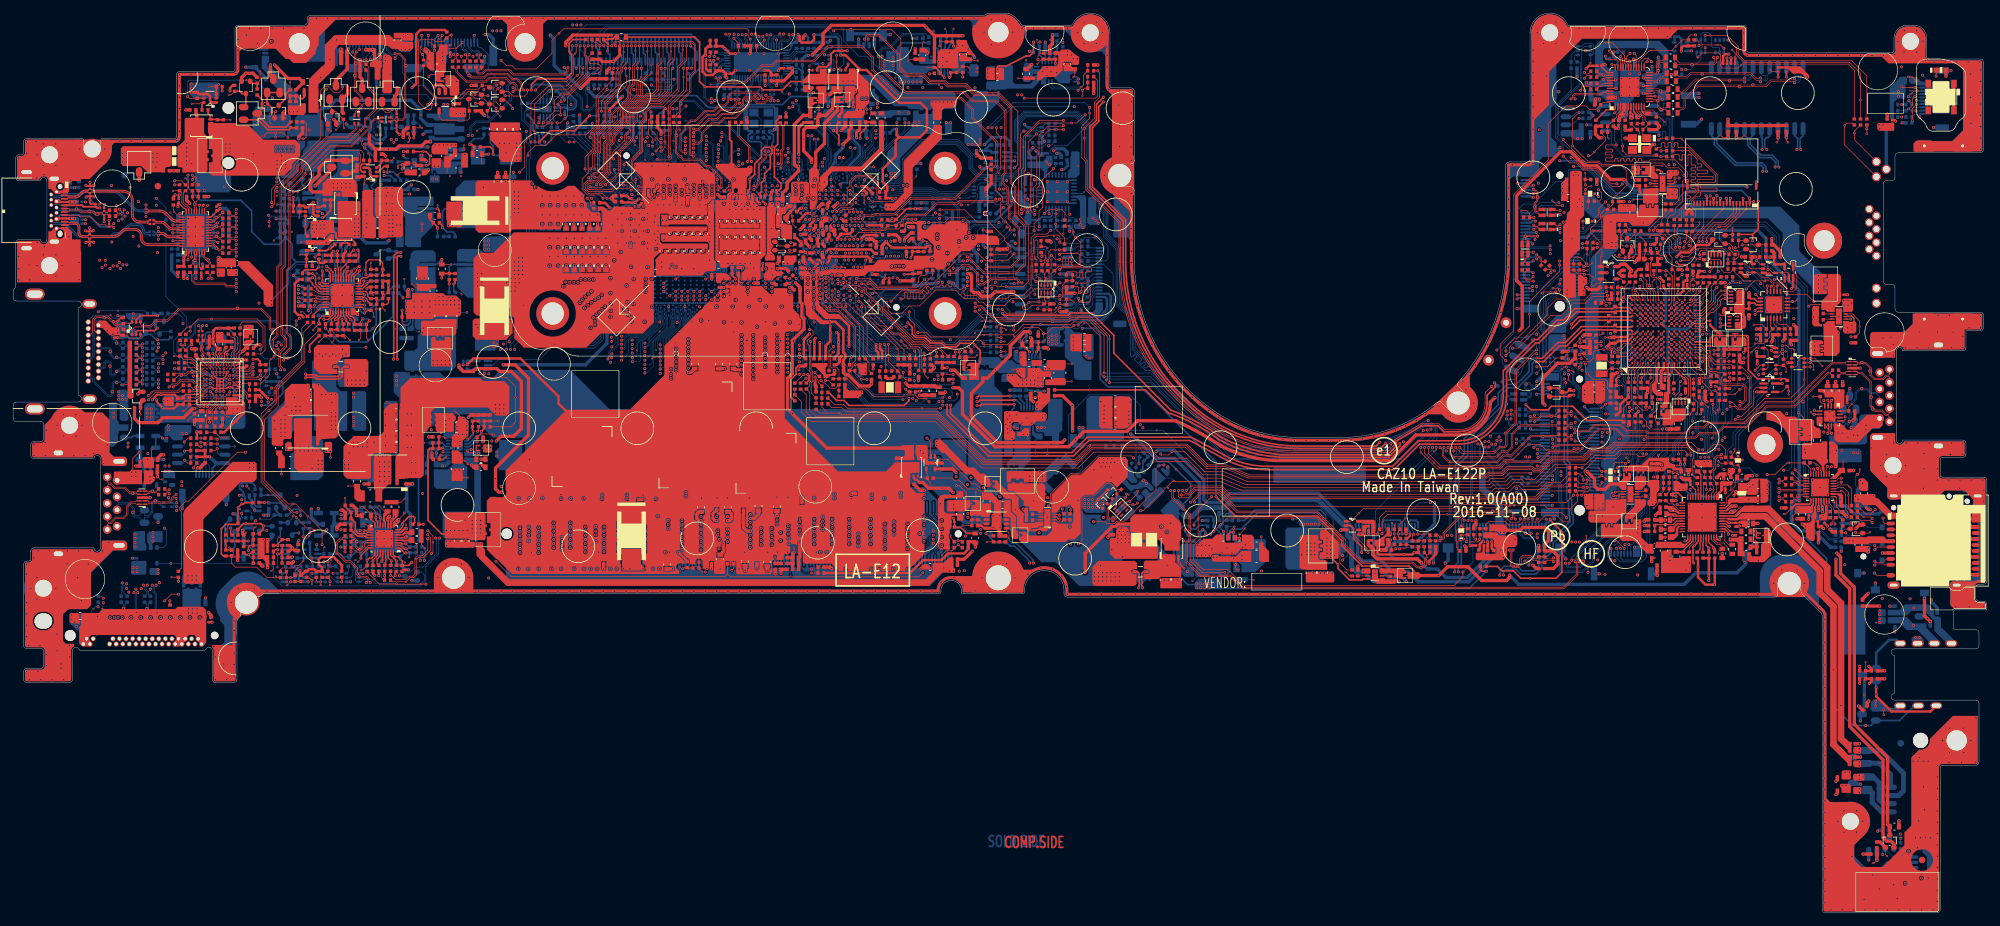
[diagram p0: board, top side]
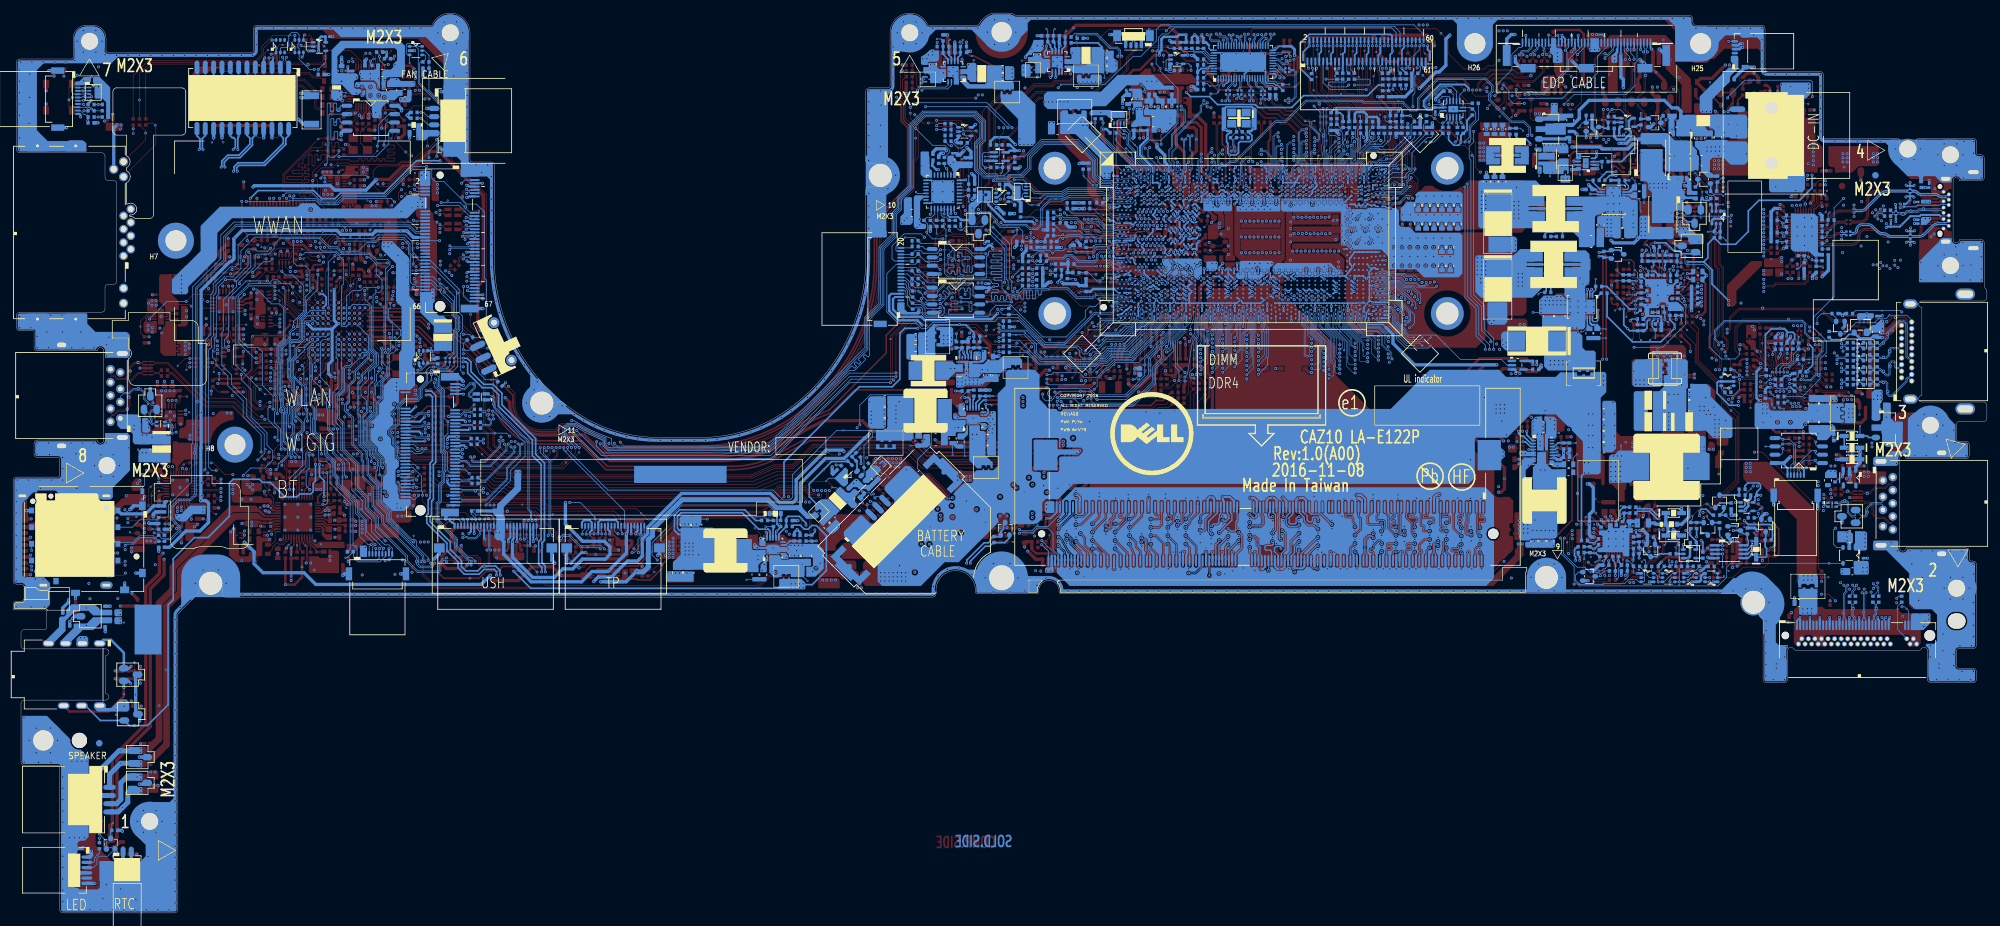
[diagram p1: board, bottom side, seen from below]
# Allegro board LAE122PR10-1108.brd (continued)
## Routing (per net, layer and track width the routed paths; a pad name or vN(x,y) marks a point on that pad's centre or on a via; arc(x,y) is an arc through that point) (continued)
DISP_ON: length 18.3
  TOP w0.102: RV2.1 72.24,121.5 v1(72.43,121.31)
  TOP w0.112: v2(69.77,124.82) 70.45,124.13 71.73,124.13 72.53,123.33 DV2.1 72.61,122.68 RV2.1
  BOTTOM w0.112: JEDP1.22 61.75,132.1 63.71,130.14 63.71,128.58 67.48,124.82 v2(69.77,124.82)
DMIC0: length 308.5
  TOP w0.107: CA6.1 53.31,128.98 53.31,129.97 53.47,130.12 v2(53.76,130.12)
  TOP w0.112: UA1.2 259.13,63.81 259.55,64.23 RA52.2 259.55,65.59 259.09,66.05 259.09,67.43 259.34,67.69 259.34,69.17 259.68,69.51 260.07,69.51 v2(260.25,69.33) ; v2(40.75,82.81) 40.75,83.06 40.48,83.34 40.48,85.47 41.43,86.42 41.43,87.49 40.79,88.13 40.79,98.23 41.27,98.71 v3(41.27,103.66) 41.27,110.49 43.82,113.05 43.82,113.59 48.01,117.78 51.2,117.78 53.49,120.07 53.49,120.99 55.06,122.55 55.06,124.8 53.97,125.89 53.97,128.32 CA6.1
  IN1 w0.119: v2(260.25,69.33) 260.07,69.5 259.34,69.5 258.93,69.92 256.45,69.92 255.67,70.71 252.28,70.71 250.15,68.57 248.72,68.57 245.41,65.26 244.1,65.26 241.61,62.77 237.88,62.77 236.55,61.43 236.55,60.87 236.09,60.41 236.09,59.02 233.49,56.42 232.23,56.42 231.77,55.97 228.67,55.97 227.74,56.9 227.74,58.04 227.35,58.43 214.27,58.43 213.96,58.74 199.46,58.74 199.01,58.29 195.62,58.29 195.16,58.76 182.85,58.76 181.82,57.73 180.16,57.73 179.05,58.84 177.02,58.84 176.4,59.45 172.24,59.45 168.25,63.44 162.86,63.44 162.49,63.82 150.8,63.82 146.41,68.21 87.48,68.21 76.93,78.76 57.44,78.76 56.61,77.93 45.02,77.93 40.91,82.04 40.91,82.65 v2(40.75,82.81)
  BOTTOM w0.107: JEDP1.7 54.25,131.07 53.76,130.58 v2(53.76,130.12)
DMIC_CLK0: length 305.3
  TOP w0.112: v2(54.43,130.12) 54.43,130.08 CA5.1 54.21,128.96 54.21,125.99 55.3,124.9 55.3,122.46 53.73,120.89 53.73,119.97 51.3,117.54 48.11,117.54 44.06,113.49 44.06,112.95 41.51,110.39 41.51,98.61 41.03,98.13 41.03,88.23 41.66,87.59 41.66,86.32 40.71,85.37 40.71,83.44 v2(41.34,82.81) ; v2(260.25,69.91) 260.08,69.74 259.58,69.74 259.1,69.27 259.1,67.82 CA54.1 RA14.1
  IN1 w0.119: v2(260.25,69.91) 260.09,69.75 259.44,69.75 259.03,70.17 256.56,70.17 255.77,70.95 252.18,70.95 250.04,68.82 248.62,68.82 245.31,65.51 244,65.51 241.5,63.02 237.78,63.02 236.3,61.54 236.3,60.98 235.84,60.52 235.84,59.12 233.39,56.67 232.12,56.67 231.67,56.21 228.78,56.21 227.99,57 227.99,58.14 227.46,58.68 214.37,58.68 214.06,58.99 199.36,58.99 198.91,58.54 195.73,58.54 195.26,59 182.75,59 181.72,57.97 180.26,57.97 179.15,59.08 177.12,59.08 176.5,59.7 172.34,59.7 168.35,63.69 162.96,63.69 162.59,64.06 150.91,64.06 146.51,68.46 87.58,68.46 77.03,79 57.33,79 56.51,78.18 45.12,78.18 41.16,82.14 41.16,82.64 v2(41.34,82.81)
  BOTTOM w0.107: JEDP1.9 55.25,131.37 54.43,130.55 v2(54.43,130.12)
DMIC_CLK_CODEC: length 2.4
  TOP w0.112: RA14.2 259.05,65.01 v1(259.05,64.53) 259.05,64.3 258.73,63.97 UA1.3
EC_FPM_EN: length 45.4
  TOP w0.107: UE1.D6 v2(248.68,87.46)
  IN3 w0.135: v2(231.47,60.03) 231.93,60.49 232.51,60.49 233.44,59.56 241.78,59.56 242.61,60.39 242.61,63.98 245.29,66.66 245.29,67.42 245.11,67.6 245.11,68.72 246.66,70.27 246.66,74.78 245.55,75.89 245.55,77.27 247.06,78.78 247.06,78.78 247.52,79.24 247.52,80.14 246.64,81.03 246.64,82.32 247.48,83.16 247.48,86.87 247.67,87.06 248.11,87.06 248.51,87.46 v2(248.68,87.46)
  BOTTOM w0.112: JUSH1.5 231.45,60.01 231.47,60.01 v2(231.47,60.03)
EDP_AUXN: length 63.9
  TOP w0.104: v2(76.16,125.82) 76.16,125.82 76.42,125.56 76.52,125.56 76.58,125.62 76.58,126.08 76.23,126.43 75.76,126.43 75.03,127.17 72.57,127.17 72.08,126.67 69.02,126.67 67.45,128.24 67.45,128.57 67.05,128.97 CV1.1
  IN1 w0.076: v2(106.48,110.86) 106.48,110.64 106.38,110.54 106.2,110.54 106.12,110.62 106.12,111.84 106.14,111.86 106.14,111.88
  IN1 w0.119: 106.14,111.88 106.14,112.23 106.87,112.97 106.87,114.1 106.97,114.2 106.97,117.5 107.4,117.93 107.4,121.23 107.51,121.34 107.51,124.46 104.6,127.36 104.6,128.61 103.64,129.57 82.84,129.57 80.16,126.88 77.63,126.88 76.49,125.74 76.24,125.74 v2(76.16,125.82)
  BOTTOM w0.089: v2(106.48,110.86) 106.75,110.59 UC1.E45
EDP_AUXN_C: length 3.2
  TOP w0.104: v2(67.11,130.88) 67.31,130.68 67.31,130.24 CV1.2
  BOTTOM w0.104: v2(67.11,130.88) 67.31,131.09 67.31,131.53 67.41,131.62 67.41,131.97 67.25,132.12 JEDP1.33
EDP_AUXP: length 63.8
  TOP w0.104: CV2.1 67.65,128.78 67.65,128.32 69.1,126.87 71.99,126.87 72.49,127.37 75.15,127.37 75.89,126.63 76.32,126.63 76.79,126.16 76.79,125.54 76.6,125.36 76.28,125.36 v2(76.16,125.24)
  IN1 w0.076: v2(106.48,110.2) 106.32,110.36 106.12,110.36 105.94,110.54 105.94,111.84 105.92,111.86 105.92,111.88
  IN1 w0.119: 105.92,111.88 105.92,112.32 106.66,113.06 106.66,114.19 106.75,114.29 106.75,117.59 107.18,118.02 107.18,121.32 107.29,121.43 107.29,124.37 104.38,127.27 104.38,128.52 103.55,129.35 82.93,129.35 80.25,126.67 77.72,126.67 76.58,125.52 76.45,125.52 76.33,125.41 76.33,125.41 v2(76.16,125.24)
  BOTTOM w0.089: v2(106.48,110.2) 106.75,110.2 106.89,110.06 UC1.F45
EDP_AUXP_C: length 3.2
  TOP w0.104: v2(67.69,130.88) 67.51,130.7 67.51,130.21 CV2.2
  BOTTOM w0.104: v2(67.69,130.88) 67.51,131.06 67.51,131.44 67.61,131.54 67.61,131.98 67.75,132.13 JEDP1.34
EDP_BIA_PWM: length 94.8
  TOP w0.112: DV1.3 74.35,126.68 73.5,126.68 73.24,126.41 73.24,123.01 v2(73.58,122.67) 73.58,122.08 v1(74.23,121.44)
  IN2 w0.124: v2(73.58,122.67) 74.24,122.01 81.76,122.01 82.59,122.85 85.58,122.85 86.42,123.68 97.38,123.68 98.55,124.85 105.05,124.85 105.28,125.08 109.47,125.08 109.68,125.29 117.11,125.29 117.58,125.77 119.96,125.77 121.1,124.63 128.28,124.63 129.11,125.46 131.77,125.46 133.25,123.98 133.25,121.73 132.82,121.3 132.82,113.93 131.65,112.76 131.65,105.71 130.34,104.4 127.36,104.4 v2(126.92,104.84)
  BOTTOM w0.102: UC1.R11 126.92,104.85 v2(126.92,104.84)
EDP_COMP: length 1.7
  TOP w0.381: RC2.1 102.7,110.08 v2(102.7,110.93)
  BOTTOM w0.254: UC1.E52 103.04,110.59 v2(102.7,110.93)
EDP_HPD: length 106.9
  TOP w0.102: v1(63.23,132.75) 63.61,132.75 RV7.1
  TOP w0.107: v2(64.21,131.53) RV7.1
  TOP w0.112: RC1.1 126.92,106.4 v2(127.4,106.88)
  IN2 w0.124: v2(70.37,124.8) 73.58,121.59 81.66,121.59 82.66,122.59 86.82,122.59 86.94,122.46 88.37,122.46 89.3,123.4 97.48,123.4 98.7,124.62 105.18,124.62 105.38,124.83 109.6,124.83 109.84,125.07 117.2,125.07 117.67,125.54 119.81,125.54 120.94,124.41 128.38,124.41 129.21,125.23 131.67,125.23 132.79,124.12 132.79,121.99 132.36,121.56 132.36,113.85 131.39,112.89 131.39,106.13 130.62,105.36 127.52,105.36 127.23,105.65 127.23,106.71 v2(127.4,106.88)
  BOTTOM w0.076: v2(127.4,106.88) UC1.L10
  BOTTOM w0.107: JEDP1.26 63.75,131.99 v2(64.21,131.53)
  BOTTOM w0.112: v2(64.21,131.53) 63.97,131.29 63.97,128.71 67.65,125.03 69.11,125.03 69.32,125.25 69.92,125.25 v2(70.37,124.8)
EDP_TXN0: length 54.6
  TOP w0.104: CV4.1 69.26,128.61 69.26,128.19 69.97,127.48 71.71,127.48 72.23,128 75.38,128 76.14,127.24 76.81,127.24 77.59,126.45 77.59,125.66 v2(77.78,125.47)
  IN1 w0.119: v2(77.78,125.47) 77.78,125.47 77.42,125.11 77.42,124.94 77.53,124.83 80.42,124.83 82.65,127.06 98.6,127.06 100.13,125.53 101.59,125.53 104.29,122.83 104.29,116.28 105,115.56 105.23,115.56 v2(105.61,115.94)
  BOTTOM w0.076: UC1.C47 105.72,112.27
  BOTTOM w0.089: v2(105.61,115.94) 105.41,115.75 105.3,115.75 105.06,115.5 105.06,114.13 105.72,113.47 105.72,112.27
EDP_TXN0_C: length 3.6
  TOP w0.104: CV4.2 69.29,130.21 69.29,130.67 v2(69.48,130.86)
  BOTTOM w0.104: JEDP1.36 68.75,132.14 68.58,131.96 68.58,131.82 68.81,131.58 68.98,131.58 69.27,131.29 69.27,131.06 v2(69.48,130.86)
EDP_TXN1: length 53.6
  TOP w0.104: v2(83.95,128.91) 84.04,128.91 84.13,128.82 84.13,128.73 84.34,128.52 84.34,128.37 83.92,127.95 76.29,127.95 75.63,128.61 71.98,128.61 71.46,128.09 70.9,128.09 70.79,128.21 70.79,128.45 70.89,128.56 71.29,128.56 71.4,128.66 CV6.1
  IN1 w0.119: v2(83.95,128.91) 84.06,128.81 84.06,128.39 84.4,128.05 98.31,128.05 100.31,126.05 101.79,126.05 104.71,123.13 104.71,117.41 105,117.12 v2(105.61,117.12)
  BOTTOM w0.076: v2(105.61,117.12) 105.88,117.39 106.2,117.39 106.52,117.07 106.52,113.88 106.64,113.76 106.65,113.76 106.86,113.55 106.86,113.21 106.84,113.16 106.84,112.79 106.85,112.77 106.85,112.58 106.77,112.32 106.74,112.29 106.47,112.29 106.31,112.13 106.31,111.97 UC1.D46
EDP_TXN1_C: length 4.3
  TOP w0.104: v2(71.25,130.85) 71.04,130.64 71.04,130.24 CV6.2
  BOTTOM w0.104: v2(71.25,130.85) 71.07,131.03 71.07,131.27 70.84,131.49 69.96,131.49 69.59,131.86 69.59,132.01 69.75,132.17 JEDP1.38
EDP_TXP0: length 54.7
  TOP w0.104: CV3.1 69.06,128.63 69.06,128.07 v3(69.46,127.67) 69.85,127.28 71.8,127.28 72.31,127.8 75.3,127.8 76.06,127.04 76.72,127.04 77.39,126.37 77.39,125.67 v2(77.19,125.47)
  IN1 w0.119: v2(105.61,115.35) 104.91,115.35 104.07,116.18 104.07,122.74 101.5,125.31 100.04,125.31 98.51,126.84 82.74,126.84 80.51,124.61 77.44,124.61 77.19,124.86 v2(77.19,125.47)
  BOTTOM w0.089: v2(105.61,115.35) 105.61,115.46 105.5,115.56 105.38,115.56 105.24,115.43 105.24,114.21 105.91,113.54 105.91,112.72 105.97,112.65 106.23,112.65 106.34,112.54 106.34,112.4 106.21,112.28 106.09,112.28 UC1.C46
EDP_TXP0_C: length 3.6
  TOP w0.104: CV3.2 69.09,130.24 69.09,130.67 v2(68.9,130.86)
  BOTTOM w0.104: JEDP1.35 68.25,132.1 68.38,131.97 68.38,131.73 68.73,131.38 68.9,131.38 69.07,131.21 69.07,131.04 v2(68.9,130.86)
EDP_TXP1: length 53.5
  TOP w0.104: CV5.1 70.59,128.89 70.59,128.12 70.82,127.89 71.55,127.89 72.06,128.41 75.55,128.41 76.21,127.75 84,127.75 84.54,128.29 84.54,128.9 v2(84.54,128.9)
  IN1 w0.119: v2(105.61,117.77) 105.51,117.67 105.51,117.59 105.46,117.53 105.43,117.53 105.24,117.34 105.09,117.34 104.93,117.5 104.93,123.22 101.88,126.27 100.4,126.27 98.4,128.27 84.49,128.27 84.28,128.48 84.28,128.65 84.37,128.74 84.37,128.8 84.47,128.9 v2(84.54,128.9)
  BOTTOM w0.076: UC1.C45 106.59,111.91 106.67,111.83 106.77,111.83 106.88,111.94 106.88,112.07 107.02,112.55 107.02,112.8 107.01,112.82 107.01,113.13 107.03,113.18 107.03,113.62 106.72,113.93 106.72,113.93 106.69,113.96 106.69,117.15 106.27,117.56 105.81,117.56 v2(105.61,117.77)
EDP_TXP1_C: length 4.3
  TOP w0.104: CV5.2 70.84,130.21 70.84,130.67 v2(70.66,130.85)
  BOTTOM w0.104: JEDP1.37 69.25,132.16 69.39,132.01 69.39,131.78 69.88,131.29 70.76,131.29 70.86,131.19 70.86,131.05 v2(70.66,130.85)
EDRAM_OPIO_RCOMP: length 2.3
  TOP w0.381: v2(94.24,108.89) 93.96,108.89 v1(93.65,109.21) 93.5,109.36 RC90.1
  BOTTOM w0.254: UC1.H66 94.44,108.7 v2(94.24,108.89)
EMMC_RCOMP: length 6.7
  BOTTOM w0.102: v1(138.26,94.56) 138.09,94.74 RC4.1
  BOTTOM w0.203: UC1.AT1 132.35,94.56 132.93,95.13
  BOTTOM w0.381: 132.93,95.13 136.17,95.13 136.56,94.74 RC4.1
EN_0.6V: length 7.1
  TOP w0.112: PC222.1 v4(73.91,75)
  TOP w0.254: v2(71.33,73.43) 71.77,73.86 PR210.2 71.77,74.99 PR212.1 PC222.1
  BOTTOM w0.254: PU200.2 69.45,71.56 70.61,72.72 70.97,72.72 71.33,73.09 v2(71.33,73.43)
EN_1.0V_PRIM_COREP: length 9
  TOP w0.102: v2(162.91,125.44) v1(162.91,124.61)
  TOP w0.112: v2(162.91,125.44) 163.22,125.74 PC411.1 PR407.1 PR406.2
  BOTTOM w0.112: v2(162.91,125.44) 162.43,125.92 158.6,125.92 158.25,126.26 PU402.13
EN_1.2V: length 6
  TOP w0.112: v2(70.1,73.43) 70.1,73.11 v4(69.25,72.26)
  TOP w0.254: v2(70.1,73.43) 69.99,73.54 PR208.2 70,74.14 PC221.1 PR209.1
  BOTTOM w0.254: PU200.1 69.23,72.01 70.1,72.88 v2(70.1,73.43)
EN_1.8VALW: length 1.8
  BOTTOM w0.112: PC505.1 176.42,66.29 v1(176.82,65.89)
EN_1VS_VCCIO: length 5.2
  TOP w0.112: v1(145.71,128.77) 145.43,129.06 PR402.2 144.58,129.06 143.72,128.2 PR403.1
  TOP w0.254: PR403.1 PC402.1 142.84,127.58 v2(142.64,127.39)
  BOTTOM w0.254: v2(142.64,127.39) 142.38,127.66 PU401.13
EN_2.5V: length 5.3
  TOP w0.112: PU503.5 151.35,58.34 151.71,57.97 151.71,57.14 PR514.1 PC513.1 PR513.2 v1(148.32,56.58)
EN_+1VALWP: length 2.6
  BOTTOM w0.254: PU301.1 156.53,85.64 156.11,86.07 PR302.1 PR312.1
EN_INVPWR: length 275.8
  TOP w0.107: 246.09,82.62 247.06,83.6 247.06,84.24 UE1.B2
  TOP w0.112: QV2.2 39.82,121.98 v2(40.03,122.18) ; v2(242.61,76.1) v1(243.14,76.1) ; 246.09,82.62 v2(246.09,81.54) RE55.1
  IN1 w0.119: v2(246.09,81.54) 245.24,81.54 243,79.31 243,76.49 v2(242.61,76.1)
  IN2 w0.124: v2(40.03,122.18) 40.03,122.67 42.66,125.3 46.59,125.3 47.53,126.24 48.53,126.24 49.57,125.2 61.49,125.2 63.69,127.4 74.36,127.4 74.72,127.04 80.09,127.04 83.74,130.69 104.23,130.69 104.68,131.15 108.6,131.15 109.46,130.28 117.52,130.28 118.75,131.51 124.08,131.51 124.71,130.87 124.71,130.65 125.2,130.17 126.42,130.17 126.95,130.69 130.01,130.69 130.91,131.6 134.47,131.6 135.79,132.92 140.38,132.92 140.6,132.7 145.13,132.7 147.95,129.88 155.78,129.88 156.42,129.23 156.42,125.7 160.99,121.14 160.99,117.94 162.61,116.32 162.61,110.32 167.01,105.91 167.01,90.14 168.93,88.23 168.93,85.75 171.4,83.28 171.4,80.7 181.35,70.74 184.46,70.74 186.18,69.02 206.17,69.02 207.44,67.75 222.1,67.75 222.76,68.41 226.35,68.41 227.39,69.45 229.06,69.45 231.44,71.83 232.5,71.83 234.11,73.45 235.04,73.45 235.94,74.34 235.94,75.3 236.6,75.96 236.6,76.84 236.93,77.17 238.39,77.17 239.08,76.47 242.24,76.47 v2(242.61,76.1)
EN_LCDPWR: length 8.9
  TOP w0.112: UV24.4 64.9,121.35 65.38,120.87 v1(66.09,120.87) 69.23,120.87 69.56,121.2 69.56,122.24 RV3.2 69.43,122.36 DV3.1
EN_PD_HV_1: length 81.4
  TOP w0.112: PR1260.1 38.7,51.13 37.11,52.72 33.87,52.72 33.29,53.3 PR1210.1 ; v2(46,100.02) 46.34,100.37 PQ1214.5 ; RT70.1 34.57,89.74 34.95,90.12 37.17,90.12 38.06,89.23 38.06,86.35 v2(37.66,85.94)
  TOP w0.203: PR1210.1 32.42,54.43 PR1250.2
  TOP w0.254: PR1250.2 32.04,54.42 31.71,54.75 31.71,58.56 32.41,59.26 34.11,59.26 PR1254.1 v4(34.25,61.8) v2(34.82,62.37) 35.14,62.37 35.33,62.56 PR1211.1
  IN2 w0.124: v2(37.66,85.94) 37.29,85.57 37.29,80.86 35.74,79.31 35.74,73.06 34.29,71.62 34.29,67.44 36.17,65.56 36.17,63.88 35.39,63.11 35.39,62.69 35.08,62.37 v2(34.82,62.37)
  BOTTOM w0.112: v2(46,100.02) 46,99.08 45.76,98.84 43.12,98.84 42.19,97.91 42.19,86.22 40.44,84.47 38.33,84.47 37.66,85.13 v2(37.66,85.94)
EN_PD_HV_1#: length 2.7
  TOP w0.112: v1(43.7,100.37) PQ1214.2
  TOP w0.254: PQ1214.2 PQ1214.3 44.69,98.67 PR1253.2
EN_PD_HV_1_R: length 5.9
  TOP w0.076: UT5.C2 33.27,83.22 33.27,83.8 33.88,84.42 33.88,84.51
  TOP w0.112: RT70.2 34.57,85.74 v1(34.41,85.59) 34.08,85.26 34.08,84.71 33.88,84.51
ENLDO_3V5V: length 64.9
  TOP w0.254: v2(152.53,78.18) 147.31,78.18 147.09,77.96 v2(146.84,77.96)
  IN3 w0.203: v2(179.91,59.12) 179.91,58.95 178.9,57.94 178.9,57.92 177.49,57.92 176.81,58.61 175.59,58.61 175.26,58.28 174.34,58.28 173.35,59.27 168.35,59.27 167.51,58.43 166.47,58.43 166.17,58.13 162.71,58.13 160.7,60.13 160.7,64.22 157.55,67.37 150.75,67.37 146.35,71.77 146.35,77.56 146.76,77.96 v2(146.84,77.96)
  BOTTOM w0.254: PU100.11 153.56,77.5 152.88,78.18 v2(152.53,78.18) ; v2(179.91,59.12) 179.91,59.43 v4(180.52,60.04) 180.94,60.46 182.65,60.46 182.92,60.2 PR103.1 PR102.1 182.92,58.9 184.04,57.78 PU102.11
ENVDD_PCH: length 449.9
  TOP w0.107: UE1.L12 255.08,93.06 255.63,93.06 255.88,93.31 255.88,93.57 256.97,94.65 v2(256.97,94.82)
  TOP w0.112: v2(63.17,123.28) 64.01,124.12 68.21,124.12 69.38,125.28 70.79,125.28 DV3.3 71.47,124.6 v2(72.34,124.6) ; v2(63.73,54.79) 63.96,55.02 v1(63.96,56.5) 63.96,57.49 v2(63.18,58.27)
  IN1 w0.119: v2(261.69,70.27) 262.15,70.72 263.29,70.72 263.55,70.47 263.55,69.51 263.94,69.12 263.94,67.26 261.59,64.91 259.76,64.91 259.36,65.31 252.4,65.31 250.73,63.65 248.73,63.65 245.01,59.93 245.01,58.66 242.97,56.62 242.97,52.05 v2(242.53,51.61)
  IN2 w0.124: v2(261.69,70.27) 261.69,71.17 265.33,74.8 265.33,78.45 266.09,79.21 266.09,81.34 264.52,82.91 264.52,87.48 262.45,89.55 262.45,91.98 261.75,92.69 260.57,92.69 258.31,94.94 257.96,94.94 257.83,94.82 v2(256.97,94.82) ; v2(242.53,51.61) 241.23,50.31 213.55,50.31 212.92,50.94 211,50.94 209.49,49.43 183.89,49.43 182.59,50.73 180.08,50.73 178.81,49.46 173.06,49.46 169.67,52.85 160.68,52.85 158.36,55.17 148.48,55.17 146.68,53.37 142.36,53.37 138.81,50.63 74.62,50.63 71.11,54.14 70.06,54.14 69.08,55.12 64.06,55.12 v2(63.73,54.79) ; v2(125.07,104.81) 125.98,103.9 130.48,103.9 132.18,105.6 132.18,112.55 133.27,113.64 133.27,121.09 133.7,121.52 133.7,124.16 131.95,125.91 122.52,125.91 121.78,126.65 120.78,126.65 120.35,126.22 117.35,126.22 116.88,125.74 105.27,125.74 104.83,125.31 98.27,125.31 97.38,124.42 94.05,124.42 93.43,125.04 91.53,125.04 90.67,124.19 85.52,124.19 84.76,124.95 82.02,124.95 80.1,123.03 73.9,123.03 v2(72.34,124.6) ; v2(63.18,58.27) 64.19,59.27 64.19,65.11 62.2,67.09 62.2,74.64 72.77,85.2 72.77,88.73 73.1,89.06 73.1,103.24 72.44,103.9 71.42,103.9 70.51,104.81 70.51,110.91 70.18,111.24 62.41,111.24 60.41,113.23 60.41,115.45 61.74,116.79 61.74,119.57 63.17,120.99 v2(63.17,123.28)
  BOTTOM w0.102: UC1.U13 125.13,104.75 v2(125.07,104.81)
EOPIO_RCOMP: length 3.4
  TOP w0.381: v2(95.31,108.87) v1(94.76,108.32) 92.86,108.32 RC91.1
  BOTTOM w0.254: UC1.H65 95.6,108.87 v2(95.31,108.87)
ESPI_ALERT#: length 184.4
  TOP w0.107: UE1.H7 v2(252.68,88.26)
  TOP w0.112: v2(144.12,85.53) 144.22,85.43 RC21.1
  IN2 w0.124: v2(144.12,85.53) 144.85,84.8 144.85,83.49 148.21,80.13 148.21,72.38 150.14,70.45 150.47,70.45 151.11,69.8 159.65,69.8 163.05,66.4 172.69,66.4 175.79,63.3 178.15,63.3 178.68,63.82 180.59,63.82 181.39,63.03 202.82,63.03 204,61.85 214.35,61.85 215.39,60.81 218.48,60.81 219.18,61.52 226.04,61.52 227.02,60.54 235.06,60.54 235.34,60.82 236.77,60.82 237.66,59.93 239.17,59.93 242,62.76 243.62,62.76 244.66,63.79 244.66,65.3 247.87,68.51 248.97,68.51 250.81,70.36 253.3,70.36 253.74,70.8 255.87,70.8 256.51,70.17 257.17,70.17 257.4,70.39 v2(257.4,70.6)
  BOTTOM w0.076: 128.37,88.4 128.26,88.4 127.47,89.19 126.94,89.19 125.86,90.27 125.86,91.42 125.97,91.53 UC1.AY11
  BOTTOM w0.112: v2(257.4,70.6) 257.66,70.85 257.66,72.47 256.5,73.62 256.5,74.78 257.46,75.74 257.46,76.48 256.72,77.23 256.72,80.33 258.21,81.83 258.21,84.21 257.54,84.87 257.54,85.88 257.22,86.2 256.55,86.2 255.51,87.24 255.51,87.62 255.28,87.85 253.06,87.85 252.68,88.22 v2(252.68,88.26) ; 128.37,88.4 v1(128.66,88.12) 130.96,85.81 133.87,85.81 134.64,85.04 135.66,85.04 136.36,84.34 139.03,84.34 139.53,84.85 143.43,84.85 v2(144.12,85.53)
ESPI_CLK: length 28.6
  BOTTOM w0.076: 128.83,89.72 128.42,89.72 127.94,90.21 127.34,90.21 127.08,90.46 127.08,90.83 127.13,90.94 127.13,91.06 127.07,91.28 127.07,91.42 127.18,91.73 127.18,91.84 127.34,92.36 UC1.AW9
  BOTTOM w0.102: 130.43,88.4 130.15,88.4 128.83,89.72
  BOTTOM w0.112: 130.43,88.4 131.67,87.16 134.16,87.16 135.27,86.05 136.28,86.05 137.11,85.23 137.67,85.23 137.9,85.46 137.9,85.89 138.44,86.43 143.59,86.43 147.4,90.24 v1(147.66,90.24) RC16.1
ESPI_CLK_5105: length 170.6
  TOP w0.107: UE1.G7 v2(251.08,88.26)
  TOP w0.112: v1(149.76,89.29) 150.21,89.75 v2(150.52,89.75) ; RE350.1 248.89,74.88 248.89,74.26 249.37,73.78 251.27,73.78 v2(251.28,73.79)
  IN3 w0.135: v2(243.44,53.83) 243.01,53.41 240.15,53.41 239.63,52.89 232.25,52.89 231.08,54.05 230.53,54.05 228.83,55.75 226.69,55.75 224.68,57.77 222.84,57.77 222.38,58.23 214.06,58.23 213.05,59.24 201.46,59.24 200.92,59.78 200.86,59.78 200.71,59.93 182.98,59.93 181.73,61.18 178.61,61.18 177.9,61.89 173.47,61.89 170.71,64.64 162.9,64.64 159.26,68.28 151.07,68.28 147.32,72.03 147.32,84.47 148.73,85.89 148.73,87.52 149.59,88.38 149.59,88.83 150.5,89.75 v2(150.52,89.75)
  BOTTOM w0.112: RC16.2 CC316.1 150,89.36 150.39,89.75 v2(150.52,89.75) ; v2(243.44,53.83) 242.95,54.32 JESPI.10 242.95,55.62 243.45,56.12 244.08,56.12 246.07,58.11 246.07,59.93 247.51,61.37 247.51,62.89 249.11,64.49 249.11,67.15 249.45,67.5 249.45,68.57 251.28,70.39 v2(251.28,73.79) 252.03,74.53 252.03,79.27 251.23,80.07 251.23,84.42 251.48,84.67 251.48,87.86 v2(251.08,88.26)
ESPI_CS#: length 191.8
  TOP w0.107: UE1.H6 v2(252.68,87.46)
  IN3 w0.135: v2(244.27,55.59) 243.05,54.37 235.3,54.37 235.1,54.57 230.74,54.57 229.05,56.27 226.91,56.27 224.89,58.29 223.06,58.29 222.48,58.87 214.15,58.87 213.26,59.76 201.67,59.76 201.14,60.3 201.07,60.3 200.92,60.45 183.22,60.45 181.98,61.7 178.88,61.7 178.15,62.42 173.67,62.42 170.93,65.16 163.11,65.16 159.47,68.8 151.3,68.8 147.85,72.24 147.85,84.27 149.25,85.68 149.25,87.31 v2(150.52,88.58)
  BOTTOM w0.076: 129.03,87.26 127.3,88.99 126.88,88.99 125.69,90.18 125.69,91.63 UC1.BA12
  BOTTOM w0.112: JESPI.7 244.45,55.41 v2(244.27,55.59) 246.84,58.15 246.84,59.93 248,61.1 248,62.67 250.49,65.16 250.49,68.54 252.07,70.11 252.07,72.95 252.83,73.71 252.83,76.84 252.97,76.99 252.97,78.38 252.58,78.78 252.58,80.34 253.9,81.66 253.9,86.99 253.43,87.46 v2(252.68,87.46) ; v2(150.52,88.58) 150.47,88.58 150.44,88.61 146.69,88.61 v1(146.56,88.49) 144.8,86.73 144.8,85.48 143.91,84.59 139.66,84.59 139.15,84.08 136.23,84.08 135.53,84.78 134.52,84.78 133.72,85.58 130.71,85.58 129.03,87.26
ESPI_IO0: length 159.2
  TOP w0.107: UE1.K5 v2(254.28,86.66)
  TOP w0.112: v2(150.51,85.6) v1(151.18,85.6)
  IN3 w0.135: v2(246.15,56.16) 245.13,57.18 243.33,57.18 241.57,55.42 235.66,55.42 232.52,58.56 228.13,58.56 225.91,60.77 218.53,60.77 217.67,59.91 214.44,59.91 213.65,60.71 202.07,60.71 201.38,61.4 183.7,61.4 180.24,64.86 176.3,64.86 176.14,65.01 172.41,65.01 171.32,66.1 163.5,66.1 159.86,69.74 151.69,69.74 148.79,72.64 148.79,83.88 v2(150.51,85.6)
  BOTTOM w0.112: JESPI.3 246.45,55.86 v2(246.15,56.16) 246.64,56.16 247.98,57.5 247.98,60.36 248.51,60.89 248.51,62.57 251.27,65.32 251.27,66.34 251.78,66.85 251.78,68.71 253.02,69.95 253.02,71.42 254.84,73.24 254.84,75.27 254.76,75.35 254.76,77.02 255.31,77.57 255.31,84.59 255.59,84.87 255.59,85.93 255.28,86.24 254.7,86.24 v2(254.28,86.66) ; v2(150.51,85.6) 150.39,85.48 RC366.2
ESPI_IO0_R: length 30.6
  BOTTOM w0.076: 127.01,87.83 124.95,89.89 124.95,90.39 124.83,90.52 124.83,90.79 124.88,90.91 124.88,91.05 124.82,91.28 124.82,91.4 124.89,91.61 124.99,91.72 125.09,91.83 UC1.AY13
  BOTTOM w0.112: RC366.1 146.33,85.48 144.42,83.58 140.16,83.58 139.65,83.07 137.44,83.07 136.83,82.46 136.27,82.46 134.92,83.81 134.05,83.81 133.16,84.7 130.34,84.7 v1(127.2,87.83) 127.01,87.83
ESPI_IO1: length 158.9
  TOP w0.107: UE1.L4 v2(255.08,85.86)
  TOP w0.112: v2(150.51,87.13) v1(151.06,87.13)
  IN3 w0.135: v2(245.55,56.16) 245.41,56.31 243.19,56.31 241.78,54.89 235.45,54.89 235.15,55.19 231.14,55.19 228.3,58.04 227.98,58.04 227.21,58.81 223.2,58.81 222.67,59.34 214.35,59.34 213.45,60.24 201.87,60.24 201.33,60.77 201.27,60.77 201.12,60.93 183.46,60.93 182.22,62.17 179.14,62.17 178.36,62.95 173.8,62.95 171.12,65.63 163.31,65.63 159.67,69.27 151.49,69.27 148.32,72.44 148.32,84.08 149.81,85.57 149.81,86.43 v2(150.51,87.13)
  BOTTOM w0.112: v2(150.51,87.13) 149.96,87.13 RC367.2 ; v2(255.08,85.86) 254.69,85.46 254.69,83.96 255.09,83.55 255.09,81.33 253.67,79.9 253.67,78.07 254.53,77.2 254.53,75.25 254.61,75.17 254.61,73.37 252.79,71.55 252.79,70.08 251.57,68.85 251.57,66.95 251.05,66.43 251.05,65.42 248.26,62.62 248.26,61.02 247.06,59.83 247.06,57.67 v2(245.55,56.16) 245.95,55.76 JESPI.4
ESPI_IO1_R: length 29.2
  BOTTOM w0.076: UC1.BA13 125.09,91.13 125.36,90.87 125.36,90 126.83,88.53 127.19,88.53 128.6,87.12
  BOTTOM w0.112: 128.6,87.12 130.6,85.13 133.41,85.13 134.26,84.28 135.28,84.28 135.98,83.58 139.41,83.58 139.91,84.08 144.17,84.08 v1(146.46,86.38) 147.41,87.32 148.86,87.32 RC367.1
ESPI_IO2: length 157.7
  TOP w0.107: UE1.G6 v2(251.08,87.46)
  TOP w0.112: v2(150.51,86.26) v1(149.77,86.26) ; v2(244.01,56.74) 244.29,56.74 245.45,55.58 v2(245.45,55.56)
  IN3 w0.135: v2(150.51,86.26) 150.04,85.79 150.04,85.47 148.55,83.98 148.55,72.54 151.59,69.5 159.76,69.5 163.4,65.86 171.22,65.86 173.78,63.31 181.43,63.31 183.58,61.16 201.21,61.16 201.37,61.01 201.43,61.01 201.97,60.47 213.55,60.47 214.35,59.68 217.77,59.68 218.63,60.54 225.81,60.54 228.08,58.27 228.4,58.27 231.24,55.43 235.24,55.43 235.52,55.16 241.67,55.16 243.25,56.74 v2(244.01,56.74)
  BOTTOM w0.112: v2(150.51,86.26) 149.94,86.26 RC368.2 ; v2(251.08,87.46) 250.68,87.06 250.68,83.11 250.71,83.08 250.71,79.83 251.53,79 251.53,74.77 250.77,74.01 250.77,70.6 248.51,68.34 248.51,64.63 247.02,63.14 247.02,61.59 245.54,60.11 245.54,58.27 v2(244.01,56.74) ; JESPI.5 v2(245.45,55.56)
ESPI_IO2_R: length 28.5
  BOTTOM w0.076: UC1.BB13 125.09,90.5 125.19,90.4 125.19,89.92 126.81,88.3 127.14,88.3 128.44,87
  BOTTOM w0.102: 147.36,86.37 146.68,85.69 146.22,85.69
  BOTTOM w0.112: 128.44,87 130.54,84.9 133.26,84.9 134.14,84.02 135.15,84.02 135.85,83.32 139.53,83.32 140.04,83.83 144.36,83.83 146.22,85.69 ; 147.36,86.37 v1(147.95,86.37) RC368.1
ESPI_IO3: length 164.6
  TOP w0.107: UE1.L5 v2(255.08,86.66)
  TOP w0.112: v2(150.51,87.71) v1(149.81,87.71)
  IN3 w0.135: v2(244.85,55.59) 244.85,55.62 244.43,56.04 243.3,56.04 241.89,54.63 235.37,54.63 235.2,54.81 230.84,54.81 229.14,56.5 227.01,56.5 224.95,58.56 223.12,58.56 222.58,59.1 214.25,59.1 213.35,60 201.77,60 201.24,60.54 201.17,60.54 201.02,60.69 183.34,60.69 182.1,61.93 179,61.93 178.26,62.67 173.75,62.67 171.03,65.39 163.21,65.39 159.57,69.03 151.39,69.03 148.08,72.34 148.08,84.17 149.53,85.62 149.53,86.78 150.46,87.71 v2(150.51,87.71)
  BOTTOM w0.112: v2(150.51,87.71) 150.46,87.76 150.22,87.76 RC369.2 ; v2(255.08,86.66) 255.25,86.66 255.8,86.1 255.8,84.78 255.52,84.5 255.52,77.48 254.99,76.95 254.99,75.42 255.07,75.35 255.07,73.14 253.27,71.35 253.27,69.87 251.99,68.59 251.99,66.74 251.49,66.24 251.49,65.25 248.92,62.67 248.92,56.1 248.31,55.49 248.31,54.25 247.86,53.81 245.21,53.81 244.95,54.07 JESPI.6 244.95,55.49 v2(244.85,55.59)
ESPI_IO3_R: length 30.9
  BOTTOM w0.076: UC1.AY12 125.66,92.12 125.36,91.82 125.36,91.39 125.53,91.23 125.53,90.09 126.86,88.76 127.25,88.76 128.81,87.2
  BOTTOM w0.112: RC369.1 v1(147.93,88.15) 146.66,88.15 145.06,86.55 145.06,85.35 144.04,84.34 139.79,84.34 139.28,83.83 136.1,83.83 135.41,84.53 134.39,84.53 133.56,85.35 130.65,85.35 128.81,87.2
ESPI_RESET#: length 178.4
  TOP w0.107: UE1.K6 v2(254.28,87.46)
  TOP w0.112: v2(150.52,89.16) 151.03,89.16 v1(151.29,88.9)
  IN2 w0.124: v2(150.52,89.16) 151.28,88.4 153.21,88.4 154.03,89.22 159.78,89.22 160.51,88.49 163.45,88.49 165.23,86.72 165.23,84.22 167.67,81.78 167.67,79.09 168.39,78.37 168.39,72.79 169.8,71.38 175.3,71.38 179.38,67.3 183.03,67.3 184.99,65.34 203.83,65.34 205.02,64.15 227.53,64.15 228.77,65.39 229.45,65.39 230.23,64.61 236.2,64.61 238.02,66.43 240.28,66.43 240.83,66.98 240.83,67.25 243.04,69.45 243.32,69.45 243.91,70.04 245.1,70.04 245.91,70.85 249.33,70.85 249.96,71.49 252.79,71.49 253.3,71.99 257.02,71.99 v2(257.22,72.2)
  BOTTOM w0.076: 128.53,88.68 128.45,88.68 127.66,89.47 126.91,89.47 126.02,90.36 126.02,91.07 UC1.BA11
  BOTTOM w0.112: v2(150.52,89.16) 150.2,88.85 146.35,88.85 143.68,86.18 138.71,86.18 138.23,85.7 138.23,85 137.82,84.59 136.49,84.59 135.79,85.29 134.77,85.29 134.02,86.04 131.17,86.04 128.53,88.68 ; v2(254.28,87.46) 254.28,87.44 254.66,87.07 255.38,87.07 256.27,86.18 256.27,85.85 257.97,84.14 257.97,81.89 256.26,80.18 256.26,76.9 256.06,76.69 256.06,75.49 256.28,75.27 256.28,73.54 257.22,72.6 v2(257.22,72.2)
EXPANDER_ALERT#: length 1.5
  TOP w0.112: UE2.7 271.25,92.22 271.25,92.21 T267.1
EXPANDER_GPU_SMCLK: length 20.3
  TOP w0.107: v2(257.13,85.73) 257,85.86 255.88,85.86 UE1.M4
  TOP w0.112: UE2.19 265.73,92.22 v2(265.36,91.86) ; v2(259.13,85.2) 259.62,85.2 RE525.1
  IN3 w0.135: v2(257.13,85.73) 257.14,85.74 257.14,86.81 257.52,87.19 257.99,87.19 258.36,86.82 258.36,85.64 258.66,85.34 258.99,85.34 v2(259.13,85.2) 259.29,85.37 259.74,85.37 260.13,85.76 260.13,86.86 261.85,88.58 264.24,88.58 266.37,90.71 266.37,91.35 266.03,91.69 265.53,91.69 v2(265.36,91.86)
EXPANDER_GPU_SMDAT: length 18.6
  TOP w0.107: UE1.M7 255.88,88.26 v2(255.88,88.25)
  TOP w0.112: v2(265.36,91.26) 265.83,91.72 UE2.20 ; v2(259.13,85.79) 259.6,85.79 RE524.1
  IN3 w0.135: v2(265.36,91.26) 265.53,91.43 265.92,91.43 266.11,91.24 266.11,90.82 264.13,88.84 261.74,88.84 259.87,86.97 259.87,85.87 259.63,85.63 259.29,85.63 v2(259.13,85.79) 258.95,85.6 258.77,85.6 258.62,85.75 258.62,86.93 258.1,87.45 257.48,87.45 256.68,88.25 v2(255.88,88.25)
FAN1_PWM: length 53.1
  TOP w0.107: UE1.L10 v2(255.08,91.46)
  TOP w0.112: v2(254.57,112.45) 254.57,112.76 253.72,113.61 252.04,113.61 251.32,114.34 249.62,114.34 249.41,114.13 242.06,114.13 241.57,114.63 239.89,114.63 v4(237.56,116.95) 237.56,121.05 v2(238.57,122.06)
  IN3 w0.135: v2(254.57,112.45) 254.57,111.81 254.19,111.43 254.19,107.71 252.4,105.92 252.4,99.35 251.36,98.31 251.36,96.98 252.46,95.87 253.64,95.87 255.5,94.02 255.5,91.87 v2(255.08,91.46)
  BOTTOM w0.112: RE48.2 v2(238.57,122.06) 238.15,122.06 237.5,121.41 JFAN1.2
FAN1_TACH: length 53.5
  TOP w0.107: UE1.E3 v2(249.48,85.06)
  IN1 w0.119: v2(238.73,86.93) 239.24,86.93 239.86,87.55 239.86,92.72 238.59,93.99 238.59,103.22 237.69,104.13 237.69,110.51 238.99,111.8 238.99,114.54 237.18,116.34 237.18,119.78 v2(238.57,121.17)
  IN2 w0.124: v2(238.73,86.93) 238.73,86.93 239.31,86.93 240.62,85.61 243.17,85.61 243.89,84.89 246.43,84.89 247.09,84.24 248.59,84.24 249.41,85.06 v2(249.48,85.06)
  BOTTOM w0.112: RE51.2 v2(238.57,121.17) 238.47,121.17 237.46,120.16 JFAN1.3
FB_1.8VALW: length 4.3
  BOTTOM w0.102: v1(171.61,70.82) 172.27,70.16 PR506.1
  BOTTOM w0.254: PR506.1 172.89,69.55 PC503.2 PR501.2 172.13,68.78 PU501.6
FB_+1VALWP: length 4.5
  BOTTOM w0.102: PR308.2 v1(152.37,86.17)
  BOTTOM w0.254: PU301.4 155.18,85.13 155.36,85.31 155.36,86.02 PR311.1 PR306.2 PR308.2
FB_IA: length 4.4
  TOP w0.203: PR650.1 PR645.2 55.37,93.66 PR648.2 54.37,93.66 54,94.03 54,94.45 53.68,94.77 PU602.17
FB_VSA: length 5.9
  TOP w0.203: PU602.25 50.33,97.87 50.93,98.46 v2(51,98.46)
  BOTTOM w0.102: PR652.1 v1(49.87,98.44)
  BOTTOM w0.203: v2(51,98.46) 50.76,98.7 PR646.1
  BOTTOM w0.254: PR652.1 PR646.1 51.62,99.38 PR649.1
FCCM_GT: length 7.6
  TOP w0.203: PU602.11 53.16,92.37 53.44,92.09 v2(53.54,92.09)
  BOTTOM w0.254: v2(53.54,92.09) 54.46,92.09 v4(56.49,94.12) 57.89,95.51 PR671.2
FCCM_IA: length 21.6
  TOP w0.203: v2(52.78,97.93) 52.78,97.83 51.93,96.98 PU602.21
  IN1 w0.254: v2(52.78,97.93) 53.59,98.74 53.59,101.08 54.96,102.45 54.96,111.72 56.27,113.02 v2(56.49,113.02)
  BOTTOM w0.254: PR659.2 59.07,111.85 57.89,113.02 v1(57.4,113.02) v2(56.49,113.02)
FCCM_VSA: length 32.2
  TOP w0.203: PU602.29 48.73,97.68 v1(48.22,98.19) 47.83,98.59 v2(47.75,98.59)
  TOP w0.254: PR679.2 v2(59.46,116.09)
  IN1 w0.254: v2(47.75,98.59) 47.52,98.82 47.52,101.21 47.18,101.55 47.18,102.44 48.56,103.82 48.56,106.94 47.5,108.01 47.5,113.47 50.12,116.09 v2(59.46,116.09)
FIVR_EN: length 1.8
  BOTTOM w0.112: RC217.1 RC219.1 RC218.1
FIVR_EN_R: length 4.5
  BOTTOM w0.112: JXDP1.45 90.31,128.09 90.24,128.03 90.24,127.16 RC126.2 RC217.2 RC132.1
GPIO126: length 5.3
  TOP w0.107: RE5.1 248.87,96.4 v1(248.87,95.93) 248.87,95.44 249.48,94.82 249.48,93.06 UE1.E12
GPP_B23: length 13.4
  TOP w0.112: v2(128.47,96.69) 128.47,96.69 v1(130.55,96.69) 131.66,95.58 137.31,95.58 137.95,96.21 137.95,96.85 138.26,97.17 138.9,97.17 139.22,97.48 RC317.1
  BOTTOM w0.102: v2(128.47,96.69) 128.48,96.69 UC1.AM7
GPP_C5: length 10.5
  BOTTOM w0.076: UC1.W1 132.79,103.29 135.33,103.29 135.51,103.47 136.85,103.47
  BOTTOM w0.112: 136.85,103.47 137.67,103.47 138.18,103.98 v1(138.95,103.98) 141.12,103.98 RC25.1
GPP_C8: length 5.1
  BOTTOM w0.076: UC1.AB1 132.45,101.81 133.88,101.81 134.01,101.94 135.54,101.94
  BOTTOM w0.112: RC405.1 136.26,101.47 v1(136.03,101.7) 135.79,101.94 135.54,101.94
GPP_E23: length 2.7
  TOP w0.112: v2(126.11,106.94) 126.45,107.29 127.91,107.29 T120.1
  BOTTOM w0.102: UC1.N12 v2(126.11,106.94)
GPU_B+:
  vias: v2(62.51,89.16) v2(63.14,89.16) v2(63.78,89.16) v2(64.41,89.16) v2(65.05,89.16) v4(62.34,88.47)
GT1P: length 4.6
  TOP w0.112: PR674.2 v1(66.71,98.88)
  TOP w0.254: v2(65.3,99.64) PR674.2
  BOTTOM w0.254: v2(65.3,99.64) 64.54,98.88 PL612.3
GT_SNUB1: length 1.9
  TOP w0.112: PR676.2 61.25,95.39 v1(60.73,95.91)
GT_SW1:
  vias: v1(61.54,95.88) v2(62,96.78) v2(62.63,96.78)
H_CATERR#: length 9.2
  BOTTOM w0.076: UC1.D63 96.89,111.69 96.97,111.96 96.97,112.07 97.11,112.55 97.11,112.8 97.07,112.89 97.07,113.08 97.11,113.18 97.11,113.54 96.94,113.71 96.94,114.89 96.51,115.32 96.51,116.19 95.91,116.79
  BOTTOM w0.102: RC79.1 96.16,119.63 96.16,118.15 v1(95.99,117.97) 95.91,117.89 95.91,116.79
H_CPU_SVIDALRT#: length 8
  BOTTOM w0.076: 95.08,116.79 95.9,115.98 95.9,114.77 96.44,114.22 96.44,113.56 96.36,113.48 96.36,112.98 UC1.B63
  BOTTOM w0.112: 95.08,116.79 95.08,116.8 v1(94.76,117.12) 94.73,117.12 94,117.85 93.59,117.85 93.38,118.06 93.38,118.69 RC153.1
H_CPUPWRGD: length 12.7
  BOTTOM w0.112: UC1.A68 93.19,113.67 92.84,113.67 92.41,114.11 90.13,114.11 v1(88.04,116.2) CC300.1 85.84,119.35 85.84,120.17 RC77.2
H_CPUPWRGD_R: length 1.3
  BOTTOM w0.112: T9.1 84.67,121.56 RC77.1
H_PROCHOT#: length 400.4
  TOP w0.112: PR926.1 v2(50.56,55.06) ; v2(166.22,81.75) 166.11,81.75 165.73,82.13 165.73,87.79 163.42,90.1 161.52,90.1 161.14,89.72 v4(156.49,89.72) 153.94,89.72 152.36,88.14 147.37,88.14 147.04,87.82 139.83,87.82 139.16,88.49 v2(137.83,88.49) ; RE288.2 251.8,97.12 v2(251.8,97.27) ; v2(242.8,94.75) 242.47,94.42 240.38,94.42 239.42,93.46 237.3,93.46 237.04,93.2 236.6,93.2 236.18,93.61 235.15,93.61 233.7,92.16 233.7,91.17 229.63,87.1 228.82,87.1 227.95,86.23 227.95,85.51 v2(227.42,84.97)
  IN1 w0.119: v2(227.42,84.97) 226.97,84.53 226.97,83.41 224.41,80.85 224.41,75.36 222.15,73.1 216.6,73.1 216.53,73.04 215.36,73.04 v2(214.84,73.55) ; v2(53.74,86.24) 56.23,83.75 58.87,83.75 61.24,81.38 71.64,81.38 v2(72.46,82.21) 73.3,81.37 80.56,81.37 86.79,75.13 142.18,75.13 143.82,76.78 143.82,77.93 143.38,78.37 143.38,79.31 143.82,79.75 143.82,82.74 142.18,84.39 139.88,84.39 139.22,85.05 139.22,87.1 v2(137.83,88.49) ; v2(50.56,55.06) 51.06,55.56 52.2,55.56 53.54,54.21 56.64,54.21 59.28,56.86 61.03,56.86 63.05,58.88 63.88,58.88 65.04,57.72 69.47,57.72 69.72,57.48 71.41,57.48 72.04,58.11 72.04,62.17 71.47,62.74 71.47,65.81 72.77,67.11 72.77,70.03 73.24,70.5 73.24,71.64 v2(72.92,71.96) ; v2(45.9,92.67) 44.68,92.67 44.16,92.15 43.11,92.15 42.02,93.24 42.02,112.89 50.27,121.14 66.26,121.14 66.69,120.7 70.69,120.7 71.01,120.38 79.33,120.38 80.1,119.61 86.38,119.61 87.14,120.37 v2(88.23,120.37)
  IN2 w0.124: v2(242.8,94.75) 242.91,94.87 242.91,95.4 244.37,96.86 246.63,96.86 247.5,97.74 250.91,97.74 251.38,97.27 v2(251.8,97.27)
  IN3 w0.135: v2(72.46,82.21) 72.46,75.33 72.92,74.88 v2(72.92,71.96)
  BOTTOM w0.112: v2(88.23,120.37) RC84.1 CC310.1 RC83.1 ; v2(53.74,86.24) 49.4,86.24 45.87,89.77 45.87,92.64 v2(45.9,92.67) 46.09,92.67 PR678.1 PC605.2 ; v2(166.22,81.75) 166.29,81.82 173.2,81.82 185.3,69.72 211.01,69.72 214.84,73.55 v2(214.84,73.55)
H_PROCHOT#_R: length 12.3
  BOTTOM w0.076: UC1.C65 95.37,112.32 95.28,112.58 95.28,112.75 95.34,112.94 95.34,113.09 95.28,113.21 95.28,113.47 95.4,113.58 95.4,114.29 94.74,114.95 94.74,115.78
  BOTTOM w0.112: RC84.2 88.23,118.57 v1(89.25,117.54) 90.36,116.43 92.49,116.43 92.68,116.62 93.9,116.62 94.74,115.78
H_PROCHOT#_R1: length 2.3
  TOP w0.107: UE1.H13 v1(252.28,94.87) 252.28,95.72 RE288.1
H_THERMTRIP#: length 340.8
  TOP w0.112: v2(73.56,53.6) 75.88,51.28 108.48,51.28 108.85,51.65 ; v2(138.58,51.85) 137.98,51.26 v1(137.53,51.26) 109.24,51.26 108.85,51.65 ; QE4.3 264.34,101.21 v2(264.8,100.75) ; 108.85,51.65 RD14.2
  IN1 w0.119: v2(263.42,69.05) 263.42,67.39 261.37,65.34 260.09,65.34 259.64,65.8 252.28,65.8 250.56,64.07 248.55,64.07 242.54,58.06 242.54,53.3 238.72,49.47 185.56,49.47 183.02,52.01 179.71,52.01 177.87,53.84 161.88,53.84 160.21,55.52 147.96,55.52 145.72,53.27 142.31,53.27 140.89,51.85 v2(138.58,51.85)
  IN3 w0.135: v2(79.53,110.69) 79.73,110.89 79.73,111.26 79.14,111.85 79.14,114.82 80.92,116.6 87.78,116.6 89.3,118.12 89.3,118.4 90.35,119.45 93.5,119.45 v2(95.55,121.5) ; v2(76.41,85.93) 76.19,85.7 76.19,73.01 74.96,71.77 74.96,59.69 74.07,58.8 74.07,54.12 v2(73.56,53.6)
  BOTTOM w0.076: UC1.C63 96.86,112.32 96.94,112.58 96.94,112.75 96.89,112.94 96.89,113.09 96.94,113.21 96.94,113.47 96.77,113.64 96.77,114.82 96.33,115.27 96.33,116.08
  BOTTOM w0.102: CC312.1 95.91,119.28 95.91,118.39 95.65,118.13 95.65,116.75 96.33,116.08
  BOTTOM w0.112: v2(76.41,85.93) 76.41,86.56 77.82,87.97 77.82,92.12 79.51,93.81 79.51,110.68 v2(79.53,110.69) ; v2(264.8,100.75) 264.5,100.44 264.5,98.5 266.65,96.36 266.65,95.51 268.68,93.48 268.68,88.75 268.9,88.52 268.9,83.52 267.44,82.05 267.44,80.59 265.1,78.26 265.1,75.68 262.44,73.03 262.44,70.03 v2(263.42,69.05) ; v2(95.55,121.5) 95.41,121.36 RC80.1 CC312.1
H_VCCST_PWRGD_XDP: length 112.7
  TOP w0.112: RC124.2 124.27,81.18 v2(123.75,81.18) ; v2(92.11,128.79) 92.11,128.47 91.84,128.2 91.84,125.99 v1(89.64,123.79) v2(89.64,122.26)
  IN1 w0.119: v2(123.75,81.18) 123.75,80.91 120.77,77.93 87.54,77.93 78.37,87.09 v2(75.57,87.09)
  IN3 w0.135: v2(89.64,122.26) 89.3,122.26 86.21,119.16 v2(78.19,119.16)
  BOTTOM w0.112: v2(75.57,87.09) 75.57,87.43 76.99,88.85 76.99,92.47 78.61,94.09 78.61,114.79 78.87,115.04 78.87,116.88 78.19,117.55 v2(78.19,119.16) ; v2(89.64,122.26) 90,121.89 RC123.2 ; v2(92.11,128.79) CC307.1 92.54,128.46 92.54,128.98 92.11,129.41 JXDP1.39
HDA_BIT_CLK: length 12.2
  TOP w0.112: RC93.2 120.38,82.08 v2(120.46,82.08)
  BOTTOM w0.076: 120.11,87.99 120.11,90.09 119.83,90.36 119.83,90.94 119.98,91.09 119.98,91.4 120.05,91.61 120.15,91.72 120.25,91.83 UC1.AY22
  BOTTOM w0.102: 120.11,87.99 v1(120.27,87.57) 120.27,87.57 120.46,87.1 v2(120.46,82.08)
HDA_BIT_CLK_R: length 159.3
  TOP w0.112: v2(255.01,69.81) 255.01,70.13 254.65,70.5 244.73,70.5 243.99,69.76 240.96,69.76 239.6,68.4 234.9,68.4 232.06,65.56 230.33,65.56 229.77,66.12 228.4,66.12 227.53,65.25 225.53,65.25 225.11,64.83 187.53,64.83 184.04,66.29 181.1,66.29 178.57,68.82 174.39,68.82 172.95,70.26 164.65,70.26 162.22,67.83 147.61,67.83 140.51,74.93 v4(136.7,74.93) 121.55,74.93 120.08,76.4 120.08,78 CC27.1 RC93.1 ; v2(257.96,64.58) 257.96,65.26 257.76,65.47 RA17.1 257.53,65.29 UA1.6
  BOTTOM w0.112: v2(255.01,69.81) 255.45,70.24 255.88,70.24 256.11,70.01 256.11,67.98 257.96,66.13 v2(257.96,64.58)
HDA_RST#: length 15.8
  TOP w0.112: RC95.2 CC331.1 121.6,79.26 121.6,80.84 121.75,80.99 121.75,82.56 121.53,82.78 121.53,87.1 v2(121.5,87.13)
  BOTTOM w0.076: v2(121.5,87.13) 121.1,87.75 120.67,88.4 120.67,90.34 120.54,90.59 120.54,92.18 UC1.AW22
HDA_RST#_R: length 149.4
  TOP w0.112: RA50.1 260.88,70.7 260.15,71.44 259.13,71.44 257.86,70.17 256.49,70.17 255.17,71.49 249.26,71.49 249.26,71.49 243.94,71.49 243.23,70.78 240.6,70.78 239.22,69.39 234.43,69.39 232.51,67.47 231.8,67.47 231.43,67.83 227.69,67.83 226.82,66.96 224.82,66.96 224.4,66.54 188.25,66.54 184.69,68.08 181.89,68.08 178.73,71.23 164.21,71.23 161.85,68.87 148.03,68.87 140.89,76.01 126.21,76.01 v4(126.01,76.21) 122.9,76.21 RC95.1
HDA_SDIN0: length 164.4
  TOP w0.112: v2(121.33,88.94) 121.59,88.94 121.87,88.66 121.87,88.14 121.05,87.32 121.05,86.75 121.32,86.49 121.32,82.61 121.54,82.4 121.54,81.08 121.36,80.9 121.36,80.39 CC332.1 121.36,79.38 121.36,76.66 122.26,75.76 140.76,75.76 147.9,68.62 161.95,68.62 164.33,70.99 178.61,70.99 181.84,67.77 184.65,67.77 188.14,66.31 224.5,66.31 224.92,66.73 226.92,66.73 227.79,67.59 231.34,67.59 231.7,67.23 232.61,67.23 234.53,69.15 239.32,69.15 240.69,70.52 243.38,70.52 244.11,71.25 255.07,71.25 256.01,70.31 256.01,69.32 255.88,69.19 255.88,66.77 256.27,66.38 RA9.1
  BOTTOM w0.076: v2(121.33,88.94) 121.33,89.6 121.03,89.9 121.03,90.31 120.82,90.51 UC1.BA21
HDA_SDIN0_R: length 2.1
  TOP w0.112: RA9.2 256.56,65.01 256.73,64.85 v1(256.73,64.5) UA1.8
HDA_SDOUT: length 15.2
  TOP w0.112: v2(122.17,81.7) 122.17,81.66 122.67,81.16 122.67,80.87 CC333.1 123.23,79.37 RC187.1 RC223.2 RC94.2 123.21,77.11 v1(123.77,76.55)
  BOTTOM w0.076: UC1.BB22 120.48,90.23 120.48,88.31 121.08,87.35 121.08,86.85
  BOTTOM w0.102: 121.08,86.85 121.79,82.21 122.03,81.86 v2(122.17,81.7)
HDA_SDOUT_R: length 150
  TOP w0.112: v2(258.57,64.58) 257.93,63.93 UA1.5 ; RC94.1 124.71,77.05 126.22,77.05 126.86,76.41 v4(128.12,76.41) 140.85,76.41 148.14,69.11 161.75,69.11 164.11,71.47 178.85,71.47 182.01,68.32 184.79,68.32 188.35,66.78 224.3,66.78 224.72,67.2 226.72,67.2 227.59,68.07 231.53,68.07 231.9,67.71 232.41,67.71 234.33,69.63 239.12,69.63 240.52,71.03 243.1,71.03 243.8,71.73 255.69,71.73 v2(256.82,70.6)
  BOTTOM w0.119: v2(258.57,64.58) 258.57,66.22 256.61,68.18 256.61,70.39 v2(256.82,70.6)
HDA_SYNC: length 12.1
  TOP w0.112: RC92.2 120.73,81.54 v2(120.8,81.54)
  BOTTOM w0.076: 120.34,88 120.27,88.19 120.27,90.2 120,90.48 120,90.85 120.25,91.11 UC1.BA22
  BOTTOM w0.102: 120.34,88 120.83,87.26 v1(120.83,85.81) 120.83,83.06 121.44,82.46 121.44,81.72 121.25,81.54 v2(120.8,81.54)
HDA_SYNC_R: length 155.5
  TOP w0.112: UA1.10 255.93,63.92 255.51,64.34 v2(255.51,64.57) ; v2(255.6,69.81) 255.6,70.38 254.99,70.99 244.5,70.99 243.78,70.27 240.77,70.27 239.4,68.9 234.61,68.9 231.83,66.11 v1(231.32,66.11) 230.47,66.11 229.97,66.61 228.2,66.61 227.33,65.74 225.33,65.74 224.91,65.32 187.73,65.32 184.24,66.78 181.3,66.78 178.76,69.33 174.57,69.33 173.15,70.75 164.44,70.75 162.06,68.38 147.76,68.38 140.7,75.44 121.74,75.44 120.83,76.35 120.83,79.02 RC92.1
  BOTTOM w0.119: v2(255.6,69.81) 255.6,67.79 256.06,67.33 256.06,65.11 v2(255.51,64.57)
HDD_DET#: length 15.9
  BOTTOM w0.076: 134.84,109.99 134.83,109.99 134.62,109.99 134.42,109.79 133.63,109.79 132.76,108.93 132.32,108.93 132.16,108.87 131.99,108.87 131.83,108.92 131.66,108.92 UC1.H2
  BOTTOM w0.112: 134.84,109.99 140.02,109.99 140.85,109.46 143.74,109.46 v1(144.19,109) 145.62,109 145.86,109.24 RPC4.1
HDMI_CEC: length 12.9
  IN3 w0.135: JHDMI1.13 12.19,87.84 12.19,90.85 v2(12.98,91.64)
  BOTTOM w0.112: v2(12.98,91.64) 13.17,91.83 v1(15.95,91.83) 20.01,91.83 RV19.1
HDMI_CLKN: length 3
  TOP w0.104: v2(19.71,84.92) 19.53,84.74 19.13,84.74 RV17.1
  BOTTOM w0.104: CV38.1 20.18,84.92 v2(19.71,84.92) 19.53,84.74 19.25,84.74 19.07,84.93 LV12.1 18.77,85.09 LV38.1
HDMI_CLKP: length 3
  TOP w0.104: RV16.1 19.1,84.54 19.5,84.54 v2(19.71,84.34)
  BOTTOM w0.104: LV37.1 18.77,84.22 LV12.2 19.08,84.38 19.24,84.54 19.5,84.54 v2(19.71,84.34) 20.23,84.34 CV37.1
HDMI_CTRL_CLK: length 9.7
  TOP w0.112: JHDMI1.15 11.72,88.1 12.11,88.5 12.11,90.52 12.6,91 14.44,91 v3(15.29,90.16) 15.7,89.75 16.69,89.75 RV22.1 17.84,89.85 QV3.6
HDMI_CTRL_DATA: length 11.6
  TOP w0.107: QV3.3 19.41,87.85 19.2,87.64 17.68,87.64 17.55,87.77
  TOP w0.112: JHDMI1.16 12.56,88.6 12.35,88.81 12.35,90.42 12.7,90.77 v3(13.89,90.77) 14.34,90.77 15.6,89.51 16.27,89.51 16.79,88.99 RV23.1 17.36,88.42 17.36,87.96 17.55,87.77
HDMI_HPD: length 14.5
  BOTTOM w0.112: JHDMI1.19 11.45,90.38 12.2,91.13 v1(14.84,91.13) 15.31,90.66 16.44,90.66 17.05,90.05 19.9,90.05 21.67,88.28 QV5.1 22.7,88.67 RV21.1
HDMI_L_CLKN: length 6.6
  BOTTOM w0.104: LV38.2 17.85,85.09 LV12.4 17.56,84.93 17.38,84.76 17.08,84.76 RV35.1 16.34,84.73 v3(15.77,84.73) 15.37,84.73 15,85.11 15,85.25 15.03,85.28 15.03,85.87 14.7,86.2 13.4,86.2 JHDMI1.12
HDMI_L_CLKP: length 6.5
  BOTTOM w0.104: LV37.2 17.85,84.22 LV12.3 17.56,84.38 17.38,84.56 17.08,84.56 RV35.2 16.39,84.53 16.09,84.53 16.06,84.5 15.32,84.5 14.8,85.02 v3(14.8,85.57) 14.8,85.82 14.61,86 13.4,86 JHDMI1.10
HDMI_L_TX_N0: length 14.2
  BOTTOM w0.104: JHDMI1.9 11.86,84.69 11.95,84.69 12.14,84.88 12.14,89.85 12.67,90.39 13.33,90.39 15.2,88.51 v3(15.2,88.24) 15.2,87.74 15.69,87.25 15.73,87.25 16.3,86.68 16.45,86.68 RV32.1 17.08,86.6 17.36,86.6 17.53,86.77 LV9.4 17.85,86.94 LV36.2
HDMI_L_TX_N1: length 8.4
  BOTTOM w0.104: LV34.2 17.85,83.25 LV6.4 17.55,83.09 17.37,82.92 17.08,82.92 RV29.1 16.41,82.96 16.15,82.96 v3(15.78,82.58) 15.27,82.08 15.06,82.08 14.93,82.21 14.93,83.07 14.96,83.1 14.96,83.79 14.59,84.16 14.05,84.16 13.83,83.94 13.83,83.3 13.73,83.2 13.4,83.2 JHDMI1.6
HDMI_L_TX_N2: length 10.2
  BOTTOM w0.104: LV32.2 17.85,81.41 LV3.4 17.57,81.25 17.4,81.07 17.08,81.07 RV26.1 16.37,81.07 16.1,81.07 16.07,81.1 15.38,81.1 15.09,80.81 v3(15.09,79.47) 15.09,79.2 14.84,78.95 14.49,78.95 12.34,81.1 12.34,81.44 12.08,81.7 11.85,81.7 JHDMI1.3
HDMI_L_TX_P0: length 14.3
  BOTTOM w0.104: LV35.2 17.85,86.06 LV9.3 17.55,86.22 17.37,86.4 17.08,86.4 RV32.2 16.32,86.44 16.22,86.44 v3(15.77,86.88) 14.97,87.69 14.97,88.46 13.24,90.19 12.76,90.19 12.34,89.77 12.34,84.79 12.04,84.49 11.84,84.49 JHDMI1.7
HDMI_L_TX_P1: length 8.4
  BOTTOM w0.104: JHDMI1.4 13.4,83 13.81,83 14.03,83.22 14.03,83.86 14.14,83.96 14.51,83.96 14.73,83.73 v3(14.73,83.39) 14.73,82.12 14.98,81.88 15.36,81.88 15.69,82.22 15.74,82.22 16.14,82.62 16.14,82.65 16.24,82.76 16.33,82.76 RV29.2 17.08,82.71 17.4,82.71 17.57,82.54 LV6.3 17.85,82.38 LV33.2
HDMI_L_TX_P2: length 10.2
  BOTTOM w0.104: JHDMI1.1 11.85,81.5 12,81.5 12.14,81.35 12.14,81.02 14.41,78.75 14.93,78.75 15.32,79.14 15.32,79.79 15.29,79.82 15.29,80.73 15.44,80.87 v3(15.75,80.87) 16.37,80.87 RV26.2 17.08,80.87 17.4,80.87 17.57,80.7 LV3.3 17.85,80.54 LV31.2
HDMI_OB: length 1.4
  TOP w0.112: RV10.2 v1(16.46,80.53)
HDMI_TX_N0: length 3
  TOP w0.104: RV15.1 19.11,86.6 19.54,86.6 v2(19.71,86.76)
  BOTTOM w0.104: LV36.1 18.77,86.94 LV9.1 19.07,86.77 19.24,86.6 19.54,86.6 v2(19.71,86.76) 20.18,86.76 CV36.2
HDMI_TX_N1: length 3
  TOP w0.104: v2(19.71,83.08) 19.54,82.91 19.11,82.91 RV13.1
  BOTTOM w0.104: CV34.2 20.18,83.08 v2(19.71,83.08) 19.54,82.91 19.23,82.91 19.05,83.09 LV6.1 18.77,83.25 LV34.1
HDMI_TX_N2: length 3
  TOP w0.104: RV11.1 19.12,81.06 19.53,81.06 v2(19.71,81.24)
  BOTTOM w0.104: LV32.1 18.77,81.41 LV3.1 19.07,81.25 19.23,81.09 19.55,81.09 v2(19.71,81.24) 20.18,81.24 CV32.2
HDMI_TX_P0: length 3
  TOP w0.104: v2(19.71,86.18) 19.49,86.4 19.11,86.4 RV14.1
  BOTTOM w0.104: LV35.1 18.77,86.06 LV9.2 19.08,86.22 19.25,86.4 19.49,86.4 v2(19.71,86.18) 20.23,86.18 CV35.2
HDMI_TX_P1: length 3
  TOP w0.104: v2(19.71,82.5) 19.49,82.71 19.11,82.71 RV12.1
  BOTTOM w0.104: CV33.2 20.23,82.5 v2(19.71,82.5) 19.49,82.71 19.23,82.71 19.05,82.54 LV6.2 18.77,82.38 LV33.1
HDMI_TX_P2: length 3
  TOP w0.104: RV10.1 19.1,80.86 19.5,80.86 v2(19.71,80.66)
  BOTTOM w0.104: LV31.1 18.77,80.54 LV3.2 19.04,80.7 19.23,80.88 19.48,80.88 v2(19.71,80.66) 20.23,80.66 CV31.2
HOST_DEBUG_TX: length 100.9
  TOP w0.112: RZ132.1 237.74,99.66 238.04,99.96 v1(238.3,99.96) 238.74,99.96 v2(239.75,98.94) ; UE1.G11 v2(251.08,92.26)
  IN1 w0.119: v2(251.08,92.26) 251.08,92.49 251.51,92.91 251.51,93.41 251.05,93.86 251.05,95.77 251.31,96.02 251.31,98.36 250.66,99.01 250.66,100.02 251.62,100.99 v2(251.62,102.17) 251.62,108.2 250.67,109.15 250.67,113.24 252.69,115.27 252.69,122.27 258.83,128.41 286.41,128.41 290.48,124.34 v2(291.68,124.34)
  BOTTOM w0.112: v2(291.68,124.34) 291.68,123.16 291.36,122.84 JDEG1.8 289.64,122.84 289.58,122.77 288.83,122.77 RE306.2 RE73.2 ; v2(251.62,102.17) 251.36,102.44 245.52,102.44 245,102.96 241.13,102.96 240.25,102.07 240.25,100.61 239.75,100.11 v2(239.75,98.94)
HOST_SD_WP#: length 202.2
  TOP w0.112: v2(280.69,58.02) 280.81,57.91 QR1.2 282.77,57.91 v1(282.92,58.05)
  IN1 w0.119: v2(260.81,72.52) 262.38,70.95 263.39,70.95 263.77,70.56 263.77,69.6 266.23,67.14 266.23,63.96 271.71,58.47 274.58,58.47 275.5,59.4 275.82,59.4 276.5,60.08 278,60.08 279.51,58.58 280.14,58.58 v2(280.69,58.02)
  IN2 w0.124: v2(135.63,98.6) 135.01,99.22 131.26,99.22 130.55,99.93 130.55,101.74 130.05,102.25 127.89,102.25 v2(127.43,102.7) ; v2(147.54,99.38) 147.66,99.5 149.63,99.5 150.98,98.16 150.98,92.49 153.41,90.05 162.53,90.05 165.72,86.87 165.72,84.42 168.16,81.97 168.16,79.24 168.84,78.56 168.84,73.05 170.06,71.83 175.49,71.83 179.57,67.75 183.22,67.75 185,65.97 203.83,65.97 205.18,64.63 227.35,64.63 228.56,65.84 229.64,65.84 230.36,65.11 235.99,65.11 237.76,66.88 240.07,66.88 240.28,67.09 240.28,67.5 242.77,69.98 243.15,69.98 243.69,70.52 244.93,70.52 245.73,71.32 249.13,71.32 249.75,71.94 252.6,71.94 253.14,72.48 256.46,72.48 256.8,72.82 260.51,72.82 v2(260.81,72.52)
  IN3 w0.135: v2(135.63,98.6) 135.79,98.45 140.69,98.45 140.72,98.41 142.59,98.41 144.26,100.08 144.63,100.08 145.02,100.48 145.57,100.48 146.26,99.79 147.12,99.79 v2(147.54,99.38)
  BOTTOM w0.076: v2(127.43,102.7) 127.08,103.05 UC1.W10
  BOTTOM w0.102: 137,98.6 138.74,98.6 RC292.1
  BOTTOM w0.112: v2(135.63,98.6) 137,98.6
HP_OUT_L: length 11.7
  TOP w0.203: v2(258.34,55.64) 257.93,56.05 UA1.32
  TOP w0.381: v2(258.34,55.64) RA7.1 ; CA43.2 v2(251.69,57.29)
  IN1 w0.381: v2(251.69,57.29) 253.59,55.38 257.58,55.38 257.83,55.64 v2(258.34,55.64)
  BOTTOM w0.127: v2(258.34,55.64) v1(258.34,54.56)
HP_OUT_R: length 12.3
  TOP w0.203: 259.04,55.76 v1(258.74,56.06) 258.33,56.48 UA1.33
  TOP w0.381: 259.04,55.76 v2(259.04,55.64) 259.23,55.45 RA8.1 ; CA44.2 v2(251.69,58.49)
  IN1 w0.381: v2(259.04,55.64) 259.04,55.76 258.47,56.34 257.52,56.34 257.2,56.02 253.9,56.02 251.69,58.23 v2(251.69,58.49)
HV_GATE1_A: length 2.9
  TOP w0.076: 35.11,79.72 33.77,79.72 UT5.B9
  TOP w0.112: 35.11,79.72 35.17,79.72 RT64.1
HV_GATE2_A: length 3.9
  TOP w0.076: UT5.A9 34.99,79.47 35.11,79.35
  TOP w0.112: 35.11,79.35 35.53,78.93 35.53,78.47 RT65.1 v1(36.02,77.01)
HW_GPS_DISABLE#: length 71.7
  TOP w0.107: RE12.1 259.59,80.29 v2(259.31,80.29) ; UE1.H5 v2(252.68,86.66)
  TOP w0.112: DZ6.1 241.58,106.5 v4(241.58,106.96) 241.58,107.39 v2(242.59,108.41)
  IN1 w0.119: v2(259.31,80.29) 259.48,80.47 261.64,80.47 261.92,80.74 261.92,88.35 262.58,89.01 262.58,97.76 264.11,99.29 264.11,102.45 264.87,103.21 264.87,107.55 265.17,107.86 v2(265.17,108.47)
  IN2 w0.124: v2(259.31,80.29) 258.58,81.01 258.18,81.01 254.53,84.66 253.84,84.66 253.67,84.49 252.47,84.49 252.2,84.77 252.2,86.17 v2(252.68,86.66)
  BOTTOM w0.112: v2(242.59,108.41) 243.13,108.94 250.25,108.94 251.2,107.99 253.99,107.99 254.6,108.6 258.66,108.6 258.79,108.47 v2(265.17,108.47)
HW_GPS_DISABLE#_R: length 3.6
  TOP w0.112: v2(239.72,105.61) 239.59,105.48 DZ6.2 v1(239.16,104.33)
  BOTTOM w0.102: v2(239.72,105.61) 239.61,105.5 JNGFF2.18
I2C1_SCK_TP: length 141.9
  TOP w0.112: v2(179.97,62.63) 179.97,62.92 180.96,63.91 183.59,63.91 186.48,61.01 198.58,61.01 202.71,56.88 202.71,56.13 205.58,53.25 213.17,53.25 213.79,52.63 v3(214.49,52.63) 214.93,52.63 215.27,52.97 215.27,53.91 215.54,54.17 215.54,54.63 RZ21.2 215.85,55.8 RZ29.1
  IN1 w0.102: v2(127.51,104.86) 127.66,104.86 128.23,105.43 130.64,105.43
  IN1 w0.119: v2(179.97,62.63) 179.81,62.8 179.81,64.3 176.51,67.59 175.07,67.59 171.67,71 163.93,71 163.42,70.49 151.61,70.49 150.39,71.71 150.39,82.87 151.67,84.15 151.67,89.47 153.02,90.82 153.02,93.5 152.01,94.5 152.01,100.8 152.23,101.02 152.23,102.98 150.93,104.27 150.93,105.48 147.79,108.63 140.2,108.63 138.54,106.97 132.89,106.97 131.35,105.43 130.64,105.43
  BOTTOM w0.076: v2(127.51,104.86) 127.51,104.5 UC1.U9
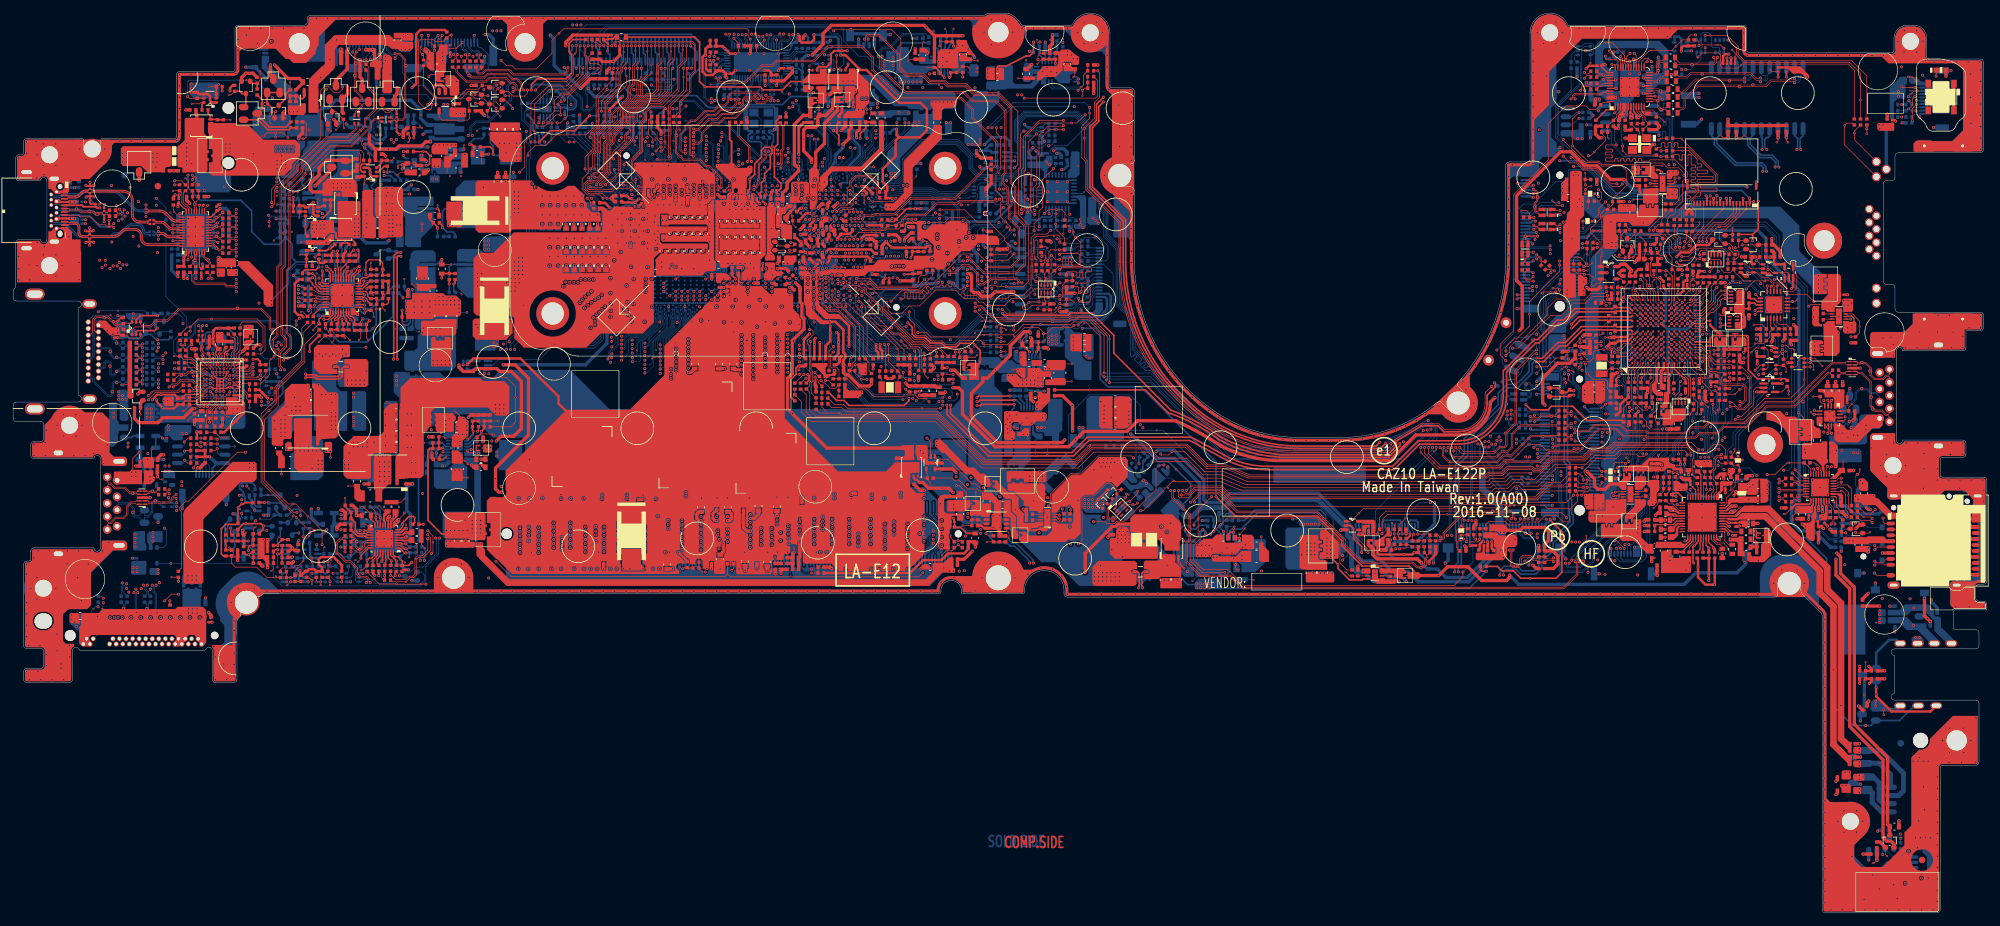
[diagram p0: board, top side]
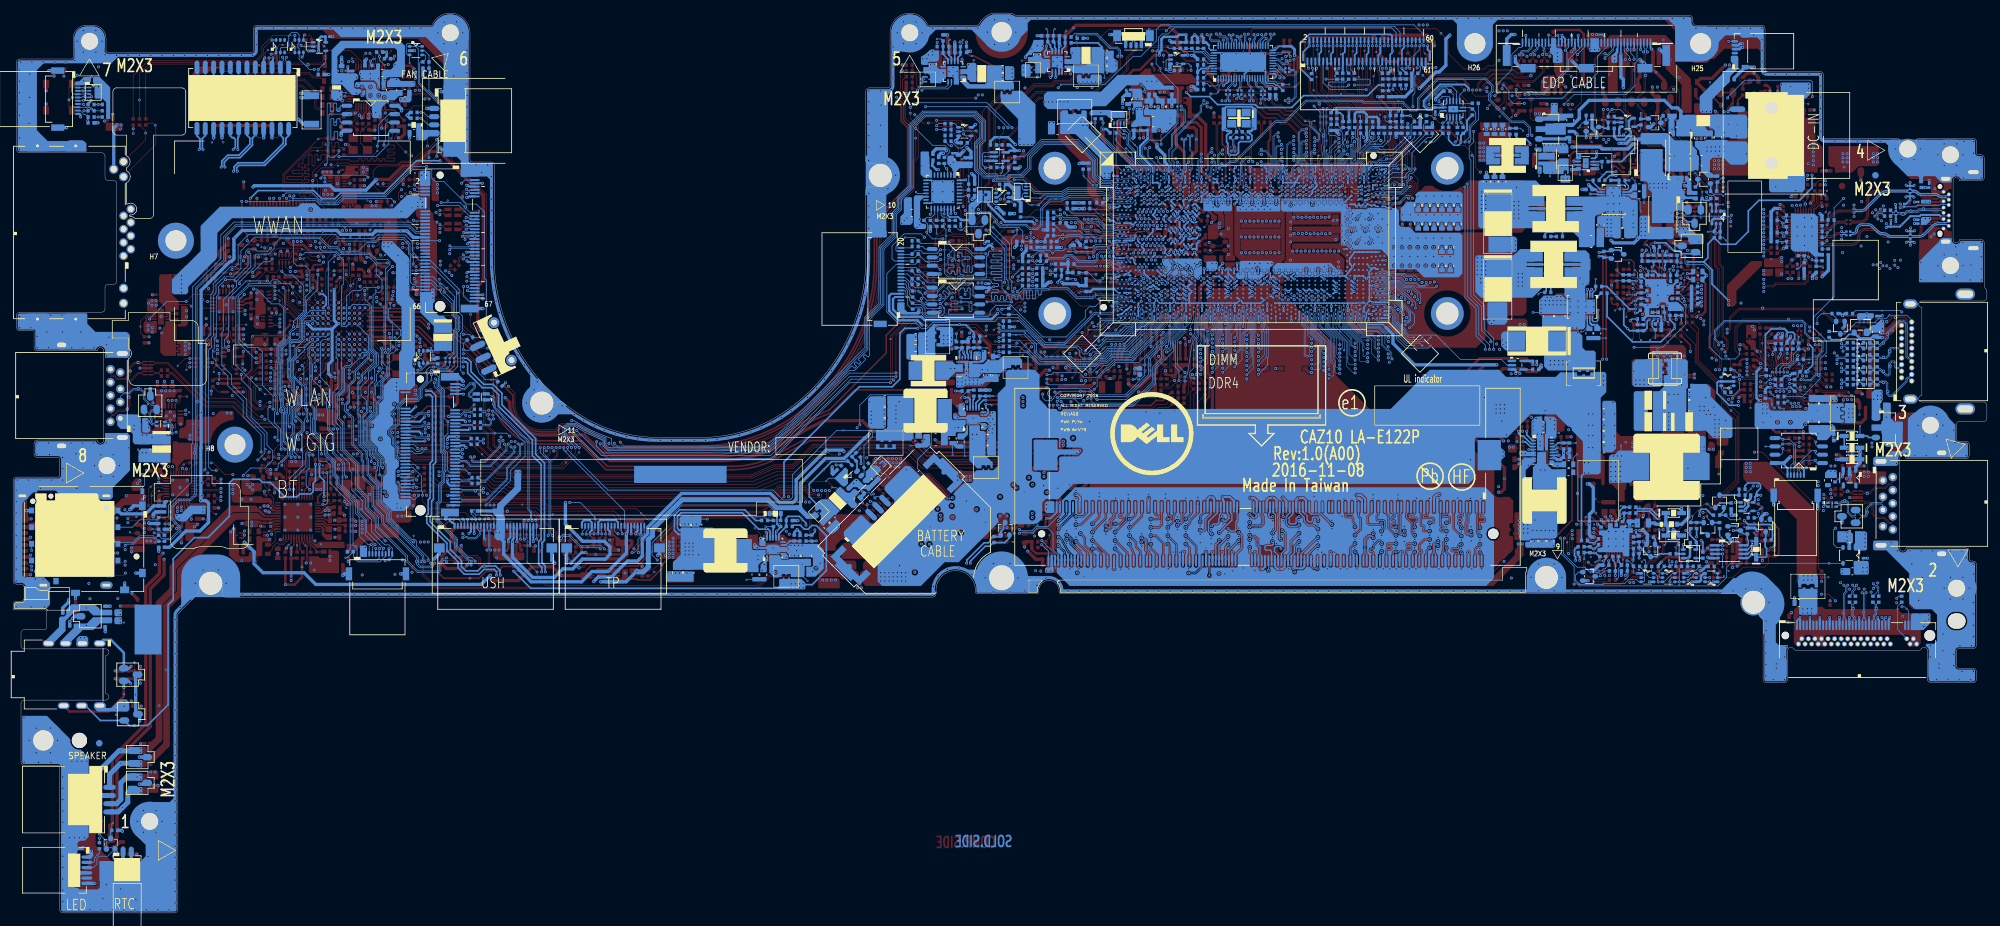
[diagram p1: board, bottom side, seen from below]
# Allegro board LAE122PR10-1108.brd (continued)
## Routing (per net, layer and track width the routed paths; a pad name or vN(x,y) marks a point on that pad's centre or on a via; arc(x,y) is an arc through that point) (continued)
I2C1_SCK_TP_R: length 5.2
  TOP w0.112: RZ117.2 RZ29.2 215.85,56.74 RZ347.2 215.66,57.8 v1(214.93,57.8) 214.89,57.75 v2(213.98,57.75)
  BOTTOM w0.112: v2(213.98,57.75) 213.98,58.16 213.55,58.6 JKBTP1.2
I2C1_SDA_TP: length 140.8
  TOP w0.112: v2(179.39,62.63) 179.39,62.63 179.74,62.98 179.74,63.02 180.86,64.15 183.69,64.15 186.58,61.25 198.68,61.25 202.94,56.98 202.94,56.22 205.68,53.49 213.27,53.49 213.89,52.87 214.83,52.87 215.03,53.07 215.03,54.01 215.3,54.27 215.3,54.63 RZ20.2 214.98,55.8 RZ26.1
  IN1 w0.102: 130.64,105.18 130.6,105.23 128.61,105.23 v2(128.22,104.84)
  IN1 w0.119: v2(179.39,62.63) 179.56,62.8 179.56,64.19 176.41,67.35 174.97,67.35 171.56,70.75 164.03,70.75 163.52,70.24 151.51,70.24 150.15,71.6 150.15,82.97 151.42,84.25 151.42,89.57 152.77,90.92 152.77,93.39 151.76,94.4 151.76,100.9 151.98,101.12 151.98,102.88 150.69,104.17 150.69,105.38 147.69,108.38 140.3,108.38 138.64,106.72 132.99,106.72 131.45,105.18 130.64,105.18
  BOTTOM w0.076: v2(128.22,104.84) 128.38,104.67 UC1.U8
I2C1_SDA_TP_R: length 4.3
  TOP w0.112: v2(213.4,57.75) 213.19,57.55 RZ346.2 RZ116.2 RZ26.2
  BOTTOM w0.112: JKBTP1.3 213.05,58.5 213.4,58.15 v2(213.4,57.75)
I_ADP: length 240
  TOP w0.107: UE1.B11 v2(247.08,92.26)
  TOP w0.112: PR935.2 57.76,50.49 v1(59.83,50.49) 60.46,51.12 61.05,51.12 61.49,51.56 61.49,53.94 61.77,54.21 62.51,54.21 63.57,55.28 63.57,57.26 v2(63.18,57.66)
  IN2 w0.124: v2(63.18,57.66) 63.34,57.83 69.36,57.83 69.8,57.39 71.69,57.39 75.74,53.34 102.77,53.34 103.89,54.46 140.16,54.46 141.71,55.64 144.6,55.64 146.17,57.2 159.22,57.2 161.53,54.89 177.71,54.89 179.8,52.8 184.44,52.8 185.77,51.46 196.98,51.46 198.04,52.52 201.55,52.52 202.58,51.5 206.37,51.5 207.11,52.23 209.32,52.23 210.06,52.97 213.83,52.97 214.31,52.49 218.42,52.49 219.55,53.62 229.07,53.62 229.73,52.96 230.85,52.96 v2(230.93,53.04) ; v2(236.53,80.85) 236.26,80.85 235.3,81.81 235.3,85.67 236.92,87.28 236.92,87.84 239.58,90.51 245.34,90.51 v2(247.08,92.26)
  BOTTOM w0.112: v2(236.53,80.85) 236.53,80.25 235.62,79.34 235.62,70.28 235.26,69.92 235.26,67.46 235.38,67.35 235.38,65.85 235.89,65.34 235.89,62.86 236.26,62.48 236.26,59.72 233.41,56.86 233.41,55.73 231.32,53.64 231.32,53.42 v2(230.93,53.04)
I_BATT: length 228
  TOP w0.107: RE64.2 255.99,78.5 256.63,77.86 256.63,76.22 v2(256.49,76.08)
  IN2 w0.124: v2(64.37,57.15) 64.79,56.73 65.12,56.73 65.75,57.36 69.19,57.36 69.64,56.91 71.53,56.91 75.56,52.88 103.02,52.88 104.12,53.97 140.34,53.97 141.87,55.13 144.83,55.13 146.45,56.75 159.04,56.75 161.35,54.44 177.52,54.44 179.61,52.35 183.23,52.35 184.57,51.01 208.77,51.01 210.28,52.52 213.64,52.52 214.15,52.02 218.66,52.02 219.76,53.12 228.93,53.12 229.83,52.22 235.18,52.22 235.61,52.65 235.61,53.9 238.05,56.34 v2(238.05,56.55)
  IN3 w0.135: v2(256.49,76.08) 256.46,76.06 256.46,74.81 256.06,74.41 254.94,74.41 253.86,73.33 252.92,73.33 247.52,67.93 247.52,66.58 245.67,64.73 245.67,62.99 244.83,62.15 244.83,61.3 241.25,57.73 238.71,57.73 238.05,57.07 v2(238.05,56.55)
  BOTTOM w0.112: v2(64.37,57.15) 64.49,57.03 64.49,54.8 62.39,52.7 61.24,52.7 60.4,51.86 59.4,51.86 59.35,51.81 58.54,51.81 58.2,52.14 PR947.2
I_BATT_R: length 7.9
  TOP w0.102: UE1.J4 v2(253.48,85.86)
  TOP w0.107: RE64.1 255.99,80.77 CE3.1 v2(255.98,81.41)
  IN1 w0.119: v2(253.48,85.86) 253.88,85.46 254.51,85.46 254.68,85.28 254.68,83.93 255.98,82.64 v2(255.98,81.41)
I_SYS: length 281.5
  TOP w0.112: RE312.2 257.26,76.27 v2(257.07,76.08) ; v2(47.08,56.14) 47.08,58.3 43.03,62.36 v4(42.64,62.36) 41.92,62.36 38.31,65.96 38.31,75.18 40.38,77.25 40.38,79.92 44.44,83.97 44.44,86.7 PR620.1 ; v2(63.18,57.06) 63.18,55.29 62.36,54.47 61.62,54.47 61.21,54.06 61.21,51.71 60.85,51.34 60.35,51.34 59.83,50.82 58.26,50.82 57.64,51.45 v2(57.49,51.45) PR936.2
  IN2 w0.124: v2(238.64,56.55) 238.6,56.55 235.86,53.81 235.86,52.46 235.37,51.97 229.76,51.97 228.86,52.87 219.86,52.87 218.79,51.79 214.05,51.79 213.55,52.29 210.41,52.29 208.9,50.79 184.48,50.79 183.14,52.12 179.52,52.12 177.43,54.21 161.25,54.21 158.94,56.52 146.61,56.52 144.96,54.87 141.94,54.87 140.44,53.75 104.21,53.75 102.45,51.99 76.13,51.99 72.63,55.49 70.73,55.49 69.09,57.13 65.85,57.13 65.21,56.5 63.74,56.5 v2(63.18,57.06)
  IN3 w0.135: v2(57.49,51.45) 56.58,52.36 51.34,52.36 48.12,55.59 47.64,55.59 v2(47.08,56.14) ; v2(238.64,56.55) 238.64,57.03 238.98,57.37 241.23,57.37 245.06,61.21 245.06,62.05 245.92,62.91 245.92,64.6 247.78,66.46 247.78,67.85 252.99,73.07 253.98,73.07 255.02,74.1 256.28,74.1 257.07,74.89 v2(257.07,76.08)
I_SYS_R: length 13.6
  TOP w0.102: RE312.1 257.76,77.62 v1(258.23,77.15)
  TOP w0.107: UE1.J5 v2(253.48,86.66) ; RE313.1 CE4.1 256.87,79.63 v2(257.39,80.15)
  TOP w0.112: RE313.1 256.87,78.45 257.26,78.05 RE312.1
  IN1 w0.119: v2(257.39,80.15) 257.39,81.74 255.61,83.51 255.61,85.99 255.34,86.26 253.88,86.26 v2(253.48,86.66)
ILIM_SEL: length 3
  TOP w0.112: v1(274.24,78.74) RI13.1 275.3,77.99 275.58,77.71 275.92,77.71 276.01,77.62 UI3.4
ILMT_+1VALWP: length 3.8
  TOP w0.112: v1(157.2,87.39) 156.86,87.04 PR310.1
  TOP w0.254: v2(155.9,85.55) 156.18,85.82 PR307.2 PR310.1
  BOTTOM w0.254: v2(155.9,85.55) 155.9,85.24 155.63,84.97 PU301.3
ILMT_DDR: length 3.9
  BOTTOM w0.102: PR207.2 v1(62.58,71.65)
  BOTTOM w0.254: PR207.2 PR205.1 65.36,71.65 65.91,71.11 PU200.17
IMON_IA: length 3.8
  TOP w0.203: v2(53.54,93.31) 53.34,93.31 53.08,93.57 PU602.14
  BOTTOM w0.112: v2(53.54,93.31) 53.85,93.31 v1(54.14,93.01)
  BOTTOM w0.203: v2(53.54,93.31) 53.16,93.69 PC625.2 52.06,93.69 PR629.2
IMON_VSA: length 3.5
  TOP w0.203: PU602.23 51.13,97.27 51.59,97.72 v2(51.59,97.88)
  BOTTOM w0.112: v2(51.59,97.88) v1(51.95,98.25)
  BOTTOM w0.203: v2(51.59,97.88) 51.59,97.43 PC643.1 PR651.1
IMVP_VR_ON: length 324.1
  TOP w0.112: RE304.1 267,99.43 267.33,99.1 v2(267.33,98.11) 267.56,98.11 268.07,97.6 UE3.4 269.26,97.6 269.34,97.67 270.34,97.67 270.53,97.48 UE4.2 ; v2(43.25,61.07) 42.75,61.07 38.06,65.76 38.06,75.69 v4(38.97,76.6) 40.13,77.76 40.13,80.05 44.18,84.1 44.18,88.48 PR616.1
  IN2 w0.124: v2(267.33,98.11) 268.03,98.11 269.47,96.66 269.47,95.19 270.28,94.38 271.11,94.38 272.02,93.47 272.02,92.58 267,87.57 267,84.69 267.51,84.19 267.51,81.25 271.35,77.4 271.35,70.33 268.55,67.53 263.35,67.53 261.11,65.29 256.59,65.29 256.28,64.98 253.16,64.98 252.12,63.94 249.78,63.94 245.87,60.03 245.87,59.2 243.19,56.52 242.46,56.52 240.17,54.22 240.17,53.44 238.02,51.29 228.83,51.29 228.15,51.97 226.34,51.97 225.39,51.02 213.8,51.02 213.2,51.62 210.72,51.62 209.21,50.11 184.17,50.11 182.87,51.4 179.66,51.4 179.32,51.06 178.41,51.06 175.94,53.53 160.96,53.53 158.64,55.85 148.14,55.85 146.42,54.13 142.19,54.13 140.72,53.02 115.07,53.02 113.36,51.31 74.89,51.31 71.39,54.82 70.34,54.82 69.36,55.8 61.78,55.8 60.19,54.21 59.48,54.21 58.76,54.93 52.67,54.93 50.75,56.84 47.97,56.84 44.85,59.95 43.65,59.95 43.25,60.35 v2(43.25,61.07)
IMVP_VR_ON_EC: length 24.5
  TOP w0.107: v2(258.01,88.25) 257.61,88.66 UE1.N7
  TOP w0.112: RE304.2 265.62,99.55 v2(265.62,99.44) 266.16,98.9 UE3.1 ; RPE10.2 259.18,98.52 v2(258.47,97.8)
  IN1 w0.119: v2(258.01,88.25) 258.06,88.25 258.42,88.61 258.42,89.7 257.52,90.6 257.52,96.85 v2(258.47,97.8)
  IN3 w0.135: v2(258.47,97.8) 258.67,97.8 261.03,100.16 262.46,100.16 263.18,99.44 v2(265.62,99.44)
INT_SPK_L+: length 43.2
  TOP w1.016: 278.82,24.17 277.33,25.66 v4(277.33,37.06) 277.33,46.75 275.23,48.84 275.23,52.18 266.95,60.46 264.95,60.46
INT_SPK_L-: length 42.7
  TOP w1.016: 278.92,26.11 278.47,26.55 v4(278.47,31.62) 278.47,47.22 276.38,49.32 276.38,52.66 267.43,61.61 264.95,61.61
INT_SPK_R+: length 47.5
  IN1 w1.016: 263.47,62.19 266.46,62.19 278.47,50.18 278.47,22.68
  vias: v1(261.45,61.75) v2(261.87,62.06) v2(262.48,62.06) v2(279.11,21.47) v2(279.74,21.47)
INT_SPK_R-: length 49.7
  TOP w0.127: v1(263.05,61.83) 262.52,61.3 v2(262.28,61.3)
  IN1 w1.016: 263.14,61 266.03,61 277.33,49.7 277.33,21.73 278.66,20.39
  vias: v2(261.69,61.15) v2(278.64,19.44) v2(279.23,19.44)
INT_SPKR_L+: length 6.3
  BOTTOM w0.762: 282.38,22.81 v1(284.31,22.81) 286.02,21.1 JSPK1.1
  vias: v2(281.25,23.01) v2(281.25,22.43)
INT_SPKR_L-: length 12
  BOTTOM w0.762: 282.38,24.71 v1(284.29,24.71) 284.57,24.71 288,21.28 288,18.62 287.28,17.9 JSPK1.2
  vias: v2(281.25,25.07) v2(281.25,24.48)
INT_SPKR_R+: length 6.9
  BOTTOM w0.762: JSPK1.3 284.91,16.65 284.28,17.28 284.28,19.84 283.34,20.79 DA7.2
  vias: v2(281.25,20.97) v2(281.25,20.38) v4(281.82,20.74)
INT_SPKR_R-: length 5.9
  BOTTOM w0.762: DA7.3 282.7,18.86 283.23,18.33 283.23,16.85 v1(284.02,16.06) 284.69,15.4 JSPK1.4
  vias: v2(281.25,18.93) v2(281.25,18.35)
INTRUDER#: length 15.7
  TOP w0.112: RC69.1 127.42,84.36 v1(127.71,84.66) 128.1,85.05 128.1,89.3 125.67,91.74 124.24,91.74 123.2,92.78 123.2,93.43 123.27,93.5 123.27,94.43 122.92,94.78 v2(122.92,95.28)
  BOTTOM w0.102: v2(122.92,95.28) 122.92,95.28 122.92,95.36 UC1.AP16
IR_CAM_DET#: length 184
  TOP w0.112: v2(153.64,107.26) 153.6,107.3 153.6,113.25 153.89,113.54 v1(153.89,116.8) 153.89,118.36 156.39,120.85 v2(160.01,120.85)
  IN1 w0.119: v2(39.33,132.9) 39.33,130.67 41.34,128.66 45.31,128.66 49.35,132.7 73.57,132.7 76.72,129.55 79.2,129.55 83.33,133.68 107.14,133.68 108.81,132 116.14,132 124.47,123.68 130.17,123.68 131.46,122.39 132.02,122.39 133.6,123.97 139.3,123.97 139.47,124.13 146.03,124.13 146.44,123.72 157.13,123.72 v2(160.01,120.85)
  BOTTOM w0.076: 136.75,109.04 136.37,109.04 RC345.1 135.16,107.83 134.14,107.83 133.91,108.06 132.21,108.06 132.06,108.16 130.23,108.16 UC1.H5
  BOTTOM w0.112: v2(153.64,107.26) 153.26,106.88 152.02,106.88 150.73,105.6 150.73,105.25 150.24,104.75 146.39,104.75 145.82,104.18 144.63,104.18 143.91,104.9 143.91,107.33 142.71,108.53 140.96,108.53 139.96,109.04 136.75,109.04 ; JIR1.6 v2(39.33,132.9)
ISH_I2C2_SCL: length 195.4
  TOP w0.112: v2(153.69,96.05) 152.92,96.82 148.94,96.82 148.45,96.34 148.17,96.34 147.8,95.97 147.29,95.97 147,96.27 147,97.56 145.7,98.87 144.59,98.87 143.45,97.73 142.87,97.73 v2(142.69,97.9) ; RZ76.1 240.84,102.06 v2(241.35,102.06)
  IN1 w0.076: v2(126.13,101.73) 126.35,101.94 126.35,102.1 126.57,102.32 129.72,102.32 130.04,102 130.41,102 130.43,102.02 130.45,102.02
  IN1 w0.119: v2(142.69,97.9) 142.53,97.74 140.52,97.74 136.65,101.61 135.14,101.61 134.74,102.02 130.45,102.02
  IN3 w0.135: v2(153.69,96.05) 153.54,95.9 153.54,94.83 153.97,94.4 153.97,88.25 152.25,86.53 152.25,84.44 150.25,82.43 150.25,73.24 152.28,71.21 160.47,71.21 164.1,67.58 178.74,67.58 180.18,66.71 arc(186.98,63.79) 194.32,62.78 196.27,62.78 202.01,62.78 202.39,62.41 202.43,62.41 202.67,62.16 214.51,62.16 215.34,61.34 217.03,61.34 217.86,62.17 224.71,62.17 228.12,65.58 232.47,65.58 235.11,68.22 236.26,68.22 236.75,68.7 237.55,68.7 239.65,70.8 239.65,75.91 237.72,77.84 236.16,77.84 234.16,79.84 234.16,95.37 236.81,98.02 236.81,98.53 240.19,101.91 241.2,101.91 v2(241.35,102.06)
  BOTTOM w0.102: UC1.AD12 125.78,101.38 v2(126.13,101.73)
  BOTTOM w0.112: v2(142.69,97.9) 142.52,97.73 142.22,97.73 RC362.1
ISH_I2C2_SCL_R: length 3.1
  TOP w0.102: RZ76.2 239.79,102.97 v1(240.07,103.25)
  TOP w0.112: v2(239.1,102.06) 239.65,102.06 RZ76.2
  BOTTOM w0.102: JNGFF2.32 239.05,102 v2(239.1,102.06)
ISH_I2C2_SDA: length 195
  TOP w0.112: RZ77.1 240.88,101.48 v2(241.35,101.48) ; v2(142.69,97.32) 142.87,97.49 143.55,97.49 144.69,98.63 145.6,98.63 146.76,97.46 146.76,96.17 147.2,95.73 147.9,95.73 148.27,96.1 148.55,96.1 149.03,96.58 152.82,96.58 153.15,96.25 153.15,96.09 v2(153.1,96.05)
  IN1 w0.076: 130.45,101.77 130.43,101.77 130.41,101.79 129.96,101.79 129.63,102.12 126.65,102.12 126.55,102.02 126.55,101.94 v2(126.77,101.73)
  IN1 w0.119: v2(142.69,97.32) 142.51,97.5 140.42,97.5 136.55,101.36 135.04,101.36 134.63,101.77 130.45,101.77
  IN3 w0.135: v2(153.1,96.05) 153.28,95.87 153.28,94.72 153.71,94.29 153.71,88.36 151.99,86.64 151.99,84.55 149.99,82.54 149.99,73.13 152.17,70.95 160.37,70.95 163.99,67.32 178.66,67.32 180.05,66.49 arc(186.91,63.53) 194.32,62.52 196.27,62.52 201.9,62.52 202.28,62.14 202.32,62.14 202.56,61.9 214.4,61.9 215.23,61.08 217.14,61.08 217.97,61.91 224.82,61.91 228.23,65.32 232.58,65.32 235.22,67.96 236.37,67.96 236.85,68.44 237.66,68.44 239.91,70.69 239.91,76.01 237.83,78.1 236.27,78.1 234.42,79.95 234.42,95.26 237.08,97.91 237.08,98.43 240.3,101.65 241.18,101.65 v2(241.35,101.48)
  BOTTOM w0.102: UC1.AD11 126.43,101.39 v2(126.77,101.73)
  BOTTOM w0.112: v2(142.69,97.32) 142.52,97.49 142.22,97.49 RC363.1
ISH_I2C2_SDA_R: length 2.9
  TOP w0.102: RZ77.2 v1(239.79,100.38)
  TOP w0.112: RZ77.2 239.68,101.42 v2(239.1,101.42)
  BOTTOM w0.102: JNGFF2.34 239.02,101.5 v2(239.1,101.42)
ISH_UART0_CTS#: length 146.8
  TOP w0.112: RZ80.1 236.84,64.95 233.78,64.95 232.04,63.21 185.36,63.21 183.97,64.6 180.01,64.6 179.13,63.73 v2(177.98,63.73)
  IN1 w0.119: v2(177.98,63.73) 175.11,63.73 172.03,66.81 164.67,66.81 163.17,68.31 151.04,68.31 148.47,70.88 148.47,84.73 148.84,85.1 148.84,92.55 150.08,93.78 150.08,99.53 149.5,100.1 149.5,101.82 146.68,104.64 141.14,104.64 140,105.78 v2(137.51,105.78)
  BOTTOM w0.076: UC1.U4 130.73,104.23 131.65,104.23 131.77,104.11 132.14,104.11 132.15,104.11 132.46,104.02 132.89,104.02 132.99,104.13 134.75,104.13 135.69,105.07 136.8,105.07 136.85,105.11
  BOTTOM w0.112: v2(137.51,105.78) v1(137.01,105.28) 136.85,105.11
ISH_UART0_CTS#_R: length 3.2
  TOP w0.112: v2(239.22,64.9) 238.36,64.9 RZ80.2
  BOTTOM w0.112: v2(239.22,64.9) 239.22,64.91 239.62,65.31 240.14,65.31 240.23,65.4 JNGFF1.62
ISH_UART0_RTS#: length 150.5
  TOP w0.112: RZ81.1 233.58,64.34 232.22,62.98 220.13,62.98 219.14,61.99 186.2,61.99 183.82,64.37 180.12,64.37 179.05,63.31 177.72,63.31 177.54,63.49 v2(177.54,64.4)
  IN1 w0.119: v2(140.53,106.74) 140.53,107.26 140.99,107.72 143.12,107.72 143.89,106.95 145.01,106.95 146.2,105.76 147.87,105.76 150.52,103.11 150.52,100.53 151.09,99.96 151.09,92.44 151.28,92.25 151.28,91.34 149.88,89.95 149.88,84.19 149.48,83.78 149.48,71.33 151.33,69.48 163.85,69.48 164.42,70.04 171.15,70.04 174.6,66.58 175.88,66.58 177.54,64.92 v2(177.54,64.4)
  BOTTOM w0.076: 132.71,104.84 131.46,104.84 UC1.U3
  BOTTOM w0.102: v2(140.53,106.74) v1(140.17,106.37) 135.75,106.37 134.32,104.94 132.8,104.94 132.71,104.84
ISH_UART0_RTS#_R: length 3.1
  TOP w0.112: v2(239.8,64.9) 239.24,64.34 v1(238.94,64.34) RZ81.2
  BOTTOM w0.112: JNGFF1.64 v2(239.8,64.9)
ISH_UART0_RXD: length 148.2
  TOP w0.112: RZ78.1 235.71,65.59 233.63,65.59 232.61,64.57 229.92,64.57 229.36,65.13 228.81,65.13 227.94,64.26 225.94,64.26 225.52,63.84 185.44,63.84 184.17,65.11 179.42,65.11 v2(178.74,64.43)
  IN1 w0.119: v2(178.74,64.43) 178.74,64.56 176.22,67.08 174.81,67.08 171.4,70.48 164.17,70.48 163.63,69.94 151.5,69.94 149.92,71.51 149.92,83.16 151.15,84.39 151.15,89.62 151.72,90.18 151.72,92.43 151.53,92.62 151.53,100.14 150.96,100.71 150.96,103.37 148.12,106.2 146.43,106.2 145.22,107.41 144.05,107.41 143.3,108.16 140.39,108.16 138.7,106.47 137.01,106.47 136.35,105.8 v2(136.35,105.78)
  BOTTOM w0.076: UC1.U1 132.77,104.5
  BOTTOM w0.102: v2(136.35,105.78) v1(135.79,105.78) 135.48,105.78 134.46,104.75 133.02,104.75 132.77,104.5
ISH_UART0_RXD_R: length 3.7
  TOP w0.112: v2(239.21,66.01) 239.21,66.37 v1(239,66.58) 238.58,67 RZ78.2
  BOTTOM w0.112: JNGFF1.58 240.06,66.4 240,66.46 239.65,66.46 v2(239.21,66.01)
ISH_UART0_TXD: length 148.6
  TOP w0.112: v2(178.15,64.43) 178.59,63.99 179.06,63.99 179.92,64.86 184.05,64.86 185.47,63.43 231.86,63.43 233.65,65.23 236.23,65.23 RZ79.1
  IN1 w0.119: v2(178.15,64.43) 178.15,64.66 175.98,66.83 174.71,66.83 171.27,70.26 164.31,70.26 163.75,69.71 151.42,69.71 149.7,71.42 149.7,83.29 150.93,84.52 150.93,89.71 151.5,90.28 151.5,92.34 151.31,92.53 151.31,100.05 150.74,100.62 150.74,103.24 148,105.98 146.35,105.98 145.13,107.19 143.96,107.19 143.21,107.94 140.48,107.94 138.75,106.21 137.31,106.21 136.93,105.83 v2(136.93,105.78)
  BOTTOM w0.076: UC1.U2 131.99,104.28 132.17,104.28 132.2,104.27 132.4,104.21 132.76,104.21
  BOTTOM w0.102: v2(136.93,105.78) 136.52,105.37 135.43,105.37 v1(134.53,104.47) 134.48,104.42 132.97,104.42 132.76,104.21
ISH_UART0_TXD_R: length 3.7
  TOP w0.112: RZ79.2 238.71,65.44 v1(239.6,65.44) 239.8,65.64 v2(239.8,66.01)
  BOTTOM w0.112: v2(239.8,66.01) 239.91,65.9 JNGFF1.60
ISUMN_GT: length 29
  TOP w0.112: v1(54.1,87.39) 53.82,87.67 PR632.1
  TOP w0.254: v2(54.32,90.31) 53.82,89.81 PR638.1 PR632.1 ; v2(66.44,95.9) PR633.2
  IN1 w0.254: v2(55.9,92.09) 55.9,92.85 58.83,95.77 61.29,95.77 61.72,95.35 65.41,95.35 65.96,95.9 v2(66.44,95.9)
  IN3 w0.254: v2(54.32,90.31) 54.82,90.31 55.9,91.39 v2(55.9,92.09)
  BOTTOM w0.203: v2(54.32,90.31) 54.06,90.56 PC641.1 53.25,89.7 PC624.2 PC626.2
  BOTTOM w0.254: PL612.2 66.76,98.88 66.44,98.56 v2(66.44,95.9) 66.44,94.64 PH602.2
ISUMN_IA: length 35.4
  TOP w0.203: v2(53.74,97.31) 53.74,99.16 54.16,99.58 55.83,99.58 56.3,99.11 PR644.2 PR640.2 57.16,97.23 PC645.1
  TOP w0.254: v2(65.43,104.48) 65.43,104.74 PR656.2
  IN1 w0.254: v2(53.74,97.31) 54.7,98.26 54.7,99.08 60.04,104.43 63.73,104.43 64.24,104.94 64.97,104.94 v2(65.43,104.48)
  BOTTOM w0.102: v4(56.4,98.02) 55.69,97.31 PC642.2
  BOTTOM w0.203: PC642.2 PC646.2 v2(53.74,97.31)
  BOTTOM w0.254: PL610.2 65.81,107.39 65.43,107.01 v2(65.43,104.48) 66.08,103.83 67.02,103.83 67.35,103.5 PH605.2
ISUMN_VSA: length 50
  TOP w0.254: PC637.2 PC633.2 ; PC637.2 48.49,100.62 v2(48.77,100.91) ; PC637.2 PC644.1 ; PR643.1 72.67,116.79 v1(73.11,116.34) v2(73.11,115.71)
  IN1 w0.254: v2(48.77,100.91) 48.89,101.03 48.89,102.42 49.6,103.13 49.6,107.1 52.38,109.88 52.38,113.1 54.05,114.77 57.81,114.77 58.01,114.97 59.61,114.97 63.14,118.5 65.71,118.5 65.96,118.25 68.63,118.25 69,117.88 70.38,117.88 70.9,117.36 72.62,117.36 73.11,116.86 v2(73.11,115.71)
  BOTTOM w0.254: v2(48.77,100.91) 48.98,100.69 PR636.2 48.97,100.28 PR641.2 ; PL614.2 73.32,115.5 v2(73.11,115.71) 73.11,116.99 72.68,117.42 PH604.2
ISUMP_GT: length 25.4
  TOP w0.203: v2(51.45,90.42) 50.73,91.13 PU602.7
  TOP w0.254: v2(65.3,96.81) PR674.1 65.31,97.5 PR633.1 PR628.1
  IN1 w0.254: v2(65.3,96.81) 65.3,96.02 65.05,95.77 61.83,95.77 61.45,96.15 58.57,96.15 55.32,92.89 v2(55.32,92.09)
  BOTTOM w0.254: v2(55.32,92.09) 55.32,89.66 v4(54.75,89.1) 54.43,88.77 PC624.1 PC626.1 52.17,88.77 51.78,89.16 51.78,90.18 51.54,90.42 v2(51.45,90.42)
ISUMP_IA: length 23.2
  TOP w0.203: PU602.19 53.09,95.57 53.41,95.9 v2(53.41,96.35)
  TOP w0.254: v2(64.65,104.4) 64.65,104.6 PR656.1 63.52,105.73 PR661.2
  IN1 w0.254: v2(53.41,96.35) 53.57,96.35 55.35,98.14 55.35,98.91 60.29,103.85 64.1,103.85 v2(64.65,104.4)
  BOTTOM w0.102: PC642.1 v1(56.5,96.39)
  BOTTOM w0.203: PC642.1 PC646.1 53.45,96.39 v2(53.41,96.35)
  BOTTOM w0.254: PR657.1 v2(64.65,104.4)
ISUMP_VSA: length 42.3
  TOP w0.203: v2(49.4,100.91) PC637.1 PC633.1 49.4,98.5 v1(49.53,98.37) PU602.27
  TOP w0.254: v2(69.56,117.18) 69.85,117.18 PR643.2 70.24,116.45 70,116.2 PR624.2
  IN1 w0.254: v2(69.56,117.18) 69.16,117.18 68.5,117.84 65.73,117.84 65.45,118.12 63.33,118.12 59.8,114.59 58.16,114.59 57.96,114.38 54.29,114.38 52.78,112.87 52.78,109.74 49.99,106.94 49.99,102.98 49.27,102.27 49.27,101.04 v2(49.4,100.91)
  BOTTOM w0.254: v2(69.56,117.18) 69.56,117.36 70.25,118.06 71.41,118.06 71.73,118.37 PR642.1
ITP_PMODE: length 69.5
  TOP w0.112: RC115.1 89.06,133.17 v2(90.01,132.22)
  BOTTOM w0.076: 128.65,116.75 128.65,115.65 126.81,113.81 126.81,112.84 127.02,112.64 127.26,112.64 127.45,112.45 127.45,111.11 127.93,110.64 UC1.E8
  BOTTOM w0.112: 128.65,116.75 127.57,117.83 125.79,117.83 123.24,120.38 123.24,125.67 125.91,128.34 v1(125.91,128.8) 126.57,129.45 126.57,131.38 126.21,131.74 126.21,133.44 125.63,134.02 124.74,134.02 123.8,134.96 90.72,134.96 90.01,134.26 JXDP1.46 v2(90.01,132.22)
JDIMM1_EVENT#: length 2.6
  TOP w0.112: RD14.1 109.76,52.52 v2(109.47,52.23)
  BOTTOM w0.112: v2(109.47,52.23) 109.48,52.23 JDIMM1.134
JTAG_CLK: length 84.1
  TOP w0.112: UE1.C8 v2(247.88,89.86)
  IN1 w0.119: v2(247.88,89.86) 247.48,90.26 247.48,94.16 247.62,94.3 247.62,95.03 247.39,95.26 247.39,97.01 247.74,97.36 247.74,106.24 248.82,107.33 248.82,113.27 250.57,115.03 250.57,116.33 251.72,117.47 251.72,122.73 258.41,129.42 287.27,129.42 v2(287.69,129) 288.97,127.72 v2(290.92,127.72)
  BOTTOM w0.112: RPE7.3 289.44,124.86 289.49,124.92 289.86,124.92 289.94,124.84 JDEG1.4 291.43,124.84 291.83,125.25 291.83,126.81 v2(290.92,127.72)
JTAG_RST#: length 12.5
  TOP w0.107: UE1.G13 251.48,94.37 250.99,94.87 250.99,96.24 250.51,96.72
  TOP w0.112: v1(247.9,103.11) 248.69,102.32 RE65.1 CE30.1 248.69,100.61 248.54,100.46 JTAG1.1 249.13,99.71 249.2,99.77 RE63.1 249.63,99.31 249.45,99.13 249.45,97.23 249.75,96.93 250.3,96.93 250.51,96.72
JTAG_TDI: length 79.8
  TOP w0.112: UE1.E9 v2(249.48,90.66) ; v4(287.7,125.98) 287.85,125.84 v2(289.74,125.84)
  IN1 w0.119: v2(249.48,90.66) 249.09,91.05 249.09,93.92 249.71,94.54 249.71,96.22 248.5,97.43 248.5,105.5 250.26,107.26 250.26,113.19 252.47,115.4 252.47,122.36 258.78,128.66 286.73,128.66 289.55,125.84 v2(289.74,125.84)
  BOTTOM w0.112: RPE7.1 289.72,125.86 v2(289.74,125.84) JDEG1.2
JTAG_TDO: length 82.5
  TOP w0.107: UE1.F6 v2(250.28,87.46)
  TOP w0.112: v4(288.76,122.56) 289.38,123.19 289.38,124.12 v2(289.74,124.47)
  IN1 w0.119: v2(250.28,87.46) 250.28,88.04 251.97,89.72 251.97,92.52 252.22,92.77 252.22,96.35 252.68,96.81 252.68,98.64 252.37,98.94 252.37,108.39 251.69,109.08 251.69,109.97 252.17,110.45 252.17,112.16 251.84,112.49 251.84,113.11 252.68,113.95 252.68,114.91 252.91,115.14 252.91,122.18 258.89,128.15 286.05,128.15 v2(289.74,124.47)
  BOTTOM w0.112: JDEG1.5 290.27,124.34 290.14,124.47 v2(289.74,124.47) 289.62,124.36 RPE7.4
JTAG_TMS: length 84.8
  TOP w0.107: v2(247.88,86.66) 247.88,86.67 247.9,86.67 UE1.C5
  TOP w0.112: v2(290.08,125.34) 289.59,125.34 v4(288.72,124.47)
  IN1 w0.119: v2(247.88,86.66) UE1.C5 248.28,92.67 248.82,93.2 248.82,96.66 248.25,97.23 248.25,105.59 249.99,107.33 249.99,113.4 252.22,115.63 252.22,122.52 258.61,128.92 287.07,128.92 289.57,126.41 289.86,126.41 290.24,126.03 290.24,125.51 v2(290.08,125.34)
  BOTTOM w0.112: RPE7.2 289.44,125.36 289.46,125.34 v2(290.08,125.34) JDEG1.3
KB_DET#: length 165.8
  TOP w0.112: v2(151.9,104.15) 151.9,104.65 v4(151.19,105.36) 150.42,106.13 150.42,108.25 150.76,108.6 150.76,109.13 149.73,110.16 149.73,112.71 150.41,113.39 150.41,118.33 149.81,118.93 v2(149.81,119.72)
  IN2 w0.124: v2(140.94,81.32) 140.94,81.29 139.11,79.46 139.11,75.78 143.1,71.79 143.1,70.57 147.69,65.99 148.52,65.99 149.16,65.36 159.24,65.36 160.5,64.09 160.5,61.07 160.82,60.75 165.27,60.75 165.79,61.27 169.35,61.27 171.06,59.55 180.11,59.55 180.72,58.94 182.79,58.94 183.35,59.5 195.78,59.5 196.61,58.67 200.61,58.67 203.94,55.34 205.7,55.34 206.09,54.95 v2(206.4,54.95)
  IN3 w0.135: v2(149.11,95.25) 149.5,94.86 149.5,92.83 149.11,92.45 149.11,92.02 145.1,88 145.1,84.93 143.75,83.59 141.89,83.59 141.46,83.15 141.46,81.83 v2(140.94,81.32) ; v2(149.81,119.72) 148.26,121.26 135.17,121.26 134.65,120.74 v2(134.65,120.47)
  BOTTOM w0.076: 131.79,115.64 129.31,113.17 129.31,112.46 129.29,112.42 129.29,112 128.97,111.69 UC1.D8
  BOTTOM w0.102: v2(134.65,120.47) 134.65,120.84 RC288.1
  BOTTOM w0.112: v2(134.65,120.47) 134.65,120.1 134.96,119.78 134.96,118.77 131.83,115.64 131.79,115.64 ; JKBTP1.20 204.55,57.89 205.51,56.93 205.51,55.51 206.07,54.95 v2(206.4,54.95) ; v2(149.11,95.25) 149.11,96.35 149.42,96.66 149.42,101.67 v2(151.9,104.15)
LAN_ACTLED_YEL#: length 35.2
  TOP w0.112: RL14.1 282.41,127.65 280.12,129.93 263.8,129.93 262.81,130.92 262.81,132.13 261.14,133.81 v1(258.56,133.81) v2(257.79,133.81)
  BOTTOM w0.112: QL1.6 v2(257.79,133.81)
LAN_ACTLED_YEL_R#: length 107.8
  TOP w0.112: v4(282.41,118.84) v2(282.41,119.56) RL14.2
  IN3 w0.135: v2(282.41,119.56) 282.41,127.82 281.68,128.55 257.86,128.55 253.72,124.4 253.72,123.33 252.7,122.32 252.7,116.3 257.46,111.54 264.48,111.54 272.16,103.86 272.16,100.5 273.94,98.73 274.92,98.73 276.5,97.14 276.5,85.89 277.38,85.01 281.11,85.01 281.86,85.76 281.86,90.96 283.87,92.96 JLOM1.10
LAN_DISABLE#_R: length 5.7
  TOP w0.112: v1(243.08,118.08) 242.92,118.24 RL7.2 RL5.1 242.92,119.99 RL9.1 244.31,121.37 244.31,121.74 244.88,122.31 UL1.3
LAN_MDIN0: length 4.2
  TOP w0.089: UL1.14 249.77,124.13 249.84,124.06 250.37,124.06 v3(250.56,123.87) 250.75,123.68 250.75,122.92 250.95,122.72 251.7,122.72 RL72.1
LAN_MDIN0_L: length 23.8
  TOP w0.089: v2(271.38,127.17) 271.22,127.01 267.74,127.01 266.98,126.25 v3(265.05,126.25) 256.67,126.25 254.55,124.13 254.55,122.94 254.35,122.74 254.04,122.74 RL72.2
  BOTTOM w0.089: v2(271.38,127.17) 271.38,127.14 271.59,126.93 271.95,126.93 272.04,127.02 272.04,127.61 271.95,127.7 271.51,127.7 271.42,127.79 TL1.11
LAN_MDIN1: length 3.4
  TOP w0.089: UL1.18 249.8,125.73 249.88,125.66 250.68,125.66 v3(250.99,125.34) 251.2,125.14 251.7,125.14 RL74.1
LAN_MDIN1_L: length 14.3
  TOP w0.089: RL74.2 254.06,125.14 254.28,125.14 256.28,127.14 263.65,127.14 v2(263.81,127.3)
  BOTTOM w0.089: v2(263.81,127.3) 263.98,127.14 264.35,127.14 264.44,127.22 264.44,127.61 264.35,127.7 263.89,127.7 263.8,127.79 TL1.5
LAN_MDIN2: length 3.2
  TOP w0.089: RL76.1 251.45,127.55 251.04,127.55 250.51,127.02 250.35,126.86 249.98,126.86 249.91,126.93 UL1.21
LAN_MDIN2_L: length 17
  TOP w0.089: v2(266.21,127.31) 266.09,127.19 265.65,127.19 264.69,128.15 255.54,128.15 254.93,127.55 253.8,127.55 RL76.2
  BOTTOM w0.089: v2(266.21,127.31) 266.38,127.14 266.94,127.14 267.03,127.23 267.03,127.61 266.94,127.7 266.43,127.7 266.34,127.79 TL1.7
LAN_MDIN3: length 4.4
  TOP w0.089: UL1.24 249.91,128.13 249.98,128.06 250.32,128.06 250.4,128.15 250.4,129.55 v3(250.61,129.75) 250.82,129.96 251.32,129.96 RL78.1
LAN_MDIN3_L: length 9.1
  TOP w0.089: RL78.2 253.2,130.3 253.91,129.59 259.06,129.59 259.26,129.78 259.26,130.26 v2(259.07,130.46)
  BOTTOM w0.089: TL1.1 258.72,129.55 259.23,130.06 259.23,130.29 v2(259.07,130.46)
LAN_MDIP0: length 4.2
  TOP w0.089: RL71.1 251.7,122.47 v3(251.08,122.47) 250.84,122.47 250.5,122.82 250.5,123.58 250.27,123.81 249.84,123.81 249.77,123.73 UL1.13
LAN_MDIP0_L: length 23.8
  TOP w0.089: v2(271.38,126.59) 271.22,126.76 267.84,126.76 267.08,126 v3(263.03,126) 256.77,126 254.8,124.03 254.8,122.83 254.46,122.49 254.08,122.49 RL71.2
  BOTTOM w0.089: v2(271.38,126.59) 271.48,126.68 272.06,126.68 272.29,126.92 272.29,127.72 272.69,128.12 272.69,128.94
LAN_MDIP1: length 3.4
  TOP w0.089: RL73.1 251.7,124.88 251.1,124.88 250.57,125.41 249.9,125.41 249.83,125.33 UL1.17
LAN_MDIP1_L: length 14.4
  TOP w0.089: v2(263.81,126.72) 263.65,126.88 v3(261.49,126.88) 256.39,126.88 254.39,124.88 254.06,124.88 RL73.2
  BOTTOM w0.089: TL1.6 265.07,127.95 264.69,127.57 264.69,127.12 264.46,126.88 263.98,126.88 v2(263.81,126.72)
LAN_MDIP2: length 3.2
  TOP w0.089: UL1.20 249.91,126.53 249.98,126.61 250.45,126.61 v3(250.66,126.81) 251.14,127.3 251.45,127.3 RL75.1
LAN_MDIP2_L: length 17
  TOP w0.089: v2(266.21,126.72) 265.99,126.94 265.55,126.94 264.59,127.9 v3(257.33,127.9) 255.64,127.9 255.04,127.3 253.8,127.3 RL75.2
  BOTTOM w0.089: v2(266.21,126.72) 266.37,126.89 267.05,126.89 267.28,127.12 267.28,127.77 267.61,128.1 TL1.8
LAN_MDIP3: length 4.4
  TOP w0.089: UL1.23 249.91,127.73 249.98,127.81 250.42,127.81 250.66,128.04 v3(250.66,128.42) 250.66,129.45 250.75,129.54 250.92,129.71 251.32,129.71 RL77.1
LAN_MDIP3_L: length 9.1
  TOP w0.089: v2(259.65,130.46) 259.51,130.32 259.51,129.68 259.17,129.34 v3(255.78,129.34) 253.3,129.34 RL77.2
  BOTTOM w0.089: TL1.2 259.99,129.55 259.48,130.06 259.48,130.29 v2(259.65,130.46)
LAN_TEST_EN: length 2.5
  TOP w0.112: v2(246.27,129.86) 246.48,129.66 UL1.30
  BOTTOM w0.112: RL12.1 246.27,129.47 v2(246.27,129.86) 245.91,130.22 v1(245.64,130.22)
LAN_WAKE#: length 256.2
  TOP w0.107: UE1.L3 v2(255.08,85.06)
  TOP w0.112: v2(244.01,121.98) 244.48,122.45 UL1.2 ; v2(145.64,103.72) 145.64,105.34 144.98,106.01 142.62,106.01 141.89,105.28 v2(139.48,105.28) ; v2(153.63,106.66) 154.03,107.05 154.03,113.14 154.23,113.34 154.23,118.39 156.29,120.45 v4(161.26,120.45) 162.08,120.45 v2(163.33,121.7)
  IN1 w0.119: v2(243.39,88.35) 243.39,90.84 241.65,92.58 241.65,95.93 240.35,97.23 240.35,102.14 243.53,105.32 243.53,121.51 v2(244.01,121.98)
  IN2 w0.124: v2(139.48,105.28) 139.48,104.58 138.58,103.68 138.33,103.68 137.46,102.81 137.46,99.03 136.29,97.86 136.29,96.53 135.56,95.8 134.21,95.8 133.79,96.22 131.54,96.22 130.08,97.69 124.61,97.69 124.33,97.41 124.33,96.85 124.52,96.66 v2(124.74,96.66) ; v2(255.08,85.06) 255.03,85.06 254.63,85.46 253.29,85.46 253.08,85.66 253.08,88.48 251.3,90.26 250.91,90.26 250.69,90.05 250.69,89.56 250.26,89.13 244.16,89.13 v2(243.39,88.35) 242.99,88.35 242.63,88 241.36,88 240.54,88.82 238.6,88.82 237.37,87.59 237.37,87.09 235.76,85.48 235.76,82.08 236.04,81.8 236.51,81.8 236.96,81.36 236.96,80.53 234.14,77.71 234.14,77.09 233.94,76.89 232.02,76.89 230.87,78.04 226.24,78.04 225.37,77.18 225.37,75.78 223.26,73.67 218.01,73.67 216.45,72.11 214.5,72.11 213.49,71.11 187.61,71.11 185.49,73.23 182.43,73.23 173.5,82.15 173.5,84.14 171,86.64 171,89.04 169.05,90.98 169.05,106.75 164.64,111.16 164.64,120.39 v2(163.33,121.7)
  BOTTOM w0.102: UC1.AM15 124.66,96.66 v2(124.74,96.66)
  BOTTOM w0.112: v2(153.63,106.66) 152.09,106.66 150.95,105.51 150.95,105.13 150.35,104.53 147.5,104.53 146.89,103.92 RC323.1 RL70.1 v2(145.64,103.72)
LCD_CBL_DET#: length 106.6
  TOP w0.112: v2(74.94,124.6) v1(75.59,124.6) ; RC287.1 133.77,102.49 v2(133.7,102.42)
  IN2 w0.124: v2(74.94,124.6) 75.83,123.71 79.72,123.71 81.67,125.66 85.04,125.66 85.69,125.02 89.68,125.02 90.01,125.36 90.01,125.6 90.37,125.96 94.67,125.96 95.31,125.33 97.18,125.33 97.84,125.98 104.55,125.98 104.99,126.42 113.67,126.42 114.23,126.98 120.15,126.98 120.51,127.34 122.28,127.34 123.02,126.6 125.69,126.6 126.28,127.2 128.13,127.2 128.73,126.6 132.22,126.6 134.39,124.43 134.39,121.15 133.96,120.72 133.96,118 135.19,116.76 135.19,108.74 137.93,105.99 137.93,104.24 136.57,102.88 134.16,102.88 v2(133.7,102.42)
  BOTTOM w0.102: UC1.AC3 130.79,102.01 130.98,102.2 132.64,102.2 132.83,102.02 133.3,102.02 v2(133.7,102.42)
  BOTTOM w0.112: v2(74.94,124.6) 74.57,124.97 74.57,126.36 72.37,128.57 72.37,130.91 71.3,131.98 70.93,131.98 70.75,132.15 JEDP1.40
LCD_TST: length 251.3
  TOP w0.107: RE20.1 248.1,81.03 248.1,81.57 v2(248.1,81.57) 248.1,81.57 248.52,81.99 248.52,82.93 249.08,83.49 UE1.D1
  TOP w0.112: v1(64.95,133.26) 65.37,133.68 v2(65.37,133.81)
  IN2 w0.124: v2(247.29,76.97) 247.29,77.42 246.61,78.11 244.88,78.11 244.45,78.54 236.3,78.54 235.1,77.34 235.1,76.63 232.69,74.22 230.4,74.22 226.99,70.8 226.44,70.8 225.44,69.8 221.35,69.8 220.93,69.38 207.9,69.38 206.86,70.42 186.7,70.42 185.02,72.1 182.24,72.1 172.78,81.56 172.78,83.82 170.29,86.31 170.29,88.79 168.38,90.7 168.38,106.47 163.96,110.88 163.96,116.88 162.34,118.5 162.34,121.7 159.67,124.37 159.67,130.49 158.65,131.52 157.31,131.52 156.5,132.33 154.19,132.33 153.24,131.38 148.88,131.38 144.71,135.55 89.9,135.55 88.1,133.74 83.59,133.74 78.97,129.12 76.03,129.12 74.59,130.56 73.1,130.56 70.38,133.28 65.89,133.28 v2(65.37,133.81)
  IN3 w0.135: v2(247.29,76.97) 248.49,78.17 248.49,81.18 v2(248.1,81.57)
  BOTTOM w0.107: JEDP1.29 65.25,133.69 v2(65.37,133.81)
LCD_VCC_TEST_EN: length 245.9
  TOP w0.107: v2(249.5,82.18) 249.3,82.18 v1(249.02,82.46) 249.02,82.99 UE1.E1
  TOP w0.112: DV3.2 v2(70.46,123.44)
  IN1 w0.119: v2(248.44,74.23) 248.44,74.84 250.01,76.41 250.01,81.88 249.71,82.18 v2(249.5,82.18)
  IN2 w0.124: v2(248.44,74.23) 247.89,74.77 241.97,74.77 241.52,75.23 237.25,75.23 236.41,74.4 236.41,74.15 235.21,72.94 234.32,72.94 233.48,72.1 233.48,69.39 233.08,68.99 227.57,68.99 226.51,67.93 222.99,67.93 222.33,67.28 207.21,67.28 205.92,68.57 186,68.57 184.27,70.29 181.1,70.29 170.95,80.45 170.95,83.1 168.48,85.56 168.48,88.04 166.56,89.96 166.56,105.72 162.16,110.13 162.16,116.13 160.54,117.75 160.54,120.95 155.04,126.45 148.62,126.45 147.29,127.77 146.06,127.77 142.69,131.15 141.35,131.15 140.09,132.41 136.04,132.41 134.78,131.14 131.22,131.14 130.26,130.19 127.08,130.19 126.61,129.71 125.01,129.71 124.37,130.36 118.31,130.36 117.78,129.83 108.64,129.83 108.13,129.33 104.74,129.33 103.88,130.19 83.88,130.19 80.28,126.59 74.03,126.59 v2(73.68,126.25)
  BOTTOM w0.112: v2(73.68,126.25) 72.82,125.38 72.82,124.11 72.15,123.44 v2(70.46,123.44)
LED_10_GRN#: length 30.5
  TOP w0.112: RL19.1 v4(281.46,123.95) 281.46,128.03 279.8,129.68 263.7,129.68 262.56,130.82 262.56,131.81 v2(261.26,133.1)
  BOTTOM w0.112: QL2.6 v2(261.26,133.1)
LED_10_GRN_R#: length 7.4
  TOP w0.112: JLOM1.11 280.52,117.9 v4(280.52,118.91) 280.52,119.2 RL19.2
LED_100_ORG#: length 34.9
  TOP w0.112: RL20.1 280.5,128.47 279.55,129.42 263.4,129.42 v1(263.21,129.23) 262.79,128.81 260.45,128.81 260.12,129.14 260.12,130.82 259.8,131.14 257.31,131.14 v2(256.68,130.5)
  BOTTOM w0.112: QL1.3 256.49,130.7 v2(256.68,130.5)
LED_100_ORG_R#: length 11.6
  TOP w0.112: RL20.2 280.22,120.42 279.36,120.42 v4(279.04,120.1) 278.98,120.04 278.98,117.15 JLOM1.13
LG1_ISL88738: length 22.9
  TOP w0.112: v4(59.58,60.97) 59.58,60.79 v2(58.75,59.95)
  IN3 w1.016: 59.23,60.79 59.23,62.03 56.79,64.46 47.33,64.46 42.12,69.67
  vias: v2(41.68,70.69) v2(42.31,70.69) v2(58.37,59.52)
LG2_ISL88738: length 13
  TOP w0.112: v2(59.87,58.61) v1(59.87,59.23)
  TOP w0.508: PQ904.6 v2(53.47,65.42)
  IN1 w0.508: v2(53.47,65.42) 53.82,65.06 57.28,65.06 60.09,62.24 60.09,58.84 v2(59.87,58.61)
LID_CL#: length 117.2
  TOP w0.112: UZ10.2 268.16,85.48 v2(267.86,85.78) ; RE26.1 v2(261.97,96.37) 262.23,96.11 v4(263.14,96.11)
  IN2 w0.124: v2(290.73,5.31) 289.33,6.7 289.33,9.59 288.9,10.02 287.93,10.02 286.73,11.23 286.73,12.39 287.88,13.55 287.88,23.5 279.75,31.63 279.75,54.31 281.87,56.43 281.87,62.02 283.22,63.37 283.22,69.37 281.24,71.35 277.81,71.35 277.07,72.08 275.9,72.08 273.35,74.63 273.35,78.95 271.16,81.15 269.82,81.15 268.22,82.75 268.22,84.53 267.86,84.89 v2(267.86,85.78)
  BOTTOM w0.112: JLED1.5 v2(290.73,5.31) ; v2(267.86,85.78) 268.49,86.41 268.49,87.44 267.86,88.07 267.86,93.69 265.19,96.37 v2(261.97,96.37)
LID_CL#_NB: length 8.2
  TOP w0.107: RE26.2 RE25.2 259.31,96.09 CE8.1 258.72,95.53 v1(258.72,94.91) 258.72,93.36 257.22,91.86 UE1.N11
LID_CL#_PCH: length 10.1
  BOTTOM w0.076: UC1.AW7 128.66,92.45 128.98,92.14 128.98,90.82 130.34,89.46 130.47,89.46
  BOTTOM w0.102: 134.89,88.43 135.37,87.95 T268.1
  BOTTOM w0.112: 134.89,88.43 132.28,88.43 131.25,89.46 130.47,89.46
LM393_P: length 15.6
  IN1 w0.254: v2(38.63,58.3) 39.01,58.68 44.54,58.68 v2(45.24,57.99)
  BOTTOM w0.203: PU1201.8 36.58,56.04 36.35,56.27 36.35,56.78 36.47,56.91 PC1201.2 37.03,57.78 PD1801.1
  BOTTOM w0.254: PR950.2 45.24,58.48 v2(45.24,57.99) 45.24,57.63 v1(45.07,57.47) 44.27,56.67 PC949.2 44.16,56.35 44.16,55.59 PU903.5 ; PD1801.1 v2(38.63,58.3)
LOM_ACTLED_YEL#: length 14.7
  TOP w0.112: v2(249.58,129.8) v1(249.09,130.29) 248.6,130.29 248.08,129.76 UL1.26
  IN1 w0.119: v2(257.79,131.9) 257.79,132.46 257.52,132.73 250.59,132.73 249.58,131.71 v2(249.58,129.8)
  BOTTOM w0.112: QL1.1 v2(257.79,131.9)
LOM_CABLE_DETECT#: length 57.3
  TOP w0.107: v2(248.1,82.2) 248.1,82.21 248.1,82.91 248.7,83.51 248.7,84.28 UE1.D2
  IN1 w0.119: v2(248.1,82.2) 248.33,82.2 249.88,83.75 249.88,88.07 251.69,89.88 251.69,92.64 251.81,92.77 251.81,93.76 251.36,94.22 251.36,95.49 251.67,95.81 251.67,96.52 252.25,97.09 252.25,98.37 252.12,98.5 252.12,108.27 251.41,108.98 251.41,110.15 251.89,110.63 251.89,112.09 251.6,112.38 251.6,113.42 v2(252.26,114.08)
  IN2 w0.124: v2(254.21,128.61) 252.26,126.65 v2(252.26,114.08)
  BOTTOM w0.112: UL2.4 253.07,129.75 v1(253.34,129.48) v2(254.21,128.61) 254.21,127.85 RE505.1
LOM_SPD10LED_GRN#: length 24.2
  TOP w0.112: RL30.2 256.55,133.12 256.84,132.83 v2(256.84,132.28) 256.91,132.34 v1(259.66,132.34) 260.14,132.34 v2(260.64,131.84) ; v2(248.94,129.8) 248.75,129.8 248.48,129.53 UL1.25
  IN1 w0.119: v2(260.64,131.84) 260.64,132.46 259.99,133.11 250.53,133.11 248.94,131.52 v2(248.94,129.8)
  BOTTOM w0.112: UL2.2 256.65,132.09 v2(256.84,132.28) ; QL2.1 v2(260.64,131.84)
LOM_SPD100LED_ORG#: length 14
  TOP w0.112: v2(256.31,133.87) 255.55,133.87 255.23,133.55 RL29.2 254.29,133.12 v4(253.34,132.17) 252.69,131.52 249.31,131.52 247.68,129.88 UL1.27
  BOTTOM w0.112: v2(256.31,133.87) 256.49,133.69 QL1.4 256.12,132.74 UL2.1
LPS_PROTECT#: length 1
  TOP w0.112: PT1.1 PR1248.2
LPSS_UART2_RXD: length 79.9
  TOP w0.112: v2(130.28,133.23) 130.08,133.43 130.08,133.59 130.18,133.69 131.92,133.69 134.79,130.82 134.79,128.74 136.01,127.51 138.57,127.51 139.58,126.5 141.76,126.5 142.3,125.96 145.05,125.96 146.4,124.62 149.97,124.62 151.9,122.69 151.9,111.26 152.53,110.63 152.53,106.2 153.99,104.74 153.99,98.96 152.77,97.74 147.92,97.74 145.81,99.84 145.58,99.84 v2(145.38,100.05)
  BOTTOM w0.076: UC1.AD1 132.42,100.52 132.53,100.52 132.71,100.7 133.77,100.7 133.92,100.85 135.21,100.85 135.5,100.56
  BOTTOM w0.107: v2(145.38,100.05) 145.83,100.05 RC330.1
  BOTTOM w0.112: 135.5,100.56 135.66,100.4 135.66,99.71 135.91,99.45 138.36,99.45 139.32,100.4 140.25,100.4 140.71,99.94 142.93,99.94 RC402.1 143.78,100.79 144.64,100.79 v2(145.38,100.05) ; v2(130.28,133.23) 130.12,133.08 130.12,132.85 130.41,132.57 JUART1.3
LPSS_UART2_TXD: length 81.7
  TOP w0.112: v2(145.38,99.45) 145.53,99.6 145.71,99.6 147.82,97.5 152.87,97.5 154.23,98.86 154.23,104.84 152.77,106.29 152.77,110.73 152.14,111.35 152.14,122.78 150.07,124.85 146.5,124.85 145.15,126.2 142.39,126.2 141.85,126.74 139.68,126.74 138.67,127.75 136.11,127.75 135.02,128.84 135.02,130.92 132.02,133.93 130.08,133.93 129.84,133.69 129.84,133.38 v2(129.69,133.23)
  BOTTOM w0.076: 135.3,100.42 135.08,100.65 134.01,100.65 133.86,100.49 132.79,100.49 132.54,100.24 132.05,100.24 UC1.AD2
  BOTTOM w0.107: RC331.1 145.87,99.45 v2(145.38,99.45)
  BOTTOM w0.112: v2(129.69,133.23) 129.87,133.06 129.87,132.83 129.61,132.57 JUART1.2 ; v2(145.38,99.45) 145.18,99.25 145.18,99.24 144.81,98.88 143.78,98.88 RC403.1 142.95,99.71 140.61,99.71 140.15,100.17 139.42,100.17 138.46,99.21 135.81,99.21 135.42,99.61 135.42,100.3 135.3,100.42
LX1_ISL88738: length 17.3
  IN1 w1.016: 58.19,61.61 56.35,63.45 52.47,63.45 49.36,66.56 49.36,70.69 48.79,71.26 47.27,71.26
  vias: v2(43.08,71.03) v2(43.08,70.46) v2(43.71,71.03) v2(43.71,70.46) v2(44.35,71.03) v2(44.35,70.46) v2(44.98,71.03) v2(44.98,70.46) v2(45.62,70.46) v2(46.25,70.46) v2(46.48,68.97) v2(46.48,68.34) v2(46.48,67.7) v2(47.08,68.97) v2(47.08,68.34) v2(47.08,67.7) v2(57.71,59.9) v2(58.09,60.36) v4(45.54,67.78)
LX2_ISL88738: length 11.4
  IN1 w0.508: v2(59.87,57.97) 60.5,57.97 61.01,58.48 61.01,62.47 57.66,65.82 v2(57.28,65.82)
  BOTTOM w0.102: 55.74,70.31 v1(55.74,71.26)
  vias: v2(55.68,69.68) v2(55.85,68.77) v2(55.85,68.03) v2(55.85,67.3) v2(55.85,66.56) v2(55.85,65.82) v2(56.28,69.68) v2(56.56,68.77) v2(56.56,68.03) v2(56.56,67.3) v2(56.56,66.56) v2(56.56,65.82) v2(56.89,69.68) v2(57.28,68.77) v2(57.28,68.03) v2(57.28,67.3) v2(57.28,66.56)
LX_1.8VALW: length 2.3
  BOTTOM w0.102: PL501.1 174.17,63.73 175.3,64.86 v1(175.97,64.86)
LX_1V_PRIM: length 1.7
  TOP w0.508: PR409.1 154.48,128.66 v2(155.18,129.36)
  BOTTOM w0.102: 154.43,129.5 154.43,129.94 v1(154.34,130.03)
LX_1VS_VCCIO: length 2.3
  TOP w0.112: PR405.1 138.52,132.6 v1(138.7,132.78)
  TOP w0.508: PR405.1 138.96,131.52 v2(139.34,131.14)
LX_3V: length 0.5
  TOP w0.112: v2(156.67,74) v1(157.17,74)
  vias: v2(152.47,74.1) v2(152.98,73.85) v2(156.06,74)
LX_5V:
  vias: v2(182.83,54.24) v2(183.41,54.24) v2(187.22,54.47) v2(187.22,53.86) v4(185.94,54.05)
LX_DDR: length 1.6
  TOP w0.112: PR202.1 v1(69.24,66.37)
  vias: v2(67.33,67.52) v2(67.97,67.52)
M2280_DEVSLP: length 224.5
  TOP w0.112: v2(23.87,47.59) 23.87,46.98 RN37.2 ; v2(130.32,108.96) 130.81,108.47 v1(130.99,108.47) 133.98,108.47 v2(134.49,108.98)
  IN1 w0.076: JNGFF3.38 19.7,42.2
  IN1 w0.119: v2(134.49,108.98) 134.52,108.98 134.62,108.88 148.27,108.88 152.48,104.66 v2(152.48,104.13) ; v2(145.44,60.31) 145.41,60.31 144.88,60.84 144.88,61.61 143.74,62.75 142.75,62.75 139.51,65.98 73.87,65.98 73.05,65.16 73.05,63.45 73.56,62.94 73.56,56.12 72.4,54.96 69.8,54.96 69.06,55.71 63.98,55.71 63.23,54.95 62.31,54.95 61.4,54.04 61.4,53.32 60.91,52.83 59.95,52.83 59.33,52.22 52.38,52.22 52.16,52.44 48.25,52.44 48.08,52.27 45.17,52.27 44.6,51.7 40.92,51.7 40.37,51.15 33.72,51.15 31.63,49.07 24.51,49.07 23.87,48.44 v2(23.87,47.59) 23.87,46.39 23.21,45.73 23.21,44.44 22.55,43.78 20.59,43.78 19.7,42.89 19.7,42.2
  IN3 w0.135: v2(149.66,96.15) 149.97,95.83 149.97,92.64 149.66,92.32 149.66,91.8 146.33,88.47 146.33,86.04 145.64,85.35 145.64,80.9 144.64,79.89 144.64,71.16 146.74,69.06 146.74,66.01 146.43,65.7 146.43,61.3 v2(145.44,60.31)
  BOTTOM w0.102: UC1.J3 130.95,108.48 130.47,108.96 v2(130.32,108.96)
  BOTTOM w0.112: v2(152.48,104.13) 149.66,101.3 v2(149.66,96.15)
M2280_PCIE_SATA#: length 229.5
  IN1 w0.119: v2(12.94,46.68) 20.73,46.68 23.39,49.34 31.53,49.34 33.59,51.41 40.24,51.41 41.5,52.67 52.24,52.67 52.47,52.44 59.15,52.44 61.89,55.17 63.14,55.17 63.89,55.93 69.15,55.93 69.89,55.18 72.24,55.18 73.3,56.25 73.3,62.81 72.79,63.32 72.79,65.27 73.73,66.2 139.62,66.2 142.82,63 143.89,63 145.44,61.45 v2(145.44,60.92)
  IN2 w0.124: v2(148.21,111.78) 148.68,111.31 148.68,105.05 v2(147.76,104.14)
  IN3 w0.135: v2(148.33,99.93) 149.52,98.75 149.52,96.85 149.19,96.51 149.19,95.97 149.74,95.42 149.74,92.73 149.38,92.37 149.38,91.91 146.02,88.56 146.02,86.12 145.39,85.48 145.39,80.98 144.4,79.99 144.4,71.07 146.51,68.96 146.51,66.18 146.18,65.85 146.18,61.66 v2(145.44,60.92)
  BOTTOM w0.076: 133.5,110.45 133.5,110.25 132.71,109.46 131.18,109.46 130.71,109.67 130.71,109.68 UC1.G4
  BOTTOM w0.102: JNGFF3.69 11.95,46.09 v1(12.23,46.37) 12.55,46.68 v2(12.94,46.68)
  BOTTOM w0.112: v2(148.33,99.93) 148.61,100.21 148.61,102.72 147.76,103.57 v2(147.76,104.14) ; 133.5,110.45 133.75,110.7 135.08,110.7 135.23,110.55 140.05,110.55 140.98,109.97 144.97,109.97 145.74,110.74 RPC4.4 146.39,111.36 146.81,111.78 v2(148.21,111.78)
M3042_DEVSLP: length 181.9
  IN1 w0.119: v2(235.74,102.5) 236.68,102.5 238.09,101.09 238.09,93.86 238.48,93.47 238.48,88.65 237.77,87.94 237.77,85.61 238,85.38 238,84.24 238.59,83.64 239.04,83.64 239.86,82.82 239.86,81.84 240.73,80.97 240.73,75.5 242.5,73.73 242.5,72.21 v2(242.07,71.78)
  IN2 w0.124: v2(150.2,105.26) 150.2,101.52 154.63,97.09 154.63,92.9 156.27,91.26 162.95,91.26 166.85,87.36 166.85,84.88 169.29,82.44 169.29,79.71 170.59,78.4 170.59,73.89 171.52,72.96 175.96,72.96 180.04,68.88 183.69,68.88 185.45,67.12 205.23,67.12 206.58,65.77 226.71,65.77 227.9,66.97 230.37,66.97 230.81,66.53 233.16,66.53 235.62,69 239.59,69 242.07,71.48 v2(242.07,71.78)
  BOTTOM w0.076: 134.87,109.38 133.75,109.38 133.45,109.08 133.45,108.6 133.08,108.22 132.27,108.22 131.91,108.48 UC1.J2
  BOTTOM w0.112: v2(150.2,105.26) 149.93,104.99 146.29,104.99 145.72,104.42 144.73,104.42 144.15,105 144.15,107.42 142.71,108.87 v1(141.87,108.87) 140.91,108.87 139.78,109.38 134.87,109.38 ; JNGFF2.30 v2(235.74,102.5)
M3042_PCIE#_SATA: length 199.2
  TOP w0.107: v2(253.48,93.06) UE1.J12
  IN2 w0.124: v2(144.46,107.96) 144.24,107.75 144.24,102.91 144.55,102.6 144.55,102.4 146.48,100.47 147.55,100.47 147.8,100.72 149.4,100.72 151.48,98.64 151.48,93.08 154.02,90.54 162.69,90.54 166.17,87.05 166.17,84.6 168.61,82.16 168.61,79.43 169.29,78.75 169.29,73.27 170.28,72.28 175.68,72.28 179.76,68.21 183.4,68.21 185.18,66.43 204.01,66.43 205.36,65.09 226.98,65.09 228.18,66.29 230.01,66.29 230.53,65.77 234.03,65.77 234.19,65.61 235.45,65.61 238.16,68.32 239.87,68.32 242.32,70.76 243.04,70.76 243.25,70.98 244.73,70.98 245.52,71.77 248.94,71.77 249.56,72.39 252.42,72.39 253.66,73.64 257.45,73.64 257.73,73.35 260.03,73.35 260.98,74.31 262.33,74.31 263.87,75.84 263.87,80.17 262.46,81.58 262.46,85.56 261.61,86.41 261.61,86.96 261.35,87.21 259.61,87.21 258.49,88.33 258.49,90.82 256.64,92.67 254.07,92.67 253.69,93.06 v2(253.48,93.06)
  BOTTOM w0.076: UC1.H3 131.19,108.74 131.85,108.74 131.94,108.71 132.19,108.71 132.33,108.75 132.87,108.75 133.7,109.59 134.53,109.59 134.63,109.69 134.85,109.69
  BOTTOM w0.112: RPC4.2 146.77,109.74 146.96,109.55 146.96,109.04 145.88,107.96 v1(145.5,107.96) v2(144.46,107.96) 143.21,109.21 140.81,109.21 140,109.69 134.85,109.69
MASK_BASE_LEDS#: length 6.4
  TOP w0.112: v1(264.82,85.48) 265.47,86.13 UZ10.4 267.03,86.13 267.36,85.8 267.36,83.2 267.04,82.88 QZ7.5
ME_FW_EC: length 44.3
  TOP w0.107: UE1.G12 v2(251.08,93.06)
  IN1 w0.119: v2(251.08,93.06) 250.44,93.7 250.44,98.14 250.37,98.22 v2(250.37,101.29)
  IN2 w0.124: v2(250.37,101.29) 249.97,100.9 248.75,100.9 248.41,100.56 246.62,100.56 245.1,99.04 244.55,99.04 243.62,98.11 242.4,98.11 240.1,95.81 237.04,95.81 233.2,91.96 233.2,89.32 v2(232.1,88.23)
  BOTTOM w0.112: SW1.1 226.99,83.64 226.85,83.93 226.85,85.89 228.73,87.77 RC221.1 231.14,88.23 v2(232.1,88.23)
ME_FWP: length 148.5
  TOP w0.112: v2(232.1,85.86) 231.96,85.86 228.8,82.7 228.8,74.71 227.39,73.3 227.39,71.36 227.18,71.15 226.41,71.15 225.6,70.34 221.02,70.34 v2(220.4,70.96) ; v2(141.27,76.95) v1(138.45,76.95) 127.09,76.95 126.49,77.54 125.08,77.54 RC223.1
  IN2 w0.124: v2(141.27,76.95) 142.95,75.27 142.95,74.21 145.01,72.15 145.01,71.33 148.56,67.78 149.1,67.78 149.56,67.32 158.37,67.32 161.78,63.91 168.1,63.91 171.47,60.54 201.57,60.54 205.1,57.01 208.79,57.01 209.42,56.37 214.03,56.37 215.68,58.02 218.67,58.02 219.15,57.55 v2(219.17,57.55)
  BOTTOM w0.112: v2(220.4,70.96) 220.4,70.22 219.06,68.88 219.06,57.66 v2(219.17,57.55) ; 231.51,87.38 232.1,86.8 v2(232.1,85.86) 231.35,85.75 SW1.3
ME_RESET#: length 4.9
  BOTTOM w0.102: v1(152.67,115.33) UC12.2
  BOTTOM w0.112: RC225.1 RC227.1 150.39,116.61 150.39,115.64 150.71,115.33 UC12.2
ME_SUS_PWR_ACK: length 178.7
  TOP w0.107: v2(247.1,94.31) 247.37,94.04 247.37,93.57 UE1.B13
  TOP w0.112: v2(143.53,85.53) 143.53,85.05 RC74.1 ; v1(245.72,69.43) 246.14,69.01 v2(246.14,68.83)
  IN2 w0.124: v2(246.14,68.83) 246.14,67.19 241.93,62.99 241.91,62.99 239.08,60.16 237.75,60.16 236.86,61.05 235.24,61.05 234.99,60.79 227.09,60.79 226.14,61.74 219.09,61.74 218.38,61.04 215.49,61.04 214.44,62.08 204.09,62.08 202.92,63.25 184.2,63.25 182.47,64.98 176.27,64.98 175.87,64.58 174.83,64.58 172.79,66.62 163.15,66.62 159.75,70.03 151.24,70.03 150.59,70.67 150.26,70.67 148.44,72.5 148.44,80.23 145.08,83.58 145.08,85.18 144.3,85.96 143.94,85.96 143.53,85.56 v2(143.53,85.53)
  IN3 w0.135: v2(125.72,94.73) 126.63,94.73 126.99,94.37 126.99,92.9 129.14,90.75 133.75,90.75 137.69,86.82 142.25,86.82 v2(143.53,85.53)
  BOTTOM w0.076: v2(125.72,94.73) 125.34,95.1 UC1.AR13
  BOTTOM w0.112: v2(247.1,94.31) 247.1,93.55 246.12,92.57 246.12,85.98 245.34,85.19 245.34,83.66 246.56,82.44 246.56,81.34 247.71,80.19 247.71,78.94 246.89,78.12 246.89,76.38 247.53,75.73 247.53,71.57 246.43,70.46 246.43,69.75 246.14,69.46 v2(246.14,68.83)
MEC_XTAL1: length 5.7
  TOP w0.112: YE1.1 242.44,82.2 243.25,83.02 CE28.1 244.4,83.02 244.8,82.61 v1(245.06,82.61) 245.44,82.61 UE1.A1
MEC_XTAL2: length 2.8
  TOP w0.112: YE1.2 242.42,84.7 243.18,83.95 CE29.1 RE290.2
MEC_XTAL2_R: length 2.4
  TOP w0.112: RE290.1 246.09,84.86 UE1.A3
MEDIACARD_IRQ#: length 188.6
  TOP w0.112: v2(267.23,66.84) 268.43,66.84 270.2,68.62 v4(270.51,68.62) RR19.1 272.97,68.62 273.87,67.71 UR1.32
  IN1 w0.119: v2(267.23,66.84) 263.99,70.08 263.99,70.65 263.93,70.72 263.93,70.75 261.62,73.05 260.05,73.05 259.01,72.01 258.51,72.01 258.16,71.66 252.18,71.66 249.85,69.34 248.34,69.34 245.13,66.13 243.68,66.13 241.76,64.21 237.42,64.21 235.78,62.57 235.78,61.25 235.29,60.76 235.29,59.69 235.17,59.57 228.24,59.57 227.72,60.09 226.52,60.09 225.71,60.9 218.46,60.9 218.31,60.75 215.03,60.75 214.53,61.25 178.98,61.25 178.18,62.05 174.11,62.05 170.6,65.56 163.82,65.56 162.33,67.05 150.53,67.05 147.25,70.33 147.25,81.02 147.11,81.17 147.11,87.34 145.91,88.54 145.91,92.83 143.61,95.13 140.84,95.13 136.84,99.13 131.99,99.13 131.73,98.87 129.3,98.87 129.28,98.85 v2(129.28,98.47)
  BOTTOM w0.076: UC1.AN8 127.93,96.69 128.01,96.77 128.04,96.77 128.98,97.71 129.15,97.71 129.31,97.88 129.31,98.44 v2(129.28,98.47)
MEM_INTERLEAVED: length 9.8
  BOTTOM w0.076: UC1.P2 132.3,106.08 133.35,106.08 133.7,106.44 v1(134.64,106.44) 134.71,106.44 134.96,106.69 136.85,106.69
  BOTTOM w0.112: 136.85,106.69 139.42,106.69 RC371.1 RC372.1
MEM_SMBCLK: length 25
  TOP w0.112: v2(129.39,104.85) 129.21,104.67 129.21,104.56 129.49,104.28 132.74,104.28 132.99,104.52 132.99,104.52 CC320.1 133.31,104.84 RC12.1 134.96,105.28 135.23,105.28 135.34,105.39 135.34,105.75 136.12,106.52 138.84,106.52 140.6,108.28 143.77,108.28 144.13,108.65 149.5,108.65 149.7,108.84 v2(149.7,108.84)
  BOTTOM w0.102: UC1.R7 v2(129.39,104.85)
  BOTTOM w0.112: QC2.6 149.37,109.75 149.71,109.42 149.71,108.85 v2(149.7,108.84)
MEM_SMBDATA: length 25.8
  TOP w0.112: v2(128.8,104.84) 128.97,104.67 128.97,104.46 129.39,104.04 132.84,104.04 133.08,104.28 134.85,104.28 RC14.1 135.58,105.01 135.58,105.65 136.22,106.28 138.94,106.28 140.7,108.05 143.87,108.05 144.23,108.41 149.85,108.41 150.28,108.84 v2(150.29,108.84)
  BOTTOM w0.102: UC1.R8 v2(128.8,104.84)
  BOTTOM w0.112: v2(150.29,108.84) 150.3,108.84 150.69,108.45 QC2.3
MPHYP_PWR_EN: length 22.2
  TOP w0.112: RC387.1 141.09,86.23 139.62,86.23 138.69,87.16 137.16,87.16 132.45,91.87 132.45,92.25 130.05,94.65 130.05,95.11 129.74,95.41 129.06,95.41 v1(128.9,95.57) 128.79,95.68 127.24,95.68 127,95.92 127,96.2 v2(126.5,96.7)
  BOTTOM w0.102: v2(126.5,96.7) 126.86,97.05 UC1.AM10
MSCLK: length 87.9
  TOP w0.112: UE1.H10 v2(252.68,91.46)
  IN3 w0.135: v2(252.68,91.46) 251.92,92.22 251.92,93.35 250.16,95.12 250.16,95.99 248.44,97.71 248.44,112.09 250.61,114.26 250.61,116.65 251.47,117.51 251.47,122.23 252.67,123.43 252.67,124.85 257.43,129.61 285.28,129.61 286.4,128.49 286.4,123.22 287.17,122.45 287.17,121.91 v2(287.72,121.36) 289.18,122.82 290.16,122.82 290.41,123.07 290.41,123.45 v2(289.96,123.9)
  BOTTOM w0.112: RE72.2 v2(287.72,121.36) RE30.1 ; JDEG1.6 290.02,123.84 v2(289.96,123.9)
MSDATA: length 88.8
  TOP w0.112: UE1.G9 v2(251.08,90.66) ; v4(289.34,120.8) 289.34,122.64 v2(289.96,123.26)
  IN3 w0.135: v2(251.08,90.66) 251.66,91.23 251.66,93.25 249.9,95.01 249.9,95.88 248.17,97.61 248.17,112.2 250.35,114.37 250.35,116.76 251.2,117.61 251.2,122.34 252.41,123.54 252.41,124.96 257.33,129.88 285.39,129.88 286.66,128.6 286.66,123.33 286.98,123.01 287.49,123.01 v2(287.74,123.26) v2(289.96,123.26)
  BOTTOM w0.112: RE86.1 v2(287.74,123.26) RE75.2 ; JDEG1.7 290.04,123.34 v2(289.96,123.26)
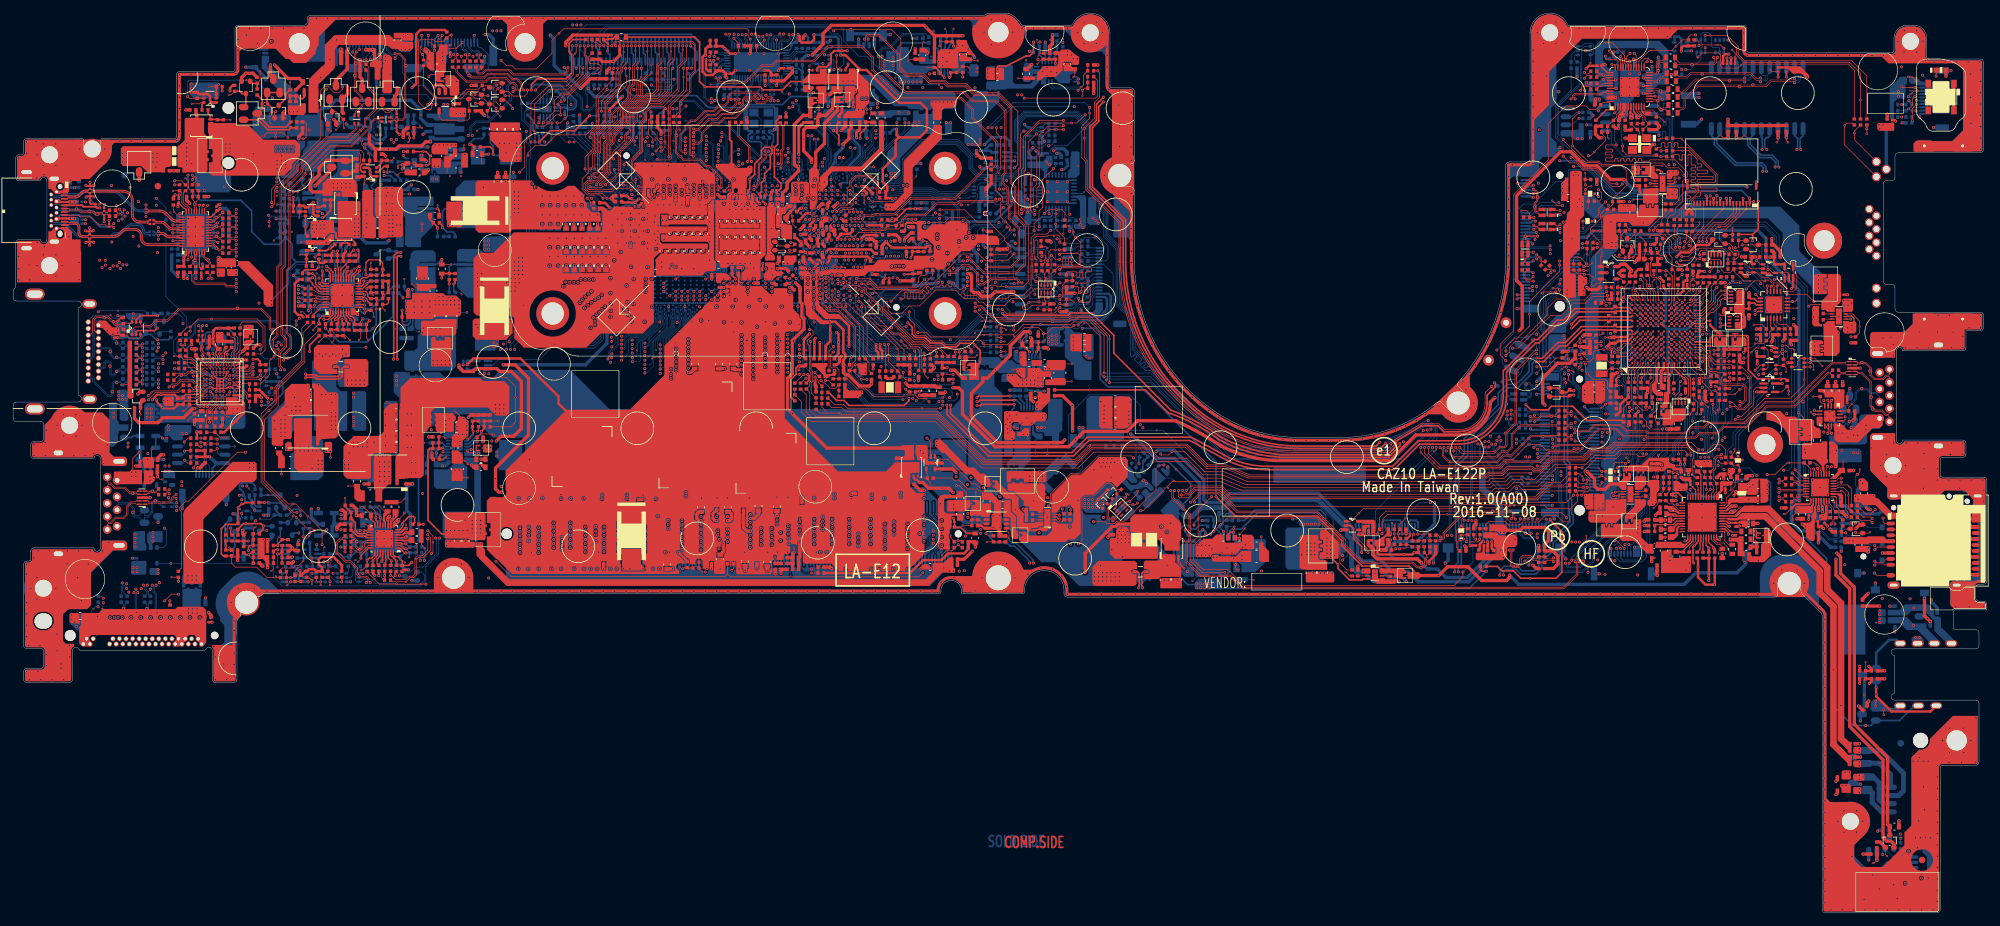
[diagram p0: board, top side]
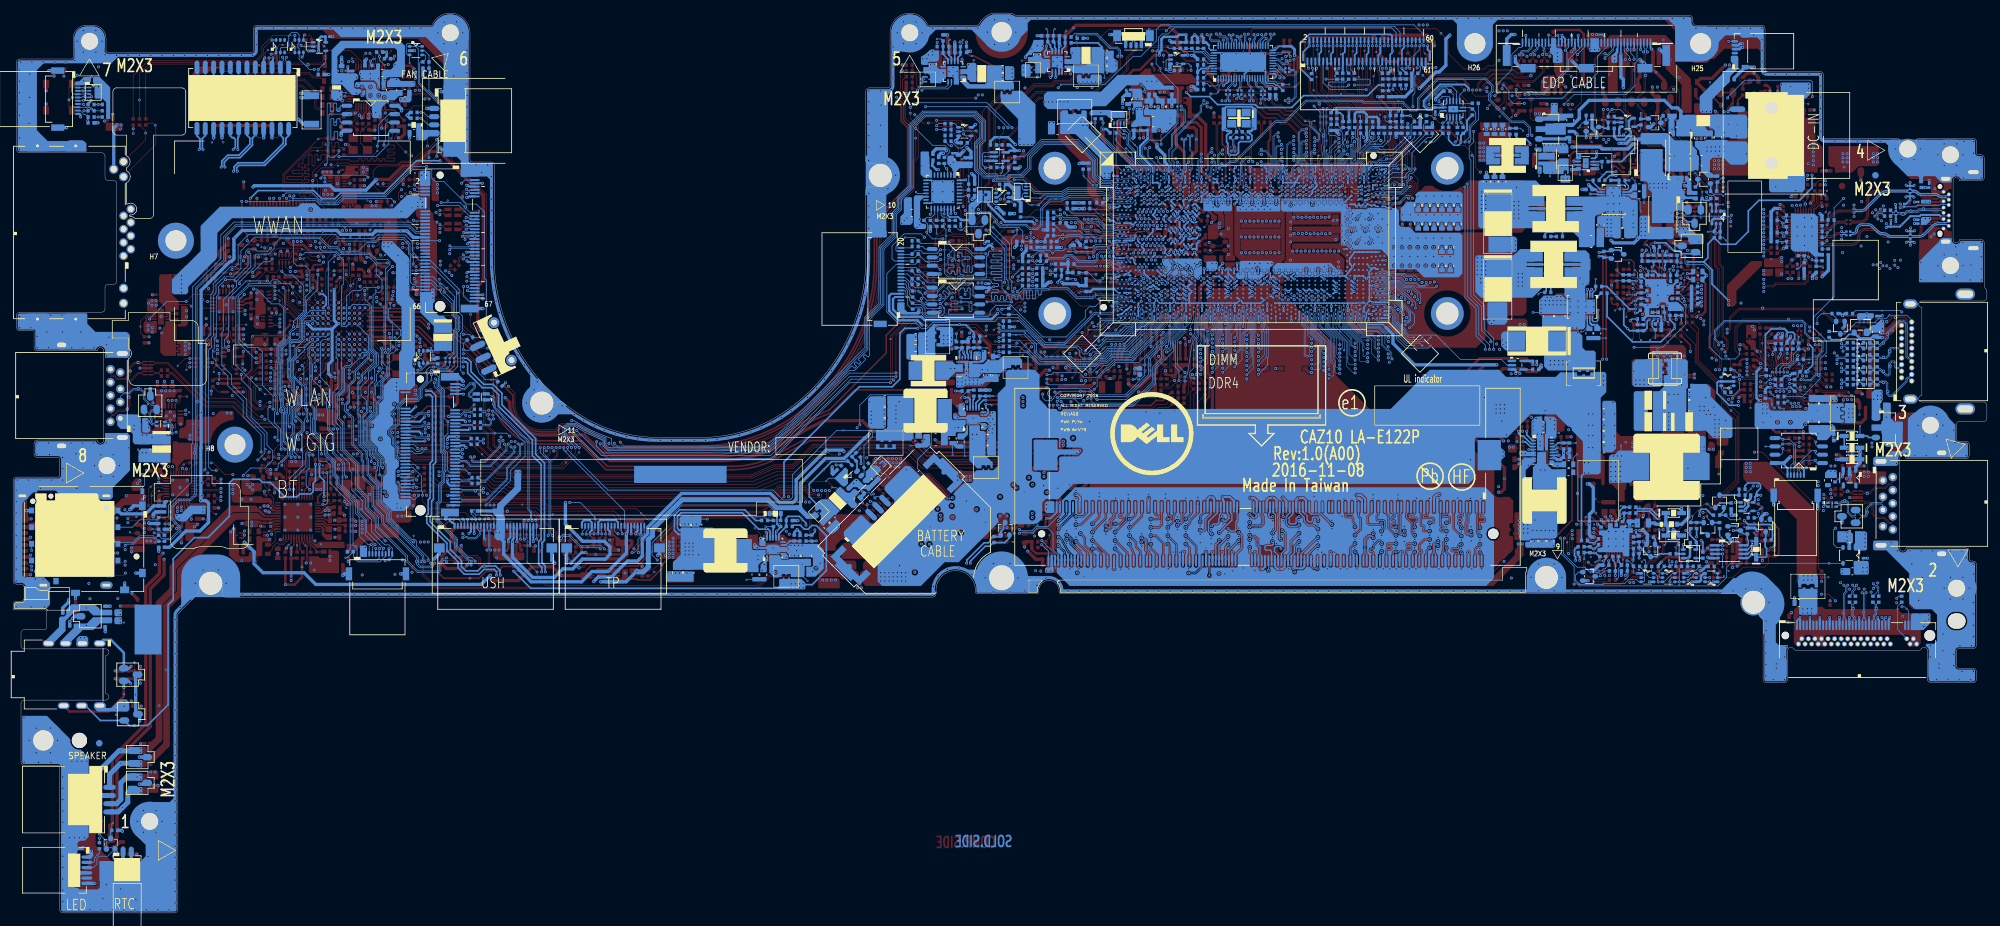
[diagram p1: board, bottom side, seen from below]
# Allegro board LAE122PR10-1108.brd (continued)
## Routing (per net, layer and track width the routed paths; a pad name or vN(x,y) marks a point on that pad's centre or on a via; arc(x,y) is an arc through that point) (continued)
MUX1_DP_SEL: length 32.7
  TOP w0.112: UT9.23 28.37,107.37 28.4,107.39 v2(28.4,107.91) ; RT89.1 v2(24.6,83.01)
  IN3 w0.135: v2(24.6,83.01) 25.02,83.42 25.02,87.26 25.96,88.2 27.23,88.2 27.74,88.71 27.74,91.55 30.75,94.57 30.75,97.37 30.3,97.82 30.3,108.34 30.02,108.62 29.11,108.62 28.4,107.91 v2(28.4,107.91)
MUX1_DPEQ0: length 4.6
  TOP w0.112: UT9.14 v2(31.19,103.7)
  BOTTOM w0.112: RT140.1 RT306.1 31.18,103.71 v2(31.19,103.7) 31.21,103.7 31.22,103.71 RT139.1 v1(31.95,104.65)
MUX1_DPEQ1: length 4.9
  TOP w0.112: UT9.2 26.77,100.24 26.64,100.11 v2(26.64,99.6)
  BOTTOM w0.102: RT247.1 25.18,98.58 v1(24.98,98.37)
  BOTTOM w0.112: RT248.1 26.48,99.44 v2(26.64,99.6) ; RT248.1 RT303.1 ; RT248.1 RT247.1
MUX1_FLIP_SEL: length 40.8
  TOP w0.112: RT375.1 26.53,89.33 v2(26.99,89.33) 28.22,90.56 v4(30.24,90.56) 37.17,90.56 38.38,89.36 38.38,85.8 37.81,85.23 RT69.1 ; UT9.21 29.17,107.39 v2(29.67,107.88)
  IN3 w0.135: v2(29.67,107.88) 29.67,100.71 26.99,98.03 v2(26.99,89.33)
MUX1_FLIP_SEL_R: length 3.3
  TOP w0.076: 34.69,84.51 33.77,83.59 33.77,83.22 UT5.B2
  TOP w0.112: 34.69,84.51 35.41,85.23 RT69.2
MUX1_I2C_EN: length 5.2
  TOP w0.112: UT9.17 30.61,104.9 30.91,105.19 v2(31.16,105.19)
  BOTTOM w0.102: RT145.1 v1(31.95,106.75)
  BOTTOM w0.112: RT145.1 31.58,105.61 v2(31.16,105.19) 30.81,105.19 RT300.1 RT301.1
MUX1_SSEQ0: length 5
  TOP w0.112: v2(31.19,102.22) 31.06,102.22 30.79,102.5 UT9.11
  BOTTOM w0.102: RT137.1 v1(31.95,101.29)
  BOTTOM w0.112: RT302.1 RT138.1 31.04,102.37 v2(31.19,102.22) 31.34,102.37 RT137.1
MUX1_SSEQ1: length 5.1
  TOP w0.112: UT9.3 27.17,100.01 v2(27.15,99.99)
  BOTTOM w0.102: RT135.1 28.79,98.19 v1(28.98,98.19)
  BOTTOM w0.112: v2(27.15,99.99) 27.37,100.2 RT305.1 ; RT305.1 RT135.1 ; RT305.1 RT136.1
MUX1_USB_EQ0: length 4.1
  TOP w0.112: UT9.38 v2(24.34,102.5)
  BOTTOM w0.112: RT143.1 24.17,101.23 RT304.1 RT144.1 24.72,102.12 v2(24.34,102.5)
MUX1_USB_EQ1: length 5.2
  TOP w0.112: UT9.35 v2(24.34,103.7)
  BOTTOM w0.112: RT141.1 25.09,104.76 RT142.1 RT307.1 24.65,103.01 24.34,103.31 v2(24.34,103.7) 24.28,103.7 v1(23.79,104.19)
MUX1_USB_SEL: length 31
  TOP w0.112: v2(27,88.72) 26.81,88.72 RT376.1 ; v2(29.01,107.91) 28.77,107.68 UT9.22 ; RT90.1 v2(24.6,83.89)
  IN3 w0.135: v2(24.6,83.89) 24.6,87.32 26,88.72 v2(27,88.72) 27.44,89.16 27.44,91.87 29.25,93.67 29.25,97.48 30.06,98.3 30.06,108.12 29.84,108.34 29.44,108.34 v2(29.01,107.91)
NB_PSID: length 8.9
  TOP w0.112: v2(39.44,122.18) 39.1,121.84 39.1,120.5 v1(39.36,120.24)
  TOP w0.254: v2(39.44,122.18) 39.44,122.69 PL3.2 38.68,123.45 PD4.2 PD4.3
  BOTTOM w0.254: v2(39.44,122.18) 39.08,122.55 PJPDC1.1
NRB_BIT: length 13.5
  TOP w0.112: v2(128.4,94.15) 128.4,92.49 v1(131.98,88.9) 134.83,86.05 RC186.1
  BOTTOM w0.076: v2(128.4,94.15) 128.4,94.66 128.84,95.1 UC1.AR7
NTC_IA: length 2.5
  TOP w0.203: PU602.15 53.16,93.97 53.34,93.79 53.69,93.79 53.99,93.5 53.99,93.32 PR635.2
NVME_LED#: length 11.8
  TOP w0.112: v2(25.17,50.56) RN100.1 v1(24.14,51.18)
  IN3 w0.076: JNGFF3.10 26.7,42.17
  IN3 w0.135: v2(25.17,50.56) 25.93,49.79 25.93,44.11 26.7,43.34 26.7,42.17
ONE_DIMM#: length 11.3
  BOTTOM w0.076: UC1.AP7 128.84,95.98 129.59,96.73 130.1,96.73 130.22,96.86 130.63,96.86 130.78,96.71 130.78,96.38 130.96,96.2 134.8,96.2 134.98,96.02 135.28,96.02 135.54,96.29 135.54,96.31
  BOTTOM w0.112: RC267.1 138.3,97.62 RC268.1 136.85,97.62 135.54,96.31
OTG_ID: length 3.8
  TOP w0.076: 31.71,77.31 31.77,77.38 31.77,78.72 UT5.E10
  TOP w0.112: 31.71,77.31 31.55,77.15 v2(31.55,76.97)
  BOTTOM w0.112: RT74.1 31.81,77.24 v2(31.55,76.97) 31.44,76.87 v1(30.94,76.87)
OTGEN/CMIN: length 4.4
  TOP w0.203: 53.63,57.44 53.83,57.24 PU901.20
  TOP w0.254: 53.63,57.44 v1(53.38,57.44) 52.47,57.44 51.55,58.37 PR919.2 PR960.2
PANEL_BKEN_EC: length 260.8
  TOP w0.107: UE1.J9 v2(253.48,90.66)
  TOP w0.112: DV2.2 73.56,123.63 73.56,125.39 v2(73.86,125.69) ; v2(257.63,74.97) v1(257.63,75.6)
  IN2 w0.124: v2(257.63,74.97) 257.17,75.43 255.68,75.43 255.48,75.23 251.45,75.23 249.99,73.77 248.97,73.77 248.74,73.54 245.88,73.54 245.12,74.31 241.42,74.31 238.53,71.42 237.56,71.42 236.56,70.41 235.27,70.41 233.62,68.77 227.67,68.77 226.58,67.68 223.11,67.68 222.49,67.05 207.08,67.05 205.79,68.34 185.9,68.34 184.18,70.07 181.01,70.07 170.72,80.36 170.72,83 168.25,85.47 168.25,87.94 166.34,89.86 166.34,105.63 161.93,110.04 161.93,116.04 159.47,118.5 159.47,121.15 154.4,126.22 148.53,126.22 147.2,127.55 145.97,127.55 144.95,128.57 141.27,128.57 140.72,129.13 138.37,129.13 138.07,128.82 132.54,128.82 131.53,129.83 127.04,129.83 126.7,129.49 124.91,129.49 124.27,130.13 118.44,130.13 117.91,129.61 108.73,129.61 108.23,129.1 104.65,129.1 103.79,129.96 83.97,129.96 80.38,126.37 74.54,126.37 v2(73.86,125.69)
  BOTTOM w0.112: v2(257.63,74.97) 257.91,75.24 257.91,76.69 257.16,77.44 257.16,78.85 258.03,79.72 258.03,81.05 258.69,81.7 258.69,84.33 258.43,84.59 258.43,86.68 258.14,86.98 257.04,86.98 256.58,87.45 256.58,90.36 255.89,91.05 253.88,91.05 v2(253.48,90.66)
PANEL_BKLEN: length 89.5
  TOP w0.112: v2(76.08,122.64) 76.08,122.84 v1(75.77,123.15) 74.94,123.98 DV2.3
  IN2 w0.124: v2(125.7,104.81) 126.37,104.15 130.41,104.15 131.93,105.67 131.93,112.62 133.04,113.73 133.04,121.19 133.48,121.63 133.48,124.07 131.86,125.69 122.43,125.69 121.69,126.43 120.88,126.43 120.45,125.99 117.45,125.99 116.97,125.52 109.56,125.52 109.4,125.36 105.21,125.36 104.93,125.08 98.42,125.08 97.31,123.96 85.37,123.96 84.63,124.7 82.09,124.7 80.03,122.64 v2(76.08,122.64)
  BOTTOM w0.076: UC1.R12 125.7,105.25 v2(125.7,104.81)
PANEL_ID: length 14
  TOP w0.107: UE1.J10 v2(253.48,91.46) ; CE47.1 RE300.2
  TOP w0.112: CE47.1 255.93,99.03 256.46,99.56 v1(256.46,99.76) 256.25,99.97 255.79,99.97 255.29,99.48 v2(254.05,99.48)
  IN1 w0.119: v2(254.05,99.48) 254.05,98.74 253.54,98.23 253.54,96.35 253.26,96.07 253.26,93.56 253.06,93.36 253.06,91.88 v2(253.48,91.46)
PBAT_CHARGER_SMBCLK: length 283.1
  TOP w0.112: v2(54.39,50.37) 54.22,50.54 54.22,51 53.91,51.32 52.92,51.32 52.47,51.76 52.47,52.65 51.41,53.72 50.75,53.72 49.43,55.03 49.43,56.39 49.95,56.91 50.23,56.91 PR922.1 ; v2(263.08,77.98) 263.19,77.86 263.42,77.86 263.79,78.23 263.79,80.13 263.49,80.43 260.41,80.43 260.06,80.78 260.06,81.35 259.55,81.86 RE43.1 259.55,82.13 259.37,82.31 258.42,82.31 257.76,82.97 257.76,84.24 257.52,84.48 256.46,84.48 UE1.N2 ; PD2.3 166.84,62.25 166.84,61.83 166.66,61.65 166.66,60.26 166.99,59.93 167.39,59.93 v2(167.57,59.76) 167.74,59.93 167.95,59.93 168.26,60.24 168.26,60.7 PRP1.3
  IN1 w0.119: v2(167.57,59.76) 167.4,59.93 167.12,59.93 166.72,59.53 165.53,59.53 164.9,58.9 158.99,58.9 158.26,59.63 157.28,59.63 157.05,59.86 146.4,59.86 146.18,59.63 144.82,59.63 143.64,60.82 142.52,60.82 141.22,62.11 141.22,63.49 139.21,65.5 74.15,65.5 73.56,64.91 73.56,63.7 74.06,63.19 74.06,55.9 72.66,54.49 69.61,54.49 68.89,55.22 65.05,55.22 60.9,51.06 59.63,51.06 59.21,50.63 54.89,50.63 54.68,50.84 54.37,50.84 54.23,50.69 54.23,50.53 v2(54.39,50.37)
  IN3 w0.135: v2(167.57,59.76) 167.73,59.92 177.32,59.92 177.68,59.56 180.21,59.56 180.46,59.32 180.46,58.14 180.88,57.72 181.72,57.72 183.16,59.15 195.77,59.15 196.52,58.4 201.03,58.4 202.92,56.51 208.49,56.51 209.04,55.96 214.64,55.96 216.35,54.26 225.62,54.26 226.15,53.72 227.97,53.72 231.08,50.62 243.94,50.62 247.76,54.44 247.76,56.12 246.28,57.61 246.28,60.4 246.56,60.68 246.56,61.59 250.67,65.7 250.67,68.55 253.5,71.38 259.16,71.38 259.72,71.94 259.72,72.87 261.43,74.57 262.79,74.57 263.51,75.3 263.51,77.56 263.09,77.98 v2(263.08,77.98)
PBAT_CHARGER_SMBDAT: length 285.9
  TOP w0.112: PR920.1 50.23,57.15 49.85,57.15 49.19,56.49 49.19,54.94 50.65,53.48 51.31,53.48 52.24,52.55 52.24,51.66 52.82,51.08 53.81,51.08 53.98,50.91 53.98,50.54 v2(53.81,50.37) ; v2(263.08,77.39) 263.31,77.62 263.52,77.62 264.03,78.13 264.03,80.22 263.59,80.67 260.51,80.67 260.31,80.87 260.31,81.68 RE37.1 260.59,82.37 259.65,82.37 259.47,82.55 258.52,82.55 258,83.07 258,84.34 257.62,84.72 256.84,84.72 256.51,85.06 255.88,85.06 UE1.M3 ; PD1.2 167.42,62.51 167.09,62.18 167.09,61.74 166.9,61.55 166.9,60.36 167.09,60.17 167.39,60.17 v2(167.57,60.34) 167.74,60.17 167.85,60.17 168.02,60.34 168.02,61.17 PRP1.2
  IN1 w0.119: v2(53.81,50.37) 53.98,50.54 53.98,50.79 54.27,51.08 54.79,51.08 54.99,50.88 59.1,50.88 59.53,51.31 60.8,51.31 64.95,55.46 68.99,55.46 69.71,54.74 72.56,54.74 73.82,56 73.82,63.09 73.31,63.6 73.31,65.01 74.04,65.74 139.31,65.74 141.47,63.59 141.47,62.22 142.62,61.06 143.74,61.06 144.92,59.88 146.07,59.88 146.3,60.11 157.15,60.11 157.38,59.88 158.36,59.88 159.1,59.14 164.79,59.14 165.43,59.78 166.62,59.78 167.02,60.17 167.4,60.17 v2(167.57,60.34)
  IN3 w0.135: v2(263.08,77.39) 263.11,77.39 263.25,77.26 263.25,75.4 262.68,74.84 261.32,74.84 259.46,72.97 259.46,72.05 259.05,71.64 253.39,71.64 250.41,68.66 250.41,65.81 246.29,61.69 246.29,60.79 246.02,60.51 246.02,57.5 247.5,56.02 247.5,54.54 243.84,50.88 231.18,50.88 228.08,53.99 226.26,53.99 225.73,54.52 216.46,54.52 214.75,56.23 209.14,56.23 208.6,56.77 203.03,56.77 201.14,58.66 196.63,58.66 195.88,59.41 183.05,59.41 181.62,57.98 180.99,57.98 180.72,58.25 180.72,59.43 180.32,59.83 177.79,59.83 177.43,60.18 167.73,60.18 v2(167.57,60.34)
PBAT_PRES#: length 264.7
  TOP w0.112: v2(162.3,56.25) 162.84,56.78 162.84,63.13 163.28,63.57 164.68,63.57 166.58,65.48 167.22,65.48 168.11,64.58 PR1.2 168.81,64.56 PD1.3 168.04,63.79 168.04,61.9 PRP1.1 ; PR931.1 53.94,51.99 55.8,50.13 v1(62.11,50.13) v2(62.89,50.13) ; UE1.F9 v2(250.28,90.66)
  IN1 w0.119: v2(162.3,56.25) 161.57,56.98 158.09,56.98 156.61,58.46 151.73,58.46 150.72,57.44 146.71,57.44 144.32,55.05 142.16,55.05 140.89,53.78 129.79,53.78 126.52,50.51 73.99,50.51 71.93,52.57 70.08,52.57 68.4,54.25 65.84,54.25 62.89,51.3 v2(62.89,50.13)
  IN2 w0.124: v2(236.35,81.41) 236.09,81.41 235.53,81.96 235.53,85.58 237.14,87.18 237.14,87.69 239.71,90.25 249.68,90.25 250.08,90.66 v2(250.28,90.66) ; v2(230.9,53.63) 230.46,53.19 229.82,53.19 229.09,53.91 209.29,53.91 209.05,53.68 204.85,53.68 204.09,52.92 202.58,52.92 201.89,53.61 201.89,56.4 200.34,57.95 196.26,57.95 195.43,58.79 184.02,58.79 183.63,58.39 183.63,57.94 182.45,56.75 179.98,56.75 179.27,57.47 178.34,57.47 176.22,55.35 163.2,55.35 v2(162.3,56.25)
  BOTTOM w0.112: v2(230.9,53.63) 231.01,53.63 233.19,55.82 233.19,56.95 236.05,59.81 236.05,62.39 235.66,62.78 235.66,65.27 235.17,65.76 235.17,67.26 235.02,67.4 235.02,70.02 235.41,70.4 235.41,79.46 236.13,80.19 236.13,81.19 v2(236.35,81.41)
PBAT_PRES#_C: length 3.7
  TOP w0.102: v4(169.61,63.88) 169.61,63.47 v2(169.42,63.28)
  TOP w0.112: v2(169.42,63.28) 168.62,62.49 168.62,62.48
  BOTTOM w0.112: v2(169.42,63.28) 169.21,63.49 168.5,63.49 PBATT1.6
PBAT_SMBCLK_C: length 4
  TOP w0.112: v4(171.29,62.5) 171.04,62.25 v2(170.6,62.25) 169.81,62.25 PRP1.6
  BOTTOM w0.112: v2(170.6,62.25) 170.6,61.34 PBATT1.4
PBAT_SMBDAT_C: length 5
  TOP w0.112: PRP1.7 169.61,62.76 v2(170.11,62.76) 171.35,63.99 v4(171.35,64.3)
  BOTTOM w0.112: PBATT1.5 169.9,62.76 v2(170.11,62.76)
PBATT+_C:
  vias: v2(168.27,57.62) v2(168.27,57.04) v2(168.27,56.46) v2(168.56,58.16) v2(168.85,57.62) v2(168.85,57.04) v2(168.85,56.46) v2(169.14,58.16) v2(169.44,57.62) v2(169.44,57.04) v2(169.44,56.46) v2(169.73,58.16) v2(170.02,57.62) v2(170.02,57.04) v2(170.02,56.46) v2(170.61,57.62) v2(170.61,57.04) v2(170.61,56.46) v2(171.19,57.04) v4(167.38,55.4) v4(168.84,58.68) v4(169.04,54.29)
PCH_ALW_ON: length 150.5
  TOP w0.107: UE1.M8 255.48,89.44 255.87,89.06 256.73,89.06 256.88,88.91 257.53,88.91 257.99,89.37 v2(257.99,89.39)
  TOP w0.112: v1(160.86,61.96) 161.14,61.68 v2(161.14,61.45) 161.14,61 RZ65.1 ; RPE10.3 259.68,97.92 v2(259.77,97.83)
  IN2 w0.124: v2(260.65,67.58) 260.46,67.58 259.08,66.2 256.08,66.2 255.78,65.9 252.68,65.9 251.66,64.88 249.4,64.88 244.85,60.34 244.85,59.46 242.81,57.42 237.1,57.42 234.75,55.08 229.61,55.08 229.39,54.85 216.25,54.85 215.52,55.59 212.01,55.59 211.48,55.05 208.96,55.05 208.64,54.73 207.53,54.73 206.25,56.02 205.46,56.02 201.49,59.98 183.2,59.98 182.61,59.39 180.96,59.39 180.34,60.01 171.28,60.01 169.57,61.72 165.54,61.72 165.08,61.25 161.34,61.25 v2(161.14,61.45)
  BOTTOM w0.112: v2(259.77,97.83) 259.21,97.27 258.09,97.27 256.42,95.59 256.42,91.73 257.99,90.16 v2(257.99,89.39) 257.99,89.27 258.65,88.61 258.65,87.75 260.06,86.33 260.06,83.92 260.18,83.8 260.18,79.2 259.91,78.93 259.91,78.49 259.72,78.3 259.72,77.26 259.33,76.87 259.33,76.36 259.53,76.16 259.53,71.87 258.88,71.21 258.88,69.86 260.32,68.41 260.32,67.91 v2(260.65,67.58)
PCH_BATLOW#: length 13.8
  TOP w0.112: RC72.1 130.11,85.39 130.11,89.97 v1(128.47,91.6) 127.86,92.22 127.84,92.22 127.21,92.86 125.71,92.86 124.78,93.79 v2(124.78,94.21)
  BOTTOM w0.076: v2(124.78,94.21) UC1.AU13
PCH_CL_CLK1: length 177.4
  TOP w0.112: v2(237.82,70.8) 237.59,70.57 233.53,70.57 232.66,71.45 230.79,71.45 v1(229.27,69.93) 228.49,69.14 227.29,69.14 226.32,68.17 217.47,68.17 215.64,70 v2(215.64,70.98)
  BOTTOM w0.076: 132.74,111.37 131.62,111.37 131.56,111.3 131.3,111.3 131.24,111.36 130.76,111.36 130.15,110.75 130.15,110.32 130.33,110.15 130.77,110.15 UC1.G3
  BOTTOM w0.112: v2(215.64,70.98) 216.94,72.28 216.94,74 216.28,74.66 215,74.66 213.56,73.79 211.3,72.76 210.39,72.43 210.39,71.36 209.98,70.95 185.77,70.95 170.73,86 170.73,90.69 168.55,92.87 168.55,101.38 166.57,103.36 166.57,106.65 165.79,107.43 165.79,108.98 164,110.78 164,120.07 162.04,122.04 154.1,122.04 152.76,120.7 152.76,117.84 153.48,117.13 153.48,113.53 152.43,112.48 150.98,112.48 150.7,112.21 149.31,112.21 148.92,112.6 147.22,112.6 146.14,113.68 146.14,115.45 143.94,117.65 138.54,117.65 135.75,114.86 135.75,112.39 134.77,111.42 132.79,111.42 132.74,111.37 ; JNGFF1.42 239.91,70.4 239.57,70.06 238.56,70.06 v2(237.82,70.8)
PCH_CL_DATA1: length 176.4
  TOP w0.112: v2(238.4,70.8) 237.95,70.34 233.96,70.34 232.55,68.93 227.42,68.93 226.42,67.93 217.2,67.93 v1(216.46,68.67) 215.04,70.09 v2(215.04,70.98)
  BOTTOM w0.076: 133.02,110.42 132.74,110.15 132.1,110.15 131.76,109.81 UC1.G2
  BOTTOM w0.112: v2(238.4,70.8) 238.86,70.34 239.24,70.34 239.8,70.9 JNGFF1.40 ; v2(215.04,70.98) 216.71,72.64 216.71,73.93 216.19,74.45 215.06,74.45 213.66,73.59 211.38,72.55 210.62,72.28 210.62,71.28 210.06,70.72 185.65,70.72 173.01,83.36 172.85,83.36 172.58,83.09 172.42,83.09 172.26,83.24 172.26,83.4 172.54,83.68 172.54,83.83 172.38,83.99 172.22,83.99 171.95,83.72 171.79,83.72 171.63,83.88 171.63,84.03 171.91,84.31 171.91,84.47 170.49,85.88 170.49,90.59 168.29,92.79 168.29,101.28 166.36,103.21 166.36,106.56 165.58,107.34 165.58,108.9 163.79,110.69 163.79,119.98 161.95,121.82 154.19,121.82 152.98,120.61 152.98,118.01 153.75,117.24 153.75,113.42 152.6,112.27 151.11,112.27 150.83,111.99 149.22,111.99 148.83,112.38 147.05,112.38 145.88,113.55 145.88,115.33 143.81,117.4 138.67,117.4 136,114.73 136,112.27 134.92,111.19 133.45,111.19 133.02,110.75 133.02,110.42
PCH_CL_RST1#: length 175.5
  TOP w0.112: v2(239.04,70.8) 238.36,70.13 234.08,70.13 232.67,68.72 227.54,68.72 226.52,67.7 216.95,67.7 v1(214.46,70.19) v2(214.46,70.96)
  BOTTOM w0.076: UC1.G1 132.73,109.8 133.27,110.35
  BOTTOM w0.112: JNGFF1.38 239.64,71.4 v2(239.04,70.8) ; v2(214.46,70.96) 214.63,71.14 214.63,71.15 214.87,71.39 214.89,71.39 216.48,72.99 216.48,73.85 216.1,74.23 215.15,74.23 213.56,73.28 211.43,72.32 210.84,72.12 210.84,71.21 210.13,70.5 185.52,70.5 173.3,82.71 172.49,82.71 170.87,84.33 170.87,84.49 171.15,84.76 171.15,84.92 170.99,85.08 170.83,85.08 170.56,84.8 170.4,84.8 170.25,84.96 170.25,90.5 168.04,92.7 168.04,101.17 166.15,103.07 166.15,106.47 165.37,107.25 165.37,108.81 163.57,110.6 163.57,119.89 161.86,121.61 154.28,121.61 153.19,120.52 153.19,118.18 154.02,117.35 154.02,113.31 152.77,112.06 151.2,112.06 150.92,111.78 149.13,111.78 148.74,112.17 146.88,112.17 145.63,113.42 145.63,115.2 143.69,117.14 138.77,117.14 136.26,114.63 136.26,112.16 135.02,110.93 133.6,110.93 133.27,110.6 133.27,110.35
PCH_DPWROK: length 205.1
  TOP w0.102: UE7.1 241.85,100.03 v4(242.06,100.24)
  TOP w0.112: v4(242.06,100.24) 242.06,106.19 242.62,106.74 243.33,106.74 RE536.2 ; RC220.1 CC266.1 125.8,80.5 RC215.1 125.79,80.52 125.27,80 124.48,80 123.68,80.8 123.46,80.8 v2(123.09,81.16) ; v2(242.9,98.56) UE7.1
  IN1 w0.119: v2(123.09,81.16) 123.09,81.67 125.46,84.04 131.51,84.04 v2(132.23,83.32)
  IN2 w0.124: v2(244.4,67.88) 243.66,67.14 243.66,65.76 240.93,63.03 237.92,63.03 236.68,61.78 234.88,61.78 234.64,61.55 227.29,61.55 226.42,62.42 218.81,62.42 218.1,61.71 215.77,61.71 214.72,62.76 204.41,62.76 203.24,63.93 202.97,63.93 202.96,63.94 184.47,63.94 182.47,65.95 175.51,65.95 174.11,67.35 163.78,67.35 160.42,70.71 151.58,70.71 149.35,72.93 149.35,80.27 145.82,83.8 145.82,85.43 144.3,86.94 136.87,86.94 134.77,84.85 133.75,84.85 v2(132.23,83.32)
  BOTTOM w0.076: 123.59,87.26 122.22,88.63 122.22,89.37 121.56,90.03 121.56,90.57 UC1.BB20
  BOTTOM w0.112: v2(123.09,81.16) 123.09,82.69 123.59,83.2 123.59,87.26 ; v2(242.9,98.56) 243.74,97.72 243.74,90.63 242.87,89.76 242.87,87.53 243.2,87.2 243.2,86.11 243.18,86.09 243.18,85.73 243.6,85.31 243.6,82.03 244.68,80.94 244.68,78.44 245.34,77.79 245.34,76.26 246.68,74.91 246.68,71.92 245.49,70.74 245.49,70.16 244.52,69.19 244.52,68.01 v2(244.4,67.88)
PCH_DPWROK_EC: length 10.9
  TOP w0.112: RE34.1 v2(245.07,95.39) ; UE1.F8 v2(250.28,89.86)
  BOTTOM w0.112: v2(250.28,89.86) 249.88,90.26 249.88,94.02 249.02,94.88 247.8,94.88 247.29,95.39 v2(245.07,95.39)
PCH_JTAG_TCK: length 67.3
  TOP w0.112: RC86.1 97.29,119.29 97.94,118.64 97.94,118.19 v2(98.71,117.42) ; v2(86.38,132.22) 86.3,132.13 86.3,128.08 v4(85.93,127.71) 84.31,126.09 81.51,126.09 78.89,123.47 78.89,118.54 77.94,117.59 77.94,113.72 v2(77.17,112.95)
  IN3 w0.135: v2(98.71,117.42) 97.59,118.55 97.59,120.64 96.24,121.98 91.31,121.98 88.34,119.01 87.55,119.01 86.64,118.1 78.71,118.1 77.82,117.21 77.82,113.6 77.17,112.95 v2(77.17,112.95)
  BOTTOM w0.076: UC1.B56 100.3,112.87 100.3,113.09 100.24,113.21 100.24,113.47 100.42,113.65 100.42,114.53 100.28,114.68 100.28,115.53 99.91,115.9 99.91,116.22 v2(98.71,117.42)
  BOTTOM w0.112: JXDP1.55 87.31,130.73 86.49,131.56 86.49,132.12 v2(86.38,132.22)
PCH_JTAG_TDI: length 31.9
  TOP w0.112: v4(97.95,116.2) 98.54,116.79 v2(98.71,116.79)
  IN1 w0.119: v2(80.99,117.55) 81.05,117.61 84.03,117.61 84.99,116.65 95.05,116.65 95.59,116.1 98.03,116.1 v2(98.71,116.79)
  BOTTOM w0.076: UC1.D59 99.37,111.69 99.45,111.96 99.45,112.07 99.53,112.35 99.57,112.51 99.59,112.55 99.59,112.8 99.55,112.89 99.55,113.08 99.59,113.18 99.59,113.54 99.43,113.7 99.43,116.07 v2(98.71,116.79)
  BOTTOM w0.102: RC81.1 CC304.1 98.54,119.75 98.54,119.36 98.19,119.01 98.19,117.3 v2(98.71,116.79)
  BOTTOM w0.112: RC229.2 80.67,117.87 v2(80.99,117.55)
PCH_JTAG_TDO: length 28.5
  TOP w0.112: v2(84.73,117.55) v4(85.47,117.55)
  IN1 w0.119: v2(84.73,117.55) 85.39,116.9 95.15,116.9 95.69,116.35 97.43,116.35 97.82,116.74 97.82,117.17 v2(98.71,118.06)
  BOTTOM w0.076: UC1.A56 100.61,113.41 100.61,114.58 100.44,114.75 100.44,115.75 100.16,116.03 100.16,116.6
  BOTTOM w0.102: RC82.1 CC303.1 99.91,120.22 100.33,119.8 100.33,118.79 100.1,118.57 99.22,118.57 v2(98.71,118.06) 100.16,116.6
  BOTTOM w0.112: v2(84.73,117.55) 84.21,117.55 RC230.2
PCH_JTAG_TMS: length 39.6
  TOP w0.112: v2(98.71,116.15) 99.3,116.74 v4(99.3,117.59) 99.3,120.31 RC130.1
  IN1 w0.119: v2(78.89,117.55) 79.79,116.65 84.3,116.65 84.79,116.16 89.57,116.16 92.38,113.35 97.99,113.35 98.71,114.07 v2(98.71,116.15)
  BOTTOM w0.076: v2(98.71,116.15) 99.25,115.61 99.25,113.64 99.42,113.47 99.42,113.21 99.36,113.09 99.36,112.94 99.42,112.75 99.42,112.58 99.34,112.32 UC1.C59
  BOTTOM w0.112: v2(78.89,117.55) 78.89,117.61 78.63,117.87 78.63,119.79 77.48,120.94 RC228.2
PCH_PCIE_WAKE#: length 187.1
  TOP w0.102: v2(254.63,83.25) 254.68,83.3 UE1.L1
  TOP w0.112: v2(135.99,79.84) 136.4,79.44 RC67.1 ; v2(259.29,79.64) 259.85,79.08 RE274.2
  IN1 w0.119: v2(259.29,79.64) 256.39,79.64 255.45,80.58 255.45,82.54 254.74,83.25 v2(254.63,83.25)
  IN2 w0.124: v2(135.99,79.84) 136.47,80.33 136.47,81.39 136.12,81.75 136.12,83.27 136.83,83.98 140.77,83.98 142.45,82.3 142.45,80.01 143.08,79.39 143.08,78.85 144.25,77.68 144.25,74.51 146.51,72.25 146.51,71.84 149.4,68.95 149.81,68.95 150.31,68.45 158.89,68.45 162.3,65.04 170.52,65.04 173.89,61.67 202.26,61.67 203.44,60.5 213.79,60.5 214.83,59.45 219.94,59.45 220.91,58.49 236.24,58.49 236.53,58.78 242.25,58.78 243.45,59.98 243.45,60.94 245.79,63.27 245.79,64.67 247.85,66.74 249.32,66.74 249.7,67.11 251.3,67.11 252.17,67.98 258.09,67.98 258.72,68.62 258.72,69.1 v2(258.34,69.48)
  BOTTOM w0.076: 126.92,86.47 125.67,87.73 125.46,87.73 123.79,89.41 123.79,90.6 UC1.BB15
  BOTTOM w0.112: v2(258.34,69.48) 258.39,69.53 258.39,72.78 258.11,73.06 258.11,74.36 258.37,74.61 258.37,76.9 257.63,77.63 257.63,78.47 258.8,79.64 v2(259.29,79.64) ; v2(135.99,79.84) 135.56,80.27 135.56,81.34 134.09,82.81 133.82,82.81 132.7,83.93 129.18,83.93 126.92,86.19 126.92,86.47
PCH_PLTRST#: length 60.8
  TOP w0.112: v2(153.99,119.23) 153.48,118.72 153.48,113.71 153.19,113.42 153.19,106.47 154.66,104.99 154.66,96.29 153.85,95.48 v4(151.31,95.48) 149.92,95.48 149.68,95.72 148.87,95.72 148.41,95.26 v2(148.11,95.26)
  IN3 w0.135: v2(148.11,95.26) 147.01,95.26 146.63,94.88 132.25,94.88 130.75,96.38 129.06,96.38 128.87,96.2 128.87,95.87 128.67,95.67 127.89,95.67 v2(127.48,96.07)
  BOTTOM w0.102: v2(127.48,96.07) 127.34,96.07 UC1.AN10
  BOTTOM w0.112: 155.98,119.36 155.98,119.68 156.1,119.79 UC7.1 157.23,120.34 RC244.1 RC62.1 RC60.1 ; 155.98,119.36 156.21,119.14 UC7.2 ; 155.98,119.36 155.86,119.23 v2(153.99,119.23)
PCH_PLTRST#_5105: length 24.8
  TOP w0.107: UE1.K1 253.88,83.34 254.56,82.66 v2(254.63,82.66)
  TOP w0.112: UE6.4 269.45,79.43 RE340.1 270.51,80.03 v2(270.51,79.56) v1(270.51,79.06)
  IN1 w0.119: v2(270.51,79.56) 269.9,79.56 268.58,78.24 265.8,78.24 264.65,79.4 259.73,79.4 259.4,79.07 256.18,79.07 255.01,80.24 255.01,82.28 v2(254.63,82.66)
PCH_PLTRST#_AND: length 480.8
  TOP w0.112: 237.15,61.56 237.15,59.93 236.84,59.62 236.14,59.62 235.18,60.59 233.39,60.59 232.4,59.6 229.98,59.6 229.53,59.14 227.82,59.14 227.3,59.66 224.82,59.66 224.36,59.2 CZ61.1 RZ114.1 ; 237.15,61.56 237,61.71 233.73,61.71 233.25,62.19 v2(228.64,62.19) ; 237.15,61.56 238.33,62.73 v2(238.33,63.69) ; v2(25.2,48.59) 24.09,48.59 v2(23.09,47.59) ; v2(271.48,67.57) 272.78,66.27 UR1.1 ; v2(184.6,51.93) 181.14,51.93 179.37,53.69 179.37,56.25 180.54,57.41 180.54,61.43 v1(181.81,62.7) v2(182.57,63.46) ; v2(155.9,118.79) 154.64,117.53 154.64,115.92 155.1,115.47 155.1,112.44 154.98,112.32 154.98,107.18 155.64,106.52 v2(155.64,106.48)
  IN1 w0.076: JNGFF3.50 16.7,42.23
  IN1 w0.119: v2(227.66,76.5) 227.66,76.74 228.46,77.54 228.46,78 232.12,81.66 v2(232.12,82.29) ; v2(184.6,51.93) 184.02,52.5 179.91,52.5 177.96,54.46 172.49,54.46 171.75,55.2 164.29,55.2 162.08,57.41 158.27,57.41 156.79,58.89 151.54,58.89 150.98,58.33 149.06,58.33 148.47,58.91 147.09,58.91 146.79,58.61 146.79,58.25 144.12,55.59 141.96,55.59 140.61,54.24 129.59,54.24 126.29,50.94 74.17,50.94 72.11,52.99 70.26,52.99 68.52,54.73 65.72,54.73 60.89,49.9 53.03,49.9 51.79,51.14 44.3,51.14 43.13,49.97 41.17,49.97 40.48,50.66 33.92,50.66 31.85,48.59 v2(25.2,48.59) ; v2(228.64,62.19) 228.15,62.68 227.85,62.68 227.81,62.72 220.7,62.72 220.45,62.97 220.31,63.11 185.74,63.11 184.96,63.89 183.01,63.89 v2(182.57,63.46) 182.15,63.46 174.69,70.92 174.06,71.44 173.02,72.48 169.75,72.48 168.45,73.77 168.45,77.8 165.3,81.36 165.3,83.04 164.14,85.48 162.99,85.48 162.76,85.71 162.76,87.82 160.13,90.45 160.13,101.01 158.1,103.05 157.24,103.05 155.64,104.65 v2(155.64,106.48) ; v2(23.09,47.59) 21.39,45.88 19.48,45.88 16.7,43.1 16.7,42.23
  BOTTOM w0.112: v2(238.33,63.69) 238.33,64.2 238.47,64.34 ; v2(232.12,82.29) 232.56,82.74 232.56,88.38 232.24,88.7 232.24,91.01 232.74,91.51 232.74,95.08 237.16,99.5 JNGFF2.42 238.87,99.5 239.33,99.96 239.33,100.28 239.83,100.78 239.83,102.24 240.96,103.37 245.18,103.37 245.7,102.85 251.04,102.85 251.64,103.45 264.83,103.45 266.42,101.86 266.42,98.95 266.86,98.52 267.6,98.52 270.22,95.9 270.22,94.65 270.58,94.29 270.58,88.23 271.36,87.45 271.36,67.69 v2(271.48,67.57) ; JNGFF1.52 239.77,67.9 238.47,66.6 238.47,64.34 ; JNGFF1.66 240.05,64.4 239.99,64.34 238.47,64.34 ; RC325.1 156.77,116.64 156.12,116.64 RC65.1 154.78,117.98 UC7.4 155.6,118.49 v2(155.9,118.79) ; v2(227.66,76.5) 227.53,76.5 222.71,71.68 222.71,69.63 224.94,67.4 224.94,65.9 228.64,62.19 v2(228.64,62.19)
PCH_PLTRST#_EC: length 187.9
  TOP w0.112: v2(160.01,120.04) 159.89,119.92 157.64,119.92 v4(156.89,119.17) 156.3,118.58 156.3,115.85 155.96,115.51 155.96,111.11 155.42,110.57 155.42,107.33 v2(155.65,107.1) ; v2(262.8,75.69) 263.36,75.69 265.19,77.52 265.19,79.75 265.52,80.08 UE6.2
  IN1 w0.119: v2(262.8,75.69) 262.8,74.94 261.98,74.12 259.34,74.12 258.92,73.7 256.4,73.7 v2(255.92,73.22) 252.82,73.22 252.33,72.73 251.22,72.73 249.54,71.05 246.25,71.05 244.25,69.05 235.37,69.05 233.01,66.69 233.01,65.42 230.69,63.1 228.18,63.1 228.14,63.14 220.88,63.14 220.49,63.54 195.85,63.54 arc(184.38,65.67) 174.43,71.77 173.81,72.32 173.07,73.06 170.97,73.06 170.5,73.53 169.45,73.53 168.88,74.1 168.88,77.96 165.78,81.5 165.78,83.12 arc(164.27,86.51) 163.12,90.04 162.35,91.29 161.17,92.47 161.17,101.23 158.9,103.5 158.05,103.5 156.09,105.46 156.09,106.65 v2(155.65,107.1)
  BOTTOM w0.112: RC244.2 159.7,120.34 v2(160.01,120.04) ; RE375.2 249.35,55.5 249.35,62.49 252.41,65.55 252.41,68.27 252.97,68.84 253.94,68.84 254.15,69.05 254.15,70.98 255.9,72.73 255.9,73.2 v2(255.92,73.22)
PCH_POPIRCOMP: length 11.2
  TOP w0.381: RC89.1 125.12,84.66 125.75,85.29 v4(125.75,87.02) 125.75,88.25 v2(125.47,88.53)
  IN2 w0.381: v2(125.47,88.53) 125.47,90.59 123.21,92.85 123.21,93.33 v2(122.89,93.66)
  BOTTOM w0.254: UC1.AU16 123.11,93.63 v2(122.89,93.66)
PCH_PWROK: length 166
  TOP w0.112: RC411.1 122.74,81.8 v2(122.16,82.38) ; v2(45.87,58.3) 45.49,58.68 44.73,58.68 v4(43.14,60.27) 37.79,65.62 37.79,76.1 39.88,78.19 39.88,80.17 43.93,84.23 43.93,89.12 PR614.1
  IN1 w0.076: v2(122.16,82.38) 121.64,81.86 121.64,81.15
  IN1 w0.119: 121.64,81.15 118.84,78.35 87.72,78.35 78.42,87.65 75.34,87.65 74.7,87.01 v2(74.7,86.75)
  IN3 w0.135: v2(74.7,86.75) 74.7,84.72 75.31,84.11 75.31,73.37 74.08,72.14 74.08,65.81 73.63,65.37 73.63,56.02 73.23,55.61 70.53,55.61 69.95,56.2 62.36,56.2 60.48,54.32 59.19,54.32 58.71,54.8 52.98,54.8 49.92,57.86 46.32,57.86 v2(45.87,58.3)
  BOTTOM w0.076: UC1.BA20 121.18,91.07 121.18,90.51 121.39,90.31 121.39,89.97 122.04,89.32 122.04,88.56 123.34,87.26 123.34,87.13
  BOTTOM w0.112: v2(122.16,82.38) 123.34,83.56 123.34,87.13
PCH_RSMRST#: length 75.5
  TOP w0.112: UZ6.1 203.8,59.72 v1(205.01,60.93) 205.71,61.63 219.34,61.63 220.33,62.61 236.66,62.61 v2(237.74,63.69) ; RE364.2 v2(261.43,84.11) RE342.1 ; RE363.2 v2(253.01,79.18)
  IN1 w0.119: v2(244.75,72.27) 245.93,73.45 246.41,73.45 246.71,73.75 248.63,73.75 249.02,74.14 249.02,74.79 249.35,75.12 251.08,75.12 253.21,77.25 253.21,77.91 253.01,78.12 v2(253.01,79.18)
  IN3 w0.135: v2(244.75,72.27) 244.75,70.69 243.05,68.99 243.05,66.06 240.25,63.26 237.99,63.26 237.74,63.51 v2(237.74,63.69) ; v2(253.01,79.18) 255.78,81.95 259.26,81.95 261.42,84.11 v2(261.43,84.11)
PCH_RSMRST#_AND: length 113.9
  TOP w0.112: v2(139.55,77.94) 139.06,78.43 137.97,78.43 137.41,78.98 135.76,78.98 135.48,78.7 131.19,78.7 v1(130.91,78.98) 129.99,79.9 128.62,79.9 127.09,81.43 RC75.1 RC215.2 ; RC215.2 125.82,82.81 125.52,83.11 124.69,83.11 124.55,83.26 124.55,85.1 v2(124.99,85.55) ; RC215.2 RC124.1 ; v2(206.12,55.51) 206.12,55.76 204.54,57.34 204.54,58.23 204.73,58.42 UZ6.4
  IN2 w0.124: v2(206.12,55.51) 205.87,55.76 205.39,55.76 201.43,59.73 183.26,59.73 182.7,59.16 180.85,59.16 180.24,59.78 171.16,59.78 169.44,61.49 165.7,61.49 165.18,60.97 160.98,60.97 160.73,61.22 160.73,64.18 159.33,65.58 149.29,65.58 148.64,66.23 147.98,66.23 143.38,70.83 143.38,71.87 139.39,75.86 139.39,77.79 v2(139.55,77.94)
  BOTTOM w0.076: 124.1,87.19 124.1,87.31 122.6,88.81 122.6,90.34 122.41,90.53 122.41,90.79 122.46,90.91 122.46,91.05 122.4,91.28 122.4,91.4 122.47,91.61 122.57,91.72 122.67,91.83 UC1.AY17
  BOTTOM w0.112: 124.1,87.19 124.1,86.12 124.67,85.55 v2(124.99,85.55)
PCH_RSMRST#_GPIO204: length 4.2
  TOP w0.107: RE363.1 253.01,82.11 v1(252.69,82.42) 252.76,82.48 252.76,84.21 252.31,84.66 UE1.H2
PCH_RTCRST#: length 220.3
  TOP w0.112: JAPS1.9 260.56,107.36 256.36,103.16 256.36,102.93 255.73,102.3 255.73,101.61 255.17,101.05 253,101.05 252.63,101.42 252.63,102.44 251.57,103.49 248.47,103.49 RE94.2 247.17,103.15 247.17,100.34 v2(246.8,99.97) ; v2(130.07,81.35) 129.27,81.35 v4(129.25,81.38) 128.24,82.38 CC25.1 RC57.1 127.9,83.17 127.9,83.82 128.36,84.28 128.36,89.35 125.75,91.96 124.33,91.96 123.42,92.87 123.42,93.34 123.49,93.41 123.49,94.52 123.39,94.62 123.39,96.5 123.58,96.7 v2(123.86,96.7)
  IN2 w0.124: v2(130.07,81.35) 132.04,81.35 137.11,86.42 144.19,86.42 145.34,85.27 145.34,83.64 148.66,80.32 148.66,72.6 150.37,70.9 150.72,70.9 151.37,70.25 160.13,70.25 163.52,66.87 172.87,66.87 174.93,64.81 175.73,64.81 176.14,65.23 182.55,65.23 184.29,63.48 203.01,63.48 204.19,62.3 214.54,62.3 215.58,61.26 218.29,61.26 219,61.97 226.23,61.97 227.15,61.05 234.85,61.05 235.08,61.28 236.9,61.28 238.14,62.52 241.12,62.52 241.81,63.21 241.83,63.21 245.62,66.99 v2(245.62,67.91)
  BOTTOM w0.102: UC1.AM16 123.5,97.05 v2(123.86,96.7)
  BOTTOM w0.112: v2(130.07,81.35) 129.78,81.35 CMOS1.1 ; v2(246.8,99.97) 246.44,99.97 245.39,98.92 245.39,97.42 244.5,96.53 244.5,95.01 244.88,94.63 245.39,94.63 245.87,94.14 245.87,86.03 245.01,85.16 245.01,83.65 245.66,83 245.66,81.21 246.61,80.26 246.61,78.93 246.66,78.88 246.66,76.3 247.32,75.64 247.32,71.65 246.21,70.55 246.21,69.87 245.2,68.86 245.2,68.32 245.21,68.31 245.21,68.31 v2(245.62,67.91)
PCH_RTCX1: length 25.2
  TOP w0.112: YC2.1 134.81,81.45 CC23.1 135.1,82.31 RC54.2 133.35,84.06 v1(133.35,84.83) v2(133.35,86.7)
  IN1 w0.119: v2(133.35,86.7) 132.36,87.69 129.46,87.69 125.45,91.7 124.03,91.7 122.43,93.31 122.43,96.2 v2(121.99,96.64)
  BOTTOM w0.102: UC1.AM18 122.4,97.05 v2(121.99,96.64)
PCH_RTCX2: length 23.2
  TOP w0.112: RC54.1 RC296.1 v1(132.94,83.58) 132.94,86.47 v2(132.71,86.7)
  IN1 w0.119: v2(132.71,86.7) 132.15,87.26 129.26,87.26 125.22,91.3 123.59,91.3 121.54,93.35 121.54,96.29 121.07,96.75 v2(121.07,96.76)
  BOTTOM w0.102: v2(121.07,96.76) 121.37,97.05 UC1.AM20
PCH_RTCX2_R: length 2.6
  TOP w0.112: YC2.2 132.31,81.45 CC26.1 RC296.2
PCH_SMB_ALERT#: length 6.1
  TOP w0.112: v2(127.66,105.85) 127.66,105.55 127.85,105.36 v1(131.09,105.36) 132.03,105.36 RC23.1
  BOTTOM w0.102: v2(127.66,105.85) 127.49,105.85 127.08,105.44 UC1.R10
PCH_SPI_CLK: length 39.9
  TOP w0.112: v2(133.29,92.55) 133.29,91.91 133.82,91.39 135.37,91.39 136.53,92.55 138.1,92.55 140.52,94.97 143.57,94.97 144.88,93.66 146.58,93.66 147.12,93.13 147.75,93.13 148.27,92.6 v4(148.79,92.6) 151.03,92.6 152.1,93.67 154.14,93.67 155.62,95.16 158.56,95.16 v2(159.47,96.07)
  BOTTOM w0.076: v2(133.29,92.55) 133.05,92.55 132.69,92.91 132.25,92.91 131.95,93.2 UC1.AV2
  BOTTOM w0.112: JSPI1.13 163.76,97.91 RC35.1 163.74,97.81 163.22,97.29 162.58,97.29 161.36,96.07 v2(159.47,96.07)
PCH_SPI_CLK_0_R: length 14
  TOP w0.112: v2(156.3,93.17) 154.82,93.17 v4(154.74,93.08) 154.34,92.69 153.96,92.69 153.79,92.51 153.79,92.14 153.95,91.98 154.57,91.98 155.24,92.66 156.86,92.66 RC29.1 157.24,92.86 157.35,92.97 157.35,93.25 157.2,93.41 157.13,93.48 RPC1.6
  BOTTOM w0.107: 154.27,92.78 154.42,92.78 154.63,92.57 154.63,91.8 154.74,91.7 154.95,91.7 155.06,91.8 155.06,93.06 155.17,93.17 155.68,93.17 155.68,93.17 v2(156.3,93.17)
  BOTTOM w0.112: UC5.6 154.27,92.78
PCH_SPI_CLK_1_R: length 14.6
  TOP w0.112: RC28.1 156.61,100.19 v2(156.71,100.09) 156.71,100.16 156.86,100.3 157.2,100.3 157.31,100.19 v1(157.31,99.85) 157.31,99.83 157.14,99.66 157.14,99.08 156.88,98.83 RC408.2
  BOTTOM w0.107: UC6.6 154.43,98.69 154.53,98.58 154.53,97.83 154.71,97.65 154.85,97.65 154.96,97.76 154.96,98.58 155.07,98.69 155.28,98.69 155.39,98.58 155.39,97.68 155.44,97.63 155.64,97.63 155.81,97.8 155.81,98.58 156.13,98.9 156.13,99.51 156.02,99.62 155.02,99.62 154.91,99.73 154.91,99.94 155.02,100.05 156.02,100.05 156.13,100.15 156.13,100.54 156.24,100.65 156.69,100.65 156.8,100.54 156.8,100.17 v2(156.71,100.09)
PCH_SPI_CLK_2_R: length 2.8
  BOTTOM w0.112: UZ12.19 159.83,105.76 RZ63.2 RZ60.2
PCH_SPI_CLK_R1: length 20.8
  TOP w0.112: RPC1.3 157.13,96.41 v2(157.38,96.66) 157.13,96.91 157.13,97.53 RC408.1
  BOTTOM w0.107: 158.77,100.41 158.77,97.5 158.24,96.96 157.48,96.96 157.38,96.86 v2(157.38,96.66)
  BOTTOM w0.112: JSPI1.14 163.19,98.41 162.83,98.04 RC35.2 162.52,97.93 161.44,96.85 158.52,96.85 158.33,96.66 v2(157.38,96.66) ; RZ60.1 158.58,104.19 v1(158.58,103.2) 158.58,102.41 158.77,102.22 158.77,100.41
PCH_SPI_CS#0: length 61.8
  BOTTOM w0.076: UC1.AU3 131.32,93.89 131.58,94.16 131.87,94.16 132.28,94.32 133.02,94.32 133.07,94.37 135.54,94.37
  BOTTOM w0.112: 135.54,94.37 135.81,94.37 136.24,93.94 138.58,93.94 139.98,95.34 142.69,95.34 143.03,95.18 146.73,95.18 147.56,94.34 149.14,94.34 150.04,95.24 150.04,96.34 150.15,96.45 151.17,96.45 151.28,96.56 151.28,96.79 151.17,96.9 150.15,96.9 150.04,97.01 150.04,97.22 150.15,97.34 151.6,97.34 151.71,97.45 151.71,97.67 151.6,97.78 150.15,97.78 150.04,97.9 150.04,98.12 150.15,98.23 151.63,98.23 151.74,98.34 151.74,98.57 151.63,98.68 150.15,98.68 150.04,98.79 150.04,99.01 150.15,99.12 151.63,99.12 151.74,99.24 151.74,99.46 151.63,99.57 150.15,99.57 150.04,99.68 150.04,99.91 150.15,100.02 151.32,100.02 151.43,100.13 151.43,100.35 151.32,100.47 150.15,100.47 150.04,100.58 150.04,100.8 150.15,100.91 v1(150.39,100.91) 151.97,100.91 152.09,100.79 152.09,100.34 152.41,100.02 152.41,96.92 152.53,96.81 155.81,96.81 156.11,97.1 156.68,97.1 156.87,96.91 156.87,96.34 157.04,96.17 158.62,96.17 159.96,94.82 161.46,94.82 161.96,95.32 163.28,95.32 163.74,95.78 RC36.1 164.82,96.91 JSPI1.11
PCH_SPI_CS#0_R1: length 3.3
  BOTTOM w0.112: JSPI1.12 164.43,97.41 RC37.1 163.74,96.67 163.35,96.28 163.22,96.28 162.83,95.88 RC36.2
PCH_SPI_CS#0_R2: length 4.6
  TOP w0.112: v2(162.04,96.04) 163.51,96.04 v4(163.83,96.35)
  BOTTOM w0.112: UC5.1 161.33,95.32 v2(162.04,96.04) 162.72,96.72 RC37.2
PCH_SPI_CS#1: length 65.3
  TOP w0.112: v2(155.84,96.27) 155.34,96.76 155.34,100.52 155.43,100.61 155.43,102.72 155.85,103.13 157.53,103.13 157.73,103.34 159.26,103.34 159.47,103.12 v2(159.47,102.28)
  BOTTOM w0.076: 135.54,94.14 133.28,94.14 133.27,94.16 132.31,94.16 132.06,94.04 132.06,94.04 132.05,94.03 131.91,93.89 UC1.AU2
  BOTTOM w0.112: v2(155.84,96.27) 155.57,96.53 151.95,96.53 151.62,96.2 151.62,96.09 151.51,95.98 150.7,95.98 150.58,95.87 150.58,95.65 150.7,95.54 151.48,95.54 151.62,95.4 151.62,95.2 151.51,95.09 150.7,95.09 150.58,94.98 150.58,94.75 150.72,94.62 151.51,94.62 151.62,94.5 151.62,94.02 151.62,94.02 151.62,93.5 151.51,93.39 151.29,93.39 151.17,93.5 151.17,94.02 151.06,94.13 150.85,94.13 150.74,94.02 150.74,93.5 150.63,93.39 150.4,93.39 150.29,93.5 150.29,94.02 150.18,94.13 149.95,94.13 149.84,94.02 149.84,93.5 149.73,93.39 149.51,93.39 149.4,93.5 149.4,94.02 149.28,94.13 149.07,94.13 148.96,94.02 148.96,93.67 148.85,93.56 148.62,93.56 148.51,93.67 148.51,94.02 148.4,94.13 148.18,94.13 148.07,94.02 148.07,93.65 147.95,93.53 147.73,93.53 147.62,93.65 147.62,94.02 147.51,94.13 147.29,94.13 147.18,94.02 147.18,93.7 147.07,93.58 146.86,93.58 146.73,93.71 146.73,94.85 146.62,94.97 146.42,94.97 146.31,94.85 146.31,93.72 146.2,93.61 145.98,93.61 145.87,93.72 145.87,94.85 145.75,94.97 145.53,94.97 145.42,94.85 145.42,93.72 145.31,93.61 145.08,93.61 144.97,93.72 144.97,94.85 144.86,94.97 144.64,94.97 144.52,94.85 144.52,94.33 144.41,94.22 144.19,94.22 144.08,94.33 144.08,94.85 143.97,94.97 142.91,94.97 142.58,95.12 140.17,95.12 138.71,93.66 136.19,93.66 135.7,94.14 135.54,94.14 ; JSPI1.19 166.07,100.91 166.2,101.04 166.2,101.59 v1(164.78,103.01) 163.33,103.01 RC32.2 162.38,102.06 159.7,102.06 v2(159.47,102.28)
PCH_SPI_CS#1_R1: length 2.7
  BOTTOM w0.112: JSPI1.20 163.94,101.41 RC42.1 RC32.1
PCH_SPI_CS#1_R2: length 2.3
  BOTTOM w0.112: UC6.1 161.76,101.23 162.14,101.61 RC42.2
PCH_SPI_CS#2: length 47.8
  TOP w0.112: v2(158.08,104.08) 157.49,103.49 155.65,103.49 155.09,102.93 v1(155.09,102.13) 155.09,95.39 153.87,94.17 151.9,94.17 151.35,93.62 147.33,93.62 146.79,94.17 145.07,94.17 144.7,94.53 144.7,94.69 145.14,95.12 145.14,95.28 144.98,95.44 144.82,95.44 144.39,95.01 144.23,95.01 143.45,95.79 143.45,96.06 143.33,96.18 143.11,96.18 143,96.06 143,95.58 142.89,95.46 142.66,95.46 142.55,95.58 142.55,95.65 142.44,95.76 142.22,95.76 142.11,95.65 142.11,95.58 141.99,95.46 141.77,95.46 141.66,95.58 141.66,95.65 141.55,95.76 141.32,95.76 141.21,95.65 141.21,95.58 141.1,95.46 140.32,95.46 139.97,95.12 139.81,95.12 139.42,95.51 139.26,95.51 139.1,95.36 139.1,95.2 139.5,94.8 139.5,94.65 139.34,94.49 139.18,94.49 138.79,94.88 138.63,94.88 138.47,94.72 138.47,94.56 138.87,94.17 138.87,94.01 138.46,93.61 138.12,93.61 138.01,93.72 138.01,94.53 137.9,94.64 137.68,94.64 137.56,94.53 137.56,93.72 137.45,93.61 137.23,93.61 137.12,93.72 137.12,94.53 137.01,94.64 136.78,94.64 136.67,94.53 136.67,93.72 136.56,93.61 136.34,93.61 136.22,93.72 136.22,94.53 136.11,94.64 135.89,94.64 135.78,94.53 135.78,93.72 135.66,93.61 v2(135.28,93.61)
  BOTTOM w0.076: UC1.AU1 133.77,93.89
  BOTTOM w0.102: v2(135.28,93.61) 135,93.89 133.77,93.89
  BOTTOM w0.112: RZ61.1 v2(158.08,104.08)
PCH_SPI_CS#2_R: length 3.5
  BOTTOM w0.112: UZ12.20 159.33,106.39 159.03,106.09 158.56,106.09 RZ61.2 RZ113.1
PCH_SPI_D0: length 40.8
  TOP w0.112: v2(133.75,93.29) 135.32,94.86 138.3,94.86 139.38,95.93 140.11,95.93 144.65,100.47 147.08,100.47 148.11,99.44 RC10.2 v1(150.72,99.44) 151.43,99.44 v2(152.48,100.5) ; v2(158.19,100.24) 158.79,99.64 v2(159.41,99.64)
  BOTTOM w0.076: UC1.AV3 131.04,93.46 133.59,93.46 v2(133.75,93.29)
  BOTTOM w0.112: v2(152.48,100.5) 152.58,100.59 154.51,100.59 155.34,101.43 157.2,101.43 158.19,100.44 v2(158.19,100.24) ; v2(159.41,99.64) 159.73,99.32 161.68,99.32 RC33.1 162.83,100.42 163.33,99.91 JSPI1.17
PCH_SPI_D0_0_R: length 13.9
  TOP w0.112: RPC1.7 157.63,93.87 v2(157.63,93.86)
  BOTTOM w0.107: v2(157.63,93.86) 157.74,93.86 157.9,93.71 157.9,93.46 157.74,93.3 156.83,93.3 156.72,93.2 156.72,92.98 156.83,92.88 157.74,92.88 157.85,92.77 157.85,92.51 157.74,92.4 156.2,92.4 156.09,92.3 156.09,92.14 v2(156.11,92.12) 156.26,91.97 158.1,91.97 158.18,91.89 158.18,91.31 158.08,91.21
  BOTTOM w0.112: UC5.5 154.16,91.51 154.47,91.21 158.08,91.21
PCH_SPI_D0_1_R: length 13.4
  TOP w0.112: RC409.2 v2(157.63,99.45)
  BOTTOM w0.107: v2(157.63,99.45) 157.63,99.88 157.74,99.98 157.9,99.98 158.03,99.86 158.16,99.86 158.29,99.73 158.29,98.9 158.18,98.79 157.43,98.79 157.33,98.69 157.33,98.47 157.43,98.37 158.18,98.37 158.29,98.26 158.29,97.7 158.04,97.45 157.83,97.45 157.72,97.56 157.72,97.75 157.62,97.85 157.4,97.85 157.3,97.75 157.3,97.45 157.28,97.45 157.15,97.32 156.98,97.32 156.87,97.43 156.87,98.35 156.76,98.46 156.55,98.46 156.44,98.35 156.44,97.45 156.3,97.31 156.02,97.31 155.85,97.14 154.53,97.14 154.25,97.42 UC6.5
PCH_SPI_D0_2_R: length 6
  TOP w0.112: RZ59.2 160.17,102.96 158.83,104.3 v4(158.83,105.03) 158.85,105.05 158.85,106.56 v2(158.88,106.59)
  BOTTOM w0.112: UZ12.21 158.83,106.64 v2(158.88,106.59)
PCH_SPI_D0_R1: length 14.8
  TOP w0.112: RZ59.1 159.42,101.09 v2(159.41,101.1) v1(158.82,101.1) 158.09,101.1 157.8,100.82 157.8,99.89 158.14,99.55 158.14,98.42 RC409.1 157.82,97.72 157.82,96.4 157.63,96.21 RPC1.2
  BOTTOM w0.112: JSPI1.18 163.8,100.41 RC33.2 163.74,100.52 163.28,100.98 162.39,100.98 162.01,100.59 159.92,100.59 v2(159.41,101.1)
PCH_SPI_D1: length 53.8
  BOTTOM w0.076: 135.54,91.31 134.97,91.31 134.92,91.26 133.39,91.26 132.54,92.12 132.14,92.12 131.98,92.28 131.5,92.28 UC1.AW3
  BOTTOM w0.112: RC34.1 162.83,99.34 163.25,98.91 JSPI1.15 166.15,98.91 167.59,97.47 167.59,91.64 165.85,89.89 v1(163.16,89.89) 163.09,89.89 162.32,89.11 161.49,89.11 160.58,90.03 158.37,90.03 158.24,90.16 151.18,90.16 150.58,90.76 147.58,90.76 143.51,86.69 140.47,86.69 135.9,91.26 135.9,91.26 135.85,91.31 135.54,91.31
PCH_SPI_D1_0_R: length 12.7
  TOP w0.112: RPC1.8 158.13,94.17 158.31,93.99 159.28,93.99 v2(159.47,94.18)
  BOTTOM w0.112: UC5.2 160.3,94.05 159.9,94.45 159.9,94.58 158.53,95.95 157.56,95.95 157.34,95.73 157.34,95.18 157.49,95.03 157.65,95.03 158.1,95.47 158.26,95.47 158.41,95.32 158.41,95.16 157.97,94.71 157.97,94.55 158.13,94.39 158.28,94.39 158.74,94.85 158.9,94.85 159.06,94.7 159.06,94.54 158.6,94.08 158.6,93.92 158.87,93.65 159.03,93.65 159.47,94.09 v2(159.47,94.18)
PCH_SPI_D1_1_R: length 14.3
  TOP w0.112: RC410.2 158.69,98.79 159.79,98.79 159.91,98.9 159.91,99.9 160.02,100.01 160.24,100.01 160.35,99.9 160.35,98.9 160.47,98.79 160.69,98.79 160.8,98.9 160.8,99.9 160.91,100.01 161.14,100.01 161.25,99.9 v4(161.25,99.27) 161.25,98.9 161.36,98.79 162.27,98.79 162.43,98.94 162.43,100.43 162.32,100.54 159.55,100.54 v2(159.41,100.4)
  BOTTOM w0.107: v2(159.41,100.4) 159.85,99.96 UC6.2
PCH_SPI_D1_2_R: length 5.5
  TOP w0.112: RZ58.2 160.23,106.78 159.79,107.22 v4(158.95,107.22) 157.7,107.22 v2(157.13,106.65)
  BOTTOM w0.112: v2(157.13,106.65) 157.33,106.85 UZ12.24
PCH_SPI_D1_R1: length 25.3
  TOP w0.112: RPC1.1 158.13,97.4 RC410.1 159.3,98.57 162.55,98.57 162.66,98.68 162.66,102.2 v2(161.85,103.01) 161.52,103.34 v4(161.52,103.81) 161.52,104.13 160.92,104.72 RZ58.1
  BOTTOM w0.112: RC34.2 163.76,99.41 JSPI1.16 166.45,99.41 166.8,99.76 166.8,101.71 164.97,103.54 162.38,103.54 v2(161.85,103.01)
PCH_SPI_D2: length 41.2
  TOP w0.112: v2(159.47,92.29) 158.63,91.45 151.28,91.45 v2(150.7,92.03)
  BOTTOM w0.076: 135.54,91.56 134.91,91.56 134.86,91.51 133.38,91.51 132.88,92.01 132.88,92.4 132.54,92.74 131.89,92.74 UC1.AW2
  BOTTOM w0.112: JSPI1.9 164.81,95.91 164.62,95.72 164.62,95.41 164.13,94.93 164.13,94.33 163.71,93.91 RC38.1 163.65,93.91 163.07,93.33 v1(162.7,93.33) 162.62,93.33 161.44,92.15 159.61,92.15 v2(159.47,92.29) ; v2(150.7,92.03) 149.91,91.25 RC11.2 147.69,91.25 143.38,86.94 140.57,86.94 135.96,91.56 135.54,91.56
PCH_SPI_D2_0_R: length 13.2
  TOP w0.112: RC39.2 162.19,95.5 162.3,95.39 162.3,94.53 162.42,94.42 162.64,94.42 162.75,94.53 v4(162.75,94.78) 162.75,95.39 162.86,95.5 163.09,95.5 163.2,95.39 163.2,94.53 163.31,94.42 163.53,94.42 163.65,94.53 163.65,95.39 163.76,95.5 163.97,95.5 164.08,95.39 164.08,93.21 163.97,93.1 162.53,93.1 162.33,93.31 v2(162.33,93.67)
  BOTTOM w0.112: UC5.3 161.76,92.78 162.33,93.36 v2(162.33,93.67)
PCH_SPI_D2_1_R: length 14.2
  TOP w0.112: RC43.2 160.48,97.64 160.59,97.76 161.95,97.76 162.06,97.64 162.06,96.95 162.17,96.84 162.4,96.84 162.51,96.95 162.51,97.64 162.62,97.76 v4(162.65,97.76) 162.84,97.76 162.95,97.64 162.95,96.95 163.07,96.84 163.29,96.84 163.4,96.95 163.4,97.64 163.51,97.76 164.18,97.76 164.3,97.87 164.3,98.25 164.18,98.36 159.71,98.36 v2(159.47,98.12)
  BOTTOM w0.112: v2(159.47,98.12) 160.04,98.69 UC6.3
PCH_SPI_D2_R1: length 12.7
  TOP w0.112: RC43.1 161.39,96.43 RC39.1 RC30.1 160.25,96.18 160.25,96.07 159.89,95.72 159.89,93.97 v2(159.47,93.55)
  BOTTOM w0.112: JSPI1.10 164.77,96.41 164.29,95.92 164.29,95.45 RC38.2 162.72,94.83 v1(162.58,94.69) 162.15,94.25 162.15,94.06 161.5,93.42 159.6,93.42 v2(159.47,93.55)
PCH_SPI_D3: length 44.7
  BOTTOM w0.076: 135.54,92.73 134.59,93.69 132.73,93.69 132.66,93.63 130.91,93.63 130.65,93.89 UC1.AU4
  BOTTOM w0.112: JSPI1.7 164.87,94.91 164.69,94.73 164.69,94.02 164.41,93.74 164.41,92.71 163.78,92.07 RC40.1 163.42,92.07 163.13,92.37 162.43,92.37 162.18,92.11 v1(162.18,91.49) 162.18,91.3 161.64,90.77 159,90.77 158.82,90.94 152.2,90.94 151.85,91.29 151.85,91.75 150.94,92.66 148.66,92.66 143.81,87.82 140.28,87.82 137.35,90.75 137.35,91.82 136.73,92.44 135.84,92.44 135.54,92.73
PCH_SPI_D3_0_R: length 12.9
  TOP w0.112: v2(156.31,93.86) 156.63,94.18 RPC1.5
  BOTTOM w0.112: v2(156.31,93.86) 156.1,93.66 155.01,93.66 154.9,93.77 154.9,95.18 155.01,95.29 155.23,95.29 155.34,95.18 155.34,94.87 155.45,94.76 155.67,94.76 155.79,94.87 155.79,95.18 155.9,95.29 156.3,95.29 156.41,95.18 156.41,95.07 156.52,94.96 156.81,94.96 156.92,95.07 156.92,95.45 156.63,95.74 155.01,95.74 154.9,95.85 154.9,95.91 154.79,96.02 154.57,96.02 154.46,95.91 154.46,94.17 154.34,94.05 UC5.7
PCH_SPI_D3_1_R: length 14.1
  TOP w0.112: RC407.2 155.85,99.63 v1(155.69,99.79) 155.65,99.83 155.65,102.49 155.76,102.6 156.01,102.6 156.12,102.49 156.12,99.94 v2(156.61,99.45)
  BOTTOM w0.107: v2(156.61,99.45) 157.09,99.45 157.34,99.7 157.34,100.92 157.11,101.15 155.43,101.15 154.24,99.96 UC6.7
PCH_SPI_D3_R1: length 22.8
  TOP w0.112: v2(159.47,92.91) 159.65,92.73 RC316.1 RC31.1 161.07,93.6 v1(161.59,93.08) ; RC407.1 155.85,97.23 v2(156.42,96.66) 156.63,96.46 RPC1.4
  BOTTOM w0.107: v2(159.47,92.91) 159.31,92.91 157.64,94.58 157.49,94.58 157.39,94.48 157.24,94.48 157.09,94.64 157.09,94.79 157.13,94.83 157.13,95.53 156.34,96.33 156.34,96.57 v2(156.42,96.66)
  BOTTOM w0.112: v2(159.47,92.91) 158.85,92.29 158.85,91.5 159.36,90.99 161.49,90.99 161.76,91.26 161.76,92.09 162.46,92.78 163.46,92.78 RC40.2 164.16,93.48 164.16,93.86 164.44,94.14 164.44,94.88 164.97,95.41 JSPI1.8
PCH_SPI_DO2_XDP: length 109
  IN2 w0.124: v2(141.48,125.83) 139.58,123.93 139.58,122.95 140.54,121.99 140.54,118.8 138.96,117.22 138.96,112.5 139.29,112.17 139.29,111.48 142.75,108.02 142.75,101.74 141.88,100.87 141.88,100.39 142.14,100.14 143.53,100.14 143.91,100.52 145.67,100.52 147.24,98.94 147.75,98.94 148.06,99.25 149.38,99.25 150.72,97.9 150.72,92.69 v2(150.08,92.04)
  BOTTOM w0.112: v2(150.08,92.04) 149.96,92.16 RC11.1 ; v2(141.48,125.83) v1(141.03,126.28) 134.38,126.28 130.05,130.62 128.88,130.62 126.54,132.95 126.54,134.68 125.8,135.42 87.29,135.42 85.81,133.94 JXDP1.60
PCH_SPI_DO_XDP: length 94.4
  TOP w0.112: v2(141.2,107.2) 144.97,107.2 146.81,105.36 148.64,105.36 151.01,102.98 151.01,102.54 v4(151.56,101.99) 152.02,101.53 152.02,100.87 151.5,100.35 RC10.1 RC133.1
  IN2 w0.124: v2(88.56,125.65) 90.58,127.67 104.16,127.67 104.47,127.97 109.57,127.97 109.72,127.82 118.96,127.82 119.21,128.08 123.28,128.08 123.83,127.53 125.5,127.53 125.88,127.91 130.74,127.91 131.3,127.35 138.57,127.35 139.03,126.9 139.03,125.55 138.11,124.64 138.11,122.46 139.18,121.39 139.18,119.36 136.96,117.14 136.96,112.59 137.93,111.61 137.93,110.46 v2(141.2,107.2)
  BOTTOM w0.112: RC128.1 88.48,125.73 v2(88.56,125.65)
PCI_CLK_LPC1: length 14.9
  TOP w0.112: RC22.1 137.5,85.55 v2(137.36,85.69)
  BOTTOM w0.076: 130.22,88.68 128.98,89.93 128.5,89.93 128.04,90.38 127.4,90.38 127.25,90.53 127.25,90.79 127.3,90.91 127.3,91.05 127.24,91.28 127.24,91.4 127.31,91.61 UC1.AY9
  BOTTOM w0.102: 130.22,88.68 130.63,88.68
  BOTTOM w0.112: 130.63,88.68 131.82,87.49 134.2,87.49 135.13,86.56 v1(135.79,86.56) 136.49,86.56 v2(137.36,85.69)
PCIE_PRX_C_DTX_N1: length 2.7
  TOP w0.104: CR14.2 271.31,63.06 271.69,63.06 272.2,63.56 272.72,63.56 272.81,63.47 UR1.8
PCIE_PRX_C_DTX_N9: length 2.4
  TOP w0.104: CL2.2 241.62,127.8 242.03,127.8 242.38,127.45 242.6,127.45 242.72,127.33 UL1.39
PCIE_PRX_C_DTX_P1: length 2.7
  TOP w0.104: UR1.7 272.82,63.87 272.72,63.76 272.07,63.76 v3(271.91,63.6) 271.56,63.26 271.32,63.26 CR13.2
PCIE_PRX_C_DTX_P9: length 2.4
  TOP w0.104: UL1.38 242.74,127.73 242.66,127.65 242.47,127.65 242.11,128 241.62,128 CL1.2
PCIE_PRX_DTX_N1: length 218.9
  TOP w0.104: CR14.1 269.67,63.07 269.24,63.07 v2(269.05,62.88)
  IN1 w0.076: 125.35,110.75 125.35,110.74 125.33,110.71 125.33,110.4 125.26,110.34 125.26,109.3 125.07,109.11 124.97,109.11 v2(124.72,108.87)
  IN1 w0.119: 125.35,110.75 125.35,111.37 126.22,112.24 132.09,112.24 133.24,113.38 137.14,113.38 137.92,112.61 137.92,111.77 140.29,109.39 146.04,109.39 147.63,110.98 150.93,110.98 152.74,109.17 152.74,106.14 154.8,104.08 154.8,89.69 152.27,87.16 152.27,84.09 150.83,82.65 150.83,72.01 151.9,70.94 163.06,70.94 163.68,71.56 171.79,71.56 174.62,68.73 175.97,68.73 180.68,64.02 180.68,63.37 181.63,62.42 215.02,62.42 215.51,61.92 217.35,61.92 217.5,62.08 226.28,62.08 227.04,61.31 230.07,61.31 234.06,65.3 234.06,66.8 235.56,68.3 244.41,68.3 246.52,70.4 249.8,70.4 251.49,72.08 255.69,72.08 256.66,73.06 259.18,73.06 259.6,73.48 262.48,73.48 263.33,74.33 268.11,74.33 269.83,72.61 269.83,70.19 267.65,68 267.65,63.83 268.35,63.12 268.8,63.12 v2(269.05,62.88)
  BOTTOM w0.089: UC1.H13 v2(124.72,108.87)
PCIE_PRX_DTX_N3: length 153.1
  IN1 w0.076: 123.57,110.75 123.57,110.74 123.54,110.71 123.54,110.51 123.43,110.4 123.43,109.35 123.25,109.16 123.14,109.16 v2(122.9,108.92)
  IN1 w0.119: v2(232.21,70) 232.21,70.15 232.04,70.32 231.88,70.32 231.67,70.11 231.67,68.58 229.54,66.44 228.07,66.44 226.9,65.28 222.03,65.28 221.62,65.69 195.94,65.69 arc(184.63,67.93) 175.04,74.34 174.31,75.07 arc(166.75,86.4) 164.09,99.75 164.09,102.44 161.41,105.12 161.41,106.73 157.73,110.41 156,110.41 153.31,113.1 153.31,113.65 152.93,114.03 149.16,114.03 148.72,114.48 146.32,114.48 143.55,117.25 140.45,117.25 138.72,115.52 130.75,115.52 129.45,114.22 125.49,114.22 124.3,115.4 123.32,115.4 122.9,114.99 122.9,113.22 123.57,112.55 123.57,110.75
  BOTTOM w0.089: UC1.H16 v2(122.9,108.92)
  BOTTOM w0.104: v2(232.21,70) 232.27,70.06 232.27,70.13 232.43,70.29 232.59,70.29 232.73,70.15 JNGFF1.43
PCIE_PRX_DTX_N4: length 144.7
  IN1 w0.076: v2(123.81,109.52) 124.05,109.76 124.16,109.76 124.35,109.95 124.35,110.48 124.18,110.66 124.18,110.71 124.2,110.74 124.2,110.75
  IN1 w0.119: 124.2,110.75 124.2,112.04 125.05,112.9 131.51,112.9 132.84,114.23 137.29,114.23 138.58,112.94 138.58,112.07 140.56,110.09 145.34,110.09 147.51,112.26 152.31,112.26 156.83,107.75 157.47,107.75 158.23,106.99 158.23,105.53 162.74,101.02 162.74,99.75 arc(165.49,85.88) 173.35,74.11 174.08,73.38 arc(174.43,73.04) 174.79,72.7 arc(184.5,66.55) 195.78,64.4 220.82,64.4 221.23,63.99 227.58,63.99 228.11,64.52 228.62,64.52 228.75,64.39 228.78,64.39 v2(229.04,64.13)
  BOTTOM w0.089: UC1.G15 v2(123.81,109.52)
  BOTTOM w0.104: JNGFF1.67 232.48,64.15 232.28,64.35 v3(230.27,64.35) 229.26,64.35 v2(229.04,64.13)
PCIE_PRX_DTX_N9: length 215.9
  TOP w0.104: v2(239.41,127.26) 239.41,127.32 239.76,127.67 240.15,127.67 CL2.1
  IN1 w0.119: v2(239.41,127.26) 239.4,127.64 239.52,127.76 240.33,127.76 240.39,127.7 240.71,127.38 240.71,125.1 234.87,119.26 234.87,113.49 234.4,113.03 234.4,102.81 236.76,100.45 236.76,97.01 236.11,96.36 236.11,94.91 234.27,93.07 234.27,79.76 230.19,75.69 230.19,71.3 229.67,70.78 229.67,69.38 226.43,66.14 222.59,66.14 222.18,66.55 195.99,66.55 arc(184.99,68.73) 175.66,74.96 174.93,75.69 arc(167.56,86.73) 164.97,99.75 164.97,103.47 162.28,106.16 162.28,107.64 157.79,112.13 156.8,112.13 153.58,115.36 146.7,115.36 143.94,118.11 140.08,118.11 138.34,116.38 130.21,116.38 129.23,115.4 127.3,115.4 126.72,115.99 125.2,115.99 124.91,116.27 122.73,116.27 122.03,115.57 122.03,113.98 120.1,112.05 120.1,111.7 119.56,111.16 119.56,110.69 119.44,110.57 119.24,110.57 119.12,110.69 119.12,110.89 v2(119.16,110.93)
  BOTTOM w0.076: UC1.E22 119.5,110.59 v2(119.16,110.93)
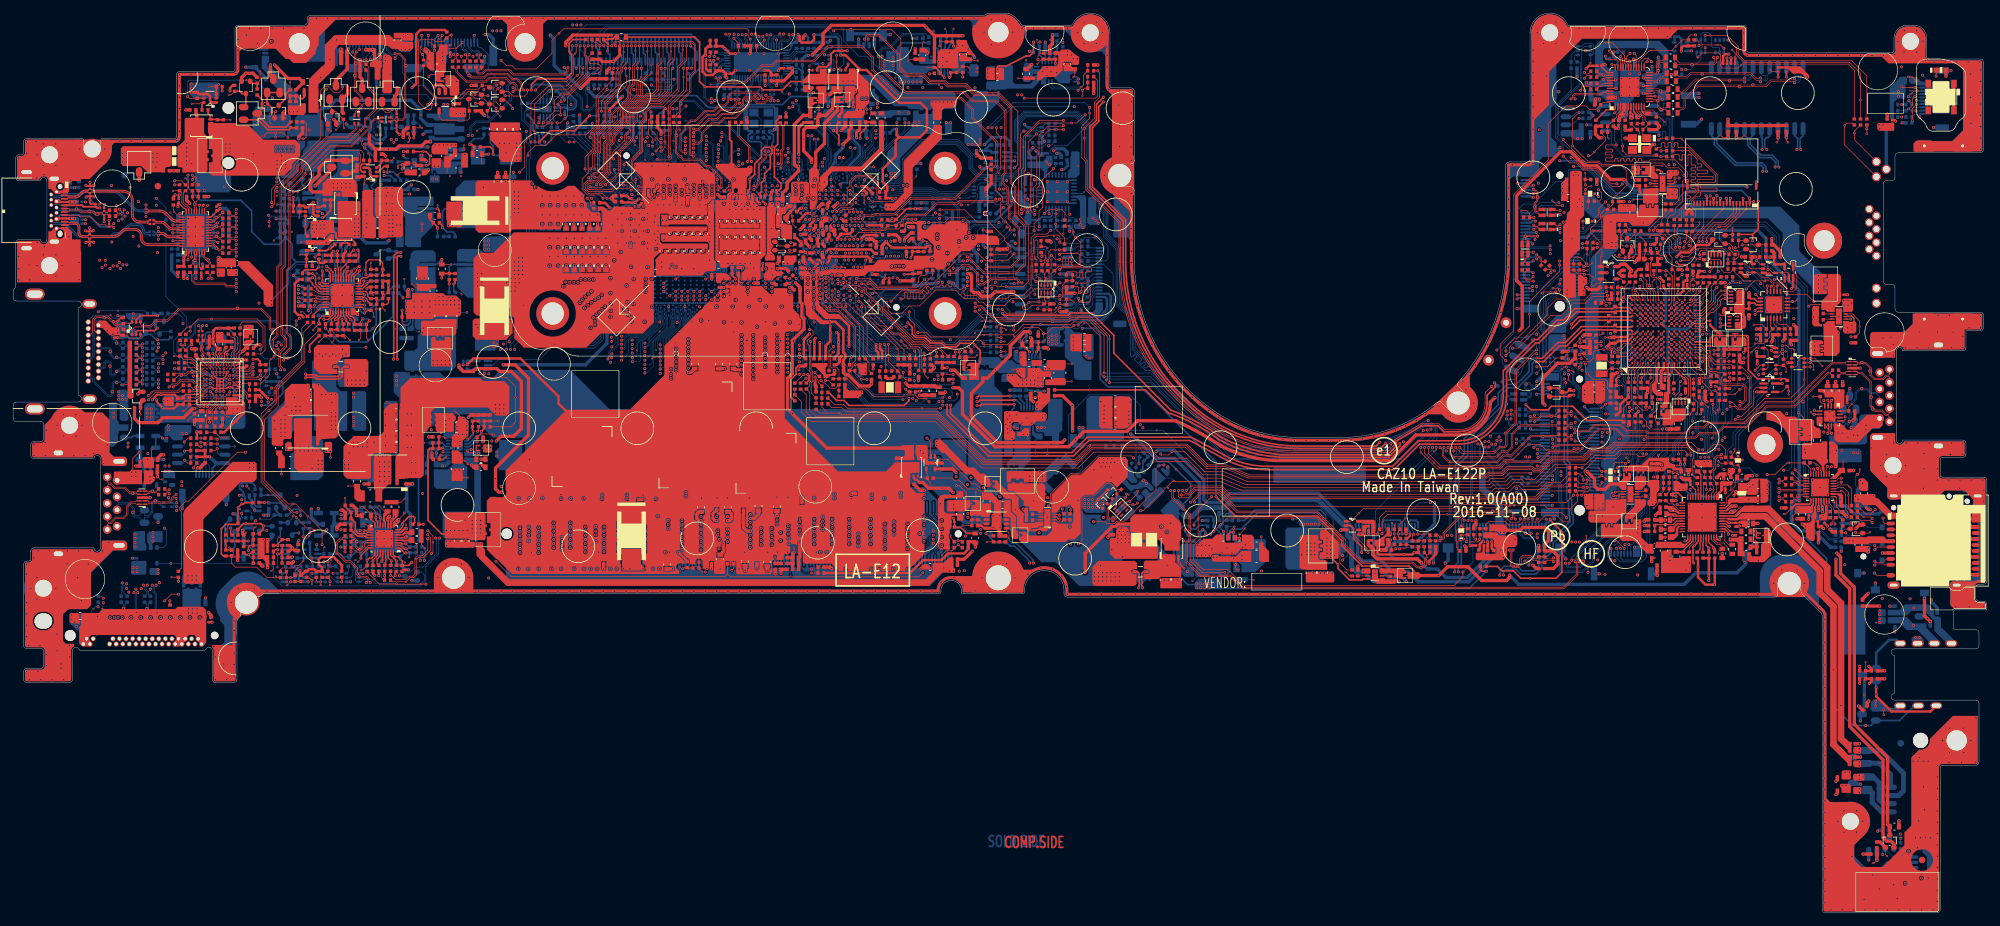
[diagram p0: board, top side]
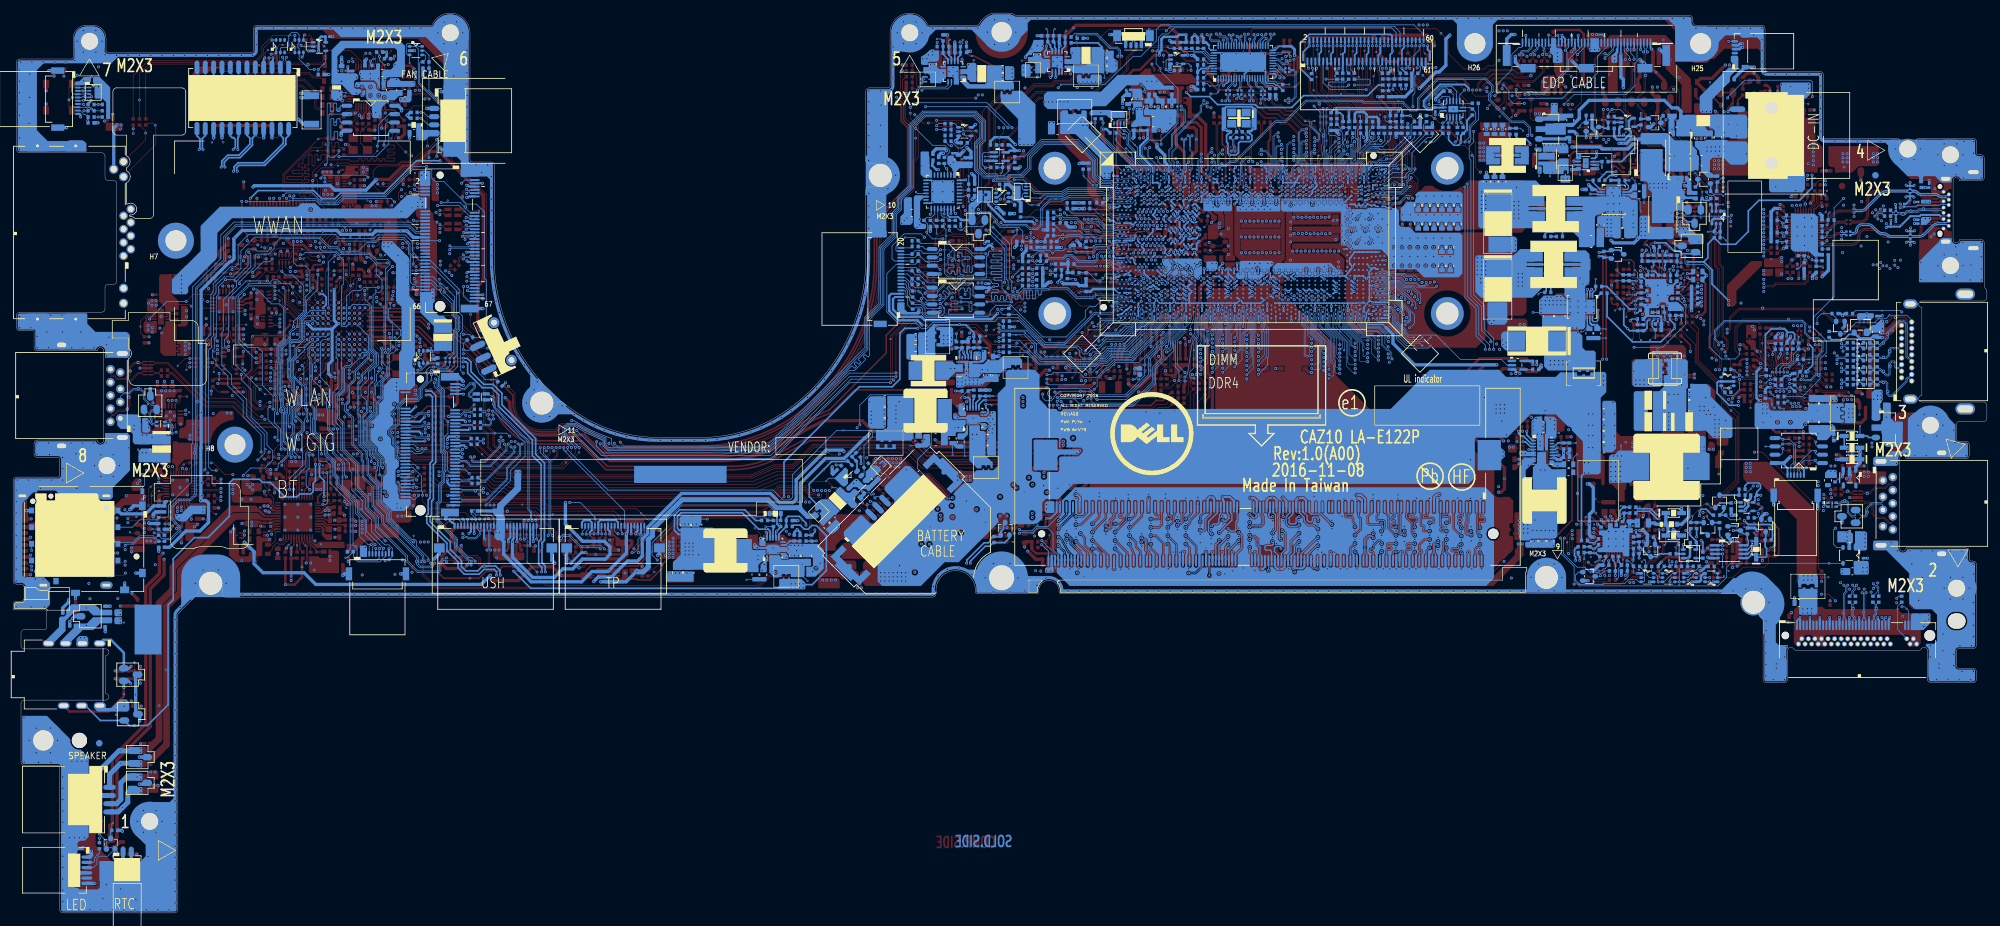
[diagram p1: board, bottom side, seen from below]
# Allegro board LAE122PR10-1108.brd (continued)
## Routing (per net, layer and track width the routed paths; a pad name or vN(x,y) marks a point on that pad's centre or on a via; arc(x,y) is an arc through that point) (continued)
PCIE_PRX_DTX_N11: length 164.4
  IN3 w0.135: v2(115.63,110.89) 115.73,110.79 115.92,110.79 116.07,110.94 116.07,111.05 116.22,111.2 116.22,111.39 115.57,112.04 115.57,114.14 112.29,117.42 111.13,117.42 107.91,120.65 105.61,120.65 102.69,123.57 86.92,123.57 85.82,122.48 83.08,122.48 81.76,121.16 72.51,121.16 72.16,120.8 50.27,120.8 44.07,114.6 44.07,109.31 42.56,107.8 42.56,103.42 41.03,101.89 41.03,92.24 36.79,88 36.79,85.43 35.86,84.51 35.86,73.52 28.03,65.69 28.03,59.87 21.66,53.5 21.66,51.33 21.45,51.12 21.45,50.32 21.63,50.14 21.63,50.06 21.73,49.96 v2(21.79,49.96)
  BOTTOM w0.102: v2(115.63,110.89) 115.86,110.89 116.04,110.72 UC1.E28
  BOTTOM w0.104: v2(21.79,49.96) 21.52,49.69 21.52,49.04 21.84,48.72 21.84,44.88 21.95,44.77 JNGFF3.29
PCIE_PRX_DTX_N12: length 166
  IN3 w0.135: v2(114.64,110.84) 114.76,110.73 114.86,110.73 114.99,110.86 114.99,113.76 112.01,116.74 110.83,116.74 107.61,119.96 100.56,119.96 97.74,122.78 88.39,122.78 85.26,119.66 79.5,119.66 79.11,120.05 52.51,120.05 52.09,119.63 50.06,119.63 44.78,114.34 44.78,109.03 43.25,107.51 43.25,103.03 41.86,101.64 41.86,91.99 38.62,88.75 38.62,83.75 37.25,82.38 37.25,81.44 36.55,80.75 36.55,73.22 28.74,65.41 28.74,59.56 23.01,53.84 23.01,49.52 22.09,48.59 19.34,48.59 19.16,48.41 18.81,48.41 18.57,48.65 18.57,48.66 v2(18.4,48.83)
  BOTTOM w0.102: UC1.E30 115.09,110.56 114.84,110.56 114.64,110.76 v2(114.64,110.84)
  BOTTOM w0.104: JNGFF3.43 18.45,44.8 18.59,44.94 18.59,48.64 v2(18.4,48.83)
PCIE_PRX_DTX_P1: length 219
  TOP w0.104: CR13.1 269.66,63.27 269.24,63.27 v2(269.05,63.46)
  IN1 w0.076: v2(124.72,109.53) 124.72,109.45 124.89,109.29 125,109.29 125.09,109.37 125.09,110.41 125.15,110.48 125.15,110.71 125.13,110.74 125.13,110.75
  IN1 w0.119: 125.13,110.75 125.13,111.46 126.13,112.46 132,112.46 133.15,113.6 137.23,113.6 138.14,112.7 138.14,111.86 140.38,109.61 145.95,109.61 147.53,111.2 151.02,111.2 152.96,109.26 152.96,106.23 155.02,104.17 155.02,89.6 152.49,87.07 152.49,83.99 151.05,82.56 151.05,72.1 151.99,71.16 162.96,71.16 163.59,71.78 171.88,71.78 174.58,69.09 175.92,69.09 180.9,64.11 180.9,63.46 181.72,62.63 215.11,62.63 215.6,62.14 217.26,62.14 217.41,62.29 226.37,62.29 227.13,61.53 229.98,61.53 233.84,65.39 233.84,66.89 235.47,68.51 244.32,68.51 246.43,70.62 249.71,70.62 251.39,72.3 255.6,72.3 256.57,73.28 259.09,73.28 259.51,73.7 262.39,73.7 263.24,74.55 268.2,74.55 270.05,72.7 270.05,70.1 267.87,67.91 267.87,63.92 268.44,63.34 268.93,63.34 v2(269.05,63.46)
  BOTTOM w0.089: UC1.G13 v2(124.72,109.53)
PCIE_PRX_DTX_P3: length 153
  IN1 w0.076: 123.35,110.75 123.35,110.74 123.37,110.71 123.37,110.58 123.26,110.47 123.26,109.42 123.17,109.34 123.06,109.34 122.9,109.5 v2(122.9,109.58)
  IN1 w0.119: 123.35,110.75 123.35,112.46 122.68,113.13 122.68,115.08 123.23,115.62 124.39,115.62 125.58,114.44 129.36,114.44 130.66,115.74 138.63,115.74 140.36,117.47 143.64,117.47 146.41,114.7 148.81,114.7 149.25,114.25 153.02,114.25 153.53,113.74 153.53,113.22 156.12,110.63 157.82,110.63 161.63,106.82 161.63,105.21 164.31,102.53 164.31,99.75 arc(166.95,86.48) 174.47,75.23 175.19,74.5 arc(184.72,68.14) 195.95,65.9 221.71,65.9 222.12,65.49 226.81,65.49 227.98,66.66 229.45,66.66 231.46,68.67 231.46,70.2 231.8,70.55 232.1,70.55 v2(232.24,70.68)
  BOTTOM w0.089: UC1.G16 v2(122.9,109.58)
  BOTTOM w0.104: v2(232.24,70.68) 232.24,70.68 232.43,70.49 232.56,70.49 232.72,70.65 JNGFF1.41
PCIE_PRX_DTX_P4: length 144.6
  IN1 w0.076: 123.98,110.75 123.98,110.74 124,110.71 124,110.58 124.17,110.41 124.17,110.02 124.09,109.94 123.97,109.94 123.81,110.1 v2(123.81,110.18)
  IN1 w0.119: v2(229.04,64.71) 229.01,64.74 228.02,64.74 227.49,64.21 221.32,64.21 220.91,64.62 195.78,64.62 arc(184.58,66.75) 174.94,72.86 arc(174.58,73.19) 174.24,73.54 173.51,74.27 arc(165.7,85.96) 162.95,99.75 162.95,99.75 162.95,101.11 158.44,105.62 158.44,107.08 157.56,107.96 156.92,107.96 152.4,112.48 147.42,112.48 145.25,110.31 140.65,110.31 138.8,112.16 138.8,113.03 137.38,114.45 132.75,114.45 131.42,113.12 124.96,113.12 123.98,112.13 123.98,110.75
  BOTTOM w0.089: UC1.F15 v2(123.81,110.18)
  BOTTOM w0.104: JNGFF1.65 232.48,64.65 232.38,64.55 230.59,64.55 230.56,64.58 229.96,64.58 229.93,64.55 229.2,64.55 v2(229.04,64.71)
PCIE_PRX_DTX_P9: length 215.9
  TOP w0.104: v2(239.4,128.17) 239.64,127.93 239.98,127.93 240.36,128.31 CL1.1
  IN1 w0.119: v2(119.24,110.18) 119.36,110.18 119.77,110.6 119.77,111.07 120.32,111.61 120.32,111.96 122.25,113.89 122.25,115.48 122.82,116.05 124.82,116.05 125.1,115.77 126.63,115.77 127.21,115.18 129.32,115.18 130.3,116.16 138.43,116.16 140.17,117.89 143.85,117.89 146.61,115.14 153.49,115.14 156.71,111.91 157.7,111.91 162.06,107.55 162.06,106.07 164.75,103.38 164.75,99.75 arc(167.36,86.65) 174.78,75.54 175.51,74.81 arc(184.9,68.53) 195.99,66.33 222.09,66.33 222.5,65.92 226.53,65.92 229.89,69.29 229.89,70.69 230.41,71.21 230.41,75.59 234.49,79.67 234.49,92.98 236.33,94.82 236.33,96.27 236.98,96.92 236.98,100.54 234.62,102.9 234.62,112.93 235.09,113.4 235.09,119.17 240.93,125.01 240.93,127.29 240.93,127.47 240.42,127.98 239.59,127.98 v2(239.4,128.17)
  BOTTOM w0.076: UC1.E23 118.83,110.59 v2(119.24,110.18)
PCIE_PRX_DTX_P11: length 164.4
  IN3 w0.135: v2(21.21,49.96) 21.21,51.22 21.42,51.43 21.42,53.6 27.79,59.97 27.79,65.79 35.62,73.62 35.62,84.61 36.55,85.53 36.55,88.1 40.79,92.34 40.79,101.99 42.31,103.52 42.31,107.9 43.83,109.41 43.83,114.7 50.17,121.04 72.06,121.04 72.41,121.4 81.66,121.4 82.98,122.72 85.72,122.72 86.82,123.81 102.79,123.81 105.71,120.89 108.01,120.89 111.23,117.66 112.39,117.66 115.81,114.24 115.81,112.14 116.46,111.49 v2(116.46,110.88)
  BOTTOM w0.102: UC1.E27 116.67,110.88 v2(116.46,110.88)
  BOTTOM w0.104: JNGFF3.31 21.45,44.68 21.64,44.87 21.64,48.63 21.32,48.96 21.32,49.85 v2(21.21,49.96)
PCIE_PRX_DTX_P12: length 165.9
  IN3 w0.135: v2(18.98,48.83) 21.98,48.83 22.77,49.62 22.77,53.94 28.5,59.66 28.5,65.51 36.31,73.32 36.31,80.85 37.01,81.54 37.01,82.48 38.38,83.85 38.38,88.85 41.62,92.09 41.62,101.74 43.01,103.13 43.01,107.61 44.54,109.13 44.54,114.44 49.96,119.87 51.99,119.87 52.41,120.29 79.21,120.29 79.6,119.9 85.16,119.9 88.29,123.02 97.84,123.02 100.66,120.2 107.71,120.2 110.93,116.98 112.11,116.98 115.23,113.86 115.23,110.76 114.68,110.2 v2(114.67,110.2)
  BOTTOM w0.102: UC1.F30 114.93,109.94 v2(114.67,110.2)
  BOTTOM w0.104: JNGFF3.41 18.95,44.79 18.79,44.95 18.79,48.64 v2(18.98,48.83)
PCIE_PTX_C_DRX_N1: length 2.7
  TOP w0.104: CR12.2 271.35,65.67 271.53,65.67 272.03,65.17 272.71,65.17 272.81,65.07 UR1.4
PCIE_PTX_C_DRX_N3: length 2.7
  BOTTOM w0.104: JNGFF1.37 232.7,71.65 232.54,71.82 231.29,71.82 CZ13.2
PCIE_PTX_C_DRX_N4: length 2.8
  BOTTOM w0.104: CZ15.2 231.13,65.81 232.46,65.81 232.62,65.65 JNGFF1.61
PCIE_PTX_C_DRX_N9: length 2.3
  TOP w0.104: CL6.2 241.63,125.97 241.96,125.97 242.22,126.23 242.55,126.23 242.65,126.13 UL1.42
PCIE_PTX_C_DRX_N11: length 3.9
  BOTTOM w0.104: JNGFF3.35 20.45,44.61 20.29,44.77 20.29,45.01 20.57,45.29 20.57,46.1 20.6,46.13 20.6,46.7 20.57,46.73 20.57,47.04 CN69.1
PCIE_PTX_C_DRX_N12: length 3.9
  BOTTOM w0.104: CN71.1 17.02,47.04 17.02,46.75 17.04,46.72 17.04,46.13 17.02,46.1 17.02,45.57 17.3,45.28 17.3,44.76 17.45,44.61 JNGFF3.47
PCIE_PTX_C_DRX_P1: length 2.7
  TOP w0.104: UR1.3 272.82,65.47 272.72,65.37 272.15,65.37 v3(271.95,65.57) 271.65,65.87 271.35,65.87 CR11.2
PCIE_PTX_C_DRX_P3: length 2.6
  BOTTOM w0.104: JNGFF1.35 232.69,72.15 232.56,72.02 231.24,72.02 CZ12.2
PCIE_PTX_C_DRX_P4: length 2.8
  BOTTOM w0.104: CZ14.2 231.15,66.01 232.43,66.01 232.57,66.15 JNGFF1.59
PCIE_PTX_C_DRX_P9: length 2.3
  TOP w0.104: UL1.41 242.65,126.53 242.55,126.43 242.14,126.43 241.88,126.17 241.61,126.17 CL5.2
PCIE_PTX_C_DRX_P11: length 3.8
  BOTTOM w0.104: CN70.1 20.37,47.04 v3(20.37,46.42) 20.37,45.38 20.09,45.1 20.09,44.74 19.95,44.6 JNGFF3.37
PCIE_PTX_C_DRX_P12: length 3.9
  BOTTOM w0.104: JNGFF3.49 16.95,44.6 17.1,44.75 17.1,45.2 16.81,45.48 v3(16.81,46.42) 16.81,47.04 CN72.1
PCIE_PTX_DRX_N1: length 195.7
  TOP w0.104: CR12.1 269.59,65.75 269.22,65.75 v2(269.03,65.56)
  IN1 w0.119: v2(123.33,113.88) 123.47,114.02 124.33,114.02 124.87,113.47 129.76,113.47 131.16,114.87 139,114.87 140.73,116.61 143.27,116.61 146.93,112.94 152.56,112.94 156.4,109.1 157.49,109.1 159.66,106.93 159.66,105.85 163.42,102.09 163.42,99.75 arc(166.13,86.14) 173.84,74.6 174.57,73.87 arc(184.34,67.34) 195.88,65.04 221.25,65.04 221.65,64.63 227.31,64.63 228.4,65.72 231.28,65.72 235.04,69.48 244.09,69.48 246.08,71.47 249.03,71.47 250.71,73.15 252.15,73.15 253.33,74.33 257.9,74.33 258.11,74.55 261.06,74.55 262.62,76.11 264.11,76.11 265.25,74.97 268.38,74.97 270.47,72.88 270.47,69.72 268.29,67.54 268.29,66.02 268.54,65.78 268.81,65.78 v2(269.03,65.56)
  BOTTOM w0.076: v2(123.33,113.88) 123.21,113.88 123.04,113.7 123.04,113.62 123.09,113.57 123.09,112.94 UC1.B17
PCIE_PTX_DRX_N3: length 152.7
  IN3 w0.135: v2(122.04,117.99) 122.04,118.05 122.61,118.62 123.17,118.62 125.63,116.17 129.27,116.17 129.78,116.67 139,116.67 139.91,117.59 143.82,117.59 145.65,115.76 148.59,115.76 149.02,116.19 154.1,116.19 156.95,113.35 156.95,111.53 164.68,103.79 164.68,99.34 arc(167.26,86.49) 174.55,75.61 175.54,74.61 arc(184.66,68.52) 195.41,66.38 203.66,66.38 204.38,65.67 220.92,65.67 223.29,68.04 225.31,68.04 227.88,70.62 229.14,70.62 229.86,71.33 229.86,71.79 229.64,72.01 229.5,72.01 229.35,71.85 229.19,71.85 229.02,71.68 v2(229.02,71.63)
  BOTTOM w0.076: 122.22,116.98 122.22,116.96 122.24,116.94 122.24,113.43 122.41,113.09 122.41,112.9 122.38,112.8 122.38,112.8 122.38,112.55 122.53,112.03 122.53,111.91 122.56,111.81 122.59,111.69 UC1.D17
  BOTTOM w0.104: v2(122.04,117.99) 122.22,117.81 122.22,116.98 ; CZ13.1 229.62,71.83 229.23,71.83 v2(229.02,71.63)
PCIE_PTX_DRX_N4: length 155.3
  IN3 w0.135: v2(121.1,118.5) 121.26,118.66 121.26,119.15 123.18,121.07 132.05,121.07 133.95,122.96 137.57,122.96 138.17,122.36 149.07,122.36 153.46,117.98 155,117.98 159.27,113.71 159.27,112.23 166.04,105.45 166.04,100.53 arc(166.04,100.36) 166.05,100.19 166.05,99.02 arc(166.05,98.8) 166.05,98.58 arc(168.67,86.67) 175.51,76.57 176.39,75.69 arc(180.5,72.31) 185.19,69.81 arc(190.28,68.26) 195.57,67.74 204.41,67.74 205.09,67.06 220.27,67.06 222.73,69.52 223.86,69.52 224.4,70.05 224.4,70.9 224.26,71.04 v2(224.26,71.06)
  BOTTOM w0.076: UC1.B19 121.15,113.26 121.09,113.32 121.03,113.41 121.03,113.6 121.09,113.65 121.09,113.99 120.97,114.11 120.97,116.01 121.31,116.35 121.31,116.94 121.3,116.96 121.3,116.98
  BOTTOM w0.104: CZ15.1 229.69,65.67 228.8,65.67 224.26,70.21 v2(224.26,71.06) ; 121.3,116.98 121.3,118.3 v2(121.1,118.5)
PCIE_PTX_DRX_N9: length 213.5
  TOP w0.104: v2(239.43,125.42) 239.35,125.42 239.16,125.6 239.16,125.88 239.32,126.03 240.21,126.03 240.36,125.88 CL6.1
  IN1 w0.119: v2(239.43,125.42) 239.43,124.48 238.17,123.22 235.7,123.22 234.45,121.98 234.45,113.9 233.73,113.18 233.73,99.54 233.34,99.15 233.34,94.65 231.69,92.99 231.69,81.97 227.99,78.28 227.99,77.71 227.06,76.78 227.06,73.91 227.96,73.01 227.96,70.09 226.13,68.26 196.12,68.26 arc(185.72,70.32) 176.91,76.21 176.18,76.94 arc(169.19,87.41) 166.73,99.75 166.73,105.94 162.34,110.33 162.34,112.58 159.95,114.97 158.68,114.97 155.37,118.29 152.27,118.29 151.6,118.96 145.81,118.96 144.94,119.83 139.31,119.83 137.64,118.16 132.3,118.16 131.87,118.59 124.64,118.59 124.19,119.05 120.57,119.05 118.9,117.37 118.9,116.22 118.66,115.99 v2(118.06,115.99)
  BOTTOM w0.076: v2(118.06,115.99) 118.19,115.99 118.55,115.63 118.55,113.34 118.98,112.91 UC1.B23
PCIE_PTX_DRX_N11: length 165.9
  IN3 w0.135: v2(20.45,49.97) 20.35,49.97 20.28,50.05 20.28,50.14 20.1,50.32 20.1,50.74 20.9,51.53 20.9,53.84 27.34,60.29 27.34,65.99 35.18,73.82 35.18,84.87 36.09,85.79 36.09,88.66 38.3,90.87 38.3,93.51 40.21,95.41 40.21,102.27 41.68,103.75 41.68,110.86 43.38,112.56 43.38,114.87 47.38,118.87 47.38,120.09 48.77,121.48 60.8,121.48 61.72,122.4 72.21,122.4 72.72,121.89 80.03,121.89 82.78,124.64 91.31,124.64 91.61,124.94 93.75,124.94 94.39,124.31 103.28,124.31 106.2,121.38 108.14,121.38 111.38,118.15 114.55,118.15 115.77,116.93 115.77,115.29 116.25,114.82 117.7,114.82 118.05,114.47 v2(118.06,114.47)
  BOTTOM w0.076: v2(118.06,114.47) 118.06,114.51 117.92,114.65 117.81,114.65 117.68,114.51 117.68,114.25 118.3,113.63 118.3,112.92 118.69,112.52 118.69,112.21 118.42,111.93 UC1.D24
  BOTTOM w0.104: v2(20.45,49.97) 20.27,49.8 20.27,49.79 20.25,49.78 20.25,49.36 20.57,49.05 20.57,48.64 CN69.2
PCIE_PTX_DRX_N12: length 179.5
  IN3 w0.135: v2(116.44,116.34) 116.48,116.34 116.61,116.47 116.8,116.47 116.86,116.41 116.86,116.09 117,115.95 117.17,115.95 117.4,116.17 117.4,117.07 115.6,118.87 111.65,118.87 108.46,122.07 106.89,122.07 103.53,125.42 95.76,125.42 94.79,126.39 83.39,126.39 80.16,123.16 72.63,123.16 71.66,124.13 40.57,124.13 38.37,121.93 38.37,110.6 40.97,108 40.97,104.24 39.46,102.73 39.46,95.75 33.96,90.25 33.96,87.55 32.33,85.93 30.12,85.93 27.04,82.84 27.04,67.08 26.62,66.66 26.62,60.58 20.22,54.18 20.22,51.81 18.35,49.95 17.65,49.95 17.46,49.77 17.4,49.77 17.3,49.67 v2(17.3,49.48)
  BOTTOM w0.076: v2(116.44,116.34) 116.44,116.26 116.7,116 116.81,116 117.19,115.63 117.19,114.14 117.58,113.75 117.58,113.24 117.64,113.17 117.78,113.17 117.85,113.25 UC1.A25
  BOTTOM w0.104: v2(17.3,49.48) 17.3,49.59 17.19,49.69 16.78,49.69 16.67,49.59 16.67,48.98 CN71.2
PCIE_PTX_DRX_P1: length 195.7
  TOP w0.104: v2(269.03,66.14) 269.22,65.95 269.75,65.95 CR11.1
  IN1 w0.119: v2(123.33,114.46) 123.55,114.24 124.42,114.24 124.96,113.69 129.67,113.69 131.07,115.09 138.91,115.09 140.64,116.83 143.36,116.83 147.03,113.16 152.65,113.16 156.49,109.32 157.58,109.32 159.88,107.02 159.88,105.94 163.64,102.18 163.64,99.75 arc(166.33,86.22) 173.99,74.75 174.72,74.02 arc(184.43,67.54) 195.88,65.26 221.34,65.26 221.75,64.85 227.22,64.85 228.3,65.94 231.19,65.94 234.95,69.7 244,69.7 245.99,71.69 248.94,71.69 250.62,73.37 252.06,73.37 253.24,74.55 257.81,74.55 258.02,74.77 260.97,74.77 262.53,76.33 264.2,76.33 265.34,75.19 268.47,75.19 270.69,72.97 270.69,69.63 268.51,67.45 268.51,66.11 268.63,65.99 268.89,65.99 v2(269.03,66.14)
  BOTTOM w0.076: UC1.A17 122.88,113.31 122.91,113.35 122.91,113.5 122.87,113.55 122.87,113.87 122.85,113.89 122.85,114.15 123.16,114.46 v2(123.33,114.46)
PCIE_PTX_DRX_P3: length 152.8
  IN3 w0.135: v2(122.63,117.99) 122.58,118.04 122.58,118.24 122.71,118.38 123.07,118.38 125.53,115.92 129.37,115.92 129.88,116.43 139.1,116.43 140.01,117.35 143.72,117.35 145.55,115.52 148.69,115.52 149.12,115.95 154,115.95 156.7,113.25 156.7,111.43 164.44,103.69 164.44,99.42 arc(167.02,86.44) 174.38,75.44 175.37,74.44 arc(184.57,68.3) 195.41,66.14 203.56,66.14 204.28,65.43 221.02,65.43 223.39,67.8 225.41,67.8 227.98,70.38 229.24,70.38 230.1,71.23 230.1,71.89 229.74,72.25 v2(229.02,72.25)
  BOTTOM w0.076: UC1.C17 122.88,111.94 123,111.94 123.09,112.03 123.09,112.21 122.98,112.32 122.69,112.32 122.6,112.42 122.54,112.58 122.54,112.75 122.58,112.87 122.58,113.13 122.41,113.47 122.41,116.94 122.42,116.96 122.42,116.98
  BOTTOM w0.104: 122.42,116.98 122.42,117.79 v2(122.63,117.99) ; v2(229.02,72.25) 229.23,72.03 229.71,72.03 CZ12.1
PCIE_PTX_DRX_P4: length 155.2
  IN3 w0.135: v2(224.84,71.06) 224.64,70.86 224.64,69.95 223.96,69.28 222.83,69.28 220.37,66.82 204.99,66.82 204.31,67.5 195.57,67.5 arc(190.23,68.03) 185.1,69.58 arc(180.37,72.11) 176.22,75.52 175.34,76.4 arc(168.41,86.67) 165.81,98.78 arc(165.81,99.55) 165.8,100.33 165.8,105.35 159.03,112.13 159.03,113.61 154.9,117.74 153.36,117.74 148.97,122.12 138.07,122.12 137.47,122.72 134.05,122.72 132.15,120.83 123.28,120.83 121.5,119.05 121.5,118.68 v2(121.68,118.5)
  BOTTOM w0.076: 121.5,116.98 121.5,116.96 121.49,116.94 121.49,116.28 121.14,115.93 121.14,114.18 121.35,113.97 121.54,113.97 121.64,113.88 121.64,113.7 121.56,113.63 121.31,113.63 121.21,113.52 121.21,113.46 121.23,113.42 121.34,113.31 UC1.A19
  BOTTOM w0.104: v2(224.84,71.06) 224.46,70.67 224.46,70.29 228.88,65.87 229.38,65.87 CZ14.1 ; v2(121.68,118.5) 121.5,118.32 121.5,116.98
PCIE_PTX_DRX_P9: length 213.5
  TOP w0.104: CL5.1 240.09,126.23 239.23,126.23 238.96,125.96 238.96,125.71 238.8,125.54 v2(238.8,125.42)
  IN1 w0.119: v2(118.06,116.57) 118.23,116.4 118.23,116.4 118.43,116.21 118.57,116.21 118.68,116.32 118.68,117.46 120.48,119.26 124.28,119.26 124.73,118.81 131.96,118.81 132.39,118.38 137.55,118.38 139.22,120.05 145.03,120.05 145.9,119.17 151.69,119.17 152.36,118.5 155.46,118.5 158.77,115.19 160.04,115.19 162.56,112.67 162.56,110.42 166.95,106.03 166.95,99.75 arc(169.39,87.49) 176.34,77.1 177.06,76.37 arc(185.81,70.53) 196.12,68.47 226.04,68.47 227.75,70.18 227.75,72.92 226.84,73.82 226.84,76.87 227.77,77.8 227.77,78.37 231.47,82.07 231.47,93.08 233.12,94.74 233.12,99.24 233.51,99.63 233.51,113.27 234.23,113.99 234.23,122.07 235.6,123.44 238.08,123.44 239.21,124.57 239.21,125.01 238.99,125.23 238.99,125.3 238.87,125.42 v2(238.8,125.42)
  BOTTOM w0.076: v2(118.06,116.57) 118.06,116.49 118.44,116.11 118.44,115.98 118.72,115.7 118.72,113.42 118.82,113.31 UC1.A23
PCIE_PTX_DRX_P11: length 166
  IN3 w0.135: v2(118.06,115.06) 116.35,115.06 116.01,115.39 116.01,117.03 114.65,118.39 111.48,118.39 108.24,121.63 106.3,121.63 103.38,124.55 94.49,124.55 93.85,125.18 91.51,125.18 91.21,124.88 82.68,124.88 79.93,122.13 72.82,122.13 72.31,122.64 61.62,122.64 60.7,121.72 48.67,121.72 47.14,120.19 47.14,118.97 43.14,114.97 43.14,112.66 41.44,110.96 41.44,103.85 39.97,102.37 39.97,95.51 38.06,93.61 38.06,90.97 35.85,88.76 35.85,85.89 34.94,84.97 34.94,73.92 27.1,66.09 27.1,60.39 20.66,53.94 20.66,51.63 19.86,50.84 v2(19.86,49.96)
  BOTTOM w0.076: UC1.C24 118.42,112.29 118.34,112.22 118.21,112.22 118.13,112.29 118.13,112.47 118.27,112.61 118.27,112.7 118.13,112.85 118.13,113.56 117.5,114.18 117.5,114.44 117.5,114.58 117.74,114.82 117.93,114.82 118.06,114.95 v2(118.06,115.06)
  BOTTOM w0.104: v2(19.86,49.96) 20.05,49.77 20.05,49.28 20.37,48.96 20.37,48.64 CN70.2
PCIE_PTX_DRX_P12: length 179.4
  IN3 w0.135: v2(17.29,50.19) 18.25,50.19 19.98,51.91 19.98,54.28 26.38,60.68 26.38,66.76 26.8,67.18 26.8,82.94 30.02,86.17 32.23,86.17 33.72,87.65 33.72,90.35 39.22,95.85 39.22,102.83 40.73,104.34 40.73,107.9 38.12,110.5 38.12,122.03 40.47,124.38 71.76,124.38 72.73,123.4 80.06,123.4 83.29,126.63 94.89,126.63 95.86,125.66 103.63,125.66 106.99,122.31 108.56,122.31 111.75,119.11 115.7,119.11 117.64,117.17 117.64,116.07 117.27,115.71 116.47,115.71 v2(116.46,115.7)
  BOTTOM w0.076: v2(116.46,115.7) 116.59,115.83 116.74,115.83 117.02,115.56 117.02,114.07 117.4,113.68 117.4,113.17 117.85,112.72 UC1.B25
  BOTTOM w0.104: CN72.2 16.47,49.67 16.69,49.89 16.99,49.89 v2(17.29,50.19)
PCIE_RCOMPN: length 3.1
  TOP w0.127: RC45.1 129.65,109.33 v1(129.65,108.25)
  TOP w0.381: v2(129.3,110.18) 129.63,110.18 130,109.82 RC45.1
  BOTTOM w0.254: v2(129.3,110.18) UC1.F5
PCIE_RCOMPP: length 2.7
  TOP w0.381: RC45.2 130.91,109.79 129.88,110.81 v2(129.3,110.81)
  BOTTOM w0.254: v2(129.3,110.81) UC1.E5
PCIE_WAKE#: length 474.6
  TOP w0.112: RE275.2 RE274.1 259.93,76.86 v2(259.74,76.67) ; v2(248.87,69.99) 248.45,69.57 247.69,69.57 247.29,69.96 244.91,69.96 244.19,69.25 v1(242.49,69.25) 241.15,69.25 239.35,67.46 239.35,67.06 240.23,66.18 240.23,64.58 239.86,64.2 239.45,64.2 v2(238.94,63.69)
  IN1 w0.076: 15.7,42.23 JNGFF3.54
  IN1 w0.119: v2(20.52,70.05) 19.58,69.11 19.58,62.91 23.7,58.79 23.7,54.99 19.87,51.17 15.7,51.17 12.39,47.86 12.39,45.86 15.7,42.55 15.7,42.23
  IN2 w0.124: v2(259.74,76.67) 258.56,76.67 257.44,77.79 252.17,77.79 250.8,76.41 249.63,76.41 249.25,76.03 247.22,76.03 246.89,76.36 246.89,77.51 246.55,77.85 244.79,77.85 244.32,78.31 236.39,78.31 235.35,77.27 235.35,76.49 234.46,75.6 v2(234.46,74.91) 233.8,74.91 232.28,73.39 231.39,73.39 228.58,70.58 226.53,70.58 225.53,69.57 221.5,69.57 220.85,68.92 207.97,68.92 206.7,70.19 186.61,70.19 184.93,71.87 181.9,71.87 172.55,81.22 172.55,83.73 170.06,86.22 170.06,88.69 168.15,90.61 168.15,106.38 163.74,110.79 163.74,116.79 162.12,118.41 162.12,121.61 159.45,124.28 159.45,130.34 158.52,131.27 157.19,131.27 156.37,132.08 154.32,132.08 153.36,131.13 148.75,131.13 144.93,134.95 127.06,134.95 125.91,133.79 123.72,133.79 123.11,133.18 117.78,133.18 117.19,132.6 109.69,132.6 109.31,132.98 108.18,132.98 107.9,133.26 83.62,133.26 79.12,128.76 75.46,128.76 75.18,129.04 62.53,129.04 61.77,128.28 47.57,128.28 45.87,126.58 39.17,126.58 30.76,118.17 30.76,112.38 35.71,107.43 35.71,93.04 33.68,91.01 25.74,91.01 22.88,88.15 19.01,88.15 17.87,87.01 17.87,81.93 15.52,79.58 15.52,76.85 18.92,73.45 18.92,71.66 v2(20.52,70.05)
  IN3 w0.135: v2(259.74,76.67) 253.49,76.67 249.86,73.04 249.86,70.95 248.89,69.99 v2(248.87,69.99)
  BOTTOM w0.112: JNGFF1.70 240.2,63.4 239.85,63.05 239.5,63.05 238.94,63.61 v2(238.94,63.69) ; JNGFF2.46 236.8,98.5 233.16,94.86 233.16,91.34 232.66,90.84 232.66,88.87 232.98,88.55 232.98,83.31 233.75,82.54 235.59,82.54 235.7,82.42 235.7,80.44 234.96,79.7 234.96,75.42 v2(234.46,74.91) 234.46,73.1 234.97,72.59 234.97,70.64 234.55,70.22 234.55,67.55 234.14,67.15 JNGFF1.55
PCIE_WAKE#_R: length 32
  TOP w0.107: UE1.N13 256.49,93.46 258.09,95.06 v2(258.09,95.45)
  TOP w0.112: RE35.1 258.41,95.77 v2(258.09,95.45) ; v2(263.08,79.83) v1(262.33,79.08) RE275.1
  BOTTOM w0.112: v2(258.09,95.45) 258.63,95.99 259.86,95.99 260.4,96.53 261.19,96.53 261.77,95.95 264.78,95.95 266.77,93.95 266.77,83.53 v2(263.08,79.83)
PD1_GPIO2: length 4.6
  TOP w0.076: UT5.D10 32.27,78.72 32.27,77.31
  TOP w0.112: v2(32.38,76.97) 32.38,76.97 32.27,77.08 32.27,77.31
  BOTTOM w0.112: RT71.1 33.03,78.48 32.76,78.21 v1(32.76,77.58) 32.76,77.35 v2(32.38,76.97)
PD1_GPIO6: length 5.6
  TOP w0.076: UT5.G10 30.77,78.72 30.77,77.8 30.28,77.31
  TOP w0.112: RT75.1 29.42,74.26 29.42,76.66 29.56,76.79 29.76,76.79 30.28,77.31
PD1_GPIO7: length 3.5
  TOP w0.076: UT5.D7 32.78,80.73 v2(32.99,80.73)
  BOTTOM w0.112: v2(32.99,80.73) 32.5,80.73 RT339.1 31.66,79.9 30.51,79.9 v1(30.44,79.83)
PD1_GPIO8: length 4
  TOP w0.076: v2(30.05,81.32) 30.18,81.32 UT5.H6
  BOTTOM w0.112: v2(30.05,81.32) 30.02,81.34 RT377.1 28.75,81.89 28.75,82.23 RT76.1 28.1,82.88 v1(28.1,83.45)
PD#: length 10.7
  TOP w0.112: v1(259.8,68.86) 260.08,68.58 RA50.2 RA48.2 262.08,68.27 DA8.2 262.99,68.07 RA18.1 262.99,67.13 262.66,66.8 CA31.1 262.34,66.05 262.34,65.1 262.01,64.77 262.01,64.25 261.01,63.24 261.01,62.42 260.73,62.14 UA1.47
PECI_EC: length 246.2
  TOP w0.112: v2(254.28,97.37) 253.64,96.73 RE60.2
  IN1 w0.119: v2(153.67,124.72) 152.91,123.97 146.54,123.97 146.13,124.38 139.36,124.38 139.2,124.21 133.42,124.21 132.01,122.81 v2(131.65,122.81)
  IN2 w0.124: v2(131.65,122.81) 131.29,122.81 130.97,123.12 130.27,123.12 129.94,123.45 120.39,123.45 119.55,124.3 118.57,124.3 117.14,122.87 111.55,122.87 111.28,122.59 102.94,122.59 v2(102.5,123.03) ; v2(153.67,124.72) 154.18,124.72 158.32,120.58 158.32,118.02 160.77,115.56 160.77,112.51 160.18,111.92 160.18,109.75 163.54,106.39 163.54,105.59 164.42,104.72 164.42,90.15 167.1,87.46 167.1,84.99 169.54,82.55 169.54,79.81 170.85,78.51 170.85,74 171.63,73.21 176.06,73.21 180.14,69.14 183.79,69.14 185.55,67.37 205.36,67.37 206.68,66.05 226.63,66.05 228,67.42 231.4,67.42 232.02,66.8 232.97,66.8 235.41,69.25 239.49,69.25 240.99,70.76 240.99,71.59 241.6,72.2 243.47,72.2 244.23,72.96 249.25,72.96 249.45,73.16 252.51,73.16 253.46,74.11 v2(258.6,74.11)
  BOTTOM w0.076: 101.53,119.17 101.18,118.82 101.18,117.3 101.37,117.11 101.37,116.03 101.22,115.87 101.22,115.16 101.74,114.64 101.74,113.42 UC1.A54
  BOTTOM w0.102: v2(102.5,123.03) 101.58,122.11 v1(101.58,119.44) 101.58,119.22 101.53,119.17
  BOTTOM w0.112: v2(254.28,97.37) 254.28,95.07 255.99,93.36 255.99,91.55 257.01,90.54 257.01,87.76 257.33,87.43 258.32,87.43 259.61,86.15 259.61,83.73 259.73,83.62 259.73,79.39 259.46,79.12 259.46,78.67 258.52,77.73 258.52,77.2 258.62,77.1 258.62,76.05 258.8,75.87 258.8,74.32 v2(258.6,74.11)
PECI_EC_R: length 2.5
  TOP w0.107: UE1.K13 253.52,93.83 253.52,94.46 253.64,94.59 v1(253.64,94.83) RE60.1
PGOOD_3V: length 56.1
  TOP w0.254: v2(152.51,77.54) 147.57,77.54 147.38,77.35 v2(146.84,77.35)
  IN3 w0.203: v2(146.84,77.35) 146.71,77.23 146.71,71.84 150.87,67.68 157.78,67.68 161.78,63.68 161.78,61.56 164.86,58.48 165.94,58.48 166.22,58.76 167.34,58.76 168.21,59.63 173.81,59.63 173.99,59.45 176.78,59.45 177.82,58.41 v2(178.56,58.41)
  BOTTOM w0.112: v2(152.51,77.54) 151.76,77.54 v1(151.62,77.4)
  BOTTOM w0.254: PR107.2 179.04,57.59 PR119.1 178.56,58.08 v2(178.56,58.41) ; v2(152.51,77.54) 152.51,77.04 152.17,76.69 152.17,76.22 152.49,75.9 PU100.9
PGOOD_5V: length 2.8
  BOTTOM w0.254: PR120.1 180.83,56.69 PR113.2 182.36,56.69 182.96,56.09 PU102.9
PLTRST_LAN#: length 202.6
  TOP w0.112: v2(243.56,129.35) 243.99,129.35 244.08,129.26 UL1.36 ; v2(155.97,107.71) 155.97,110.53 156.37,110.93 156.37,115.28 156.73,115.63 156.73,118.25 157.94,119.45 v4(158.99,119.45) v2(160,119.45)
  IN1 w0.119: v2(229.69,63.87) 229.35,63.53 228.32,63.53 228.28,63.57 221.05,63.57 220.65,63.97 195.83,63.97 arc(183.77,66.37) 173.55,73.2 173.18,73.57 171.35,73.57 170.95,73.96 169.73,73.96 169.34,74.36 169.34,78.13 169.34,78.13 arc(167.39,81.08) 165.76,84.21 arc(163.16,91.87) 162.28,99.91 162.28,100.73 156.55,106.46 156.55,107.12 v2(155.97,107.71)
  IN3 w0.135: v2(243.56,129.35) 242.68,128.47 241.31,128.47 240.41,127.57 240.41,122.9 239.85,122.34 239.85,121.45 240.76,120.54 240.76,107.34 242.72,105.38 242.72,100.78 241.85,99.91 240.01,99.91 238.11,98 238.11,91.59 236.93,90.41 236.93,87.01 236.02,86.09 236.02,83.93 236.27,83.68 238.87,83.68 239.86,82.69 239.86,80.72 240.43,80.15 240.43,78.17 241.12,77.48 241.12,70.01 239.52,68.41 239.52,67.73 238.79,67 237.34,67 235.49,65.15 233.79,65.15 232.85,64.21 230.04,64.21 v2(229.69,63.87)
  BOTTOM w0.112: RC62.2 v2(160,119.45)
PLTRST_TPM#: length 16
  IN2 w0.124: v2(157.76,116.98) 158.75,116.98 160.34,115.38 160.34,112.69 159.76,112.1 159.76,108.69 160.98,107.47 v2(160.98,106.53)
  BOTTOM w0.112: v2(157.76,116.98) 158.07,116.98 158.72,117.63 RC325.2 RC60.2 ; v2(160.98,106.53) 160.83,106.68 UZ12.17
PM_LANPHY_ENABLE: length 239.7
  TOP w0.112: RL7.1 242.01,118.83 242.59,118.25 242.59,117.74 v4(240.89,116.03) 240.31,115.45 v2(240,115.45)
  IN2 w0.124: v2(240,115.45) 240,111.09 241.35,109.74 242.93,109.74 246.94,105.73 258.54,105.73 261.9,102.37 262.15,102.37 262.81,101.71 262.81,99.81 262.91,99.71 262.91,93.28 263.93,92.27 263.93,89.09 265.2,87.82 265.2,84.77 266.33,83.63 266.33,78.92 265.86,78.45 265.86,75.02 262.13,71.28 262.13,69.92 260.58,68.38 260.49,68.38 258.77,66.66 255.83,66.66 255.52,66.36 252.45,66.36 251.43,65.34 249.19,65.34 244.37,60.51 244.37,59.62 242.63,57.87 236.91,57.87 234.67,55.64 229.77,55.64 229.4,56 226.46,56 224.96,57.51 220.61,57.51 219.87,58.24 215.46,58.24 214.45,57.24 205.2,57.24 201.67,60.77 173.51,60.77 170.14,64.14 161.88,64.14 158.48,67.54 149.66,67.54 149.2,68.01 148.72,68.01 145.29,71.44 145.29,72.19 143.2,74.27 143.2,75.68 141.63,77.25 v2(141.63,77.43)
  BOTTOM w0.076: 123.87,87.16 123.87,87.26 122.44,88.7 122.44,90.27 122.24,90.46 122.24,90.83 122.29,90.94 122.29,91.06 122.23,91.28 122.23,91.42 122.28,91.58 122.28,91.66 122.5,92.36 122.5,92.36 122.67,92.54 UC1.AW17
  BOTTOM w0.112: v2(141.63,77.43) 140.82,77.43 140.64,77.25 130.08,77.25 126.64,80.69 126.64,82.94 123.87,85.71 123.87,87.16
PME#: length 2.5
  TOP w0.112: T115.1 125.25,95.08 125.25,93.86 v2(125.66,93.44)
  BOTTOM w0.076: UC1.AU11 125.97,93.8 125.66,93.5 v2(125.66,93.44)
POA_WAKE#: length 44
  TOP w0.107: UE1.E4 v2(249.48,85.86)
  TOP w0.112: RE324.1 246.21,76.45 v2(246.25,76.49) 246.53,76.77 v1(246.81,76.77)
  IN3 w0.135: v2(249.48,85.86) 249.08,85.46 249.08,84 247.61,82.52 247.61,81.38 248.06,80.92 248.06,78.84 246.75,77.52 246.75,76.84 246.4,76.49 v2(246.25,76.49) 247.19,75.55 247.19,70.11 246.73,69.66 246.73,67.77 242.85,63.88 242.85,60.3 241.87,59.32 233.34,59.32 232.63,60.04 v2(232.18,60.04)
  BOTTOM w0.112: JUSH1.4 231.95,59.81 232.18,60.04 v2(232.18,60.04)
PORT80_DET#: length 35
  TOP w0.107: UE1.K4 v2(254.28,85.86)
  TOP w0.112: v2(242.21,88.4) 241.93,88.12 RE513.1 240.64,87.62 239.83,87.62 RE512.1 ; v1(240.55,99.13) 239.95,98.53 v2(239.31,98.53) 238.9,98.94 RZ131.1
  IN1 w0.119: v2(239.31,98.53) 239.96,97.88 239.96,97.3 241.43,95.84 241.43,92.49 242.21,91.7 v2(242.21,88.4)
  IN2 w0.124: v2(242.21,88.4) 243.17,89.36 249.59,89.36 249.89,89.65 249.89,90.06 250.09,90.26 250.48,90.26 250.69,90.47 250.69,90.85 250.91,91.06 251.3,91.06 251.61,90.75 251.61,90.28 253.01,88.89 253.49,88.89 253.88,88.49 UE1.K4 v2(254.28,85.86)
POWER_SW#_MB: length 131
  TOP w0.112: SW3.4 292.19,122.78 v2(292.19,123.96) 292.19,126.02 SW3.2 ; RE33.2 CE10.1 242.89,79.97 242.89,81.05 242.58,81.35 240.7,81.35 v4(239.84,82.21) 239.52,82.54 v2(239.52,83.71) ; JAPS1.11 v2(259.56,109.36)
  IN1 w0.119: v2(259.56,109.36) 258.75,110.16 258.36,110.16 253.13,115.39 253.13,122.08 258.95,127.9 285.9,127.9 289.25,124.55 289.25,123.15 289.65,122.76 291.17,122.76 292.19,123.77 v2(292.19,123.96) ; v2(239.52,83.71) 239.34,83.89 238.69,83.89 238.23,84.36 238.23,85.51 238,85.74 238,87.85 238.7,88.56 238.7,93.56 238.34,93.93 238.34,103.17 237.11,104.4 237.11,113.17 v2(237.74,113.8)
  BOTTOM w0.112: v2(259.56,109.36) 259.13,109.79 255.08,109.79 253.83,108.55 251.47,108.55 250.57,109.45 244.05,109.45 239.7,113.8 v2(237.74,113.8)
POWER_SW_IN#: length 15.7
  TOP w0.107: UE1.D5 v2(248.68,86.66)
  TOP w0.112: v1(241.86,76.99) 242.02,76.99 v2(242.61,77.58) 242.75,77.72 RE33.1 RE31.2 CE12.1
  IN1 w0.119: v2(248.68,86.66) 248.27,86.25 248.27,84.89 242.61,79.23 v2(242.61,77.58)
PRIM_PWRGD_GPIO024: length 6.6
  TOP w0.107: RE361.1 RE362.1 247.52,79.05 v1(247.52,81.86) 247.52,82.76 248.28,83.53 UE1.C1
PROCHOT#_ISL88738: length 26.1
  TOP w0.112: v1(51.47,54.52) v2(51.47,55.08) PR926.2 51.61,55.7 52.31,55 53.08,55 54.12,56.04 PU901.23
  IN3 w0.135: v2(58.85,51.42) 58.47,51.04 54.96,51.04 54.62,51.38 51.15,51.38 46.68,55.85 46.68,56.31 46.94,56.57 49.98,56.57 v2(51.47,55.08)
  BOTTOM w0.112: PQ1216.1 58.95,51.32 v2(58.85,51.42)
PS_ID: length 318.6
  TOP w0.107: UE1.L11 v2(255.08,92.26)
  TOP w0.112: v2(44.16,118.03) 44.38,118.03 44.65,118.3 v1(44.65,118.62) 44.65,120.36 44.4,120.61 PR4.1 PR5.2
  IN2 w0.124: v2(44.16,118.03) 44.1,118.03 43.72,117.66 43.1,117.66 39.01,121.74 39.01,122.39 39.57,122.95 39.98,122.95 42.56,125.53 46.5,125.53 47.43,126.46 48.63,126.46 49.67,125.42 61.36,125.42 63.56,127.63 74.49,127.63 74.85,127.27 80,127.27 83.65,130.92 104.07,130.92 104.53,131.38 108.75,131.38 109.62,130.51 117.37,130.51 118.61,131.76 124.15,131.76 124.94,130.97 124.94,130.74 125.29,130.39 126.33,130.39 126.88,130.95 129.88,130.95 130.76,131.82 134.31,131.82 136.42,133.93 143.47,133.93 144.32,133.08 145.27,133.08 148.22,130.14 154.98,130.14 155.47,130.63 156.34,130.63 158.54,128.42 158.54,123.9 161.21,121.23 161.21,118.03 162.83,116.41 162.83,110.41 167.24,106 167.24,90.24 169.16,88.32 169.16,85.84 171.62,83.38 171.62,80.8 181.46,70.97 184.55,70.97 186.27,69.25 206.27,69.25 207.53,67.99 221.9,67.99 222.58,68.67 226.13,68.67 227.14,69.67 228.95,69.67 231.36,72.08 232.39,72.08 234.01,73.7 234.93,73.7 235.69,74.45 235.69,75.4 236.36,76.08 236.36,76.92 236.83,77.39 238.48,77.39 239.18,76.7 244.31,76.7 245.73,75.27 249.26,75.27 249.64,74.89 250.42,74.89 251.23,75.7 252.75,75.7 253.56,76.51 257.75,76.51 259.2,75.07 260.68,75.07 262.13,76.52 262.13,79.89 261.96,80.06 261.96,84.25 261.68,84.53 261.12,84.53 258.21,87.44 257.59,87.44 256.85,88.18 256.85,90.49 v2(255.08,92.26)
PWM1_GT: length 12.6
  TOP w0.112: PR680.1 59.26,89.99 v1(59.62,89.62)
  TOP w0.203: v2(53.54,92.7) 53.47,92.77 PU602.12
  TOP w0.254: PR680.1 v2(59.26,91.9)
  IN1 w0.254: v2(59.26,91.9) 58.88,91.51 55.14,91.51 53.96,92.7 v2(53.54,92.7)
  BOTTOM w0.203: PU612.8 60.1,90.31 59.95,90.16 59.48,90.16 59.26,90.38 v2(59.26,91.9)
PWM_IA: length 19
  TOP w0.203: PU602.22 51.53,97.11 52.34,97.92 v1(52.34,98.27) 52.63,98.56 v2(52.75,98.56)
  IN1 w0.254: v2(54.51,111.71) 54.51,102.55 53.21,101.26 53.21,99.02 v2(52.75,98.56)
  BOTTOM w0.203: v2(54.51,111.71) PR662.1 55.13,111.4 54.6,110.87 54.6,110.53 54.8,110.32 PU610.8
PWM_SA: length 2.3
  BOTTOM w0.112: v1(58.63,113.6) PR606.1
  BOTTOM w0.254: PR606.1 58.64,114.56 PU614.3
PWM_VSA: length 32.7
  TOP w0.112: v4(53.12,117.74) 53.12,117.09 v2(53.59,116.62)
  TOP w0.203: v2(47.75,98) 47.85,98 48.33,97.52 PU602.30
  IN1 w0.254: v2(53.59,116.62) 50.15,116.62 47.12,113.59 47.12,107.83 48.18,106.77 48.18,103.98 46.8,102.6 46.8,101.39 47.14,101.05 47.14,98.54 47.67,98 v2(47.75,98)
  BOTTOM w0.254: PR606.2 55.66,114.55 v2(53.59,116.62)
REM_DIODE1_N: length 204.9
  TOP w0.127: QE3.3 116.04,101.03 117.64,101.03 118.05,100.63 118.66,100.63 CE35.1 118.34,101.05 v2(118.33,101.03)
  TOP w0.254: UE1.A8 246.57,89.34 244.33,89.34 CE24.1 243.84,89.41 238.92,89.41 236.48,86.97 235.35,86.97 232.95,84.57 232.15,84.57 v2(232.11,84.61)
  IN3 w0.254: v2(219.61,52.01) 219.07,51.47 213.52,51.47 212.98,52.01 210.13,52.01 209.46,51.34 186.58,51.34 184.57,53.35 180.82,53.35 179.33,54.84 160.17,54.84 159.64,55.36 148.51,55.36 146.73,57.14 146.73,57.75 144.93,59.56 144.93,64.76 144.7,64.99 144.7,68.31 142.66,70.35 142.66,74.19 140.54,76.31 140.54,78.8 139.03,80.31 139.03,82.24 136.9,84.36 132.46,84.36 125.35,91.48 117.35,91.48 114.13,94.7 114.13,98.4 113.69,98.85 113.69,99.3 113.96,99.58 114.56,99.58 114.75,99.39 116.06,99.39 117.71,101.03 v2(118.33,101.03)
  BOTTOM w0.254: v2(219.61,52.01) 219.64,52.05 219.64,52.91 220.13,53.4 220.13,56.43 219.75,56.8 219.75,68.6 221.09,69.94 221.09,72.34 226.22,77.47 226.22,79.23 227.59,80.59 229,80.59 230.95,82.54 230.95,84.01 231.51,84.57 232.07,84.57 v2(232.11,84.61)
REM_DIODE1_P: length 207
  TOP w0.127: v2(118.47,102.23) 118.81,102.23 CE35.2 118.81,101.69 QE3.1 116.68,101.69 QE3.2
  TOP w0.254: v2(232.11,84.02) 232.15,84.06 233.17,84.06 235.57,86.46 236.69,86.46 239.13,88.9 243.86,88.9 CE24.2 244.18,88.83 246.51,88.83 UE1.A7
  IN3 w0.254: v2(118.47,102.23) 118.18,102.23 115.85,99.9 114.96,99.9 114.77,100.09 113.75,100.09 113.18,99.52 113.18,98.64 113.63,98.19 113.63,94.49 117.14,90.97 125.14,90.97 132.25,83.86 136.69,83.86 138.52,82.03 138.52,80.1 140.03,78.59 140.03,76.1 142.15,73.98 142.15,70.14 144.19,68.1 144.19,64.78 144.42,64.55 144.42,59.35 146.23,57.54 146.23,56.92 148.3,54.85 159.43,54.85 159.95,54.33 179.12,54.33 180.61,52.84 184.36,52.84 186.37,50.84 209.68,50.84 210.34,51.5 212.77,51.5 213.31,50.96 219.28,50.96 220.19,51.87 v2(220.19,52.01)
  BOTTOM w0.254: v2(220.19,52.01) 220.15,52.05 220.15,52.7 220.64,53.19 220.64,56.64 220.26,57.01 220.26,68.39 221.6,69.73 221.6,72.13 226.73,77.26 226.73,79.02 227.8,80.08 229.21,80.08 231.46,82.33 231.46,83.8 231.72,84.06 232.07,84.06 v2(232.11,84.02)
REM_DIODE2_N: length 149.3
  TOP w0.254: v2(237.4,89.76) 238.52,90.88 242.9,90.88 CE26.1 243.31,90.88 246.51,90.88 UE1.A10 ; v2(237.77,78.95) 237.22,78.95 CE37.2 237,78.74 QE5.3
  IN1 w0.254: v2(237.4,89.76) 237.37,89.72 236.34,89.72 235.22,88.61 235.22,80.03 236.12,79.13 237.59,79.13 v2(237.77,78.95)
  IN3 w0.254: v2(227.06,51.51) 227.02,51.47 227.02,50.3 226.21,49.49 185.29,49.49 183.21,51.57 180.07,51.57 178.58,53.06 159.39,53.06 158.92,53.53 155.65,53.53 v2(155.45,53.33)
  BOTTOM w0.254: v2(227.06,51.51) 227.05,51.52 227.05,52.03 227.4,52.39 228.95,52.39 229.69,51.65 231.96,51.65 232.91,52.6 232.91,53.54 234.61,55.23 234.61,56.36 237.68,59.43 237.68,60.66 237.47,60.87 237.47,60.88 237.46,60.89 237.46,62.98 237.18,63.26 237.18,68.55 236.82,68.92 236.82,78.69 237.18,79.04 237.68,79.04 v2(237.77,78.95) ; v2(155.45,53.33) 155.4,53.38 155.4,53.81 152.78,56.42 152.13,56.42 151.81,56.74 151.81,57.01 151.46,57.36 CE46.2 150.46,57.36 150.22,57.61 QE7.2 150.22,58.14 149.82,58.53 149.82,59.27 QE7.1
REM_DIODE2_P: length 147.4
  TOP w0.254: UE1.A9 246.57,90.37 243.31,90.37 CE26.2 242.9,90.37 238.74,90.37 237.54,89.17 v2(237.4,89.17) ; QE5.2 235.34,80.04 QE5.1 236.74,79.39 CE37.1 237.27,79.64 v2(237.77,79.64)
  IN1 w0.254: v2(237.77,79.64) 236.33,79.64 235.73,80.24 235.73,88.4 236.55,89.21 237.36,89.21 v2(237.4,89.17)
  IN3 w0.254: v2(226.48,51.5) 226.52,51.46 226.52,50.51 226,50 185.5,50 183.42,52.08 180.28,52.08 178.79,53.57 159.6,53.57 159.13,54.04 155.42,54.04 154.86,53.48 v2(154.86,53.33)
  BOTTOM w0.254: v2(226.48,51.5) 226.48,51.51 226.54,51.57 226.54,52.24 227.19,52.89 229.16,52.89 229.9,52.16 231.75,52.16 232.4,52.81 232.4,53.75 234.1,55.44 234.1,56.57 237.17,59.65 237.17,60.45 236.96,60.66 236.96,62.77 236.68,63.05 236.68,68.34 236.31,68.71 236.31,78.9 236.97,79.55 237.68,79.55 v2(237.77,79.64) ; QE7.3 148.92,57.16 149.63,56.45 CE46.1 151.38,56.45 151.92,55.92 152.57,55.92 154.89,53.6 154.89,53.35 v2(154.86,53.33)
REM_DIODE4_N: length 231.3
  TOP w0.254: v2(58.55,84.42) 58.49,84.47 58.49,99.98 58.7,100.19 59.02,100.19 v2(59.08,100.13) ; UE1.A11 246.26,92.28 244.26,92.28 CE27.1 243.72,92.15 237.92,92.15 236.17,90.4 235.22,90.4 232.24,87.43 231.79,87.43 227.02,82.66 227.02,79.09 arc(226.55,76.43) 225.07,74.18 224.66,73.78 arc(222.69,72.46) 220.37,71.99 214.06,71.99 210.15,68.08 191.13,68.08 arc(187.68,68.53) 184.45,69.84 arc(181.96,71.21) 179.45,72.54 163.67,72.54 161.32,70.19 148.79,70.19 142.8,76.18 142.8,77.38 v2(142.84,77.42)
  IN1 w0.254: v2(142.84,77.42) 142.8,77.38 142.8,76.67 141.88,75.75 87.04,75.75 80.36,82.42 73.86,82.42 73.06,83.22 70.81,83.22 69.9,82.31 61.26,82.31 59.15,84.42 v2(58.55,84.42)
  BOTTOM w0.254: v2(59.08,100.13) 58.52,100.13 CE39.1 57.4,99.96 QE6.3
REM_DIODE4_P: length 235.9
  TOP w0.127: UE1.B10 247.09,91.45 246.37,91.45
  TOP w0.254: v2(59.08,100.72) 59.05,100.7 58.49,100.7 57.99,100.19 57.99,84.47 v2(57.94,84.42) ; 246.37,91.45 246.05,91.77 244.26,91.77 CE27.2 243.98,91.64 238.13,91.64 236.38,89.9 235.43,89.9 232.45,86.92 232,86.92 227.53,82.45 227.53,79.1 arc(227.02,76.24) 225.43,73.82 225.02,73.42 arc(222.89,71.99) 220.37,71.49 214.27,71.49 210.36,67.57 191.13,67.57 arc(187.55,68.04) 184.2,69.39 arc(181.73,70.73) 179.24,72.03 163.88,72.03 161.53,69.68 148.58,69.68 142.29,75.97 142.29,77.38 v2(142.25,77.42)
  IN1 w0.254: v2(57.94,84.42) 57.94,84.53 58.34,84.93 59.36,84.93 61.47,82.81 69.69,82.81 70.6,83.73 73.27,83.73 74.07,82.93 80.57,82.93 87.25,76.25 141.67,76.25 142.29,76.88 142.29,77.38 v2(142.25,77.42)
  BOTTOM w0.254: v2(59.08,100.72) 58.51,100.72 CE39.2 57.4,100.87 QE6.2 55.96,101.07 QE6.1
RES_BIAS: length 4.7
  TOP w0.112: UL1.12 248.48,122.54 248.59,122.43 249.78,122.43 250.34,121.87 RL13.1 250.81,121.36 v1(251.6,120.57)
RESET_OUT#_R: length 3.7
  BOTTOM w0.112: RC128.2 RC129.2 89.38,127.16 CC33.1 89.71,128.36 JXDP1.47
RING2: length 41.4
  IN3 w1.016: 254.02,60.65 254.02,57.86 253.83,57.67 253.83,56.34 254.6,55.57 256.94,55.57 259.61,52.91 264.23,52.91 268.13,56.81 273.06,56.81 283.51,46.36
  vias: v1(252.84,61.8) v2(252.58,61.35) v2(253.16,61.35) v2(284.38,46.05) v2(284.38,45.48)
RING2_R:
  vias: v2(289.56,46.49)
RJ45_MDIN0: length 28
  IN3 w0.203: v2(271.77,116.4) 271.89,116.53 271.89,117 272.26,117.37 273.72,117.37 280.4,110.69 280.4,101.46 281.35,100.51 282.57,100.51 282.77,100.71 JLOM1.2
  BOTTOM w0.267: TL1.14 271.42,118.54 271.87,118.1 271.87,116.5 v2(271.77,116.4)
RJ45_MDIN1: length 32.5
  IN1 w0.203: v2(268.43,113.73) 268.57,113.87 268.57,114.41 268.96,114.81 275.44,114.81 279.79,110.45 279.79,105.45 281.15,104.09 282.57,104.09 282.92,104.44 282.92,105.14 JLOM1.6
  BOTTOM w0.267: TL1.20 263.8,118.59 264.25,118.15 264.25,117.05 266.13,115.16 267.85,115.16 268.53,114.48 268.53,113.83 v2(268.43,113.73)
RJ45_MDIN2: length 31.9
  IN3 w0.203: v2(266.47,116.4) 266.47,117.19 268.4,119.12 273.68,119.12 281.53,111.27 281.53,105.22 282.41,104.34 283.79,104.34 JLOM1.5
  BOTTOM w0.267: TL1.18 266.34,118.34 266.47,118.21 v2(266.47,116.4)
RJ45_MDIN3: length 36.5
  IN1 w0.203: JLOM1.8 282.77,106.83 282.57,106.63 281.71,106.63 280.96,107.38 280.96,110.99 276.11,115.85 268.53,115.85 266.67,113.99 266.67,113.2 v2(266.55,113.07)
  BOTTOM w0.267: v2(266.55,113.07) 266.65,113.17 266.65,113.63 266.28,113.99 262.36,113.99 259.15,117.2 259.15,118.1 258.72,118.53 TL1.24
RJ45_MDIP0: length 28
  IN3 w0.203: v2(272.35,116.4) 272.22,116.53 272.22,116.87 272.4,117.04 273.58,117.04 280.07,110.55 280.07,101.32 281.21,100.18 JLOM1.1
  BOTTOM w0.267: 272.69,119.57 272.69,118.5 272.25,118.06 272.25,116.5 v2(272.35,116.4)
RJ45_MDIP1: length 32.5
  IN1 w0.203: v2(269.01,113.73) 268.9,113.84 268.9,114.27 269.1,114.48 275.3,114.48 279.46,110.31 279.46,105.31 282.55,102.22 JLOM1.3
  BOTTOM w0.267: v2(269.01,113.73) 268.91,113.83 268.91,114.64 268.01,115.54 266.29,115.54 264.63,117.21 264.63,118.13 265.07,118.58 TL1.19
RJ45_MDIP2: length 31.9
  IN3 w0.203: JLOM1.4 282.82,103.24 283.03,103.46 283.03,103.75 282.78,104.01 282.27,104.01 281.2,105.08 281.2,111.14 273.54,118.79 268.54,118.79 266.83,117.09 266.83,116.8 267.17,116.46 v2(267.17,116.4)
  BOTTOM w0.267: v2(267.17,116.4) 266.85,116.72 266.85,117.95 267.12,118.22 267.35,118.22 267.61,118.48 TL1.17
RJ45_MDIP3: length 36.5
  IN1 w0.203: v2(267.13,113.07) 267,113.2 267,113.85 268.67,115.52 275.97,115.52 280.63,110.86 280.63,107.24 281.57,106.3 JLOM1.7
  BOTTOM w0.267: TL1.23 259.99,118.6 259.54,118.15 259.54,117.36 262.52,114.37 266.44,114.37 267.03,113.78 267.03,113.17 v2(267.13,113.07)
RTCRST_ON: length 7.1
  TOP w0.112: v1(244.05,100.32) 244.47,99.9 RE93.1 245.6,100.15 245.25,100.51 QE12.2 244.85,101.31 244.85,103.85 RE514.2 RE515.2
RTCRST_ON_GPIO122: length 15.7
  TOP w0.112: UE1.F11 v2(250.28,92.26) ; v2(246.31,104.13) 245.63,104.81 RE515.1
  IN3 w0.135: v2(246.31,104.13) 247.29,104.13 247.84,103.58 247.84,97.42 248.56,96.7 248.56,95.7 250.28,93.98 v2(250.28,92.26)
RTCRST_ON_GPIO141: length 18.8
  TOP w0.112: v2(245.85,101.69) 245.27,101.69 245.07,101.89 245.07,103.43 RE514.1 ; UE1.B6 v2(247.05,87.43)
  IN1 w0.119: v2(247.05,87.43) 246.56,87.92 246.56,92.52 246.89,92.85 246.89,93.97 246.05,94.8 246.05,101.48 v2(245.85,101.69)
RTD3_CIO_PWR_EN: length 9.2
  BOTTOM w0.076: UC1.AC2 131.56,101.18 131.89,100.86 133.64,100.86 133.91,101.13 135.54,101.13
  BOTTOM w0.112: 135.54,101.13 135.65,101.13 136.15,100.62 138.86,100.62 139.09,100.85 T18.1
RUN_ON: length 340.4
  TOP w0.112: v2(157.71,62.06) 158.02,62.38 158.02,63.87 161.17,67.03 162.69,67.03 165.35,69.68 170.38,69.68 v2(170.66,69.4) ; v2(261.24,99.71) 261.25,99.69 RE280.2 RE292.1 ; v2(159.41,60.63) 159.3,60.74 UZ3.5 ; RZ345.1 203.22,52.28 202.14,53.37 202.14,56.65 198.58,60.21 184.95,60.21 v4(183.94,59.2) 182.92,58.18 v2(182.9,58.18) ; v2(144.68,127.47) PR402.1 ; UZ4.3 v2(279.91,90.54) ; v2(274.34,93.23) 273.25,94.32 270.15,94.32 269.7,94.78 269.7,95.26 268.91,96.05 268.26,96.05 267.46,96.85 266.46,96.85 265.65,97.66 UE5.4 v2(264.21,97.66)
  IN1 w0.119: 240.14,84.53 240.16,84.55 240.16,92.81 238.85,94.12 238.85,99.5 239.9,100.56 239.9,102.36 243.01,105.47 v2(243.01,107.9) ; 240.14,84.53 v2(238.91,84.53) ; 240.14,84.53 240.24,84.42 240.24,82.04 241.04,81.24 241.04,75.53 242.89,73.69 v2(242.89,73.24) ; v2(125.05,128.6) 125.22,128.6 126.04,127.78 129.94,127.78 130.18,127.55 140.01,127.55 140.24,127.78 144.36,127.78 v2(144.68,127.47)
  IN2 w0.124: v2(157.71,62.06) 157.71,62.06 157.97,62.06 v2(159.41,60.63) 159.74,60.3 165.46,60.3 165.98,60.81 169.16,60.81 172.27,57.71 176.23,57.71 177.36,58.84 179.09,58.84 180.24,57.69 181.77,57.69 182.25,58.18 v2(182.9,58.18) ; v2(242.89,73.24) 242.28,73.85 241.61,73.85 240.3,72.54 240.3,71.09 239.16,69.96 235.45,69.96 232.8,67.31 232.19,67.31 231.6,67.9 227.5,67.9 226.15,66.55 206.89,66.55 205.56,67.88 185.72,67.88 183.99,69.61 180.38,69.61 176.3,73.69 172.41,73.69 v2(172.11,73.98) 171.61,73.98 171.32,74.27 171.32,78.71 170.04,79.99 170.04,82.72 167.58,85.19 167.58,87.66 164.9,90.34 164.9,104.92 164.02,105.79 164.02,106.99 161.25,109.75 161.25,115.76 158.79,118.21 158.79,120.87 154.12,125.54 147.78,125.54 146.66,126.66 145.49,126.66 v2(144.68,127.47) ; v2(243.01,107.9) 245.63,105.28 258.17,105.28 261.03,102.41 261.03,101.18 261.43,100.79 261.43,99.9 v2(261.24,99.71)
  IN3 w0.135: v2(172.11,73.98) 172.11,70.86 v2(170.66,69.4)
  BOTTOM w0.112: v2(274.34,93.23) 277.26,93.23 279.91,90.58 v2(279.91,90.54) ; v2(238.91,84.53) 238.53,84.53 238.21,84.21 QE2.2 ; RZ320.1 124.16,128.11 124.53,128.11 125.02,128.6 v2(125.05,128.6) 125.05,130 124.93,130.12 UZ35.2 ; v2(261.24,99.71) 261.64,99.3 262.57,99.3 v2(264.21,97.66)
RUN_ON#: length 3.4
  TOP w0.112: v2(238.66,85.1) 238.89,85.33 RE68.1 239.32,84.89 v1(239.76,84.44)
  BOTTOM w0.112: QE2.6 238.86,85.31 v2(238.66,85.1) 238.21,85.55 QE2.5
RUN_ON_EC: length 32.5
  TOP w0.112: v2(256.94,100.35) 256.94,100.79 257.2,101.04 258.02,101.04 258.34,100.72 258.34,99.96 258.65,99.66 259.98,99.66 260.18,99.45 RPE10.4 260.18,98.12 260.63,97.67 261.66,97.67 RE292.2 ; UE5.2 262.29,98.31 RE292.2 ; UE1.E8 v2(249.48,89.86) ; RE292.2 262.16,97.83 263.65,96.34 v1(264.67,96.34)
  BOTTOM w0.112: v2(256.94,100.35) 256.94,100.36 256.9,100.36 256.88,100.34 256.56,100.34 256.21,100.7 251.53,100.7 250.4,99.56 250.4,95.84 250.68,95.55 250.68,89.61 250.47,89.39 249.95,89.39 v2(249.48,89.86)
RUNPWROK: length 271.2
  TOP w0.112: UE1.G3 v2(251.08,85.06) ; v2(86.8,128.85) 86.8,127.86 v1(84.99,126.05) 84.54,125.6 81.72,125.6 79.45,123.32 79.45,120.33 79.8,119.98 81.03,119.98 v2(81.5,120.45) 82.74,121.69 v2(83.4,121.69) 83.4,122.93 v2(83.02,123.31)
  IN1 w0.119: v2(242.1,73.25) 242.1,73.75 240.48,75.36 240.48,80.79 239.55,81.73 239.55,82.24 v2(239.04,82.75)
  IN2 w0.124: v2(242.1,73.25) 241.4,73.25 240.54,72.39 240.54,71 239.27,69.73 235.54,69.73 232.89,67.08 232.1,67.08 231.51,67.67 227.76,67.67 226.41,66.32 206.76,66.32 205.46,67.63 185.66,67.63 183.89,69.39 180.25,69.39 176.17,73.47 171.73,73.47 171.1,74.1 171.1,78.61 169.82,79.89 169.82,82.63 167.35,85.09 167.35,87.57 164.67,90.25 164.67,104.82 163.79,105.7 163.79,106.89 161.03,109.66 161.03,115.66 158.57,118.12 158.57,120.69 158.37,120.89 158.37,120.91 153.96,125.31 147.67,125.31 146.61,126.38 144.8,126.38 143.4,127.78 140.78,127.78 140.23,128.33 138.69,128.33 138.39,128.03 131.69,128.03 131.13,128.59 125.6,128.59 125.21,128.21 124.11,128.21 122.9,129.42 118.41,129.42 118.14,129.15 108.92,129.15 108.42,128.65 104.43,128.65 103.68,129.4 87.34,129.4 v2(86.8,128.85) ; v2(239.04,82.75) 239.04,84.02 240.4,85.38 243.08,85.38 243.79,84.67 246.34,84.67 246.99,84.01 248.69,84.01 249.32,84.65 249.65,84.65 249.88,84.88 249.88,85.25 250.09,85.46 250.68,85.46 v2(251.08,85.06)
  BOTTOM w0.112: v2(239.04,82.75) 238.48,82.75 237.56,83.67 QE2.3 236.14,83.83 RE67.1 ; UC8.1 83.21,122.3 83.4,122.12 v2(83.4,121.69) ; UC8.10 80.8,125.3 81.51,126 83.18,126 85.49,123.7 85.49,123.14 85.17,122.82 84.67,122.82 84.25,123.24 83.09,123.24 v2(83.02,123.31) 82.41,123.31 82.3,123.41 UC8.13 ; UC8.4 81.3,120.65 v2(81.5,120.45)
SA_LGATE: length 7.4
  TOP w0.112: v2(68.67,116.47) v1(68.67,117.04)
  IN3 w0.508: v2(68.67,116.47) 65.84,116.47 64.9,115.53 v2(62.2,115.53)
SA_SNUB: length 1.6
  TOP w0.112: PR627.2 v1(66.13,112.9)
SA_SW: length 7.8
  IN3 w0.508: v2(63.27,113.37) 63.4,113.24 67.26,113.24 68.81,114.79 v2(68.81,115.68)
  BOTTOM w0.102: 62.01,113.27 v1(62.01,112.55)
SA_UGATE: length 10
  IN3 w0.508: v2(68.22,112.94) 67.87,112.58 61.89,112.58 61.02,113.45 v2(59.28,113.45)
  BOTTOM w0.102: v2(68.22,112.94) v1(68.22,112.34)
SATA_LED_EN: length 18.8
  TOP w0.112: v1(274.29,82.81) 274.29,83.55 273.95,83.89 v2(273.77,83.89) QZ2.5 ; v2(267.87,95.58) 267.75,95.46 UE2.14
  IN1 w0.119: v2(273.77,83.89) 273.14,84.53 273.14,92.85 271.38,94.6 268.84,94.6 v2(267.87,95.58)
SATA_PRX_DTX_N1: length 193.1
  IN1 w0.119: v2(120.23,109.57) 120.19,109.57 119.44,108.82 118.1,108.82 117.66,109.27 117.66,111.18 120.98,114.5 120.98,115.51 122.39,116.92 125.27,116.92 125.51,116.67 126.95,116.67 127.46,116.17 128.88,116.17 129.73,117.02 138.06,117.02 139.79,118.75 144.31,118.75 145.21,117.85 150.86,117.85 151.79,116.92 153.18,116.92 157.17,112.93 158.54,112.93 161.24,110.23 161.24,109.92 163.02,108.14 163.02,106.41 165.63,103.8 165.63,99.75 arc(168.17,86.98) 175.4,76.16 176.13,75.43 arc(185.26,69.33) 196.03,67.19 222.59,67.19 223,66.78 226.17,66.78 229.03,69.64 229.03,71.05 229.44,71.46 229.44,75.85 233.63,80.04 233.63,93.42 234.41,94.2 234.41,95.57 236.12,97.28 236.12,100.18 234.81,101.49 234.56,101.49 v2(234.19,101.12)
  BOTTOM w0.076: v2(120.23,109.57) 120.24,109.58 120.25,109.58 120.28,109.6 120.43,109.6 120.61,109.42 UC1.G21
  BOTTOM w0.104: v2(234.19,101.12) 233.95,101.36 231.2,101.36 231.09,101.25 JNGFF2.35
SATA_PRX_DTX_P1: length 193.3
  IN1 w0.119: v2(234.16,101.71) 234.9,101.71 236.34,100.27 236.34,97.19 234.63,95.48 234.63,94.11 233.85,93.33 233.85,79.95 229.66,75.76 229.66,71.36 229.25,70.96 229.25,69.55 226.26,66.56 222.91,66.56 222.5,66.97 196.03,66.97 arc(185.18,69.13) 175.98,75.28 175.25,76.01 arc(167.97,86.9) 165.41,99.75 165.41,103.7 162.8,106.32 162.8,108.05 161.02,109.83 161.02,110.14 158.45,112.71 157.08,112.71 153.09,116.7 151.7,116.7 150.77,117.63 145.12,117.63 144.22,118.54 139.88,118.54 138.15,116.8 129.82,116.8 128.97,115.95 127.36,115.95 126.86,116.45 125.42,116.45 125.18,116.7 122.48,116.7 121.2,115.42 121.2,114.41 117.88,111.09 117.88,109.36 118.19,109.04 119.35,109.04 119.84,109.53 119.84,109.91 v2(120.17,110.25)
  BOTTOM w0.076: v2(120.17,110.25) 120.17,110.19 120.42,109.94 UC1.F21
  BOTTOM w0.104: JNGFF2.33 231.09,101.75 231.28,101.56 234.01,101.56 v2(234.16,101.71)
SATA_PTX_C_DRX_N1: length 3.8
  TOP w0.104: v2(232.12,100.34) 232.33,100.12 232.57,100.12 232.84,99.86 232.84,99.48 232.97,99.34 CZ10.2
  BOTTOM w0.104: JNGFF2.39 231.05,100.25 231.18,100.12 231.9,100.12 v2(232.12,100.34)
SATA_PTX_C_DRX_P1: length 3.7
  TOP w0.104: v2(232.12,99.71) 232.33,99.92 232.49,99.92 232.64,99.78 232.64,99.39 232.81,99.22 232.81,98.78 CZ11.2
  BOTTOM w0.104: v2(232.12,99.71) 231.9,99.92 231.18,99.92 231.01,99.75 JNGFF2.41
SATA_PTX_DRX_N1: length 180.6
  TOP w0.104: CZ10.1 234.05,98.47 234.62,97.9 v2(234.82,97.9)
  IN1 w0.119: v2(234.82,97.9) 235.27,97.45 235.27,97.05 233.98,95.77 233.98,94.38 233.02,93.41 233.02,80.48 232.31,79.78 231.82,79.78 228.86,76.82 228.86,75.09 228.61,74.83 228.61,69.82 226.4,67.61 196.08,67.61 arc(185.45,69.73) 176.44,75.74 175.71,76.47 arc(168.58,87.15) 166.07,99.75 166.07,105.69 161.68,110.08 161.68,112.32 159.72,114.28 158.42,114.28 155.27,117.43 152.14,117.43 151.29,118.29 145.42,118.29 144.53,119.18 139.6,119.18 137.86,117.45 127.33,117.45 127.05,117.72 124.23,117.72 123.85,117.35 121.96,117.35 120.55,115.94 120.55,114.82 120.29,114.56 119.73,114.56 v2(119.68,114.51)
  BOTTOM w0.076: UC1.D21 120.04,111.96 120.04,112.07 120.02,112.13 119.9,112.55 119.9,112.8 119.93,112.89 119.93,113.08 119.9,113.18 119.9,113.59 120.06,113.76 120.06,114.6 120,114.67 119.84,114.67 v2(119.68,114.51)
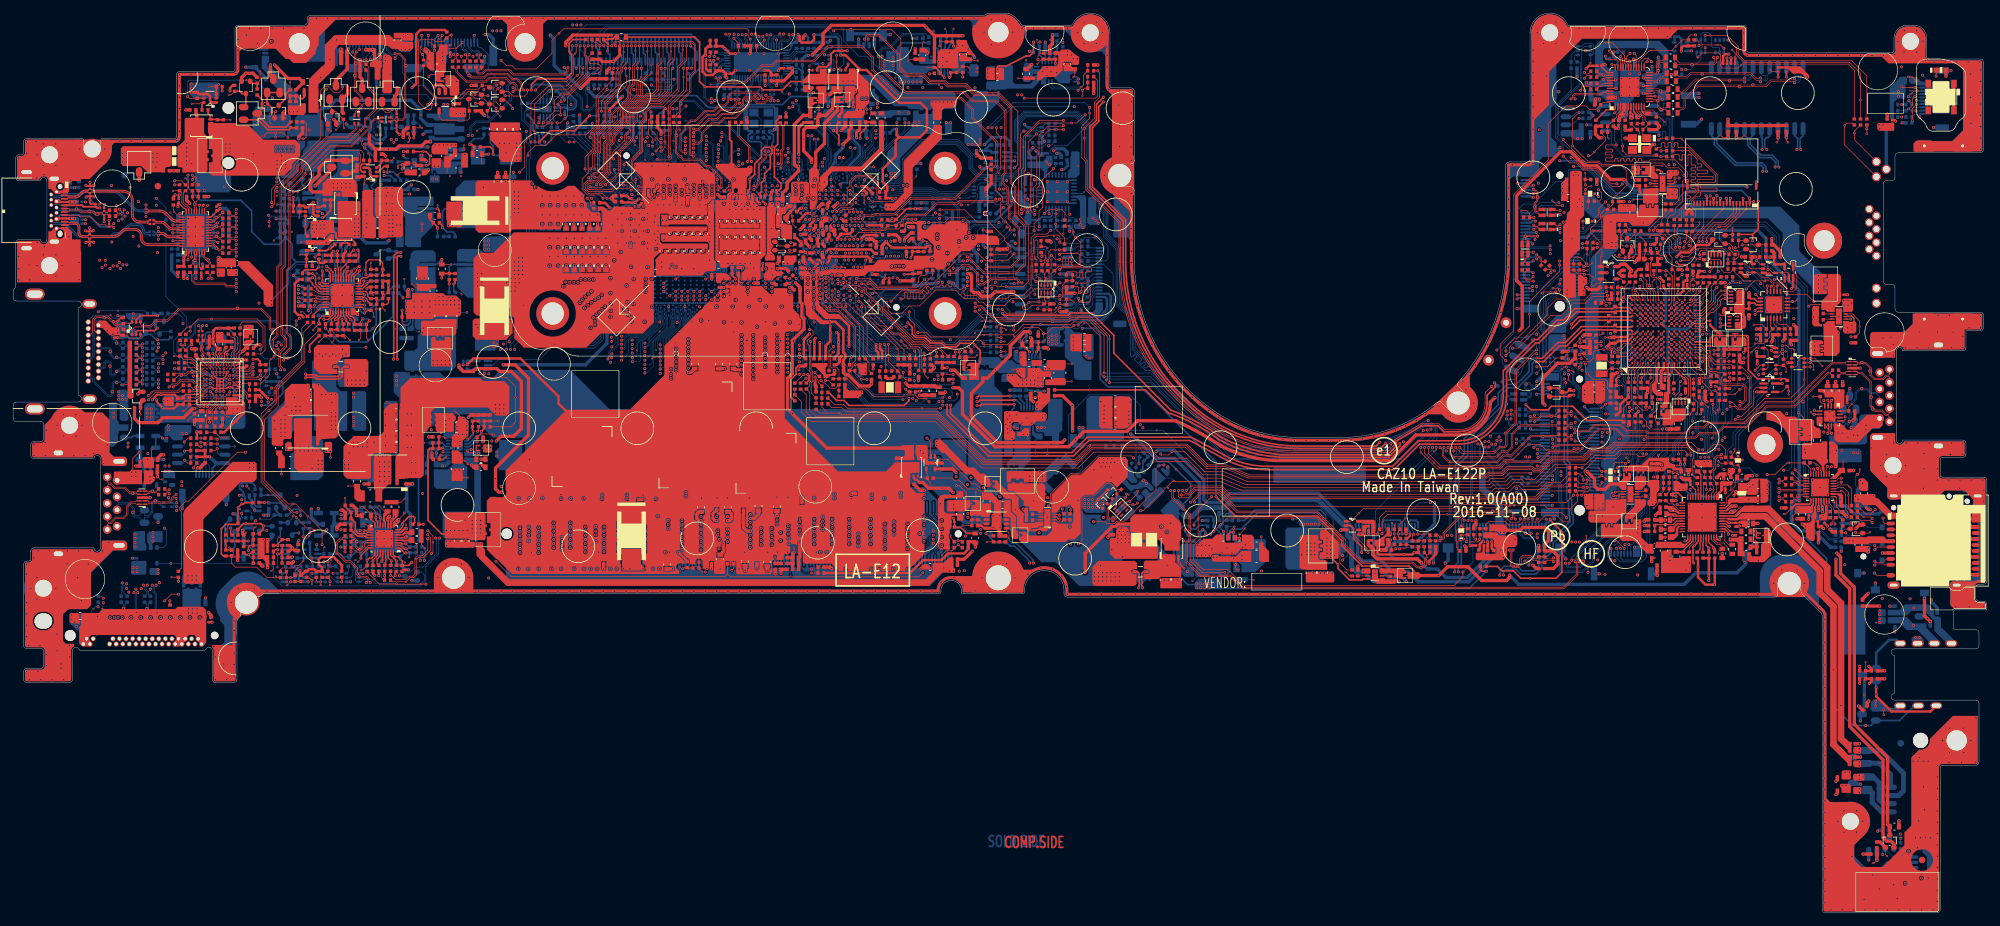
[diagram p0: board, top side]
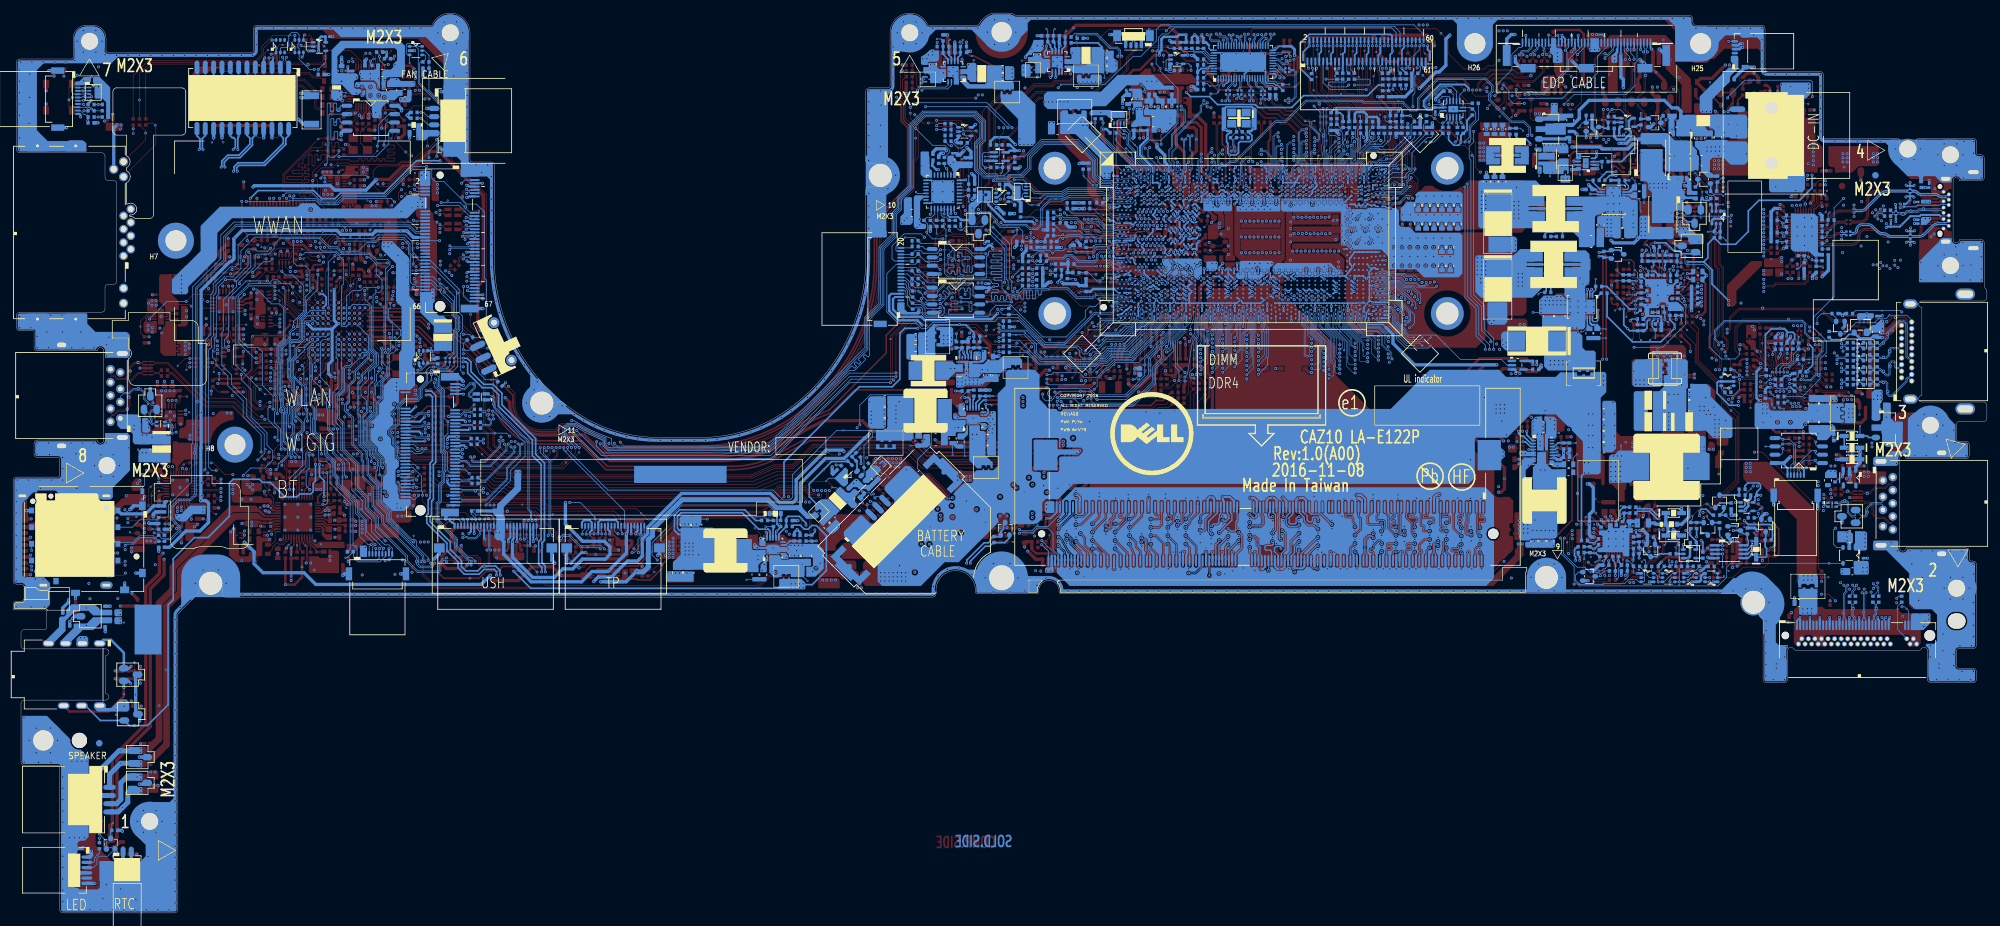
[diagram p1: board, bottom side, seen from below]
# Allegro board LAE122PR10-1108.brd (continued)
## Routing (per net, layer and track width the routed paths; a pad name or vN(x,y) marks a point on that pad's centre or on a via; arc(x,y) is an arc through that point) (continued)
SATA_PTX_DRX_P1: length 180.7
  TOP w0.104: v2(234.28,97.64) 234.28,97.96 234.15,98.09 CZ11.1
  IN1 w0.119: v2(234.28,97.64) 234.5,97.64 234.65,97.49 234.93,97.49 235.05,97.36 235.05,97.15 233.77,95.86 233.77,94.47 232.8,93.5 232.8,80.57 232.22,80 231.73,80 228.65,76.91 228.65,75.18 228.39,74.93 228.39,69.91 226.31,67.83 196.08,67.83 arc(185.53,69.93) 176.6,75.9 175.87,76.63 arc(168.78,87.24) 166.29,99.75 166.29,105.78 161.9,110.17 161.9,112.41 159.81,114.5 158.51,114.5 155.36,117.65 152.23,117.65 151.38,118.51 145.51,118.51 144.62,119.4 139.51,119.4 137.77,117.66 127.42,117.66 127.14,117.94 124.14,117.94 123.76,117.56 121.87,117.56 120.33,116.03 120.33,114.91 120.2,114.78 120,114.78 119.69,115.1 v2(119.68,115.1)
  BOTTOM w0.076: UC1.C21 120.33,112.01 120.44,112.01 120.51,112.08 120.51,112.26 120.44,112.33 120.18,112.33 120.13,112.38 120.06,112.58 120.06,112.75 120.1,112.86 120.1,113.14 120.09,113.15 120.07,113.21 120.07,113.52 120.24,113.69 120.24,114.67 120.07,114.84 119.84,114.84 119.68,115 v2(119.68,115.1)
SATALED#: length 440.4
  TOP w0.112: v2(40.18,110.63) 39.8,110.25 39.8,108.09 v2(39.39,107.68) ; v2(241.53,110.27) 241.98,109.82 241.98,108.88 241.64,108.53 RN101.2 ; v2(273.78,83.24) QZ2.4 v1(272.88,81.33) 272.88,80.57 270.78,78.47 266.85,78.47 263.64,75.26 v2(262.37,75.26) ; v2(35.39,70.24) 34.19,70.24 26.72,62.77 26.34,62.77 25.36,61.8 25.36,61.48 25.63,61.21 25.63,52.55 RN100.2
  IN2 w0.124: v2(39.39,107.68) 39.39,107.12 39.67,106.84 39.67,103.2 38.63,102.16 38.63,80.96 36.78,79.11 36.78,72.91 35.39,71.52 v2(35.39,70.24) ; v2(241.53,110.27) 242.8,110.27 243.76,109.31 246.61,109.31 249.73,106.18 260.55,106.18 267.1,99.63 268.26,99.63 272.67,95.22 272.67,84.36 v2(273.78,83.24) ; v2(151.36,111.67) 151.52,111.51 151.52,109.13 149.81,107.42 149.81,101.53 154.25,97.09 154.25,92.92 156.16,91.02 162.84,91.02 166.62,87.24 166.62,84.79 169.06,82.35 169.06,79.62 170.37,78.31 170.37,73.8 171.43,72.74 175.87,72.74 179.94,68.66 183.59,68.66 185.36,66.89 204.72,66.89 206.07,65.54 226.8,65.54 228,66.74 230.27,66.74 230.76,66.25 233.2,66.25 235.71,68.77 239.68,68.77 242.13,71.22 242.84,71.22 244.33,72.71 249.38,72.71 249.58,72.91 252.61,72.91 253.57,73.86 257.54,73.86 257.8,73.61 259.9,73.61 260.83,74.53 261.63,74.53 v2(262.37,75.26) ; v2(40.18,110.63) 40.51,110.63 45.17,115.29 45.17,118.26 44.19,119.24 42.34,119.24 40.71,120.86 40.71,122.6 42.1,123.99 53.29,123.99 55.92,121.36 59.35,121.36 62.85,124.86 68.55,124.86 68.9,125.21 70.84,125.21 70.99,125.06 72.44,125.06 74.23,123.26 79.92,123.26 81.86,125.21 84.86,125.21 85.65,124.42 90.37,124.42 91.24,125.28 93.6,125.28 94.03,124.85 97.41,124.85 98.09,125.53 104.74,125.53 105.18,125.97 113.85,125.97 114.41,126.53 120.34,126.53 120.69,126.88 121.9,126.88 122.63,126.15 132.04,126.15 133.94,124.25 133.94,121.34 133.5,120.91 133.5,113.55 132.57,112.62 132.57,111.71 v2(134.01,110.27)
  BOTTOM w0.076: 133.84,110.27 132.78,109.21 132.15,109.21 UC1.H1
  BOTTOM w0.112: v2(151.36,111.67) 151.25,111.57 148.66,111.57 148.4,111.3 147.31,111.3 146.97,110.96 146.97,110.46 146.75,110.24 RPC4.3 145.63,110.24 145.1,109.71 140.92,109.71 140.04,110.27 v2(134.01,110.27) 133.84,110.27
SBIOS_TX: length 230.4
  TOP w0.112: v2(146.56,92.97) 146.91,92.62 147.56,92.62 149.36,90.82 160.86,90.82 161.09,91.04 164,91.04 167.03,88.01 v1(167.03,87.5) 167.03,80.87 v2(167.02,80.86) ; v2(228.42,86.12) 229.28,86.12 234.28,91.11 235.86,91.11 237.73,92.97 239.6,92.97 240.63,94.01 242.72,94.01 v2(242.89,94.17)
  IN1 w0.097: v2(146.56,92.97) 146.56,93.08 143.87,95.76 142.42,95.76 141.97,96.21 141.97,96.32 141.6,96.68 140.69,96.68 136.67,100.7 135.13,100.7 134.54,101.28 133.17,101.28 v2(133.07,101.38)
  IN1 w0.119: v2(242.89,94.17) 243.97,95.25 243.97,97.57 245.2,98.8 245.2,104.96 246.96,106.73 246.96,109.64 246.17,110.43 246.17,113.42 246.89,114.13 248.97,114.13 250.07,115.24 250.07,116.53 251.22,117.68 251.22,122.94 258.21,129.93 287.79,129.93 289.47,128.26 291.08,128.26 292.63,126.71 292.63,123.71 291.23,122.31 v2(289.9,122.31) ; v2(216.01,73.78) 221.88,73.78 223.75,75.65 223.75,81.14 226.27,83.67 226.27,85.16 227.23,86.12 v2(228.42,86.12)
  BOTTOM w0.076: v2(133.07,101.38) 132.83,101.38 132.2,101.62 UC1.AB2
  BOTTOM w0.112: v2(167.02,80.86) 173.24,80.86 185.01,69.09 211.47,69.09 215.87,73.49 215.87,73.64 v2(216.01,73.78) ; RE306.1 v2(289.9,122.31)
SD/MMCCD#: length 27.1
  TOP w0.112: v2(283.59,51.81) 283.93,51.47 JSD1.9 ; UR1.30 274.67,67.34 v2(274.31,67.69)
  IN1 w0.119: v2(283.59,51.81) 285.72,53.95 285.72,56.4 285.28,56.84 283.13,56.84 280.97,59 279.68,59 274.88,63.8 274.88,67.18 274.37,67.69 v2(274.31,67.69)
SD/MMCCLK: length 4.4
  TOP w0.112: UR1.17 277.66,63.47 277.82,63.31 277.82,61.89 278.18,61.53 278.18,60.46 RR5.1
SD/MMCCLK_R: length 23.5
  TOP w0.112: v2(283.63,55.38) 284.02,55.77 JSD1.5 ; RR5.2 278.53,58.79 CR21.1 278.69,57.95 v2(279.2,57.95)
  IN1 w0.119: v2(279.2,57.95) 279.76,57.95 279.88,57.83 279.88,57.24 280,57.12 280.22,57.12 280.34,57.24 280.34,57.47 280.48,57.61 280.83,57.61 280.95,57.49 280.95,57.15 281.07,57.03 281.25,57.03 281.37,56.91 281.37,55.29 281.49,55.17 281.76,55.17 281.87,55.29 281.87,56.94 281.99,57.06 282.31,57.06 282.45,56.92 282.45,56.48 282.59,56.34 283.03,56.34 283.17,56.2 283.17,54.18 283.3,54.05 283.61,54.05 283.73,54.17 283.73,54.89 283.86,55.01 284.17,55.01 284.3,54.89 284.3,54.13 284.42,54.01 285.1,54.01 285.22,54.13 285.22,55.98 284.97,56.22 284.47,56.22 v2(283.63,55.38)
SD/MMCCMD: length 5.9
  TOP w0.112: RR6.1 279.53,60.86 279.53,61.12 279.17,61.48 279.17,63.84 278.68,64.33 v1(278.47,64.33) 278.41,64.27 UR1.19
SD/MMCCMD_R: length 27.2
  TOP w0.112: v2(291.23,58.05) 290.76,57.57 JSD1.3 ; RR6.2 281.43,59.87 282.87,59.87 v2(283.22,59.52)
  IN1 w0.119: v2(291.23,58.05) 290.54,58.05 290.33,58.25 290.33,60.76 290.21,60.88 289.97,60.88 289.86,60.76 289.86,58.18 289.74,58.06 289.5,58.06 289.38,58.18 289.38,60.79 289.26,60.91 289.02,60.91 288.9,60.79 288.9,58.26 288.76,58.11 288.44,58.11 287.23,59.32 284.31,59.32 284.12,59.52 v2(283.22,59.52)
SD/MMCDAT0/RCLK+: length 2.1
  TOP w0.089: UR1.16 276.67,62.43 277.33,61.77 277.33,61.56 RR10.1
SD/MMCDAT0/RCLK+_R: length 30.4
  TOP w0.089: v2(283.63,53.62) 283.79,53.45 284.87,53.45 285.39,53.97 JSD1.7 ; v2(277.56,59.3) 277.39,59.47 277.39,59.94 RR10.2
  IN1 w0.089: v2(277.56,59.3) 277.32,59.06 277.32,58.8 277.47,58.64 278.53,58.64 278.71,58.46 278.71,58 278.51,57.79 276.59,57.79 276.48,57.69 276.48,57.41 276.59,57.29 279.01,57.29 279.22,57.08 279.22,56.63 279.02,56.42 276.31,56.42 276.2,56.31 276.2,55.99 276.35,55.84 279.04,55.84 279.25,55.64 279.25,53.82 279.33,53.73 279.77,53.73 279.86,53.82 279.86,55.98 280.07,56.2 280.62,56.2 280.83,55.99 280.83,53.54 281.05,53.32 283.34,53.32 v2(283.63,53.62)
SD/MMCDAT1/RCLK-: length 2.1
  TOP w0.089: UR1.15 276.27,62.47 277.07,61.67 277.07,61.43 RR9.1
SD/MMCDAT1/RCLK-_R: length 30.4
  TOP w0.089: v2(283.63,53.03) 283.79,53.2 284.96,53.2 285.08,53.07 JSD1.8 ; v2(276.97,59.3) 277.14,59.47 277.14,59.94 RR9.2
  IN1 w0.089: v2(276.97,59.3) 277.11,59.16 277.11,58.71 277.38,58.44 278.44,58.44 278.51,58.38 278.51,58.08 278.42,58 276.5,58 276.27,57.77 276.27,57.32 276.51,57.09 278.93,57.09 279.01,57 279.01,56.71 278.93,56.63 276.23,56.63 275.99,56.4 275.99,55.91 276.27,55.63 278.96,55.63 279.04,55.55 279.04,53.73 279.25,53.53 279.86,53.53 280.07,53.74 280.07,55.9 280.16,55.99 280.54,55.99 280.62,55.9 280.62,53.46 280.96,53.12 283.54,53.12 v2(283.63,53.03)
SD/MMCDAT2: length 5.6
  TOP w0.112: RR8.1 280.05,64.69 v1(279.75,64.98) 279.47,65.26 277.98,65.26 277.78,65.07 UR1.21
SD/MMCDAT2_R: length 23.1
  TOP w0.112: v2(283.68,61.48) v1(283.32,61.12) 283.01,60.81 282.27,60.81 RR8.2 ; v2(284.88,60.21) 284.88,59.64 285.15,59.37 JSD1.1
  IN1 w0.119: v2(284.88,60.21) 285.14,60.21 285.27,60.34 285.27,64.74 285.14,64.87 284.81,64.87 284.69,64.75 284.69,60.91 284.57,60.78 284.31,60.78 284.19,60.91 284.19,64.72 284.06,64.84 283.76,64.84 283.61,64.7 283.61,61.54 v2(283.68,61.48)
SD/MMCDAT3: length 5.7
  TOP w0.112: UR1.20 277.79,64.67 277.95,64.83 278.88,64.83 279.6,64.11 v1(279.6,63.64) 279.6,61.67 RR7.1
SD/MMCDAT3_R: length 28
  TOP w0.112: JSD1.2 290.03,58.47 290.24,58.68 v2(291.23,58.68) ; RR7.2 281.81,60.37 v1(281.93,60.37) 282.98,60.37 v2(283.22,60.13)
  IN1 w0.119: v2(291.23,58.68) 291.23,62.18 291.04,62.37 287.42,62.37 287.3,62.25 287.3,61.98 287.42,61.86 289.21,61.86 289.36,61.72 289.36,61.48 289.24,61.36 287.42,61.36 287.3,61.24 287.3,60.91 287.45,60.76 288.26,60.76 288.38,60.64 288.38,59.89 288.25,59.76 284.5,59.76 284.14,60.13 v2(283.22,60.13)
SD_GPIO: length 2.9
  TOP w0.112: UR1.28 275.47,67.34 275.31,67.5 275.31,67.92 274.86,68.36 v1(274.71,68.36) 274.46,68.62 RR3.2
SD_RCOMP: length 3.4
  TOP w0.381: v2(129.3,102.71) 129.3,102.94 v1(129.73,103.36) 131.42,103.36 RC96.1
  BOTTOM w0.254: UC1.AB7 129.3,102.4 v2(129.3,102.71)
SD_UHS2_D0N: length 32.4
  TOP w0.089: JSD1.19 298.56,55.19 297.96,55.79 291.55,55.79 v2(291.39,55.63) ; UR1.25 276.67,67.71 v2(277.02,68.06)
  IN1 w0.089: v2(277.02,68.06) 276.82,68.27 276.82,68.45 276.97,68.6 277.79,68.6 282.34,64.05 282.34,59.35 283.58,58.11 286.56,58.11 288.86,55.81 291.2,55.81 v2(291.39,55.63)
SD_UHS2_D0P: length 32.5
  TOP w0.089: v2(276.43,68.06) 276.27,67.9 UR1.26 ; JSD1.18 298.1,56.1 298.04,56.04 291.55,56.04 v2(291.39,56.21)
  IN1 w0.089: v2(276.43,68.06) 276.61,68.24 276.61,68.53 276.89,68.81 277.87,68.81 282.55,64.13 282.55,59.43 283.66,58.32 286.65,58.32 288.95,56.02 291.2,56.02 v2(291.39,56.21)
SD_UHS2_D1N: length 32.5
  TOP w0.089: v2(297.89,52.87) 297.96,52.94 298.27,52.94 298.7,53.37 JSD1.21 ; v2(278.52,66.28) 278.18,66.28 277.77,65.87 UR1.23
  IN1 w0.089: v2(278.52,66.28) 278.64,66.17 279.37,66.17 281.73,63.81 281.73,59.11 283.35,57.49 285.95,57.49 290.15,53.3 291.88,53.3 291.97,53.38 291.97,53.78 292.18,53.99 292.62,53.99 292.83,53.78 292.83,53.38 292.91,53.3 293.18,53.3 293.27,53.38 293.27,53.78 293.48,53.99 293.92,53.99 294.13,53.78 294.13,53.38 294.21,53.3 294.82,53.3 295.32,52.79 297.81,52.79 v2(297.89,52.87)
SD_UHS2_D1P: length 32.4
  TOP w0.089: v2(278.52,65.68) 278.01,65.68 277.8,65.47 UR1.22 ; JSD1.22 298.07,52.46 v2(297.89,52.28)
  IN1 w0.089: v2(278.52,65.68) 278.8,65.96 279.29,65.96 281.52,63.73 281.52,59.03 283.26,57.29 285.86,57.29 290.06,53.09 291.97,53.09 292.18,53.3 292.18,53.69 292.26,53.78 292.53,53.78 292.62,53.69 292.62,53.3 292.83,53.09 293.27,53.09 293.48,53.3 293.48,53.69 293.56,53.78 293.83,53.78 293.92,53.69 293.92,53.3 294.13,53.09 294.74,53.09 295.24,52.59 297.59,52.59 v2(297.89,52.28)
SDWP: length 13.6
  TOP w0.112: v2(274.89,67.79) 275.07,67.61 UR1.29 ; QR1.1 280.68,59.36 v2(280.68,59.46)
  IN1 w0.119: v2(274.89,67.79) 275.66,67.02 275.66,63.62 278.49,60.79 279.59,60.79 280.68,59.71 v2(280.68,59.46)
SHD_CLK: length 19.3
  TOP w0.107: UE1.J8 v2(253.48,89.86)
  TOP w0.112: RE374.1 252.06,103.68 253.26,102.47 v2(253.26,101.48)
  IN1 w0.119: v2(253.26,101.48) 253.97,100.77 254.25,100.77 254.74,100.29 254.74,96.63 254.09,95.98 254.09,94.87 254.38,94.58 254.38,93.84 255.5,92.72 255.5,90.31 255.48,90.3 255.48,89.71 255.2,89.42 253.92,89.42 v2(253.48,89.86)
SHD_CLK_R1: length 38.4
  TOP w0.112: v2(244.21,117.09) 244.2,117.1 242.73,117.1 242.62,116.99 242.62,116.58 242.73,116.46 243.55,116.46 243.66,116.35 243.66,116.13 243.55,116.02 242.68,116.02 242.57,115.9 242.57,115.68 242.68,115.57 243.55,115.57 243.66,115.46 243.66,115.23 243.55,115.12 242.71,115.12 242.59,115.01 242.59,114.73 242.71,114.62 243.93,114.62 244.04,114.73 244.04,114.95 244.15,115.06 244.38,115.06 244.49,114.95 244.49,114.73 244.6,114.62 244.83,114.62 244.94,114.73 244.94,114.95 245.05,115.06 245.27,115.06 245.38,114.95 245.38,114.73 245.5,114.62 245.72,114.62 245.83,114.73 245.83,114.95 245.94,115.06 246.17,115.06 246.28,114.95 246.28,114.73 246.39,114.62 246.61,114.62 246.73,114.73 246.73,114.95 246.84,115.06 247.06,115.06 247.17,114.95 247.17,114.73 247.28,114.62 247.51,114.62 247.62,114.73 247.62,114.95 247.73,115.06 247.95,115.06 248.07,114.95 248.07,114.73 248.18,114.62 249.2,114.62 249.41,114.83 253.2,114.83 255.1,112.93 255.1,112.34 254.34,111.58 254.34,108.56 253.29,107.5 253.29,106.78 252.9,106.4 252.55,106.4 v1(252.06,105.9) RE374.2
  BOTTOM w0.112: UE9.6 243.67,120.53 243.95,120.26 243.95,117.8 244.21,117.54 v2(244.21,117.09)
SHD_CS#: length 60.8
  TOP w0.107: 257.19,86.66 255.88,86.66 UE1.M5
  TOP w0.112: RE98.1 262.01,85.2 v2(261.42,85.2) 261.42,84.9 261.1,84.58 260.11,84.58 259.76,84.24 RE364.1 259.37,84.11 258.53,84.95 v1(258.53,85.62) 258.39,85.76 258.09,85.76 257.19,86.66
  IN1 w0.119: v2(261.42,85.2) 260.96,85.65 260.96,86.25 261.61,86.89 261.61,88.44 262.36,89.2 262.36,97.89 263.87,99.39 263.87,102.06 257.4,108.52 257.4,110.36 253.69,114.08 v2(253.11,114.08)
  BOTTOM w0.112: v2(253.11,114.08) 252.84,114.34 252.84,123.36 252.73,123.47 252.45,123.47 252.33,123.36 252.33,122.28 252.22,122.17 251.99,122.17 251.88,122.28 251.88,123.37 251.77,123.48 251.51,123.48 251.39,123.37 251.39,122.3 251.28,122.18 251.01,122.18 250.9,122.3 250.9,122.96 250.79,123.07 UE9.1
SHD_IO0: length 75.3
  TOP w0.107: UE1.J7 v2(253.48,88.26)
  TOP w0.112: v2(236.14,115.38) 237.15,114.37 238.12,114.37 239.22,113.27 241.08,113.27 243.59,110.77 244.77,110.77 v2(245.16,111.16) ; v2(253.9,101.48) 253.58,101.8 253.58,102.73 253.07,103.24 RE366.1
  IN1 w0.119: v2(243.7,99.1) 243.7,99.24 242.71,100.23 242.71,103.43 244.27,104.99 244.27,110.27 v2(245.16,111.16) ; v2(253.48,88.26) 254.2,88.97 255.99,88.97 256.31,89.29 256.31,90.31 255.75,90.87 255.75,92.9 254.66,93.99 254.66,94.68 254.35,94.98 254.35,95.9 254.99,96.53 254.99,100.39 v2(253.9,101.48)
  BOTTOM w0.112: QE13.5 238.03,131.48 237.35,130.8 RE530.1 CE503.1 237.35,125.44 235.02,123.11 235.02,118.17 236.14,117.04 v2(236.14,115.38) ; v2(253.9,101.48) 253.9,101.2 253.6,100.91 251.45,100.91 250.94,100.41 246.43,100.41 245.12,99.1 v2(243.7,99.1)
SHD_IO0_R1: length 24.6
  TOP w0.112: RE366.2 253.82,106.48 253.82,107.2 254.83,108.21 254.83,109.84 255.02,110.02 256.17,110.02 256.28,110.13 256.28,110.36 256.17,110.47 255.74,110.47 255.62,110.58 255.62,110.8 255.74,110.92 256.22,110.92 256.34,111.03 256.34,111.25 256.22,111.36 255.74,111.36 255.62,111.47 255.62,111.7 255.74,111.81 256.22,111.81 256.34,111.92 256.34,112.14 256.22,112.26 255.74,112.26 255.62,112.37 255.62,112.59 255.74,112.7 256.22,112.7 256.34,112.82 256.34,113.04 256.22,113.15 255.74,113.15 255.62,113.26 255.62,113.49 255.74,113.6 256.22,113.6 256.34,113.71 256.34,113.93 256.22,114.04 255.76,114.04 255.65,114.16 255.65,115.52 255.54,115.63 255.27,115.63 255.16,115.52 255.16,114.01 255.05,113.9 254.82,113.9 254.71,114.01 254.71,115.52 254.6,115.63 254.38,115.63 254.27,115.52 254.27,114.91 v1(254.2,114.84) 254.15,114.79 253.93,114.79 253.82,114.91 253.82,115.49 253.68,115.63 253.06,115.63 252.83,115.4 RE367.1
SHD_IO0_R2: length 12.1
  TOP w0.112: RE367.2 v2(251.05,115.33)
  BOTTOM w0.112: UE9.5 243.35,119.26 243.46,119.15 243.46,117.26 245.39,115.33 v2(251.05,115.33)
SHD_IO1: length 20.9
  TOP w0.107: UE1.L6 v2(255.08,87.46)
  TOP w0.112: v2(253.97,102.12) 253.97,102.94 253.53,103.38 v1(253.53,103.86) 253.53,104.38 RE368.1
  IN1 w0.119: v2(253.97,102.12) 254.21,101.88 254.69,101.88 255.17,101.4 255.17,101.2 255.5,100.87 255.5,94.07 256.26,93.31 256.26,91.09 256.77,90.58 256.77,88.3 256.28,87.82 255.45,87.82 v2(255.08,87.46)
SHD_IO1_R1: length 24.7
  TOP w0.112: RE368.2 254.2,105.97 254.2,107.22 255.05,108.07 255.05,108.81 255.16,108.92 255.44,108.92 255.55,109.04 255.55,109.26 255.44,109.37 255.16,109.37 255.05,109.48 255.05,109.7 255.16,109.81 256.26,109.81 256.55,110.1 256.55,111.7 256.66,111.81 258.88,111.81 258.99,111.92 258.99,112.19 258.88,112.3 256.66,112.3 256.55,112.42 256.55,112.65 256.66,112.76 258.05,112.76 258.16,112.87 258.16,113.15 258.05,113.26 256.66,113.26 256.55,113.37 256.55,113.63 256.66,113.74 257.15,113.74 257.26,113.85 257.26,114.1 257.15,114.21 256.66,114.21 256.55,114.32 256.55,114.92 255.26,116.22 v1(254.33,116.22) RE369.1
SHD_IO1_R2: length 12.1
  TOP w0.112: RE369.2 v2(251.05,116.22)
  BOTTOM w0.112: UE9.2 252.48,121.8 252.59,121.69 252.59,115.4 252.41,115.23 251.79,115.23 251.05,115.96 v2(251.05,116.22)
SHD_IO2: length 32.3
  TOP w0.107: UE1.L7 v2(255.08,88.26)
  TOP w0.112: v2(254.53,101.48) 254.53,101.7 255.59,102.75 255.59,103.67 RE370.1 256.91,104.99 v1(256.91,105.29) ; RE360.1 261.75,81.42 v2(261.48,81.68)
  IN1 w0.119: v2(254.53,101.48) 255.24,100.77 255.24,96.38 254.61,95.74 254.61,95.11 255.01,94.71 255.01,94.07 256.01,93.08 256.01,90.97 256.54,90.43 256.54,89.2 255.99,88.66 255.48,88.66 v2(255.08,88.26)
  IN2 w0.124: v2(261.48,81.68) 259.01,81.68 255.52,85.18 255.52,87.82 v2(255.08,88.26)
SHD_IO2_R1: length 25.4
  TOP w0.112: RE370.2 RE376.1 256.3,106.16 256.3,107.11 255.67,107.73 255.67,108.5 256.4,109.23 256.89,109.23 257.07,109.42 257.07,109.92 257.18,110.03 259.49,110.03 259.6,110.14 259.6,110.41 259.49,110.53 257.15,110.53 257.03,110.64 257.03,110.91 257.15,111.02 259.47,111.02 259.59,111.15 259.59,112.6 v1(254.2,117.99) 254.07,118.12 RE371.1
SHD_IO2_R2: length 13
  TOP w0.112: RE371.2 250.98,118.12 v2(250.72,117.87)
  BOTTOM w0.112: v2(250.72,117.87) 251.13,117.87 251.25,117.98 251.25,119.04 251.36,119.15 251.68,119.15 251.79,119.04 251.79,117.98 251.9,117.87 252.18,117.87 252.3,117.98 252.3,121.01 252.18,121.12 251.95,121.12 251.84,121.01 251.84,120.19 251.73,120.08 251.51,120.08 251.39,120.19 251.39,121.01 251.28,121.12 251,121.12 250.89,121.01 250.89,120.65 250.78,120.53 UE9.3
SHD_IO3: length 19.6
  TOP w0.107: UE1.M6 v2(255.93,87.41)
  TOP w0.112: v2(254.65,102.38) 254.93,102.65 RE372.1
  IN1 w0.119: v2(255.93,87.41) 256.39,87.41 257,88.02 257,90.74 256.49,91.25 256.49,101.74 255.85,102.38 v2(254.65,102.38)
SHD_IO3_R1: length 25.7
  TOP w0.112: RE373.1 250.56,116.7 250.98,116.7 251.09,116.81 251.09,117.34 251.2,117.45 251.54,117.45 251.65,117.34 251.65,116.86 251.76,116.75 252.01,116.75 252.12,116.86 252.12,117.35 252.23,117.46 252.51,117.46 252.62,117.35 252.62,116.86 252.74,116.75 252.96,116.75 253.1,116.89 v1(253.1,117.17) 253.1,117.34 253.21,117.45 253.53,117.45 253.63,117.35 253.63,116.81 253.76,116.68 255.2,116.68 259.38,112.5 259.38,111.49 259.27,111.38 256.87,111.38 256.76,111.27 256.76,109.89 255.42,108.55 255.42,108.09 254.44,107.1 254.44,106.16 RE377.1 RE372.2
SHD_IO3_R2: length 12.6
  TOP w0.112: v2(245.21,116.93) v1(245.21,116.19) 245.85,115.55 249.85,115.55 249.87,115.57 RE373.2
  BOTTOM w0.112: v2(245.21,116.93) 245.21,117.28 245.01,117.49 245.01,120.23 243.43,121.8 UE9.7
SIM_DET: length 90.9
  TOP w0.112: v1(281.35,67.63) 281.35,67.25 v2(280.96,66.85)
  IN3 w0.135: v2(269.75,67.49) 270.97,68.71 280.44,68.71 280.96,68.19 v2(280.96,66.85)
  BOTTOM w0.112: JSIM1.2 281.02,64.87 280.71,65.19 280.71,66.6 v2(280.96,66.85) ; JNGFF2.58 239.21,95.5 239.53,95.82 239.81,95.82 240.18,96.18 240.18,100.23 240.46,100.52 240.46,101.89 241.27,102.7 244.95,102.7 245.43,102.22 246.78,102.22 248.11,100.9 250.65,100.9 251.33,101.59 252.45,101.59 253.9,103.03 263.9,103.03 266.01,100.93 266.01,98.23 267.23,97 268.52,97 269.8,95.71 269.8,94.47 270.16,94.11 270.16,88.02 270.47,87.72 270.47,86.27 270.93,85.81 270.93,67.97 270.44,67.49 v2(269.75,67.49)
SIO_EXT_SCI#: length 171.5
  TOP w0.112: v2(138.83,96.55) 137.61,95.32 131.53,95.32 130.52,96.34 128.62,96.34 v2(128.36,96.08) ; v1(259.43,76.17) 258.98,76.63 v2(258.98,77.53) 258.98,77.98 RE341.1
  IN2 w0.124: v2(138.83,96.55) 139.72,95.67 141.81,95.67 142.09,95.95 142.09,96.48 142.26,96.65 142.97,96.65 144.86,98.54 146.27,98.54 147.39,97.42 148.8,97.42 149.15,97.07 149.15,95.84 149.6,95.39 149.6,93.86 149.15,93.4 149.15,91.3 150.07,90.37 152.18,90.37 153.11,89.45 159.87,89.45 160.6,88.72 163.55,88.72 165.49,86.77 165.49,84.32 167.93,81.88 167.93,79.15 168.61,78.47 168.61,72.92 169.93,71.61 175.4,71.61 179.47,67.53 183.12,67.53 185.08,65.57 203.92,65.57 205.11,64.37 227.43,64.37 228.67,65.61 229.54,65.61 230.3,64.86 236.1,64.86 237.89,66.66 240.18,66.66 240.56,67.04 240.56,67.42 242.85,69.71 243.25,69.71 243.82,70.28 245.01,70.28 245.82,71.08 249.21,71.08 249.85,71.71 252.7,71.71 253.21,72.22 256.58,72.22 256.94,72.59 258.66,72.59 v2(258.85,72.4)
  BOTTOM w0.076: v2(128.36,96.08) 128.52,96.08 UC1.AN7
  BOTTOM w0.107: v2(138.83,96.55) 139.01,96.72 140.09,96.72 RC237.1
  BOTTOM w0.112: v2(258.85,72.4) 259.04,72.59 259.04,75.97 258.88,76.13 258.88,77.43 v2(258.98,77.53)
SIO_EXT_SCI#_EC: length 6.3
  TOP w0.112: UE1.M1 255.48,83.23 256.54,82.18 v1(256.58,82.18) 256.79,82.18 257.36,81.61 257.36,80.94 258.79,79.51 RE341.2
SIO_EXT_SMI#: length 194.8
  TOP w0.112: v2(261.58,77.86) 261.95,77.86 262.84,76.97 263.68,76.97 264.53,77.83 264.53,81.45 v4(264.37,81.61) 263.68,82.31 RE338.1
  IN2 w0.124: v2(261.58,77.86) 260.89,77.86 260.31,78.45 257.76,78.45 257.35,78.04 252.04,78.04 250.65,76.64 248.51,76.64 246.53,78.62 245.64,78.62 245.23,79.03 244.52,79.03 244.35,78.85 241.96,78.85 240.74,80.07 237.51,80.07 234.85,77.41 234.85,76.75 232.55,74.44 230.31,74.44 226.89,71.03 226.35,71.03 225.35,70.03 220.97,70.03 220.57,69.63 208.02,69.63 207.01,70.65 186.79,70.65 185.11,72.33 182.36,72.33 173.01,81.69 173.01,83.91 170.52,86.4 170.52,88.88 168.6,90.8 168.6,106.56 164.19,110.97 164.19,116.98 162.57,118.6 162.57,122.05 v2(161.68,122.93)
  IN3 w0.135: v2(135.88,120.47) 135.88,119.89 136.49,119.27 148.67,119.27 v2(149.12,119.72)
  BOTTOM w0.102: 131.88,115.4 131.8,115.4 129.57,113.17 UC1.A6 ; v2(135.88,120.47) 135.88,120.48 135.85,120.5 RC346.1
  BOTTOM w0.112: v2(161.68,122.93) 152.33,122.93 v2(149.12,119.72) ; 131.88,115.4 135.88,119.4 v2(135.88,120.47)
SIO_EXT_SMI#_EC: length 12.8
  TOP w0.107: UE1.K7 v2(254.28,88.26)
  TOP w0.112: v2(261.47,82.31) RE338.2
  IN2 w0.124: v2(261.47,82.31) 259.84,82.31 256.34,85.81 256.34,88.43 256.06,88.71 254.74,88.71 v2(254.28,88.26)
SIO_EXT_WAKE#: length 189.8
  TOP w0.107: UE1.M12 255.69,92.66 256.13,93.1 v2(257.05,93.1)
  IN2 w0.124: v2(142.32,100.6) 142.49,100.77 145.82,100.77 146.38,100.21 147.65,100.21 147.92,100.48 149.08,100.48 151.2,98.36 151.2,92.62 153.54,90.28 162.62,90.28 165.94,86.96 165.94,84.51 168.38,82.07 168.38,79.33 169.06,78.65 169.06,73.18 170.19,72.06 175.58,72.06 179.66,67.98 183.31,67.98 185.09,66.2 203.92,66.2 205.27,64.86 227.07,64.86 228.28,66.06 229.88,66.06 230.48,65.47 233.88,65.47 233.99,65.36 235.89,65.36 237.65,67.13 239.06,67.13 239.93,67.99 240.35,67.99 242.89,70.54 243.3,70.54 243.51,70.75 244.83,70.75 245.63,71.55 249.04,71.55 249.66,72.17 252.51,72.17 253.05,72.71 256.34,72.71 256.73,73.1 260.16,73.1 261.14,74.08 262.66,74.08 264.16,75.57 264.16,81.6 262.69,83.07 262.69,85.71 261.86,86.54 261.86,87.08 261.45,87.49 259.73,87.49 258.9,88.31 258.9,91.25 v2(257.05,93.1)
  BOTTOM w0.076: UC1.AC1 132.63,101.18 132.79,101.03 133.47,101.03 133.71,101.27
  BOTTOM w0.102: 135.74,101.47 135.58,101.63 134.07,101.63 v1(133.88,101.45) 133.88,101.44 133.71,101.27
  BOTTOM w0.112: 135.74,101.47 136.33,100.87 138.73,100.87 139.09,101.23 140.51,101.23 140.74,101 141.92,101 v2(142.32,100.6) 142.72,101 145.16,101 RC283.1
SIO_PWRBTN#: length 316.4
  TOP w0.112: UE1.K11 v2(254.28,92.26) ; v2(91.51,128.79) 91.35,128.63 CC269.1 RC241.1 91.35,127.05 v1(90.37,126.07) 88.82,124.52 88.82,120.15 87.3,118.63 82.7,118.63 81.09,117.02 79.54,117.02 78.44,115.93 v2(78.44,115.51)
  IN1 w0.119: v2(128.29,83.58) 122.22,77.5 87.35,77.5 78.45,86.4 75.62,86.4 v2(75.14,85.93)
  IN2 w0.124: v2(254.28,92.26) 254.06,92.26 253.66,92.66 253.28,92.66 253.09,92.85 253.09,93.51 253.21,93.64 254.18,93.64 254.61,94.07 258.27,94.07 260.1,92.24 261.56,92.24 262,91.8 262,89.36 264.07,87.29 264.07,82.72 264.86,81.93 264.86,74.98 260.27,70.39 260.14,70.39 259.82,70.08 259.82,69.36 258.21,67.75 252.3,67.75 251.86,67.32 251.86,66.81 251.08,66.03 247.55,66.03 246.01,64.49 246.01,63.17 243.68,60.84 243.68,59.89 242.35,58.55 236.63,58.55 236.34,58.26 228.81,58.26 227.72,57.17 226.32,57.17 225.29,58.21 220.86,58.21 219.85,59.23 214.74,59.23 213.69,60.27 203.34,60.27 202.17,61.44 173.79,61.44 170.42,64.81 162.19,64.81 158.79,68.22 150.15,68.22 149.66,68.72 149.17,68.72 146.18,71.72 146.18,72.26 144.02,74.42 144.02,77.53 142.98,78.57 v2(142.65,78.57)
  BOTTOM w0.076: 126.54,86.6 125.57,87.56 125.39,87.56 123.6,89.36 123.6,91.07 UC1.BA15
  BOTTOM w0.112: v2(142.65,78.57) 143.08,78.99 143.08,79.39 142.51,79.96 136.71,79.96 135.76,79 131.24,79 128.29,81.95 v2(128.29,83.58) 128.29,84.44 126.54,86.19 126.54,86.6 ; v2(75.14,85.93) 75.14,87.6 76.57,89.03 76.57,92.64 78.19,94.26 78.19,115.27 v2(78.44,115.51) ; JXDP1.41 v2(91.51,128.79)
SIO_RCIN#: length 181
  TOP w0.112: RC13.1 135.99,81.28 135.6,81.67 v2(135.6,82.43) ; RE339.1 v2(261.42,83.13)
  IN2 w0.124: v2(259.87,70.7) 259.08,69.91 256.23,69.91 255.9,70.24 254.63,70.24 254.42,70.03 254.42,69.75 254.23,69.56 251.1,69.56 249.6,68.06 248.11,68.06 245.11,65.05 245.11,63.59 242.78,61.25 242.78,60.26 241.97,59.46 236.25,59.46 235.96,59.17 227.43,59.17 225.76,60.84 219.47,60.84 218.76,60.13 215.11,60.13 214.07,61.17 203.72,61.17 202.54,62.35 181.02,62.35 180.24,63.13 178.97,63.13 178.43,62.6 173.92,62.6 170.8,65.72 162.74,65.72 159.33,69.12 150.72,69.12 150.16,69.68 149.86,69.68 147.47,72.07 147.47,79.84 143.02,84.29 136.66,84.29 135.6,83.22 v2(135.6,82.43)
  BOTTOM w0.076: UC1.AW13 125.09,92.54 124.92,92.36 124.92,92.36 124.7,91.66 124.7,91.58 124.65,91.42 124.65,91.28 124.71,91.06 124.71,90.94 124.67,90.85 124.66,90.83 124.66,90.45 124.79,90.32 124.79,89.78 127.07,87.49
  BOTTOM w0.112: v2(135.6,82.43) 134.55,83.48 133.92,83.48 132.98,84.42 130.3,84.42 127.23,87.49 127.07,87.49 ; v2(261.42,83.13) 260.94,82.66 260.94,78.95 260.69,78.7 260.69,76.55 260.88,76.36 260.88,74.73 259.99,73.84 259.99,70.82 v2(259.87,70.7)
SIO_RCIN#_EC: length 5.3
  TOP w0.112: UE1.N3 256.72,85.46 256.98,85.19 257.54,85.19 258.29,84.44 258.29,83.34 v1(258.7,82.93) 259.56,82.93 RE339.2
SIO_SLP_A#: length 225.5
  TOP w0.107: v2(259.56,95.36) 259.05,94.85 259.05,93.23 257.25,91.43 255.92,91.43 UE1.M11
  TOP w0.112: JAPS1.6 262.06,106.75 260.62,105.31 259.12,105.31 v4(257.49,103.68) 256.82,103.01 v2(256.82,102.37)
  IN1 w0.119: v2(256.82,102.37) 256.82,102.68 257.12,102.98 259.74,102.98 260.31,102.41 260.31,96.11 v2(259.56,95.36)
  IN2 w0.076: 125.69,92.24 124.33,93.6 123.53,93.6 123.26,93.86 123.26,95.02 123.33,95.09 123.33,95.48 122.98,95.83
  IN2 w0.124: 125.69,92.24 126.63,91.3 126.63,86.1 129.29,83.45 129.29,82.12 129.53,81.88 132.19,81.88 136.98,86.67 144.25,86.67 145.59,85.33 145.59,83.71 148.92,80.38 148.92,72.71 150.49,71.13 150.82,71.13 151.47,70.48 160.26,70.48 163.65,67.09 172.97,67.09 175.02,65.04 175.63,65.04 176.05,65.45 182.64,65.45 184.39,63.7 203.14,63.7 204.32,62.53 214.63,62.53 215.67,61.49 218.19,61.49 218.9,62.2 226.32,62.2 227.22,61.3 234.75,61.3 234.96,61.5 236.77,61.5 238.02,62.75 240.97,62.75 243.89,65.66 243.89,66.61 244.98,67.7 244.98,68.69 245.2,68.91 245.57,68.91 245.91,69.25 247.36,69.25 247.61,69 249.12,69 250.71,70.58 253.17,70.58 253.61,71.03 258.95,71.03 v2(259.28,70.7) ; v2(122.9,95.92) 122.98,95.83
  BOTTOM w0.102: UC1.AN16 123.35,96.35 v2(122.9,95.92)
  BOTTOM w0.112: v2(259.56,95.36) 259.28,95.08 259.28,87.42 260.28,86.42 260.28,84.01 260.39,83.89 260.39,79.11 260.12,78.84 260.12,78.4 259.94,78.21 259.94,77.17 259.82,77.05 259.9,77.05 260.12,76.83 260.12,76.51 259.9,76.28 259.73,76.28 259.73,76.27 259.75,76.25 259.75,71.78 259.73,71.76 259.73,71.14 v2(259.28,70.7)
SIO_SLP_LAN#: length 218.3
  TOP w0.107: UE1.H9 v2(252.68,90.66)
  TOP w0.112: UZ2.5 252.75,111.6 v2(253.2,112.05) ; v2(143.2,82.08) 142.26,82.08 142.17,82.17 RC344.1 141.57,81.74 141.62,81.68 RC68.1
  IN2 w0.124: v2(143.2,82.08) 143.64,81.65 143.64,79.69 143.33,79.39 143.33,78.93 144.78,77.48 144.78,74.34 146.86,72.25 146.86,71.92 149.58,69.2 149.92,69.2 150.44,68.67 159.07,68.67 162.48,65.27 170.61,65.27 173.98,61.9 202.36,61.9 203.53,60.72 213.88,60.72 214.92,59.68 220.03,59.68 221,58.71 236.15,58.71 236.44,59 242.16,59 243.23,60.07 243.23,61.05 245.56,63.38 245.56,64.8 247.72,66.97 249.2,66.97 251.31,69.07 257.33,69.07 v2(257.73,69.48)
  IN3 w0.135: v2(252.68,90.66) 253.08,91.05 253.08,93.03 251.04,95.07 251.04,95.9 250.4,96.53 250.4,97.1 250.66,97.36 250.66,98.18 252.12,99.64 252.12,106.12 253.85,107.86 253.85,111.39 v2(253.2,112.05)
  BOTTOM w0.076: 126.96,87.21 126.06,88.11 v1(125.84,88.11) 125.32,88.11 123.98,89.45 123.98,90.37 124.13,90.53 124.13,92 123.98,92.34 123.98,92.33 123.82,92.49 UC1.AW15
  BOTTOM w0.112: v2(252.68,90.66) 253.08,91.05 253.08,91.71 253.22,91.85 255.39,91.85 256.79,90.45 256.79,87.53 257.13,87.2 258.22,87.2 258.65,86.77 258.65,84.68 258.93,84.4 258.93,81.64 258.25,80.96 258.25,79.63 257.38,78.76 257.38,77.53 258.14,76.77 258.14,74.71 257.88,74.46 257.88,72.93 258.14,72.68 258.14,69.89 v2(257.73,69.48) ; v2(143.2,82.08) 142.53,82.08 142.24,82.37 138.26,82.37 137.56,81.67 135.58,81.67 134.15,83.1 133.91,83.1 132.83,84.19 130.12,84.19 127.1,87.21 126.96,87.21
SIO_SLP_S0#: length 294.6
  TOP w0.112: JAPS1.15 257.56,104.72 256.06,103.21 256.06,102.92 255.35,102.21 v2(255.35,101.77) ; PR426.1 v2(165.25,128.41) 165.5,128.15 165.5,124.33 164.76,123.58 164.76,121.17 v2(163.19,119.61) v4(163.19,118.13) 163.19,115.17 163.64,114.72 163.64,110.38 168.71,105.31 168.71,99.27 arc(170.03,90.66) 173.81,82.81 arc(175.04,81.21) 176.33,79.64 arc(180.35,75.78) 185.09,72.83 arc(190.13,71.05) 195.45,70.45 209.09,70.45 209.93,71.28 v2(209.93,71.59) ; PR425.1 139.71,128.03 v2(139.62,127.94)
  IN1 w0.119: 139.62,127.94 139.62,128.11 138.91,128.83 129.46,128.83 127.79,130.5 127.15,130.5 126.2,131.46 124.3,131.46 123.68,130.83 v2(123.62,130.83) ; 139.62,127.94 v2(139.62,127.94) ; 139.62,127.94 140.27,128.59 143.24,128.59 144.65,130 148.09,130 149.02,130.92 156.4,130.92 158.65,133.17 160.49,133.17 v2(165.25,128.41)
  IN2 w0.124: v2(255.35,101.77) 255.1,101.53 255.1,99.45 253.96,98.31 244.78,98.31 242.47,96 242.26,96 233.73,87.46 233.73,80.53 232.79,79.59 225.68,79.59 225.07,78.98 225.07,76.08 222.91,73.92 217.83,73.92 216.24,72.34 211.29,72.34 210.97,72.02 210.36,72.02 v2(209.93,71.59) ; v2(139.62,127.94) 139.79,127.77 139.79,125.17 138.87,124.25 138.87,122.66 139.86,121.67 139.86,119.08 137.63,116.86 137.63,112.87 138.61,111.89 138.61,111.09 142.07,107.63 142.07,103.49 140.49,101.9 140.49,101.08 138.96,99.55 138.96,98.25 137.82,97.1 137.82,95.77 136.49,94.44 133.63,94.44 133.22,94.85 130.06,94.85 129.77,95.14 129.05,95.14 128.59,94.68 128.05,94.68 127.83,94.46 127.22,94.46 127.12,94.56 126.19,94.56 v2(125.74,94.11)
  BOTTOM w0.112: UZ35.1 123.68,130.77 v2(123.62,130.83) ; RZ363.1 158,116.01 158,116.29 158.75,117.04 160.62,117.04 v2(163.19,119.61) 163.19,119.95 161.75,121.39 154.36,121.39 153.4,120.43 153.4,118.27 154.23,117.44 154.23,113.22 153.63,112.62 153.63,110.83 RZ112.1
  BOTTOM w0.254: UC1.AT11 125.75,94.11 v2(125.74,94.11)
SIO_SLP_S3#: length 224.1
  TOP w0.107: UE1.K9 v2(254.28,90.66)
  TOP w0.112: UE3.2 264.63,98.25 263.91,98.96 UE5.1 262.28,98.96 RE280.1 v2(262.16,99.73) 262.19,99.71 262.53,99.71 262.85,100.02 262.85,100.79 262.66,100.98 262.24,100.98 261.97,101.25 261.97,101.59 261.52,102.04 QE11.2 260.55,102.04 259.94,102.65 259.94,103.83 260.39,104.28 261.01,104.28 v1(262.47,105.74) 264.06,107.33 JAPS1.2
  IN2 w0.076: v2(123.81,95.34) 123.45,94.98 123.45,93.97 123.66,93.77 124.69,93.77 125.96,92.5
  IN2 w0.124: v2(258.06,93.36) 259.41,92.01 261.47,92.01 261.77,91.7 261.77,89.27 263.14,87.91 263.14,83.26 264.64,81.76 264.64,75.08 260.82,71.26 253.52,71.26 253.07,70.81 250.58,70.81 248.99,69.23 247.7,69.23 247.42,69.51 245.84,69.51 245.47,69.14 244.6,69.14 243.41,67.95 243.41,65.82 240.85,63.27 237.8,63.27 237.18,62.65 218.72,62.65 218.01,61.94 215.86,61.94 214.82,62.98 204.55,62.98 203.36,64.17 184.56,64.17 182.56,66.17 175.61,66.17 174.2,67.57 163.93,67.57 160.57,70.93 151.69,70.93 149.6,73.01 149.6,80.34 146.08,83.86 146.08,86.55 144.82,87.81 130.65,87.81 125.96,92.5
  IN3 w0.135: v2(254.28,90.66) 254.44,90.66 254.83,90.26 255.25,90.26 258.06,93.07 v2(258.06,93.36) 259.03,94.32 259.03,96.24 262.15,99.36 262.15,99.73 v2(262.16,99.73)
  BOTTOM w0.076: UC1.AP15 124.27,95.72 v2(123.81,95.34)
SIO_SLP_S4#: length 497.9
  TOP w0.107: UE1.N12 257.16,92.66 257.45,92.95 257.45,93.8 v2(258.15,94.5)
  TOP w0.112: v2(70.74,73.44) 70.9,73.61 PR208.1 ; v2(148.22,57.88) 148.22,57.85 148.58,57.49 PR513.1 ; JAPS1.5 262.56,106.79 260.78,105.01 259.38,105.01 257.4,103.03 v2(257.4,102.37) ; UZ21.4 125.93,128.49 125.45,128.96 v1(125.45,129.77) v2(125.45,130.79) ; v2(139.22,72.4) 139.79,71.84 UZ34.2 ; v2(50.19,125.93) 50.19,125.61 49.63,125.06 48.93,125.06 47.97,126.02 47.45,126.02 46.87,125.45 46.87,118.13 42.8,114.06 42.8,113.47 40.35,111.02 40.03,111.02 39.39,110.39 v2(39.39,108.32)
  IN1 w0.119: v2(258.15,94.5) 258.75,95.1 258.75,96.86 258.93,97.04 258.93,99.32 257.4,100.85 v2(257.4,102.37) ; v2(143.66,66.51) 143.64,66.51 142.72,67.43 87.06,67.43 80.63,73.86 71.16,73.86 v2(70.74,73.44) 70.51,73.67 70.51,76.85 69.6,77.75 57.7,77.75 57,77.05 44.5,77.05 42.57,78.98 40.02,78.98 v2(39.34,78.31)
  IN2 w0.124: v2(141.63,78.6) 141.81,78.6 142.26,78.14 143.05,78.14 143.74,77.46 143.74,74.38 145.82,72.3 145.82,71.64 148.97,68.49 149.43,68.49 149.92,67.99 158.69,67.99 162.09,64.59 170.33,64.59 173.7,61.22 202.07,61.22 203.25,60.04 213.6,60.04 214.64,59 219.75,59 220.77,57.98 225.19,57.98 226.67,56.5 231.37,56.5 231.52,56.65 235.04,56.65 236.72,58.33 242.44,58.33 243.91,59.79 243.91,60.71 248.99,65.8 251.2,65.8 252.09,66.69 252.09,67.17 252.45,67.52 258.34,67.52 259.67,68.85 260.41,68.85 260.73,69.16 260.73,70.52 265.09,74.88 265.09,82.02 264.29,82.81 264.29,87.39 262.23,89.46 262.23,91.89 261.65,92.46 260.23,92.46 258.19,94.5 v2(258.15,94.5) ; v2(50.19,125.93) 51.27,127.01 62.6,127.01 63.44,127.85 74.62,127.85 74.98,127.5 79.91,127.5 83.56,131.15 103.92,131.15 104.38,131.61 108.9,131.61 108.99,131.52 117.61,131.52 118.08,131.99 124.25,131.99 v2(125.45,130.79) ; v2(39.34,78.31) 39.34,78.83 38.89,79.28 38.89,93.69 40.38,95.18 40.38,105.42 40.49,105.52 40.49,107.22 v2(39.39,108.32) ; v2(148.22,57.88) 148.22,58.65 147.34,59.52 145.46,59.52 144.07,60.92 144.07,64.58 143.66,64.98 v2(143.66,66.51) 143.13,67.04 143.13,68.13 139.22,72.04 v2(139.22,72.4)
  IN3 w0.135: v2(139.22,72.4) 135.56,76.07 v2(135.56,78.27)
  BOTTOM w0.076: 125.18,87.13 125.18,87.28 123.27,89.19 123.27,91.63 UC1.BA16
  BOTTOM w0.112: 125.18,87.13 126.01,86.31 126.01,85.93 127.47,84.47 127.47,81.95 131.15,78.27 v2(135.56,78.27) 135.71,78.27 136.42,78.98 137.44,78.98 137.97,78.45 138.78,78.45 139.01,78.67 141.56,78.67 v2(141.63,78.6)
SIO_SLP_S5#: length 213.1
  TOP w0.107: v2(257.4,89.39) 257.34,89.46 UE1.N8
  TOP w0.112: JAPS1.4 263.06,106.81 260.87,104.62 v4(259.94,104.62) 259.65,104.62 258.01,102.98 v2(258.01,102.37)
  IN2 w0.124: v2(259.76,68.24) 258.79,67.27 255.07,67.27 254.51,66.71 252.45,66.71 251.3,65.56 249.09,65.56 244.14,60.62 244.14,59.71 242.53,58.1 236.81,58.1 235.14,56.42 231.61,56.42 231.44,56.25 226.57,56.25 225.09,57.73 220.7,57.73 219.66,58.78 214.55,58.78 213.51,59.82 203.15,59.82 201.98,60.99 173.61,60.99 170.24,64.36 161.99,64.36 158.58,67.77 149.77,67.77 149.27,68.26 148.84,68.26 145.54,71.56 145.54,72.26 143.51,74.29 143.51,77.35 142.98,77.89 141.98,77.89 141.86,78.01 v2(141.63,78.01)
  BOTTOM w0.076: UC1.AY16 123.24,92.12 122.94,91.82 122.94,91.39 123.11,91.23 123.11,89.1 124.93,87.28 124.93,87.07
  BOTTOM w0.112: v2(141.63,78.01) 141.18,78.46 139.1,78.46 138.37,77.73 130.37,77.73 127.15,80.94 127.15,83.2 125.75,84.59 125.75,86.18 124.93,87.01 124.93,87.07 ; v2(258.01,102.37) 258.01,99.22 257.44,98.65 256.16,98.65 255.48,97.97 255.48,94.64 256.2,93.92 256.2,91.64 257.4,90.44 v2(257.4,89.39) 257.98,88.82 258.1,88.82 258.43,88.48 258.43,87.66 259.85,86.24 259.85,83.83 259.96,83.71 259.96,79.29 259.7,79.02 259.7,78.58 259.51,78.39 259.51,77.35 259.1,76.94 259.1,76.26 259.29,76.07 259.29,71.93 258.65,71.28 258.65,69.77 259.76,68.66 v2(259.76,68.24)
SIO_SLP_SUS#: length 289.4
  TOP w0.112: RZ64.1 159.84,61.12 v2(159.84,61.61) ; v2(154.04,124.24) 164.92,124.24 165.17,124.5 165.17,126.97 PR406.1 ; UZ34.1 140.44,69.4 140.68,69.16 142.38,69.16 146.05,65.49 146.59,65.49 147.27,64.81 v2(147.85,64.81) ; v2(161.62,89.6) 161.31,89.29 v4(159.98,89.29) 158.41,89.29 157.43,88.31 v2(157,88.31) 157,88.49 156.23,89.25 154.09,89.25 151.52,86.68 147.97,86.68 v2(147.78,86.88) 147.38,87.28 144.23,87.28 143.58,86.62 142.12,86.62 141.54,87.2 139.86,87.2 139.01,88.05 137.64,88.05 137.37,88.31 137.37,89.69 136.52,90.54 v2(136.52,91.62) ; RE349.1 263.4,83.2 264.77,81.83 264.77,77.71 263.78,76.72 262.74,76.72 262.23,77.23 v2(261.58,77.23) ; v2(164.59,59.68) 166.34,59.68 166.67,59.35 167.79,59.35 168.18,59.73 169.3,59.73 174.12,64.55 174.12,67.76 174.66,68.3 v2(175.32,68.3)
  IN1 w0.119: v2(159.84,61.61) 161.77,59.68 v2(164.59,59.68)
  IN2 w0.124: v2(260.37,72.06) 260.08,71.77 253.39,71.77 252.88,71.26 250.06,71.26 249.42,70.62 246,70.62 245.19,69.82 244.13,69.82 243.54,69.23 243.13,69.23 241.12,67.22 241.12,66.57 240.1,65.55 237.54,65.55 236.34,64.36 230.12,64.36 229.32,65.16 228.88,65.16 227.63,63.92 204.93,63.92 203.74,65.11 184.9,65.11 182.94,67.08 176.1,67.08 175.32,67.86 v2(175.32,68.3) ; v2(154.04,124.24) 151.06,121.27 151.06,112.77 151.75,112.09 151.75,109.04 150.32,107.6 150.32,105.7 150.6,105.42 150.6,103.81 151.03,103.38 v2(152.56,103.38) ; v2(147.85,64.81) 147.92,64.87 159.08,64.87 159.84,64.11 v2(159.84,61.61)
  IN3 w0.135: v2(161.62,89.6) 161.62,90 161.11,90.51 161.11,100.89 160.21,101.79 155.71,101.79 154.13,103.38 v2(152.56,103.38) ; v2(136.52,91.62) 136.16,91.26 129.44,91.26 127.96,92.74 127.96,94.17 127.68,94.46 127.31,94.46 127.07,94.69 127.07,95.41 126.78,95.71 126.29,95.71 126.11,95.53 124.39,95.53 v2(123.82,96.1) ; v2(147.85,64.81) 147.85,65.47 148.13,65.75 148.13,69.15 145.68,71.61 145.68,79.4 146.69,80.42 146.69,84.6 147.78,85.69 v2(147.78,86.88)
  BOTTOM w0.102: UC1.AN15 123.96,96.1 v2(123.82,96.1)
  BOTTOM w0.112: v2(157,88.31) PR312.2 ; v2(261.58,77.23) 261.87,76.93 261.87,75.21 260.37,73.71 v2(260.37,72.06) ; PR504.1 174.66,68.3 v2(175.32,68.3)
SIO_SLP_WLAN#: length 212.3
  TOP w0.112: v2(219.78,70.96) 220.66,70.07 225.63,70.07 226.5,70.93 227.27,70.93 227.61,71.27 227.61,73.21 229.05,74.66 229.05,82.57 231.75,85.27 v2(232.1,85.27) ; RZ71.1 251.74,106.79 249.3,104.35 v2(249.3,104.07) ; UE1.D9 v2(248.68,90.66)
  IN1 w0.119: v2(249.3,104.07) 249.3,103.29 249.9,102.69 249.9,100.35 249.52,99.97 249.52,97.13 249.93,96.71 249.93,93.33 249.88,93.28 249.88,90.48 249.66,90.26 UE1.D9 v2(248.68,90.66)
  IN2 w0.124: v2(218.51,57.53) 218.51,57.54 218.26,57.79 215.84,57.79 214.15,56.09 209.09,56.09 208.56,56.63 205.17,56.63 201.56,60.23 171.42,60.23 167.97,63.68 161.55,63.68 158.14,67.09 149.45,67.09 149.05,67.5 148.51,67.5 144.78,71.23 144.78,72.06 142.64,74.19 142.64,74.89 140.84,76.69 140.84,77.79 v2(141.04,77.99) ; v2(232.1,85.27) 230.48,86.89 230.48,100.39 233.02,102.93 242.84,102.93 243.31,103.4 248.63,103.4 v2(249.3,104.07)
  BOTTOM w0.076: UC1.BB17 122.78,90.58 122.78,88.87 124.36,87.29 124.36,87.13
  BOTTOM w0.112: 124.36,87.13 124.36,86.31 124.67,85.99 125.25,85.99 125.5,85.74 125.5,84.47 126.87,83.09 126.87,80.87 130.25,77.49 140.55,77.49 v2(141.04,77.99) ; v2(218.51,57.53) 218.51,57.56 218.78,57.84 218.78,68.95 219.91,70.07 219.91,70.82 v2(219.78,70.96)
SLEEVE: length 43.1
  IN3 w1.016: 252.75,59.89 252.75,58.62 252.56,58.43 252.56,55.76 254.02,54.3 256.37,54.3 259.04,51.64 264.81,51.64 268.71,55.54 272.49,55.54 283.16,44.87
  BOTTOM w0.102: v2(284.38,44.27) v1(283.82,44.27)
  vias: v2(252.58,60.69) v2(253.16,60.67) v2(284.38,44.84)
SLEEVE_R:
  vias: v2(289.53,43.83)
SLOT2_CONFIG_0: length 50.7
  TOP w0.107: 258.65,91.55 257.36,90.26 UE1.N9
  TOP w0.112: RPE9.4 261.24,93.24 v2(260.81,93.67) 260.4,93.67 v1(260.09,93.37) 260.09,92.59 259.05,91.55 258.65,91.55
  IN2 w0.124: v2(235.49,108.32) 236.88,108.32 238.45,106.74 243.05,106.74 244.74,105.05 258.01,105.05 260.75,102.31 260.75,101.14 261.17,100.72 261.17,100.28 260.76,99.86 260.76,99.52 261.54,98.74 261.54,94.41 v2(260.81,93.67)
  BOTTOM w0.112: v2(235.49,108.32) 232.6,108.32 231.03,106.75 JNGFF2.13
SLOT2_CONFIG_1: length 48.3
  TOP w0.107: UE1.M10 255.88,90.66 257.46,90.66 258.85,92.05 v1(258.94,92.05)
  TOP w0.112: v1(258.94,92.05) 259.66,92.77 259.66,93.57 260.35,94.26 v2(260.81,94.26) 261.32,93.74 RPE9.3
  IN2 w0.124: v2(260.81,94.26) 260.04,95.02 260.04,97.29 260.18,97.43 260.18,98.75 259.13,99.81 258.06,99.81 255.09,102.78 249.41,102.78 247.62,100.99 246.49,100.99 245.04,99.54 238.11,99.54 233.45,94.88 v2(231.48,94.88)
  BOTTOM w0.112: v2(231.48,94.88) 231.35,94.75 JNGFF2.61
SLOT2_CONFIG_2: length 49
  TOP w0.107: 258.95,92.72 257.29,91.06 UE1.N10
  TOP w0.112: RPE9.2 261.43,94.24 v2(260.82,94.85) 260.22,94.85 v1(260.18,94.89) 259.36,94.07 259.36,93.13 258.95,92.72
  IN2 w0.124: v2(232.07,95.51) 233.45,95.51 237.72,99.78 244.88,99.78 246.31,101.21 247.45,101.21 249.29,103.06 255.17,103.06 258.16,100.06 259.36,100.06 260.48,98.94 260.48,97.32 260.35,97.19 260.35,95.32 v2(260.82,94.85)
  BOTTOM w0.112: JNGFF2.67 231.29,93.25 232.07,94.03 v2(232.07,95.51)
SLOT2_CONFIG_3: length 78.4
  TOP w0.102: v1(261.5,95.97) 261.33,95.97 v2(260.82,95.46)
  TOP w0.112: RPE9.1 261.54,94.74 v2(260.82,95.46) ; UE1.F4 v2(250.28,85.86)
  IN2 w0.124: v2(260.82,95.46) 261.24,95.88 261.24,96.81 260.82,97.23 260.82,99.03 260.3,99.55 260.3,102 257.76,104.54 238.67,104.54 237.36,105.85 234.54,105.85 234.11,106.28 234.11,109.52 v2(232.37,111.26)
  IN3 w0.135: v2(263.66,84.59) 261.01,84.59 259.87,83.45 257.34,83.45 256.77,84.02 255.74,84.02 255.47,83.75 251.44,83.75 250.68,84.5 250.68,85.46 v2(250.28,85.86)
  BOTTOM w0.112: JNGFF2.1 231.88,111.75 v2(232.37,111.26) ; v2(263.66,84.59) 263.97,84.59 266.43,87.04 266.43,93.96 264.77,95.62 260.97,95.62 v2(260.82,95.46)
SLOT2_SATA_LED#: length 4.8
  TOP w0.102: RN101.1 v1(239.98,107.52)
  TOP w0.112: RN101.1 239.98,109.13 240.18,109.33 v2(240.18,109.87)
  BOTTOM w0.112: v2(240.18,109.87) 240,109.69 238.89,109.69 238.7,109.5 JNGFF2.10
SM_RCOMP0: length 12.6
  TOP w0.381: v2(121.31,88.3) 120.48,87.48 120.48,84.73 RC5.1
  IN2 w0.305: v2(121.98,94.74) 121.76,94.74 120.29,93.26 120.29,89.27 121.25,88.3 v2(121.31,88.3)
  BOTTOM w0.254: UC1.AR18 122.41,95.08 v2(121.98,94.74)
SM_RCOMP1: length 11.5
  TOP w0.381: v2(122.22,87.64) 122.07,87.49 v4(122.07,86.66) 122.07,84.54 RC6.1
  IN2 w0.305: v2(121.98,94.1) 121.69,94.1 120.84,93.26 120.84,92.65 120.84,91.03 121.23,90.64 121.23,89.78 122.22,88.78 v2(122.22,87.64)
  BOTTOM w0.254: v2(121.98,94.1) 122.41,94.43 UC1.AT18
SM_RCOMP2: length 10.7
  TOP w0.381: RC7.1 122.9,86.98 v2(122.9,86.99)
  IN2 w0.305: v2(122.9,86.99) 123.16,87.25 123.16,89.19 122.55,89.81 122.55,90.87 121.45,91.97 121.45,93.16 121.76,93.47 v2(121.97,93.47)
  BOTTOM w0.254: v2(121.97,93.47) 121.98,93.47 UC1.AU18
SML0_SMBCLK: length 242
  TOP w0.112: UL1.28 247.28,130.77 v2(246.98,131.07)
  IN1 w0.119: v2(140.79,102.84) 140.96,103.01 141.73,103.01 142.19,103.47 144.22,103.47 144.9,104.14 146.43,104.14 148.99,101.59 148.99,96.16 148.68,95.86 148.68,95.09 148.8,94.98 148.8,94.54 147.93,93.67 147.93,91.49 147.34,90.91 147.34,88.56 148.26,87.64 148.26,85.33 147.97,85.05 147.97,70.64 150.82,67.79 162.85,67.79 164.37,66.28 170.9,66.28 174.36,62.83 178.11,62.83 179.19,61.75 214.74,61.75 215.23,61.25 217.63,61.25 217.78,61.41 225.94,61.41 226.76,60.59 230.57,60.59 235.25,65.27 235.25,66.66 235.46,66.86 235.63,66.86 v2(235.82,66.68)
  IN3 w0.135: v2(246.98,131.07) 246.4,130.5 246.02,130.5 245.39,129.87 239.94,129.87 236.92,126.85 236.92,111.9 240.03,108.78 240.03,107.05 242.21,104.88 242.21,100.99 241.63,100.42 239.8,100.42 237.59,98.21 237.59,92.3 235.35,90.06 235.35,81.14 236.09,80.41 237.98,80.41 238.53,79.86 238.53,79.13 240.61,77.06 240.61,70.25 238,67.64 237.19,67.64 236.41,66.85 235.99,66.85 v2(235.82,66.68)
  BOTTOM w0.076: UC1.R9 127.73,105.14 127.86,105.02 127.86,104.53 128.11,104.29 128.11,104.15 128.33,103.92 129.36,103.92 129.96,103.32 129.96,103.24 130.38,102.83 132.08,102.83 132.32,102.72 132.76,102.72 132.88,102.84 135.58,102.84 135.69,102.96 136.82,102.96 136.83,102.94 136.85,102.94
  BOTTOM w0.102: RC347.1 RC19.1
  BOTTOM w0.112: 136.85,102.94 138.02,102.94 138.27,103.19 139.94,103.19 140.12,103.01 140.61,103.01 v2(140.79,102.84) 140.97,103.02 141.14,103.02 141.69,102.47 CC318.1 142.56,102.39 RC19.1
SML0_SMBDATA: length 235.5
  TOP w0.112: v2(246.34,131.07) 245.83,130.57 245.83,129.68 246.08,129.43 UL1.31
  IN1 w0.119: v2(140.79,103.42) 140.96,103.26 141.63,103.26 142.09,103.71 144.12,103.71 144.8,104.39 146.53,104.39 149.23,101.69 149.23,95.96 149.53,95.66 149.53,94.93 148.17,93.57 148.17,91.39 147.59,90.81 147.59,88.66 148.5,87.74 148.5,85.23 148.22,84.94 148.22,70.74 150.92,68.04 162.96,68.04 164.47,66.53 171.01,66.53 174.46,63.07 178.21,63.07 179.29,61.99 214.84,61.99 215.34,61.5 217.53,61.5 217.68,61.65 226.05,61.65 226.86,60.84 230.47,60.84 235.01,65.38 235.01,66.76 235.35,67.11 235.66,67.11 v2(235.82,67.26)
  IN3 w0.135: v2(246.34,131.07) 246.34,130.87 246.23,130.77 245.91,130.77 245.28,130.14 239.83,130.14 236.66,126.96 236.66,111.79 239.77,108.68 239.77,106.94 241.94,104.77 241.94,101.1 241.53,100.68 239.69,100.68 237.33,98.32 237.33,92.41 235.09,90.17 235.09,81.03 235.98,80.15 237.88,80.15 238.27,79.75 238.27,79.02 240.34,76.95 240.34,70.35 237.89,67.9 237.09,67.9 236.3,67.12 235.96,67.12 v2(235.82,67.26)
  BOTTOM w0.076: UC1.W2 132.04,103.03 132.28,102.92 132.67,102.92 132.8,103.04 135.49,103.04 135.61,103.16 136.82,103.16 136.83,103.18 136.85,103.18
  BOTTOM w0.112: RC348.1 RC20.1 140.95,103.26 v2(140.79,103.42) 140.61,103.25 140.22,103.25 140.04,103.42 138.17,103.42 137.92,103.18 136.85,103.18
SML1_SMBCLK: length 207.6
  TOP w0.112: v2(238.56,53.53) 238.39,53.35 238.39,51.55 236.26,49.42 187.26,49.42 185.41,51.27 180.87,51.27 178.68,53.46 178.68,56.49 179.13,56.95 179.13,60.66 176.53,63.26 176.53,64.23 v2(176.36,64.4) ; UE1.D8 v2(248.68,89.86)
  IN1 w0.119: v2(141.14,105.91) 141.3,106.07 142.42,106.07 142.61,106.26 144.97,106.26 145.99,105.24 147.68,105.24 150.01,102.91 150.01,100.3 150.58,99.73 150.58,93.58 149.36,92.35 149.36,84.44 148.98,84.06 148.98,71.11 151.26,68.83 163.41,68.83 164.92,67.32 172.3,67.32 173.6,66.03 175.65,66.03 176.53,65.16 176.53,64.57 v2(176.36,64.4)
  BOTTOM w0.076: 136.85,103.96 136.83,103.96 136.82,103.98 135.52,103.98 135.21,103.67 133.15,103.67 133.05,103.57 132.75,103.57 132.19,103.4 131.94,103.4 131.85,103.44 131.66,103.44 131.65,103.44 131.57,103.4 131.34,103.4 UC1.W3
  BOTTOM w0.112: RC15.1 141.99,106.13 141.36,106.13 v2(141.14,105.91) 141.2,105.86 CC319.1 140.66,105.77 138.68,105.77 137.91,104.99 137.91,104.41 137.46,103.96 136.85,103.96 ; v2(248.68,89.86) 248.43,89.86 246.58,88 246.58,85.79 245.79,85 245.79,83.93 247.69,82.03 247.69,81.32 248.27,80.74 248.27,76.05 248.02,75.8 248.02,71.34 246.94,70.25 246.94,69.25 246.78,69.1 246.78,66.74 245.29,65.24 245.29,62.33 243.81,60.86 243.81,59.82 238.37,54.38 238.37,53.72 v2(238.56,53.53)
SML1_SMBDATA: length 211.9
  TOP w0.112: v2(176.94,64.4) 176.77,64.23 176.77,63.36 179.37,60.75 179.37,56.85 178.92,56.39 178.92,53.56 180.97,51.51 185.51,51.51 187.36,49.66 236.16,49.66 238.15,51.65 238.15,53.36 v2(237.98,53.53) ; UE1.E11 v2(249.48,92.26)
  IN1 w0.119: v2(141.14,106.49) 141.32,106.31 142.32,106.31 142.51,106.5 145.07,106.5 146.09,105.49 147.78,105.49 150.26,103.01 150.26,100.4 150.83,99.83 150.83,93.47 149.6,92.25 149.6,84.34 149.22,83.96 149.22,71.21 151.36,69.08 163.51,69.08 165.02,67.57 172.41,67.57 173.7,66.28 175.75,66.28 176.77,65.26 176.77,64.57 v2(176.94,64.4)
  BOTTOM w0.076: UC1.V3 131.23,103.57 131.53,103.57 131.63,103.62 131.83,103.62 131.99,103.57 132.16,103.57 132.29,103.61 132.75,103.74 132.97,103.74 133.1,103.88 135.12,103.88 135.43,104.18 136.82,104.18 136.83,104.2 136.85,104.2
  BOTTOM w0.112: v2(237.98,53.53) 238.13,53.68 238.13,54.48 243.57,59.92 243.57,60.96 245.05,62.43 245.05,65.34 246.55,66.84 246.55,69.2 246.7,69.35 246.7,70.35 247.79,71.44 247.79,75.9 248.03,76.15 248.03,80.64 247.45,81.23 247.45,81.94 245.55,83.84 245.55,85.1 246.34,85.89 246.34,92.4 246.68,92.75 248.99,92.75 v2(249.48,92.26) ; RC17.1 141.73,106.36 141.27,106.36 v2(141.14,106.49) 140.65,106 138.58,106 137.67,105.09 137.67,104.51 137.36,104.2 136.85,104.2
SNB_+1VALWP: length 2
  TOP w0.112: 159.28,81.04 v1(161.26,81.04)
SNUB_1.8VALW: length 2.2
  BOTTOM w0.102: PC506.1 170.22,64.05 v1(169.94,63.76)
  BOTTOM w0.508: PC506.1 171.06,63.87 PR502.2
SNUB_1V_PRIM: length 2.3
  TOP w0.112: PR409.2 v1(153.11,127.26)
  TOP w0.508: PR409.2 PC419.1
SNUB_1VS_VCCIO: length 2.3
  TOP w0.102: PC401.1 136.65,130.17 v1(136.35,129.87)
  TOP w0.508: PR405.2 138.47,130.17 PC401.1
SNUB_CHG1: length 1.7
  TOP w0.112: PR923.2 v4(40.85,66.91)
SNUB_CHG2: length 1.4
  TOP w0.112: PC941.1 v1(51,65.1)
SPKR: length 149.4
  TOP w0.112: v2(230.8,60.07) 230.8,60.07 231.77,61.05 235.89,61.05 v2(236.69,60.25) ; v2(130.32,93.33) 130.87,92.78 130.87,91.64 v1(132.24,90.27) 134.1,88.4 135.15,88.4 136.9,86.65 138.52,86.65 139.42,85.75 140.43,85.75 v2(140.68,85.51) RC183.1 ; RA12.2 253.49,66.74 v2(253.49,67.12)
  IN1 w0.119: v2(253.49,67.12) 253.06,66.69 251.94,66.69 250.26,65.01 248.29,65.01 244.38,61.1 240.18,61.1 238.99,59.9 237.03,59.9 v2(236.69,60.25)
  IN2 w0.124: v2(140.68,85.51) 141.35,84.83 143.19,84.83 147.98,80.04 147.98,72.27 150.06,70.19 150.36,70.19 150.98,69.58 159.54,69.58 162.95,66.17 171.03,66.17 174.12,63.07 178.25,63.07 178.77,63.6 180.5,63.6 181.3,62.8 202.73,62.8 203.9,61.63 214.26,61.63 215.3,60.58 218.57,60.58 219.28,61.29 225.95,61.29 227.62,59.62 230.38,59.62 230.8,60.03 230.8,60.07 v2(230.8,60.07)
  BOTTOM w0.076: v2(130.32,93.33) 130.08,93.09 UC1.AW5
SPKR_R: length 2.9
  TOP w0.112: CA27.1 252.3,64.27 CA72.1 RA51.1 RA12.1
SRTCRST#: length 19.9
  TOP w0.112: RC56.1 130.39,82.64 130.39,83.91 CC24.1 129.51,84.78 129.51,89.27 126.25,92.53 125.66,92.53 124.32,93.88 v1(124.32,96.42) 124.32,96.83 124.07,97.08 123.66,97.08 123.26,96.68 v2(122.91,96.68)
  BOTTOM w0.102: v2(122.91,96.68) 122.63,96.4 UC1.AN18
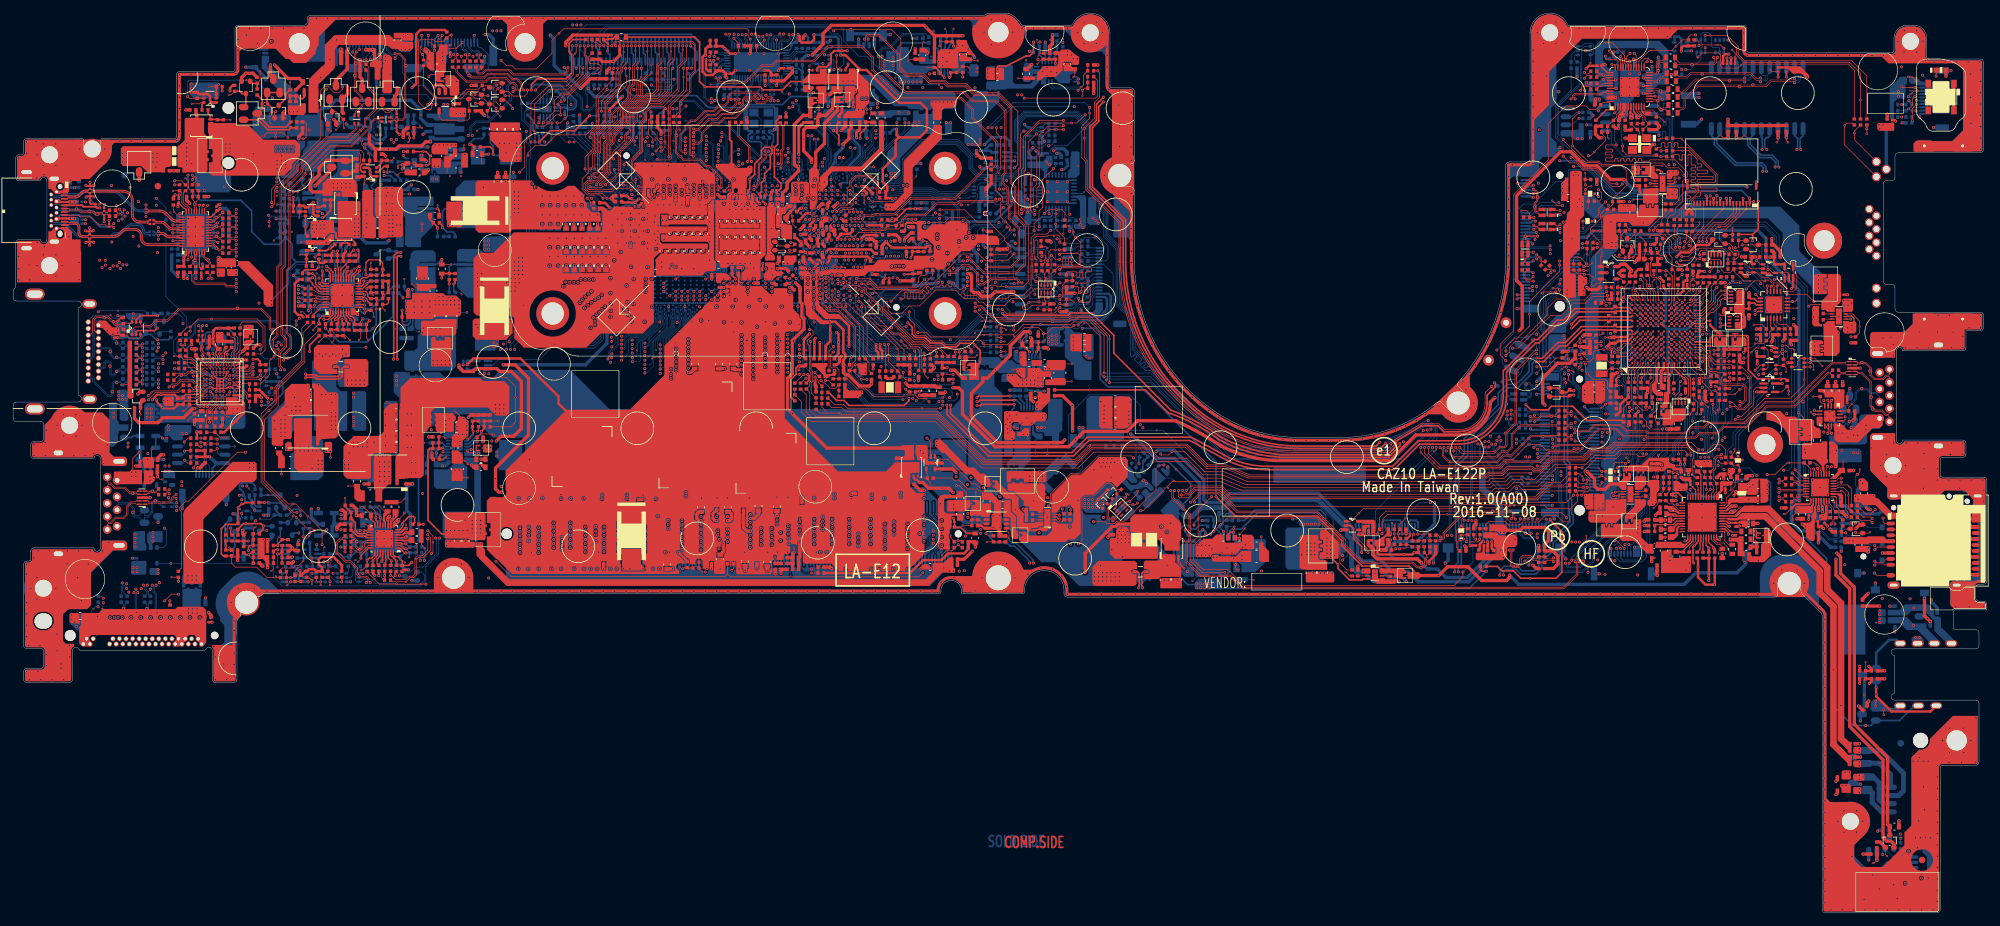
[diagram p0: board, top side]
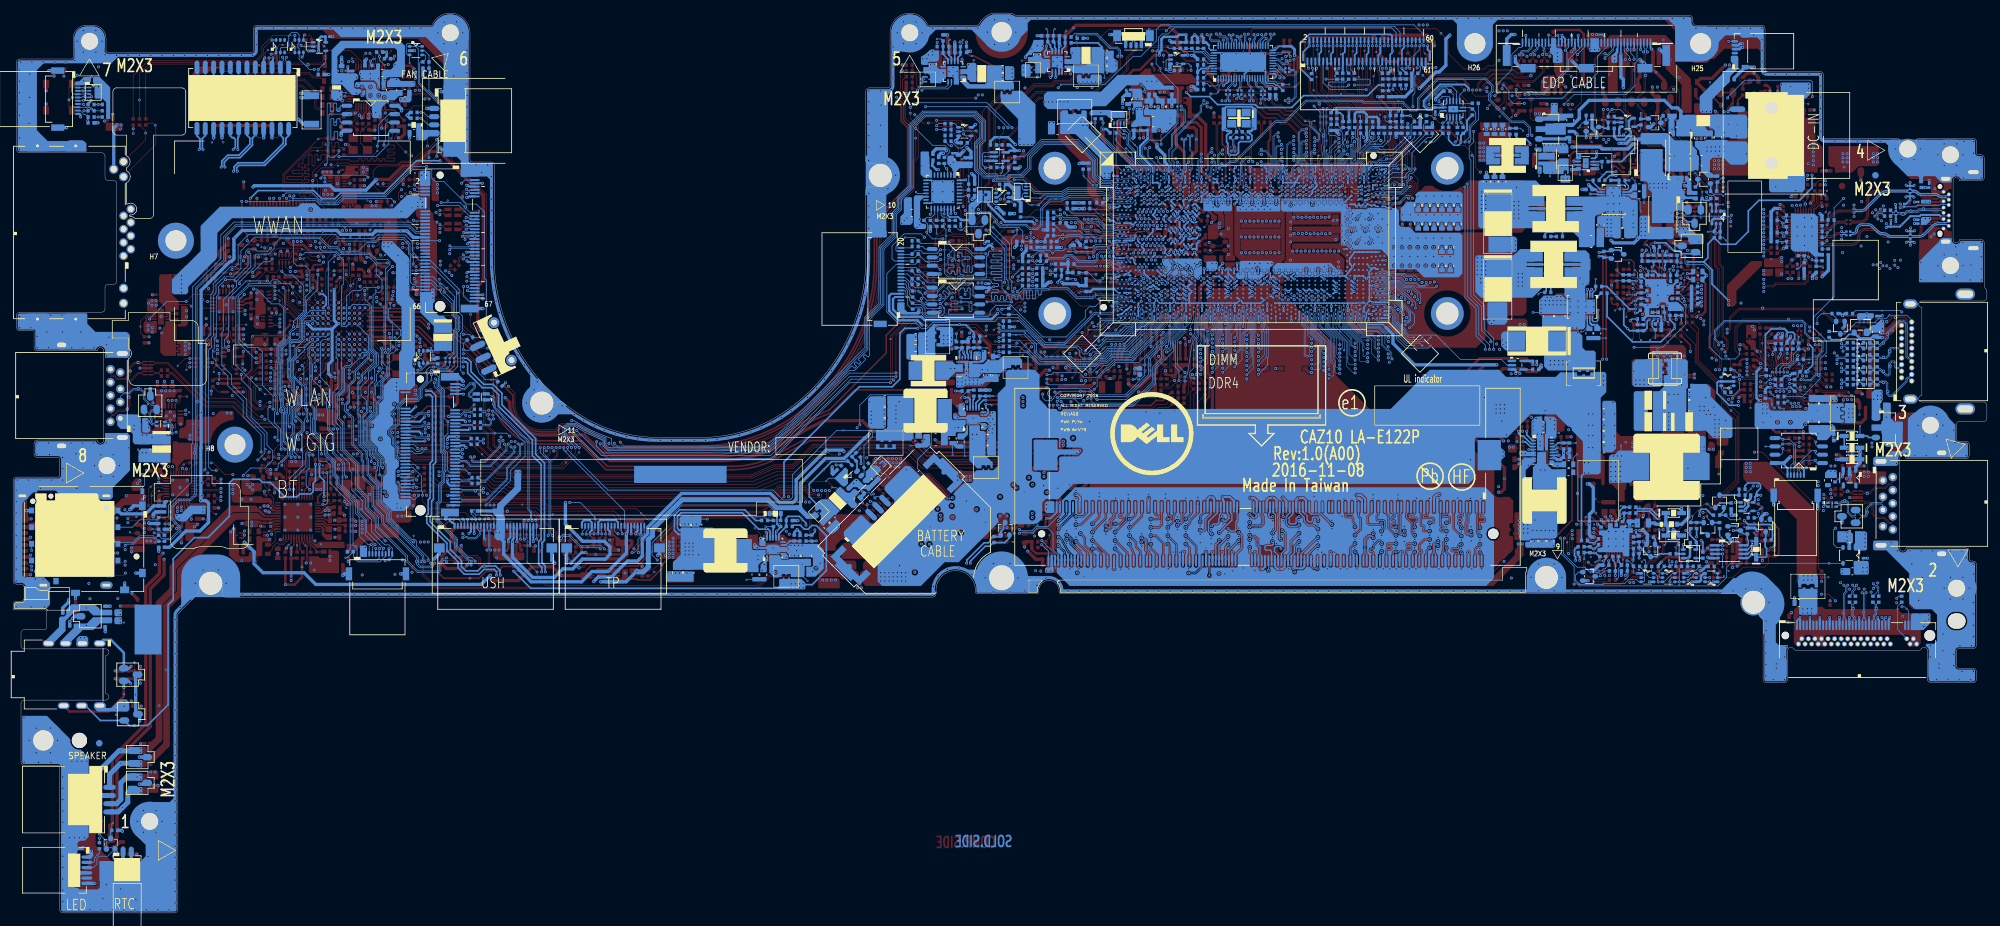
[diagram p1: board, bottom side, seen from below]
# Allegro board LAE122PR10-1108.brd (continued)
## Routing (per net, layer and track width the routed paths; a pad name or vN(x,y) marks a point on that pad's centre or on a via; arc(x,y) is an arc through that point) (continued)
SS_1V_PRIM: length 3.6
  BOTTOM w0.102: v1(157.97,133.15) 158.15,132.97 PC420.1
  BOTTOM w0.254: PC420.1 PR428.1 158.15,130.83 157.75,130.44 PU402.7
SS_1VS_VCCIO: length 3.7
  BOTTOM w0.112: v1(142,134.78) 142.21,134.57 PC410.1
  BOTTOM w0.254: PC410.1 PR427.1 142.01,132.65 142.01,131.96 141.88,131.83 PU401.7
SUSACK#: length 193.9
  TOP w0.107: UE1.K12 v2(254.3,93.08)
  IN1 w0.119: v2(126.51,96.11) 126.14,95.74 126.14,92.53 129.06,89.61 133.45,89.61 v2(133.82,89.23)
  IN2 w0.124: v2(133.82,89.23) 134.14,88.91 136.93,88.91 137.18,89.16 138.41,89.16 139.31,88.26 145.01,88.26 150.11,83.16 150.11,73.21 151.94,71.38 160.84,71.38 162.15,70.08 172.37,70.08 175.82,66.62 182.75,66.62 184.72,64.65 203.55,64.65 204.77,63.43 227.51,63.43 227.72,63.22 230.44,63.22 230.53,63.31 233.93,63.31 234.13,63.1 235.8,63.1 237.05,64.36 241.3,64.36 242.95,66 242.95,68.14 244.4,69.59 245.29,69.59 246.09,70.39 249.51,70.39 250.15,71.04 252.98,71.04 253.45,71.51 260.75,71.51 264.41,75.17 264.41,81.66 262.91,83.16 262.91,87.45 262.62,87.74 259.8,87.74 259.15,88.39 259.15,91.55 257.03,93.68 254.9,93.68 v2(254.3,93.08)
  BOTTOM w0.102: UC1.AP11 126.15,95.75 v2(126.51,96.11)
SUSCLK: length 295.3
  TOP w0.112: v2(171.78,61.33) 172.14,61.33 v1(173.52,62.71) 176.61,65.8 183.83,65.8 187.33,64.33 225.32,64.33 225.74,64.75 227.74,64.75 228.61,65.62 229.56,65.62 230.12,65.07 232.34,65.07 235.16,67.89 RZ56.2 ; v2(124.99,86.37) 124.29,85.67 124.29,82.7 RC48.1
  IN1 w0.119: v2(166.14,60.29) 162.94,60.29 161.2,62.02 159.27,62.02 158.9,61.65 154.33,61.65 154.05,61.93 148.9,61.93 146.25,64.58 146.25,66.05 v2(145.95,66.36) 144.37,66.36 143.94,65.92 142.77,65.92 141.77,66.92 73.29,66.92 71.97,65.61 71.97,63 72.54,62.43 72.54,57.9 71.62,56.98 69.51,56.98 69.27,57.22 65.87,57.22 65.3,56.66 63.6,56.66 62.84,55.89 61.59,55.89 58.92,53.22 52.78,53.22 51.71,54.29 50.14,54.29 49.63,54.8 42.21,54.8 41.45,54.04 35.2,54.04 31.23,50.06 23.09,50.06 20.99,47.97 v2(13.74,47.97) ; v2(137.31,81.16) 136.87,81.16 136.1,81.93 136.1,83.32 133.88,85.55 126.96,85.55 126.13,86.37 v2(124.99,86.37)
  IN3 w0.135: v2(143.2,80.78) 143.64,80.35 143.64,79.79 143.2,79.36 143.2,79 143.88,78.33 143.88,70.86 145.95,68.79 v2(145.95,66.36) ; v2(171.78,61.33) 171.37,60.91 166.77,60.91 v2(166.14,60.29)
  BOTTOM w0.076: UC1.BA17 122.67,91.13 122.94,90.87 122.94,88.94 124.56,87.32
  BOTTOM w0.112: v2(124.99,86.37) 124.67,86.69 124.67,87.21 124.56,87.32 ; v2(143.2,80.78) 142.95,80.53 137.69,80.53 137.31,80.91 v2(137.31,81.16) ; v2(13.74,47.97) 13.41,48.3 RN99.2
SUSCLK_R: length 6.4
  BOTTOM w0.102: RN99.1 13.6,46.76 v1(13.6,46.34) 13.6,43.2 JNGFF3.68
SW2_DP1_AUXN: length 128
  TOP w0.104: RV70.1 106.3,131.15 106.3,130.8 v2(106.11,130.61) ; v2(27.33,111.84) 27.33,111.97 27.44,112.09 27.69,112.09 27.83,111.95 27.83,111.53 27.72,111.43 27.55,111.43 27.33,111.21 CT116.1 ; CT81.1 28.47,88.89 28.47,89.34 v2(28.28,89.53)
  IN1 w0.119: v2(27.33,111.84) 27.33,111.95 27.48,112.1 27.61,112.1 27.77,112.26 28.08,112.26 28.62,112.81 28.62,115.32 29.56,116.26 29.56,123.76 31.55,125.75 36.01,125.75 36.94,126.69 45.99,126.69 47.51,128.21 79.36,128.21 82.53,131.38 106.15,131.38 106.43,131.1 106.43,130.79 106.25,130.61 v2(106.11,130.61)
  IN3 w0.135: v2(27.33,111.84) 27.33,111.93 27.46,112.06 27.55,112.06 27.73,112.24 28.12,112.24 31.97,108.39 31.97,94.54 28.62,91.19 28.62,89.95 28.28,89.6 v2(28.28,89.53)
  BOTTOM w0.104: UV7.29 107.53,131.14 107.25,131.42 106.49,131.42 106.21,131.13 106.21,130.71 v2(106.11,130.61)
SW2_DP1_AUXN_C: length 3.3
  TOP w0.104: CT116.2 27.33,109.66 27.34,109.65 RT131.1 27.34,108.79 27.65,108.48 v3(27.65,108.09) 27.65,108.02 27.65,107.53 27.57,107.46 UT9.25
SW2_DP1_AUXP: length 128
  TOP w0.104: CT80.1 28.68,88.87 28.68,89.35 v2(28.86,89.53) ; RV76.1 106.82,130.99 v2(106.82,130.59) ; CT115.1 28.03,111.21 28.03,112.03 27.77,112.29 27.51,112.29 v2(27.31,112.48)
  IN1 w0.119: v2(27.31,112.48) 27.99,112.48 28.41,112.9 28.41,115.41 29.35,116.35 29.35,123.85 31.46,125.97 35.91,125.97 36.85,126.91 45.89,126.91 47.42,128.43 79.27,128.43 82.44,131.6 106.24,131.6 106.65,131.19 106.65,130.76 v2(106.82,130.59)
  IN3 w0.135: v2(27.31,112.48) 28.22,112.48 32.21,108.49 32.21,94.44 28.86,91.09 v2(28.86,89.53)
  BOTTOM w0.104: v2(106.82,130.59) 106.62,130.59 106.51,130.7 106.51,130.8 106.41,130.9 106.41,131.05 106.58,131.21 107.17,131.21 107.44,130.94 108.11,130.94 108.31,130.74 UV7.28
SW2_DP1_AUXP_C: length 3.3
  TOP w0.104: CT115.2 28.21,110.09 RT130.1 28.21,108.79 27.88,108.46 27.88,107.54 27.97,107.44 UT9.24
SW2_DP1_CADET: length 3.7
  TOP w0.102: v1(110.53,131.24) 110.53,132.19 RV73.1
  TOP w0.112: v2(109.81,133.33) 110.5,132.63 RV73.1
  BOTTOM w0.107: v2(109.81,133.33) 110.31,132.82 UV7.33
SW2_DP1_HPD: length 148.7
  TOP w0.112: v2(74.32,130.01) 75.16,129.17 76.02,129.17 76.5,128.69 79.68,128.69 82.09,131.09 82.09,133.06 v4(83.16,134.13) 83.84,134.81 111.81,134.81 112.09,134.53 112.09,133.45 v2(112.31,133.23)
  IN2 w0.124: v2(21.84,108.94) 23.28,110.37 27.52,110.37 29.74,112.6 29.74,122.59 31.93,124.78 35.03,124.78 37.59,127.34 45.69,127.34 47.37,129.02 61.86,129.02 62.22,129.37 73.68,129.37 v2(74.32,130.01)
  BOTTOM w0.107: UV7.38 v2(112.31,133.23)
  BOTTOM w0.112: RT73.1 28.09,78.75 25.42,81.42 25.42,84.44 24.47,85.39 24.47,87.26 26.38,89.16 26.38,90.88 23.28,93.98 RT380.1 23.28,107.5 v2(21.84,108.94)
SW2_DP1_HPD_R: length 2
  TOP w0.102: UT5.C10 v2(33.02,79.45)
  BOTTOM w0.112: RT73.2 32.4,78.75 v1(32.69,79.04) 33.02,79.37 v2(33.02,79.45)
SW2_DP1_N0: length 112.6
  TOP w0.104: v2(33.99,101.33) 33.79,101.14 33.21,101.14 CT104.1
  IN3 w0.135: v2(33.99,101.33) 34.16,101.16 34.82,101.16 36.75,103.1 36.75,108.13 35.19,109.69 35.19,123.32 38.93,127.06 45.71,127.06 47.39,128.74 73.73,128.74 74.93,127.54 80.07,127.54 84.09,131.56 107.19,131.56 108.16,130.58 110.55,130.58 112.86,132.9 112.86,133.64 112.68,133.82 112.68,133.91 112.6,134 v2(112.52,134)
  BOTTOM w0.104: v2(112.52,134) 112.53,134 112.9,133.62 112.9,132.88 112.71,132.68 UV7.39
SW2_DP1_N0_C: length 2.7
  TOP w0.104: UT9.10 30.2,102.1 30.3,102 30.57,102 30.88,101.69 30.92,101.69 31.32,101.29 31.32,101.25 31.43,101.14 31.61,101.14 CT104.2
SW2_DP1_N1: length 110.6
  TOP w0.104: v2(33.99,103.11) 33.79,102.92 33.21,102.92 CT106.1
  IN3 w0.135: v2(33.99,103.11) 34.01,103.11 34.35,102.77 35.04,102.77 35.99,103.72 35.99,107.92 34.38,109.54 34.38,123.7 38.48,127.79 45.48,127.79 47.15,129.46 74.08,129.46 75.31,128.23 79.79,128.23 82.42,130.86 82.42,131.7 83.82,133.09 106.72,133.09 107.72,132.09 108.92,132.09 108.92,132.09 110.32,132.09 111.35,133.12 111.35,133.61 111.07,133.89 v2(111.07,133.92)
  BOTTOM w0.104: v2(111.07,133.92) 111.43,133.56 111.43,133.23 111.61,133.05 111.61,132.8 111.51,132.7 UV7.36
SW2_DP1_N1_C: length 2.4
  TOP w0.104: UT9.13 30.4,103.3 30.5,103.2 v3(30.96,103.2) 31.19,103.2 31.47,102.92 31.61,102.92 CT106.2
SW2_DP1_N2: length 115.6
  TOP w0.104: CT108.1 33.21,104.7 33.79,104.7 v2(33.99,104.89)
  IN3 w0.135: v2(33.99,104.89) 34.16,104.72 34.79,104.72 35.27,105.19 35.27,107.68 30.69,112.26 30.69,125.45 31.29,126.05 35.53,126.05 38.02,128.53 45.26,128.53 49.4,132.68 72.66,132.68 76.42,128.91 79.51,128.91 81.71,131.11 81.71,132.04 83.53,133.86 106.95,133.86 108.01,132.79 108.89,132.79 109.77,132.79 109.97,132.79 110.25,133.07 110.25,133.56 110.07,133.74 110.07,133.86 109.93,133.99 v2(109.83,133.99)
  BOTTOM w0.104: v2(109.83,133.99) 110.09,133.73 110.09,133.58 110.71,132.96 UV7.34
SW2_DP1_N2_C: length 2.4
  TOP w0.104: CT108.2 31.61,104.7 v3(30.96,104.7) 30.72,104.7 30.44,104.42 30.29,104.42 30.21,104.5 UT9.16
SW2_DP1_N3: length 113.6
  TOP w0.104: CT110.1 33.31,106.37 33.69,106.37 v2(33.99,106.67)
  IN3 w0.135: v2(108.58,134) 108.8,133.78 108.8,133.61 108.66,133.48 108.32,133.48 107.12,134.67 83.26,134.67 80.97,132.38 80.97,131.34 79.24,129.6 76.72,129.6 72.96,133.36 49.12,133.36 45,129.24 42.1,129.24 41.33,130.01 38.36,130.01 35.09,126.74 30.85,126.74 29.88,125.78 29.88,112.05 34.58,107.35 34.58,106.52 34.45,106.39 34.29,106.39 34.01,106.67 v2(33.99,106.67)
  BOTTOM w0.104: v2(108.58,134) 108.66,134 108.77,133.88 108.77,133.81 108.97,133.61 108.97,133.3 109.51,132.76 UV7.31
SW2_DP1_N3_C: length 2.7
  TOP w0.104: UT9.19 30.2,105.7 30.3,105.6 30.5,105.6 v3(30.93,106.03) 31.37,106.47 31.61,106.47 CT110.2
SW2_DP1_P0: length 112.6
  TOP w0.104: v2(33.99,100.75) 33.79,100.94 33.21,100.94 CT103.1
  IN3 w0.135: v2(113.1,134) 113.1,132.8 110.65,130.34 108.06,130.34 107.09,131.32 84.19,131.32 80.17,127.3 74.83,127.3 73.63,128.5 47.49,128.5 45.81,126.82 39.03,126.82 35.43,123.22 35.43,109.79 36.99,108.23 36.99,103 34.92,100.92 34.16,100.92 v2(33.99,100.75)
  BOTTOM w0.104: UV7.40 113.11,132.7 113.1,132.7 v2(113.1,134)
SW2_DP1_P0_C: length 2.7
  TOP w0.104: CT103.2 31.61,100.94 31.35,100.94 v3(30.96,101.33) 30.49,101.8 30.28,101.8 30.18,101.7 UT9.9
SW2_DP1_P1: length 110.7
  TOP w0.104: v2(33.99,102.53) 33.79,102.72 33.21,102.72 CT105.1
  IN3 w0.135: v2(33.99,102.53) 35.14,102.53 36.23,103.62 36.23,108.02 34.62,109.64 34.62,123.6 38.58,127.55 45.58,127.55 47.25,129.22 73.98,129.22 75.21,127.99 79.89,127.99 82.67,130.76 82.67,131.6 83.92,132.85 106.62,132.85 107.62,131.85 108.62,131.85 108.92,131.85 110.42,131.85 111.59,133.02 111.59,133.86 v2(111.66,133.92)
  BOTTOM w0.104: UV7.37 111.91,132.68 111.81,132.79 111.81,133.13 111.63,133.31 111.63,133.89 v2(111.66,133.92)
SW2_DP1_P1_C: length 2.4
  TOP w0.104: CT105.2 31.61,102.72 31.39,102.72 31.14,102.97 30.67,102.97 30.65,103 30.5,103 30.4,102.9 UT9.12
SW2_DP1_P2: length 115.7
  TOP w0.104: v2(33.99,104.3) 33.79,104.5 33.21,104.5 CT107.1
  IN3 w0.135: v2(110.49,133.92) 110.49,132.97 110.07,132.55 108.45,132.55 107.91,132.55 106.85,133.61 83.63,133.61 81.95,131.94 81.95,131.01 79.61,128.67 76.32,128.67 72.56,132.43 49.5,132.43 45.36,128.29 38.12,128.29 35.63,125.8 31.39,125.8 30.94,125.35 30.94,112.36 35.51,107.78 35.51,105.09 34.89,104.47 34.16,104.47 v2(33.99,104.3)
  BOTTOM w0.104: UV7.35 111.11,132.67 110.91,132.86 110.91,133.05 110.31,133.64 110.31,133.82 110.42,133.92 v2(110.49,133.92)
SW2_DP1_P2_C: length 2.4
  TOP w0.104: UT9.15 30.2,104.1 30.31,104.21 30.52,104.21 30.76,104.46 31.65,104.46 CT107.2
SW2_DP1_P3: length 113.6
  TOP w0.104: CT109.1 33.11,106.17 33.9,106.17 v2(33.99,106.08)
  IN3 w0.135: v2(33.99,106.08) 34.05,106.14 34.55,106.14 34.82,106.42 34.82,107.45 30.12,112.15 30.12,125.68 30.95,126.5 35.19,126.5 38.46,129.77 41.23,129.77 42,129 45.1,129 49.22,133.12 72.86,133.12 76.62,129.36 79.34,129.36 81.21,131.24 81.21,132.28 83.36,134.43 107.02,134.43 108.22,133.23 108.76,133.23 109.04,133.51 109.04,133.87 v2(109.17,134)
  BOTTOM w0.104: v2(109.17,134) 109.17,133.39 109.91,132.65 UV7.32
SW2_DP1_P3_C: length 2.7
  TOP w0.104: CT109.2 31.61,106.27 31.46,106.27 31.25,106.06 31.25,106.06 30.91,105.72 30.9,105.72 30.58,105.4 30.33,105.4 30.23,105.3 UT9.18
SW2_DP2_AUXN: length 173.8
  TOP w0.104: CV150.1 235.29,76.38 235.29,76.27 234.92,75.9 234.64,75.9 234.61,75.93 234.03,75.93 234,75.9 232.76,75.9 232.36,75.5 231.22,75.5 231.15,75.56 v2(231.15,75.72) ; RV71.1 106.74,129.65 v2(106.74,130)
  IN3 w0.135: v2(106.74,130) 106.68,130 106.56,129.88 106.56,129.71 106.83,129.44 108.37,129.44 108.63,129.7 118.92,129.7 122.44,126.19 129.82,126.19 132.22,123.79 138.25,123.79 138.89,123.15 149.38,123.15 153.73,118.79 155.28,118.79 161.29,112.79 161.29,111.35 166.81,105.83 166.81,99.39 arc(169.21,87.33) 176.04,77.11 176.89,76.26 arc(185.49,70.52) 195.63,68.5 204.78,68.5 205.46,67.82 219.94,67.82 222.26,70.14 222.26,71.74 223.9,73.37 228.09,73.37 229.96,75.25 230.78,75.25 231.15,75.61 v2(231.15,75.72)
  BOTTOM w0.104: UV7.27 108.36,130.34 108.23,130.21 107.91,130.21 107.3,129.6 106.63,129.6 106.55,129.68 106.55,129.89 106.66,130 v2(106.74,130)
SW2_DP2_AUXN_C: length 5.1
  TOP w0.104: CV150.2 236.75,76.26 237.2,76.26 v2(237.38,76.44)
  BOTTOM w0.104: JNGFF1.20 240.15,75.9 240,75.75 239.5,75.75 238.99,76.26 237.57,76.26 v2(237.38,76.44)
SW2_DP2_AUXP: length 173.8
  TOP w0.104: CV149.1 v3(234.33,75.7) 232.84,75.7 232.44,75.3 231.44,75.3 v2(231.15,75) ; v2(106.16,130) 106.45,129.7 106.45,129.56 RV77.1
  IN3 w0.135: v2(106.16,130) 106.32,129.83 106.32,129.61 106.73,129.2 108.47,129.2 108.73,129.46 118.82,129.46 122.34,125.94 129.72,125.94 132.12,123.55 138.15,123.55 138.79,122.91 149.28,122.91 153.63,118.55 155.18,118.55 161.05,112.69 161.05,111.25 166.57,105.73 166.57,99.39 arc(168.99,87.24) 175.87,76.94 176.72,76.09 arc(185.39,70.29) 195.63,68.26 204.68,68.26 205.36,67.58 220.04,67.58 222.5,70.04 222.5,71.64 224,73.13 228.19,73.13 230.06,75 v2(231.15,75)
  BOTTOM w0.104: UV7.26 108.32,129.94 108.25,130.01 107.99,130.01 107.39,129.4 106.55,129.4 106.35,129.6 106.35,129.8 v2(106.16,130)
SW2_DP2_AUXP_C: length 5.1
  TOP w0.104: v2(237.38,75.86) 237.18,76.06 236.78,76.06 CV149.2
  BOTTOM w0.104: JNGFF1.22 240.14,75.4 239.99,75.55 239.42,75.55 238.91,76.06 237.58,76.06 v2(237.38,75.86)
SW2_DP2_CADET: length 3.5
  TOP w0.102: RV74.1 v1(113.26,131.2)
  TOP w0.112: RV74.1 113.59,132.22 v2(114.45,133.08)
  BOTTOM w0.107: v2(114.45,133.08) 114.31,132.94 UV7.43
SW2_DP2_HPD: length 170.7
  IN1 w0.119: v2(116.31,133.11) 116.31,134.25 117.63,135.57 144.19,135.57 148.54,131.23 153.67,131.23 154.66,132.22 155.85,132.22 v2(156.42,132.79)
  IN2 w0.124: v2(156.42,132.79) 157.41,131.8 158.87,131.8 160.62,130.06 161.08,130.06 163.4,127.74 163.4,124.22 162.8,123.62 162.8,118.69 164.42,117.07 164.42,111.07 168.83,106.66 168.83,90.89 170.77,88.95 170.77,86.55 173.28,84.04 173.28,82.02 182.3,73 185.39,73 187.52,70.88 213.58,70.88 214.59,71.89 216.6,71.89 218.11,73.39 224.36,73.39 v2(225.06,72.69)
  BOTTOM w0.107: UV7.48 v2(116.31,133.11)
  BOTTOM w0.112: v2(225.06,72.69) 225.51,73.15 v4(227.3,73.15) JNGFF1.31
SW2_DP2_N0: length 162.2
  TOP w0.104: CV156.1 235.34,72.8 233.4,72.8 233.37,72.83 232.71,72.83 232.69,72.8 231.17,72.8 228.2,69.83 227.01,69.83 226.05,68.87 218.81,68.87 217.93,69.75 217.93,70.92 v2(217.98,70.97)
  IN3 w0.135: v2(118.22,133.91) 118.32,133.81 118.32,133.37 118.64,133.06 122.79,133.06 123.43,133.69 126.8,133.69 132.65,127.84 138.74,127.84 139.36,128.47 144.53,128.47 145.97,127.02 147.79,127.02 148.4,126.41 149.92,126.41 152.89,123.44 155.07,123.44 164.03,114.48 164.03,112.3 169.31,107.02 169.31,99.4 arc(171.52,88.29) 177.81,78.88 178.49,78.2 arc(186.48,72.86) 195.89,70.99 206.12,70.99 206.81,70.3 217.56,70.3 217.8,70.54 217.8,70.79 v2(217.98,70.97)
  BOTTOM w0.104: UV7.49 116.71,132.83 116.98,133.1 118.07,133.1 118.26,133.29 118.26,133.87 v2(118.22,133.91)
SW2_DP2_N0_C: length 5
  TOP w0.104: CV156.2 236.77,72.63 237.2,72.63 v2(237.39,72.82)
  BOTTOM w0.104: JNGFF1.32 240.15,72.9 240,72.75 239.46,72.75 239.29,72.58 237.63,72.58 v2(237.39,72.82)
SW2_DP2_N1: length 164.5
  TOP w0.104: CV152.1 235.19,74.43 229.66,74.43 228.27,73.04 228.27,71.06 227.65,70.44 226.75,70.44 225.87,69.56 219.52,69.56 219,70.09 219,70.78 v2(219.19,70.97)
  IN3 w0.135: v2(219.19,70.97) 219,70.78 219,70.1 218.51,69.62 206.44,69.62 205.74,70.31 195.85,70.31 arc(186.21,72.23) 178.04,77.69 177.33,78.39 arc(170.89,88.04) 168.63,99.41 168.63,106.71 163.31,112.03 163.31,114.15 154.74,122.72 152.62,122.72 149.65,125.69 147.82,125.69 147.22,126.29 145.27,126.29 144.94,126.62 139.57,126.62 139.05,127.14 132.05,127.14 126.85,132.34 117.58,132.34 116.98,132.94 116.98,133.85 v2(116.81,134.02)
  BOTTOM w0.104: UV7.46 115.51,132.69 115.59,132.77 115.59,133.31 116.02,133.74 116.53,133.74 v2(116.81,134.02)
SW2_DP2_N1_C: length 4.9
  TOP w0.104: CV152.2 236.77,74.41 237.17,74.41 v2(237.36,74.6)
  BOTTOM w0.104: v2(237.36,74.6) 237.56,74.4 238.36,74.4 238.51,74.25 239.99,74.25 240.14,74.4 JNGFF1.26
SW2_DP2_N2: length 159.2
  IN3 w0.135: v2(114.86,133.88) 115.03,133.71 115.03,132.9 116.28,131.65 125.86,131.65 128.51,128.99 128.98,128.99 131.68,126.29 134.34,126.29 135.64,124.99 149.36,124.99 152.5,121.85 154.51,121.85 162.55,113.81 162.55,111.8 167.94,106.41 167.94,99.4 arc(170.26,87.77) 176.84,77.91 177.63,77.12 arc(185.94,71.57) 195.74,69.62 205.43,69.62 206.11,68.94 219.43,68.94 221.11,70.62 221.11,72.34 223.26,74.49 227.63,74.49 228.03,74.9 228.03,75.16 v2(228.21,75.33)
  BOTTOM w0.104: v2(114.86,133.88) 115.06,133.68 115.06,133.37 114.91,133.21 114.91,132.88 114.71,132.69 UV7.44 ; v2(228.21,75.33) 228.01,75.14 228.01,74.61 228.16,74.47 229.16,74.47 CV148.1
SW2_DP2_N2_C: length 3.2
  BOTTOM w0.104: JNGFF1.25 232.61,74.65 232.45,74.48 230.75,74.48 CV148.2
SW2_DP2_N3: length 162.3
  IN3 w0.135: v2(113.62,133.67) 113.78,133.51 113.78,132.5 116.13,130.15 120.37,130.15 123.06,127.46 129.35,127.46 131.28,125.53 134.01,125.53 135.24,124.29 149.07,124.29 152.39,120.98 154.42,120.98 161.8,113.6 161.8,111.56 167.26,106.11 167.26,99.41 arc(169.62,87.51) 176.36,77.42 177.16,76.62 arc(185.68,70.94) 195.72,68.94 205.04,68.94 205.72,68.26 219.73,68.26 221.79,70.32 221.79,72.01 223.6,73.81 227.91,73.81 228.98,74.89 228.98,76.16 228.68,76.46 228.43,76.46 v2(228.23,76.66)
  BOTTOM w0.104: v2(113.62,133.67) 113.82,133.48 113.82,133.34 113.61,133.13 113.61,132.8 113.51,132.7 UV7.41 ; v2(228.23,76.66) 228.34,76.55 229.26,76.55 CV145.1
SW2_DP2_N3_C: length 3.4
  BOTTOM w0.104: JNGFF1.19 232.73,76.15 232.58,76 232.49,76 231.98,76.52 231.06,76.52 230.97,76.43 230.77,76.43 CV145.2
SW2_DP2_P0: length 162.2
  TOP w0.104: v2(217.4,70.97) 217.73,70.64 217.73,69.67 218.72,68.67 226.13,68.67 227.09,69.63 228.28,69.63 231.25,72.6 v3(233.06,72.6) 234.99,72.6 CV157.1
  IN3 w0.135: v2(118.81,133.91) 118.58,133.68 118.58,133.48 118.76,133.3 122.69,133.3 123.33,133.93 126.9,133.93 132.75,128.08 138.64,128.08 139.26,128.71 144.63,128.71 146.07,127.26 147.89,127.26 148.5,126.66 150.02,126.66 152.99,123.68 155.17,123.68 164.27,114.58 164.27,112.4 169.56,107.12 169.56,99.4 arc(171.75,88.38) 177.98,79.05 178.66,78.37 arc(186.57,73.09) 195.89,71.23 206.22,71.23 206.91,70.54 217.46,70.54 217.56,70.64 217.56,70.8 v2(217.4,70.97)
  BOTTOM w0.104: v2(118.81,133.91) 118.8,133.91 118.46,133.57 118.46,133.21 118.15,132.9 117.06,132.9 116.99,132.83 116.99,132.73 117.11,132.61 UV7.50
SW2_DP2_P0_C: length 4.9
  TOP w0.104: v2(237.39,72.24) 237.2,72.43 236.77,72.43 CV157.2
  BOTTOM w0.104: JNGFF1.34 240.13,72.4 239.98,72.55 239.55,72.55 239.38,72.38 237.53,72.38 v2(237.39,72.24)
SW2_DP2_P1: length 164.4
  TOP w0.104: v2(218.6,70.97) 218.8,70.78 218.8,70.01 219.44,69.36 225.96,69.36 226.84,70.24 227.74,70.24 228.47,70.98 228.47,72.96 229.75,74.23 235.14,74.23 CV153.1
  IN3 w0.135: v2(218.6,70.97) 218.76,70.82 218.76,70.2 218.41,69.86 206.54,69.86 205.84,70.55 195.85,70.55 arc(186.3,72.45) 178.21,77.86 177.5,78.57 arc(171.11,88.13) 168.87,99.41 168.87,106.81 163.55,112.13 163.55,114.25 154.84,122.96 152.72,122.96 149.75,125.93 147.92,125.93 147.32,126.53 145.37,126.53 145.04,126.86 139.67,126.86 139.15,127.38 132.15,127.38 126.95,132.59 117.68,132.59 117.23,133.04 117.23,133.85 v2(117.4,134.02)
  BOTTOM w0.104: UV7.47 115.91,132.68 115.79,132.8 115.79,133.23 116.11,133.54 116.91,133.54 v2(117.4,134.02)
SW2_DP2_P1_C: length 4.9
  TOP w0.104: v2(237.36,74.01) 237.17,74.21 236.77,74.21 CV153.2
  BOTTOM w0.104: JNGFF1.28 240.16,73.9 240.01,74.05 238.43,74.05 238.27,74.2 237.55,74.2 v2(237.36,74.01)
SW2_DP2_P2: length 159.1
  IN3 w0.135: v2(227.5,75.32) 227.55,75.37 227.66,75.37 227.79,75.24 227.79,75 227.53,74.74 223.16,74.74 220.86,72.44 220.86,70.72 219.33,69.18 206.21,69.18 205.53,69.86 195.74,69.86 arc(186.03,71.79) 177.8,77.29 177.01,78.08 arc(170.48,87.86) 168.18,99.4 168.18,106.51 162.79,111.9 162.79,113.91 154.61,122.1 152.6,122.1 149.46,125.23 135.74,125.23 134.44,126.53 131.78,126.53 129.08,129.23 128.61,129.23 125.96,131.89 116.38,131.89 115.27,133 115.27,133.79 115.36,133.88 v2(115.44,133.88)
  BOTTOM w0.104: v2(227.5,75.32) 227.55,75.37 227.66,75.37 227.81,75.22 227.81,74.53 228.07,74.27 229.16,74.27 CV147.1 ; UV7.45 115.11,133.13 115.26,133.28 115.26,133.83 115.32,133.88 v2(115.44,133.88)
SW2_DP2_P2_C: length 3.2
  BOTTOM w0.104: JNGFF1.27 232.58,74.15 232.45,74.28 230.77,74.28 CV147.2
SW2_DP2_P3: length 162.1
  IN3 w0.135: v2(228.23,76.05) 228.23,76.14 228.31,76.22 228.58,76.22 228.74,76.06 228.74,74.99 227.81,74.05 223.5,74.05 221.55,72.11 221.55,70.42 219.63,68.5 205.82,68.5 205.14,69.18 195.72,69.18 arc(185.77,71.16) 177.33,76.79 176.53,77.6 arc(169.85,87.6) 167.5,99.41 167.5,106.21 162.04,111.66 162.04,113.7 154.52,121.22 152.49,121.22 149.17,124.53 135.34,124.53 134.11,125.77 131.38,125.77 129.45,127.7 123.16,127.7 120.47,130.39 116.23,130.39 114.02,132.6 114.02,133.52 114.17,133.67 v2(114.22,133.67)
  BOTTOM w0.104: v2(114.22,133.67) 114.12,133.67 114.02,133.56 114.02,133.25 113.81,133.05 113.81,132.78 113.91,132.68 UV7.42 ; v2(228.23,76.05) 228.18,75.99 228.18,75.86 228.31,75.73 228.5,75.73 228.64,75.87 228.64,76.24 228.74,76.35 229.16,76.35 229.5,76.01 CV146.1
SW2_DP2_P3_C: length 3.4
  BOTTOM w0.104: JNGFF1.21 232.56,75.65 231.92,76.29 231.12,76.29 231.06,76.23 230.75,76.23 CV146.2
SW2_PS8338_CFG0: length 1.6
  BOTTOM w0.112: UV7.59 119.2,128.34 RV85.1
SW2_PS8338_P0: length 1.8
  BOTTOM w0.112: UV7.60 118.71,127.94 RV95.1
SW2_PS8338_P1: length 4.2
  BOTTOM w0.107: RV94.1 RV93.1 118.73,126.44 v1(118.39,126.1) 117.38,126.1 117.11,126.37 UV7.1
SW2_PS8338_PC10: length 2.7
  BOTTOM w0.112: UV7.56 118.68,129.54 RV90.1 RV91.1
SW2_PS8338_PC11: length 7.9
  BOTTOM w0.112: UV7.55 118.27,129.94 119.48,131.15 120.75,131.15 120.92,131.33 122.4,131.33 RV83.1 RV84.1 124.61,131.82 v1(124.81,132.02)
SW2_PS8338_PC20: length 4.8
  BOTTOM w0.107: RV81.1 RV82.1
  BOTTOM w0.112: UV7.54 118.29,130.34 119.31,131.37 120.66,131.37 RV82.1
SW2_PS8338_PC21: length 2.9
  BOTTOM w0.112: RV80.1 RV79.1 119.34,131.76 118.32,130.74 UV7.53
SW2_PS8338_PEQ: length 4.3
  TOP w0.112: v1(113.3,127.53) 113.55,127.77 RV88.1 RV87.1 114.57,126.15 v2(114.58,126.14)
  BOTTOM w0.107: UV7.8 114.31,126.28 114.45,126.14 v2(114.58,126.14)
SW2_PS8338_SW: length 2.9
  BOTTOM w0.112: RV89.1 108.85,126.19 109.69,126.19 110.31,126.8 UV7.18
SW_+1VALWP: length 2
  TOP w0.102: 159.28,83.7 v1(161.28,83.7)
  vias: v2(157.25,83.01) v2(157.85,83.01)
SW_USB20_N1: length 3.8
  TOP w0.104: v2(277.05,73.13) 276.81,73.37 276.81,73.6 277.01,73.81 UI3.11
  BOTTOM w0.104: LI7.1 277.49,74.26 277.21,74.54 276.82,74.54 276.69,74.41 276.69,73.47 277.04,73.13 v2(277.05,73.13)
SW_USB20_P1: length 3.8
  TOP w0.104: v2(276.46,73.13) 276.6,73.27 276.6,73.67 276.51,73.77 UI3.10
  BOTTOM w0.104: v2(276.46,73.13) v3(276.46,74.12) 276.46,74.46 276.74,74.74 277.47,74.74 LI7.4
SYS_LED_MASK#: length 106.4
  TOP w0.112: RE21.1 245.46,95.38 v1(245.46,94.89) 245.46,94 v2(245.32,93.86) 246.53,92.66 UE1.A12 ; UZ10.1 268.98,84.83 269.17,85.02 269.17,85.48 v2(269.57,85.88)
  IN1 w0.119: v2(245.32,93.86) 245.32,94.16 244.59,94.89 244.59,96.27 245.45,97.13 245.45,104.8 247.24,106.58 247.24,110.06 246.64,110.65 v2(246.64,112.17)
  IN2 w0.124: v2(254.82,128.61) 252.54,126.33 252.54,115.67 254.02,114.18 254.02,112.26 v2(253.81,112.04)
  IN3 w0.135: v2(269.57,85.88) 271.2,85.88 271.91,86.59 271.91,95.82 268.81,98.92 268.81,101.37 265.7,104.48 258.82,104.48 256.92,106.39 256.92,111.11 255.01,113.02 254.18,113.02 253.81,112.65 v2(253.81,112.04)
  BOTTOM w0.112: v2(254.82,128.61) 255.55,128.61 257.14,130.2 QL1.2 257.14,131.84 257.33,132.03 257.33,132.47 257.14,132.66 QL1.5 257.14,133.93 257.45,134.25 258.25,134.25 258.71,133.79 258.71,132.19 258.95,131.95 259.87,131.95 259.99,131.82 QL2.2 ; v2(246.64,112.17) 246.95,112.48 253.38,112.48 v2(253.81,112.04)
SYS_PWROK: length 236.2
  TOP w0.112: v2(232.13,83.27) 233.73,83.27 235.08,84.62 RE56.1 236.27,84.62 v2(236.71,85.06) ; UE1.G4 v2(251.08,85.86) ; v2(225.26,80.29) 224.26,79.28 224.26,77.75 arc(223.06,74.86) 220.18,73.67 218.13,73.67 217.22,74.59 214.5,74.59 210.41,72.13 210.41,71.31 209.29,70.19 195.66,70.19 arc(187.25,71.66) 179.83,75.91 arc(175.62,80.03) 172.26,84.87 arc(169.44,91.87) 168.48,99.35 168.48,105.21 163.42,110.26 163.42,114.51 162.8,115.13 162.8,119.94 164.01,121.14 v4(164.01,121.94) v2(164.01,122.82)
  IN2 w0.124: v2(232.13,83.27) 228.85,83.27 225.87,80.29 v2(225.26,80.29) ; v2(236.71,85.06) 237.27,85.06 237.93,85.72 237.93,87.52 238.77,88.35 240.31,88.35 241.15,87.51 242.39,87.51 242.78,87.12 245.21,87.12 246.07,86.26 250.68,86.26 v2(251.08,85.86) ; v2(89.16,125.64) 90.53,127.01 98.78,127.01 99.06,126.73 103.96,126.73 104.44,127.21 105.92,127.21 106.45,127.75 109.47,127.75 109.62,127.6 119.05,127.6 119.31,127.85 123.18,127.85 123.73,127.3 125.59,127.3 125.98,127.69 130.64,127.69 131.2,127.13 134.16,127.13 136.92,124.37 136.92,120.92 v2(136.47,120.47)
  IN3 w0.135: v2(136.47,120.47) 136.47,119.88 136.82,119.53 148.32,119.53 v2(148.51,119.72)
  BOTTOM w0.076: UC1.B6 129.82,112.59 129.82,112.79 130.02,112.99 131.62,112.99 131.85,113.22
  BOTTOM w0.112: 131.85,113.22 132.66,114.03 132.66,115.86 136.47,119.66 v2(136.47,120.47) ; v2(148.51,119.72) 152.33,123.54 163.28,123.54 v2(164.01,122.82) ; v2(89.16,125.64) 89.37,125.85 RC129.1
SYS_RESET#: length 220.5
  TOP w0.112: JAPS1.13 v2(258.56,109.33)
  IN1 w0.119: v2(226.05,85.84) 226.05,83.77 223.52,81.24 223.52,75.75 221.83,74.06 216.6,74.06 v2(215.59,75.07)
  BOTTOM w0.076: 133.12,111.64 132.76,112 132.21,112 132,111.8 131.72,111.8 131.52,112 130.58,112 130.15,112.43 UC1.B5
  BOTTOM w0.112: v2(215.59,75.07) 215.26,75.07 213.38,73.95 211.28,72.99 209.52,72.35 209.52,71.44 209.27,71.18 185.95,71.18 170.94,86.19 170.94,90.82 168.8,92.96 168.8,101.49 166.79,103.5 166.79,106.74 166.01,107.52 166.01,109.07 164.22,110.86 164.22,120.17 162.14,122.25 154.01,122.25 152.55,120.79 152.55,117.76 153.27,117.04 153.27,113.62 152.35,112.7 150.89,112.7 150.61,112.42 149.71,112.42 149.05,113.08 RC224.2 148.27,114.45 CC302.1 RC291.1 v1(146.68,115.31) 146.66,115.31 144.07,117.91 138.43,117.91 135.51,114.98 135.51,112.51 134.64,111.64 133.12,111.64 ; v2(226.05,85.84) 228.61,88.41 228.61,96.5 228.88,96.77 228.88,106.85 230.12,108.08 231.63,108.08 235.06,111.52 236.38,111.52 236.92,112.06 236.92,113.2 237.07,113.35 239.81,113.35 243.94,109.22 250.35,109.22 251.31,108.27 253.88,108.27 254.52,108.9 258.13,108.9 v2(258.56,109.33)
SYS_RESET#_R: length 3.3
  BOTTOM w0.112: RC290.2 RC224.1 ; RC224.1 149.96,113.05 v1(150.25,112.75) ; RC224.1 149.96,114.56 149.85,114.68 UC12.4
TBT_FORCE_PWR: length 5.1
  BOTTOM w0.112: T19.1 131.14,116.6 130.25,115.71 130.25,115.2 128.6,113.55 128.6,112.96 UC1.B7
TBT_RESET_N_EC_R: length 10.8
  TOP w0.107: UE1.L8 v2(255.08,89.86)
  TOP w0.112: v1(259.97,91.25) 260.15,91.07 260.88,91.07 v2(261.29,91.48) 261.71,91.9 RE95.2
  IN3 w0.135: v2(255.08,89.86) 255.29,89.86 255.84,90.41 256.21,90.41 258.41,92.61 260.16,92.61 v2(261.29,91.48)
TBTA_AUXN_C: length 6
  TOP w0.076: 29.18,84.32 29.19,84.31 29.22,84.31 29.77,83.75 29.77,83.23 UT5.J2
  TOP w0.112: 29.18,84.32 28.81,84.68 v3(28.81,85) 28.81,85.36 28.55,85.63 28.55,86.55 28.41,86.69 28.41,86.96 RT95.1 28.28,87.44 CT81.2
TBTA_AUXP_C: length 5.4
  TOP w0.076: 29.36,84.51 29.38,84.49 29.38,84.47 30,83.85 30,83.5 UT5.J1
  TOP w0.112: CT80.2 28.85,87.37 RT96.1 28.67,86.97 28.67,86.8 28.81,86.66 v3(28.81,86.29) 28.81,85.74 29.08,85.47 29.08,84.79 29.36,84.51
TBTA_BOT_N: length 44.6
  TOP w0.076: UT5.L7 28.68,80.47 28.61,80.54 28.16,80.54 27.98,80.37 27.96,80.37
  TOP w0.112: 27.96,80.37 v2(27.76,80.16)
  IN1 w0.119: v2(27.76,80.16) 27.83,80.16 28.15,79.84 28.15,79.71 26.02,77.58 19.79,77.58 16.66,80.71 16.66,96.84 15.51,97.99 15.51,98.33 15.67,98.49 15.67,98.5 v2(15.84,98.66)
  IN2 w0.124: v2(15.84,98.66) 15.67,98.83 15.67,98.84 15.57,98.94 15.57,99.63 15.82,99.88 15.82,103.55 16.35,104.08 16.35,104.09 17.04,104.79 v2(17.04,106.23)
  BOTTOM w0.112: v2(17.04,106.23) 16.89,106.38 16.89,106.58 16.58,106.89 15.84,106.89 RT122.2
TBTA_BOT_N_R: length 8.7
  BOTTOM w0.112: JUSBC1.B7 6.8,107.35 v3(9.66,107.35) 10.42,107.35 10.65,107.11 12.2,107.11 12.49,106.83 13.65,106.83 DT20.1 14.09,106.82 14.37,106.82 RT122.1
TBTA_BOT_P: length 44.6
  TOP w0.076: UT5.K7 29.37,80.47 29.12,80.22 28.88,80.22 28.66,80.01 28.48,80.01 28.4,80.08 v2(28.4,80.18)
  IN1 w0.119: v2(28.4,80.18) 28.4,79.61 26.13,77.33 19.68,77.33 16.41,80.6 16.41,96.73 15.25,97.88 v2(15.25,98.66)
  IN2 w0.124: v2(15.25,98.66) 15.25,98.95 15.28,98.97 15.28,99.76 15.52,100 15.52,103.67 16.05,104.21 16.05,104.21 16.74,104.91 16.74,105.66 v2(16.6,105.8)
  BOTTOM w0.112: v2(16.6,105.8) 16.63,105.84 16.63,106.47 16.47,106.62 15.97,106.62 RT123.2
TBTA_BOT_P_R: length 8.7
  BOTTOM w0.112: RT123.1 14.37,106.56 14.09,106.56 DT19.1 13.64,106.56 v3(12.67,106.56) 12.38,106.56 12.09,106.85 10.54,106.85 10.31,107.08 6.93,107.08 JUSBC1.B6
TBTA_CC1: length 53.6
  TOP w0.127: UT5.L9 28.97,79.43 28.57,79.43 28.4,79.26
  TOP w0.203: RT104.2 25.92,78.74 26.25,79.07 28.21,79.07 28.4,79.26
  TOP w0.305: v2(21.23,78.24) 21.23,78.31 21.95,79.03 v1(22.48,79.03) 24.64,79.03 25.06,78.61 CT86.1 25.79,78.43 RT104.2 ; v2(13.21,107.52) 12.74,107.52 DT7.1 10.72,107.68 10.5,107.9 JUSBC1.A5
  IN2 w0.305: v2(13.21,107.52) 12.98,107.29 12.98,99.73 v2(13.18,99.53)
  IN3 w0.305: v2(13.18,99.53) 12.7,99.05 12.7,95.72 13.82,94.6 13.82,78.07 15.19,76.69 18.92,76.69 19.96,77.73 20.92,77.73 21.23,78.05 v2(21.23,78.24)
TBTA_CC2: length 55.5
  TOP w0.203: UT5.L10 28.8,78.97 27.88,78.05 26.19,78.05 25.92,77.79 RT105.2
  TOP w0.305: v2(21.87,78.24) 21.87,77.94 v4(22.77,77.04) 22.9,76.91 24.53,76.91 25.06,77.43 CT85.1 RT105.2
  IN2 w0.305: v2(15.33,104.51) 13.89,103.07 13.89,100.39 14.55,99.73 14.55,99.27 v2(14.04,98.77)
  IN3 w0.305: v2(21.87,78.24) 21.87,78.47 20.9,79.44 20.19,79.44 18.44,77.68 15.59,77.68 14.74,78.53 14.74,94.95 14.73,94.96 14.73,95.18 14.04,95.87 v2(14.04,98.77)
  BOTTOM w0.127: 7.09,106.27 5.88,106.27 JUSBC1.B5
  BOTTOM w0.305: v2(15.33,104.51) 15.2,104.63 DT16.1 13.26,104.63 11.64,106.25 10.25,106.25 10.06,106.44 7.25,106.44 7.09,106.27
TBTA_DBG_CTL1: length 5.8
  TOP w0.076: UT5.E4 32.02,82.38 v2(32.1,82.46)
  BOTTOM w0.112: RT106.1 29.74,85.79 29.74,84.28 30.25,83.77 31.46,83.77 32.1,83.12 v1(32.1,82.97) v2(32.1,82.46)
TBTA_DBG_CTL2: length 2.3
  TOP w0.076: UT5.D5 32.95,81.9 v2(32.99,81.9)
  BOTTOM w0.102: RT107.1 v1(34.62,81.91)
  BOTTOM w0.112: RT107.1 33.6,81.9 v2(32.99,81.9)
TBTA_DEBUG1: length 5.3
  TOP w0.076: UT5.L2 28.95,83.05 28.44,83.05 27.93,83.56
  TOP w0.112: 27.93,83.56 27.09,84.4 25.92,84.4 RT92.2 v1(24.5,84.9)
TBTA_DEBUG2: length 4.1
  TOP w0.076: UT5.K2 29.27,83.22 28.55,83.22 28.12,83.65 28.12,83.75 27.93,83.94
  TOP w0.112: 27.93,83.94 27.21,84.66 26.55,84.66 RT93.2
TBTA_DEBUG3: length 3.3
  TOP w0.076: 27.93,82.88 27.96,82.84 28.14,82.84 28.3,82.69 28.7,82.69 28.84,82.55 28.95,82.55 UT5.L3
  TOP w0.112: RT89.2 26.33,83.2 27.61,83.2 27.93,82.88
TBTA_DEBUG4: length 4
  TOP w0.076: UT5.K3 29.27,82.72 28.92,82.72 28.77,82.87 28.37,82.87 28.22,83.02 28.1,83.02 27.93,83.2
  TOP w0.112: RT90.2 v1(27.11,83.89) 27.23,83.89 27.93,83.2
TBTA_LSRX_R: length 5.5
  TOP w0.076: 27.53,82.58 27.98,82.58 28.04,82.51 28.63,82.51 28.77,82.37 28.77,82.37 28.92,82.22 29.27,82.22 UT5.K4
  TOP w0.112: 27.53,82.58 v3(27.27,82.58) 26.65,82.58 26.32,82.24 24.61,82.24 RT88.2
TBTA_LSTX_R: length 5.2
  TOP w0.076: UT5.L4 29,81.99 28.82,81.99 28.68,82.14 28.68,82.14 28.53,82.28 27.95,82.28 27.88,82.35 27.65,82.35 27.63,82.33 27.56,82.33 27.54,82.31 27.53,82.31
  TOP w0.112: 27.53,82.31 26.76,82.31 26.43,81.98 v3(25.64,81.98) 25.24,81.98 RT87.2
TBTA_MRESET: length 3.5
  TOP w0.076: UT5.E11 32.02,77.31
  TOP w0.112: v1(32.92,75.61) 32.6,75.61 31.9,76.31 RT86.1 31.96,76.41 31.96,77.21 32.02,77.27 32.02,77.31
TBTA_RESET_N_EC_R: length 2.4
  TOP w0.076: UT5.F11 31.52,77.49 31.34,77.31
  TOP w0.112: 31.34,77.31 31.3,77.27 31.3,77.27 30.88,76.86 RT110.2
TBTA_ROM_CLK_PD: length 21.2
  TOP w0.112: v2(36.55,83.2) 35.91,82.56 35.1,82.56 35.04,82.5 34.04,82.5 UT5.A3 ; v2(28.6,71.77) 28.97,71.77 RT54.2
  IN1 w0.119: v2(36.55,83.2) 36.03,83.2 35.25,82.42 35.25,75.88 33.87,74.5 32.6,74.5 32.19,74.09 31.23,74.09 30.86,73.72 29.33,73.72 28.43,72.82 28.43,72.82 28.18,72.57 28.18,72.57 28.14,72.53 28.14,72.22 v2(28.6,71.77)
TBTA_ROM_CLK_PD_R: length 10.2
  TOP w0.112: v2(31.1,71.51) RT54.1
  BOTTOM w0.112: JDB1.2 29.88,68.21 29.42,68.67 29.42,71.19 29.74,71.51 v2(31.1,71.51) 31.48,71.13 v1(33.74,71.13)
TBTA_ROM_CS#_PD: length 26.9
  TOP w0.076: UT5.B3 33.77,82.72 34.65,82.72 34.71,82.78 35.11,82.78
  TOP w0.112: v2(27.48,67.87) 27.48,67.98 27.98,68.48 RT57.2 ; v2(36.55,83.78) 36.09,83.32 36.09,83.09 35.77,82.78 35.11,82.78
  IN1 w0.119: v2(27.48,67.87) 27.48,72.3 28.13,72.95 28.14,72.95 28.38,73.19 28.38,73.2 29.19,74 30.76,74 31.1,74.34 32.07,74.34 32.47,74.75 33.72,74.75 35,76.03 35,82.8 35.98,83.78 v2(36.55,83.78)
TBTA_ROM_CS#_PD_R: length 7.8
  TOP w0.112: RT51.2 RT57.1 26.55,68.59 v2(26.12,69.02)
  BOTTOM w0.112: UT6.1 25.91,68.59 26.12,68.81 v2(26.12,69.02) 27.79,69.02 28.6,68.21 28.6,67.45 28.38,67.23 JDB1.5
TBTA_ROM_DI_PD: length 19.9
  TOP w0.076: 35.11,82.18 34.46,82.18 34.42,82.22 33.77,82.22 UT5.B4
  TOP w0.112: RT55.2 v2(28.6,72.4) ; v2(36.55,82.61) 36.46,82.61 36.03,82.18 v1(35.56,82.18) 35.11,82.18
  IN1 w0.119: v2(36.55,82.61) 36.02,82.61 35.51,82.1 35.51,75.75 34,74.24 32.73,74.24 32.32,73.84 31.33,73.84 29.89,72.4 v2(28.6,72.4)
TBTA_ROM_DI_PD_R: length 9.3
  TOP w0.112: v2(31.09,72.21) 30.9,72.4 RT55.1
  BOTTOM w0.112: UT6.5 31.28,72.4 v2(31.09,72.21) 30.06,72.21 29.17,71.32 29.17,68.53 29.38,68.32 JDB1.3
TBTA_ROM_DO_PD: length 19.4
  TOP w0.102: UT5.A4 34.32,81.97 34.44,81.85 36.28,81.85 36.46,82.03 v2(36.55,82.03)
  TOP w0.112: v2(28.6,71.13) 28.29,71.13 RT56.2
  IN1 w0.119: v2(36.55,82.03) 36.1,82.03 35.76,81.69 35.76,75.65 34.1,73.99 32.85,73.99 32.41,73.54 31.39,73.54 28.98,71.13 v2(28.6,71.13)
TBTA_ROM_DO_PD_R: length 8.8
  TOP w0.112: v2(26.1,70.39) 26.2,70.5 RT52.2 RT56.1
  BOTTOM w0.112: UT6.2 25.93,69.86 26.1,70.03 v2(26.1,70.39) 26.2,70.5 26.71,70.5 28.88,68.33 JDB1.4
TBTA_ROM_HOLD#_PD: length 3.1
  TOP w0.112: v2(31.1,70.81) 30.78,70.5 RT50.2
  BOTTOM w0.112: v2(31.1,70.81) 31.1,70.15 31.39,69.86 UT6.7
TBTA_ROM_WP#_PD: length 2.8
  TOP w0.112: v2(26.07,71.82) 26.66,72.4 RT53.2
  BOTTOM w0.112: 25.04,71.13 25.83,71.13 26.07,71.37 v2(26.07,71.82)
TBTA_ROSC: length 3.3
  TOP w0.076: 30.86,84.51 30.86,84.24 30.77,84.15 30.77,83.22 UT5.G2
  TOP w0.112: 30.86,84.51 30.86,84.75 30.43,85.18 v2(30.43,85.29)
  BOTTOM w0.112: RT100.1 30.43,85.96 v2(30.43,85.29)
TBTA_RX1N: length 22.2
  TOP w0.175: UT9.31 25.45,105.3 arc(25.28,105.34) 25.12,105.36 24.86,105.36 arc(24.4,105.45) 24.02,105.71 23.16,106.56 arc(22.79,106.81) 22.35,106.9 20.56,106.9 arc(20.39,106.87) v2(20.24,106.77)
  BOTTOM w0.175: JUSBC1.B10 arc(6.03,108.96) 6.34,109.04 6.95,109.04 arc(7.2,109.09) 7.41,109.24 7.5,109.32 arc(7.61,109.4) 7.75,109.42 10.13,109.42 arc(10.4,109.48) 10.62,109.63 10.78,109.78 arc(10.94,109.89) 11.12,109.92 11.28,109.92 arc(11.47,109.89) 11.63,109.78 DT14.1 11.77,109.76 arc(11.96,109.89) 12.2,109.94 14.96,109.94 arc(15.65,109.8) 16.24,109.4 18.41,107.23 arc(18.74,107.01) 19.13,106.94 19.91,106.94 arc(20.1,106.89) v2(20.24,106.77)
TBTA_RX1P: length 22.2
  TOP w0.175: UT9.30 25.42,105.7 arc(25.26,105.64) 25.09,105.62 24.86,105.62 arc(24.51,105.69) 24.21,105.89 23.35,106.75 arc(22.89,107.06) 22.35,107.17 20.61,107.17 arc(20.44,107.2) 20.29,107.3 v2(20.24,107.35)
  BOTTOM w0.175: JUSBC1.B11 arc(6.01,109.37) 6.28,109.31 6.95,109.31 arc(7.1,109.34) 7.23,109.42 7.31,109.51 arc(7.51,109.64) 7.75,109.69 10.13,109.69 arc(10.3,109.72) 10.44,109.82 10.59,109.97 arc(10.83,110.13) 11.12,110.19 11.38,110.19 arc(11.48,110.21) 11.55,110.26 DT13.1 arc(11.91,110.26) 12.15,110.2 14.96,110.2 arc(15.75,110.04) 16.43,109.59 18.6,107.42 arc(18.84,107.26) 19.13,107.2 19.91,107.2 arc(20.09,107.24) v2(20.24,107.35)
TBTA_RX2N: length 21.5
  TOP w0.175: JUSBC1.A10 8.27,105.4 8.28,105.4 arc(8.41,105.31) 8.56,105.28 9.44,105.28 arc(9.95,105.07) 10.16,104.57 10.16,103.69 arc(10.28,103.39) 10.59,103.27 11.28,103.27 arc(11.41,103.29) 11.52,103.37 DT9.1 11.74,103.4 arc(11.89,103.3) 12.06,103.26 15.16,103.26 15.59,103.29 arc(15.97,103.47) 16.26,103.76 arc(16.73,104.2) 17.35,104.35 18.53,104.35 arc(19.33,104.02) 19.66,103.23 19.66,102.95 arc(19.93,102.3) 20.58,102.03 25.19,102.03 arc(25.31,102.05) 25.43,102.1 UT9.39
TBTA_RX2P: length 21.4
  TOP w0.175: UT9.40 25.41,101.7 arc(25.3,101.75) 25.17,101.76 20.58,101.76 arc(19.74,102.11) 19.39,102.95 19.39,103.23 arc(19.14,103.84) 18.53,104.09 17.35,104.09 arc(16.85,103.96) 16.48,103.62 16.48,103.61 arc(16.11,103.24) 15.64,103.03 15.17,103 12.17,103 arc(11.89,102.94) DT10.1 11.52,102.9 arc(11.47,102.94) 11.42,102.97 arc(11.35,103) 11.28,103 10.59,103 arc(10.1,103.21) 9.89,103.69 9.89,104.57 arc(9.76,104.89) 9.44,105.02 8.56,105.02 arc(8.44,105) 8.35,104.93 8.32,104.9 JUSBC1.A11
TBTA_SBU1: length 66.3
  TOP w0.112: v2(20.6,78.24) 21.72,79.36 25.2,79.36 25.41,79.58 RT108.2 ; JUSBC1.A8 8.52,106.4 8.58,106.34 10.01,106.34 10.21,106.13 11.82,106.13 v1(13.02,104.94) 14.02,104.94 14.32,104.63 DT8.1 14.86,104.63 v2(15.33,105.1) ; v2(24.6,111.02) RT132.2
  IN2 w0.124: v2(14.04,99.5) 14.04,99.71 13.55,100.2 13.55,103.33 v2(15.33,105.1) 15.33,105.74 14.4,106.67 14.4,108.62 15.04,109.26 18.57,109.26 20.33,111.02 v2(24.6,111.02)
  IN3 w0.135: v2(20.6,78.24) 19.96,78.24 18.77,77.05 15.31,77.05 14.18,78.18 14.18,94.71 13.05,95.85 13.05,98.51 v2(14.04,99.5)
TBTA_SBU1_R: length 2.9
  TOP w0.076: 27.93,79.51 28.37,79.51 28.48,79.63 28.79,79.63 28.89,79.72 29.27,79.72 UT5.K8
  TOP w0.112: 27.93,79.51 26.9,79.51 RT108.1
TBTA_SBU2: length 66.3
  TOP w0.112: RT133.2 25.63,111.64 v2(24.6,111.64) ; RT109.2 25.04,79.59 21.31,79.59 v1(21.07,79.35) v2(20.6,78.88)
  IN2 w0.124: v2(24.6,111.64) 20.55,111.64 18.43,109.52 14.63,109.52 v2(13.21,108.1) 13.28,108.1 13.65,107.73 13.65,107.3 13.3,106.94 13.3,100.05 13.61,99.73 13.61,99.2 13.55,99.13 v2(13.55,98.4)
  IN3 w0.135: v2(20.6,78.88) 20.14,78.88 18.62,77.35 15.47,77.35 14.42,78.4 14.42,94.81 14.4,94.83 14.4,94.96 13.55,95.81 v2(13.55,98.4)
  BOTTOM w0.112: JUSBC1.B8 5.87,108.02 7.07,108.02 7.19,107.91 10.62,107.91 10.84,107.68 DT15.1 12.79,107.68 v2(13.21,108.1)
TBTA_SBU2_R: length 2.6
  TOP w0.076: UT5.L8 28.88,79.97 28.71,79.81 28.41,79.81 28.37,79.77 27.93,79.77
  TOP w0.112: 27.93,79.77 27.53,79.77 RT109.1
TBTA_TOP_N: length 45.6
  TOP w0.076: UT5.L6 29,80.95 27.82,80.95 27.72,80.95
  TOP w0.112: 27.72,80.95 27.36,81.3 25.44,81.3 24.8,80.66 24.22,80.66 23.77,80.21 v2(23.77,80.2) ; RT121.1 15.77,106.42 16.5,106.42 16.77,106.68 16.77,107.05 v2(16.93,107.21)
  IN1 w0.119: v2(16.73,98.82) 16.73,98.81 17.3,98.25 17.3,81.82 19.79,79.32 22.3,79.32 23.81,80.83 24.06,80.83 24.15,80.74 24.15,80.54 23.82,80.2 v2(23.77,80.2)
  IN2 w0.124: v2(16.73,98.82) 16.73,98.82 17.02,99.11 17.02,103.81 17.93,104.72 17.93,107.28 17.37,107.83 16.7,107.83 16.55,107.69 16.55,107.56 16.9,107.21 v2(16.93,107.21)
TBTA_TOP_N_R: length 7.4
  TOP w0.112: RT121.2 14.37,106.56 14.09,106.56 DT12.1 13.65,106.55 v3(12.9,106.55) 12.36,106.55 12.18,106.73 10.33,106.73 10.04,107.02 8.6,107.02 8.48,106.9 JUSBC1.A7
TBTA_TOP_P: length 45.6
  TOP w0.076: 27.53,80.76 27.54,80.76 27.56,80.76 27.6,80.72 27.86,80.72 29.27,80.72 UT5.K6
  TOP w0.112: v2(24.41,80.2) 24.41,80.28 24.52,80.39 24.91,80.39 25.55,81.04 27.26,81.04 27.53,80.76 ; RT120.1 15.59,107.03 15.94,106.68 16.39,106.68 16.5,106.79 16.5,107.01 v2(16.22,107.3)
  IN1 w0.119: v2(24.41,80.2) 24.41,80.85 24.17,81.09 23.71,81.09 22.2,79.58 19.9,79.58 17.55,81.93 17.55,98.35 v2(17.31,98.82)
  IN2 w0.124: v2(17.31,98.82) 17.31,103.68 18.23,104.6 18.23,107.4 17.5,108.13 16.58,108.13 16.25,107.81 16.25,107.33 v2(16.22,107.3)
TBTA_TOP_P_R: length 7.4
  TOP w0.112: JUSBC1.A6 8.48,107.4 8.6,107.28 10.15,107.28 10.44,107 v3(11.58,107) 12.29,107 12.47,106.82 13.64,106.82 DT11.1 14.09,106.82 14.37,106.82 RT120.2
TBTA_TX1N: length 4.7
  TOP w0.175: UT9.34 25.34,104.1 arc(25.26,104.15) 25.17,104.16 24.3,104.16 arc(23.9,104.24) 23.56,104.47 23.02,105.01 arc(22.82,105.15) 22.58,105.19 21.74,105.19 arc(21.55,105.16) CT96.1
TBTA_TX1N_C: length 17.2
  TOP w0.175: JUSBC1.A3 8.25,108.9 8.29,108.94 arc(8.38,109) 8.48,109.02 9.48,109.02 arc(9.81,109.08) 10.09,109.27 10.57,109.76 arc(10.76,109.88) 10.98,109.92 11.25,109.92 arc(11.47,109.88) 11.65,109.76 DT6.1 11.77,109.76 arc(11.95,109.88) 12.17,109.92 16.74,109.92 arc(17.65,109.54) 18.03,108.63 18.03,106.48 arc(18.4,105.58) 19.3,105.21 20.44,105.21 arc(20.64,105.17) CT96.2
TBTA_TX1P: length 4.7
  TOP w0.175: CT95.1 21.44,105.58 arc(21.58,105.49) 21.74,105.46 22.58,105.46 arc(22.92,105.39) 23.21,105.2 23.75,104.66 arc(24,104.49) 24.3,104.43 25.17,104.43 arc(25.26,104.45) 25.34,104.5 UT9.33
TBTA_TX1P_C: length 17.1
  TOP w0.175: JUSBC1.A2 8.24,109.4 8.27,109.37 arc(8.36,109.31) 8.48,109.28 9.48,109.28 arc(9.71,109.33) 9.9,109.46 10.39,109.94 arc(10.66,110.12) 10.98,110.19 11.25,110.19 arc(11.47,110.23) 11.65,110.35 DT5.1 11.77,110.35 arc(11.95,110.23) 12.17,110.19 16.74,110.19 arc(17.84,109.73) 18.3,108.63 18.3,106.48 arc(18.59,105.77) 19.3,105.47 20.44,105.47 arc(20.64,105.51) CT95.2
TBTA_TX2N: length 4.7
  TOP w0.175: UT9.36 25.44,103.3 arc(25.3,103.25) 25.15,103.23 23.75,103.23 arc(23.52,103.27) 23.33,103.4 23.3,103.43 23.19,103.54 arc(22.97,103.69) 22.71,103.74 22.45,103.74 arc(22.29,103.77) 22.16,103.86 v2(22.12,103.9)
  BOTTOM w0.175: CT98.1 arc(21.51,103.79) 21.66,103.74 21.87,103.74 arc(22.02,103.79) v2(22.12,103.9)
TBTA_TX2N_C: length 17.4
  BOTTOM w0.175: JUSBC1.B3 arc(6.08,105.32) 6.42,105.24 7.28,105.24 arc(7.9,105.12) 8.42,104.77 9.67,103.52 arc(9.95,103.34) 10.27,103.27 11.21,103.27 arc(11.45,103.33) DT18.1 11.72,103.41 arc(11.88,103.3) 12.07,103.26 arc(12.08,103.26) 12.09,103.26 14.68,103.26 arc(14.84,103.29) 14.98,103.39 arc(15.35,103.63) 15.78,103.72 15.91,103.72 arc(16.28,103.79) 16.59,104 17.39,104.8 arc(17.68,105) 18.03,105.07 19.02,105.07 arc(19.69,104.79) 19.96,104.13 19.96,104.1 arc(20.07,103.85) 20.32,103.74 20.51,103.74 arc(20.68,103.78) CT98.2
TBTA_TX2P: length 4.7
  TOP w0.175: v2(22.12,103.31) 22.19,103.38 arc(22.29,103.45) 22.42,103.47 22.71,103.47 arc(22.87,103.44) 23,103.35 23.12,103.24 23.14,103.22 arc(23.42,103.03) 23.75,102.96 23.75,102.96 25.15,102.96 arc(25.3,102.95) 25.44,102.9 UT9.37
  BOTTOM w0.175: CT97.1 arc(21.53,103.44) 21.69,103.48 21.86,103.48 arc(22.01,103.44) v2(22.12,103.31)
TBTA_TX2P_C: length 17.4
  BOTTOM w0.175: CT97.2 arc(20.67,103.44) 20.49,103.48 20.32,103.48 arc(19.88,103.66) 19.7,104.1 19.7,104.13 arc(19.5,104.6) 19.02,104.8 18.03,104.8 arc(17.78,104.75) 17.57,104.61 16.78,103.82 arc(16.38,103.55) 15.91,103.45 15.78,103.45 arc(15.45,103.39) 15.17,103.2 arc(14.95,103.05) 14.68,103 12.09,103 arc(11.88,102.96) 11.7,102.84 DT17.1 arc(11.52,102.94) 11.33,103.01 10.27,103.01 arc(9.85,103.09) 9.48,103.33 8.24,104.58 arc(7.8,104.88) 7.28,104.98 6.26,104.98 arc(6,104.92) JUSBC1.B2
TDI_XDP: length 17.5
  TOP w0.112: v2(80.77,120.48) 80.77,120.54 82.51,122.28 v1(82.51,122.87) 82.51,123.91 83.61,125.01 84.44,125.01 87.25,127.82 87.25,130.45 87.01,130.69 v2(87.01,132.22)
  BOTTOM w0.112: UC8.5 80.8,120.57 80.77,120.54 v2(80.77,120.48) 80.67,120.37 RC229.1 ; JXDP1.56 v2(87.01,132.22)
TDO_XDP: length 19.8
  TOP w0.112: v2(88.21,132.22) 88.21,131.16 CC306.1 87.68,130.54 87.68,129.78 87.98,129.48 89.16,129.48 89.55,129.09 89.55,128.44 89.08,127.97 88.06,127.97 84.48,124.38 84.48,121.54 v4(84.04,121.11) 83.39,120.45 v2(82.89,120.45)
  BOTTOM w0.112: UC8.2 82.3,120.93 82.72,120.52 82.83,120.52 v2(82.89,120.45) RC230.1 ; JXDP1.52 v2(88.21,132.22)
THERMATRIP1#: length 4.1
  TOP w0.107: UE1.B12 247.08,93.06 247.08,93.69 246.66,94.12 246.66,95.11 v1(246.73,95.18) 246.94,95.39 246.94,95.97 RE301.1
THERMATRIP2#: length 36.5
  TOP w0.107: UE1.H3 v2(252.68,85.06)
  TOP w0.112: CE36.1 v1(267.03,102.96) ; CE36.1 QE4.1 v2(263.42,101.86) ; CE36.1 RE69.2
  IN1 w0.119: v2(252.68,85.06) 252.22,85.52 252.22,92.37 252.73,92.87 252.73,96.23 253.11,96.61 253.11,98.84 252.82,99.13 252.82,102.26 254.84,104.28 261.01,104.28 v2(263.42,101.86)
TOUCH_SCREEN_DET#: length 159.3
  TOP w0.112: v2(63.78,123.28) 63.78,122.74 63.54,122.5 v1(63.42,122.5) 62.94,122.5 61.76,123.68 61.76,132.83 62.14,133.21 63.99,133.21 64.32,132.88 65.53,132.88 RV8.1 66.51,133.86 v2(66.75,133.86)
  IN1 w0.119: v2(136.04,89.42) 136.61,88.85 136.61,88.02 138.26,86.37 138.26,81.74 138.39,81.61 138.39,80.97 137.95,80.53 137.46,80.53 135.71,78.78 131.72,78.78 131.47,79.03 131.47,81.52 131.13,81.86 126.89,81.86 122.31,77.28 87.22,77.28 79.16,85.34 74.84,85.34 v2(74.26,85.93)
  IN2 w0.124: v2(74.26,85.93) 74.26,93.19 73.35,94.09 73.35,103.31 72.49,104.18 71.52,104.18 70.76,104.94 70.76,111.01 70.31,111.47 62.56,111.47 60.67,113.36 60.67,115.33 62,116.66 62,119.39 63.78,121.17 v2(63.78,123.28)
  BOTTOM w0.076: 135.54,89.42 135.02,89.42 134.34,90.11 130.78,90.11 130.3,90.59 130.3,90.97 130.15,91.12 130.15,91.63 129.76,92.01 UC1.AY5
  BOTTOM w0.112: JEDP1.32 v2(66.75,133.86) ; 135.54,89.42 v2(136.04,89.42)
TOUCH_SCREEN_PD#: length 105.6
  IN2 w0.124: v2(64.41,123.28) 65.43,122.26 70.28,122.26 71.67,120.87 81.67,120.87 82.9,122.11 86.61,122.11 86.71,122.01 88.62,122.01 89.51,122.9 97.79,122.9 98.83,123.94 102.67,123.94 103.76,122.85 111.12,122.85 111.4,123.12 117.04,123.12 118.47,124.55 119.71,124.55 120.53,123.73 130.15,123.73 130.47,124.04 131.77,124.04 132.1,123.72 132.1,122.33 130.83,121.07 130.83,118.72 v2(131.39,118.17)
  BOTTOM w0.102: 131.13,115.73 128.89,113.49 UC1.A7
  BOTTOM w0.107: v2(64.41,123.28) 62.89,124.8 54.94,124.8 53.63,126.11 53.63,129.51 53.3,129.84 53.3,131.8 53.25,131.85 JEDP1.5
  BOTTOM w0.112: 131.13,115.73 131.13,116.16 132.66,117.69 v1(132.66,117.97) RC272.1 132.38,118.95 131.6,118.17 v2(131.39,118.17)
TOUCHPAD_INTR#: length 159.1
  TOP w0.112: RC414.1 135.72,85.86 v2(132.7,88.88) ; v2(249.52,74.23) RE318.2
  IN2 w0.124: v2(248.28,69.99) 248.08,69.78 245.8,69.78 245.38,69.37 244.49,69.37 243.18,68.05 243.18,65.91 241.4,64.13 237.15,64.13 235.89,62.87 218.59,62.87 217.88,62.17 216.32,62.17 v2(215.91,62.57) 215.27,63.21 204.68,63.21 203.46,64.43 184.63,64.43 182.65,66.4 175.73,66.4 172.33,69.8 162.09,69.8 160.73,71.16 151.78,71.16 149.83,73.11 149.83,80.43 146.31,83.95 146.31,86.64 144.92,88.04 139.22,88.04 138.35,88.91 137.31,88.91 137.06,88.66 132.93,88.66 v2(132.7,88.88)
  IN3 w0.135: v2(248.28,69.99) 249.52,71.22 v2(249.52,74.23)
  BOTTOM w0.102: UC1.BA5 129.82,91.26 129.58,91.02 129.58,90.52 130.36,89.74 131.85,89.74 v2(132.7,88.88)
  BOTTOM w0.112: JKBTP1.5 212.05,60.34 214.29,62.57 v2(215.91,62.57)
TP_LAN_JTAG_TCK: length 4.2
  TOP w0.112: v2(242.58,130.64) 242.58,130.33 v1(242.74,130.16) 244.29,130.16 244.48,129.97 UL1.35
  BOTTOM w0.112: RL2.1 242.97,130.25 v2(242.58,130.64)
TP_LAN_JTAG_TDI: length 5.6
  TOP w0.112: UL1.32 245.68,129.39 245.51,129.55 245.51,130.76 243.57,132.7 T88.1
TP_LAN_JTAG_TDO: length 3.5
  TOP w0.112: T89.1 243.1,131.37 244,130.47 244.35,130.47 244.88,129.93 UL1.34
TP_LAN_JTAG_TMS: length 4.3
  TOP w0.112: v2(244.88,130.57) 245.2,130.25 245.2,129.49 245.28,129.41 UL1.33
  BOTTOM w0.112: v1(244.13,129.3) 244.88,130.05 v2(244.88,130.57) 244.88,130.81 RL1.1
TPM_GPIO4: length 1.6
  BOTTOM w0.112: T283.1 162.96,109.72 UZ12.13
TPM_LPM#: length 15.6
  TOP w0.112: v2(155.55,104.01) 155.55,105.12 156.3,105.87 156.3,107.01 156.82,107.53 156.82,111.82 v2(158.49,113.48)
  BOTTOM w0.112: UZ12.3 158.33,113.32 v2(158.49,113.48) 158.82,113.82 RZ363.2 RZ111.1 ; QZ9.1 155.11,103.57 v2(155.55,104.01)
TPM_PIRQ#: length 48.9
  IN3 w0.135: v2(128.38,95.26) 131.33,95.26 132.15,94.44 146.89,94.44 147.18,94.16 148.1,94.16 148.36,94.42 v2(148.36,94.73) ; v2(159.04,102.78) 156.06,102.78 154.53,104.3 153.06,104.3 152.79,104.58 v2(151.43,104.58)
  BOTTOM w0.076: UC1.AP8 127.93,95.71 v2(128.38,95.26)
  BOTTOM w0.112: v2(159.04,102.78) 160.64,102.78 161.43,103.57 161.43,105.09 RZ69.2 161.47,106.07 160.77,106.07 160.33,106.51 UZ12.18 ; v2(151.43,104.58) 148.88,102.03 148.88,96.68 148.56,96.37 v1(148.56,96.16) 148.56,94.93 v2(148.36,94.73)
TPM_TYPE: length 16.6
  TOP w0.112: RC349.1 138.07,82.83 138.07,85.69 137.64,86.12 136.29,86.12 v1(135.95,86.47) 135.28,87.13 v2(135.28,87.2)
  BOTTOM w0.076: 130.35,89.19 129.21,90.33 128.65,90.33 128.42,90.56 128.42,91.76 UC1.AY7
  BOTTOM w0.112: v2(135.28,87.2) 135.28,87.76 134.81,88.23 132.03,88.23 131.06,89.19 130.35,89.19
TRST#_XDP: length 14.4
  TOP w0.112: v2(83.47,123.68) 83.47,124.26 v1(83.84,124.62) 84.02,124.8 84.53,124.8 87.47,127.73 87.47,130.54 87.24,130.77 87.24,131.85 v2(87.61,132.22)
  BOTTOM w0.112: UC8.12 81.8,124.34 81.96,124.5 82.93,124.5 83.47,123.95 v2(83.47,123.68) ; JXDP1.54 v2(87.61,132.22)
TUSB546A_SBU1_R: length 4.8
  TOP w0.112: UT9.27 26.77,107.37 26.44,107.71 26.25,107.71 25.7,108.25 25.7,109.76 RT132.1 v1(24.38,110.11)
TUSB546A_SBU2_R: length 6.2
  TOP w0.112: UT9.26 27.17,107.3 26.52,107.96 26.38,107.96 25.93,108.41 25.93,109.79 RT133.1 26.72,110.58 26.72,111.58 v1(26.25,112.05)
TYPEC_ID: length 8.7
  TOP w0.107: UE1.F2 250.28,84.25 250.28,83.45 249.96,83.13 249.96,81.23 249.52,80.78 249.52,78.83 CE62.1 RE343.1
  TOP w0.112: RE343.1 249.91,77.54 249.91,76.96 v1(249.66,76.71)
UART_MISO: length 4.9
  TOP w0.076: UT5.F2 31.27,83.22 31.27,83.89 31.46,84.07 31.46,84.51
  TOP w0.112: 31.46,84.51 31.46,85.22 v2(31.42,85.25)
  BOTTOM w0.112: RT82.1 31.32,86.79 RT83.1 31.42,85.82 v2(31.42,85.25) 31.42,84.89 v1(31.77,84.53)
UART_MOSI: length 5.3
  TOP w0.076: 32.64,84.51 32.64,84.36 32.27,84 32.27,83.22 UT5.E2
  TOP w0.112: 32.64,84.51 v2(32.64,85.15)
  BOTTOM w0.112: v1(33.3,86.8) RT81.1 32.23,86.79 RT83.2 32.64,85.52 v2(32.64,85.15)
UG1_ISL88738: length 15.1
  TOP w0.112: v2(48.35,70.37) v4(48.35,69.44)
  IN1 w1.016: 56.89,61.22 55.81,62.3 51.9,62.3 48.03,66.18 48.03,69.48
  vias: v2(47.71,70.37) v2(57.07,59.98) v2(57.35,60.49)
UG2_ISL88738: length 10.4
  TOP w0.508: PQ904.1 v2(60.86,65.42)
  BOTTOM w0.508: v2(59.84,57.31) 60.25,57.31 60.55,57.62 v4(60.55,59.38) 60.55,60.77 59.97,61.35 59.97,64.84 60.54,65.42 v2(60.86,65.42)
UIM_CLK: length 92.2
  BOTTOM w0.112: JNGFF2.24 238.53,104 238.65,103.88 239.29,103.88 240.33,104.92 266.83,104.92 268.61,103.13 268.61,99.6 272.92,95.29 272.92,71.24 273.04,71.12 v3(273.04,70.15) 273.04,63.81 273.76,63.09 275.51,63.09 276.61,61.98 276.61,59.98 275.41,58.77 275.41,58.43 276.71,57.12 278.06,57.12 CZ38.1 278.84,57.29 279.16,57.29 279.37,57.5 281.42,57.5 282.47,56.45 284.56,56.45 JSIM1.C3
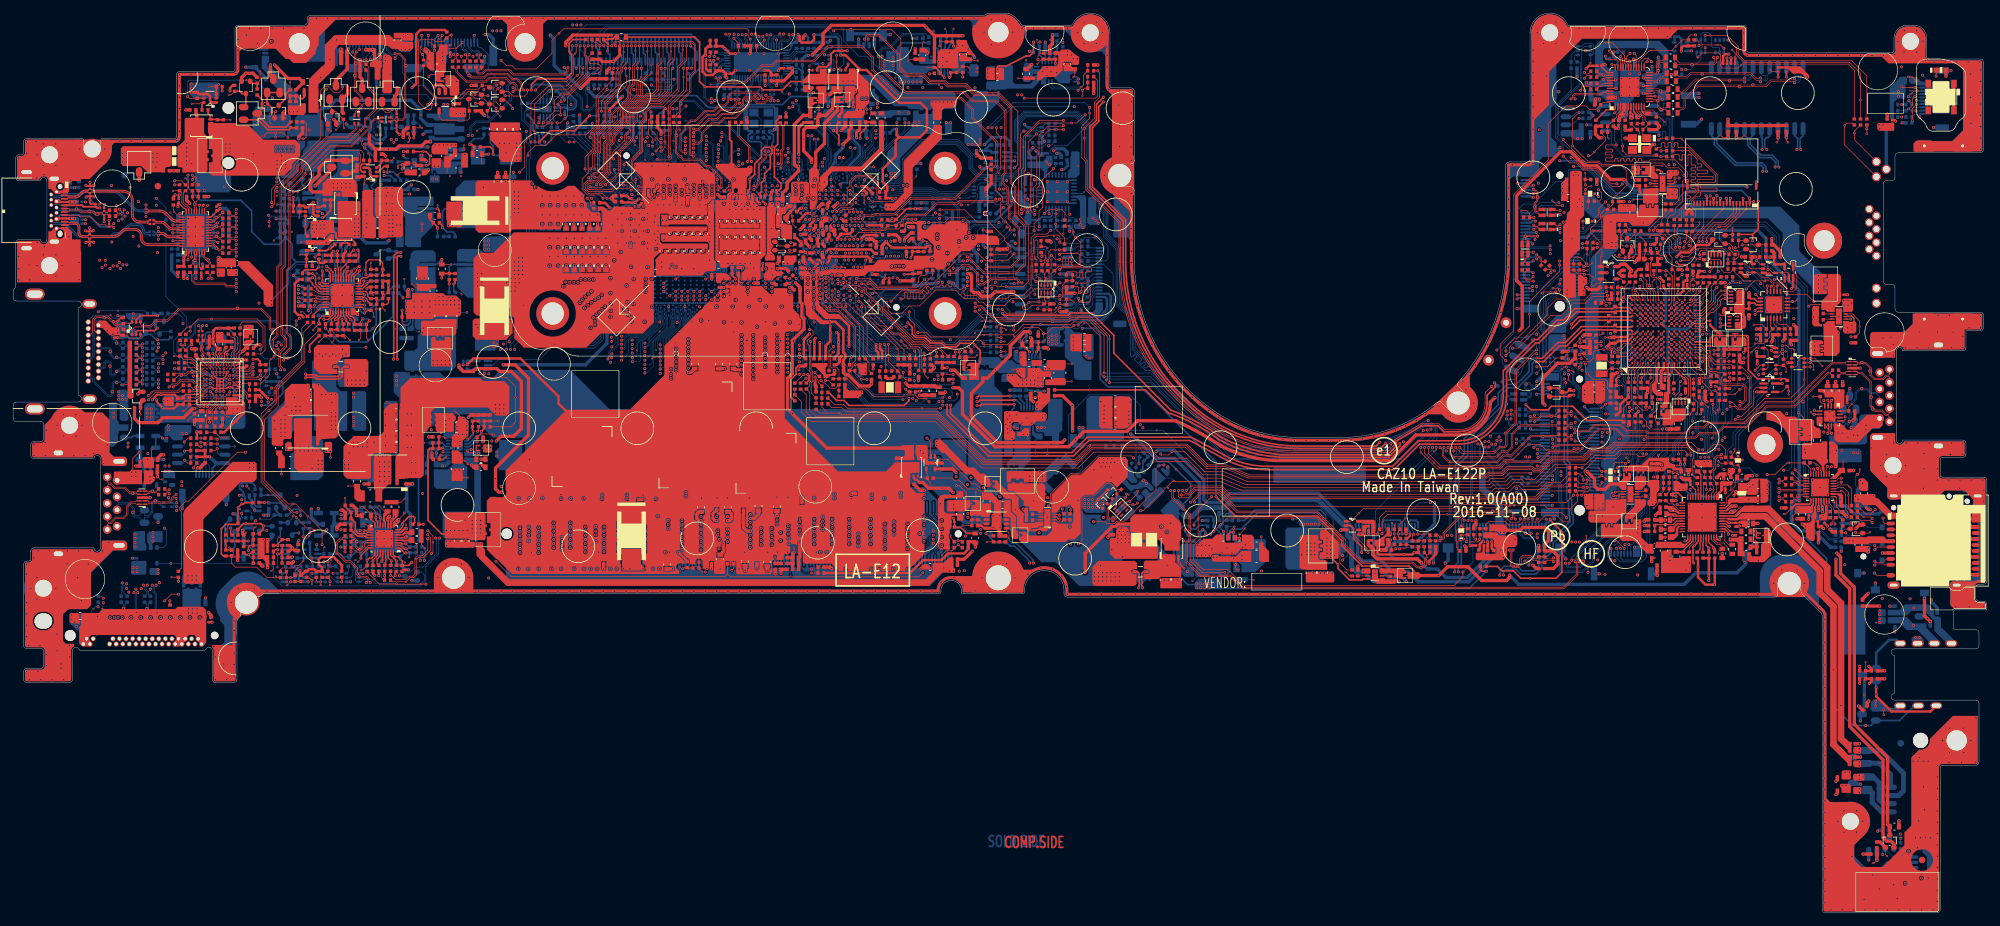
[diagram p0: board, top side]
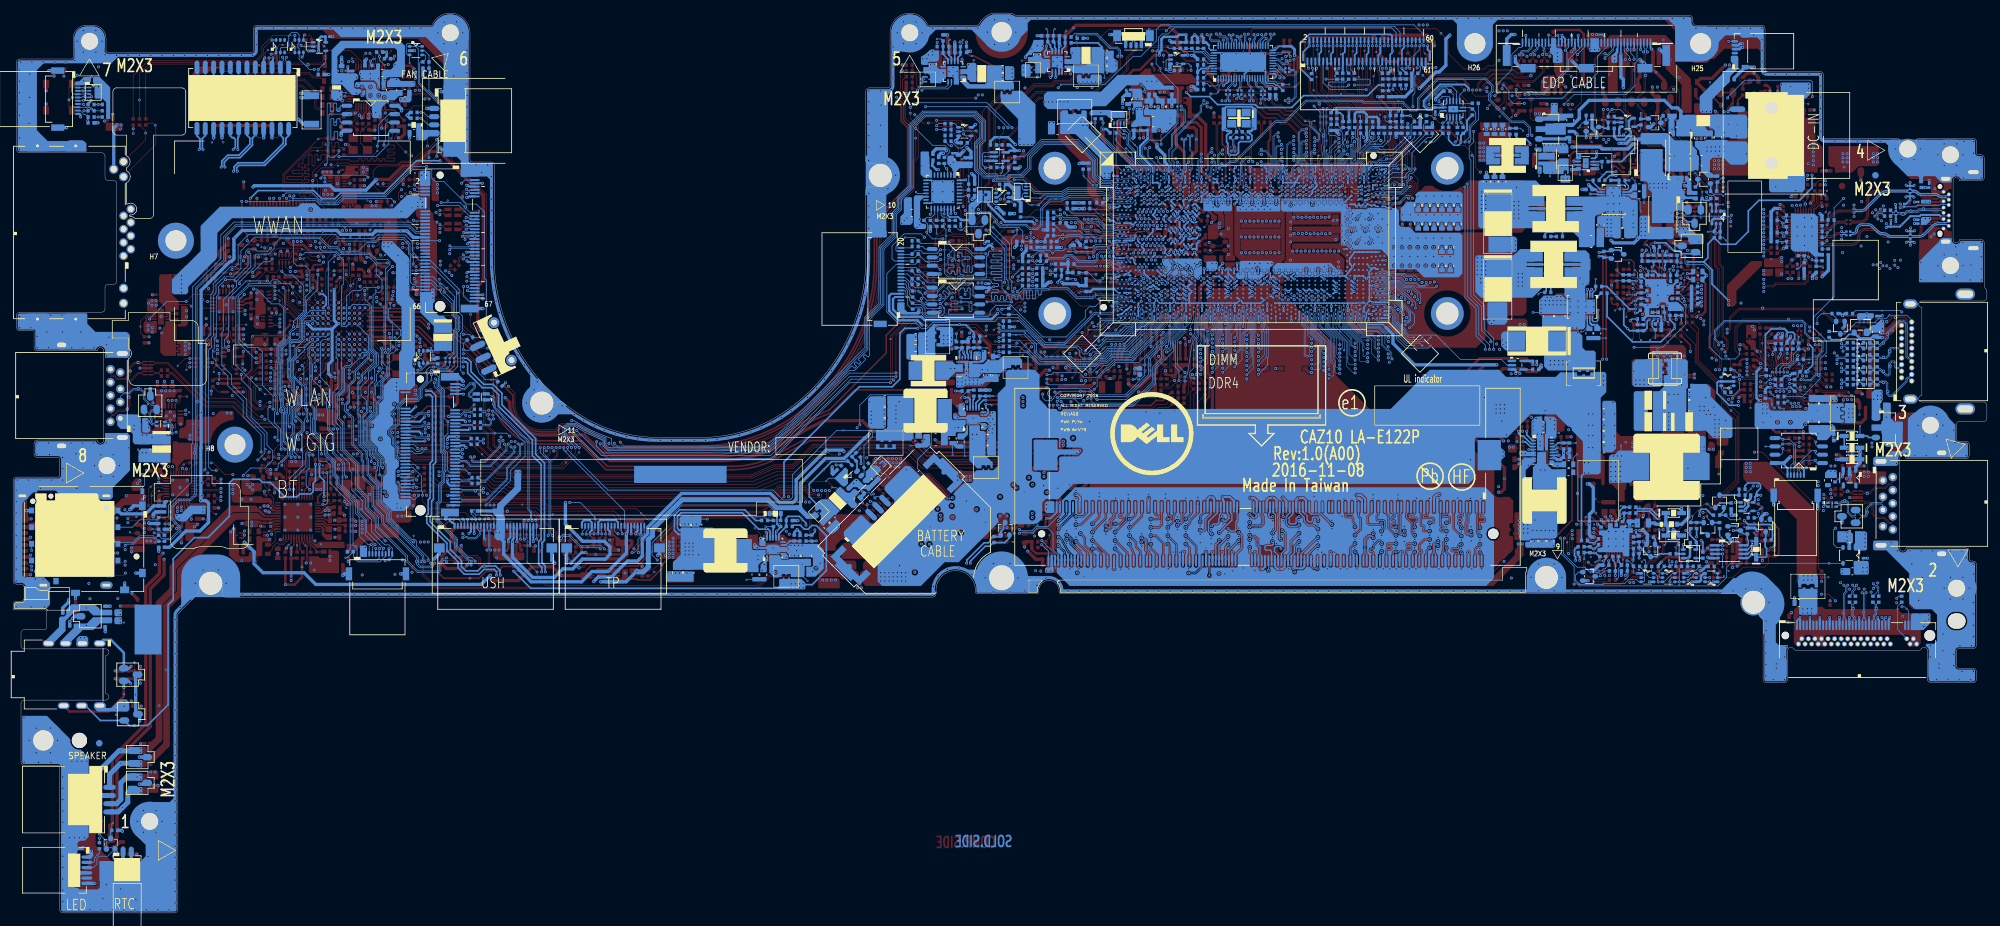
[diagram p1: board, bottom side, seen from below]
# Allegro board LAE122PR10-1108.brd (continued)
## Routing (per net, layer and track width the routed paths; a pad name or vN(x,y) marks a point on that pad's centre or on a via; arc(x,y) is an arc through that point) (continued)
UIM_DATA: length 106.8
  IN3 w0.135: v2(283.63,56.02) 287.5,56.02 288.36,55.16 297.76,55.16 v2(297.88,55.28)
  BOTTOM w0.112: v2(283.63,56.02) 283.44,56.21 282.37,56.21 281.32,57.26 279.47,57.26 279.26,57.05 278.91,57.05 CZ39.1 RZ335.2 277.63,56.77 277.52,56.88 276.61,56.88 275.17,58.33 275.17,58.87 276.38,60.08 276.38,61.89 275.41,62.85 273.66,62.85 272.8,63.71 272.8,71.02 272.68,71.14 v3(272.68,77.94) 272.68,95.19 268.37,99.5 268.37,103.03 266.73,104.68 240.43,104.68 239.39,103.64 238.66,103.64 238.51,103.5 JNGFF2.26 ; JSIM1.C7 v2(297.88,55.28)
UIM_RESET: length 86.8
  BOTTOM w0.112: JNGFF2.22 239.3,104.5 240.13,105.33 267.06,105.33 269.06,103.34 269.06,99.76 273.34,95.48 v1(273.34,74.56) 273.34,71.59 273.51,71.42 273.51,65.68 277.03,62.16 277.03,60.55 277.3,60.29 CZ40.1 278.89,59.93 281.41,59.93 282.52,58.81 JSIM1.C2
UPD1_ALERT#: length 348
  TOP w0.112: v2(39.77,84.91) v1(39.33,84.47) 39.08,84.21 39.08,82.05 37.68,80.66 RT60.1 ; RE91.1 v2(249.96,97.32) ; UE1.F10 v2(250.28,91.46)
  IN1 w0.119: v2(249.96,97.32) 250.2,97.07 250.2,93.24 250.69,92.75 250.69,91.87 v2(250.28,91.46) UE1.F10 250.68,89.53 250.16,89.01 249.53,89.01 249.08,88.57 249.08,83.89 247.47,82.28 247.47,78.29 v2(246.25,77.07)
  IN2 w0.124: v2(246.25,77.07) 245.24,77.07 244.23,78.08 236.49,78.08 235.6,77.2 235.6,76.39 234.93,75.71 234.93,74.76 234.62,74.45 233.69,74.45 232.38,73.14 231.46,73.14 228.67,70.35 226.78,70.35 225.78,69.35 221.63,69.35 220.96,68.67 207.89,68.67 206.6,69.96 186.52,69.96 184.83,71.65 181.75,71.65 172.33,81.07 172.33,83.63 169.84,86.12 169.84,88.6 167.92,90.52 167.92,106.29 163.51,110.69 163.51,116.69 161.89,118.31 161.89,121.51 159.22,124.18 159.22,130.18 158.41,131 157.07,131 156.25,131.82 154.44,131.82 153.52,130.9 148.6,130.9 144.8,134.69 127.29,134.69 126.13,133.54 123.82,133.54 123.19,132.9 117.89,132.9 117.33,132.34 109.5,132.34 109.18,132.66 107.48,132.66 107.16,132.98 83.87,132.98 82.17,131.28 82.17,130.95 79.63,128.41 75.33,128.41 75.13,128.61 62.56,128.61 62,128.05 47.67,128.05 45.95,126.33 42.16,126.33 39.57,123.73 37.05,123.73 31.3,117.98 31.3,112.75 32.98,111.07 37.06,111.07 39.39,108.75 39.85,108.75 40.74,107.86 40.74,105.37 40.61,105.24 40.61,93.08 39.14,91.6 39.14,85.55 v2(39.77,84.91)
UPD1_SMBCLK: length 268.4
  TOP w0.107: v2(247.88,85.06) UE1.C3
  TOP w0.112: v2(241.93,86.5) 241.71,86.73 241.54,86.73 241.15,86.34 RE303.1
  IN1 w0.119: v2(247.88,85.06) 247.49,85.45 246.18,85.45 244.79,86.84 242.27,86.84 v2(241.93,86.5) ; v2(236.48,53.32) 236.65,53.15 236.65,52.57 236.53,52.45 230.2,52.45 229.54,53.11 218.86,53.11 218.38,52.63 210.51,52.63 208.55,50.67 189.71,50.67 186.46,53.92 186.46,55.66 185.27,56.86 180.24,56.86 179.47,57.62 173.46,57.62 170.04,61.04 163.24,61.04 161.52,62.77 149.15,62.77 147.18,64.73 147.18,66.94 146.23,67.89 87.29,67.89 76.88,78.31 57.55,78.31 56.79,77.54 44.73,77.54 42.01,80.27 40.83,80.27 40.16,80.94 v2(40.16,82.24)
  BOTTOM w0.112: QT1.1 40.16,82 v2(40.16,82.24) 40.16,82.64 RT58.1 ; v2(247.88,85.06) 247.5,85.44 246.87,85.44 246.64,85.22 246.64,84.74 248.77,82.61 248.77,81.31 249.66,80.42 249.66,78.04 250.18,77.52 250.18,76.56 249.1,75.47 249.1,71.38 247.67,69.95 247.67,68.95 247.52,68.79 247.52,66.43 246.02,64.93 246.02,62 244.54,60.53 244.54,59.47 239.21,54.14 v3(239.21,53.62) 239.21,53.09 238.75,52.63 236.9,52.63 236.65,52.88 236.65,53.15 v2(236.48,53.32)
UPD1_SMBCLK_Q: length 27.7
  TOP w0.076: 35.11,81.6 34.34,81.6 34.21,81.72 33.77,81.72 UT5.B5
  TOP w0.112: RT375.2 25.58,87.16 v2(25.58,86.63) 25.75,86.46 25.75,86.14 RT92.1 ; RT67.1 37.68,82.61 v2(37.68,81.99) 37.55,81.99 v1(37.25,81.69) 37.16,81.6 35.11,81.6 35.11,81.6
  IN1 w0.119: v2(25.58,86.63) 25.75,86.46 25.75,85.25 26.58,84.42 29.11,84.42 29.87,83.66 33.76,83.66 35.03,84.92 37.19,84.92 37.62,84.49 37.62,82.84 38.13,82.33 38.13,81.9 38.03,81.8 37.87,81.8 v2(37.68,81.99)
  BOTTOM w0.112: QT1.6 37.98,81.69 v2(37.68,81.99) 38.57,82.88 RT58.2
UPD1_SMBDAT: length 265.8
  TOP w0.112: v2(241.93,87.09) 241.82,86.97 241.31,86.97 RE302.1 ; UE1.B4 v2(247.08,85.86)
  IN1 w0.119: v2(237.06,53.32) 236.89,53.15 236.89,52.47 236.63,52.21 230.1,52.21 229.44,52.86 218.96,52.86 218.48,52.38 210.61,52.38 208.65,50.42 189.61,50.42 186.21,53.82 186.21,55.56 185.16,56.61 180.13,56.61 179.37,57.37 173.35,57.37 169.93,60.79 163.14,60.79 161.41,62.52 149.04,62.52 146.94,64.63 146.94,66.84 146.13,67.65 87.19,67.65 76.78,78.06 57.66,78.06 56.89,77.3 44.63,77.3 41.91,80.02 v2(39.39,80.02) ; v2(247.08,85.86) 246.92,85.7 246.28,85.7 244.89,87.09 v2(241.93,87.09)
  BOTTOM w0.112: RT59.1 39,79.5 39.39,79.89 v2(39.39,80.02) 39.03,80.39 QT1.4 ; v2(247.08,85.86) 246.91,85.68 246.77,85.68 246.4,85.32 246.4,84.64 248.53,82.51 248.53,81.21 249.43,80.32 249.43,77.94 249.94,77.42 249.94,76.66 248.86,75.57 248.86,71.48 247.44,70.05 247.44,69.05 247.28,68.89 247.28,66.53 245.78,65.03 245.78,62.1 244.31,60.63 244.31,59.57 238.97,54.24 238.97,53.19 238.66,52.87 237,52.87 236.89,52.98 236.89,53.15 v2(237.06,53.32)
UPD1_SMBDAT_Q: length 31.3
  TOP w0.076: UT5.A5 34.16,81.47 34.28,81.35 35.11,81.35
  TOP w0.112: RT376.2 26.16,87.16 v2(26.16,86.63) 25.99,86.46 25.99,86.14 RT93.1 ; RT66.1 38.5,82.18 v2(37.68,81.35) 35.11,81.35
  IN1 w0.119: v2(26.16,86.63) 26,86.47 26,85.35 26.68,84.67 29.21,84.67 29.97,83.91 33.66,83.91 34.92,85.17 37.29,85.17 37.87,84.59 37.87,82.94 38.38,82.43 38.38,81.8 38.13,81.55 37.88,81.55 v2(37.68,81.35)
  BOTTOM w0.112: v2(37.68,81.35) 37.68,79.81 38.61,78.88 39.52,78.88 39.91,79.27 RT59.2 40.47,79.94 QT1.3
UPD1_SMBUS_ALERT#: length 3.6
  TOP w0.076: 35.11,80.72 34.89,80.72 34.77,80.61 34.29,80.61 34.17,80.72 33.77,80.72 UT5.B6
  TOP w0.112: 35.11,80.72 35.95,80.72 RT60.2 RT68.1
UPD2_ALERT#: length 13.5
  TOP w0.107: UE1.F5 v2(250.28,86.66)
  TOP w0.112: RE92.1 250.19,75.08 v2(250.19,75.63)
  IN1 w0.119: v2(250.19,75.63) 251.05,76.49 251.05,80.34 250.68,80.71 250.68,86.26 v2(250.28,86.66)
UPD2_SMBCLK: length 14.4
  TOP w0.107: UE1.D7 v2(248.68,88.26)
  TOP w0.112: v2(260.07,89.96) 260.24,89.78 261.02,89.78 261.17,89.93 RPE12.3
  IN3 w0.135: v2(260.07,89.96) 259.91,89.8 259.16,89.8 258.32,88.95 256.43,88.95 256.33,89.05 249.27,89.05 248.96,88.74 248.96,88.54 v2(248.68,88.26)
UPD2_SMBDAT: length 14
  TOP w0.107: UE1.E7 v2(249.48,88.26)
  TOP w0.112: v2(260.07,89.37) 260.24,89.55 261.05,89.55 261.16,89.43 RPE12.4
  IN3 w0.135: v2(260.07,89.37) 259.91,89.53 259.27,89.53 258.42,88.69 256.32,88.69 256.22,88.78 249.38,88.78 249.22,88.63 249.22,88.52 v2(249.48,88.26)
USB2_ID: length 195.2
  IN1 w0.119: v2(38.92,106.37) 38.92,110.22 v2(40.17,111.47)
  IN2 w0.124: v2(37.46,92.99) 37.9,93.42 37.9,105.35 v2(38.92,106.37) ; v2(133.67,100.13) 134.21,100.67 136.06,100.67 137.18,101.8 137.18,102.85 138.39,104.06 138.39,106.33 136.19,108.52 v2(136.19,110.94) 136.19,111.21 135.42,111.98 135.42,117.8 134.18,119.04 134.18,120.63 134.62,121.06 134.62,124.53 132.32,126.83 128.83,126.83 128.23,127.42 126.19,127.42 125.59,126.83 123.11,126.83 122.37,127.56 120.42,127.56 120.06,127.21 114.13,127.21 113.57,126.65 104.89,126.65 104.46,126.21 98.55,126.21 97.98,126.78 90.74,126.78 89.73,125.77 89.73,125.5 89.48,125.25 85.78,125.25 85.14,125.89 81.57,125.89 80.05,124.37 75.8,124.37 75.18,124.99 74.36,124.99 74.19,124.82 73.31,124.82 72.19,125.94 70.93,125.94 70.42,125.44 68.8,125.44 68.46,125.09 62.75,125.09 59.27,121.6 56,121.6 52.99,124.61 42.41,124.61 40.49,122.7 40.49,120.77 42.25,119.01 44.1,119.01 44.95,118.17 44.95,115.38 41.03,111.47 v2(40.17,111.47)
  IN3 w0.135: v2(37.46,92.99) 34.82,90.35 34.82,87.03 34.05,86.26 34.05,78.43 33.67,78.05 v2(30.31,78.05)
  BOTTOM w0.076: v2(133.67,100.13) 133.04,99.5 131.42,99.5 UC1.AG3
  BOTTOM w0.112: RT74.2 30.62,77.8 30.36,78.05 v2(30.31,78.05) ; v2(136.19,110.94) v1(137.54,112.28) 137.69,112.44 RC337.1
USB2_VBUSSENSE: length 21.4
  IN2 w0.124: v2(135.61,110.94) 135.61,108.7 138.16,106.15 138.16,104.15 136.93,102.92 136.93,101.86 135.97,100.9 134.06,100.9 133.85,100.69 131.62,100.69 v2(130.99,100.05)
  BOTTOM w0.076: v2(130.99,100.05) 130.99,99.72 UC1.AG4 ; RC338.1 136.8,112.14 v1(136.11,111.44) v2(135.61,110.94)
USB3_PRX_C_DTX_N6: length 2.6
  TOP w0.104: CT112.2 27.29,98.93 27.29,99.45 27.67,99.83 27.67,100.35 27.57,100.45 UT9.4
USB3_PRX_C_DTX_P6: length 2.6
  TOP w0.104: CT111.2 27.49,98.93 27.49,99.32 v3(27.69,99.52) 27.87,99.7 27.87,100.35 27.97,100.45 UT9.5
USB3_PRX_DTX_N1: length 201.1
  TOP w0.104: v2(237.91,73.78) 238.07,73.61 239.99,73.61 240.86,74.48 244.92,74.48 245.89,73.52 248.92,73.52 249.15,73.29 254.75,73.29 255.58,74.12 257.52,74.12 258.24,74.83 263.79,74.83 266.92,77.96 271.11,77.96 277.07,83.92 279.13,83.92 279.28,84.07 DI4.1 DI4.9 280.86,84.07 281,83.93 v3(281.66,83.93) 282.27,83.93 283.08,83.13 283.08,82.94 283.11,82.91 283.11,82.34 283.08,82.31 283.08,82.06 283.62,81.52 284.83,81.52 285.31,82 285.72,82 285.87,82.14 JUSB1.5
  IN3 w0.076: 128.99,108.02 128.76,108.02 128.6,107.86 127.28,107.86 127.1,108.04 127.1,109.2 127.18,109.28 127.35,109.28 127.41,109.22 127.54,109.22 127.66,109.1 127.66,108.91 127.56,108.81 v2(127.47,108.81)
  IN3 w0.135: 128.99,108.02 129.44,108.02 129.88,108.46 135.01,108.46 135.5,108.94 139.22,108.94 139.5,108.67 144.69,108.67 145.91,107.45 148.35,107.45 149.55,106.25 152.21,106.25 153.19,105.26 157.89,105.26 162.61,100.54 162.61,99.58 arc(165.37,85.71) 173.23,73.95 173.82,73.35 arc(183.91,66.61) 195.81,64.25 202.65,64.25 203.29,63.61 224,63.61 228.29,67.89 231.32,67.89 231.48,67.73 232.52,67.73 234.65,69.86 235.12,69.86 236.03,70.77 236.03,73.09 236.52,73.58 237.71,73.58 v2(237.91,73.78)
  BOTTOM w0.102: UC1.H8 v2(127.47,108.81)
USB3_PRX_DTX_N2: length 175.6
  TOP w0.104: RI28.1 234.15,105.11 LI16.4 234.75,105.11 235.07,104.8 235.52,104.8 v2(235.68,104.95)
  IN3 w0.135: v2(128.39,108.3) 129.09,108.3 130.2,109.4 139.79,109.4 140.07,109.11 144.87,109.11 146.09,107.89 148.53,107.89 149.59,106.83 152.36,106.83 153.48,105.71 158.14,105.71 163.08,100.77 163.08,99.42 arc(165.76,85.92) 173.41,74.47 174.42,73.47 arc(184.04,67.04) 195.39,64.78 202.91,64.78 203.63,64.06 223.83,64.06 228.34,68.57 232.75,68.57 234.47,70.3 234.92,70.3 235.44,70.82 235.44,76.64 232.8,79.28 232.8,97.38 236.65,101.24 236.65,104.64 236.38,104.91 235.71,104.91 v2(235.68,104.95)
  BOTTOM w0.102: UC1.J6 128.76,107.98 128.41,108.22 v2(128.39,108.3)
USB3_PRX_DTX_N3: length 152.3
  TOP w0.104: JUSB2.5 14.33,59.18 14.51,59.35 14.89,59.35 15.67,60.14 16.87,60.14 17.5,60.76 17.5,61.97 18,62.47 18.59,62.47 18.74,62.32 DI1.9 DI1.1 20.55,62.32 20.7,62.47 23.77,62.47 24.36,63.05 24.36,63.23 24.52,63.39 24.66,63.39 v2(24.84,63.21)
  IN1 w0.076: 124.23,108.3 124.25,108.3 124.27,108.32 124.69,108.32 125.33,107.68 125.88,107.68 126.16,107.96 126.16,108.39 126.23,108.47 126.32,108.47 v2(126.55,108.23)
  IN1 w0.119: 124.23,108.3 120.03,108.3 119.47,107.74 119.47,106.08 119.04,105.65 118.36,105.65 118.07,105.94 115.78,105.94 115.06,106.67 97.25,106.67 96.87,107.04 92.51,107.04 89.83,104.36 80.25,104.36 74.57,98.69 74.57,91.86 70.38,87.67 61.62,87.67 61.11,88.17 56.54,88.17 55.88,88.83 48.59,88.83 47.76,89.66 46.72,89.66 45.92,88.86 42.92,88.86 41.98,89.8 39.27,89.8 38.58,89.11 38.58,83.68 39.05,83.21 39.05,81.47 36.42,78.84 36.42,75.2 31.39,70.17 31.39,69.05 25.74,63.4 25.02,63.4 v2(24.84,63.21)
  BOTTOM w0.102: UC1.J10 v2(126.55,108.23)
USB3_PRX_DTX_N6: length 145.4
  TOP w0.104: CT112.1 27.2,97.42 27.2,96.35 27.7,95.86 32.1,95.86 32.51,95.45 33.92,95.45 v2(34,95.38)
  IN3 w0.076: 125.19,111.01 125.19,110.99 125.22,110.96 125.22,110.75 125.08,110.62 125.08,109.89 125.29,109.68 125.47,109.68 v2(125.64,109.52)
  IN3 w0.135: v2(34,95.38) 34.22,95.6 35.06,95.6 38.49,99.03 38.49,108.84 37.06,110.27 37.06,122.5 39.43,124.88 46.33,124.88 48.07,126.62 71.63,126.62 74.35,123.9 79.75,123.9 83.41,127.56 103.68,127.56 105.99,125.25 116.06,125.25 117,124.31 117,119.14 120.39,115.75 120.39,114.07 121.23,113.23 124.51,113.23 125.19,112.56 125.19,111.01
  BOTTOM w0.089: UC1.G11 v2(125.64,109.52)
USB3_PRX_DTX_P1: length 201.1
  TOP w0.104: JUSB1.6 285.87,81.69 285.76,81.8 285.39,81.8 284.91,81.32 283.54,81.32 282.88,81.98 v3(282.88,82.62) 282.88,83.04 282.19,83.73 281.97,83.73 281.95,83.7 281.37,83.7 281.34,83.73 281.03,83.73 280.86,83.57 DI4.8 DI4.2 279.28,83.57 279.13,83.72 277.15,83.72 271.19,77.76 267,77.76 263.88,74.63 258.32,74.63 257.6,73.92 255.66,73.92 254.84,73.09 249.06,73.09 248.84,73.32 245.8,73.32 244.84,74.28 240.95,74.28 240.08,73.41 238.13,73.41 v2(237.91,73.19)
  IN3 w0.076: 128.99,107.78 128.78,107.78 128.67,107.68 127.21,107.68 126.92,107.96 126.92,109.28 127.1,109.46 127.43,109.46 127.43,109.46 v2(127.55,109.58)
  IN3 w0.135: v2(237.91,73.19) 237.76,73.34 236.62,73.34 236.27,72.99 236.27,70.67 235.22,69.61 234.75,69.61 232.62,67.49 231.38,67.49 231.22,67.65 228.39,67.65 224.1,63.37 203.19,63.37 202.55,64.01 195.81,64.01 arc(183.82,66.39) 173.65,73.18 173.06,73.78 arc(165.15,85.62) 162.37,99.58 162.37,100.44 157.79,105.02 153.09,105.02 152.11,106.01 149.45,106.01 148.25,107.21 145.81,107.21 144.59,108.43 139.4,108.43 139.12,108.7 135.6,108.7 135.11,108.21 129.98,108.21 129.54,107.78 128.99,107.78
  BOTTOM w0.102: UC1.G8 127.84,109.29 v2(127.55,109.58)
USB3_PRX_DTX_P2: length 175.6
  TOP w0.104: v2(235.68,104.37) 235.45,104.6 235.14,104.6 234.75,104.21 LI16.1 234.15,104.21 RI27.1
  IN3 w0.135: v2(128.36,108.91) 128.36,108.81 128.48,108.69 128.56,108.69 128.72,108.54 128.99,108.54 130.1,109.64 130.53,109.64 130.72,109.83 131.1,109.83 131.29,109.64 131.68,109.64 131.9,109.87 132.21,109.87 132.44,109.64 139.89,109.64 140.17,109.35 144.97,109.35 146.19,108.13 148.63,108.13 149.69,107.07 152.46,107.07 153.58,105.95 158.24,105.95 163.32,100.87 163.32,99.42 arc(165.99,86.01) 173.58,74.64 174.59,73.64 arc(184.14,67.26) 195.4,65.02 203.01,65.02 203.73,64.3 223.73,64.3 228.24,68.81 232.65,68.81 234.37,70.54 234.82,70.54 235.2,70.92 235.2,76.54 232.56,79.18 232.56,97.48 236.41,101.34 236.41,104.54 236.28,104.67 235.99,104.67 235.85,104.53 235.81,104.53 235.68,104.39 v2(235.68,104.37)
  BOTTOM w0.102: UC1.H6 128.64,108.64 v2(128.36,108.91)
USB3_PRX_DTX_P3: length 152.3
  TOP w0.104: v2(24.84,63.8) 24.62,63.59 24.43,63.59 24.16,63.31 24.16,63.14 23.69,62.67 20.7,62.67 20.55,62.82 DI1.2 DI1.8 18.74,62.82 18.59,62.67 17.92,62.67 17.3,62.05 17.3,60.84 16.79,60.34 15.59,60.34 14.8,59.55 14.53,59.55 14.33,59.74 JUSB2.6
  IN1 w0.076: 124.23,108.52 124.25,108.52 124.27,108.5 124.76,108.5 125.4,107.86 125.8,107.86 125.98,108.04 125.98,108.46 126.16,108.64 126.32,108.64 v2(126.55,108.88)
  IN1 w0.119: v2(24.84,63.8) 25.02,63.62 25.65,63.62 31.17,69.14 31.17,70.27 36.2,75.29 36.2,78.93 38.84,81.56 38.84,83.12 38.36,83.59 38.36,89.2 39.18,90.02 42.07,90.02 43.01,89.08 45.83,89.08 46.63,89.88 47.85,89.88 48.68,89.05 55.97,89.05 56.63,88.39 61.2,88.39 61.71,87.88 70.29,87.88 74.35,91.95 74.35,98.78 80.16,104.58 89.74,104.58 92.41,107.26 96.97,107.26 97.34,106.88 115.15,106.88 115.87,106.16 118.16,106.16 118.45,105.87 118.95,105.87 119.25,106.17 119.25,107.83 119.94,108.52 124.23,108.52
  BOTTOM w0.102: UC1.H10 v2(126.55,108.88)
USB3_PRX_DTX_P6: length 145.4
  TOP w0.104: v2(34,95.96) 33.69,95.65 32.59,95.65 32.18,96.06 27.78,96.06 27.4,96.44 27.4,97.24 CT111.1
  IN3 w0.076: 125.43,111.01 125.43,110.99 125.4,110.96 125.4,110.68 125.27,110.55 125.27,109.97 125.37,109.87 125.5,109.87 125.64,110.01 v2(125.64,110.18)
  IN3 w0.135: v2(34,95.96) 34.11,95.84 34.96,95.84 38.25,99.13 38.25,108.74 36.82,110.17 36.82,122.6 39.33,125.12 46.23,125.12 47.97,126.86 71.73,126.86 74.45,124.14 79.65,124.14 83.31,127.8 103.78,127.8 106.09,125.49 116.16,125.49 117.24,124.41 117.24,119.24 120.64,115.85 120.64,114.17 121.33,113.47 124.61,113.47 125.43,112.66 125.43,111.01
  BOTTOM w0.076: UC1.F11 v2(125.64,110.18)
USB3_PRX_L_DTX_N2: length 3.3
  TOP w0.104: RI28.2 233.05,105.11 LI16.3 232.69,105.11 232.24,104.66 231.88,104.66 v2(231.67,104.87)
  BOTTOM w0.104: JNGFF2.21 231.05,104.75 231.18,104.62 231.43,104.62 v2(231.67,104.87)
USB3_PRX_L_DTX_P2: length 3.2
  TOP w0.104: RI27.2 233.05,104.21 LI16.2 232.63,104.21 232.38,104.46 231.9,104.46 v2(231.67,104.23)
  BOTTOM w0.104: JNGFF2.23 231.01,104.25 231.18,104.42 231.48,104.42 v2(231.67,104.23)
USB3_PTX_C_DRX_N1: length 13.6
  TOP w0.104: CI13.1 278.45,82.41 278.84,82.41 278.85,82.42 279.13,82.42 279.28,82.57 DI4.4 DI4.7 280.89,82.57 281.05,82.41 281.67,82.41 283.08,81 v3(283.08,78.66) 283.08,77.32 283.2,77.2 283.24,77.2 283.64,76.8 283.64,76.76 283.73,76.67 284.76,76.67 285.42,76.01 285.65,76.01 285.87,76.23 JUSB1.8
USB3_PTX_C_DRX_N2: length 2.1
  TOP w0.104: RI30.1 229.89,100.77 LI17.1 229.89,100.18 230.24,99.83 230.24,99.3 CI29.1
USB3_PTX_C_DRX_N3: length 9.5
  TOP w0.104: CI5.1 21.86,64.1 21.55,64.1 21.52,64.07 20.9,64.07 20.8,63.97 20.47,63.97 20.32,63.82 DI1.4 DI1.7 18.94,63.82 18.79,63.97 v3(18.22,63.97) 17.73,63.97 17,64.71 15.43,64.71 14.8,65.34 14.53,65.34 14.33,65.15 JUSB2.8
USB3_PTX_C_DRX_N6: length 2.9
  TOP w0.104: UT9.7 28.77,100.46 28.94,100.29 28.94,100.05 29.3,99.69 29.3,99.66 29.88,99.07 29.88,98.92 CT114.2
USB3_PTX_C_DRX_P1: length 13.7
  TOP w0.104: JUSB1.9 285.87,75.61 285.67,75.81 285.34,75.81 284.68,76.46 283.65,76.46 v3(283.28,76.84) 282.88,77.23 282.88,78.35 282.85,78.38 282.85,78.95 282.88,78.98 282.88,80.92 281.59,82.21 281.03,82.21 280.89,82.07 DI4.6 DI4.5 279.28,82.07 279.13,82.22 278.93,82.22 278.92,82.21 278.45,82.21 CI16.1
USB3_PTX_C_DRX_P2: length 2.1
  TOP w0.104: RI29.1 230.79,100.77 LI17.4 230.79,100.18 230.44,99.83 230.44,99.3 CI30.1
USB3_PTX_C_DRX_P3: length 9.5
  TOP w0.104: CI4.1 21.83,64.3 v3(21.21,64.3) 20.85,64.3 20.72,64.17 20.5,64.17 20.35,64.32 DI1.5 DI1.6 18.96,64.32 18.81,64.17 18.54,64.17 18.51,64.2 17.79,64.2 17.08,64.91 15.52,64.91 14.88,65.54 14.53,65.54 14.33,65.74 JUSB2.9
USB3_PTX_C_DRX_P6: length 2.8
  TOP w0.104: CT113.2 30.08,98.94 30.08,99.19 v3(29.69,99.58) 29.14,100.14 29.14,100.35 29.17,100.38 UT9.8
USB3_PTX_DRX_N1: length 197.4
  TOP w0.104: v2(234.55,71.58) 234.83,71.31 235.2,71.31 235.34,71.44 239.09,71.44 239.09,71.44 241.51,73.86 244.31,73.86 245.39,72.78 248.79,72.78 249.01,72.57 256.22,72.57 256.89,73.24 259.59,73.24 260.55,74.19 264.02,74.19 267.15,77.33 271.36,77.33 276.45,82.41 276.84,82.41 CI13.2
  IN3 w0.135: v2(126.49,115.16) 126.42,115.16 126.33,115.08 126.33,114.99 126.21,114.87 126.21,114.69 126.4,114.5 129.64,114.5 131.1,115.96 139.35,115.96 140.22,116.83 143.36,116.83 145.12,115.07 149.05,115.07 149.45,115.47 153.86,115.47 156.25,113.08 156.25,110.66 164,102.91 164,99.42 arc(166.62,86.27) 174.06,75.13 175.07,74.12 arc(184.4,67.89) 195.4,65.7 203.35,65.7 204.07,64.98 223.44,64.98 228.33,69.87 229.42,69.87 231.18,71.63 232.24,71.63 232.64,71.23 234.21,71.23 234.39,71.41 234.43,71.41 234.55,71.54 v2(234.55,71.58)
  BOTTOM w0.076: v2(126.49,115.16) 126.33,115 126.33,114.46 125.77,113.91 125.47,113.91 125.02,113.46 125.02,113.21 125.07,113.11 125.07,112.91 125.02,112.75 125.02,112.58 125.06,112.45 125.19,112.32 125.46,112.32 125.61,112.18 125.61,111.93 125.53,111.86 125.44,111.86 UC1.C13
USB3_PTX_DRX_N2: length 171.8
  TOP w0.104: v2(231.59,96.34) 231.59,96.34 230.64,96.34 230.14,96.85 230.14,97.8 CI29.2
  IN3 w0.135: v2(231.59,96.34) 231.59,96.43 231.41,96.62 231.12,96.62 230.91,96.4 230.91,79.55 232.49,77.97 232.49,74.19 231.38,73.07 229.22,73.07 224.69,68.54 223.07,68.54 220.67,66.14 204.65,66.14 203.96,66.82 195.56,66.82 arc(190.08,67.36) 184.81,68.96 arc(180.01,71.52) 175.8,74.98 174.86,75.92 arc(167.65,86.7) 165.12,99.42 165.12,104.18 161.44,107.86 161.44,108.18 158.28,111.34 158.28,112.66 154.27,116.67 152.97,116.67 151.53,118.11 139.69,118.11 139.03,117.46 128.1,117.46 127.96,117.32 127.96,116.77 128.13,116.6 v2(128.24,116.6)
  BOTTOM w0.076: v2(128.24,116.6) 128.11,116.6 127.86,116.35 127.86,115.29 126.95,114.37 126.94,114.37 126.05,113.48 126.05,113.38 125.51,112.84 125.51,112.84 125.34,112.66 UC1.B13
USB3_PTX_DRX_N3: length 173.2
  TOP w0.104: v2(23.78,63.92) 23.61,64.1 23.43,64.1 CI5.2
  IN3 w0.135: v2(23.78,63.92) 23.97,64.1 24.36,64.1 25.2,64.94 25.2,82.19 29.89,86.89 31.68,86.89 33.15,88.35 33.15,97.78 37.78,102.41 37.78,108.57 36.3,110.05 36.3,122.86 39.34,125.91 46.15,125.91 47.83,127.58 73.37,127.58 74.43,126.52 80.74,126.52 84.55,130.33 104.2,130.33 106.46,128.07 109.31,128.07 109.65,127.72 117.82,127.72 122.06,123.48 122.06,122.88 122.31,122.63 122.57,122.63 v2(122.76,122.44)
  BOTTOM w0.076: 124.24,116.98 124.24,116.96 124.22,116.94 124.22,116.81 124.7,116.33 124.7,114.54 124.36,114.2 124.36,113.18 124.18,113 124.01,113 123.93,112.92 UC1.B15
  BOTTOM w0.104: 124.24,116.98 124.24,118.7 122.32,120.62 122.32,122.3 122.49,122.46 122.73,122.46 v2(122.76,122.44)
USB3_PTX_DRX_N6: length 141.1
  TOP w0.104: v2(29.72,96.71) 29.87,96.86 29.87,97.35 CT114.1
  IN1 w0.119: v2(29.72,96.71) 29.72,97.59 30.72,98.59 31.62,98.59 32.49,99.45 32.49,108.93 30.26,111.15 30.26,123.39 31.75,124.88 36.01,124.88 36.85,125.72 46.04,125.72 47.99,127.67 79.73,127.67 82.83,130.77 104.37,130.77 105.71,129.42 114.73,129.42 117.69,126.47 117.69,124.15 118.33,123.51 v2(118.77,123.51)
  BOTTOM w0.076: UC1.D16 123.67,112.3 123.67,113.46 123.96,113.75 123.96,114.45 124.18,114.67 124.18,116.11 123.56,116.73 123.56,116.94 123.57,116.96 123.57,116.98
  BOTTOM w0.104: v2(118.77,123.51) 118.82,123.47 119.46,123.47 119.85,123.07 119.85,122.22 123.57,118.5 123.57,116.98
USB3_PTX_DRX_P1: length 197.3
  TOP w0.104: v2(234.56,70.99) 234.68,71.11 235.29,71.11 235.42,71.24 239.17,71.24 241.59,73.66 244.23,73.66 245.31,72.58 248.71,72.58 248.92,72.37 256.31,72.37 256.97,73.04 259.68,73.04 260.63,73.99 264.1,73.99 267.23,77.13 271.45,77.13 276.53,82.21 276.84,82.21 CI16.2
  IN3 w0.135: v2(234.56,70.99) 232.54,70.99 232.14,71.38 231.28,71.38 229.52,69.63 228.43,69.63 223.54,64.74 203.97,64.74 203.25,65.46 195.4,65.46 arc(184.3,67.67) 174.9,73.95 173.89,74.96 arc(166.39,86.18) 163.76,99.42 163.76,102.81 156.01,110.56 156.01,112.98 153.76,115.23 149.55,115.23 149.15,114.82 145.02,114.82 143.26,116.59 140.32,116.59 139.45,115.72 131.2,115.72 129.74,114.26 126.3,114.26 125.91,114.66 v2(125.91,115.16)
  BOTTOM w0.076: UC1.D13 125.07,111.69 124.99,111.96 124.99,112.07 124.85,112.55 124.85,112.8 124.89,112.89 124.89,113.08 124.89,113.08 124.85,113.17 124.85,113.53 125.39,114.08 125.7,114.08 126.15,114.53 126.15,114.92 v2(125.91,115.16)
USB3_PTX_DRX_P2: length 171.8
  TOP w0.104: CI30.2 230.66,98.04 230.34,97.72 230.34,96.93 230.72,96.54 231.09,96.54 v2(231.56,97.01)
  IN3 w0.135: v2(127.54,116.71) 127.72,116.89 127.72,117.42 128,117.7 138.93,117.7 139.59,118.35 151.63,118.35 153.07,116.91 154.37,116.91 158.52,112.76 158.52,111.44 161.68,108.28 161.68,107.96 165.36,104.28 165.36,99.42 arc(167.87,86.8) 175.03,76.09 175.97,75.15 arc(180.14,71.73) 184.9,69.18 arc(190.12,67.6) 195.56,67.06 204.06,67.06 204.75,66.38 220.57,66.38 222.97,68.78 224.59,68.78 229.12,73.32 231.28,73.32 232.25,74.29 232.25,77.87 230.67,79.45 230.67,96.5 231.02,96.86 231.41,96.86 v2(231.56,97.01)
  BOTTOM w0.076: UC1.A13 125.25,113.27 125.25,113.11 125.34,113.02 125.45,113.02 125.47,113.04 125.48,113.04 125.89,113.45 125.89,113.55 126.82,114.49 126.82,114.49 127.68,115.35 127.68,116.57 v2(127.54,116.71)
USB3_PTX_DRX_P3: length 173.1
  TOP w0.104: CI4.2 23.43,64.32 23.58,64.32 v2(23.78,64.53)
  IN3 w0.135: v2(23.78,64.53) 23.97,64.34 24.26,64.34 24.95,65.04 24.95,82.29 29.79,87.13 31.58,87.13 32.9,88.45 32.9,97.88 37.54,102.51 37.54,108.47 36.05,109.95 36.05,122.96 39.24,126.15 46.05,126.15 47.73,127.82 73.47,127.82 74.53,126.76 80.64,126.76 84.45,130.57 104.3,130.57 106.56,128.31 109.41,128.31 109.75,127.96 117.92,127.96 122.3,123.58 122.3,122.98 122.41,122.87 122.61,122.87 v2(122.76,123.02)
  BOTTOM w0.076: 124.04,116.98 124.04,116.96 124.05,116.94 124.05,116.74 124.53,116.26 124.53,114.61 124.19,114.28 124.19,113.25 124.11,113.17 124,113.17 123.93,113.23 UC1.A15
  BOTTOM w0.104: 124.04,116.98 124.04,118.62 122.12,120.53 122.12,122.38 v2(122.76,123.02)
USB3_PTX_DRX_P6: length 141.1
  TOP w0.104: CT113.1 30.07,97.31 30.07,96.94 v2(30.3,96.71)
  IN1 w0.119: v2(30.3,96.71) 30.3,96.71 29.93,97.08 29.93,97.5 30.81,98.37 31.71,98.37 32.7,99.36 32.7,109.02 30.48,111.24 30.48,123.3 31.84,124.66 36.1,124.66 36.94,125.5 46.13,125.5 48.08,127.45 79.82,127.45 82.92,130.55 104.28,130.55 105.62,129.21 114.64,129.21 117.47,126.38 117.47,124.06 118.24,123.29 118.4,123.29 118.77,122.93 v2(118.77,122.93)
  BOTTOM w0.076: UC1.C16 123.2,112.34 123.05,112.48 123.05,112.55 123.13,112.63 123.44,112.63 123.5,112.69 123.5,112.88 123.47,112.91 123.34,112.91 123.25,113 123.25,113.14 123.34,113.23 123.4,113.23 123.5,113.33 123.5,113.53 123.79,113.82 123.79,114.52 124.01,114.74 124.01,116.04 123.38,116.66 123.38,116.94 123.37,116.96 123.37,116.98
  BOTTOM w0.104: v2(118.77,122.93) 118.77,122.93 119.1,123.27 119.37,123.27 119.65,122.99 119.65,122.14 123.37,118.42 123.37,116.98
USB3_PTX_L_DRX_N2: length 5.6
  TOP w0.104: RI30.2 229.89,101.69 LI17.2 229.89,102.43 230.15,102.69 230.15,102.95 v3(230.38,103.18) 230.54,103.34 231.79,103.34 231.94,103.19 v2(232.24,103.19)
  BOTTOM w0.104: v2(232.24,103.19) 232.21,103.19 232.14,103.25 JNGFF2.27
USB3_PTX_L_DRX_P2: length 5.5
  TOP w0.104: RI29.2 230.79,101.69 LI17.3 230.79,102.48 230.66,102.61 230.44,102.61 230.37,102.69 230.37,102.84 230.67,103.14 231.7,103.14 231.93,102.92 231.93,102.77 v2(231.85,102.69)
  BOTTOM w0.104: JNGFF2.29 231.17,102.75 231.24,102.82 231.24,102.94 231.34,103.05 231.8,103.05 231.9,102.94 231.9,102.75 v2(231.85,102.69)
USB20_N1: length 208.2
  TOP w0.104: UI3.2 277.01,77.69 276.86,77.84 276.86,77.96 v2(277.06,78.16)
  IN3 w0.135: v2(277.06,78.16) 276.96,78.26 276.96,78.75 276.7,79.01 268.78,79.01 267.5,80.3 265.17,80.3 263.8,78.93 262.98,78.93 262.26,78.21 262.26,76.83 260.86,75.44 258.95,75.44 255.89,72.38 253.02,72.38 249.62,68.97 249.62,67.64 248.98,67 248.98,65.35 245.5,61.87 245.5,61.02 240.58,56.1 235.94,56.1 232.75,59.29 228.35,59.29 226.18,61.47 218.27,61.47 217.39,60.59 214.73,60.59 213.93,61.39 202.35,61.39 201.66,62.08 194.05,62.08 arc(187,63) 180.42,65.71 178.55,66.78 163.78,66.78 160.14,70.42 151.97,70.42 149.47,72.92 149.47,82.9 151.44,84.88 151.44,86.85 153.26,88.66 153.26,91.1 150.84,93.52 150.84,99.28 149.41,100.71 146.64,100.71 145.96,101.39 144.63,101.39 144.23,101 143.45,101 141.63,99.19 136.24,99.19 135.91,99.52 130.93,99.52 130.24,100.21 126.62,100.21 126.35,100.48 126.35,100.84 126.57,101.06 127.37,101.06 127.7,101.38 127.7,101.39 v2(128.04,101.73)
  BOTTOM w0.089: v2(128.04,101.73) 128.04,101.83 UC1.AB9
USB20_N1_R: length 11.8
  BOTTOM w0.104: JUSB1.2 284.36,78.73 283.94,79.16 282.98,79.16 282.39,79.74 282.03,79.74 282,79.71 281.27,79.71 280.82,79.26 280.82,78.32 280.17,77.67 280.17,77.52 280.77,76.92 DI5.2 280.55,76.76 279.99,76.19 279.99,75.58 279.77,75.35 v3(279.77,74.93) 279.77,74.63 279.55,74.41 278.99,74.41 LI7.2
USB20_N2: length 146.4
  IN1 w0.119: v2(24.91,62.53) 25.87,62.53 32.05,68.72 32.05,70.03 37.04,75.02 37.04,78.69 39.48,81.12 39.48,83.46 39.1,83.84 39.1,87.2 39.9,88 41.96,88 42.31,87.64 55.22,87.64 55.88,86.98 60.5,86.98 61.12,86.36 70.75,86.36 73.61,89.22 78.94,89.22 87.95,80.21 102.96,80.21 106.77,84.02 106.77,90.82 107.83,91.88 114.91,91.88 116.88,93.86 116.88,98.54 116.8,98.62 116.8,99.39 117.72,100.31 125.1,100.31 125.22,100.19 125.7,100.19 126.02,100.51 126.02,100.96 126.33,101.28 129.49,101.28 129.79,100.99 129.99,100.62 v2(129.99,100.62)
  BOTTOM w0.076: UC1.AD6 129.72,101.07 v2(129.99,100.62)
  BOTTOM w0.104: LI3.1 24.31,62.54 24.51,62.34 24.71,62.34 v2(24.91,62.53)
USB20_N2_R: length 12.6
  BOTTOM w0.104: LI3.2 22.88,62.54 22.71,62.37 22.56,62.37 22.09,62.85 v3(21.66,62.85) 21.31,62.85 21.07,62.6 21.07,61.13 20.51,60.56 20.11,60.56 20,60.67 DI2.3 19.14,60.56 18.54,60.56 18.44,60.67 18.44,60.78 18.47,60.81 18.47,61.38 18.44,61.41 18.44,61.67 17.56,62.55 16.04,62.55 15.83,62.75 JUSB2.2
USB20_N4: length 192.3
  TOP w0.104: RI48.1 234.17,106.37 LI8.1 234.75,106.37 235.02,106.64 235.51,106.64 v2(235.69,106.46)
  IN3 w0.135: v2(235.69,106.46) 235.69,106.49 235.31,106.88 234.88,106.88 234.77,106.77 234.77,106.34 235.13,105.98 236.52,105.98 237.39,105.12 237.39,100.19 236.3,99.1 236.3,98.24 233.59,95.53 233.59,79.63 236.05,77.16 237.61,77.16 239.12,75.65 239.12,72.12 238.3,71.3 237.59,71.3 237.16,70.87 237.16,70.57 235.51,68.93 235.08,68.93 232.29,66.14 227.91,66.14 224.46,62.69 217.65,62.69 216.81,61.85 215.55,61.85 214.73,62.68 202.89,62.68 202.26,63.3 194.81,63.3 arc(186.54,64.52) 178.98,68.07 177.41,69.11 171.57,69.11 171.12,68.65 170.28,68.65 169.89,69.05 169.89,70.52 170.93,71.56 170.93,73.29 170.48,73.73 169.6,73.73 168.84,74.49 168.84,77.4 165.49,81.45 165.49,83.03 164.64,85.05 164.26,85.32 162.83,85.32 162.37,85.77 162.37,88.2 161.85,88.72 161.16,88.72 159.49,90.4 155.85,90.4 154.51,91.75 154.51,94.83 154.14,95.2 154.14,99.58 151.51,102.21 144.96,102.21 144.15,103.02 143.8,103.02 141.68,100.9 141.68,100.47 141.13,99.92 140.42,99.92 139.94,100.4 138.84,100.4 138.56,100.68 130.69,100.68 130.3,101.08 128.07,101.08 127.91,100.92 127.91,100.8 v2(128.11,100.61)
  BOTTOM w0.089: UC1.AD9 128.11,100.69 v2(128.11,100.61)
USB20_N4_L: length 6.7
  TOP w0.104: RI48.2 233.24,106.37 LI8.2 232.63,106.37 232.28,106.72 232.03,106.72 231.79,106.96 v3(231.79,107.64) 231.79,108.3 232.08,108.59 232.08,108.84 232.04,108.88 232.04,109.43 232.08,109.47 232.08,109.82 231.97,109.92 231.83,109.92 v2(231.61,109.71)
  BOTTOM w0.104: v2(231.61,109.71) 231.39,109.92 231.18,109.92 231.01,109.75 JNGFF2.9
USB20_N5: length 185.3
  TOP w0.104: v2(41.22,84.3) 41.22,85.18 42.19,86.14 42.19,87.8 41.62,88.37 41.62,97.99 42,98.37 42,110.19 44.55,112.74 44.55,113.28 48.29,117.02 51.47,117.02 54.37,119.91 54.37,120.5 54.98,121.12 55.85,121.12 56.01,121.28 LZ1.1
  IN1 w0.119: v2(134.69,96.77) 134.69,96.23 135.02,95.9 136.48,95.9 138.21,94.17 138.21,89.95 140.77,87.39 141,87.39 145.13,83.26 145.13,76.15 142.78,73.8 86.2,73.8 80.45,79.56 53.83,79.56 53.58,79.82 45.87,79.82 45.07,80.62 43.45,80.62 42.09,81.98 42.09,82.84 41.28,83.65 41.28,84.23 v2(41.22,84.3)
  BOTTOM w0.076: v2(134.69,96.77) 134.38,97.08 134.38,97.37 134.21,97.55 132.46,97.55 132.33,97.68 132.33,97.78 UC1.AJ1
USB20_N5_R: length 16.8
  TOP w0.104: LZ1.2 57.61,121.28 57.83,121.05 58.13,121.05 DV8.1 58.71,121.05 59.32,121.05 59.62,121.36 59.62,128.88 59.6,128.91 59.6,129.5 59.62,129.53 59.62,130.07 58.85,130.85 58.58,130.85 58.37,130.63 58.2,130.63 58.09,130.52 58.09,130.37 v2(58.18,130.28)
  BOTTOM w0.104: v2(58.18,130.28) 58.18,130.5 58.03,130.65 57.76,130.65 56.91,131.5 56.91,131.9 56.75,132.06 JEDP1.12
USB20_N7: length 143.8
  IN1 w0.119: v2(134.44,98.61) 134.25,98.42 134.25,98.27 134.4,98.13 136.92,98.13 137.97,97.07 137.97,96.48 139.75,94.71 143.43,94.71 145.46,92.67 145.46,87.54 146.42,86.58 146.42,70.52 151.49,65.45 163.24,65.45 163.56,65.13 170.39,65.13 174.03,61.48 177.41,61.48 178.36,60.53 214.47,60.53 214.8,60.2 220.33,60.2 220.62,60.48 221.78,60.48 222.03,60.23 222.03,60.02 v2(222.23,59.82)
  BOTTOM w0.076: UC1.AH1 132.04,98.48 132.04,98.36 132.11,98.3 132.8,98.3 133.67,99.16 133.97,99.16 134.15,98.99 134.15,98.82 134.36,98.61 v2(134.44,98.61)
  BOTTOM w0.104: v2(222.23,59.82) 221.9,60.16 221.9,61.09 222.28,61.47 222.28,71.84 227.51,77.06 v3(227.51,77.61) 227.51,78.57 227.65,78.72 227.83,78.72 227.94,78.61 227.94,78.34 228.05,78.24 LI9.1 228.92,78.24 RI50.1
USB20_N7_L: length 7
  BOTTOM w0.104: JNGFF1.5 232.58,79.65 232.46,79.77 231.88,79.77 231.02,80.63 230.81,80.63 230.48,80.31 230.48,80.12 231.37,79.23 231.37,78.84 231.11,78.59 230.81,78.59 230.46,78.24 LI9.2 229.85,78.24 RI50.2
USB20_N8: length 187.4
  TOP w0.104: v2(39.9,85.53) 39.44,85.98 39.44,87.34 40.16,88.05 40.16,98.49 40.66,98.99 40.66,110.75 43.21,113.3 43.21,113.87 47.74,118.39 50.94,118.39 52.2,119.65 52.2,120 52,120.2 LV27.3
  IN1 w0.119: v2(39.9,85.53) 40.38,85.05 41.27,85.05 42.34,86.12 52.74,86.12 55.8,83.06 58.66,83.06 61.4,80.31 80.7,80.31 86.52,74.49 142.55,74.49 144.48,76.42 144.48,83 140.77,86.7 140.54,86.7 137.51,89.73 137.51,93.75 136.1,95.16 133.48,95.16 132.03,96.61 130.29,96.61 129.5,97.4 128.27,97.4 127.66,98.02 127.66,98.63 127.91,98.88 127.91,99.43 v2(128.05,99.57)
  BOTTOM w0.089: UC1.AF8 128.05,99.66 v2(128.05,99.57)
USB20_N8_R: length 13.5
  TOP w0.104: v2(51.72,131.27) 52.02,130.97 52.02,129.88 51.99,129.85 51.99,129.28 52.02,129.25 v3(52.02,127.68) 52.02,125.33 53.06,124.29 53.06,124.02 52.96,123.91 52.44,123.91 DV4.2 52.49,123.4 52.93,123.4 53.06,123.27 53.06,123.06 52.2,122.2 52.2,121.96 52,121.76 LV27.4
  BOTTOM w0.104: JEDP1.2 51.75,131.93 51.91,131.77 51.91,131.46 v2(51.72,131.27)
USB20_N9: length 151.7
  TOP w0.076: v2(28.31,81.32) 28.66,81.22 29.27,81.22 UT5.K5
  IN1 w0.119: v2(134.29,100.14) 134.29,100.51 134.22,100.58 130.95,100.58 130.35,99.99 126.5,99.99 126.23,99.71 126.23,99.29 125.84,98.9 124.82,98.9 124.25,99.48 119.31,99.48 118.83,99.01 118.83,98.57 117.79,97.53 117.79,92.15 116.5,90.85 108.32,90.85 107.66,90.19 107.66,83.61 103.37,79.32 87.51,79.32 78.62,88.21 73.85,88.21 71.13,85.49 60.64,85.49 60.03,86.1 55.46,86.1 54.8,86.76 41.94,86.76 41.57,87.14 41.23,87.14 40.86,86.77 v2(40.86,86.61)
  BOTTOM w0.076: v2(134.29,100.14) 134.37,100.14 134.6,99.91 134.6,99.78 134.51,99.69 133.62,99.69 133.02,99.09 132.49,98.94 132.3,98.94 132.21,98.97 132.17,98.97 132.1,98.99 132.05,99.09 132.07,99.17 132.1,99.2 UC1.AG1
  BOTTOM w0.104: v2(40.86,86.61) 40.86,86.79 41.5,87.43 41.5,88.84 40.02,90.32 28.05,90.32 27.59,89.86 27.59,88.47 26.86,87.74 25.68,87.74 24.95,87.01 24.95,85.62 25.83,84.75 25.83,82.12 26.79,81.16 27.87,81.16 28.02,81.32 v2(28.31,81.32)
USB20_N10: length 138.4
  IN1 w0.119: v2(232.19,57.8) 232.19,57.8 231.82,57.44 231.45,57.44 231.37,57.35 229.86,57.35 227.8,59.41 214.65,59.41 214.17,59.89 182.53,59.89 181.98,59.35 180.85,59.35 180.39,59.8 178.18,59.8 177.32,60.67 173.89,60.67 170.09,64.47 163.2,64.47 162.89,64.78 151.21,64.78 145.77,70.22 145.77,85.32 142.97,88.12 140.98,88.12 138.93,90.17 138.93,94.6 136.79,96.75 135.69,96.75 134.95,97.48 132.37,97.48 131.66,98.2 129.78,98.2 129.57,97.99 128.55,97.99 128.41,98.12 128.41,98.33 128.55,98.47 v2(128.7,98.47)
  BOTTOM w0.089: v2(128.7,98.47) 128.7,98.56 129.04,98.9 UC1.AH7
  BOTTOM w0.104: JUSH1.8 229.95,58.47 229.65,58.17 229.65,57.85 230.26,57.24 231.33,57.24 231.51,57.42 231.81,57.42 v2(232.19,57.8)
USB20_P1: length 208.1
  TOP w0.104: UI3.3 276.51,77.69 276.66,77.84 276.66,77.96 v2(276.46,78.16)
  IN3 w0.135: v2(127.4,101.73) 127.45,101.67 127.45,101.48 127.27,101.3 126.47,101.3 126.11,100.94 126.11,100.38 126.52,99.97 130.14,99.97 130.83,99.27 135.81,99.27 136.14,98.94 141.73,98.94 143.55,100.76 144.33,100.76 144.73,101.15 145.86,101.15 146.54,100.47 149.31,100.47 150.6,99.18 150.6,93.42 153.01,91 153.01,88.76 151.2,86.95 151.2,84.98 149.23,83 149.23,72.82 151.87,70.18 160.04,70.18 163.68,66.54 178.49,66.54 180.3,65.5 arc(186.93,62.77) 194.05,61.84 201.56,61.84 202.25,61.15 213.83,61.15 214.63,60.35 217.49,60.35 218.37,61.23 226.08,61.23 228.25,59.05 232.65,59.05 235.84,55.86 240.68,55.86 245.74,60.92 245.74,61.77 249.22,65.24 249.22,66.9 249.86,67.54 249.86,68.87 253.12,72.13 255.99,72.13 259.05,75.19 260.96,75.19 262.5,76.73 262.5,78.11 263.08,78.69 263.9,78.69 265.27,80.06 267.4,80.06 268.68,78.77 276.6,78.77 276.72,78.65 276.72,78.41 276.47,78.16 v2(276.46,78.16)
  BOTTOM w0.089: UC1.AB10 127.08,102.04 v2(127.4,101.73)
USB20_P1_R: length 11.7
  BOTTOM w0.104: JUSB1.3 283.82,79.36 283.06,79.36 282.47,79.94 v3(281.63,79.94) 281.21,79.94 280.62,79.35 280.62,78.4 279.57,77.35 279.24,77.35 278.84,76.95 DI5.3 279.39,76.76 279.79,76.35 279.79,75.66 279.54,75.41 279.54,74.72 279.42,74.61 279.17,74.61 278.92,74.86 LI7.3
USB20_P2: length 146.4
  IN1 w0.119: v2(129.28,100.61) 129.46,100.61 129.56,100.72 129.56,100.9 129.4,101.06 126.42,101.06 126.24,100.87 126.24,100.42 125.79,99.97 125.13,99.97 125.01,100.09 117.81,100.09 117.02,99.3 117.02,98.71 117.1,98.63 117.1,93.77 115,91.66 107.92,91.66 106.99,90.73 106.99,83.93 103.05,79.99 87.86,79.99 78.85,89 73.7,89 70.84,86.14 61.03,86.14 60.41,86.76 55.79,86.76 55.13,87.42 42.22,87.42 41.87,87.78 39.99,87.78 39.32,87.11 39.32,83.93 39.7,83.55 39.7,81.03 37.26,78.6 37.26,74.93 32.27,69.94 32.27,68.63 25.96,62.31 25.29,62.31 24.93,61.95 v2(24.91,61.95)
  BOTTOM w0.076: UC1.AD7 129.28,100.82 v2(129.28,100.61)
  BOTTOM w0.104: v2(24.91,61.95) 24.71,62.14 24.51,62.14 24.31,61.94 LI3.4
USB20_P2_R: length 12.6
  BOTTOM w0.104: LI3.3 22.83,61.94 22.6,62.17 22.48,62.17 22.03,62.62 21.38,62.62 21.27,62.51 21.27,61.04 20.59,60.36 20.11,60.36 20,60.26 DI2.2 19.13,60.36 18.46,60.36 18.24,60.59 v3(18.24,61.1) 18.24,61.59 17.47,62.35 16.04,62.35 15.83,62.15 JUSB2.3
USB20_P4: length 192.4
  TOP w0.104: v2(235.69,107.12) 234.84,107.12 234.69,107.27 LI8.4 234.17,107.27 RI47.1
  IN3 w0.135: v2(127.4,100.61) 127.61,100.82 127.61,100.96 127.97,101.32 130.4,101.32 130.79,100.93 138.66,100.93 138.94,100.64 140.04,100.64 140.52,100.16 141.03,100.16 141.44,100.57 141.44,101 143.7,103.26 144.25,103.26 145.06,102.45 151.61,102.45 154.38,99.68 154.38,95.3 154.75,94.93 154.75,91.85 155.95,90.64 159.59,90.64 161.26,88.96 161.95,88.96 162.61,88.3 162.61,85.87 162.93,85.56 164.41,85.56 164.59,85.38 164.84,85.21 165.73,83.08 165.73,81.53 169.09,77.48 169.09,74.59 169.7,73.98 170.58,73.98 171.17,73.39 171.17,71.46 170.13,70.42 170.13,69.15 170.38,68.9 171.02,68.9 171.47,69.35 177.49,69.35 179.11,68.27 arc(186.61,64.75) 194.81,63.54 202.36,63.54 202.99,62.92 214.83,62.92 215.65,62.1 216.71,62.1 217.55,62.93 224.36,62.93 227.81,66.38 232.19,66.38 234.98,69.17 235.41,69.17 236.92,70.67 236.92,70.97 237.49,71.54 238.2,71.54 238.88,72.22 238.88,75.55 237.51,76.92 235.95,76.92 233.35,79.53 233.35,95.63 236.06,98.34 236.06,99.2 237.15,100.29 237.15,105.02 236.42,105.74 235.03,105.74 234.53,106.24 234.53,106.87 234.78,107.12 v2(235.69,107.12)
  BOTTOM w0.089: UC1.AD10 127.4,100.75 v2(127.4,100.61)
USB20_P4_L: length 6.7
  TOP w0.104: v2(231.61,110.34) 231.83,110.12 232.06,110.12 232.28,109.9 v3(232.28,109.15) 232.28,108.5 231.99,108.21 231.99,107.96 232.02,107.93 232.02,107.36 231.99,107.33 231.99,107.04 232.11,106.92 232.28,106.92 232.63,107.27 LI8.3 233.24,107.27 RI47.2
  BOTTOM w0.104: JNGFF2.7 231.05,110.25 231.18,110.12 231.39,110.12 v2(231.61,110.34)
USB20_P5: length 185.2
  TOP w0.104: v2(41.88,84.59) 41.77,84.48 41.62,84.48 41.42,84.67 41.42,85.09 42.39,86.06 42.39,87.88 41.82,88.46 41.82,97.91 42.2,98.29 42.2,110.11 44.75,112.66 44.75,113.19 48.38,116.82 51.55,116.82 54.57,119.83 54.57,120.42 55.07,120.92 55.78,120.92 56.01,120.68 LZ1.4
  IN1 w0.119: v2(41.88,84.59) 41.64,84.35 41.64,84.12 41.5,83.99 41.5,83.74 42.3,82.93 42.3,82.07 43.54,80.83 45.16,80.83 45.96,80.04 53.67,80.04 53.92,79.78 80.54,79.78 86.29,74.02 142.69,74.02 144.91,76.24 144.91,83.17 140.91,87.17 140.67,87.17 137.99,89.86 137.99,94.08 136.39,95.68 134.93,95.68 134.42,96.19 134.42,96.45 134.03,96.84 v2(134.03,96.84)
  BOTTOM w0.076: v2(134.03,96.84) 134.03,96.85 134.21,97.03 134.21,97.3 134.14,97.38 132.38,97.38 131.89,97.87 UC1.AJ2
USB20_P5_R: length 16.4
  TOP w0.104: LZ1.3 57.57,120.68 57.75,120.85 58.2,120.85 DV7.1 58.64,120.85 59.4,120.85 59.83,121.28 v3(59.83,129.2) 59.83,130.15 58.93,131.05 58.49,131.05 58.49,131.05 v2(58.18,131.05)
  BOTTOM w0.104: v2(58.18,131.05) 57.99,130.85 57.84,130.85 57.11,131.58 57.11,131.9 57.25,132.04 JEDP1.13
USB20_P7: length 143.9
  IN1 w0.119: v2(221.65,59.82) 221.81,59.99 221.81,60.14 221.69,60.26 220.71,60.26 220.42,59.98 214.71,59.98 214.38,60.31 178.27,60.31 177.32,61.26 173.94,61.26 170.29,64.91 163.47,64.91 163.15,65.23 151.4,65.23 146.2,70.43 146.2,86.49 145.25,87.45 145.25,92.58 143.34,94.49 139.66,94.49 137.76,96.39 137.76,96.98 136.83,97.91 134.31,97.91 134.03,98.18 134.03,98.39 v2(133.86,98.56)
  BOTTOM w0.076: v2(133.86,98.56) 133.97,98.68 133.97,98.92 133.9,98.99 133.74,98.99 132.87,98.12 132.04,98.12 131.88,98.28 UC1.AH2
  BOTTOM w0.104: RI49.1 228.92,79.14 LI9.4 228.31,79.14 228.09,78.92 227.57,78.92 227.3,78.65 227.3,77.92 227.28,77.89 227.28,77.32 227.3,77.29 227.3,77.15 222.08,71.92 222.08,61.56 221.7,61.17 221.7,59.87 v2(221.65,59.82)
USB20_P7_L: length 7.1
  BOTTOM w0.104: JNGFF1.3 232.63,80.15 232.45,79.97 231.96,79.97 231.1,80.83 230.68,80.83 v3(230.49,80.64) 230.28,80.43 230.28,80.04 231.17,79.15 231.17,78.92 231.03,78.79 230.81,78.79 230.46,79.14 LI9.3 229.85,79.14 RI49.2
USB20_P8: length 187.4
  TOP w0.104: LV27.2 52.6,120.22 52.4,120.02 52.4,119.57 51.02,118.19 47.82,118.19 43.41,113.78 43.41,113.22 40.86,110.66 40.86,98.91 40.36,98.41 40.36,87.97 39.64,87.26 39.64,86.07 39.74,85.97 v2(40.36,85.97)
  IN1 w0.119: v2(40.36,85.97) 40.36,85.96 40.36,85.37 40.47,85.26 41.18,85.26 42.25,86.34 52.83,86.34 55.89,83.27 58.75,83.27 61.5,80.53 80.79,80.53 86.61,74.71 142.46,74.71 144.26,76.51 144.26,82.91 140.68,86.48 140.45,86.48 137.29,89.64 137.29,93.66 136.01,94.94 133.39,94.94 131.94,96.39 130.2,96.39 129.41,97.18 128.18,97.18 127.44,97.93 127.44,98.72 127.69,98.97 127.69,99.41 127.53,99.57 v2(127.26,99.57)
  BOTTOM w0.089: v2(127.26,99.57) 127.26,99.66 127.6,100 UC1.AF9
USB20_P8_R: length 13.5
  TOP w0.104: LV27.1 52.6,121.75 52.4,121.95 52.4,122.12 53.26,122.98 53.26,123.29 53.38,123.4 53.86,123.4 DV4.3 53.91,123.91 53.37,123.91 53.26,124.02 53.26,124.38 52.23,125.4 52.23,127.39 52.25,127.41 52.25,127.97 52.22,128 v3(52.22,129.56) 52.22,131.19 v2(52.3,131.27)
  BOTTOM w0.104: v2(52.3,131.27) 52.11,131.46 52.11,131.79 52.25,131.93 JEDP1.3
USB20_P9: length 151.7
  TOP w0.076: UT5.L5 29.02,81.62 28.84,81.8 28.73,81.8 28.61,81.69 28.3,81.69 v2(28.09,81.9)
  IN1 w0.119: v2(134.87,100.13) 134.87,100.14 134.51,100.51 134.51,100.61 134.31,100.8 130.85,100.8 130.26,100.2 126.41,100.2 126.01,99.8 126.01,99.38 125.75,99.12 124.92,99.12 124.34,99.7 119.22,99.7 118.62,99.1 118.62,98.66 117.58,97.62 117.58,92.24 116.41,91.07 108.23,91.07 107.44,90.28 107.44,83.7 103.27,79.54 87.6,79.54 78.71,88.43 73.76,88.43 71.04,85.71 60.73,85.71 60.12,86.32 55.55,86.32 54.89,86.98 42.03,86.98 41.66,87.35 41.13,87.35 40.8,87.02 40.4,87.02 v2(40.38,87.01)
  BOTTOM w0.076: v2(134.87,100.13) 134.77,100.03 134.77,99.71 134.58,99.52 133.69,99.52 133.11,98.94 132.51,98.76 132.27,98.76 132.17,98.8 132.15,98.8 131.98,98.85 131.86,99.07 131.88,99.14 131.83,99.2 UC1.AG2
  BOTTOM w0.104: v2(40.38,87.01) 40.68,87.01 40.69,87.02 40.8,87.02 41.3,87.52 41.3,88.76 39.94,90.12 28.13,90.12 27.79,89.77 27.79,88.39 26.94,87.54 25.77,87.54 25.15,86.93 25.15,85.7 26.03,84.83 26.03,82.21 26.87,81.36 27.78,81.36 28.09,81.67 v2(28.09,81.9)
USB20_P10: length 138.5
  IN1 w0.119: v2(128.05,98.47) 128.2,98.32 128.2,98.03 128.46,97.77 129.66,97.77 129.87,97.98 131.57,97.98 132.28,97.27 134.86,97.27 135.6,96.53 136.7,96.53 138.71,94.51 138.71,90.08 140.89,87.9 142.88,87.9 145.55,85.22 145.55,70.13 151.12,64.56 162.8,64.56 163.11,64.26 170,64.26 173.8,60.45 177.22,60.45 178.09,59.58 180.3,59.58 180.76,59.13 182.07,59.13 182.62,59.67 214.08,59.67 214.56,59.19 227.71,59.19 229.77,57.13 231.46,57.13 231.55,57.22 v2(232.19,57.22)
  BOTTOM w0.089: v2(128.05,98.47) 128.05,98.56 128.38,98.9 UC1.AH8
  BOTTOM w0.104: JUSH1.9 229.45,57.77 230.18,57.04 231.41,57.04 231.6,57.22 v2(232.19,57.22)
USB_OC0#: length 255.2
  TOP w0.112: UI3.13 278.86,75.02 279.11,75.26 v2(279.11,75.64)
  IN2 w0.124: v2(152.35,93.18) 151.99,93.54 151.99,98.97 149.58,101.38 149.58,107.51 151.29,109.22 151.29,111.18 150.52,111.95 v2(150.52,119.75) ; v2(140.36,81.34) 138.84,79.82 138.84,75.7 142.87,71.66 142.87,70.42 147.55,65.75 148.44,65.75 149.05,65.13 159.14,65.13 160.27,64 160.27,60.97 160.72,60.52 165.37,60.52 165.89,61.04 169.25,61.04 171.84,58.46 175.18,58.46 175.87,59.14 179.17,59.14 180.36,57.95 181.66,57.95 182.42,58.71 182.89,58.71 183.42,59.24 195.71,59.24 196.52,58.43 200.53,58.43 204.48,54.48 208.74,54.48 209.06,54.8 211.63,54.8 212.16,55.33 215.39,55.33 216.1,54.62 229.48,54.62 229.7,54.85 234.84,54.85 237.19,57.2 242.91,57.2 245.08,59.37 245.08,60.23 249.5,64.65 251.79,64.65 252.8,65.67 255.88,65.67 256.18,65.97 259.79,65.97 261.07,67.26 261.07,67.81 261.47,68.21 268.27,68.21 270.53,70.48 270.53,75.8 v2(270.2,76.13)
  IN3 w0.135: v2(150.52,119.75) 148.74,121.53 133.93,121.53 131.67,119.26 v2(131.42,119.26) ; v2(279.11,75.64) 277.96,74.5 276.06,74.5 275.13,75.42 271.5,75.42 270.78,76.13 v2(270.2,76.13) ; v2(140.36,81.34) 140.36,81.98 140.94,82.55 140.94,83.39 141.65,84.11 143.53,84.11 144.57,85.15 144.57,88.22 148.59,92.24 v2(148.59,93.18)
  BOTTOM w0.102: 129.61,115.33 127.76,113.48 UC1.A9
  BOTTOM w0.112: v2(152.35,93.18) v2(148.59,93.18) ; 129.61,115.33 129.61,116.09 130.78,117.26 130.78,118.86 131.19,119.26 v2(131.42,119.26) 131.57,119.26 131.98,119.67 RPC3.3
USB_OC1#: length 222.4
  IN1 w0.119: v2(130.64,122.63) 129.82,123.46 122.66,123.46 114.33,131.78 108.72,131.78 107.04,133.46 83.42,133.46 79.29,129.33 76.62,129.33 73.48,132.47 49.53,132.47 45.46,128.4 36.62,128.4 35.28,127.06 30.99,127.06 27.16,123.23 27.16,114.06 25.96,112.86 25.96,110.58 27.63,108.9 27.63,107.72 29.41,105.94 29.41,101.28 27.27,99.13 19.59,99.13 18.41,100.32 13,100.32 12.5,99.81 12.5,97.83 13.92,96.4 13.92,78.55 19.36,73.11 19.36,60.66 21.36,58.66 v2(23.06,58.66)
  BOTTOM w0.102: UC1.C9 127.76,112.22 128.09,112.55 128.09,113.42 129.77,115.1
  BOTTOM w0.112: v2(23.06,58.66) 23.34,58.38 23.34,56.17 22.88,55.71 UI1.3 ; v2(130.64,122.63) 130.64,121.18 130.91,120.91 132.31,120.91 132.48,120.74 RPC3.2 132.48,119.54 131.68,118.74 v1(131.47,118.74) 131.23,118.74 131.01,118.53 131.01,117.16 129.84,115.99 129.84,115.17 129.77,115.1
USB_OC2#: length 11.5
  BOTTOM w0.076: UC1.D9 128.05,111.65 128.05,111.8 128.21,111.97 128.45,111.97 128.85,112.37 129,112.37 129.15,112.52 129.15,113.26 131.71,115.83 131.74,115.83 132.43,116.52 v1(132.43,116.66) 133.04,117.28 133.04,119.28 132.98,119.34 RPC3.1
USB_OC3#: length 9.5
  BOTTOM w0.102: 129.39,115.43 127.45,113.49 127.45,112.98 UC1.B9
  BOTTOM w0.112: 129.39,115.43 129.39,116.67 v1(129.84,117.12) 130.55,117.84 130.55,119.16 131.48,120.09 RPC3.4
USB_PWR_EN1#: length 274.8
  TOP w0.107: v2(254.09,79.03) 253.64,78.59 253.64,78.24 253.71,78.18 RPE11.3 ; UE1.K3 v2(254.28,85.06)
  IN1 w0.119: v2(254.28,85.06) 254.28,85.04 253.64,84.4 253.64,79.47 v2(254.09,79.03)
  IN2 w0.124: v2(237.46,56.55) 237.46,56.07 235.29,53.9 235.29,52.84 234.92,52.47 229.9,52.47 229,53.37 219.66,53.37 218.53,52.24 214.24,52.24 213.74,52.75 210.15,52.75 208.64,51.24 184.66,51.24 183.33,52.57 179.71,52.57 177.61,54.67 161.44,54.67 159.13,56.98 146.3,56.98 144.7,55.38 141.79,55.38 140.26,54.23 104.01,54.23 102.9,53.11 75.65,53.11 71.63,57.14 69.73,57.14 69.28,57.59 65.42,57.59 v2(64.98,57.15)
  IN3 w0.135: v2(254.09,79.03) 254.05,79.03 253.26,78.24 253.26,77.18 252.6,76.52 249.91,76.52 248.97,75.58 248.97,71.84 247.7,70.57 247.7,69.91 247.27,69.48 247.27,66.71 245.41,64.86 245.41,63.07 244.59,62.24 244.59,61.4 241.18,57.99 238.29,57.99 237.46,57.17 v2(237.46,56.55)
  BOTTOM w0.112: v2(64.98,57.15) 64.82,56.99 64.82,54.76 62.88,52.82 62.88,50.66 62.08,49.86 40.98,49.86 39.65,51.19 39.65,52.71 39.05,53.31 v4(24.03,53.31) UI1.4
USB_PWR_EN2#: length 12.5
  TOP w0.112: RPE11.4 253.21,78.8 253.88,79.48 v1(253.88,80.34) 253.88,80.89 v2(254.03,81.04) ; UE1.G5 v2(251.08,86.66)
  IN2 w0.124: v2(251.08,86.66) 251.48,86.26 251.48,84.89 251.28,84.7 251.28,81.51 251.75,81.04 v2(254.03,81.04)
USB_PWR_SHR_LFT_EN#: length 31.6
  TOP w0.107: v2(254.09,78.43) 254.21,78.31 RPE11.2 ; UE1.J3 v2(253.48,85.06)
  TOP w0.112: v1(273.87,76.35) 274.21,76.02 v2(274.41,76.02) UI3.6
  IN1 w0.119: v2(274.41,76.02) 274.03,76.4 272.12,76.4 270.94,77.58 265.48,77.58 264.34,78.72 259.96,78.72 259.61,78.37 255.36,78.37 254.98,77.99 254.53,77.99 v2(254.09,78.43) 253.42,79.1 253.42,85 v2(253.48,85.06)
USB_PWR_SHR_VBUS_EN: length 29.8
  TOP w0.107: RPE11.1 v2(254.71,78.43) 255.27,78.99 255.27,81.34 253.52,83.09 253.52,84.22 UE1.J2
  TOP w0.112: v2(274.41,76.66) 274.55,76.52 UI3.5
  IN1 w0.119: v2(274.41,76.66) 272.25,76.66 271.09,77.81 265.63,77.81 264.47,78.97 259.9,78.97 259.55,78.62 254.9,78.62 v2(254.71,78.43)
USBCOMP: length 1.9
  TOP w0.112: v2(129.35,101.72) 129.47,101.84 RC44.1
  BOTTOM w0.102: v2(129.35,101.72) 129.69,102.05 UC1.AB6
USH_DET#: length 65.1
  TOP w0.112: v2(248.18,94.19) 248.21,94.19 248.28,94.12 UE1.C13 ; DZ7.2 221.06,58.57 RZ87.1 ; DZ7.2 219.92,58.31 219.92,55.69 RE526.2 ; DZ7.2 220.62,59.99 221.38,60.74 226.98,60.74 228.15,59.57 229.34,59.57 229.62,59.86 v2(229.62,60.08)
  IN3 w0.135: v2(248.18,94.19) 245.48,91.49 245.48,85.34 244.42,84.29 244.42,83.3 243.94,82.81 243.94,81.77 244.44,81.28 244.44,74.32 245.34,73.42 245.34,70.29 243.53,68.48 243.53,65.99 240.34,62.8 237.53,62.8 236.36,61.63 231.04,61.63 229.63,60.22 229.63,60.08 v2(229.62,60.08)
USH_DET#_R: length 4.6
  TOP w0.112: RZ87.2 221.22,57.66 221.17,57.6 DZ7.1 220.62,57.29 220.91,57.01 v2(220.95,57.01) 220.71,56.77 v1(220.31,56.77)
  BOTTOM w0.112: JUSH1.26 v2(220.95,57.01)
USH_PWR_STATE#: length 87.3
  TOP w0.112: v2(222.83,56.98) 222.53,57.29 RZ10.2 ; UE2.9 v2(271.07,93.22) 271.48,93.22 v1(271.8,93.55)
  IN2 w0.124: v2(271.07,93.22) 269.67,93.22 266.33,89.88 266.33,84.41 266.79,83.95 266.79,80.85 269.26,78.37 269.26,76.21 270.2,75.27 270.2,70.47 268.17,68.44 261.34,68.44 261,68.1 260.56,68.1 258.9,66.43 255.98,66.43 255.67,66.13 252.55,66.13 251.53,65.11 249.3,65.11 244.6,60.41 244.6,59.53 242.72,57.65 237,57.65 234.69,55.33 229.75,55.33 229.33,55.75 225.83,55.75 225.24,55.16 224.15,55.16 222.83,56.48 v2(222.83,56.98)
  BOTTOM w0.112: v2(222.83,56.98) 222.95,57.1 JUSH1.22
USH_RST#_R: length 4.4
  TOP w0.112: v1(222.02,56.58) 223.14,56.58 223.42,56.86 v2(223.42,56.98) 223.47,57.03 RZ114.2
  BOTTOM w0.112: JUSH1.21 223.45,57.02 v2(223.42,56.98)
USH_SMBCLK: length 60.9
  TOP w0.112: v2(234.69,54.13) 234.53,53.98 233.67,53.98 233.36,54.29 RZ8.2 CZ62.1 232.12,53.98 231.7,53.98 231.2,54.49 229.99,54.49 229.52,54.01 229.52,53.15 229.25,52.88 v3(228.92,52.88) 228.56,52.88 228.33,53.11 228.33,55.14 v2(228.51,55.33) ; UE1.B3 v2(247.08,85.06)
  BOTTOM w0.112: v2(247.08,85.06) 247.55,84.59 247.95,84.59 249.33,83.21 249.99,83.21 250.21,82.98 250.21,79.61 251.02,78.8 251.02,75.47 250.28,74.74 250.28,70.81 248.02,68.55 248.02,64.85 246.53,63.35 246.53,61.8 245.04,60.32 245.04,58.85 240.64,54.46 240.64,53.76 239.01,52.13 235.88,52.13 235.77,52.24 235.77,53.48 235.27,53.98 234.84,53.98 v2(234.69,54.13) ; v2(228.51,55.33) 228.31,55.54 228.31,58.28 228.45,58.42 JUSH1.11
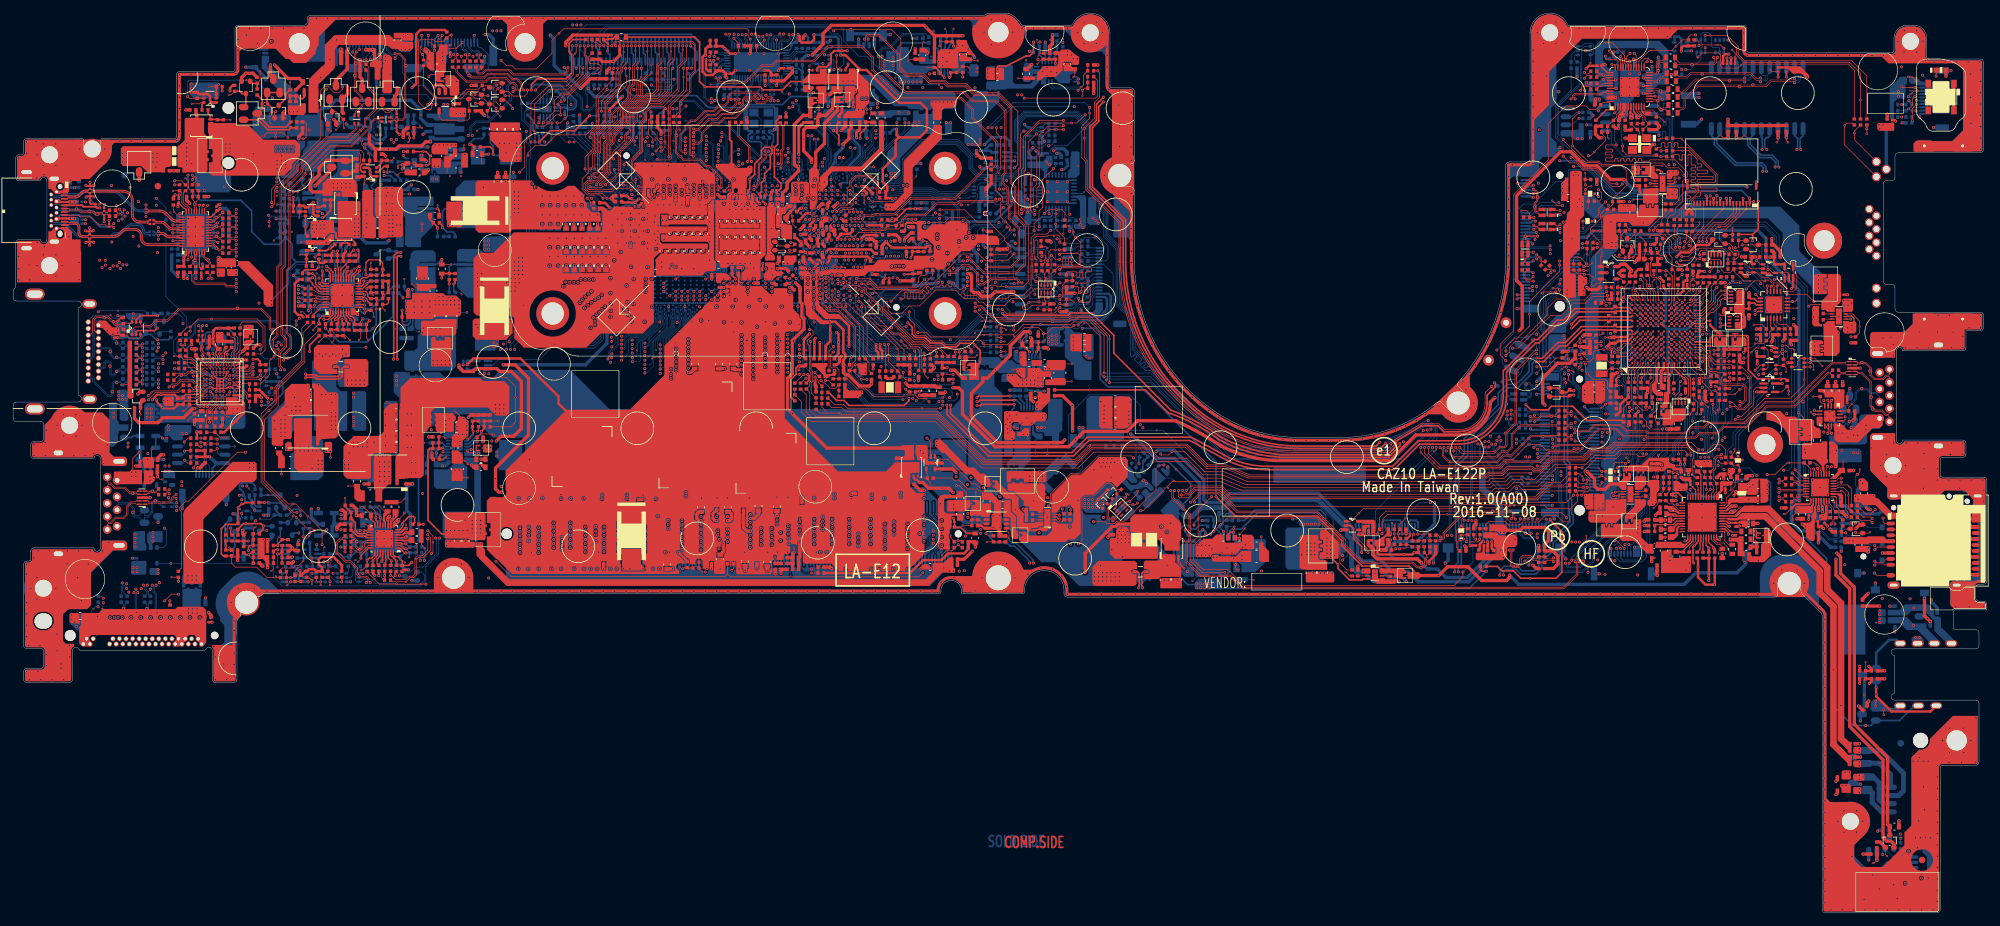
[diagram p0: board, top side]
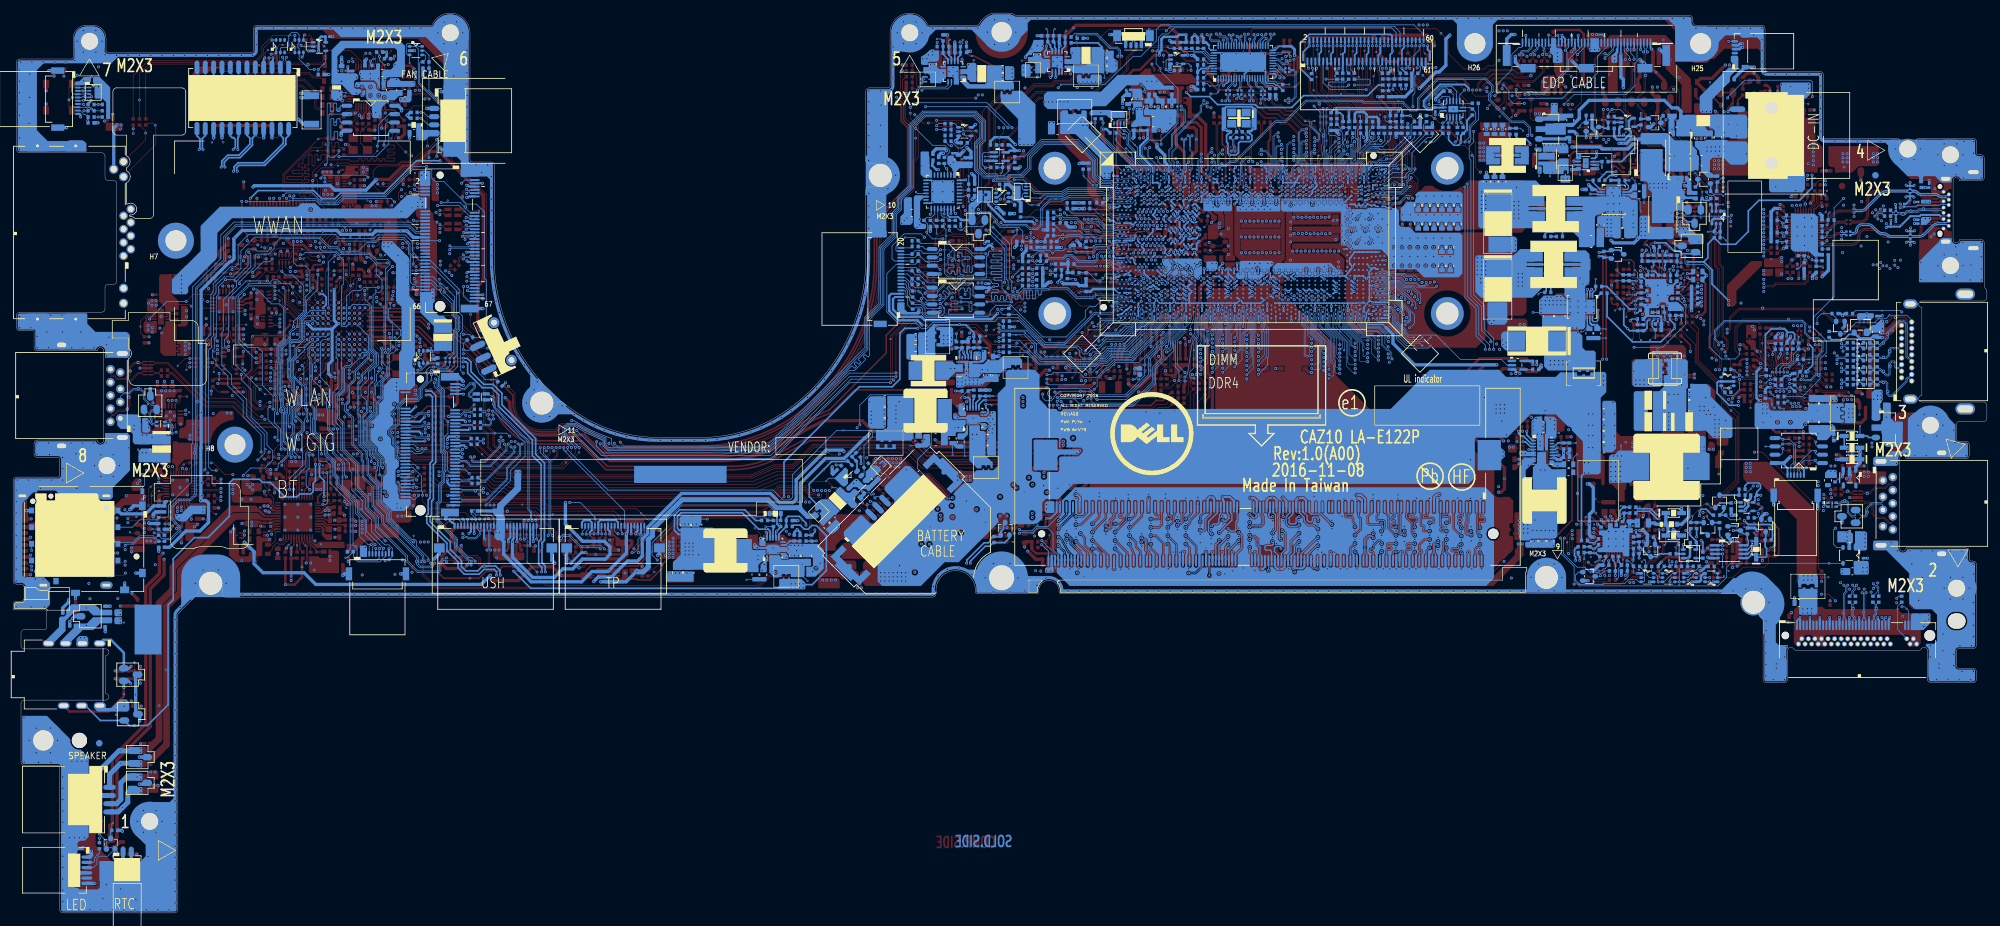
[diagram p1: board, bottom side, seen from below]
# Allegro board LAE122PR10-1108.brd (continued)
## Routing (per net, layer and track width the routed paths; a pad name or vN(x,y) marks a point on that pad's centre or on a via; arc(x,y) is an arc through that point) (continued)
USH_SMBDAT: length 62.4
  TOP w0.107: v2(249.48,86.66) UE1.E5
  TOP w0.112: v2(234.69,53.55) 234.5,53.74 233.64,53.74 RZ9.2 CZ63.1 232.12,53.74 231.61,53.74 231.1,54.25 230.09,54.25 229.75,53.91 229.75,53.05 229.35,52.64 228.46,52.64 228.09,53.01 228.09,55.17 v2(227.93,55.33)
  BOTTOM w0.112: v2(227.93,55.33) 228.07,55.47 228.07,58.28 227.95,58.39 JUSH1.12 ; v2(234.69,53.55) 234.88,53.74 235.17,53.74 235.53,53.38 235.53,52.14 235.78,51.89 239.11,51.89 240.88,53.66 240.88,54.36 245.28,58.75 245.28,60.22 246.76,61.7 246.76,63.25 248.26,64.75 248.26,68.45 250.52,70.71 250.52,74.64 251.26,75.37 251.26,78.9 250.45,79.71 250.45,83.08 250.09,83.45 249.43,83.45 249.08,83.8 249.08,86.26 v2(249.48,86.66)
VCI_IN1#: length 12.1
  TOP w0.112: RE507.1 238.17,83.79 238.94,83.79 239.24,84.1 240.26,84.1 240.74,84.58 240.74,85.51 240.96,85.72 241.49,85.72 241.69,85.92 v1(242.19,85.92) 242.27,85.84 242.95,85.84 243.2,86.09 243.2,86.12 243.41,86.33 243.73,86.33 244.36,85.7 244.79,85.7 245.69,86.6 247.03,86.6 UE1.B5
VCI_IN2#: length 14.4
  TOP w0.112: UE1.D4 v2(248.68,85.86) ; v1(237.01,86.16) 237.59,86.16 RE508.1 237.97,86.73 238.73,87.5 v2(238.73,87.51)
  IN2 w0.124: v2(238.73,87.51) 239.04,87.51 240.68,85.88 242.98,85.88 243.17,86.08 243.17,86.11 243.55,86.48 245.53,86.48 246.55,85.46 248.29,85.46 v2(248.68,85.86)
VCT_LAN_R1: length 2.3
  TOP w0.112: UL1.6 246.08,122.44 245.97,122.34 v1(245.97,121.77) 245.58,121.37 RL3.1
VGA_ID: length 12.8
  TOP w0.107: UE1.H11 v2(252.66,92.23)
  TOP w0.112: v1(251.8,99.22) 251.8,100.09 v2(251.67,100.21) 250.99,100.21 RE85.1 250.99,101.1 RE84.1
  BOTTOM w0.112: v2(251.67,100.21) 252.68,99.2 252.68,92.26 v2(252.66,92.23)
VID0_PRIM_CORE: length 4.4
  TOP w0.102: PR408.2 156.75,130.17 v1(156.04,129.46)
  TOP w0.254: PR408.2 PR418.2 PR420.1 v2(158.77,129.55)
  BOTTOM w0.254: PU402.9 158.85,129.03 158.77,129.11 v2(158.77,129.55)
VID0_VCCIO: length 4.7
  TOP w0.112: v1(141.2,132.94) 141.3,132.84 PR414.2
  TOP w0.254: v2(143.28,132.15) 143.28,132.65 PR416.1 143.06,132.84 PR414.2
  BOTTOM w0.254: PU401.9 143.39,130.55 143.57,130.73 143.57,131.29 143.28,131.58 v2(143.28,132.15)
VID1_PRIM_CORE: length 4.5
  BOTTOM w0.112: v1(159.97,133.23) 159.94,133.26 159.32,133.26 PR417.2
  BOTTOM w0.254: PR417.2 159.03,132.1 PR411.2 PR419.1 159.02,130.94 158.25,130.17 PU402.8
VID1_VCCIO: length 3.8
  BOTTOM w0.112: v1(143.29,134.82) 143.08,134.61 PR413.2
  BOTTOM w0.254: PR413.2 PR415.1 143.08,132.71 142.66,132.29 142.66,131.98 142.38,131.7 PU401.8
VIDALERT_N: length 77.9
  TOP w0.112: v2(43.46,94.47) PR625.1
  IN1 w0.119: v2(93.8,118.25) 92.69,119.36 87.54,119.36 86.8,118.61 71.3,118.61 70.21,119.7 66.27,119.7 65.86,120.12 52.8,120.12 51.42,118.74 49.32,118.74 43.66,113.08 43.66,96.66 43.04,96.04 43.04,94.86 43.43,94.47 v2(43.46,94.47)
  BOTTOM w0.112: v2(43.46,94.47) 43.61,94.63 PR604.2 ; RC152.1 93.56,120.65 RC153.2 94.04,119.3 94.04,118.49 v2(93.8,118.25)
VIDALERT_N_B: length 2.3
  TOP w0.112: PR625.2 46.68,93.97 PU602.36
VIDSCLK: length 85.3
  TOP w0.112: v2(43.46,93.8) PR618.1
  IN1 w0.119: v2(94.97,118.24) 93.35,119.86 87.33,119.86 86.59,119.11 79.89,119.11 79.13,119.88 70.78,119.88 70.45,120.2 66.48,120.2 66.07,120.62 52.59,120.62 51.22,119.24 49.11,119.24 43.16,113.29 43.16,96.95 42.53,96.32 42.53,94.65 43.38,93.8 v2(43.46,93.8)
  BOTTOM w0.076: 96.15,115.97 96.15,114.98 v1(96.3,114.84) 96.61,114.52 96.61,113.38 UC1.A63
  BOTTOM w0.102: 96.15,115.97 95.41,116.71 CC321.1
  BOTTOM w0.112: PR601.2 44.02,93.8 v2(43.46,93.8) ; v2(94.97,118.24) 94.97,118.44 CC321.1
VIDSCLK_B: length 2.4
  TOP w0.112: PR618.2 45.62,93.66 v1(46.46,93.66) 46.51,93.66 46.71,93.57 PU602.37
VIDSOUT: length 87.3
  TOP w0.112: v2(43.46,95.64) PR626.1
  IN1 w0.119: v2(92.67,118.25) 92.67,118.67 92.52,118.82 91.83,118.82 91.71,118.7 91.71,117.66 91.59,117.54 91.35,117.54 91.23,117.66 91.23,118.74 91.11,118.85 90.87,118.85 90.75,118.74 90.75,117.66 90.63,117.54 89.44,117.54 89.32,117.66 89.32,118.74 89.2,118.85 88.96,118.85 88.84,118.74 88.84,117.66 88.72,117.54 87.53,117.54 87.41,117.66 87.41,117.99 87.29,118.11 71.09,118.11 70.04,119.16 66.11,119.16 65.7,119.57 52.96,119.57 51.63,118.24 49.53,118.24 44.16,112.88 44.16,96.35 v2(43.46,95.64)
  BOTTOM w0.076: UC1.D64 96.11,111.93 96.41,112.22 96.41,112.46 96.2,112.67 96.2,113.56 96.24,113.6 96.24,114.19 95.53,114.91 v1(95.53,115.87) 95.53,115.91 94.08,117.36
  BOTTOM w0.112: RC157.1 v2(92.67,118.25) 92.67,118.03 93.11,117.59 93.85,117.59 94.08,117.36 ; PR605.2 43.58,95.51 v2(43.46,95.64)
VIDSOUT_B: length 2.5
  TOP w0.112: PU602.35 46.95,94.37 46.62,94.42 PR626.2
VRALERT#: length 22.6
  TOP w0.112: RC73.1 141.57,85.41 140.99,85.99 139.52,85.99 138.6,86.9 137.03,86.9 132.07,91.87 v1(132.07,92.1) 132.07,92.25 129.75,94.56 129.75,94.87 129.49,95.13 128.99,95.13 128.69,94.83 128.22,94.83 127.72,95.32 127.11,95.32 126.71,95.73 126.23,95.73 126.12,95.84 126.12,96.09 v2(125.64,96.57)
  BOTTOM w0.102: v2(125.64,96.57) 126.1,97.03 UC1.AM11
VSA_SEN+: length 125.4
  TOP w0.112: RC168.2 117.19,120.13 117.19,116.49 116.93,116.23 116.93,114.31 116.85,114.23 116.55,114.23 v2(116.55,114.23)
  TOP w0.203: PC650.1 52.08,100.28 PC652.1 51.22,100.4 v2(51.89,101.08)
  IN3 w0.135: v2(51.89,101.08) 52.08,101.26 52.08,101.64 50.63,103.09 50.63,107.15 49.7,108.08 47.92,108.08 46.75,109.25 46.75,115.4 50.32,118.97 52.43,118.97 52.87,119.41 65.7,119.41 66.17,118.93 68.15,118.93 68.99,118.09 69.35,118.09 69.51,118.25 69.51,118.38 v2(69.34,118.55) ; v2(121.09,108.91) 120.66,108.92 120.27,108.52 118.16,108.52 117.45,109.23 117.45,111.11 117.75,111.42 117.75,112.19 117.34,112.6 116.78,112.6 116.45,112.93 116.45,113.85 116.55,113.95 v2(116.55,114.23)
  BOTTOM w0.112: v2(69.34,118.55) 69.53,118.75 69.53,119.79 70.48,120.74 72.38,120.74 75.67,124.03 75.67,124.75 75.22,125.2 75.22,126.17 76.37,127.32 83.66,127.32 86.76,124.21 86.76,122.71 86.96,122.52 87.76,122.52 88.94,123.7 94.87,123.7 95.1,123.92 103.77,123.92 106.93,120.76 108.46,120.76 114.58,114.64 115.37,114.64 115.96,114.04 116.35,114.04 v2(116.55,114.23)
  BOTTOM w0.203: PR649.2 PC640.2 52.55,100.34 51.89,101 v2(51.89,101.08)
  BOTTOM w0.254: v2(121.09,108.91) 121.36,108.64 UC1.H20
VSA_SEN-: length 126.1
  TOP w0.112: RC166.1 117.43,120.13 117.43,116.39 117.17,116.13 117.17,114.21 116.97,114.01 v2(116.97,113.55)
  TOP w0.203: v2(52.53,101.08) 52.68,100.93 52.68,99.88 52.17,99.38 PC650.2 51.29,99.38 PC649.1 51.17,99.39 49.93,98.16 PU602.26
  IN3 w0.135: v2(69.96,118.54) 69.77,118.35 69.77,118.14 69.46,117.83 68.88,117.83 68.04,118.67 66.07,118.67 65.59,119.14 52.98,119.14 52.54,118.71 50.43,118.71 47.02,115.29 47.02,109.36 48.03,108.34 49.81,108.34 50.89,107.26 50.89,103.2 52.34,101.75 52.34,101.26 v2(52.53,101.08) ; v2(116.97,113.55) 116.71,113.29 116.71,113.04 116.89,112.86 117.45,112.86 118.01,112.3 118.01,111.31 117.71,111 117.71,109.34 118.27,108.78 119.96,108.78 v2(120.1,108.92)
  BOTTOM w0.112: v2(116.97,113.55) 116.71,113.8 115.87,113.8 115.27,114.4 114.48,114.4 108.36,120.52 106.83,120.52 103.67,123.68 95.19,123.68 94.97,123.46 89.04,123.46 87.85,122.28 86.86,122.28 86.52,122.61 86.52,124.11 83.56,127.08 76.47,127.08 75.46,126.07 75.46,125.29 75.91,124.85 75.91,123.93 72.48,120.51 70.58,120.51 69.77,119.7 69.77,118.73 v2(69.96,118.54)
  BOTTOM w0.254: UC1.H21 120.38,108.64 v2(120.1,108.92)
VSET_5105: length 6.9
  TOP w0.112: RE77.1 CE38.1 244.88,93.61 v2(245.29,93.2) ; UE1.C9 v2(247.88,90.66)
  IN2 w0.124: v2(247.88,90.66) 247.48,91.06 247.48,92.45 246.74,93.2 v2(245.29,93.2)
WIGIG_32KHZ: length 3.1
  TOP w0.112: RZ56.1 239,67.89 v2(239.03,67.86)
  BOTTOM w0.112: v2(239.03,67.86) 239.56,68.4 JNGFF1.50
WLAN_COEX1: length 23.7
  TOP w0.112: v2(236.64,83.23) 236.27,83.23 v1(235.93,82.89)
  BOTTOM w0.112: JNGFF1.48 241.7,68.9 242.37,69.58 242.37,70.92 242.93,71.48 242.93,72.44 243.49,73 243.49,73.49 242.49,74.49 242.49,75.44 242.99,75.94 242.99,76.27 242.31,76.95 242.31,77.24 241.09,78.46 239.23,78.46 238.86,78.83 238.86,79.98 237.77,81.07 237.77,82.71 237.25,83.23 v2(236.64,83.23) 235.32,83.23 234.83,83.72 RZ130.2
WLAN_COEX2: length 23.1
  TOP w0.112: v1(237.73,82.48) 237.48,82.73 v2(236.95,82.73)
  BOTTOM w0.112: RZ129.2 234.17,83.42 234.64,82.96 235.78,82.96 235.94,82.79 236.89,82.79 v2(236.95,82.73) 237.56,82.13 237.56,80.98 238.65,79.89 238.65,78.68 239.09,78.25 241,78.25 242.1,77.15 242.1,74.59 243.28,73.4 243.28,73.08 242.72,72.52 242.72,71.57 242.16,71.01 242.16,69.68 241.88,69.4 JNGFF1.46
WLAN_COEX3: length 22.1
  TOP w0.112: v2(236.96,82.08) v1(236.96,81.27)
  BOTTOM w0.112: JNGFF1.44 241.68,69.9 241.95,70.17 241.95,71.11 242.5,71.66 242.5,73.88 241.88,74.5 241.88,77.04 240.92,78 239,78 238.4,78.6 238.4,79.8 236.96,81.25 v2(236.96,82.08) 236.96,82.13 236.51,82.58 235.86,82.58 235.69,82.75 234.16,82.75 233.51,83.4 RZ128.2
WLAN_WIGIG60GHZ_DIS#: length 48.4
  TOP w0.112: DZ1.1 244.07,66.18 244.68,66.79 v2(244.85,66.79) ; UE1.L13 254.68,94.18 v1(255.38,94.88) 255.5,94.99 255.5,96.2 v2(255.93,96.63) 256.49,96.07 RE8.1
  IN2 w0.124: v2(255.93,96.63) 255.72,96.42 251.87,96.42 249.13,93.69 247.05,93.69 246.34,94.4 245.22,94.4 244.79,93.97 v2(244.79,92.84)
  BOTTOM w0.112: v2(244.85,66.79) 244.85,68.01 244.75,68.11 244.75,69.08 245.73,70.06 245.73,70.68 246.89,71.83 246.89,75 245.57,76.33 245.57,78.98 245.49,79.06 245.49,80.44 243.81,82.12 243.81,83.3 244.37,83.85 244.37,85.75 244.19,85.93 244.19,92.25 v2(244.79,92.84)
WLAN_WIGIG60GHZ_DIS#_R: length 2.6
  TOP w0.112: v1(241.56,66.52) 241.88,66.52 v2(242.04,66.68) 242.15,66.68 DZ1.2
  BOTTOM w0.112: v2(242.04,66.68) 241.82,66.9 JNGFF1.56
WRST#: length 3.9
  TOP w0.112: UE2.4 268.75,90.05 269.05,89.75 270.11,89.75 CE500.1 RE6.2
WWAN_COEX1: length 16.1
  TOP w0.112: v2(235.61,95) 235.35,95.26 v4(234.59,95.26)
  BOTTOM w0.112: RZ130.1 234.21,85.22 233.85,85.22 233.62,85.45 233.62,88.82 233.3,89.14 233.3,90.57 233.85,91.13 233.85,92.88 235.61,94.64 v2(235.61,95) 235.98,95 236.98,96 JNGFF2.56
WWAN_COEX2: length 17.4
  TOP w0.112: v2(235.04,94.68) 233.17,94.68 v4(232.98,94.5)
  BOTTOM w0.112: JNGFF2.54 236.95,96.5 235.91,95.46 235.38,95.46 235.04,95.13 v2(235.04,94.68) 233.64,93.28 233.64,91.22 233.08,90.66 233.08,89.05 233.4,88.73 233.4,85.36 RZ129.1
WWAN_COEX3: length 16.4
  TOP w0.112: v4(235.79,96.62) 235.63,96.47 v2(235.63,95.9)
  BOTTOM w0.112: JNGFF2.52 236.74,97 v2(235.63,95.9) 235.34,95.9 233.42,93.98 233.42,91.31 232.87,90.75 232.87,88.96 233.19,88.64 233.19,84.92 RZ128.1
WWAN_PWR_EN: length 4.5
  TOP w0.102: RZ43.1 v1(239.5,112.83)
  TOP w0.112: v2(239.55,111.01) 239.5,111.06 RZ43.1 CZ198.1
  BOTTOM w0.102: v2(239.55,111.01) 239.04,110.5 JNGFF2.6
WWAN_RADIO_DIS#: length 51.4
  TOP w0.112: UE1.M2 255.88,84.26 255.88,83.49 256.53,82.85 v2(257.07,82.85) 257.67,82.26 257.67,81.68 v1(257.76,81.6) 257.81,81.54 258.33,81.54 RE10.1 ; DZ5.1 241.39,109.23 v2(241.53,109.23)
  IN1 w0.119: v2(257.07,82.85) 258.49,84.28 258.49,85.8 261.87,89.18 261.87,95.67 261.45,96.09 261.45,98.51 261.69,98.75 261.69,100.7 262.36,101.36 v2(262.36,101.41)
  IN2 w0.124: v2(241.53,109.23) 243.12,109.23 246.84,105.5 258.33,105.5 262.36,101.48 v2(262.36,101.41)
WWAN_RADIO_DIS#_R: length 3.5
  TOP w0.102: v1(240.43,110.79) 240.03,110.79 v2(239.55,110.31)
  TOP w0.112: v2(239.55,110.31) 239.55,110.05 DZ5.2
  BOTTOM w0.102: JNGFF2.8 239.24,110 v2(239.55,110.31)
WWAN_WAKE#: length 47.5
  TOP w0.107: UE1.M13 255.48,93.6 256.39,94.5 256.39,94.83 v2(256.97,95.41)
  TOP w0.112: v1(234.48,108.62) 235.24,107.86 v2(236.04,107.86) ; RE38.1 256.97,95.53 v2(256.97,95.41)
  IN2 w0.124: v2(236.04,107.86) 236.98,107.86 238.35,106.49 242.85,106.49 244.54,104.8 257.88,104.8 260.53,102.15 260.53,100.72 v2(260.78,100.47)
  IN3 w0.135: v2(256.97,95.41) 256.97,97.67 258.65,99.35 259.66,99.35 v2(260.78,100.47)
  BOTTOM w0.112: v2(236.04,107.86) 232.78,107.86 231.17,106.25 JNGFF2.15
XCLK_BIASREF: length 16.4
  TOP w0.112: RC324.1 108.34,110.09 v2(109.12,110.87) ; v1(119.21,104.58) 118.77,105.03 RC52.1 118.69,105.62 v2(118.69,106.26)
  IN1 w0.097: v2(118.69,106.26) 118.26,106.69 116.22,106.69 115.08,107.83 115.08,108.55 114.56,109.07 114.48,109.07 114.16,109.39 114.16,109.77 113.33,110.61 113.33,111.09 113.02,111.4 109.65,111.4 v2(109.12,110.87)
  BOTTOM w0.076: UC1.E42 108.85,110.59 v2(109.12,110.87)
XDP_DBRESET#: length 90.8
  TOP w0.112: RC137.1 88.68,132.67 88.96,132.67 v2(89.41,132.22) 89.37,132.17 CC32.1 ; v2(125.02,134.5) 125.25,134.73 v4(127.62,134.73) 133.78,134.73 135.24,133.27 135.24,128.93 136.2,127.96 138.76,127.96 139.76,126.96 142,126.96 142.52,126.44 145.21,126.44 146.59,125.07 150.2,125.07 153.06,122.21 153.06,114.09 v2(152.57,113.61)
  BOTTOM w0.112: UC12.1 152.75,115.98 153,115.73 153,114.04 v2(152.57,113.61) 152.5,113.68 RC290.1 ; v2(89.41,132.22) JXDP1.48 89.41,134.33 90.27,135.19 124.33,135.19 v2(125.02,134.5)
XDP_JTAGX: length 8.2
  BOTTOM w0.076: 98.13,117.08 98.13,116.11 98.99,115.24 98.99,113.47 UC1.A59
  BOTTOM w0.102: 98.13,117.08 98,117.2 98,117.69 v1(97.8,117.89) 97.76,117.93 97.76,118.63 RC328.2
  BOTTOM w0.112: RC87.1 CC305.1 97.18,119.33 97.51,119 RC328.2
XDP_OBS0: length 1.9
  BOTTOM w0.112: RC239.2 97.51,128.31 JXDP1.21
XDP_OBS0_R: length 23.6
  IN1 w0.119: v2(100.51,122.63) 100.51,122.79 100.16,123.14 100.16,123.31 100.52,123.66 100.52,123.83 100.35,124 100.18,124 99.82,123.65 99.66,123.65 97.24,126.06 v2(97.24,126.23)
  BOTTOM w0.076: UC1.C55 101.07,112.76 100.94,112.89 100.94,114.72 100.82,114.83 100.82,116.1 100.89,116.16 100.89,116.76 100.61,117.04 v1(100.61,117.73) 100.61,118.07 100.67,118.13 100.67,120.09
  BOTTOM w0.112: RC239.1 97.68,126.69 100.15,126.69 100.32,126.52 100.32,126.38 99.89,125.95 97.52,125.95 v2(97.24,126.23) ; 100.67,120.09 100.67,122.47 v2(100.51,122.63)
XDP_OBS1: length 2
  BOTTOM w0.112: RC240.2 96.91,128.6 JXDP1.23
XDP_OBS1_R: length 23.8
  IN1 w0.119: v2(96.35,126.23) 96.43,126.23 100.04,122.63 100.04,122.35 100.25,122.14 100.81,122.14 101.12,122.44 v2(101.12,122.63)
  BOTTOM w0.076: UC1.D55 101.07,111.92 101.39,112.23 101.39,112.46 101.34,112.51 101.34,113.38 101.1,113.61 101.1,114.79 100.99,114.9 100.99,116.03 101.05,116.09 101.05,116.89 100.93,117.02 100.93,119.42 101.09,119.58 101.09,120.09
  BOTTOM w0.112: RC240.1 94.13,127.13 93.98,126.97 93.98,126.43 94.17,126.23 v2(96.35,126.23) ; v2(101.12,122.63) 101.09,122.6 v1(101.09,121.38) 101.09,120.09
XDP_OBS2_R: length 3
  BOTTOM w0.076: T10.1 101.92,115.42 101.92,112.95 UC1.B54
XDP_OBS3_R: length 4.4
  BOTTOM w0.076: UC1.C56 100.51,112.24 100.77,112.51 100.77,114.65 100.61,114.81 T11.1
XDP_PRSNT_PIN1: length 7.3
  IN1 w0.119: v2(103.35,128.79) 103.35,128.31 102.16,127.13 v2(100.69,127.13)
  BOTTOM w0.112: RC122.1 RC121.1 v2(100.69,127.13) ; v2(103.35,128.79) 103.51,128.95 JXDP1.1
XDP_TMS: length 16.7
  TOP w0.112: v2(85.79,132.24) 85.79,131.21 v1(85.62,131.04) 85.38,130.81 85.38,127.87 84.29,126.77 80.88,126.77 v2(79.58,125.47)
  BOTTOM w0.112: v2(85.79,132.24) 86.41,132.86 JXDP1.58 ; v2(79.58,125.47) 80.3,124.74 UC8.9 80.3,123.47 80.22,123.39 78.46,123.39 RC228.1
XTAL24_IN: length 13.8
  TOP w0.104: v2(112.86,110.29) 112.86,110.35 113.09,110.58 113.18,110.58 113.62,111.02 113.62,111.9 113.74,112.02 113.74,114.08 114.75,115.09 114.75,115.81 114.91,115.97 114.96,115.97 v2(115.14,116.15)
  BOTTOM w0.104: YC1.3 114.37,119.68 114.37,119.16 CC21.1 114.34,119.1 RC46.2 114.92,117.9 114.92,117.08 114.75,116.91 114.75,116.47 114.86,116.37 114.92,116.37 v2(115.14,116.15) ; UC1.E37 111.47,110.51 111.75,110.23 112.8,110.23 v2(112.86,110.29)
XTAL24_OUT: length 10.1
  TOP w0.104: v2(114.55,116.15) 114.55,115.17 113.54,114.16 113.54,112.11 113.41,111.98 113.41,111.1 113.09,110.78 112.97,110.78 v2(112.86,110.88)
  BOTTOM w0.104: v2(112.86,110.88) 112.57,110.59 UC1.E35 ; RC295.1 RC46.1 114.46,118.21 114.72,117.95 114.72,117.16 114.55,117 114.55,116.15 v2(114.55,116.15)
XTAL24_OUT_R: length 4.9
  BOTTOM w0.102: CC22.1 113.94,119.59 113.94,120.94 YC1.1
  BOTTOM w0.112: CC22.1 113.33,119.1 112.53,118.3 RC295.2
XTALI: length 6.1
  TOP w0.112: UL1.10 247.68,122.25 248.63,121.3 248.63,120.93 RL11.2 248.32,119.45 CL14.1 248.3,118.74 YL1.1
XTALO: length 3.9
  TOP w0.112: RL34.2 RL11.1 248.3,121.25 v3(247.92,121.62) 247.28,122.26 UL1.9
XTALO_R: length 5
  TOP w0.112: YL1.3 247.78,117.41 247.78,119.11 CL13.1 247.36,119.45 246.52,120.29 RL34.1
Z2805: length 3.6
  TOP w0.127: v1(260.12,118.58) 260.5,118.2 v2(261.26,118.2)
  TOP w0.508: RL18.1 v2(261.26,118.2)
  BOTTOM w0.508: TL1.22 v2(261.26,118.2)
Z2806: length 3.1
  TOP w0.127: v1(268.68,117.49) 268.88,117.69 v2(268.88,118.2)
  TOP w0.508: RL16.1 v2(268.88,118.2)
  BOTTOM w0.508: TL1.16 v2(268.88,118.2)
Z2807: length 3.7
  TOP w0.127: v1(263.7,118.55) 263.33,118.18 v2(262.53,118.18)
  TOP w0.508: RL17.1 v2(262.53,118.18)
  BOTTOM w0.508: TL1.21 v2(262.53,118.18)
Z2808: length 3.2
  TOP w0.127: v2(270.15,118.18) 270.15,117.75 v1(270.43,117.47)
  TOP w0.508: RL15.1 v2(270.15,118.18)
  BOTTOM w0.508: TL1.15 v2(270.15,118.18)
N04748: length 4.5
  TOP w0.112: v1(60.41,55.64) 59.84,56.21 v2(59.84,56.27)
  TOP w0.203: v2(59.84,56.27) 59.28,56.27 59.12,56.44 PU901.3
  BOTTOM w0.203: PC939.1 59.18,56.98 59.84,56.32 v2(59.84,56.27) 60.01,56.44 60.5,56.44 PR929.1
N16399089: length 8
  BOTTOM w0.112: PD901.1 48.91,56.29 v1(49.11,56.09)
  BOTTOM w0.508: PD903.1 48.59,58.93 48.59,57.87 PD901.1 ; PD903.1 PD904.1 ; PD903.1 50.38,59.26 50.57,59.45 PR916.2
N16400770: length 42.2
  TOP w0.254: v2(44.55,81.57) 44.65,81.67 45.95,81.67 46.24,81.38 v1(49.71,81.38) 50.14,81.81 50.14,83.03 50.39,83.28 PR901.3
  IN3 w0.203: v2(49.95,60.72) 44.93,60.72 39.88,65.76 39.88,75.53 41.75,77.4 41.75,79.22 44.23,81.7 44.42,81.7 v2(44.55,81.57)
  BOTTOM w0.254: v2(49.95,60.72) 50.32,60.72 51.23,61.63 53.25,61.63 PR910.1
N16404606: length 3.1
  BOTTOM w0.112: v1(44.85,60.54) 44.85,60.07 45.11,59.82 PR950.1
  BOTTOM w0.254: PD905.3 43.17,59.52 PR939.2 PR950.1
N16404788: length 5.4
  IN1 w0.254: v2(43.52,57.92) 44.47,57.92 v2(46.25,56.14)
  BOTTOM w0.254: v2(43.52,57.92) 42.82,57.92 PD905.1 ; PU903.1 46.25,56.14 v2(46.25,56.14)
N16775301: length 4.4
  TOP w0.112: v1(65.84,72.36) 65.61,72.59 PR206.1
  TOP w0.254: PR206.1 PR204.2 PC208.2 65.28,70.81 65.38,70.92 v2(65.45,70.92)
  BOTTOM w0.254: PU200.16 65.78,70.66 65.53,70.92 v2(65.45,70.92)
N16775385: length 5.4
  TOP w0.112: PC218.1 71.17,73.02 73.05,73.02 v4(73.2,72.87)
  TOP w0.254: v2(70.67,71.84) PC218.1
  BOTTOM w0.254: PU200.3 69.56,71.11 70.29,71.84 v2(70.67,71.84)
N16775433: length 1.9
  TOP w0.112: v4(69.28,68.45) 68.69,69.04 PR202.2
N16775513: length 1.8
  BOTTOM w0.112: v1(62.46,69.92) 63.02,69.37 PR203.2
N16775517:
  vias: v2(65.43,68.15)
N16776853: length 3
  TOP w0.112: v1(65.94,69.54) 65.56,69.16 PC207.1
  TOP w0.254: PC207.1 64.93,69.56 v2(65.18,69.8)
  BOTTOM w0.254: PU200.14 65.88,69.76 65.87,69.76 65.49,69.76 65.49,69.76 65.23,69.76 v2(65.18,69.8)
N16783014:
  vias: v1(156.86,77.33) v2(155.95,77.48) v2(155.95,76.9)
N16783095: length 2.5
  BOTTOM w0.112: PR108.1 155.31,79.58 156.34,78.55 v1(156.34,78.5)
  BOTTOM w0.254: PR108.1 155.07,79.72 PC113.2
N16783134: length 3
  BOTTOM w0.112: PR117.1 186.32,60.41 v1(187.58,60.41)
  BOTTOM w0.254: PC127.2 PR117.1
N16783223: length 2.7
  TOP w0.102: v1(187.72,58.64) 186.84,57.76 v2(186.84,57.1)
  TOP w0.112: PC119.1 186.71,57.22 v2(186.84,57.1)
N16784595: length 1.8
  BOTTOM w0.112: PC102.1 v1(157.57,69.84)
N16784799: length 1.4
  BOTTOM w0.102: v1(188.97,50.79) 188.89,50.87 PC114.1
N17185092: length 3.2
  BOTTOM w0.112: PR1214.2 40.18,102.97 v1(39.72,102.51)
  BOTTOM w0.254: PQ1204.6 40.59,103.9 PR1218.2 PR1214.2
N17188126: length 2.2
  TOP w0.102: v2(38.29,62.6) v1(38.81,62.6)
  TOP w0.254: PR1211.2 38.25,62.56 v2(38.29,62.6)
  BOTTOM w0.254: PU1200.1 v2(38.29,62.6)
N17188417: length 3.7
  BOTTOM w0.112: PR1215.2 36.84,63.79 v1(35.92,64.71)
  BOTTOM w0.254: PU1200.2 37.07,61.95 36.84,62.18 PR1215.2
N17263481: length 6
  TOP w0.112: PU602.39 46.63,92.77 46.12,92.26 45.69,92.26 45.41,92.53 PR612.2 45.25,92.18 45.49,91.93 45.49,91.59 PR614.2 44.14,91.67 v1(43.84,91.67)
N17264741: length 2.6
  TOP w0.203: PU602.40 46.93,92.37 v1(46.42,91.86) 45.74,91.18 PR616.2
N17335638: length 4.8
  TOP w0.112: v1(144.63,59.1) 144.66,59.07 PR516.1 146.07,59.08 PC515.2 PR515.2 147.27,59.94 147.9,59.31 PU503.3
N17340170: length 3.9
  BOTTOM w0.254: PR1226.2 PR1215.1 37.76,63.7 v1(38.84,63.7) PQ1205.1
N17370862: length 4.6
  TOP w0.508: v2(46.02,110.87) v1(47.06,111.91) 48.51,113.36 PQ5.1
  BOTTOM w0.508: v2(46.02,110.87) 46.02,110.88 PC4.2
N17370885: length 5.2
  TOP w0.112: v1(52.61,115.91) 52.94,115.58 52.94,114.46 52.53,114.04 PR10.2
  TOP w0.508: PR10.2 PR15.1 51.74,113.12 51.4,112.77 PQ5.2
N17370921: length 2.4
  TOP w0.112: v1(53.49,111.15) PQ1.6
  TOP w0.508: PQ1.6 53.03,112.33 52.91,112.2 PR15.2
N17370927: length 2.5
  BOTTOM w0.112: PQ7.1 44.03,112.45 v1(44.42,112.85)
  BOTTOM w0.254: PQ7.1 44.03,111.09 PR16.2
N17370961: length 9.9
  TOP w0.254: PR6.2 37.93,123.95 PL3.1 37.93,122.64 PQ2.1 37.2,121.68 39.05,119.82 v1(40.94,119.82) 41.53,119.82 PR3.1
N17370983: length 8.8
  TOP w0.254: PQ2.3 37.31,120.94 v1(38.06,120.19) 38.84,119.42 42.04,119.42 PR3.2 PR5.1
N17370995: length 4.1
  TOP w0.112: PR8.2 37.63,126.95 v1(37.63,128.36)
  TOP w0.254: PQ3.2 36.43,126.49 PR8.2 PR6.1
N17370999: length 5.2
  TOP w0.112: PR7.2 33.2,124.74 v1(32.84,124.74)
  TOP w0.254: PR7.2 34.52,125.28 34.88,124.92 PQ3.1 35.46,123.21 PQ2.2
N17371029: length 0.6
  TOP w0.112: v2(47.95,119.47) 48.14,119.47 v1(48.42,119.19)
N17371043: length 2.5
  BOTTOM w0.112: v1(49.2,119.42) 49.68,119.9 PQ6.1
  BOTTOM w0.254: PQ6.1 49.68,121.18 PR18.2
N17371182: length 2.1
  BOTTOM w0.112: v1(52.73,121.97) PR23.2
  BOTTOM w0.254: PR23.2 52.27,121.05 52.21,121.12 PQ6.2
N17371184: length 2.3
  BOTTOM w0.112: v1(53.01,119.19) 52.73,119.47 PR23.1
  BOTTOM w0.254: PR23.1 53.14,120.14 53.39,119.88 PU1.4
N17371196: length 1.2
  BOTTOM w0.254: PU1.1 56.54,121.18 PR21.2
N17371207: length 3.6
  BOTTOM w0.112: PR22.1 58.1,120.94 v1(58.66,120.94)
  BOTTOM w0.254: PQ8.1 58.49,119.84 58.3,119.64 PR27.1 PR22.1
N17372066: length 3.5
  TOP w0.112: PR19.2 57.67,114.77 v1(58.05,115.15)
  TOP w0.254: PR19.2 56.97,114.76 PR17.2 56.11,114.34 PQ1.3
N17372074: length 4.5
  TOP w0.112: v1(54.06,115.82) 54.33,115.56 PR25.1
  TOP w0.254: PR25.1 54.33,114.44 54.08,114.18 53.17,114.18 52.92,113.93 52.92,113.23 53.17,112.98 PQ1.5
N17372833: length 6.7
  TOP w0.203: v2(40.28,54.74) 40.58,54.74 PC1206.1 ; PC1206.1 40.98,55.14 PR1203.1 ; PC1206.1 PR1219.1 PR1201.2
  BOTTOM w0.112: v2(40.28,54.74) v1(40.28,52.7)
  BOTTOM w0.203: PU1201.3 v2(40.28,54.74)
N17479322: length 8.4
  TOP w0.254: PR1251.2 50.91,102.18 v2(50.54,102.18) 50.2,102.18 PR1252.1
  BOTTOM w0.254: PQ1215.2 44.6,100.52 46.46,100.52 46.84,100.9 47.62,100.9 v1(48.46,101.73) 48.91,102.18 v2(50.54,102.18)
N17494434: length 11.4
  TOP w0.203: PR1239.2 PR1246.1 PC1211.1 36.47,55.13 35.96,54.62 v2(35.84,54.62) 35.44,54.62 PR1238.1
  BOTTOM w0.254: PQ1212.1 33.7,56.96 PR1255.2 33.78,55.83 33.58,55.62 v1(33.58,54.36) 33.69,54.25 PD1205.1 35.51,54.62 v2(35.84,54.62) 36.37,54.09 PU1201.5
N17509431: length 4.4
  TOP w0.254: PR949.2 v2(56.6,51.45) 56.6,50.76 PR935.1
  BOTTOM w0.203: PC947.1 57.01,53.78 v1(56.59,53.36) PR947.1 56.59,51.46 v2(56.6,51.45)
N17509921: length 2.5
  BOTTOM w0.112: v1(42.62,60.51) 42.62,60.27 PD905.2
  BOTTOM w0.254: PR941.2 41,59.51 PD905.2
N17522701: length 2.1
  BOTTOM w0.112: PR942.2 47.34,55.66 v1(47.43,55.75)
  BOTTOM w0.254: PU903.2 PR942.2
N17670003: length 4.7
  TOP w0.203: PU901.30 57.12,54.17 v2(57.62,53.67) 57.62,53.11 PR936.1
  BOTTOM w0.112: v1(59.07,52.17) 58.7,52.17 58.38,52.49 58.15,52.49 PR948.1
  BOTTOM w0.254: v2(57.62,53.67) 57.61,53.66 PR948.1
N17739728: length 4.9
  BOTTOM w0.112: PR1224.1 39.09,59.95 37.78,59.95 v1(37.62,60.12)
  BOTTOM w0.254: PQ1205.3 40.08,61.29 PR1221.2 PR1224.1
N17747591: length 3.8
  TOP w0.112: PR28.1 v1(62.3,119.71)
  TOP w0.254: v2(61.04,118.18) 61.06,118.2 PR26.2 PR28.1
  BOTTOM w0.254: PQ8.3 v2(61.04,118.18)
N17747606: length 2.4
  BOTTOM w0.112: v1(62.03,119.9) 62.03,120.05 61.59,120.49 PQ8.2
  BOTTOM w0.254: PR29.2 61.04,121.6 PQ8.2
N17765266: length 4.7
  TOP w0.203: PU901.26 55.52,54.49 54.82,53.8 v2(54.82,53.68) PR933.2
  BOTTOM w0.102: v1(53.82,51.88) PR951.2
  BOTTOM w0.112: PR951.2 53.82,52.94 54.56,53.68 v2(54.82,53.68)
N17768164: length 3.6
  BOTTOM w0.112: v1(52.16,53.83) 51.98,53.64 PR1245.2 51.98,52.41 51.78,52.21 51.78,51.51 51.4,51.13 PQ1210.5
N17769037: length 5.6
  TOP w0.102: v1(46.86,49.97) v2(46.86,50.48)
  TOP w0.112: v2(46.86,50.48) 46.46,50.48 46.19,50.75 PR1230.1
  BOTTOM w0.112: PQ1207.6 v2(46.86,50.48) ; v2(46.86,50.48) PQ1211.4 ; v2(46.86,50.48) 46.86,52.43 PR1258.2
N17769560: length 3.5
  TOP w0.102: v1(48.28,49.99) v2(48.28,50.49)
  TOP w0.112: v2(48.28,50.49) 48.28,50.86 PR1242.2 PR1233.1
  BOTTOM w0.112: v2(48.28,50.49) 48.28,50.87 48.03,51.13 PQ1211.5
N17769738: length 4.3
  BOTTOM w0.112: v1(48.45,53.8) 48.45,53.4 48.3,53.25 PR1257.2 PR1235.1 49.93,52 49.93,51.32 49.74,51.13 PQ1211.2
N17770477: length 3.9
  TOP w0.102: v2(45.53,50.71) v1(45.53,50.2)
  TOP w0.112: PR1232.1 44.91,51 45.24,51 v2(45.53,50.71)
  BOTTOM w0.112: v2(45.53,50.71) 45.11,51.13 44.88,51.13 44.75,51.26 ; 44.75,51.26 44.63,51.13 PQ1207.2 ; 44.75,51.26 44.75,51.65 44.62,51.78 PQ1207.3
N17771093: length 3.4
  BOTTOM w0.112: PR1241.2 43.82,52.75 44.26,52.26 44.88,52.26 45.11,52.03 45.11,51.6 45.58,51.13 PQ1207.5
N17771333: length 12
  TOP w0.102: v1(41.77,49.97) 42.27,50.47 v2(42.27,50.48)
  TOP w0.112: v2(42.27,50.48) 42.88,50.48 PR1261.2 PR1234.1
  IN2 w0.124: v2(48.74,51.78) 48.74,50.23 48.44,49.92 42.82,49.92 v2(42.27,50.48)
  BOTTOM w0.112: PQ1208.6 v2(42.27,50.48) ; PQ1211.1 v2(48.74,51.78)
N17771663: length 3.2
  BOTTOM w0.112: PR1259.1 41.54,51.94 41.38,51.78 PQ1208.3 PQ1208.2 40.24,51.13 v1(40.04,51.33)
N17772624: length 4.4
  TOP w0.102: v1(43.38,52.64) 42.95,52.21 PR1261.1
  TOP w0.112: PR1244.2 PR1260.2 v2(42.25,51.13) 42.62,51.13 PR1261.1
  BOTTOM w0.112: PQ1208.5 v2(42.25,51.13)
N17801240: length 4.7
  TOP w0.112: PR1228.2 v1(33.11,120.93)
  TOP w0.254: PR1228.2 PC1210.1 31.07,121 PQ1206.4 30.06,121.55 29.69,121.92 PR1229.1
N17802718: length 2.4
  TOP w0.112: PR1212.1 v1(43.86,102.3)
  BOTTOM w0.254: PQ1215.1 47.24,101.71 v2(47.71,102.18)
N17804163: length 9
  TOP w0.254: v2(47.14,106.03) 47.29,106.03 v1(47.99,106.73) 48.36,107.1 PR1213.1 48.36,108.7 PR1207.2 ; PR1207.2 PC1203.2 ; PR1207.2 48.78,108.71 49.05,108.98 49.05,109.28 49.32,109.55 PQ1202.4
  BOTTOM w0.254: v2(47.14,106.03) 46.35,106.03 45.7,105.38 44.78,105.38 PQ1203.1
N17890941: length 2.8
  BOTTOM w0.112: v1(34.54,61.61) 34.85,61.3 PU1200.4 36.01,61.3 36.36,60.95 PR1216.1
N17892124: length 2.8
  TOP w0.254: PR1252.2 48.4,101.29 v1(48.14,101.29) 47.87,101.02 PQ1214.6
N18264144: length 3.4
  BOTTOM w0.112: PR20.1 42.07,109.98 41.69,109.59 40.43,109.59 v1(40.17,109.33)
  BOTTOM w0.254: PQ7.2 42.07,111.17 PR20.1
N18265642: length 59.5
  TOP w0.112: v2(47.14,106.63) 46.82,106.94 PQ1201.2 ; v2(39.01,105.41) v4(39.01,104.71)
  IN2 w0.124: v2(34.82,60.91) 34.82,61.79 35.65,62.62 35.65,63.01 36.42,63.78 36.42,65.67 34.54,67.55 34.54,71.36 36.09,72.91 36.09,79.11 38.12,81.14 38.12,102.29 39.01,103.18 v2(39.01,105.41)
  BOTTOM w0.112: v2(39.01,105.41) 39.01,105.92 39.33,106.23 45.92,106.23 46.32,106.63 v2(47.14,106.63) ; v2(34.82,60.91) 34.82,60.4 34.99,60.23 PR1216.2
N18265900: length 1.9
  TOP w0.112: PR1220.2 v1(43.6,106.01)
  TOP w0.254: PQ1201.5 PR1220.2
N18266224: length 8.2
  TOP w0.203: PR1243.1 PR1240.2 PC1213.1 ; PC1213.1 v2(35.83,56.7) ; PC1213.1 PR1238.2
  BOTTOM w0.102: PD1205.2 35.14,57.62 v1(35.51,57.99)
  BOTTOM w0.203: v2(35.83,56.7) 35.77,56.65 PD1205.2 35.14,56.34 35.46,56.02 35.84,56.02 36.47,55.39 PU1201.7
N18266545: length 101.1
  TOP w0.112: PQ1209.5 28.04,124.22 PC1214.1 26.86,124.2 v2(26.6,124.46)
  TOP w0.203: PR1243.2 33.15,57.83 v2(33.15,58.68)
  IN2 w0.124: v2(39.5,124.27) 37.21,124.27 31.05,118.11 31.05,112.67 32.97,110.75 37.06,110.75 39,108.81 39,107.19 39.41,106.79 39.41,103.25 38.38,102.22 38.38,81.06 36.42,79.11 36.42,72.91 34.79,71.28 34.79,67.65 36.67,65.77 36.67,63.67 35.9,62.9 35.9,60.56 34.02,58.68 v2(33.15,58.68)
  BOTTOM w0.112: v2(26.6,124.46) 26.6,126.73 26.82,126.96 v1(35.55,126.96) 36.91,126.96 39.5,124.37 v2(39.5,124.27)
N18267253: length 7.4
  TOP w0.203: PR1249.1 32.42,55.32 PR1250.1 v2(32.41,55.95) PR1248.1
  BOTTOM w0.112: v2(32.41,55.95) 32.45,55.95 32.7,55.7 v1(32.95,55.7)
  BOTTOM w0.254: PQ1212.2 32.27,59.24 32.27,56.09 v2(32.41,55.95)
N18268286: length 4.2
  BOTTOM w0.102: PQ1205.2 42.01,61.8 v1(42.58,62.37)
  BOTTOM w0.254: PQ1205.2 40.67,62.51 PR1225.2
N18277029: length 4.3
  TOP w0.102: PR404.2 v1(139.18,128.9)
  TOP w0.254: v2(141.88,127.39) 141.26,128.01 PR425.2 141.26,128.19 140.55,128.9 PR404.2
  BOTTOM w0.254: PU401.14 v2(141.88,127.39)
N18277134: length 9.8
  TOP w0.112: v2(162.25,125.44) v1(162.75,125.93) 163.09,126.27 163.09,127.79 PR426.2 PR410.2
  BOTTOM w0.112: v2(162.25,125.44) 162.05,125.64 158.34,125.64 157.75,126.23 PU402.14
N18278112: length 4.5
  TOP w0.112: v1(45.7,88.88) 45.7,88.94 46.57,89.81 PR620.2
  TOP w0.203: PU602.1 48.33,91.3 48,90.97 47.05,90.97 46.63,90.55 PR620.2
N18278782: length 1.6
  TOP w0.112: PC930.1 59.12,62.62 v1(59.65,63.16)
N18278920: length 5.2
  TOP w0.112: PU901.21 54.03,56.84 53.95,56.76 53.64,56.76 53.28,56.39 53.28,55.9 53,55.62 52.59,55.62 52.37,55.84 v3(52.37,56.61) 52.37,56.9 52.12,57.15 51.8,57.15 PR920.2
N18278998: length 5.2
  TOP w0.112: PR922.2 51.8,56.91 52.02,56.91 52.13,56.8 52.13,55.74 52.49,55.39 v3(52.79,55.39) 53.1,55.39 53.52,55.8 53.52,56.29 53.74,56.52 53.93,56.52 54.01,56.44 PU901.22
N18287403: length 3
  TOP w0.112: v1(57.02,112.81) 56.98,112.84 PR19.1
  TOP w0.254: PQ1.2 55.65,112.98 56.53,113.85 PR19.1
N18287500: length 1.1
  BOTTOM w0.254: PU1.2 PR22.2
N18288083: length 1.1
  BOTTOM w0.254: PR946.1 43.27,54.1 PU903.4
N18288371: length 2.3
  BOTTOM w0.112: v1(42.51,103.86) PR1218.1
  BOTTOM w0.254: PQ1204.5 41.24,104.4 41.54,104.1 PR1218.1
N18288510: length 2
  BOTTOM w0.112: v1(40.19,108.01) PR1223.1
  BOTTOM w0.254: PQ1204.2 41.24,107.95 PR1223.1
N18290168: length 2.1
  TOP w0.203: PU901.29 56.72,53.93 v1(56.77,53.88) 56.77,53.15 PR949.1
N18290418: length 3.6
  BOTTOM w0.112: PR423.1 156.37,132.24 156.02,132.6 v1(156.02,133.12)
  BOTTOM w0.254: PR423.1 PR424.1 156.37,130.81 156.75,130.43 PU402.5
N18325201: length 2.4
  TOP w0.254: v2(261.11,130.38) CL16.1
  BOTTOM w0.254: TL1.3 261.26,129.87 261.11,130.02 v2(261.11,130.38)
N18325205: length 3.8
  TOP w0.112: v2(262.34,130.38) 262.34,131.11 v1(261.89,131.57)
  TOP w0.254: v2(262.34,130.38) 262.32,130.35 CL17.1
  BOTTOM w0.254: v2(262.34,130.38) 262.53,130.19 TL1.4
N18325209: length 3.7
  TOP w0.112: CL20.1 267.93,128.31 v1(267.64,128.6)
  TOP w0.254: v2(268.88,127.46) CL20.1
  BOTTOM w0.254: TL1.9 v2(268.88,127.46)
N18325213: length 2.3
  TOP w0.254: v2(270.15,127.46) CL21.1
  BOTTOM w0.254: TL1.10 v2(270.15,127.46)
N18364501: length 3.8
  BOTTOM w0.112: v1(106.27,126.33) RV97.1 107.45,126.5 108.08,126.5 108.41,126.83 109.38,126.83 109.51,126.96 UV7.20
N18366912: length 2.4
  BOTTOM w0.112: CV96.1 109.49,125.93 109.74,125.93 110.34,126.53 110.41,126.53 110.71,126.82 UV7.17
N18421193: length 3.5
  TOP w0.112: PR624.1 v1(71.4,114.3)
  TOP w0.254: v2(72.48,115.71) PR624.1
  BOTTOM w0.254: v2(72.48,115.71) 72.27,115.5 PL614.3
N18490882: length 2.7
  TOP w0.112: v1(280.19,77.62) 279.67,77.1 RI14.2 279.65,76.52 UI3.16
N18762046: length 0.9
  TOP w0.112: RA17.2 CA33.1
N18762152: length 1.4
  TOP w0.112: CZ127.1 248.59,63.43 UZ5.10
N18762172: length 1.4
  TOP w0.112: UZ5.12 248.51,64.23 CZ126.1
N18762349: length 4
  TOP w0.203: UA1.27 255.93,56.73 254.47,55.27 RA44.1 254.04,55.01 253.99,55.07 CA51.1
N18762353: length 4.1
  TOP w0.203: UA1.7 257.13,66.82 CA53.1
N18762355: length 3.3
  TOP w0.152: UA1.39 260.83,58.94 261.55,58.22 v1(261.67,58.22) 261.73,58.22 261.87,58.08 263.19,58.08 CA52.1
N18762401: length 5.3
  TOP w0.203: RA53.1 RA54.1 250.23,59.19 252.88,59.19 253.42,59.74 UA1.20
N18762411: length 4.2
  TOP w0.112: CA29.1 261.2,55.45 261.2,55.78 260.58,56.4 259.66,56.4 259.13,56.94 UA1.35
N18762416: length 3.1
  TOP w0.112: CA29.2 261.35,56.14 260.78,56.72 260.78,58.06 260.71,58.14 UA1.37
N18762426: length 2.7
  TOP w0.112: CA35.1 255.36,55.75 256.33,56.72 UA1.28
N18762428: length 2.8
  TOP w0.112: UA1.34 258.73,56.93 259.51,56.14 260.09,56.14 260.39,55.85 CA49.1
N18762438: length 1.9
  TOP w0.203: UA1.19 253.24,60.14 253,59.89 CA25.1
N20151644: length 42.9
  TOP w0.254: v2(44.55,82.15) 44.65,82.05 v1(46.1,82.05) 46.37,81.79 49.54,81.79 49.73,81.98 49.73,83.03 49.48,83.28 PR901.2
  IN3 w0.203: v2(44.55,82.15) 44.4,82 44.1,82 41.41,79.31 41.41,77.52 39.54,75.66 39.54,65.62 45.08,60.08 v2(49.95,60.08)
  BOTTOM w0.254: v2(49.95,60.08) 50.23,60.08 51.4,61.25 53.2,61.25 PR909.1
N20880735: length 1.9
  BOTTOM w0.102: PC307.2 v1(152.45,87.96)
  BOTTOM w0.254: PC307.2 153.43,87.09 PR308.1
N24606174: length 4.1
  TOP w0.112: v1(154.44,88.05) 153.76,87.36 PC313.1
  TOP w0.254: v2(154.84,85.55) 153.76,86.62 PC313.1
  BOTTOM w0.254: PU301.5 154.73,85.44 v2(154.84,85.55)
N27076067: length 2.3
  BOTTOM w0.102: v1(55.07,50.9) 54.67,51.3 54.67,51.69 54.75,51.76 PC944.1
  BOTTOM w0.254: PC944.1 PR934.2
N27077001: length 120.9
  TOP w0.254: v2(171.45,49.57) 171.55,49.67 171.55,51.78 171.3,52.03 PR917.2
  IN2 w0.254: v2(171.45,49.57) 171.12,49.57 171.02,49.46 162.98,49.46 158.05,54.4 148.73,54.4 146.99,52.67 142.55,52.67 139.07,49.95 71.75,49.95 70.36,51.34 70.36,52.4 68.44,54.32 65.53,54.32 64.64,53.43 62.99,53.43 v2(62.66,53.76)
  BOTTOM w0.254: PR937.2 62.34,55.83 62.81,55.36 62.81,54.42 62.66,54.27 v2(62.66,53.76)
N28424999: length 7.5
  BOTTOM w0.076: UC1.AW71 91.67,92.33 90.82,92.33 90.38,91.9 90.38,91.6 90.03,91.25 90.03,90.88
  BOTTOM w0.112: T113.1 88.12,87.77 88.73,88.38 88.73,88.8 90.03,90.09 90.03,90.88
N28425002: length 9.8
  BOTTOM w0.076: UC1.AW70 92.25,92.13 91.25,92.13 91.22,92.17 90.91,92.17 90.6,91.86 90.6,91.48 90.3,91.17
  BOTTOM w0.102: 89.97,89.7 90.3,90.03 90.3,91.17
  BOTTOM w0.112: T114.1 86.37,87.4 88.14,87.4 88.97,88.24 88.97,88.71 89.97,89.7
N28489601: length 6.5
  BOTTOM w0.112: SW1.2 230.12,84.13 230.21,83.64 229.68,82.25 228.74,81.3 v1(227.89,81.3) 227.18,81.3 RC222.1
N28769860: length 3.4
  BOTTOM w0.112: v1(140.22,134.53) 140.44,134.31 PR422.1
  BOTTOM w0.254: PR422.1 PR421.2 140.44,132.14 140.88,131.7 PU401.5
N28810563: length 1.6
  TOP w0.112: CZ110.1 249.53,111.77 249.7,111.6 UZ2.10
N28811129: length 1.3
  TOP w0.112: UZ3.10 155.34,60.74 CZ114.1
N28856399: length 9.5
  BOTTOM w0.076: 90.23,89.3 91.25,90.32 92.4,90.32 92.58,90.5 92.58,91.15 UC1.BA70
  BOTTOM w0.107: T16.1 86.38,86.88 88.43,86.88 89.47,87.92 89.47,88.54 90.23,89.3
N28856402: length 11.6
  BOTTOM w0.076: 90.51,91.02 90.89,91.4 91.4,91.4 91.48,91.48 92.05,91.48 92.22,91.65 92.73,91.65 UC1.BA68
  BOTTOM w0.102: 90.17,89.56 90.51,89.9 90.51,91.02
  BOTTOM w0.107: 90.17,89.56 89.23,88.62 89.23,88.1 88.26,87.13 85.37,87.13 T17.1
N28857231: length 11.4
  BOTTOM w0.076: 91.04,89.48 91.55,89.99 92.63,89.99 93.33,90.69 UC1.BB68
  BOTTOM w0.102: 91.04,89.48 90.37,88.81
  BOTTOM w0.107: 88.26,86.12 87.81,86.12
  BOTTOM w0.112: T12.1 85.11,86.12 87.81,86.12 ; 88.26,86.12 88.56,86.12 89.98,87.54 89.98,88.42 90.37,88.81
N28857234: length 7.9
  BOTTOM w0.076: 90.43,89.18 91.4,90.15 92.56,90.15 92.9,90.49 UC1.BB69
  BOTTOM w0.112: T13.1 88.47,86.5 89.71,87.74 89.71,88.47 90.43,89.18
N28857237: length 1.2
  TOP w0.112: T14.1 125.52,98.54 v2(125.52,98.47)
  BOTTOM w0.102: UC1.AK13 125.13,98.02 125.52,98.4 v2(125.52,98.47)
N28857240: length 1.3
  TOP w0.112: T15.1 126.65,98.47 v2(126.13,98.47)
  BOTTOM w0.102: UC1.AK12 125.78,98.13 126.12,98.47 v2(126.13,98.47)
N28861827: length 9.3
  BOTTOM w0.076: 93.48,117.22 93.94,117.22 95.2,115.96 95.2,115 96.02,114.18 96.02,112.61 96.11,112.52 UC1.C64
  BOTTOM w0.112: RC120.1 91.78,117.68 92.24,117.22 v1(93.19,117.22) 93.48,117.22
N28938912: length 2
  TOP w0.102: v1(158.93,92.23) 158.65,91.95 CC8.1
  TOP w0.112: RC29.2 CC8.1
N28938914: length 1.9
  TOP w0.112: CC7.1 156.61,102.49 RC28.2 157.33,101.62 v1(157.56,101.39)
N29708559: length 5.9
  BOTTOM w0.076: 132.52,90.57 132.09,91 131,91 130.83,91.18 130.83,91.5 UC1.AY4
  BOTTOM w0.102: 132.52,90.57 134.9,90.57 T126.1
N29708561: length 4.6
  BOTTOM w0.102: UC1.BB3 131.64,90.35 134.86,90.35 T127.1
N29708639: length 7.7
  BOTTOM w0.102: UC1.BB5 130.64,89.93 133.75,89.93 134.77,88.91 T130.1
N30342894: length 2.3
  TOP w0.112: RV18.2 v1(19.4,75.98)
  TOP w0.508: RV18.2 19.4,77.8 QV4.2
N31877076: length 4.5
  TOP w0.112: LV1.1 62.52,130.74 v2(62.37,130.9) 62.11,131.15 v1(62.11,132.08)
  BOTTOM w0.107: v2(62.37,130.9) 61.25,132.02 JEDP1.21
N32590572: length 1.4
  TOP w0.112: UZ4.12 275.87,90.54 CZ117.1
N32592963: length 1.4
  TOP w0.112: UZ4.10 275.81,91.34 CZ118.1
N32594166: length 1.6
  TOP w0.112: CZ109.1 248.78,110.8 UZ2.12
N32595008: length 5.8
  TOP w0.112: RZ71.2 RZ70.2 253.17,108.1 v1(253.83,108.76) 253.83,110.56 253.6,110.8 UZ2.3
N32817808: length 1.3
  TOP w0.112: CZ113.1 155.34,59.94 UZ3.12
N32818355: length 3.7
  TOP w0.112: UZ3.3 158.92,59.94 159.23,59.62 159.79,59.62 RZ64.2 RZ65.2 v1(161,58.86)
N32819772: length 1.3
  TOP w0.112: CZ121.1 209.77,51.39 UZ8.6
N33612393: length 1.9
  TOP w0.112: RD18.1 116.1,54.3 v1(116.08,54.33)
  TOP w0.508: CD31.2 RD18.1
N35551576: length 2.8
  TOP w0.112: PR1236.1 v1(29.91,125.99)
  TOP w0.254: PQ1209.2 PQ1209.3 30.95,125.98 PR1236.1
N35551581: length 3.2
  TOP w0.112: PQ1209.6 28.61,123.57 28.42,123.38 v1(27.2,123.38)
  TOP w0.254: PR1229.2 28.78,123.3 PQ1209.6
N35551592: length 5.9
  TOP w0.112: PR1237.2 36.59,58.51 v1(36.94,58.86)
  TOP w0.203: PR1237.2 PC1212.1 PR1247.1 36.03,56.02 35.84,55.83 v2(35.84,55.26)
  BOTTOM w0.203: v2(35.84,55.26) 35.9,55.26 36.42,54.74 PU1201.6
N35551655: length 5
  TOP w0.102: v1(39.36,52.14) 39.66,52.45 PC1205.1
  TOP w0.203: PC1205.1 PR1217.1 PR1208.2 39.92,55.39 v2(40.29,55.39)
  BOTTOM w0.203: PU1201.2 v2(40.29,55.39)
N35551713: length 3.2
  TOP w0.254: PQ1201.6 v1(44.54,104.58) 44.54,103.53 PR1212.2
N35551785: length 4.4
  BOTTOM w0.112: PR1202.2 v1(43.38,109.95)
  BOTTOM w0.254: PR1209.1 42.34,108.65 43.11,108.65 PR1202.2 43.57,108.72 PQ1203.2
N35551806: length 1.1
  BOTTOM w0.254: PQ1204.3 41.89,107.84 PR1209.2
N35551822: length 2.3
  TOP w0.112: v1(46.44,108.81) PQ1201.3
  TOP w0.254: PQ1201.3 46.88,107.59 47.12,107.83 PR1213.2
N36626863: length 3.7
  TOP w0.112: v2(22.01,66.48) 22.39,66.1 v1(22.73,66.1)
  TOP w0.381: RT111.2 CT90.1 v2(22.01,66.48)
  BOTTOM w0.381: v2(22.01,66.48) 22.01,66.8 21.87,66.94 UT7.3
N36827741: length 4.2
  TOP w0.112: UZ26.4 138.14,66.3 RZ120.2 ; v1(139.79,65.29) 139.79,65.54 139.27,66.06 RZ120.2 ; UZ34.4 139.14,67.15 139.27,67.02 RZ120.2
N38749366: length 4.2
  TOP w0.112: v1(42.19,126.66) RV5.2
  TOP w0.254: RV5.2 41.53,124.84 41.53,124.19 QV2.1
N38749387: length 5.6
  TOP w0.112: v1(50.44,119.71) 50.32,119.84 RV6.1 49.18,122.17 QV7.1 48.6,122.55 48.21,122.95 QV8.2
N38798736: length 9.8
  TOP w0.076: UT5.F10 31.27,78.72 31.27,77.64 30.94,77.31
  TOP w0.112: RT97.2 RT98.1 ; RT97.2 31.61,72.43 v1(32.62,72.43) ; RT97.2 RT99.1 30.75,74.19 30.4,74.53 30.4,76.77 30.94,77.31
N38798744: length 3.7
  TOP w0.076: UT5.G4 31.02,82.38 v2(30.94,82.46)
  BOTTOM w0.112: v2(30.94,82.46) 30.94,83.02 30.78,83.17 v1(30.1,83.17) RT85.1
N38798745: length 6.9
  TOP w0.076: UT5.F4 v2(31.52,82.46)
  BOTTOM w0.112: v2(31.52,82.46) 31.52,83.07 31.08,83.51 30.12,83.51 29.49,84.15 29.49,85.15 RT84.1 28.01,85.98 v1(27.66,85.62)
N38798858: length 3.1
  TOP w0.076: 31.8,84.51 31.8,84.4 31.72,84.33 31.72,83.68 UT5.F1
  TOP w0.112: RT63.1 32.13,85.95 32.13,85.71 31.8,85.39 31.8,84.85 v1(31.8,84.85) 31.8,84.51
N38798904: length 4.8
  TOP w0.076: 27.93,77.76 28.89,78.72 29.27,78.72 UT5.K10
  TOP w0.112: 27.93,77.76 27.71,77.54 RT105.1 26.83,77.3 26.09,76.56 v1(25.85,76.56)
N38798905: length 3.1
  TOP w0.076: UT5.K9 29.27,79.22 28.7,79.22 28.04,78.56 27.93,78.56
  TOP w0.112: 27.93,78.56 v1(27.8,78.56) RT104.1
N38798908: length 4.5
  TOP w0.076: UT5.L11 28.91,78.47 28.03,77.59 28.03,77.31
  TOP w0.112: v1(26.62,75.07) RT103.1 28.03,76.48 28.03,77.31
N38798948: length 0.9
  BOTTOM w0.112: RT85.2 T220.1
N38798949: length 0.9
  BOTTOM w0.112: T219.1 RT84.2
N38799002: length 2.8
  TOP w0.076: v2(30.05,80.73) 30.26,80.73 UT5.H7
  BOTTOM w0.112: v2(30.05,80.73) 29.55,80.73 CT87.1 28.51,79.69 v1(28.27,79.69)
N38799008: length 2.3
  TOP w0.076: UT5.D6 32.86,81.32 v2(32.99,81.32)
  BOTTOM w0.112: v1(33.69,80.77) 33.15,81.32 v2(32.99,81.32) 32.95,81.35 RT101.1
N39468508: length 2.7
  TOP w0.112: v1(56.64,91.86) 56.3,92.2 PR650.2
  TOP w0.203: PR650.2 56.92,92.78 57.17,93.04 PC647.2
N39468570: length 2.9
  BOTTOM w0.112: v1(53.61,98.02) 53.25,97.66 53.25,96.91 PC629.2
  BOTTOM w0.203: PR639.1 PC629.2
N39469485: length 19.2
  TOP w0.254: PR610.1 v2(47.57,89.16)
  BOTTOM w0.254: PH601.2 57.86,90.94 53.99,87.07 49.67,87.07 v4(48.16,88.57) v2(47.57,89.16) 47.57,89.72 48.28,90.43 PR631.2
N39469718: length 2.5
  TOP w0.112: PR632.2 52.91,87.58 v1(52.68,87.35)
  TOP w0.254: PR632.2 52.41,88.85 52.4,88.83 PC627.1
N39469776: length 28.1
  TOP w0.112: v1(54.91,90.89) 54.91,91.48 PR635.1
  TOP w0.203: v2(53.54,91.48) 53.61,91.48 54.01,91.88 PR635.1
  IN1 w0.254: v2(56.51,112.43) 56.37,112.43 55.37,111.43 55.37,102.14 53.97,100.75 53.97,98.38 52.81,97.21 52.81,92.11 53.44,91.48 v2(53.54,91.48)
  BOTTOM w0.203: PR647.2 53.22,91.48 v2(53.54,91.48)
  BOTTOM w0.254: v2(56.51,112.43) 57.48,112.43 PH603.2
N39469798: length 5.3
  TOP w0.254: v2(62.94,114.01) 63.22,114.01 63.46,114.25 63.46,115.52 62.89,116.09 v1(62.51,116.09) PR679.1
  BOTTOM w0.254: PU614.7 62.88,114.06 v2(62.94,114.01)
N39469812: length 3.2
  TOP w0.254: PR628.2 67.33,96.09 v2(67.14,95.9)
  BOTTOM w0.112: PH602.1 68.02,94.63 v1(68.33,94.31)
  BOTTOM w0.254: PH602.1 67.14,94.83 v2(67.14,95.9)
N39469818: length 1.9
  BOTTOM w0.112: PR630.2 48.21,97.6 48.37,97.76 v1(48.37,98.16)
  BOTTOM w0.203: PR630.2 PC631.1
N39469863: length 3.7
  TOP w0.203: v2(49.07,98.13) 49.13,98.07 PU602.28
  BOTTOM w0.203: v2(49.07,98.13) 49.07,98.74 48.98,98.83 PR636.1 48.12,99.38 PC632.1
N39469888: length 4.4
  TOP w0.112: v1(53.36,90.63) 52.91,90.17 PR638.2
  TOP w0.203: PU602.8 51.13,91.22 51.38,90.97 51.61,90.97 52.02,90.56
  TOP w0.254: 52.02,90.56 52.03,90.55 PC627.2 52.89,89.75 PR638.2
N39469908: length 2.2
  TOP w0.112: PC617.2 50.65,88.01 v1(51.31,87.34)
  TOP w0.254: PC617.2 PR621.1
N39469972: length 3.4
  TOP w0.112: PU602.38 46.17,93.17 v2(46.09,93.25)
  BOTTOM w0.112: PR678.2 46.91,94.58 v1(46.11,93.78) 46.09,93.75 v2(46.09,93.25)
N39469996: length 2.4
  TOP w0.102: v2(59.28,114.06) 58.8,114.06 v1(58.63,113.89)
  TOP w0.508: PC611.2 59.87,114.31 59.62,114.06 v2(59.28,114.06)
  BOTTOM w0.254: v2(59.28,114.06) PU614.2
N39469998: length 1.7
  TOP w0.102: v1(58.55,112.49) 58.96,112.91 PC611.1
N39470055: length 3.6
  TOP w0.203: PU602.20 52.88,95.97 52.93,96.02 52.93,96.58 53.2,96.85 53.94,96.85 54.3,97.22 PC630.1 55.37,97.22 PR640.1
N39470129: length 2.9
  BOTTOM w0.112: v1(51.77,101.86) 51.22,101.31 51.22,100.75 PR646.2
  BOTTOM w0.203: PR646.2 50.77,100.28 PC640.1
N39470145: length 1.5
  BOTTOM w0.203: PR652.2 50.11,100.53 50.11,101.29 PC601.1
N39470169: length 1.9
  TOP w0.112: PC630.2 v1(54.51,99.15)
  TOP w0.203: PR644.1 55.37,98.13 PC630.2
N39470173: length 1.9
  BOTTOM w0.102: v1(47.1,98.46) 47.19,98.55 PC632.2
  BOTTOM w0.203: PC632.2 PR641.1
N39470189: length 2.1
  BOTTOM w0.112: v1(70.69,119.28) 71.05,119.64 PR642.2
  BOTTOM w0.254: PH604.1 PR642.2
N39470248: length 2.2
  TOP w0.112: PC621.2 v1(46.56,87.04)
  TOP w0.254: PC621.2 PR623.1
N39470250: length 6.3
  TOP w0.112: 48.41,88.92 48.88,88.45 48.88,87.29 v1(48.58,86.98)
  TOP w0.203: PR621.2 49.35,88.94 PR622.2 49.53,89.98 49.53,90.59 49.93,90.99 PU602.5
  TOP w0.254: PR621.2 48.41,88.92 PR623.2
N39470270: length 0.9
  BOTTOM w0.254: PH605.1 PR657.2
N39470326: length 4.2
  TOP w0.203: v2(49.07,90.43) 49.07,90.61 49.53,91.08 PU602.4
  BOTTOM w0.112: v2(49.07,90.43) 48.74,90.1 v1(48.56,90.1)
  BOTTOM w0.203: PC616.2 49.16,92.25 PR617.2 49.07,91.49 v2(49.07,90.43)
N39470328: length 0.9
  BOTTOM w0.203: PR617.1 50.09,91.57 PC614.2
N39470344: length 2.2
  TOP w0.203: PR610.2 48.49,90.5 49.13,91.15 PU602.3
N39470375: length 4.8
  TOP w0.203: v2(47.33,90.5) 48.02,90.5 48.73,91.22 PU602.2
  BOTTOM w0.112: v1(46.51,90) PR613.2
  BOTTOM w0.203: PR613.2 PC613.2 47.39,90.56 v2(47.33,90.5)
N39470446: length 5.2
  TOP w0.203: PU602.34 46.64,94.77 v1(46.34,95.07) 46.34,95.09 45.59,95.84 45.59,96 PR602.1 45.19,96.78 45.52,96.78 v2(45.59,96.86)
  BOTTOM w0.203: v2(45.59,96.86) 45.32,96.59 PC603.1
N39470448: length 5.3
  TOP w0.203: PR603.1 v2(45.62,97.48) 46.07,97.03 v1(46.07,96.51) 46.07,95.92 46.83,95.17 PU602.33
  BOTTOM w0.203: PC604.1 45.05,97.48 v2(45.62,97.48)
N39470528: length 3
  TOP w0.203: PU602.32 47.06,95.57 46.63,96 v2(46.63,96.02)
  BOTTOM w0.112: PR608.1 v1(46.05,95.45)
  BOTTOM w0.203: PR608.1 47.06,95.57 46.63,96 v2(46.63,96.02)
N39470532: length 4.2
  TOP w0.203: v2(47.09,97.88) 47.09,96.15 47.27,95.97 PU602.31
  BOTTOM w0.112: v1(46.24,97.52) 46.52,97.24 PR611.1
  BOTTOM w0.203: PR611.1 47.27,97.7 v2(47.09,97.88)
N39470546: length 0.9
  TOP w0.203: PC639.2 PR645.1
N39473183: length 3.5
  TOP w0.102: v2(64.67,107.39) v1(64.67,107.9)
  TOP w0.254: v2(64.67,107.39) 64.92,107.14 PR661.1
  BOTTOM w0.254: v2(64.67,107.39) PL610.3
N39473185: length 1.3
  BOTTOM w0.102: PC671.2 v1(58.08,89.05)
N39473187: length 1.4
  BOTTOM w0.102: PR672.2 61.07,89.05 61.49,88.63 v1(61.82,88.63)
N39473189: length 1.3
  BOTTOM w0.102: PC671.1 v1(58.04,87.65)
N39473240: length 2.7
  BOTTOM w0.112: v1(59.6,96.65) PR671.1
  BOTTOM w0.203: PR671.1 59.6,94.98 60.1,94.49 PU612.1
N39473270: length 1.6
  BOTTOM w0.112: PC655.2 53.62,111.59 v1(54.04,112.01)
N39473272: length 2.9
  BOTTOM w0.112: PR660.2 53.62,109.28 52.83,108.49 52.83,107.11 v1(52.67,106.94)
N39473274: length 1.2
  BOTTOM w0.112: PR660.1 v1(52.22,108.23)
N39473308: length 3.1
  BOTTOM w0.112: v1(60.97,111.71) PR659.1
  BOTTOM w0.203: PU610.1 58.93,110.32 59.98,111.38 PR659.1
N41288260: length 4.1
  TOP w0.112: v2(231.67,106.06) RZ326.1 231.05,106.63 230.59,107.08 v1(229.74,107.08)
  BOTTOM w0.102: JNGFF2.17 231.12,105.75 231.43,106.06 v2(231.67,106.06)
N41303246: length 2.2
  BOTTOM w0.112: v1(279.49,58.51) CZ38.2 278.53,58.47 RZ334.1
N44311288: length 3
  TOP w0.112: v1(261.95,104.43) RE90.2 ; RE90.2 261.45,103.45 261.34,103.34 QE11.3 ; RE90.2 RE70.1
N44311298: length 2.2
  TOP w0.112: QE4.2 262.91,102.51 RE70.2 v1(262.86,101.52)
N44321668: length 9
  TOP w0.107: UE1.B1 247.48,83.58 246.56,82.66 246.56,78.2 RE58.1
  TOP w0.112: RE57.1 v1(245.34,76.8) 245.34,76.97 RE58.1
N44321726: length 10
  TOP w0.107: UE1.G2 251.84,84.3 251.84,82.47 v2(251.67,82.31)
  TOP w0.112: v2(250.54,77.71) 250.54,76.81 RE318.1
  IN3 w0.135: v2(251.67,82.31) 251.1,81.74 251.1,78.27 v2(250.54,77.71)
N44321827: length 7.5
  TOP w0.112: UE1.N4 257.21,86.26 258.23,85.24 258.23,84.94 258.65,84.51 v1(258.65,84.23) 259.28,83.6 261.73,83.6 RE349.2
N44321953: length 1.9
  TOP w0.102: CE57.1 v1(247.1,73.86)
  TOP w0.112: RE350.2 CE57.1
N44725169: length 3.6
  TOP w0.112: UZ8.3 204.89,51.39 CZ197.1 RZ345.2 203.64,51.37 v1(203.01,52)
N44851953: length 1.9
  TOP w0.112: T225.1 230.95,95.25 231.22,95.25 v2(231.48,95.51)
  BOTTOM w0.112: v2(231.48,95.51) 231.22,95.25 JNGFF2.59
N44905504: length 2.3
  BOTTOM w0.112: JDIMM1.162 118.47,51.47 T50.1
N44907662: length 3
  TOP w0.107: T51.1 v2(119.85,59.64)
  BOTTOM w0.112: JDIMM1.165 119.22,61.9 119.22,61.07 119.85,60.45 v2(119.85,59.64)
N45160305: length 8.3
  BOTTOM w0.112: JESPI.8 243.95,54.41 244.83,53.53 248.13,53.53 248.87,54.27 RE375.1 249.78,54.15 v1(250.09,54.15)
N45499007: length 2.5
  BOTTOM w0.102: RZ25.1 285.66,13.59 v1(285.52,13.73)
  BOTTOM w0.112: RZ25.1 285.84,12.41 QZ3.1
N45523002: length 4.8
  TOP w0.112: RE14.1 RE13.2 ; RE14.1 267.25,89.17 UE2.1 ; RE14.1 266.47,89.69 v1(265.17,89.69)
N45523004: length 5.9
  TOP w0.112: v1(265.34,86.8) 266.66,86.8 RE15.2 267.59,87.73 267.59,88.58 RE16.1 267.75,89.39 UE2.2
N45523094: length 2.8
  TOP w0.112: RE17.2 RE18.1 268.25,89.81 UE2.3
N45601552: length 5.9
  TOP w0.076: 33.09,84.51 32.52,83.94 UT5.D1
  TOP w0.112: 33.09,84.51 33.25,84.67 v1(33.25,85) 33.25,85.38 33.83,85.96 33.83,87.51 33.58,87.77 33.29,87.77 RT378.1
N45601554: length 6.2
  TOP w0.076: UT5.D2 32.77,83.22 32.77,83.81 33.47,84.51
  TOP w0.112: RT379.1 34.21,87.73 v1(34.21,86.84) 34.21,85.99 33.6,85.38 33.6,84.64 33.47,84.51
N46166384: length 3.5
  TOP w0.112: UT9.32 v2(24.34,104.9)
  BOTTOM w0.112: v1(23.95,106.81) 24.19,106.56 RT380.2 24.19,105.05 v2(24.34,104.9)
N46226517: length 2.5
  BOTTOM w0.112: CZ56.1 160.04,104.68 RZ63.1 v1(159.99,103.57)
N46226641: length 3.5
  BOTTOM w0.112: v1(155.13,112.35) RZ362.2 RZ112.2 155.16,110.22 UZ12.29
N46226670: length 2.5
  BOTTOM w0.112: UZ12.27 155.81,109.22 155.66,109.37 RZ62.1 v1(155.13,108.38)
N46226856: length 5.8
  BOTTOM w0.112: RZ113.2 156.59,104.11 v1(156.23,104.11) 156.11,104.11 155.54,104.68 152.93,104.68 152.67,104.95 QZ9.2
N46293588: length 2.7
  TOP w0.112: RZ131.2 239.21,98.03 v2(239.29,97.95) v1(239.85,97.95)
  BOTTOM w0.112: v2(239.29,97.95) 239.24,98 JNGFF2.48
N46293598: length 4.9
  TOP w0.112: RZ132.2 238.24,97.53 239.2,97.53 v2(239.36,97.37) 240.21,97.37 v1(240.66,96.91)
  BOTTOM w0.112: JNGFF2.50 239.23,97.5 v2(239.36,97.37)
N46460386: length 1.9
  TOP w0.112: QE12.1 246.36,102.81 247.08,103.53 RE94.1
N47527449: length 54.9
  TOP w0.112: RE34.2 RE348.1 242.67,96.48 242.49,96.66 UE7.3 241.85,96.17 241.64,95.96 241.26,95.96 240.93,95.63 v1(240.43,95.63) 240.43,96.15 241.07,96.78 241.07,100.34 241.77,101.04 241.77,102.31 240.31,103.77 240.31,104.32 241.83,105.84 241.83,106.53 242.57,107.26 RE536.1 243.66,107.99 RE537.2 243.66,108.79 245.85,110.97 245.85,113.13 245.08,113.9 242,113.9 241.48,114.42 239.54,114.42 236.17,117.79 v2(236.17,117.93)
  BOTTOM w0.112: QE13.1 239.38,132.13 238.97,131.72 238.97,126.46 235.44,122.93 235.44,118.65 v2(236.17,117.93)
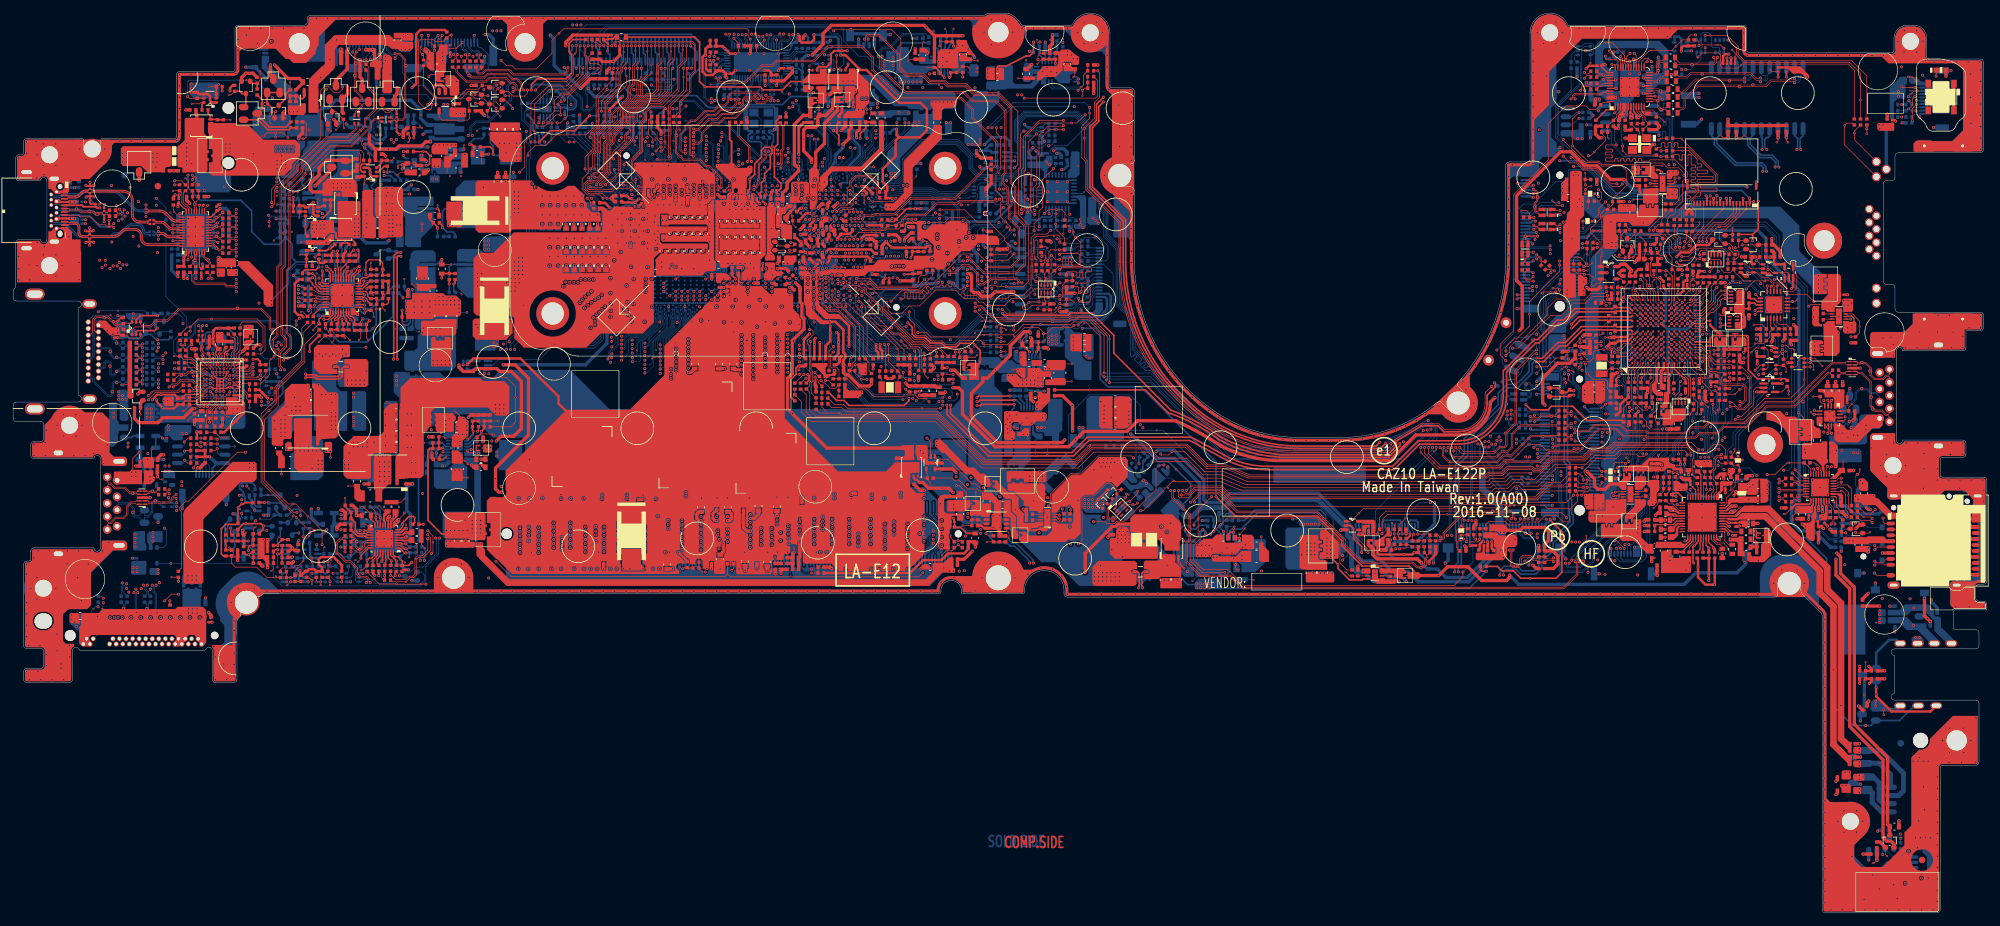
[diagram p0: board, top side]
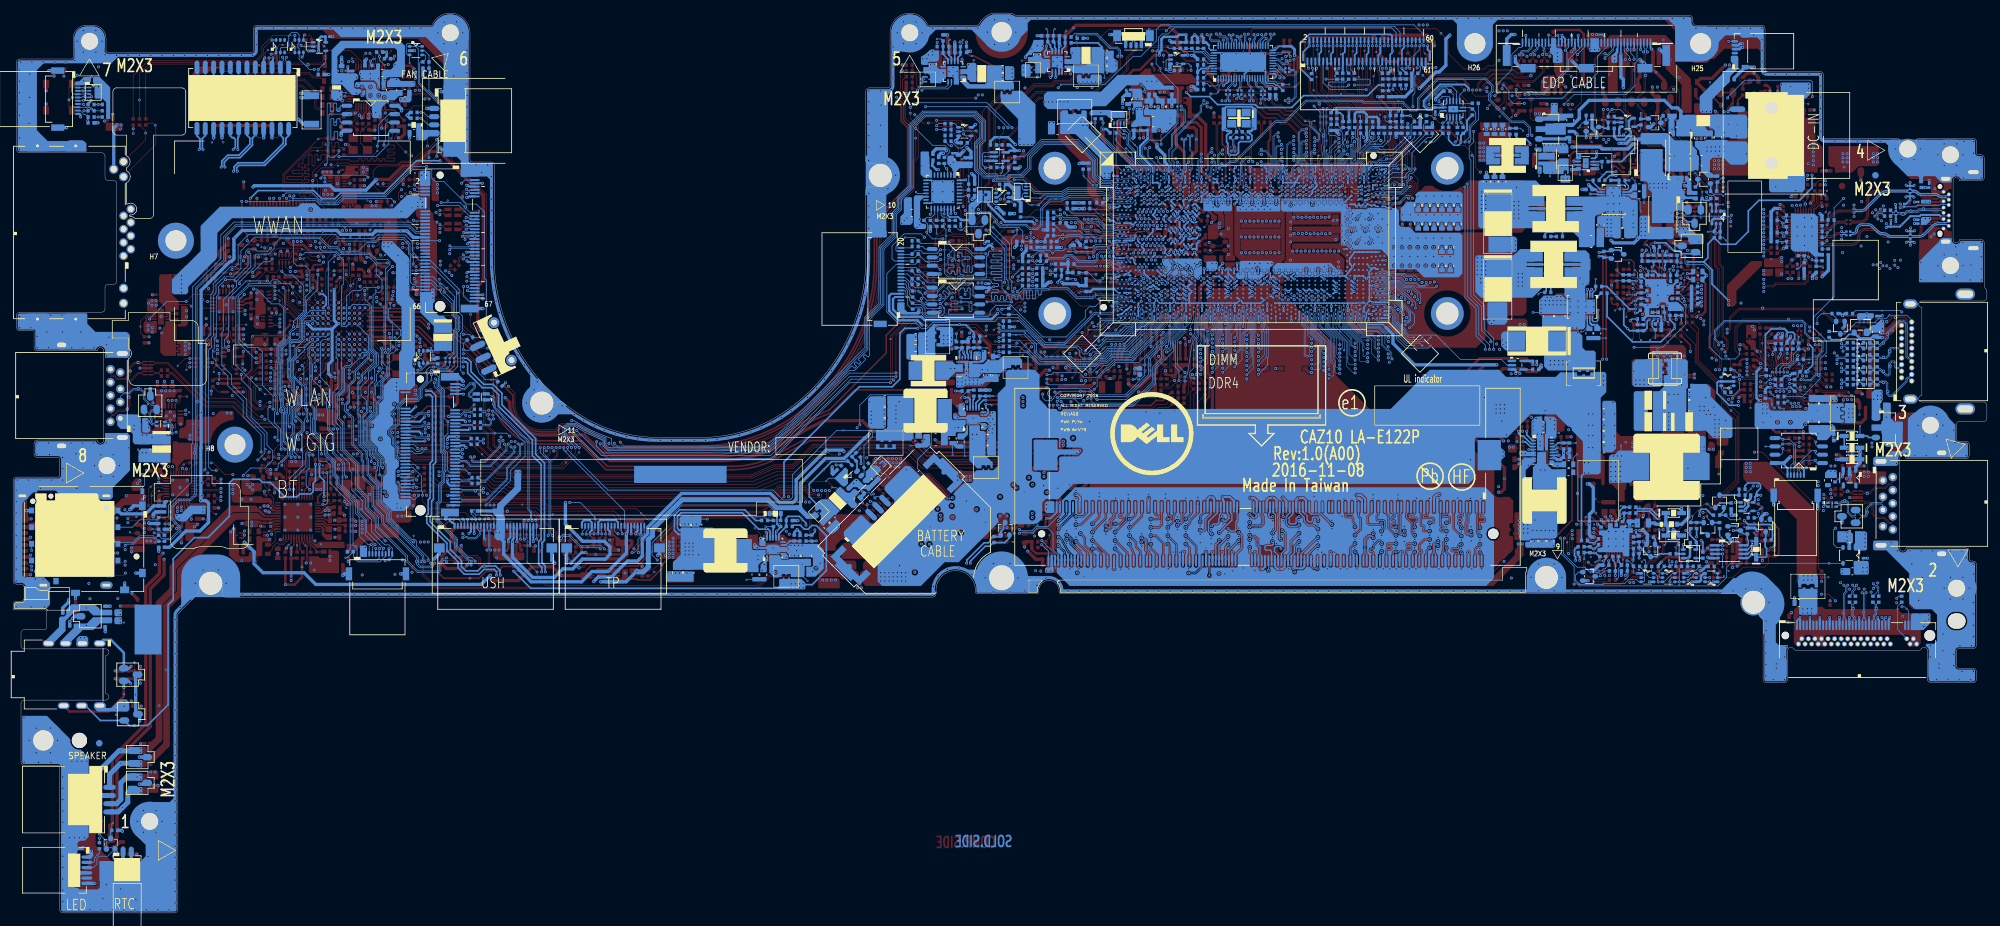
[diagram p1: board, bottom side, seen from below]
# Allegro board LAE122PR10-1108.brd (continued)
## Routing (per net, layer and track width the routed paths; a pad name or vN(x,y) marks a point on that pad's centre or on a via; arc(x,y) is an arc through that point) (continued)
N47527453: length 5.8
  BOTTOM w0.112: v1(240.29,129.6) QE13.3 240.6,130.83 240.82,131.05 240.82,132.34 240.61,132.55 239.37,132.55 238.95,132.13 QE13.6
N47527563: length 1.4
  TOP w0.112: UE7.4 244.99,96.66 CE5.1
N119328643: length 5.8
  TOP w0.112: PR931.2 53.26,52.31 v1(53,52.31)
  TOP w0.203: PR931.2 53.94,53.77 v2(53.92,53.78) 54.25,54.11 54.63,54.11 55.12,54.6 PU901.25
  BOTTOM w0.254: v2(53.92,53.78) 53.85,53.86 PC938.1 PR930.1
N132000604: length 1.4
  TOP w0.112: v1(62.74,55.62) 62.19,56.17 PC934.1
N132005053: length 121.8
  TOP w0.254: PR917.3 172.22,52.03 171.96,51.76 v1(171.96,50.3) 171.96,49.69 v2(172.08,49.57)
  IN2 w0.254: v2(172.08,49.57) 172.08,49.74 171.78,50.05 170.97,50.05 170.76,49.85 163.14,49.85 158.2,54.79 148.54,54.79 146.8,53.05 142.44,53.05 138.96,50.33 71.91,50.33 70.74,51.5 70.74,52.55 68.59,54.7 65.33,54.7 64.44,53.81 63.35,53.81 62.91,54.24 62.25,54.24 62.03,54.01 v2(62.03,53.76)
  BOTTOM w0.254: PR938.2 62.27,54.53 62.03,54.29 v2(62.03,53.76)
N4758359918: length 2.3
  TOP w0.203: PR932.1 55.45,53.24 v1(55.45,53.88) 55.45,53.99 55.92,54.46 PU901.27

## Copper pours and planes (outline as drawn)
2.5VSP on TOP (solid shape): 147.65,62.44 148.99,62.44 148.99,61.03 148.74,60.78 148.74,60.53 148.61,60.4 147.6,60.4 147.59,60.39 147.39,60.59 145.79,60.59 145.79,61.33 146,61.53 146,62.16 146.56,62.16 146.56,62.7 146,62.7 146,62.93 147.17,62.93
3V_SN on BOTTOM (solid shape): 162.01,71.89 162.33,71.58 163.22,71.58 163.22,70.94 161.44,70.94 161,71.38 161,72.97 162.01,72.97
3V_VIN on TOP (solid shape): 154.84,73.8 154.84,72.85 154.71,72.72 153,72.72 152.93,72.78 152.93,73.23 153,73.29 153.44,73.29 154.07,73.92 154.71,73.92
3V_VIN on BOTTOM (solid shape): 153.69,74.34 153.79,74.36 154.98,74.36 155.03,74.31 155.03,69.01 153.78,67.77 153.19,67.77 153.19,68.26 151.79,68.26 151.79,67.77 151.48,67.77 151.48,68.67 152.55,69.73 152.55,73.29 152.74,73.48 153.27,73.48 153.43,73.63 153.43,74.29 153.49,74.36 153.6,74.36
5V_SN on TOP (solid shape): 190.46,56.02 191.29,55.19 191.29,53.54 190.08,53.54 189.83,53.8 189.83,56.46 190.46,56.46
5V_VIN on BOTTOM (solid shape): 184.07,54.55 184.12,54.53 184.17,54.53 184.22,54.53 184.27,54.55 184.31,54.56 185.44,54.56 185.51,54.49 185.51,51.92 184.71,51.12 184.08,51.12 184,51.19 183.62,51.19 183.62,51.67 182.21,51.67 182.21,51.19 181.46,51.19 181.46,51.19 180.3,51.19 180.11,51.38 180.11,51.95 184.24,51.95 184.24,51.9 184.25,51.85 184.26,51.8 184.29,51.75 184.32,51.7 184.35,51.66 184.39,51.63 184.44,51.6 184.49,51.59 184.54,51.57 184.6,51.57 184.65,51.57 184.7,51.59 184.75,51.6 184.8,51.63 184.84,51.66 184.87,51.7 184.9,51.75 184.93,51.8 184.94,51.85 184.95,51.9 184.95,51.95 184.94,52.01 184.93,52.06 184.9,52.1 184.87,52.15 184.84,52.19 184.8,52.22 184.75,52.25 184.7,52.27 184.65,52.28 184.6,52.28 184.54,52.28 184.49,52.27 184.44,52.25 184.39,52.22 184.35,52.19 184.32,52.15 184.29,52.1 184.26,52.06 184.25,52.01 184.24,51.95 180.11,51.95 180.11,52.78 179.98,52.91 179.98,52.91 179.22,52.91 179.16,52.97 179.16,53.99 182.47,53.99 182.62,53.83 183.56,53.83 183.77,54.04 183.77,54.34 183.98,54.56 184.04,54.56
+0.6V_DDR_VTT on TOP (solid shape): 72.99,71.32 72.99,70.35 72.83,70.2 71.68,70.2 71.62,70.26 71.62,71.39 71.68,71.44 72.87,71.44
+0.6V_DDR_VTT on TOP (solid shape): 71.59,56.4 71.59,54.9 71.73,54.76 71.73,54.42 71.6,54.29 70.76,54.29 70.57,54.48 70.57,56.4 70.7,56.53 71.46,56.53
+0.6V_DDR_VTT on TOP (solid shape): 143.28,54.05 143.28,52.67 143.51,52.44 143.51,52 143.38,51.88 141.48,51.88 140.79,51.19 140.23,51.19 140,51.42 140,51.85 140.1,51.95 140.1,53.22 140.3,53.41 141.82,53.41 142.58,54.18 143.15,54.18
+0.6V_DDR_VTT on BOTTOM (solid shape): 142.64,54.54 142.64,52.84 142.8,52.69 143.33,52.69 143.48,52.54 143.48,51.98 143.38,51.88 142.31,51.88 142.17,52.02 142.17,52.69 142.31,52.84 142.31,54.54 142.37,54.6 142.59,54.6
+0.6V_DDR_VTT on IN3 (solid shape): 73.18,71.19 73.18,68.84 72.16,68.84 72.16,70.05 71.91,70.31 71.91,71.19 72.03,71.32 73.05,71.32
+0.6V_DDR_VTT on IN3 (solid shape): 72.77,56.37 72.31,55.92 70.69,55.92 70.53,56.07 70.53,56.91 70.71,57.08 71.58,57.08 71.78,57.29 71.78,57.54 72.77,57.54
+0.6VSP on BOTTOM (solid shape): 71.22,70.32 71.22,69.84 71.02,69.63 68.82,69.63 68.76,69.7 68.76,70.25 68.83,70.33 69.45,70.33 69.49,70.29 69.98,70.29 70.15,70.47 71.07,70.47
+0.6VSP on TOP: 70.06,68.71 69.88,68.89 69.88,69.04 69.87,69.05 69.87,70.27 70.1,70.5 70.1,71.32 70.24,71.46 71.43,71.46 71.46,71.42 71.46,71.27 71.46,71.27 71.46,71.11 70.94,71.11 70.94,70.67 71.46,70.67 71.46,70.06 70.9,69.5 70.9,69.34 70.89,69.33 70.89,69.02 70.9,69.01 70.9,68.75 70.86,68.71
+0.9V_LAN on TOP (solid shape): 246.99,123.43 246.99,122.26 247.88,121.37 247.88,121.14 247.72,120.99 247.27,120.99 247.09,121.17 247.09,121.8 246.76,122.13 246.76,123.43 246.81,123.48 246.94,123.48
+0.9V_LAN on TOP (solid shape): 244.4,124.57 244.4,124.06 244.34,124.01 242.8,124.01 242.77,124.04 242.77,124.6 242.82,124.65 244.32,124.65
+0.9V_LAN on TOP (solid shape): 248.18,123.43 248.18,122.54 248.19,122.53 248.19,122.41 248.37,122.22 249.41,122.22 249.6,122.03 249.6,121.68 249.48,121.55 248.63,121.55 247.98,122.2 247.98,123.43 248.03,123.48 248.13,123.48
+0.9V_LAN on BOTTOM (solid shape): 252.18,131.58 252.18,126.38 252.12,126.31 250.66,126.31 249.07,124.72 248.12,124.72 247.8,125.04 247.67,125.04 247.67,125.49 247.86,125.68 248.5,125.68 248.75,125.93 248.75,126.77 248.51,127.01 248.37,127.01 248.12,127.26 248.12,127.71 248.44,128.03 251.1,128.03 251.29,128.22 251.29,130.63 250.09,131.84 242.53,131.84 242.21,131.52 242.21,130 242.78,129.42 242.78,128.98 243.17,128.6 244.18,128.6 244.56,128.22 244.56,125.61 244.44,125.49 243.99,125.49 243.93,125.55 243.93,127.14 243.61,127.46 241.51,127.46 241.01,127.96 241.01,132.22 241.77,132.98 250.79,132.98
+0.9V_LAN on IN2 (solid shape): outline of 500 points within 242.28,120.98 248.88,129.58
+1.0V_APLL on TOP (solid shape): 124.74,104.66 124.93,104.47 125.25,104.47 125.44,104.28 125.44,103.2 124.93,103.2 124.93,103.58 124.61,103.9 124.48,103.9 124.36,104.02 124.36,104.91 124.74,104.91
+1.0V_APLL on IN2 (solid shape): outline of 711 points within 123.95,103.9 129.97,112.76
+1.0V_CLK2 on TOP (solid shape): outline of 149 points within 121.26,107.22 122.76,113.59
+1.0V_CLK3 on IN2 (solid shape): outline of 152 points within 120.39,107.22 121.66,112.3
+1.0V_CLK5 on IN2 (solid shape): outline of 205 points within 121.18,106.44 123.52,112.05
+1.0V_MPHYAON on TOP (solid shape): 141.5,119.96 141.5,118.06 137.06,113.61 137.06,109.78 134.35,107.07 132.93,107.07 132.74,107.26 132.74,108.02 132.93,108.21 134.14,108.21 134.58,108.66 134.59,108.66 134.73,108.74 134.81,108.88 134.81,108.89 135.66,109.74 135.66,110.59 135.7,110.6 135.77,110.62 135.83,110.67 135.9,110.69 135.96,110.67 136.55,110.94 135.96,111.21 135.9,111.19 135.83,111.21 135.77,111.26 135.7,111.28 135.66,111.29 135.66,114.63 140.1,119.07 140.1,119.96 140.3,120.15 141.31,120.15
+1.0V_MPHYAON on IN3 (solid shape): outline of 510 points within 122.4,106.03 133.86,107.84
+1.0V_MPHYGT on TOP (solid shape): 123.49,106.21 124.13,106.21 124.25,106.09 124.25,105.48 124.06,105.29 123.66,105.29 123.52,105.16 123.52,104.61 123.45,104.53 122.87,104.53 122.78,104.62 122.78,105.37 123.03,105.62 123.03,105.81 123.03,105.82 123.03,105.96 123.28,106.21 123.48,106.21
+1.0V_MPHYGT on BOTTOM (solid shape): 135.15,112.53 134.52,111.9 133.63,111.9 133.5,112.02 133.5,112.79 133.12,113.17 133.12,114.69 133.18,114.76 135.15,114.76
+1.0V_MPHYGT on BOTTOM (solid shape): 137.95,121.8 139.98,121.8 139.98,122.38 140.87,122.38 141.18,122.06 141.18,118.88 141.06,118.76 138.83,118.76 138.14,118.06 136.99,118.06 136.87,118.18 136.87,120.48 137.12,120.74 137.12,122.18 137.31,122.38 137.95,122.38
+1.0V_MPHYGT on IN1 (solid shape): outline of 1293 points within 122.69,105.17 136.36,112.98
+1.0V_MPHYGT on TOP: 133.25,123.07 137.34,123.07 138.58,121.83 138.58,119.9 138.33,119.64 137.06,119.64 136.84,119.86 136.84,120.75 136.63,120.97 133.34,120.97 132.73,121.58 130.62,121.58 130.58,121.62 130.58,122.18 130.61,122.25 130.67,122.28 131,122.62 130.69,122.99 130.64,122.99 130.64,124.15 130.77,124.28 132.04,124.28
+1.0V_PRIM on TOP (solid shape): 143.72,123.77 143.72,123.2 143.28,122.76 141.95,122.76 141.5,122.31 141.5,121.04 141.37,120.91 140.23,120.91 140.1,121.04 140.1,122.69 139.75,123.05 139.75,123.73 139.91,123.88 143.62,123.88
+1.0V_PRIM on TOP (solid shape): outline of 114 points within 120.32,121.19 130.45,128.76
+1.0V_PRIM on BOTTOM (solid shape): 160.04,88.83 159.49,88.83 159.49,86.88 160.04,86.88 160.04,86.37 157.73,86.37 157.48,86.62 157.48,89.11 157.72,89.36 160.04,89.36
+1.0V_PRIM on BOTTOM (solid shape): 129.67,122.62 129.67,121 130.33,120.34 130.33,119.84 129.44,119.84 129.31,119.96 127.47,119.96 127.47,121.36 128.36,121.36 128.55,121.55 128.55,122.57 128.55,122.57 128.55,122.62 128.67,122.74 129.54,122.74
+1.0V_PRIM on BOTTOM (solid shape): 134.97,125.23 143.15,125.23 143.66,124.72 143.66,123.14 143.09,122.57 136.55,122.57 136.1,123.01 134.2,123.01 131.44,125.77 131.44,125.79 131.42,125.79 131.02,126.19 129.32,126.19 129.25,126.21 129.22,126.28 129.21,126.33 129.19,126.38 128.88,126.59 128.64,126.32 128.64,126.3 128.12,125.78 128.12,125.69 127.94,125.51 123.87,125.51 123.85,125.54 123.85,126.02 124,126.17 125.35,126.17 126.96,127.78 132.42,127.78
+1.0V_PRIM on IN2 (solid shape): outline of 277 points within 120.17,97.65 123.47,103.74
+1.0V_PRIM on VCC: 151.34,86.5 151.34,92.45 150.65,93.14 150.65,117.46 149.48,118.63 141.84,118.63 133.12,109.91 133.12,108.68 133.95,107.86 133.95,95.81 132.87,94.73 132.87,93.29 121.12,93.29 121.12,101.66 121.69,102.23 121.69,103.25 122.39,103.94 122.39,105.85 124.93,108.39 124.93,117.76 126.18,119.01 132.15,119.01 137.23,124.09 156.87,124.09 156.87,93.5 161.31,89.06 161.31,86.86 160.95,86.5
+1.0V_PRIM_CORE on BOTTOM (solid shape): 148.54,125.33 148.54,124.8 149.96,124.8 149.96,125.36 150.24,125.36 150.24,123.71 147.6,121.07 147.6,117.1 147.41,116.91 145.44,116.91 144.93,117.42 144.93,123.28 147.01,125.36 148.51,125.36
+1.0V_PRIM_CORE on IN1 (solid shape): outline of 1313 points within 120.1,98.82 147.35,105.4
+1.0V_PRIM_CORE on IN2 (solid shape): outline of 314 points within 144.96,100.91 148.39,117.55
+1.0V_PRIM_COREP on TOP (solid shape): 150.96,128.73 150.96,127.01 149.88,127.01 149.76,127.14 149.76,128.79 149.86,128.89 150.8,128.89
+1.0V_PRIM_COREP on BOTTOM (solid shape): 152.3,129.17 152.3,126.73 152.65,126.38 154.91,126.38 155.51,126.97 155.51,127.58 155.6,127.67 156.34,127.67 156.41,127.6 156.41,127.14 156.28,127.01 156.28,126.63 155.33,125.68 151.41,125.68 151.28,125.55 148.23,125.55 148.23,126.57 148.49,126.82 149.63,126.82 149.76,126.95 149.76,129.04 149.95,129.23 152.23,129.23
+1.0V_SRAM on TOP (solid shape): 124.15,112.66 124.15,111.01 123.47,110.32 123.47,110.15 123.32,109.99 122.78,109.99 122.66,110.12 122.66,111.19 122.91,111.44 122.91,112.18 123.59,112.86 123.95,112.86
+1.0V_SRAM on IN3 (solid shape): outline of 702 points within 119.18,100.57 124.43,111.44
+1.0V_VCCST on TOP (solid shape): 126.54,124.51 126.54,124.24 125.99,124.24 125.99,123.81 126.54,123.81 126.54,123.53 126.53,123.51 124.77,123.51 124.67,123.61 124.67,124.09 125.12,124.54 126.51,124.54
+1.0V_VCCST_C on TOP (solid shape): 128.54,125.64 128.54,125.12 128.14,124.71 128.14,124.06 127.76,124.06 127.68,123.99 127.67,123.99 127.67,123.98 127.23,123.53 126.69,123.53 126.69,125.92 126.82,126.05 128.14,126.05
+1.0V_VCCSTG on TOP (solid shape): 122.45,124.4 122.45,124.12 121.93,124.12 121.93,123.68 122.45,123.68 122.45,123.38 122.45,123.38 122.12,123.38 121.75,123.01 121.75,121.17 121.18,121.17 121.12,121.23 121.12,124.22 121.33,124.43 122.43,124.43
+1.0V_VCCSTG_C on TOP (solid shape): 123.9,125.89 123.9,123.73 123.57,123.4 122.63,123.4 122.63,125.36 122.3,125.69 122.3,125.89 122.45,126.05 123.75,126.05
+1.0V_VCCSTG_R on TOP (solid shape): outline of 309 points within 118.34,108.29 121.31,111.52
+1.0VS_VCCIO on TOP (solid shape): 109.37,96.85 109.37,96.59 109.24,96.47 108.04,96.47 107.85,96.28 107.85,96.02 107.28,96.02 107.08,96.21 107.08,97.55 108.67,97.55
+1.0VS_VCCIO on TOP (solid shape): 116.05,99.1 116.05,98.03 116.23,97.85 116.86,97.85 116.94,97.93 117.04,97.93 117.4,97.57 116.9,97.08 116.27,97.08 115.63,96.44 114.49,96.44 114.39,96.54 114.39,97.45 115.03,98.09 115.03,98.41 114.85,98.6 114.59,98.6 114.55,98.63 114.55,99.13 114.6,99.18 115.96,99.18
+1.0VS_VCCIO on BOTTOM (solid shape): 136.55,127.26 137.95,127.26 137.95,127.84 138.45,127.84 138.64,127.65 138.64,126.71 138.4,126.47 134.94,126.47 134.83,126.57 134.83,127.65 135.02,127.84 136.55,127.84
+1.0VS_VCCIO on IN1 (solid shape): outline of 365 points within 107.92,96.36 116.09,99.03
+1.0VS_VCCIO on VCC: 106.45,93.29 106.45,97.55 114.28,97.55 115.16,98.44 118.15,98.44 118.51,98.8 118.51,105.85 118.83,106.17 118.83,112.71 119.85,113.72 119.85,118.74 121.5,120.39 121.5,127.2 122.39,128.09 138.03,128.09 138.71,127.41 138.71,124.6 137.02,124.6 131.94,119.52 125.97,119.52 124.48,118.04 124.48,117.83 124.55,117.76 124.55,108.55 122.01,106.01 122.01,104.1 121.31,103.4 121.31,103.4 121.2,103.25 121.31,103.1 121.31,102.39 120.74,101.82 120.74,93.29
+1.2V_DDR_B+ on TOP (solid shape): 67.4,75.74 67.4,75.13 67.14,74.88 67.14,73.42 67.08,73.35 64.6,73.35 64.36,73.59 64.36,76.16 64.41,76.21 66.93,76.21
+1.2V_DDR_B+ on BOTTOM (solid shape): 67.4,75.65 67.4,75.12 67.21,74.93 67.21,73.16 67.33,73.04 67.33,70.66 67.32,70.65 67.32,70.52 66.91,70.52 66.91,72.19 66.76,72.34 65.81,72.34 65.56,72.59 65.56,75.26 65.98,75.68 67.37,75.68
+1.2V_DDRP on TOP (solid shape): 71.98,60.93 71.98,57 71.83,56.84 69.62,56.84 69.37,57.1 65.94,57.1 65.75,57.29 65.75,60.78 66.06,61.1 71.82,61.1
+1.2V_DDRP on BOTTOM (solid shape): 71.27,57.16 70.89,56.78 69.7,56.78 69.39,57.08 65.76,57.08 65.43,57.41 65.43,60.97 65.66,61.2 69.98,61.2 70.25,61.48 71.27,61.48
+1.2V_DDRP on BOTTOM (solid shape): 70.89,68.97 70.89,68.32 71.26,67.96 71.26,66.69 71.27,66.67 71.27,66.11 70.25,66.11 70.25,67.51 69.02,68.74 68.82,68.74 68.77,68.79 68.77,69.35 68.85,69.43 70.43,69.43
+1.2V_LDO on TOP (solid shape): 274.38,63.21 274.38,62.1 274.19,61.91 274.19,61.2 273.91,60.92 271.63,60.92 271.5,61.05 271.5,61.81 271.71,62.03 272.76,62.03 272.77,62.04 273.8,62.04 273.85,62.04 274.1,62.28 274.1,62.33 274.17,62.4 274.17,63.22 274.22,63.27 274.32,63.27
+1.2V_LDO on TOP (solid shape): 275.97,63.21 275.97,62.44 276.2,62.22 276.3,62.22 276.43,62.09 276.43,60.08 276.2,59.85 275.33,59.85 275.16,60.03 275.16,60.54 275.46,60.84 275.64,60.84 275.87,60.84 276.02,60.99 276.02,61.22 276.02,62.06 275.77,62.32 275.77,63.21 275.82,63.26 275.92,63.26
+1.2V_LDO on BOTTOM (solid shape): 275.07,60.83 275.91,60.83 276,60.74 276,60.23 275.46,59.69 274.41,59.69 273.3,60.79 271.47,60.79 271.36,60.91 271.36,62.01 271.47,62.13 273.77,62.13
+1.2V_MEM on TOP (solid shape): 90.68,65.59 82.68,65.59 82.68,73.59 90.68,73.59
+1.2V_MEM on TOP (solid shape): 108.95,65.38 98.95,65.38 98.95,80.38 108.95,80.38
+1.2V_MEM on TOP (solid shape): 118.69,64.57 110.69,64.57 110.69,72.57 118.69,72.57
+1.2V_MEM on TOP (solid shape): outline of 11585 points within 72.16,51.62 139.03,97.74
+1.8V_PRIM on TOP (solid shape): 206.78,52.46 206.78,51.83 206.72,51.76 205.57,51.76 205.45,51.89 205.45,52.4 205.57,52.53 206.72,52.53
+1.8V_PRIM on TOP (solid shape): 262.15,87.25 262.59,87.25 262.59,87.78 263.84,87.78 263.85,87.74 263.93,87.61 264.06,87.52 264.09,87.51 264.09,86.46 264.06,86.42 261.89,86.42 261.78,86.52 261.78,87.76 261.81,87.78 262.15,87.78
+1.8V_PRIM on BOTTOM (solid shape): 178.94,60.87 180.03,60.87 180.05,60.86 180.05,60.27 179.86,60.08 178.33,60.08 177.89,60.53 177.89,60.59 178.52,61.22 178.59,61.22
+1.8V_RUN on TOP (solid shape): 214.4,51.7 214.4,51.17 214.17,50.94 212.49,50.94 212.43,51 212.43,51.95 214.15,51.95
+1.8V_RUN_AUDIO on TOP (solid shape): 263.61,57.4 263.61,55.22 263.8,55.03 263.8,54.39 262.85,54.39 262.73,54.52 262.73,56.41 262.53,56.6 261.42,56.6 261.34,56.68 261.34,57.14 261.42,57.21 262.76,57.21 262.96,57.41 263.6,57.41
+1.8V_RUN_CARD on TOP (solid shape): 298.5,59.14 299.46,59.14 299.53,59.08 299.53,58.6 299.46,58.53 297.41,58.53 297.41,59.47 297.46,59.52 298.12,59.52
+1.8V_RUN_CARD on TOP (solid shape): 283.73,63.72 283.73,62.38 283.53,62.18 281.83,62.18 281.42,62.59 280.6,62.59 280.43,62.76 280.43,63.69 280.61,63.86 283.59,63.86
+1.8V_RUN_CARD on TOP (solid shape): 275.56,63.23 275.56,62.34 275.89,62.01 275.89,61.05 275.82,60.97 275.51,60.97 275.44,61.05 275.44,62.11 275.36,62.19 275.36,63.23 275.41,63.28 275.51,63.28
+1.8V_RUN_CARD on IN2 (solid shape): 276.44,61.16 276.25,60.97 275.55,60.97 275.46,61.06 275.46,61.94 275.59,62.06 276.44,62.06
+1.8V_RUN_CARD on IN2 (solid shape): 281.13,63.94 281.22,63.94 281.43,63.73 281.43,62.92 281.16,62.65 280.16,62.65 279.93,62.42 279.4,62.42 279.42,62.44 279.42,63.36 280.01,63.94 281.13,63.94
+1.8V_RUN_UZ8 on TOP (solid shape): 212.24,52.08 212.24,51.73 211.68,51.73 211.68,51.19 212.24,51.19 212.24,50.94 211.22,50.94 211.03,51.13 210.46,51.13 210.4,51.19 210.4,51.64 210.27,51.76 208.24,51.76 208.18,51.83 208.18,52.46 208.24,52.53 211.8,52.53
+1.8VALWP on BOTTOM (solid shape): 178.52,62.18 178.52,61.48 178.27,61.22 177.89,61.61 177.82,61.61 177.51,61.29 177.51,61.22 177.89,60.84 177.63,60.59 177.63,60.02 177.82,59.83 177.82,59.51 177.32,59 175.66,60.65 175.41,60.65 174.78,61.29 174.78,61.35 176.49,63.07 177.63,63.07
+1VALWP on TOP (solid shape): 162.84,85.63 161.24,85.63 161.06,85.81 161.06,88.07 161.26,88.28 162.84,88.28
+1VALWP on BOTTOM (solid shape): 161.72,88.53 162.71,88.53 162.81,88.43 162.81,84.82 163.57,84.06 164.26,84.06 164.26,81.29 161.97,81.29 161.62,81.65 161.62,83.42 160.22,84.82 160.22,89.47 160.17,89.52 160.17,89.77 160.48,89.77
+1VALWP_B+ on TOP (solid shape): 154.2,83.07 154.2,81.58 153.68,81.58 152.83,82.43 152.83,82.97 152.98,83.12 154.15,83.12
+1VALWP_B+ on BOTTOM (solid shape): 150.65,84.26 152.27,84.26 152.85,83.68 154.86,83.68 154.86,81.67 153.62,81.67 152.98,82.31 152.76,82.31 152.75,82.31 152.63,82.33 152.5,82.31 152.49,82.31 152.15,82.31 152.14,82.31 152.02,82.33 151.89,82.31 151.88,82.31 150.72,82.31 150.19,82.31 149.53,82.97 149.3,82.97 149.2,83.07 148.66,83.07 148.66,83.55 147.29,83.55 147.29,83.07 146.99,83.07 146.99,84.34 147.39,84.75 150.16,84.75
+1VS_VCCIOP on BOTTOM (solid shape): 136.42,131.96 136.42,130.06 137.25,129.23 137.88,129.23 137.92,129.19 139.72,129.19 139.72,129.2 140.46,129.2 140.54,129.12 140.54,128.97 140.01,128.44 139.58,128.44 139.16,128.03 134.58,128.03 134.45,128.15 134.45,131.58 134.9,132.03 136.36,132.03
+2.5V_MEM on TOP (solid shape): 145.82,62.93 145.82,61.94 145.11,61.22 142.34,61.22 142.34,62.85 142.44,62.95 145.79,62.95
+2.5V_MEM on BOTTOM (solid shape): 143.53,62.47 143.53,61.22 143.28,60.97 142.21,60.97 142.06,61.12 142.06,62.7 142.14,62.77 143.23,62.77
+2.5V_VIN on TOP (solid shape): 151.98,62.81 151.98,61.22 152.8,60.4 152.8,58.44 153.08,58.16 153.08,57.09 153.02,57.03 152.31,57.03 152.24,57.1 152.23,57.1 151.98,57.35 151.98,60.15 151.73,60.4 151.03,60.4 150.9,60.53 150.9,62.81 151.03,62.94 151.85,62.94
+3.3V_1.8V_ESPI on TOP (solid shape): 145.31,85.04 145.39,85.04 145.5,84.92 145.5,84.16 145.12,83.78 145.12,82.62 144.8,82.62 144.61,82.81 144.61,84.15 144.74,84.28 144.74,84.91 144.87,85.04 145.31,85.04
+3.3V_1.8V_PGPPA on TOP (solid shape): 147.09,83.7 147.09,81.29 145.76,81.29 145.69,81.35 145.69,82.56 145.57,82.69 145.31,82.69 145.31,82.88 145.88,82.88 145.88,83.39 145.31,83.39 145.31,83.58 145.64,83.91 146.88,83.91
+3.3V_ALW on TOP (solid shape): 280.31,93.55 280.31,91.83 280.12,91.64 278.85,91.64 278.79,91.7 278.79,92.4 278.66,92.53 278.66,93.48 278.85,93.67 280.19,93.67
+3.3V_ALW on TOP (solid shape): 253.64,110.37 253.64,109.04 253.45,108.85 251.99,108.85 251.8,109.04 251.8,109.74 251.93,109.87 251.93,110.44 251.99,110.5 253.52,110.5
+3.3V_ALW on TOP (solid shape): 69.04,122.69 69.04,121.42 68.91,121.3 66.7,121.3 66.44,121.55 66.44,122.57 66.69,122.81 68.92,122.81
+3.3V_ALW on TOP (solid shape): 259.77,87.25 260.21,87.25 260.21,87.78 260.91,87.78 261.09,87.6 261.09,86.49 261,86.4 259.4,86.4 259.14,86.65 259.14,87.65 259.27,87.78 259.77,87.78
+3.3V_ALW on TOP (solid shape): 226.06,59.25 227.17,59.25 227.66,58.76 227.66,58.13 227.32,57.78 226.53,57.78 226.14,58.17 224.94,58.17 224.92,58.2 224.92,59.19 224.98,59.25 226.06,59.25
+3.3V_ALW on TOP (solid shape): 253.77,113.12 253.77,112.58 253.6,112.41 252.99,112.41 252.72,112.13 252.72,111.96 252.65,111.9 251.99,111.9 251.93,111.96 251.93,113.1 252.12,113.29 253.59,113.29
+3.3V_ALW on TOP (solid shape): 207.54,59.7 207.54,57.83 207.54,57.68 207.39,57.53 207.12,57.53 206.91,57.75 206.91,59.26 206.82,59.35 205.55,59.35 205.38,59.51 204.68,59.51 204.56,59.64 204.56,59.83 204.68,59.95 207.29,59.95
+3.3V_ALW on TOP (solid shape): 254.84,76.85 254.84,76.32 254.82,76.3 254.82,75.48 254.28,74.94 253.26,74.94 252.68,74.36 251.31,74.36 251.31,75.68 250.95,76.03 250.95,76.8 251.2,76.8 251.2,76.24 251.71,76.24 251.71,76.8 252.91,76.8 253.03,76.92 254.76,76.92
+3.3V_ALW on TOP (solid shape): 263.8,94.84 263.8,91.17 264.03,90.94 264.03,89.37 263.74,89.08 262.44,89.08 262.27,89.25 262.27,89.98 262.37,90.08 262.98,90.08 263.18,90.28 263.18,90.99 262.91,91.26 262.43,91.26 262.2,91.49 262.2,92.87 262.52,93.19 262.52,94.8 262.76,95.05 263.6,95.05
+3.3V_ALW on TOP (solid shape): 169.82,69.07 169.82,66.5 168.17,64.84 167.35,65.67 166.52,65.67 166.51,65.67 164.61,63.76 163.22,63.76 163.21,63.76 162.65,63.21 162.65,57.87 161.69,56.91 160.7,56.91 160.35,56.55 153.54,56.55 153.25,56.84 153.25,57.35 153.25,57.39 153.77,57.39 153.77,57.82 153.25,57.82 153.25,58.11 153.25,58.12 154.2,58.12 154.77,57.54 157.48,57.54 157.73,57.8 157.76,57.8 158.27,58.3 158.27,59.07 158.2,59.13 158.2,59.57 158.27,59.64 158.91,59.64 159.21,59.35 160.81,59.35 160.81,59.07 161,58.58 161.18,59.07 161.18,59.35 161.21,59.35 161.5,59.64 161.5,61.61 161.14,61.97 160.87,62.25 160.58,61.99 160.58,61.97 160.53,61.92 160,61.92 159.99,61.93 159.66,61.91 159.49,61.64 159.48,61.62 158.9,61.03 158.27,61.03 158.2,61.1 158.2,63.8 161.25,66.84 162.77,66.84 165.42,69.5 169.4,69.5
+3.3V_ALW on BOTTOM (solid shape): 224.31,67.45 224.31,66 223.29,66 223.29,67.45 223.42,67.57 224.18,67.57
+3.3V_ALW on BOTTOM (solid shape): 153.13,85.71 153.13,84.44 153.44,84.13 154.88,84.13 154.89,84.12 154.89,83.91 154.87,83.89 152.96,83.89 152.4,84.45 152.4,85.69 152.55,85.84 152.99,85.84
+3.3V_ALW on BOTTOM (solid shape): 288.53,127.34 288.53,126.55 288.3,126.32 288.3,124.32 288.15,124.17 287.09,124.17 286.53,123.6 286.53,121.13 286.45,121.05 285.98,121.05 285.9,121.13 285.9,125.86 287.53,127.49 288.38,127.49
+3.3V_ALW on BOTTOM (solid shape): 227.67,61.61 227.67,61.03 227.09,60.45 227.09,58.42 227.38,58.13 227.38,57.21 227,56.83 226.01,56.83 226.01,56.88 225.78,57.11 225.78,60.41 225.96,60.59 225.96,61.45 225.98,61.48 226.02,61.48 226.21,61.67 227.61,61.67
+3.3V_ALW on BOTTOM (solid shape): 158.38,115.29 158.38,114.21 157.62,113.45 157.62,113.21 157.48,113.07 157.48,112.13 157.4,112.05 157.17,112.05 157.01,112.22 157.01,113.04 156.49,113.56 154.54,113.56 154.54,114.58 156.87,114.58 157.38,115.09 157.38,115.4 157.45,115.48 158.19,115.48
+3.3V_ALW on BOTTOM: 170.31,69.14 170.78,68.67 170.78,68.6 170.39,68.21 170.2,68.4 169.05,68.4 168.31,67.65 165.81,67.65 165.06,68.4 165.06,71.58 165.31,71.83 166.71,71.83 166.71,71.26 168.81,71.26 168.81,71.83 170,71.83 170.31,71.52
+3.3V_ALW on VCC: outline of 163 points within 35.96,65.92 299.03,136.03
+3.3V_ALW_DSW on TOP (solid shape): outline of 105 points within 122.15,90.57 126.36,98.49
+3.3V_ALW_PCH on TOP (solid shape): 142.45,71.09 142.45,70.67 141.91,70.13 141.5,70.13 140.41,71.22 140.41,72.03 140.59,72.2 141.33,72.2
+3.3V_ALW_PCH on TOP (solid shape): 148.87,66.09 148.87,64.9 148.86,64.91 148.33,64.91 148,65.24 147.62,65.24 147.62,65.24 147.52,65.24 146.75,66 146.75,66.54 147.21,66.99 147.97,66.99
+3.3V_ALW_PCH on TOP (solid shape): outline of 775 points within 122.67,97.02 150.2,105.55
+3.3V_ALW_PCH on BOTTOM (solid shape): 152.8,110.06 152.8,109.72 152.3,109.72 152.3,109.28 152.8,109.28 152.8,108.38 152.69,108.27 151.9,108.27 151.75,108.42 151.75,110.01 151.89,110.15 152.72,110.15
+3.3V_ALW_PCH on BOTTOM (solid shape): 136.71,122.11 136.71,121.79 136.54,121.61 134.14,121.61 133.75,121.23 131.41,121.23 131.34,121.3 131.34,121.99 131.66,122.31 133.37,122.31 133.49,122.43 136.4,122.43
+3.3V_ALW_PCH on IN1 (solid shape): outline of 260 points within 136.22,78.22 143.15,83.7
+3.3V_ALW_PCH on IN3 (solid shape): 137.05,78.52 137.27,78.3 137.26,78.27 137.24,78.1 137.3,77.94 137.3,77.19 137.45,77.04 137.45,76.86 140.84,73.47 140.84,71.14 140.58,71.14 139.52,72.2 139.54,72.23 139.52,72.6 139.17,72.75 139.15,72.75 136.24,75.66 136.24,78.57 136.4,78.73 136.6,78.73 136.61,78.73 137.05,78.73
+3.3V_ALW_PCH on IN3 (solid shape): outline of 376 points within 119.59,96.14 123.16,99.16
+3.3V_ALW_PCH on VCC: 141.44,82.69 141.44,84.42 141.73,84.72 144.91,84.72 146.39,86.2 146.39,87.75 145.18,88.95 145.18,99.37 143.34,101.21 143.34,105.19 143.58,105.42 150.14,105.42 150.14,92.93 150.84,92.23 150.84,86.5 150.29,86.5 146.48,82.69
+3.3V_ALW_PCH_UZ3 on TOP (solid shape): 151.03,64.72 151.03,64.34 150.84,64.15 150.2,64.15 149.44,64.91 149.19,64.91 149.19,65.16 149.6,65.16 149.6,65.67 149.19,65.67 149.19,65.92 149.82,65.92
+3.3V_ALW_PCH_UZ3 on TOP (solid shape): 156.93,59.57 156.93,59.07 156.87,59 156.36,59 156.04,58.68 155.22,58.68 155.12,58.58 155.12,58.2 155.09,58.18 154.71,58.18 154.46,58.43 153.44,58.43 152.93,58.94 152.93,59.51 153.76,59.51 153.82,59.45 155.6,59.45 155.79,59.64 156.87,59.64
+3.3V_ALW_UE1 on TOP (solid shape): 252.3,79.26 252.3,77.67 252.06,77.43 252.06,77.04 251.97,76.95 250.98,76.95 250.95,76.97 250.95,77.33 251.48,77.86 251.48,79.39 251.51,79.41 252.15,79.41
+3.3V_ALWP on TOP (solid shape): 167.47,73.86 165.76,73.86 165.44,74.18 165.44,78.5 165.7,78.75 167.47,78.75
+3.3V_ALWP on BOTTOM (solid shape): 167.47,74.05 167.92,73.61 169,73.61 169.25,73.35 169.25,72.02 163.85,72.02 163.54,72.34 163.54,78.37 163.98,78.81 167.47,78.81
+3.3V_CAM on TOP (solid shape): 57.73,130.41 57.73,125.17 57.53,124.97 56.48,124.97 56.23,125.21 56.23,128.73 56.31,128.81 56.31,130.66 56.54,130.89 57.26,130.89
+3.3V_CAM on BOTTOM (solid shape): 56.39,133.31 56.39,131.92 56.54,131.76 56.54,131.33 57.2,130.67 57.2,129.76 57.06,129.63 56.44,129.63 56.28,129.79 56.28,130.98 56.11,131.15 56.11,133.31 56.16,133.36 56.34,133.36
+3.3V_CPS on TOP (solid shape): 31.86,99.81 33.77,99.81 33.96,99.62 33.96,98.52 33.89,98.46 31.01,98.46 31.01,99.25 31.01,99.26 31.01,99.62 31.01,99.63 31.01,100.02 31.14,100.15 31.52,100.15
+3.3V_CPS on IN2: 31.45,106.38 31.77,106.06 31.77,100.79 30.76,99.77 28.41,99.77 27.27,98.63 25.74,98.63 25.73,98.61 25.15,98.61 24.6,98.06 24.6,96.74 24.6,96.73 24.6,96.62 24.83,96.39 27.98,96.39 28.12,96.53 28.12,97.78 29.03,98.69 31.65,98.69 32.85,99.9 32.85,106.82 32.03,107.64 31.01,107.64 30.82,107.45 27.7,107.45 27.16,107.99 27.16,109.62 27.02,109.76 24.49,109.76 24.2,109.47 24.2,106.91 24.74,106.38 25.55,106.38 25.55,106.38
+3.3V_EC_PLL on TOP (solid shape): 250.87,83.96 250.87,83.02 250.59,82.74 250.59,80.91 250.39,80.71 250.39,79.83 250.76,79.46 251.27,79.46 251.33,79.4 251.33,78.88 251.26,78.8 250.43,78.8 249.72,79.51 249.72,79.72 249.71,79.74 249.71,80.66 250.19,81.14 250.19,82.97 250.52,83.3 250.52,83.93 250.62,84.03 250.8,84.03
+3.3V_HDD_M2 on TOP (solid shape): outline of 533 points within 10.06,40.63 29.42,46.68
+3.3V_HDD_M2 on BOTTOM (solid shape): 28.73,49.35 28.73,48.27 28.6,48.14 28.6,45.6 28.47,45.48 26.06,45.48 25.8,45.73 25.8,49.41 28.66,49.41
+3.3V_LAN on TOP (solid shape): 247.86,113.93 247.86,112.66 247.74,112.53 246.66,112.53 246.53,112.66 246.53,113.84 246.64,113.95 247.85,113.95
+3.3V_LAN on TOP (solid shape): 286.59,120.41 286.59,119.35 286.5,119.25 284.27,119.25 284,119.52 284,120.22 284.23,120.45 286.05,120.45 286.1,120.51 286.49,120.51
+3.3V_LAN on BOTTOM (solid shape): 240.67,125.45 240.67,125.03 240.67,125.03 240.67,124.6 240.86,124.41 241.77,124.41 241.9,124.28 241.9,123.77 241.7,123.58 240.31,123.58 239.99,123.9 239.99,125.49 240.64,125.49
+3.3V_LAN on IN2 (solid shape): 285.13,121.12 285.13,120.04 285.04,119.95 284.15,119.95 284.05,120.05 284.05,121.12 284.12,121.19 285.05,121.19
+3.3V_LAN on IN2 (solid shape): 254.67,131.33 254.67,129.54 254.44,129.31 252.89,129.31 252.65,129.55 252.65,130.48 251.61,131.52 244.44,131.52 243.86,130.95 243.61,130.95 243.36,131.2 242.4,131.2 241.9,130.69 241.9,126.62 242.39,126.12 242.39,124.42 243.51,123.3 243.51,120.76 243.67,120.6 243.67,114.95 244.31,114.31 247.42,114.31 247.61,114.12 247.61,112.66 247.48,112.53 242.72,112.53 241.77,113.49 241.77,118.37 240.88,119.26 240.88,119.77 242.11,121 242.11,122.67 241.78,123 240.63,123 240.12,123.51 240.12,131.77 241.07,132.73 253.28,132.73
+3.3V_LAN_OUT on TOP (solid shape): 245.78,123.44 245.78,121.97 245.76,121.95 245.72,121.88 245.69,121.81 244.98,121.09 244.98,120.69 244.85,120.56 244.37,120.56 244.35,120.58 244.35,121.07 244.54,121.26 244.54,121.66 245.16,122.29 245.16,123.43 245.21,123.48 245.74,123.48
+3.3V_LAN_OUT on BOTTOM (solid shape): outline of 231 points within 241.39,121.17 248.63,126.69
+3.3V_LAN_OUT on IN2 (solid shape): 250.4,127.72 250.4,124.99 250.4,124.98 250.4,120.28 249.64,119.52 246.02,119.52 245.76,119.78 245.06,119.78 244.41,120.43 244.41,122.12 244.6,122.31 245.58,122.31 245.71,122.18 245.71,121.23 246.21,120.72 248.82,120.72 249.2,121.11 249.2,124.98 248.12,126.06 248.12,126.25 248.82,126.95 248.82,128.18 247.06,129.93 246.78,129.93 246.66,130.06 246.66,130.31 246.78,130.44 247.67,130.44
+3.3V_LAN_UZ2 on TOP (solid shape): 250.07,113.77 250.07,113.06 250.67,112.46 250.67,111.95 250.6,111.89 249.68,111.89 249,112.56 248.18,112.56 248.05,112.68 248.05,113.1 248.63,113.1 248.63,113.61 248.05,113.61 248.05,113.9 248.1,113.94 249.9,113.94
+3.3V_M_TPM on BOTTOM (solid shape): 163.49,109.18 163.49,104.62 163.15,104.28 161.79,104.28 161.64,104.43 161.64,104.96 161.76,105.08 162.22,105.08 162.52,105.38 162.52,108.53 161.97,109.08 161.26,109.08 161.19,109.15 161.19,109.28 161.26,109.36 162.01,109.36 162.08,109.42 163.24,109.42
+3.3V_M_TPM on BOTTOM (solid shape): 153.82,109.95 153.82,109.03 153.83,109.02 153.83,108.96 153.87,108.96 154.32,108.51 154.35,108.49 154.39,108.46 154.46,108.39 154.71,108.39 155.15,107.95 155.15,105.15 154.9,104.9 154.32,104.9 154.09,105.13 154.09,106.25 154.21,106.37 154.21,107.34 152.98,108.57 152.98,110.11 153.06,110.18 153.59,110.18
+3.3V_M_TPM on IN2 (solid shape): 155.24,107.69 155.24,106.61 155.29,106.57 155.29,106.54 155.51,106.14 155.95,106.3 157.08,106.3 157.13,106.29 157.18,106.3 157.67,106.3 157.68,106.29 157.83,106.26 157.98,106.29 157.99,106.3 158.61,106.3 158.77,106.23 158.94,106.24 159.02,106.26 159.08,106.3 160.69,106.3 160.83,106.16 161.14,106.16 161.27,106.3 162.11,106.3 163.49,104.92 163.49,104.63 163.14,104.28 161.1,104.28 160.96,104.3 160.84,104.28 160.83,104.28 158.37,104.28 158.08,104.43 157.78,104.28 157.28,104.28 156.53,105.03 154.58,105.03 154.07,105.54 154.07,107.72 154.25,107.9 155.04,107.9
+3.3V_MMI_AUX on TOP (solid shape): 276.39,71.87 276.39,69.26 276.5,69.15 276.5,68.68 276.36,68.54 276.34,68.53 276.01,68.31 275.97,67.91 275.98,67.89 275.98,66.54 275.92,66.47 275.83,66.47 275.76,66.54 275.76,67.31 275.53,67.55 275.53,68.18 274.58,69.13 272.64,69.13 272.52,69.25 272.52,71.38 272.81,71.68 275.47,71.68 275.7,71.91 276.35,71.91
+3.3V_MMI_IN on TOP (solid shape): 274.37,75.04 274.37,74.33 274.72,73.98 275.08,73.98 275.41,73.65 275.41,72.45 275.33,72.38 274.36,72.38 273.96,71.97 272.34,71.97 272.11,72.2 272.11,72.7 272.64,72.7 272.64,73.21 272.11,73.21 272.11,73.5 272.64,73.5 272.64,74.01 272.11,74.01 272.11,75.09 272.24,75.22 274.19,75.22
+3.3V_MMI_IN on TOP (solid shape): 274.78,63.21 274.78,62.16 274.72,62.11 274.72,61.11 274.74,61.1 274.74,60.18 274.47,59.91 274.47,56.87 274.32,56.73 273.76,56.73 273.15,57.33 273.15,58.4 272.31,59.23 272.31,59.45 272.39,59.52 273.06,59.52 273.67,59.52 273.99,59.84 273.99,60.78 274.36,61.14 274.36,61.9 274.53,62.08 274.53,62.36 274.57,62.39 274.57,63.21 274.62,63.26 274.72,63.26
+3.3V_MMI_IN on IN2 (solid shape): 274.34,72.51 274.34,69.48 273.39,68.53 273.39,66.81 271.49,64.91 271.49,62.09 271.4,62 271.4,60.2 271.4,60.2 271.38,60.09 271.4,59.99 271.4,59.99 271.4,59.86 271.57,59.69 273.32,59.69 273.39,59.61 273.39,58.63 273.33,58.57 270.98,58.57 269.91,59.64 269.91,62.57 270.28,62.94 270.28,65.48 272.18,67.38 272.18,69.1 272.85,69.76 272.85,72.71 273.24,73.11 273.75,73.11
+3.3V_RUN on TOP (solid shape): 34.25,98.05 34.25,97.23 34.12,97.1 32.79,97.1 32.6,97.29 32.6,98.18 34.12,98.18
+3.3V_RUN on TOP (solid shape): 28.98,50.43 28.73,50.18 26.25,50.18 25.93,50.49 25.93,54.43 28.98,54.43
+3.3V_RUN on TOP (solid shape): 37.11,68.53 37.11,66.18 36.6,65.67 33.11,65.67 32.85,65.92 32.85,68.21 33.42,68.78 36.85,68.78
+3.3V_RUN on TOP (solid shape): 207.26,56.93 207.26,56.62 206.7,56.62 206.7,56.18 207.26,56.18 207.26,55.77 207.45,55.77 207.45,54.93 207.41,54.9 206.91,54.9 206.91,55.31 206.36,55.85 206.36,56.89 206.45,56.98 207.21,56.98
+3.3V_RUN on TOP (solid shape): 157.44,67.19 157.44,65.92 157.19,65.67 154,65.67 154,66.24 152.03,66.24 151.99,66.2 151.99,65.67 151.48,65.67 151.36,65.8 151.36,67.27 151.47,67.38 157.25,67.38
+3.3V_RUN on TOP (solid shape): 245.51,66.56 246.02,66.56 246.02,67.13 246.34,67.13 246.47,67 246.47,66.05 245.77,65.35 245.77,64.59 245.71,64.53 245.07,64.53 244.44,65.16 244.35,65.16 244.35,65.64 244.65,65.64 245.26,66.25 245.26,67.13 245.51,67.13
+3.3V_RUN on TOP (solid shape): 270.07,75.68 271.57,75.68 271.98,75.27 271.98,73.88 272.51,73.88 272.51,73.63 271.98,73.63 271.98,73.08 272.51,73.08 272.51,72.83 271.98,72.83 271.98,71.75 271.81,71.58 270.65,71.58 270.65,71.62 270.48,72.54 270.08,73.39 268.81,74.64 267.1,75.15 267.1,76.36 267.28,76.54 269.21,76.54
+3.3V_RUN on BOTTOM (solid shape): 247.88,55.9 247.88,54.43 247.7,54.25 246.82,54.25 246.78,54.29 246.78,55.82 246.99,56.03 247.75,56.03
+3.3V_RUN on BOTTOM (solid shape): 28.73,51.51 28.73,49.6 28.28,49.6 28.28,50.18 26.25,50.18 26.25,49.6 25.74,49.6 25.74,51.38 26,51.64 28.6,51.64
+3.3V_RUN on BOTTOM (solid shape): 149.69,110.82 149.16,110.82 148.49,110.15 148.49,109.48 148.68,109.29 149.12,109.29 149.12,108.91 148.68,108.91 148.3,108.53 147.8,108.53 147.5,108.23 147.5,106.77 147.47,106.74 146.95,106.74 146.9,106.79 146.9,108.41 147.22,108.72 147.22,110.82 147.28,110.88 148.36,110.88 148.8,111.33 149.69,111.33
+3.3V_RUN on IN2 (solid shape): 140.56,82.76 137.11,82.76 136.98,82.64 136.5,82.64 136.37,82.76 136.37,83.12 136.78,83.53 140.56,83.53
+3.3V_RUN on IN2 (solid shape): 157.02,66.69 157.02,65.9 156.89,65.77 154.41,65.77 154.2,65.97 154.05,65.97 154,66.03 154,66.74 154.71,66.74 154.79,66.81 156.89,66.81
+3.3V_RUN on VCC: 156.97,63 152.47,67.51 144.11,67.51 143.47,66.88 34,66.88 34,70.28 21.3,82.98 21.3,90.77 23.39,92.87 23.39,105.99 29.36,111.96 29.36,114.84 41.66,127.14 77.85,127.14 80.46,129.74 104.08,129.74 105.54,131.2 126.28,131.2 126.52,130.97 126.52,128.6 122.13,128.6 121.18,127.65 81.45,127.65 80.85,127.04 80.82,127.01 78.59,124.79 48.62,124.79 41.36,117.53 41.36,116.41 40.3,116.41 39.27,115.37 39.27,109.17 37.13,109.17 36.41,108.45 36.41,93.89 37.07,93.23 43.48,93.23 43.71,93 43.71,92.19 43.42,91.9 36.56,91.9 35.46,90.79 35.46,86.33 36.41,85.38 36.41,79.28 42.65,73.04 42.82,73.04 48.8,73.04 49.93,74.18 61.95,74.18 63.08,73.05 156.13,73.1 163.81,65.42 232.92,65.42 242.64,75.13 258.21,75.13 260.25,77.16 268.31,77.16 268.31,75.68 268.08,75.45 265.09,75.45 262.87,73.23 248.01,73.23 237.15,62.37 163.03,62.37 162.39,63
+3.3V_RUN on VCC: 135.13,82.69 133.37,84.44 133.37,94.52 134.45,95.6 134.45,108.07 133.63,108.89 133.63,109.7 142.05,118.12 149.27,118.12 150.14,117.25 150.14,105.93 143.37,105.93 142.84,105.4 142.84,101 144.68,99.16 144.68,88.74 145.88,87.54 145.88,86.41 144.7,85.23 141.52,85.23 140.93,84.63 140.93,82.69
+3.3V_RUN_AUDIO on TOP (solid shape): 262.28,67.7 262.28,67.13 261.9,66.75 261.9,66.18 261.39,66.18 261.39,66.62 261.2,66.81 261.2,67.7 261.33,67.83 262.15,67.83
+3.3V_RUN_AUDIO on TOP (solid shape): outline of 85 points within 245.26,67 254.4,69.42
+3.3V_RUN_AUDIO on IN1 (solid shape): outline of 363 points within 248.69,66.75 261.75,69.92
+3.3V_RUN_AUDIO_DVDD on TOP (solid shape): 261.9,65.29 261.77,65.16 260.69,65.16 260.5,64.97 260.5,64.37 260.04,63.92 260.04,63.16 259.83,62.94 259.48,62.94 259.42,63 259.42,63.79 260.06,64.43 260.06,65.73 260.12,65.8 261.9,65.8
+3.3V_RUN_AUDIO_UZ5 on TOP (solid shape): 248.82,66.43 248.82,65.25 248.72,65.25 247.99,64.53 247.1,64.53 247.04,64.59 247.04,66.43 247.19,66.58 248.66,66.58
+3.3V_RUN_CARD on TOP (solid shape): 285.42,56.98 286.56,56.98 286.71,56.83 286.71,56.5 286.59,56.37 282.83,56.37 282.66,56.21 278.88,56.21 278.81,56.27 278.81,57.2 278.9,57.29 282.34,57.29 282.47,57.41 284.99,57.41
+3.3V_RUN_CARD on IN2 (solid shape): 280.57,57.16 280.57,56.46 280.44,56.34 278.79,56.34 278.79,57.35 280.38,57.35
+3.3V_RUN_CARD on IN2 (solid shape): 275.3,62.05 275.3,61.16 274.85,60.72 274.85,60.34 273.84,60.34 273.84,61.86 274.15,62.18 275.17,62.18
+3.3V_RUN_UZ3 on TOP (solid shape): 157.25,65.14 157.25,62.18 156.93,61.86 156.93,61.1 156.87,61.03 156.23,61.03 155.98,61.29 154.9,61.29 154.84,61.35 154.84,61.8 154.65,61.99 154.2,61.99 153.95,62.24 153.95,62.81 152.49,64.27 151.76,64.27 151.48,64.55 151.48,65.49 156.89,65.49
+3.3V_TP on TOP (solid shape): 209.75,58.24 210.04,57.95 210.04,57.55 209.87,57.38 209.18,57.38 208.91,57.11 208.91,55.92 207.41,55.92 207.41,56.91 208.1,56.91 208.51,57.31 208.66,57.31 209.24,57.9 209.24,58.76 209.75,58.76
+3.3V_TSP on TOP (solid shape): 51.33,131.84 51.33,131.58 51.14,131.39 51.14,129.23 50.63,129.23 50.63,130.31 50.57,130.38 50.57,131.58 50.95,131.96 51.2,131.96
+3.3V_VDD_PIC on TOP (solid shape): 36.66,89.55 36.66,87.58 36.41,87.58 36.41,88.15 35.9,88.15 35.9,87.58 35.28,87.58 35.09,87.77 35.09,89.53 35.23,89.67 36.54,89.67
+3.3V_VDD_PIC on TOP (solid shape): 39.61,95.71 39.61,92.54 39.51,92.44 38.59,92.44 38.15,92.89 38.15,94.84 34.25,98.74 34.25,99.29 34.35,99.39 35.93,99.39
+3.3V_VDD_PIC on IN1 (solid shape): 40.28,92.89 40.28,92.56 36.04,88.31 35.65,88.31 35,88.96 35,89.22 38.86,93.08 38.86,93.2 39.32,93.66 39.51,93.66
+3.3V_VDD_PIC on IN2 (solid shape): 27.07,66.06 27.07,65.06 26.9,64.88 25.6,64.88 25.44,65.05 25.44,66.04 25.63,66.23 26.91,66.23
+3.3V_VDD_PIC on BOTTOM: 35.24,89.71 36.41,89.71 37.45,88.67 37.45,78.76 38.17,78.04 38.17,77 38.1,76.92 36.65,76.92 35.41,78.16 35.41,82.61 35.03,82.99 35.03,89.5
+3.3V_VDD_PIC on BOTTOM: 19.71,65.67 20.15,65.67 20.28,65.54 20.28,64.84 20.39,64.74 21.57,64.74 21.72,64.59 22.05,64.59 22.22,64.77 22.22,65.95 22.36,66.09 26.03,66.09 26.08,66.04 26.08,65.23 25.77,64.91 23.63,64.91 23.34,64.62 23.34,64.13 22.63,63.42 21.18,63.42 20.99,63.61 19.92,63.61 19.58,63.96 19.58,65.54
+3.3V_VDD_PIC on IN1: 34.99,62.76 34.21,62.76 33.44,63.54 33.44,64.79 33.64,65 34.36,65 34.49,64.87 34.49,64.01 35.05,63.45 35.05,62.83
+3.3V_VDD_PIC on IN1: 37.68,78.2 38.4,78.2 38.7,77.91 38.7,76.29 38.67,76.26 37.83,76.26 37.54,76.55 37.54,78.07
+3.3V_VDD_PIC on IN2: 33.37,63.9 34.68,63.9 35.06,63.52 35.06,62.89 34.94,62.76 33.56,62.76 33.27,63.05 33.27,63.8
+3.3V_VDD_PIC_PDA on TOP (solid shape): 36.66,87.07 35.96,86.37 35.96,85.86 35.46,85.86 35.08,85.48 35.08,85.42 34.89,85.42 34.82,85.48 34.82,85.8 35.2,86.18 35.2,87.13 35.46,87.39 36.66,87.39
+3.3V_WLAN on TOP (solid shape): 242.44,63.78 242.44,61.56 242.37,61.48 240.97,61.48 240.87,61.58 240.87,63.63 240.87,63.76 241,63.89 242.33,63.89
+3.3V_WLAN on TOP (solid shape): 242.53,80.95 242.53,78.19 242,77.66 241.11,77.66 241.04,77.72 241.04,81.07 241.07,81.1 242.38,81.1
+3.3V_WLAN on TOP (solid shape): 248.69,108.01 248.74,107.99 248.74,107.51 249.24,107.51 249.24,108.02 249.54,108.02 249.54,107.51 250.04,107.51 250.04,108.02 250.56,108.02 250.66,107.92 250.66,106.2 249.23,104.76 246.71,104.76 246.11,105.36 244.36,105.36 244.23,105.23 244.23,103.5 244.53,103.2 244.53,101.85 244.58,101.81 244.58,101.48 244.32,101.23 242.47,101.23 242.24,101.45 242.24,106.11 242.65,106.52 243.49,106.52 243.6,106.63 247.23,106.63 247.67,107.07 247.67,107.77 247.93,108.02 248.69,108.02
+3.3V_WLAN on BOTTOM (solid shape): 244.58,102.25 244.58,101.2 243.05,99.68 241.2,99.68 241.2,100.72 242.91,102.44 244.38,102.44
+3.3V_WLAN on BOTTOM (solid shape): outline of 246 points within 239.47,61.29 246.28,86.4
+3.3V_WLAN_UZ2 on TOP (solid shape): 250.65,110.45 250.65,108.33 250.48,108.16 249.94,108.16 249.94,108.15 249.91,108.15 249.91,107.63 249.66,107.63 249.66,108.15 249.64,108.15 249.64,108.16 249.14,108.16 249.14,108.15 249.11,108.15 249.11,107.63 248.86,107.63 248.86,108.08 248.84,108.09 248.84,108.16 248.37,108.16 248.31,108.23 248.31,110.17 248.58,110.44 249.13,110.44 249.2,110.5 250.6,110.5
+3.3V_WWAN on TOP (solid shape): 276.31,96.85 275.8,96.85 275.8,96.14 276.31,96.14 276.31,95.65 275.8,95.65 275.8,94.94 276.31,94.94 276.31,94.37 274.53,94.37 274.28,94.63 274.28,97.1 274.6,97.42 276.31,97.42
+3.3V_WWAN on TOP (solid shape): 239.04,112.91 239.04,109.42 239.36,109.1 239.36,106.31 238.86,105.82 238.83,105.82 238.83,105.79 238.72,105.67 238.72,101.22 238.09,100.59 237.23,99.73 237.23,97.63 237.41,97.46 237.88,97.46 238.09,97.25 238.09,93.82 237.15,93.82 236.9,93.56 236.75,93.56 236.33,93.97 236.12,93.97 236.12,104.91 236.13,104.95 236.16,104.96 236.45,105.14 236.46,105.48 236.44,105.52 236.69,105.76 236.69,106.63 237.2,107.14 237.2,112.85 237.51,113.17 238.78,113.17
+3.3V_WWAN on BOTTOM (solid shape): 238.73,112.96 238.73,110.93 238.63,110.83 237.23,110.83 237.13,110.93 237.13,113.04 237.26,113.17 238.53,113.17
+3.3V_WWAN on BOTTOM (solid shape): 276.5,96.59 276.5,94.58 276.25,94.32 274.33,94.32 274.03,94.63 274.03,95.45 272.95,96.53 272.95,98.37 273.26,98.69 274.41,98.69
+3.3V_WWAN on BOTTOM (solid shape): 237.01,95.11 237.01,94.77 237.13,94.65 238.62,94.65 238.71,94.56 238.71,91.57 236.62,89.48 236.62,88.53 236.56,88.47 233.89,88.47 233.89,89.83 235.14,91.07 235.86,91.07 236.73,91.93 236.73,92.92 236.48,93.17 236.48,95.1 236.57,95.19 236.93,95.19
+3.3V_WWAN on BOTTOM (solid shape): 242.78,107.39 253.83,107.39 254.66,108.21 256.82,108.21 257.35,107.68 269.21,107.68 272.13,104.76 272.13,103.24 269.68,103.24 269.68,103.59 267.35,105.92 240.64,105.92 239.33,107.22 255.01,107.22 255.02,107.17 255.03,107.12 255.05,107.07 255.08,107.02 255.11,106.98 255.15,106.95 255.19,106.92 255.24,106.89 255.29,106.88 255.34,106.87 255.4,106.87 255.45,106.88 255.5,106.89 255.55,106.92 255.59,106.95 255.63,106.98 255.66,107.02 255.69,107.07 255.71,107.12 255.72,107.17 255.73,107.22 255.72,107.28 255.71,107.33 255.69,107.38 255.66,107.43 255.63,107.47 255.59,107.5 255.55,107.53 255.5,107.56 255.45,107.57 255.4,107.58 255.34,107.58 255.29,107.57 255.24,107.56 255.19,107.53 255.15,107.5 255.11,107.47 255.08,107.43 255.05,107.38 255.03,107.33 255.02,107.28 255.01,107.22 239.33,107.22 239.16,107.39 237.83,107.39 237.64,107.58 237.64,108.91 237.83,109.1 238.72,109.1 239.1,109.48 240.69,109.48
+3.3V_WWAN_UZ4 on TOP (solid shape): 278.47,97.1 278.47,93.23 277.52,92.28 277.52,91.7 277.46,91.64 276.38,91.64 276.06,91.96 275.49,91.96 275.49,93.29 276.44,94.24 276.44,94.27 276.45,94.27 276.45,95.05 276.44,95.05 276.44,95.07 275.92,95.07 275.92,95.52 276.44,95.52 276.44,95.54 276.45,95.54 276.45,96.25 276.44,96.25 276.44,96.27 275.92,96.27 275.92,96.72 276.44,96.72 276.44,96.74 276.45,96.74 276.45,97.39 278.18,97.39
+5V_ALW on TOP (solid shape): 275.66,75.53 275.66,74.56 275.41,74.31 274.9,74.31 274.75,74.46 274.75,75.55 274.85,75.65 275.54,75.65
+5V_ALW on TOP (solid shape): 52.04,92.14 52.04,92.06 52.7,91.4 52.7,91.12 52.6,91.02 52.35,91.02 52.17,91.2 51.51,91.2 51.43,91.27 51.43,92.14 51.48,92.19 51.99,92.19
+5V_ALW on TOP (solid shape): 279.74,90.12 280.19,90.12 280.31,90.24 280.57,90.24 280.82,89.99 280.82,88.66 280.5,88.34 279.04,88.34 278.79,88.59 278.79,90.18 278.85,90.24 279.61,90.24
+5V_ALW on TOP (solid shape): 201.95,56.57 201.95,54.18 201.76,53.99 199.19,53.99 199.03,54.14 199.03,54.98 199.05,54.98 199.05,55 199.55,55 199.55,55.71 199.03,55.71 199.03,56.2 199.55,56.2 199.55,56.91 199.05,56.91 199.05,58.14 199.35,58.43 200.09,58.43
+5V_ALW on TOP (solid shape): 275.68,79.83 278.92,79.83 278.98,79.77 278.98,77.29 278.6,76.91 277.46,76.91 277.39,76.97 277.39,77.73 277.46,77.8 277.46,78.37 277.2,78.62 275.99,78.62 275.99,79 275.61,79.39 274.98,79.39 274.98,79.89 275.61,79.89
+5V_ALW on BOTTOM (solid shape): 147.09,129.23 147.09,127.71 146.9,127.52 145.83,127.52 145.68,127.67 145.68,129.23 145.87,129.42 146.9,129.42
+5V_ALW on BOTTOM (solid shape): 20.28,53.54 20.28,51.76 20.09,51.57 18.12,51.57 17.99,51.7 17.99,53.48 18.18,53.67 20.15,53.67
+5V_ALW on BOTTOM (solid shape): 21.66,77.04 22.19,77.04 22.19,76.59 21.66,76.59 21.66,75.84 22.19,75.84 22.19,75.39 21.66,75.39 21.66,74.8 21.55,74.69 20.15,74.69 19.96,74.88 19.96,77.42 20.28,77.73 21.66,77.73
+5V_ALW on IN2 (solid shape): outline of 186 points within 72.41,129.42 87.78,135.65
+5V_ALW on BOTTOM: 162.79,127.79 162.96,127.61 162.96,126.38 162.77,126.19 161.42,126.19 161.16,126.44 161.16,127.62 161.33,127.79
+5V_ALW on VCC: outline of 154 points within 14.31,48.13 282.09,135.68
+5V_ALW_PDA on TOP (solid shape): 34.32,78.56 34.35,78.48 34.3,78.4 34.19,78 34.55,77.8 34.58,77.81 34.78,77.6 34.78,76.37 34.37,75.96 32.59,75.96 32.43,76.11 32.43,76.62 32.47,76.63 32.74,76.98 32.45,77.32 32.45,77.35 32.44,77.39 32.44,78.52 32.51,78.6 34.28,78.6
+5V_ALW_PDA on BOTTOM (solid shape): outline of 184 points within 21.79,73.8 35.39,77.81
+5V_ALWP on TOP (solid shape): 198.86,57.47 198.86,56.8 198.93,56.8 198.93,56.78 199.41,56.78 199.41,56.33 198.87,56.33 198.87,55.58 199.41,55.58 199.41,55.14 198.86,55.14 198.86,54.04 199.1,53.8 199.99,53.8 200.18,53.6 200.18,52.33 196.34,52.33 195.98,52.69 195.98,57.29 196.34,57.64 198.68,57.64
+5V_ALWP on BOTTOM (solid shape): 199.03,58.62 199.03,54.6 200.18,53.45 200.18,52.33 194.21,52.33 193.83,52.72 193.83,58.43 194.14,58.75 198.91,58.75
+5V_PD_VDD on TOP (solid shape): 21.46,69.31 21.46,67.91 21.36,67.8 19.95,67.8 19.87,67.89 19.87,68.45 19.73,68.58 19.73,69.25 20,69.52 21.26,69.52
+5V_RUN on TOP (solid shape): 275.74,87.13 275.74,86.71 275.22,86.71 275.22,86.2 275.74,86.2 275.74,85.91 275.22,85.91 275.22,85.4 275.74,85.4 275.74,85.04 275.61,84.91 273.96,84.91 273.65,85.23 273.65,87.01 273.96,87.32 275.55,87.32
+5V_RUN on TOP (solid shape): 245.78,63.07 245.78,61.05 244.18,59.46 243.69,59.46 243.69,58.93 243.44,58.93 243.44,59.46 242.89,59.46 242.89,58.93 242.64,58.93 242.64,59.46 242.63,59.46 242.63,59.51 240.31,59.51 239.99,59.83 239.99,61.1 240.24,61.35 242.45,61.35 242.6,61.5 242.6,62.94 242.68,63.03 244.75,63.03 244.85,63.13 245.72,63.13
+5V_RUN on BOTTOM (solid shape): 19.77,91.26 19.77,90.5 19.65,90.37 17.69,90.37 17.22,90.84 17.22,91.35 17.32,91.45 19.58,91.45
+5V_RUN on BOTTOM (solid shape): 239.29,120.34 239.29,117.93 239.16,117.8 237.89,117.8 237.32,118.37 235.99,118.37 235.74,118.63 235.74,119.12 236.01,119.39 238.34,119.39 238.5,119.56 238.5,120.34 238.58,120.42 239.22,120.42
+5V_RUN on IN2 (solid shape): 35.9,65.35 35.9,64.78 35.65,64.53 33.68,64.53 33.17,65.03 33.17,65.54 35.71,65.54
+5V_RUN on IN2 (solid shape): 273.91,89.62 274.94,88.6 274.94,85.06 274.79,84.91 274.03,84.91 273.45,85.48 273.45,88.59 272.9,89.15 272.9,90.41 272.92,90.43 273.91,90.43
+5V_RUN on IN2 (solid shape): 240.05,117.61 240.05,117.1 239.93,116.98 239.29,116.98 238.78,117.49 238.21,117.49 238.02,117.68 238.02,118.25 238.15,118.37 239.29,118.37
+5V_RUN on IN2 (solid shape): 18.19,72.61 18.19,70.83 18.08,70.72 17.3,70.72 17.11,70.91 17.11,72.63 17.21,72.73 18.07,72.73
+5V_RUN on IN2 (solid shape): 25.61,67.45 25.61,66.69 24.98,66.69 23.96,67.7 23.07,67.7 22.88,67.89 22.88,68.53 23.01,68.65 24.41,68.65
+5V_RUN on IN2 (solid shape): 18.57,91.51 18.57,90.63 18.38,90.43 17.99,90.43 17.42,89.86 17.42,89.8 17.4,89.77 16.41,89.77 16.41,90.17 16.42,90.18 16.42,90.91 17.16,91.64 18.44,91.64
+5V_RUN on IN3 (solid shape): 18.4,71.83 18.4,70.81 18.38,70.81 18.27,70.7 17.44,70.7 17.25,70.89 17.25,71.74 17.41,71.89 18.33,71.89
+5V_RUN on IN3 (solid shape): 22.76,68.65 23.84,68.65 24.03,68.46 24.03,67.89 23.9,67.77 22.25,67.77 21.99,68.02 21.99,68.72 22.12,68.84 22.57,68.84
+5V_RUN on VCC: 203.14,57.35 202.25,58.24 171.52,58.24 169.67,60.08 156.59,60.08 151.83,64.84 58.57,64.84 58.06,64.34 55.14,64.34 54.63,64.84 34.48,64.84 34,65.33 34,66.37 143.72,66.37 144.36,67 152.26,67 156.76,62.49 162.14,62.49 162.77,61.86 237.37,61.86 248.22,72.72 263.08,72.72 265.31,74.94 268.29,74.94 268.82,75.47 268.82,77.31 272.69,81.19 272.69,90.14 273.31,90.75 275.99,90.75 275.99,81.02 275.3,80.32 275.3,78.98 273.2,76.89 273.2,69.52 271.44,67.77 259.61,67.77 257.96,69.42 249.79,69.42 245.03,64.65 243.82,64.65 243.1,63.93 243.1,62.6 242.4,61.9 242.4,61.86 242.34,61.8 242.34,60.4 239.29,57.35
+5V_RUN_AUDIO on TOP (solid shape): 265.9,64.08 265.56,63.75 264.27,63.75 263.72,64.3 262.9,64.3 262.82,64.38 262.82,65.51 262.88,65.57 264.29,65.57 264.95,66.23 265.89,66.23 265.9,66.24
+5V_RUN_AUDIO on TOP (solid shape): 248.05,59.89 248.05,57.29 249.07,56.27 249.83,56.27 249.9,56.21 249.9,54.81 248.88,54.81 246.98,56.72 245.13,56.72 244.63,57.22 242.05,57.22 241.9,57.38 241.9,59.21 242.02,59.33 242.51,59.33 242.51,58.8 243.02,58.8 243.02,59.33 243.31,59.33 243.31,58.8 243.82,58.8 243.82,59.33 246.73,59.33 246.85,59.45 246.85,59.89 246.98,60.02 247.93,60.02
+5V_RUN_AUDIO on IN1 (solid shape): outline of 779 points within 246.53,57.64 265.33,66.11
+5V_RUN_AUDIO on IN2 (solid shape): outline of 328 points within 246.78,57.67 265.28,65.72
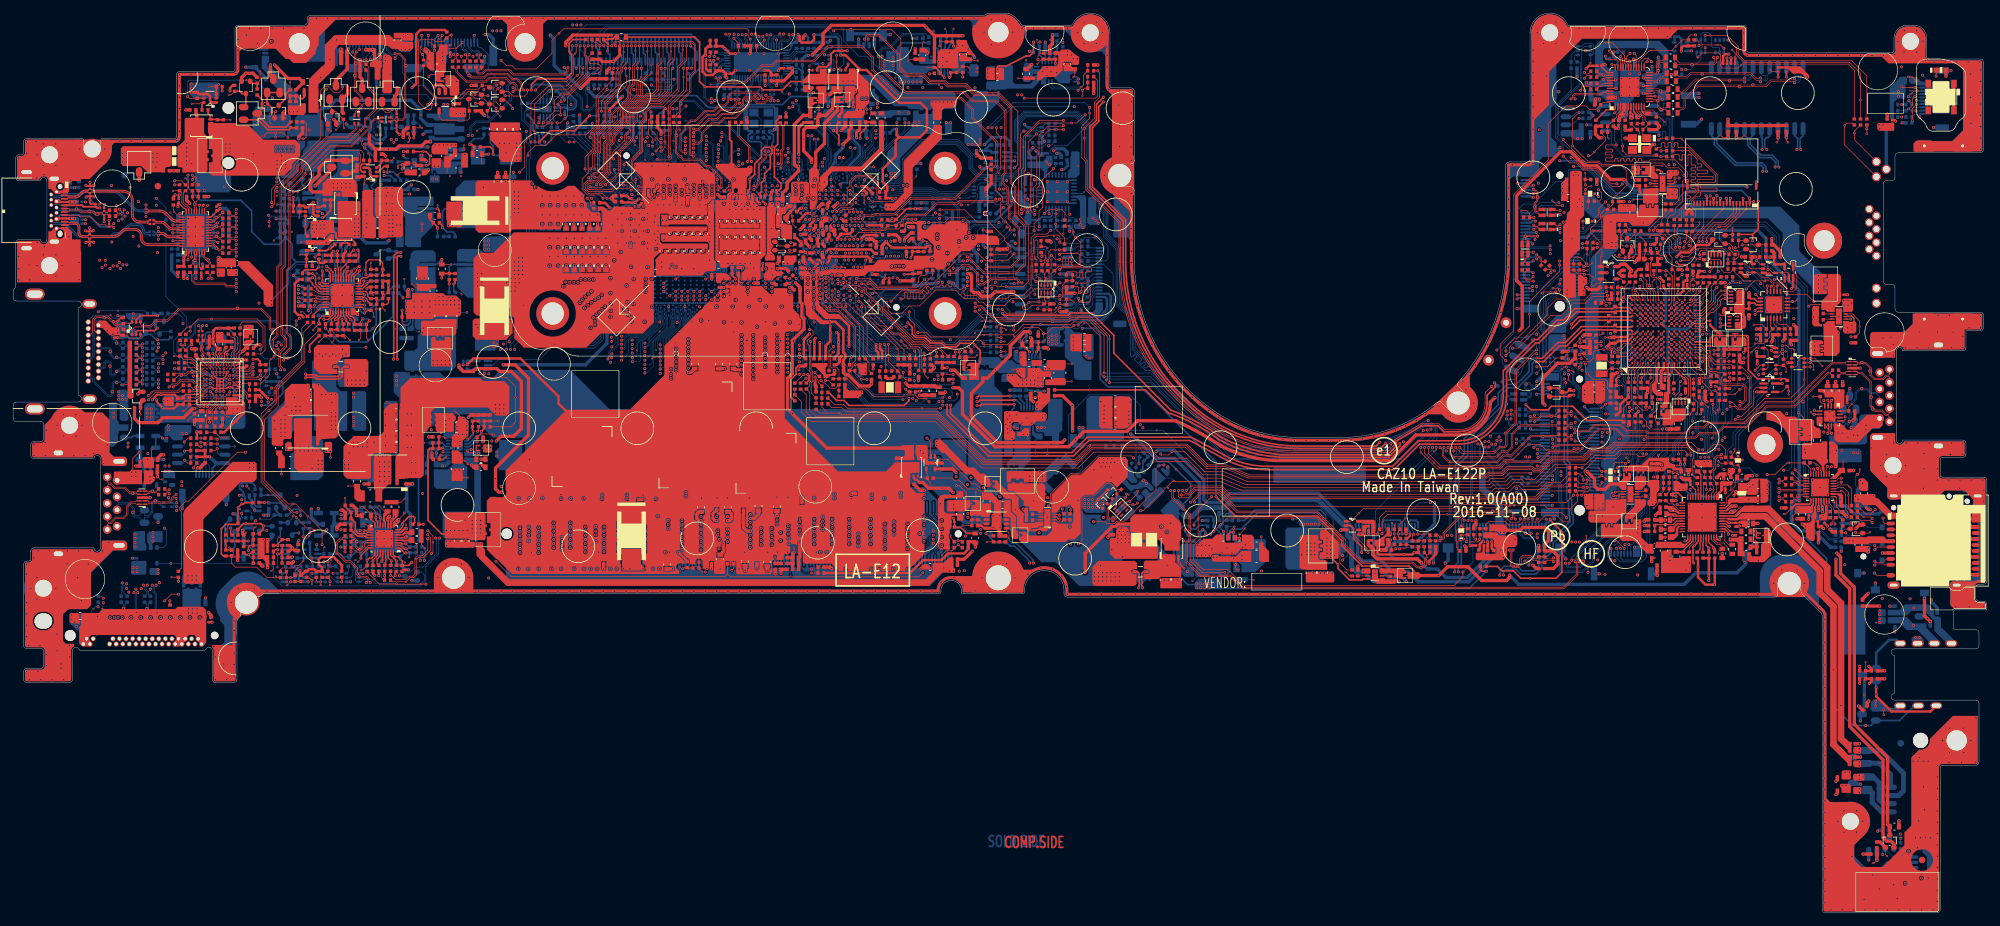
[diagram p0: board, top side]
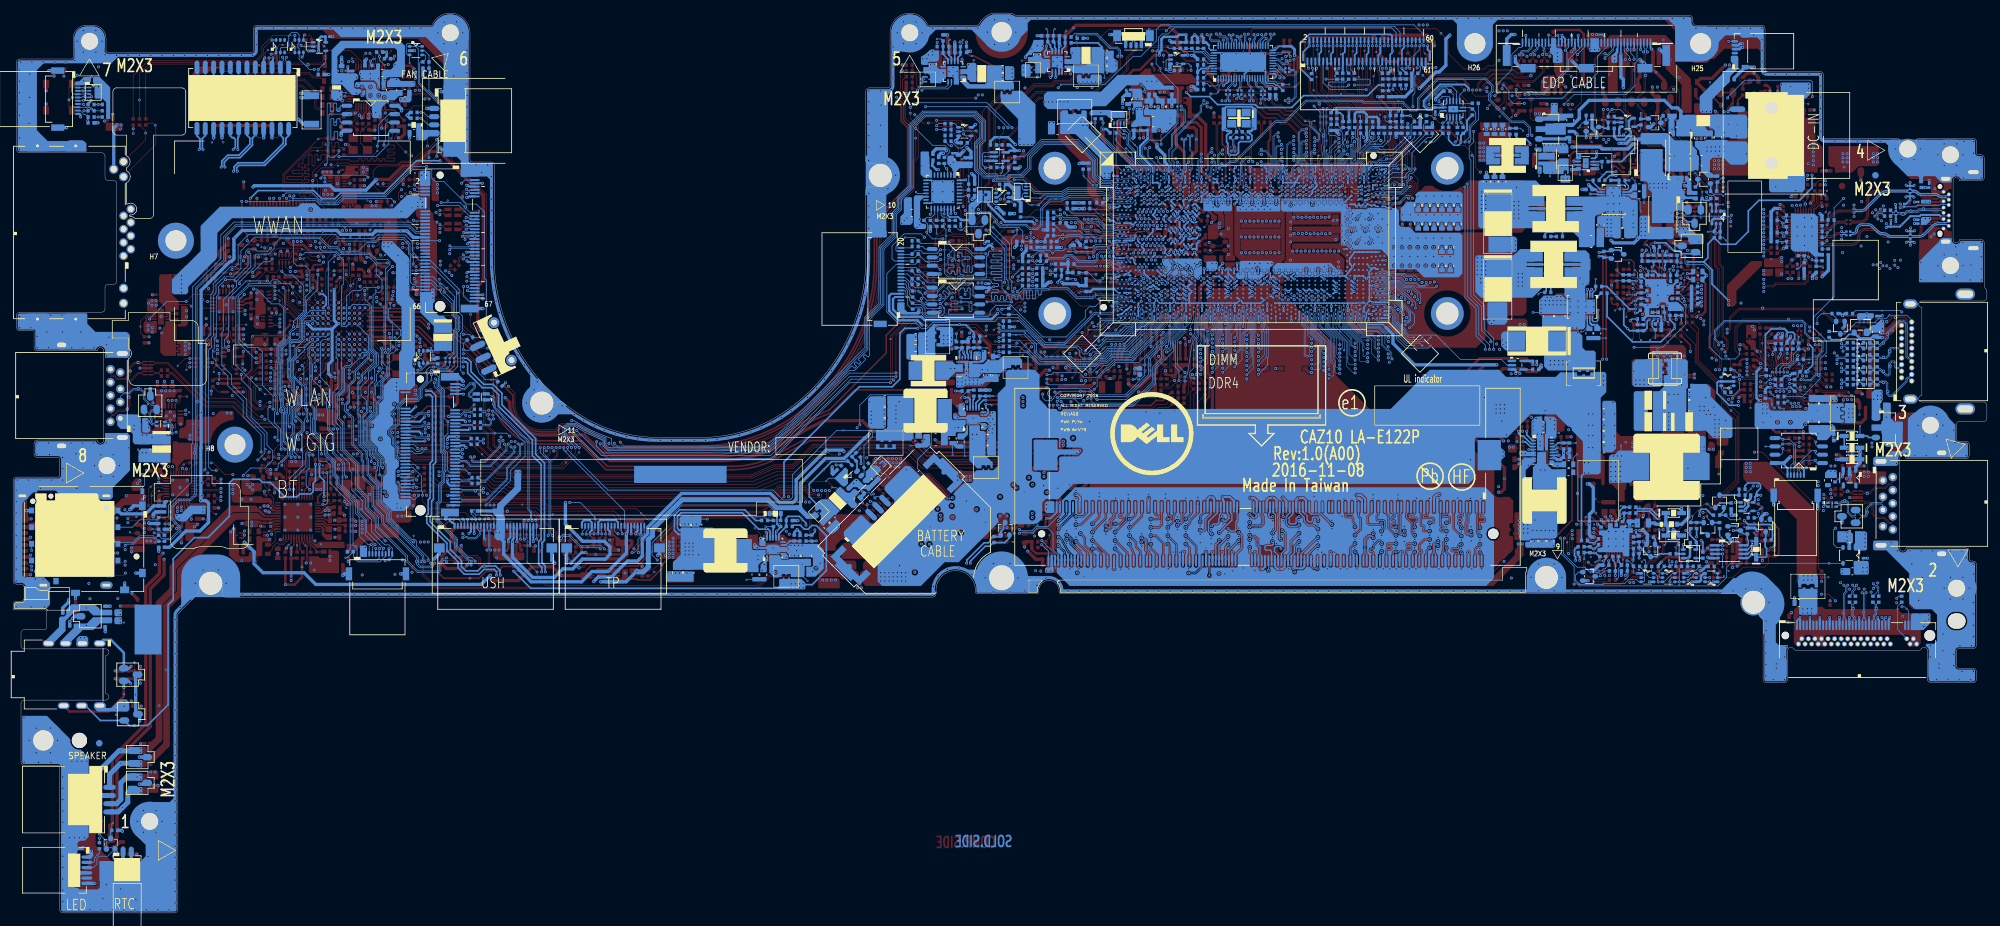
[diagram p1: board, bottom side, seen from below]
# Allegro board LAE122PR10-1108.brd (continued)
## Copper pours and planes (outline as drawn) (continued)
+5V_RUN_AUDIO_UZ5 on TOP (solid shape): 248.06,63.06 248.63,63.06 248.75,62.93 248.75,62.11 246.72,60.08 246.72,59.51 246.47,59.51 246.47,60.08 245.96,60.08 245.96,59.51 245.65,59.51 245.54,59.62 245.54,60.55 247.04,62.05 247.04,63.07 247.1,63.13 247.98,63.13
+5V_RUN_PVDD_L on TOP (solid shape): 266.04,63.36 266.04,62.8 265.78,62.55 261.8,62.55 260.88,61.63 259.99,61.63 259.94,61.68 259.94,61.78 259.99,61.83 260.78,61.83 261.21,62.27 261.21,62.9 261.57,63.26 262.63,63.26 262.86,63.49 265.91,63.49
+5V_RUN_PVDD_L on TOP (solid shape): 261.34,59.62 262.86,59.62 263.07,59.83 264.51,59.83 264.59,59.75 264.59,58.91 264.49,58.81 263.5,58.81 263.37,58.94 263.37,59.24 263.27,59.35 262.66,59.35 262.61,59.29 262.23,59.29 262.2,59.32 261.26,59.32 260.96,59.62 259.97,59.62 259.92,59.68 259.92,59.78 259.97,59.83 261.14,59.83
+5V_RUN_PVDD_L on IN2 (solid shape): 266.11,63.13 266.11,62.55 265,61.43 265,58.99 264.77,58.76 263.7,58.76 263.45,59.02 263.45,62.37 264.39,63.31 265.94,63.31
+5V_RUN_UZ4 on TOP (solid shape): 277.52,90.18 277.52,89.61 277.9,89.23 277.9,88.97 278.28,88.59 278.28,85.48 277.72,84.92 275.97,84.92 275.88,85.01 275.88,85.51 275.87,85.51 275.87,85.53 275.36,85.53 275.35,85.54 275.35,85.78 275.87,85.78 275.87,85.8 275.88,85.8 275.88,86.31 275.87,86.31 275.87,86.33 275.35,86.33 275.35,86.58 275.87,86.58 275.87,86.6 275.88,86.6 275.88,87.39 275.8,87.46 275.8,89.8 275.93,89.8 276.38,90.24 277.46,90.24
+5V_USB_CHG_PWR on TOP (solid shape): 284.96,75.58 284.96,75.12 284.82,74.98 284.82,74.37 284.38,73.92 283.3,73.92 281.14,71.77 277.9,71.77 277.46,72.21 277.46,73.54 277.39,73.61 277.39,74.59 277.47,74.66 278.43,74.66 279.44,73.66 280.11,73.66 280.13,73.67 280.29,73.76 280.38,73.92 280.38,73.93 282.41,75.96 284.58,75.96
+5V_USB_CHG_PWR on BOTTOM (solid shape): 284.96,75.63 284.96,75.14 284.82,75 284.82,74.31 284.31,73.8 283.23,73.8 282.47,73.04 282.47,71.77 282.15,71.45 276.72,71.45 276.69,71.47 276.69,72.72 276.74,72.77 277.33,72.77 277.33,72.78 277.96,73.42 278.92,73.42 279.3,73.04 280.82,73.04 280.83,73.04 280.98,73.04 281.27,73.33 281.27,75.64 281.63,76.01 284.58,76.01
+DV33_18 on TOP (solid shape): 278.81,63.69 278.81,61.79 278.49,61.79 278.18,62.1 278.18,63.46 277.91,63.74 277.89,63.76 276.91,63.76 276.84,63.83 276.84,63.93 276.91,63.99 278.51,63.99
+VBUS_DC_SS on TOP (solid shape): 52.92,108.35 52.92,103.1 52.73,102.91 51.84,102.91 51.71,103.03 49.53,103.03 49.53,105.7 49.45,105.78 49.45,108.55 52.73,108.55
+VBUS_DC_SS on BOTTOM (solid shape): 52.92,106.12 52.92,102.88 52.79,102.75 47.9,102.75 47.75,102.91 47.75,104.38 47.97,104.6 51.08,104.6 51.33,104.85 51.33,106.18 51.46,106.31 52.73,106.31
+VCC_CORE on TOP (solid shape): outline of 495 points within 106.98,96.43 114.65,114.46
+VCC_CORE on TOP (solid shape): outline of 498 points within 70.45,103.71 89.5,111.69
+VCC_CORE on BOTTOM (solid shape): 77.49,111.44 77.49,104.72 77.18,104.4 67.65,104.4 67.33,104.72 67.33,106.94 69.87,106.94 69.87,107.77 67.4,107.77 67.4,110.37 68.72,111.69 77.24,111.69
+VCC_CORE on BOTTOM (solid shape): outline of 368 points within 79.87,104.16 89.3,109.99
+VCC_CORE on BOTTOM (solid shape): outline of 386 points within 108.69,96.46 114.41,99.43
+VCC_CORE on BOTTOM (solid shape): outline of 554 points within 107.64,106.95 114.86,109.81
+VCC_CORE on IN1 (solid shape): outline of 494 points within 108.23,100.4 114.39,106.25
+VCC_CORE on VCC: 106.45,97.93 106.45,108.02 105.75,108.72 91.68,108.72 87.49,104.53 82.47,104.53 79.61,101.67 63.97,101.67 63.97,107.6 65.37,109 65.37,112.47 66.04,112.47 67.12,113.55 76.52,113.55 76.88,113.91 84.15,121.12 85.22,122.18 112.12,122.18 114.9,119.41 114.9,98.71 114.12,97.93
+VCC_CORE on IN2: 106.45,108.02 105.75,108.72 91.59,108.72 88.42,105.55 76.86,105.55 76.22,104.91 71.52,104.91 71.02,105.42 71.02,112.15 71.27,112.41 77.24,112.41 77.49,112.66 77.49,112.8 77.5,112.81 77.53,112.95 77.5,113.09 77.49,113.1 77.49,114.5 82.32,119.33 88.66,119.33 89.93,120.6 101.07,120.6 101.12,120.56 108.9,120.56 111.38,118.07 114.58,118.07 114.87,117.78 114.87,98.67 112.61,96.4 110.89,96.4 110.13,97.17 107.02,97.17 106.45,97.74
+VCC_CORE on IN3: outline of 185 points within 70.83,96.4 114.9,117.16
+VCC_GT on TOP (solid shape): outline of 4299 points within 70.13,86.18 106.98,114.44
+VCC_GT on BOTTOM (solid shape): 72.07,100.28 77.68,100.28 77.94,100.02 77.94,94.69 77.05,93.8 69.24,93.8 67.65,95.39 67.65,98.44 70.19,98.44 70.19,99.32 67.65,99.32 67.65,100.91 67.97,101.23 71.12,101.23
+VCC_GT on BOTTOM (solid shape): outline of 2394 points within 79.91,96.91 107.53,108.96
+VCC_GT on IN1: outline of 119 points within 74.94,92.47 105.94,106.68
+VCC_GT on VCC: 70,86.12 70,91.18 63.97,97.21 63.97,101.17 79.82,101.17 82.68,104.02 87.7,104.02 91.89,108.21 105.5,108.21 105.94,107.77 105.94,93.29 94.98,93.29 87.8,86.12
+VCC_GT on IN2: 73.75,94.37 73.54,94.58 73.54,100.47 74.22,101.14 79.82,101.14 82.7,104.02 87.72,104.02 91.88,108.18 105.53,108.18 105.94,107.77 105.94,97.69 105.62,97.38 90.68,97.38 89.46,98.6 89.46,98.62 89.37,98.94 89.05,99.04 89.02,99.04 88.73,99.32 82,99.32 81.72,99.05 81.71,99.04 81.5,98.94 81.39,98.73 81.39,98.72 77.05,94.37
+VCC_GT on IN3: 91.37,93.26 89.11,95.51 89.11,96.91 88.1,97.93 80.61,97.93 76.48,93.8 70.95,93.8 70.51,94.24 70.51,98.56 72.99,101.04 72.99,103.77 73.18,103.96 87.65,103.96 92.16,108.47 102.13,108.47 102.32,108.28 102.32,107.77 103.34,106.75 105.43,106.75 105.94,106.25 105.94,96.28 105.43,95.77 100.48,95.77 99.78,95.07 99.78,94.32 99.71,94.1 99.78,93.89 99.78,93.55 99.5,93.26
+VCC_GTUS on BOTTOM (solid shape): outline of 887 points within 98.32,96.96 108.79,99.1
+VCC_SA on TOP (solid shape): 77.47,118.83 77.47,114.67 77.3,114.5 74.51,114.5 74,115.01 74,116.53 72.67,117.87 72.67,119.07 72.69,119.1 77.2,119.1
+VCC_SA on TOP (solid shape): 119.31,99.34 118.75,98.79 117.31,98.79 117.18,98.92 117.18,99.2 117.41,99.43 117.41,100.07 117.58,100.24 119.31,100.24
+VCC_SA on TOP (solid shape): 116.79,108.26 116.79,108.19 116.88,108.1 116.88,108.01 116.87,107.91 116.88,107.81 116.88,107.71 117.03,107.56 117.15,107.56 117.23,107.55 117.34,107.56 117.37,107.58 117.48,107.66 117.55,107.77 117.56,107.78 117.85,108.08 118.66,108.08 118.75,107.99 118.75,107.66 118.53,107.45 118.09,107.45 117.8,107.15 117.8,106.82 117.54,106.57 117.3,106.57 117.12,106.39 117.12,105.34 117.31,105.15 117.72,105.15 117.93,104.94 118.49,104.94 118.69,104.74 118.69,102.75 118.64,102.7 117.4,102.7 117.03,103.07 117.03,104.13 116.89,104.27 116.88,104.28 116.73,104.44 116.3,104.44 116.17,104.56 116.17,106.39 116.35,106.57 116.35,107.66 116.12,107.89 116.12,108.3 116.25,108.42 116.63,108.42
+VCC_SA on BOTTOM (solid shape): 118.94,99.2 118.94,98.35 118.91,98.28 118.91,98.21 118.63,98.19 118.54,97.92 118.11,97.92 117.87,98.25 117.62,97.92 117.53,97.92 117.26,98.2 117.26,98.48 117.18,98.56 117.18,99.13 117.4,99.35 118.78,99.35
+VCC_SA on BOTTOM (solid shape): outline of 334 points within 114.92,107 119.38,109.81
+VCC_SA on BOTTOM: 74.06,113.8 77.43,113.8 77.81,114.18 77.81,118.44 77.15,119.1 73.34,119.1 73.32,119.07 73.32,117.98 73.81,117.49 73.81,114.06
+VCC_SA on VCC: 115.28,98.82 115.28,119.41 115.34,119.48 115.34,119.69 112.33,122.69 85.01,122.69 83.79,121.48 76.31,114.06 67.27,114.06 67.27,118.78 69.68,121.19 69.68,124.28 78.81,124.28 81.18,126.65 81.66,127.14 121.12,127.14 121.12,120.55 119.47,118.9 119.47,113.88 118.45,112.87 118.45,106.33 118.13,106.01 118.13,98.96 117.99,98.82 ; 1 cut-out
+VCC_SA on IN2: 117.22,98.77 116.28,99.71 116.28,103.18 116.34,103.28 116.45,103.26 117.01,103.5 116.45,103.74 116.34,103.72 116.28,103.81 116.28,109.87 116.91,109.87 117.14,109.64 117.14,109.08 118.13,108.09 118.13,98.96 117.94,98.77
+VCC_SFR_OC on TOP (solid shape): 137.25,71.26 137.25,69.16 137.12,69.04 134.33,69.04 134.33,69.54 134.39,69.61 135.66,69.61 135.85,69.8 135.85,70.41 135.63,70.62 135.15,70.62 135.15,71 135.47,71.32 137.18,71.32
+VCC_SFR_OC on IN2 (solid shape): 119.78,98.23 119.78,95.95 119.68,95.85 118.87,95.85 118.65,96.07 118.64,96.1 118.64,96.62 118.65,96.65 118.66,96.71 118.65,96.74 118.98,96.74 118.98,96.68 118.99,96.63 119.01,96.58 119.03,96.54 119.06,96.5 119.1,96.46 119.14,96.43 119.19,96.4 119.24,96.39 119.29,96.38 119.34,96.38 119.39,96.39 119.44,96.4 119.49,96.43 119.53,96.46 119.57,96.5 119.6,96.54 119.62,96.58 119.64,96.63 119.64,96.68 119.64,96.74 119.64,96.79 119.62,96.84 119.6,96.88 119.57,96.93 119.53,96.96 119.49,96.99 119.44,97.02 119.39,97.03 119.34,97.04 119.29,97.04 119.24,97.03 119.19,97.02 119.14,96.99 119.1,96.96 119.06,96.93 119.03,96.88 119.01,96.84 118.99,96.79 118.98,96.74 118.65,96.74 118.65,96.77 118.64,96.8 118.64,98.18 118.92,98.46 119.56,98.46
+VDDA_AVDD1 on TOP (solid shape): 254.4,56.3 254.86,56.3 254.91,56.35 254.99,56.35 255.01,56.32 255.01,56.14 254.51,55.64 250.28,55.64 250.21,55.7 250.21,56.45 250.37,56.6 254.1,56.6
+VSS_PLL on TOP (solid shape): 251.66,83.93 251.66,82.81 251.29,82.45 251.29,80.85 251.48,80.66 251.74,80.66 251.74,79.77 250.98,79.77 250.82,79.92 250.82,82.69 251.31,83.17 251.31,83.93 251.41,84.03 251.56,84.03
GND on TOP (solid shape): 68.41,104.72 68.22,104.53 66.25,104.53 66.06,104.72 66.06,107.96 68.41,107.96
GND on TOP (solid shape): 10.12,45.48 10.12,44.14 8.85,44.14 8.6,44.4 8.6,45.54 8.79,45.73 9.87,45.73
GND on TOP (solid shape): 24.47,78.56 24.47,77.29 23.2,77.29 22.85,77.64 22.85,78.46 23.07,78.69 24.34,78.69
GND on TOP (solid shape): 149.57,128.79 149.57,127.01 148.42,127.01 148.23,127.2 148.23,128.79 148.36,128.92 149.44,128.92
GND on TOP (solid shape): 236.94,108.72 236.75,108.53 235.86,108.53 235.86,111.26 236.43,111.83 236.43,112.09 236.94,112.09
GND on TOP (solid shape): 32.26,98.18 32.26,97.12 32.13,96.99 31.19,96.99 31.01,97.17 31.01,98.26 31.04,98.28 32.15,98.28
GND on TOP (solid shape): 154.63,61.71 154.63,59.62 154.13,59.62 154.13,61 153.69,61.43 153.69,61.66 153.82,61.78 154.56,61.78
GND on TOP (solid shape): 178.05,50.81 178.05,49.56 177.97,49.48 174.84,49.48 174.77,49.56 174.77,50.81 175.02,51.07 177.79,51.07
GND on TOP (solid shape): 201.29,51.73 201.29,50.56 201.1,50.37 197.12,50.37 196.92,50.57 196.92,51.81 197.1,51.99 201.03,51.99
GND on TOP (solid shape): 254.09,65.48 255.1,65.48 255.1,64.64 254.79,64.32 253.03,64.32 252.94,64.41 252.94,65.86 253.71,65.86
GND on TOP (solid shape): 258.85,68.97 258.85,67.96 256.63,67.96 256.18,68.4 256.18,69.04 257.44,69.04 257.5,69.1 258.72,69.1
GND on TOP (solid shape): 267.42,65.86 267.42,62.88 267.1,62.56 266.22,62.56 266.22,64.65 266.15,64.72 266.15,66.18 267.1,66.18
GND on TOP (solid shape): 21.36,66.62 21.61,66.37 21.61,65.99 20.98,65.35 19.9,65.35 19.9,67.38 19.96,67.45 21.36,67.45
GND on TOP (solid shape): 77.21,120.5 77.21,119.49 76.97,119.25 72.79,119.25 72.67,119.38 72.67,120.5 72.68,120.51 77.2,120.51
GND on TOP (solid shape): 282.63,65.61 282.63,64.48 282.52,64.37 281.45,64.37 281.13,64.68 281.13,66.08 281.31,66.26 281.98,66.26
GND on TOP (solid shape): 95.59,53.29 96.16,52.72 96.16,52.33 96.04,52.21 92.92,52.21 92.8,52.33 92.8,55.45 95.59,55.45
GND on TOP (solid shape): 170.38,78.37 170.38,74.66 169.58,73.86 167.92,73.86 167.73,74.05 167.73,78.43 168.04,78.75 170,78.75
GND on TOP (solid shape): 240.88,81.08 240.88,77.77 240.74,77.63 239.5,77.63 239.01,78.12 239.01,80.39 239.74,81.12 240.83,81.12
GND on TOP (solid shape): 247.29,107.83 247.29,107.14 247.04,106.88 244.59,106.88 244.48,107 244.48,107.92 244.64,108.09 247.04,108.09
GND on TOP (solid shape): 275.11,92.47 275.11,89.99 275.3,89.8 275.55,89.8 275.55,89.42 274.41,89.42 274.09,89.74 274.09,92.34 274.28,92.53 275.04,92.53
GND on TOP (solid shape): 61.01,133.97 61.01,133.15 60.88,133.02 59.37,133.02 59.03,133.36 58.09,133.36 57.97,133.48 57.97,134.08 58.09,134.2 60.78,134.2
GND on TOP (solid shape): 67.64,117.28 67.64,116.85 67.51,116.72 66.44,116.72 66.27,116.55 66.27,115.66 63.98,115.66 63.78,115.86 63.78,116.97 64.22,117.41 67.51,117.41
GND on TOP (solid shape): 76.1,90.43 76.1,88.4 75.08,87.39 70.57,87.39 70,87.96 70,90.31 70.32,90.63 75.91,90.63
GND on TOP (solid shape): 126.96,80.02 127.21,79.77 127.23,79.77 127.33,79.67 129.35,79.67 129.47,79.54 129.47,79.13 128.84,78.5 126.45,78.5 126.45,80.72 126.96,80.72
GND on TOP (solid shape): 207.86,51.19 208.05,51 208.94,51 209.07,50.87 210.78,50.87 210.78,50.43 210.53,50.18 207.73,50.18 207.03,50.87 207.03,52.33 207.86,52.33
GND on TOP (solid shape): 50.32,131.77 50.32,129.36 50.25,129.3 49.74,129.3 49.62,129.42 49.62,131.77 49.81,131.96 50.13,131.96
GND on TOP (solid shape): 130.07,82.05 129.99,81.97 129.6,81.97 129.6,81.97 129.21,81.97 128.86,82.33 128.86,82.94 128.62,83.18 128.62,83.72 128.67,83.77 130.07,83.77
GND on TOP (solid shape): 164.29,88.23 164.29,85.74 164.21,85.66 163.1,85.66 162.99,85.77 162.99,88.1 163.17,88.28 164.23,88.28
GND on TOP (solid shape): 278,71.21 278,68.01 277.76,67.76 277.52,67.76 277.38,67.9 277.38,68.32 277.14,68.56 276.79,68.56 276.68,68.68 276.68,71.82 276.75,71.9 277.31,71.9
GND on TOP (solid shape): 32.03,88.47 32.03,87.58 32.22,87.39 33.58,87.39 33.58,86.9 31.05,86.9 30.88,87.07 30.88,88.47 31.01,88.59 31.9,88.59
GND on TOP (solid shape): 69.68,56.59 70.25,56.59 70.32,56.53 70.32,55.83 70.19,55.7 66,55.7 65.78,55.92 65.78,56.81 65.89,56.91 69.37,56.91
GND on TOP (solid shape): 273.65,127.71 273.65,127.33 273.52,127.2 273.2,127.2 272.44,127.96 271.11,127.96 270.34,128.73 268.69,128.73 268.69,129.04 268.76,129.11 272.25,129.11
GND on TOP (solid shape): 63.82,131.2 64.07,131.2 64.16,131.11 64.16,128.47 63.52,128.47 62.97,129.02 62.97,130.88 62.47,131.38 62.47,131.79 62.63,131.95 63.07,131.95
GND on TOP (solid shape): 126.39,125.93 126.39,125.11 126.26,124.98 126.26,124.98 126.19,124.91 124.98,124.91 124.61,124.53 124.17,124.53 124.17,124.98 124.67,125.49 124.67,126.06 126.26,126.06
GND on TOP (solid shape): 38.33,57.01 38.33,54.65 38.45,54.52 39.01,54.52 39.01,52.54 38.89,52.41 38.61,52.41 38.5,52.51 38.5,53.48 38.02,53.96 37.29,53.96 37.26,53.99 37.26,57.19 38.15,57.19
GND on TOP (solid shape): 121.5,126.06 121.86,126.06 121.94,125.97 121.94,125.61 121.44,125.11 120.55,125.11 120.31,125.34 120.31,126.13 120.43,126.25 120.48,126.25 121.31,126.25
GND on TOP (solid shape): 239.22,97.01 239.63,97.01 239.82,96.82 239.82,96.01 239.36,95.55 239.36,95.2 239.55,95.01 239.55,94.18 239.42,94.05 238.47,94.05 238.4,94.12 238.4,97.29 238.94,97.29
GND on TOP (solid shape): 139.34,71.13 139.34,69.04 139.53,68.84 139.53,68.34 139.03,68.34 138.33,69.04 137.82,69.04 137.69,69.16 137.69,69.61 137.5,69.8 137.5,71.26 137.6,71.35 139.12,71.35
GND on TOP (solid shape): 158.01,58.81 157.38,58.18 156.67,58.18 156.51,58.33 156.13,58.33 155.98,58.18 155.32,58.18 155.32,58.53 156.08,58.53 156.41,58.86 156.97,58.86 157.12,59.02 157.12,60.77 158.01,60.77
GND on TOP (solid shape): 244.61,82.46 244.61,82.29 244.52,82.21 244.49,82.21 244.31,82.03 244.21,82.03 243.77,81.6 243.77,80.92 243.71,80.92 243.71,80.12 243.2,80.12 243.2,82.26 243.35,82.41 244,82.41 244.21,82.62 244.45,82.62
GND on TOP (solid shape): 250.79,65.99 250.79,64.46 250.4,64.08 250.4,62.53 249.91,62.04 249.2,62.04 249.01,62.23 249.01,62.81 249.39,63.19 249.39,64.78 249.01,65.16 249.01,65.73 249.32,66.05 250.72,66.05
GND on TOP (solid shape): 267.8,58.24 267.8,54.49 266.79,53.48 264.5,53.48 264.18,53.8 264.18,55 264.76,55 264.76,54.56 264.95,54.37 266.09,54.37 266.28,54.56 266.28,56.14 266.72,56.59 266.72,58.68 266.85,58.81 267.23,58.81
GND on TOP (solid shape): 210.03,57.01 210.03,56.73 209.85,56.55 209.85,55.92 209.65,55.92 209.45,55.71 209.45,55.15 209.35,55.05 208.3,55.05 208.2,55.15 208.2,55.56 208.3,55.66 208.89,55.66 209.22,55.99 209.22,56.68 209.12,56.78 209.12,57.11 209.93,57.11
GND on TOP (solid shape): 68.92,75.45 68.92,75.39 69.37,74.94 69.37,72.88 68.44,71.96 68.44,71.22 68.22,71 66.95,71 66.83,71.13 66.83,72.65 67.4,73.23 67.4,74.81 67.78,75.19 67.78,75.64 68.73,75.64
GND on TOP (solid shape): 206.72,59.15 206.72,58.76 206.28,58.76 206.14,58.62 206.14,57.61 205.95,57.41 204.87,57.41 204.75,57.54 204.75,57.86 204.87,57.99 205.41,57.99 205.56,58.14 205.56,59.04 205.69,59.17 206.7,59.17
GND on TOP (solid shape): 240.72,63.79 240.72,61.55 240.67,61.5 239.74,61.5 239.69,61.54 239.69,61.56 239.57,61.91 239.34,62.2 239.34,63.76 239.5,63.92 240.59,63.92
GND on TOP (solid shape): 58.57,70.43 58.23,70.09 55.05,70.09 54.51,69.54 54.51,66.37 54.32,66.18 50.89,66.18 50.32,66.75 50.32,71.13 51.9,72.72 55.78,72.72 56.48,73.42 56.48,76.72 57.43,77.67 58.57,77.67
GND on TOP (solid shape): 282.92,55.76 282.92,54.94 282.74,54.76 282.46,54.76 282.16,54.99 281.79,55.03 281.76,55.03 280.71,55.03 280.65,55.09 280.65,55.84 280.76,55.95 282.73,55.95
GND on TOP (solid shape): 59.41,110.4 59.41,103.36 59.06,103.01 56.99,103.01 56.86,102.88 55.84,102.88 55.65,103.07 55.65,105.87 55.15,106.37 55.15,109.55 55.14,109.56 55.14,110.37 55.47,110.7 59.1,110.7
GND on TOP (solid shape): 124.04,83.39 123.79,83.13 123.79,82.31 123.91,82.18 124.67,82.18 124.86,82.37 124.86,82.81 124.99,82.94 125.25,82.94 125.44,82.75 125.44,82.12 125.18,81.86 124.48,81.86 124.17,81.54 123.53,81.54 123.47,81.61 123.47,81.99 122.2,83.26 121.75,83.26 121.69,83.32 121.69,83.77 121.75,83.83 124.04,83.83
GND on TOP (solid shape): 156.92,82.56 158.14,82.56 158.14,81.8 158.04,81.7 157.25,81.7 157.05,81.49 157.05,80.27 156.92,80.15 152.52,80.15 151.35,81.32 151.35,82.08 151.5,82.23 152.75,82.23 153.53,81.46 154.25,81.46 154.29,81.46 154.57,81.74 154.57,83.03 154.64,83.1 156.38,83.1
GND on TOP (solid shape): 45.17,80.59 45.17,79.96 45.55,79.58 45.55,75.89 45.43,75.77 42.76,75.77 42.44,75.45 42.44,72.46 42.25,72.27 41.36,72.27 41.17,72.08 41.17,71.38 41.04,71.26 39.58,71.26 39.39,71.45 39.39,75.58 41.36,77.54 41.36,79.64 42.38,80.66 45.11,80.66
GND on TOP (solid shape): 65.89,94.13 67.5,94.13 68.22,93.41 68.22,91.22 67.94,90.94 64.29,90.94 63.9,90.56 59.97,90.56 59.84,90.69 59.84,93.36 59.97,93.48 60.6,93.48 60.79,93.67 60.79,94.37 60.92,94.5 65.52,94.5
GND on TOP (solid shape): 153.22,76.34 157.19,76.34 157.44,76.08 157.44,75.26 157.12,74.94 155.85,74.94 155.22,74.31 153.63,74.31 153.12,74.81 152.3,74.81 152.11,74.62 152.11,73.8 152.61,73.29 152.61,72.29 152.42,72.1 151.2,72.1 150.96,72.34 150.96,76.35 151.13,76.52 153.05,76.52
GND on TOP (solid shape): 184.5,57.52 184.5,56.68 184.72,56.46 187.01,56.46 187.22,56.68 187.22,57.64 187.25,57.67 188.67,57.67 189.05,57.29 189.05,56.46 189.06,56.46 189.06,55.51 189,55.45 187.03,55.45 186.21,54.62 184.05,54.62 183.89,54.77 182.83,54.77 182.29,54.24 180.31,54.24 180.16,54.39 180.16,55.88 181.34,57.06 182.68,57.06 183.28,57.67 184.35,57.67
GND on TOP (solid shape): 145.23,133.11 145.78,131.75 146.71,130.6 146.71,130.31 146.65,130.25 146.33,130.25 146.2,130.38 146.2,130.57 145.95,130.82 145.5,130.82 145.5,131.01 145.25,131.27 144.17,131.27 143.98,131.07 143.98,128.79 141.12,128.79 140.87,129.04 140.87,131.27 141.31,131.71 143.34,131.71 143.72,132.09 143.72,133.11
GND on TOP (solid shape): 150.18,62.94 150.42,62.94 150.54,62.81 150.54,58.02 150.82,57.75 151.43,57.75 151.43,57.24 149.99,57.24 149.99,58.2 149.76,58.43 147.9,58.43 147.73,58.6 147.73,58.61 147.53,58.8 147.26,58.79 147.25,58.79 146.66,58.79 146.66,59.32 146.68,59.35 147.47,59.35 147.93,58.89 148.92,58.89 149.1,59.07 149.1,60.74 149.45,61.1 149.45,62.3 148.78,62.98 147.7,62.98 147.57,63.1 147.57,64.12 148.99,64.12
GND on TOP (solid shape): 55.33,131.71 55.33,130.38 55.33,130.33 55.66,130 56.13,130 56.17,129.95 56.17,128.93 55.96,128.72 55.96,127.12 55.87,127.03 55.17,127.03 55.08,127.12 55.08,128.85 54.94,128.99 54.45,128.99 54.38,129.06 54.38,129.7 54.44,129.77 54.55,129.77 54.57,129.8 54.58,129.8 54.68,129.87 54.75,129.97 54.76,129.98 54.8,130.02 54.8,131.08 54.57,131.31 53.59,131.31 53.45,131.44 53.45,131.74 53.62,131.9 55.14,131.9
GND on TOP (solid shape): 115.9,108.27 115.9,107.86 116.22,107.54 116.22,106.6 116.07,106.44 116.07,104.39 116.26,104.19 116.72,104.19 116.91,104 116.91,103.93 116.91,103.93 116.91,103.27 116.5,102.86 115.64,102.86 115.48,102.7 115.48,102.15 115.82,101.82 115.82,101.57 115.46,101.21 115.46,100.81 116.02,100.25 116.02,99.56 115.94,99.48 114.6,99.48 114.53,99.55 114.53,100.04 114.81,100.32 114.81,107.7 115.04,107.93 115.04,108.19 115.21,108.37 115.8,108.37
GND on TOP (solid shape): 108.1,105.61 108.1,105.23 108.23,105.1 108.74,105.1 108.86,105.23 108.86,105.61 108.99,105.74 109.24,105.74 109.37,105.61 109.37,105.23 109.5,105.1 110.01,105.1 110.13,105.23 110.13,105.61 110.26,105.74 110.51,105.74 110.64,105.61 110.64,105.23 110.77,105.1 111.28,105.1 111.4,105.23 111.4,105.61 111.53,105.74 111.78,105.74 111.91,105.61 111.91,105.23 112.04,105.1 112.55,105.1 112.67,105.23 112.67,105.61 112.8,105.74 113.05,105.74 113.18,105.61 113.18,105.23 113.31,105.1 113.69,105.1 113.69,104.47 107.72,104.47 107.72,105.1 107.59,105.23 107.59,105.61 107.72,105.74 107.97,105.74
GND on TOP (solid shape): 161.19,131.39 161.22,131.39 161.67,131 162.17,130.68 162.28,130.62 162.39,130.5 162.39,129.49 162.2,129.3 161.44,129.3 161.38,129.36 161.38,129.55 161.12,129.8 160.17,129.8 159.92,129.55 159.92,128.53 158.84,127.46 157.04,127.46 156.52,126.93 156.07,126.93 155.97,127.03 155.97,128.1 156.98,129.11 158.84,129.11 159.22,129.49 159.22,130.69 159.09,130.82 158.52,130.82 158.52,131.33 158.58,131.39 159.47,131.39 159.73,131.65 160.93,131.65
GND on TOP (solid shape): 226.43,57.54 227.58,57.54 227.76,57.72 228.71,57.72 229.1,57.33 229.1,57.33 229.18,57.24 229.18,56.17 229.1,56.08 229.1,56.04 228.84,55.78 227.76,55.78 227.58,55.61 227.58,55.41 227.57,55.33 227.58,55.25 227.58,54.34 226.99,53.75 222.99,53.75 222.83,53.91 222.83,54.84 222.93,54.94 223.7,54.94 223.85,55.09 223.85,56.17 223.91,56.24 223.99,56.23 224.05,56.24 224.26,56.24 224.29,56.21 224.29,55.73 224.2,55.64 224.2,54.89 224.34,54.75 225.86,54.75 225.99,54.88 225.99,55.65 225.86,55.78 225.65,55.78 225.62,55.82 225.62,56.79 225.29,57.11 224.09,57.11 223.98,57.23 223.98,57.92 224.09,58.03 225.95,58.03
GND on TOP (solid shape): 108.1,103.2 108.1,102.82 108.23,102.69 108.74,102.69 108.86,102.82 108.86,103.2 108.99,103.33 109.24,103.33 109.37,103.2 109.37,102.82 109.5,102.69 110.01,102.69 110.13,102.82 110.13,103.2 110.26,103.33 110.51,103.33 110.64,103.2 110.64,102.82 110.77,102.69 111.28,102.69 111.4,102.82 111.4,103.2 111.53,103.33 111.78,103.33 111.91,103.2 111.91,102.82 112.04,102.69 112.55,102.69 112.67,102.82 112.67,103.2 112.8,103.33 113.05,103.33 113.18,103.2 113.18,102.82 113.31,102.69 113.69,102.69 113.69,101.04 113.31,101.04 113.18,100.91 113.18,100.53 113.05,100.4 112.8,100.4 112.67,100.53 112.67,100.91 112.55,101.04 112.04,101.04 111.91,100.91 111.91,100.53 111.78,100.4 111.53,100.4 111.4,100.53 111.4,100.91 111.28,101.04 110.77,101.04 110.64,100.91 110.64,100.53 110.51,100.4 110.26,100.4 110.13,100.53 110.13,100.91 110.01,101.04 109.5,101.04 109.37,100.91 109.37,100.53 109.24,100.4 108.99,100.4 108.86,100.53 108.86,100.91 108.74,101.04 108.23,101.04 108.1,100.91 108.1,100.53 107.97,100.4 107.72,100.4 107.59,100.53 107.59,103.2 107.72,103.33 107.97,103.33
GND on TOP (solid shape): 299.7,91.39 299.91,91.31 299.99,91.1 299.99,89.25 299.91,89.04 299.7,88.96 297.31,88.96 297.31,86.2 297.22,85.99 297.01,85.91 288.08,85.91 288.06,85.94 287.28,86.4 286.69,85.7 286.69,84.66 283.23,84.66 282.92,84.97 282.92,88.27 283.21,88.56 288.14,88.56 289.41,89.83 289.41,91.34 289.46,91.39
GND on TOP (solid shape): 14.7,75.2 14.7,70.18 15.32,69.56 17.02,69.56 17.34,69.24 17.34,68.44 17.07,68.17 13.73,68.17 13.5,68.4 13.5,69.25 13.5,69.35 13.48,69.44 13.4,69.61 13.29,69.75 13.03,69.91 12.73,69.95 12.35,69.79 12.13,69.45 3.18,69.45 2.98,69.54 2.89,69.75 2.89,71.4 2.98,71.61 3.18,71.7 4.3,71.7 4.56,71.77 4.75,71.97 4.79,72.08 4.8,72.2 4.8,74.45 6.67,76.32 13.58,76.32
GND on TOP (solid shape): 34.12,44.72 33.48,49.52 38.25,48.65 38.17,48.65 38.06,48.63 37.96,48.56 37.74,48.34
GND on TOP (solid shape): 146.1,51.01 149.97,55.1 154.1,51.27 154.1,51.14 154.1,50.32 153.95,49.77 153.9,49.2 153.9,48.95 153.87,48.88 153.8,48.85 146.1,48.85
GND on TOP (solid shape): outline of 116 points within 0.61,96.16 10.37,104.66
GND on TOP (solid shape): 10.3,96.2 0.6,96.2 0.6,100.33 0.62,100.38 0.65,100.42 0.94,100.29 1.25,100.24 2.55,100.24 3.63,101.12 2.99,102.36 3.02,102.44 3.09,102.47 3.98,102.47 3.99,102.44 4.31,102.06 4.8,101.99 5.2,101.45 5.84,101.24 6.71,101.24 7.59,101.69 7.76,102.67 7.8,102.69 7.84,102.7 10.3,102.7
GND on TOP (solid shape): 10.3,117.9 10.3,111.6 7.84,111.6 7.8,111.61 7.76,111.63 7.59,112.61 6.71,113.06 5.84,113.06 5.2,112.85 4.8,112.31 4.31,112.24 3.99,111.86 3.98,111.83 3.09,111.83 3.02,111.86 2.99,111.94 3.63,113.18 2.55,114.06 1.25,114.06 0.94,114.01 0.65,113.88 0.62,113.92 0.6,113.97 0.6,115.1 0.69,115.31 0.9,115.4 1.3,115.4 1.66,115.54 1.8,115.9 1.8,117.6 1.89,117.81 2.1,117.9 4.56,117.9 6.54,117.9
GND on TOP (solid shape): 286.69,72.1 287.28,71.4 288.06,71.86 288.08,71.89 297.01,71.89 297.22,71.81 297.31,71.6 297.31,69.95 297.22,69.74 297.01,69.66 293.9,69.66 293.54,69.51 293.39,69.15 293.39,66.75 293.54,66.39 293.9,66.24 300.2,66.24 300.41,66.16 300.49,65.95 300.49,50.63 300.41,50.42 300.2,50.34 299.5,50.34 299,50.13 298.79,49.63 298.79,48.03 299,47.53 299.5,47.32 300.2,47.32 300.41,47.24 300.49,47.03 300.49,46.41 295.9,46.41 295.85,46.4 295.64,46.4 295.17,46.87 295.17,46.88 295.14,46.91 295.14,50.25 295.44,50.55 298.79,50.55 299.12,50.73 299.5,50.79 300.04,50.79 300.04,59.32 299.79,59.57 298.41,59.57 298.41,61.42 298.6,61.61 298.6,63.07 297.27,64.4 294.22,64.4 292.89,63.07 285.84,63.07 285.52,63.38 285.52,64.84 282.92,67.45 282.92,72.78 283.3,73.16 286.69,73.16
GND on TOP (solid shape): outline of 236 points within 140.92,55.41 144.75,64.27
GND on TOP (solid shape): outline of 234 points within 97.88,97.17 107.08,108.67
GND on TOP (solid shape): outline of 263 points within 1.81,35.31 17.37,56.77
GND on TOP (solid shape): outline of 768 points within 30.32,0.21 299.29,53.66
GND on TOP (solid shape): outline of 1292 points within 0.61,71.84 299.99,136.99
GND on BOTTOM (solid shape): 149.57,127.01 148.36,127.01 148.17,127.2 148.17,128.85 148.42,129.11 149.57,129.11
GND on BOTTOM (solid shape): 24.66,67.13 24.66,66.3 22.95,66.3 22.88,66.37 22.88,67.38 23.07,67.57 24.22,67.57
GND on BOTTOM (solid shape): 236.57,88.1 236.57,85.71 233.91,85.71 233.88,85.74 233.88,87.92 234.19,88.23 236.45,88.23
GND on BOTTOM (solid shape): 11.58,45.41 11.58,43.19 11.52,43.13 9.68,43.13 8.6,44.21 8.6,45.54 8.72,45.67 11.33,45.67
GND on BOTTOM (solid shape): 22.31,52.46 22.31,51.7 22.12,51.51 20.92,51.51 20.79,51.64 20.79,52.46 20.92,52.59 22.19,52.59
GND on BOTTOM (solid shape): 27.13,78.9 27.13,78.07 26.95,77.89 22.91,77.89 22.76,78.04 22.76,78.57 23.14,78.95 27.07,78.95
GND on BOTTOM (solid shape): 76.1,92.91 76.1,90.05 75.72,89.67 73.49,89.67 73.05,90.12 73.05,92.97 73.18,93.1 75.91,93.1
GND on BOTTOM (solid shape): 112.02,122.73 112.02,119.46 111.91,119.36 111.38,119.36 111.24,119.5 111.24,122.55 111.47,122.78 111.97,122.78
GND on BOTTOM (solid shape): 143.05,120.56 143.05,118.77 142.98,118.7 142.1,118.7 141.97,118.83 141.97,120.68 142.92,120.68
GND on BOTTOM (solid shape): 164.62,88.1 164.62,84.57 164.41,84.36 163.63,84.36 162.99,85 162.99,88.17 163.09,88.28 164.44,88.28
GND on BOTTOM (solid shape): 176.86,58.53 176.86,58.38 176.3,57.82 175.66,57.82 174.73,58.76 174.73,59.42 175.31,60.01 175.39,60.01
GND on BOTTOM (solid shape): 199.19,60.25 199.19,59.08 198.98,58.88 196.24,58.88 195.86,59.26 195.86,60.46 198.97,60.46
GND on BOTTOM (solid shape): 281.58,70.43 281.58,68.78 281.52,68.72 276.88,68.72 276.82,68.78 276.82,70.43 277.2,70.81 281.2,70.81
GND on BOTTOM (solid shape): 74,88.28 74,86.43 73.3,85.74 70.38,85.74 70.38,88.59 70.45,88.66 73.62,88.66
GND on BOTTOM (solid shape): 75.91,100.72 71.88,100.72 71.58,101.03 71.58,102.8 71.91,103.13 75.91,103.13
GND on BOTTOM (solid shape): 8.51,38.64 8.51,36.4 8.41,36.3 7.22,36.3 7.07,36.45 7.07,38.49 7.27,38.69 8.46,38.69
GND on BOTTOM (solid shape): 32.31,38.49 32.31,36.46 32.15,36.31 30.96,36.31 30.86,36.41 30.86,38.64 30.91,38.7 32.1,38.7
GND on BOTTOM (solid shape): 33.2,112.84 33.2,110.2 32.87,109.87 28.14,109.87 27.71,110.3 27.71,112.86 27.89,113.04 32.99,113.04
GND on BOTTOM (solid shape): 53.81,79.32 53.81,73.73 53.62,73.54 51.97,73.54 51.65,73.86 51.65,79.39 51.78,79.51 53.62,79.51
GND on BOTTOM (solid shape): 77.56,67.52 74.06,67.52 73.98,67.61 73.98,69.03 73.46,69.56 73.46,70.37 74.09,71 74.09,72.07 77.56,72.07
GND on BOTTOM (solid shape): 116.58,122.74 116.58,119.38 116.4,119.2 115.87,119.2 115.72,119.35 115.72,119.47 115.88,119.63 115.88,122.7 116.04,122.86 116.45,122.86
GND on BOTTOM (solid shape): 134.33,131.27 134.33,128.41 134.07,128.15 132.87,128.15 132.42,128.6 132.42,129.8 133.06,130.44 133.06,131.46 134.14,131.46
GND on BOTTOM (solid shape): 163.22,74.12 163.22,72.34 162.33,72.34 162.27,72.4 162.27,73.54 162.14,73.67 162.14,74.05 162.33,74.24 163.09,74.24
GND on BOTTOM (solid shape): 243.71,126.73 243.71,125.97 243.69,125.94 239.67,125.94 239.42,126.2 239.42,126.73 239.55,126.86 241.63,126.86 242.06,127.29 243.15,127.29
GND on BOTTOM (solid shape): 29.87,101.23 29.49,100.85 27.07,100.85 26.31,100.09 24.85,100.09 24.85,100.66 25.55,100.66 25.74,100.85 25.74,106.12 26.25,106.63 29.87,106.63
GND on BOTTOM (solid shape): 158.33,127.46 157.57,127.46 157.38,127.26 157.38,126.38 157.31,126.31 156.68,126.31 156.61,126.38 156.61,127.26 156.68,127.33 156.68,129.11 158.33,129.11
GND on BOTTOM (solid shape): 170.46,78.4 170.46,74.26 170.05,73.85 168.12,73.85 167.73,74.24 167.73,78.56 167.92,78.75 170.1,78.75
GND on BOTTOM (solid shape): 201.22,51.88 201.22,50.72 200.99,50.49 197.06,50.49 197.06,51.89 197.25,52.08 201.01,52.08
GND on BOTTOM (solid shape): 67.64,117.23 67.64,116.17 67.54,116.06 65.33,116.06 65.15,115.89 63.78,115.89 63.78,116.98 64.22,117.42 67.45,117.42
GND on BOTTOM (solid shape): 130.71,125.3 130.26,125.3 130.17,125.2 130.17,124.07 130.02,123.92 128.82,123.92 128.67,124.07 128.67,125.42 128.93,125.68 130.71,125.68
GND on BOTTOM (solid shape): 165.01,108.82 165.01,106.69 165.53,106.17 165.53,105.04 165.39,104.9 163.98,104.9 163.64,105.24 163.64,106.04 163.78,106.18 163.78,108.99 163.92,109.13 164.7,109.13
GND on BOTTOM (solid shape): 281.04,75.37 281.04,73.4 280.87,73.24 280.07,73.24 279.79,73.52 279.79,74.14 279.87,74.22 279.87,74.23 280.08,74.44 280.08,75.34 280.19,75.45 280.96,75.45
GND on BOTTOM (solid shape): 22.76,56.53 21.49,56.53 21.23,56.27 21.23,55.45 21.11,55.32 20.79,55.32 20.66,55.45 20.66,56.27 20.41,56.53 20.41,57.8 20.79,58.18 22.76,58.18
GND on BOTTOM (solid shape): 58.57,77.91 58.57,70.43 58.38,70.24 57.05,70.24 56.48,70.81 56.48,77.76 56.8,78.08 58.4,78.08
GND on BOTTOM (solid shape): 65.8,94.12 67.52,94.12 68.24,93.4 68.24,91.4 68.17,91.32 59.71,91.32 59.71,93.48 64.03,93.48 64.79,94.24 65.68,94.24
GND on BOTTOM (solid shape): 69.68,56.59 70.25,56.59 70.32,56.53 70.32,55.83 70.19,55.7 65.92,55.7 65.78,55.84 65.78,56.81 65.89,56.91 69.37,56.91
GND on BOTTOM (solid shape): 23.84,74.37 27.07,74.37 27.14,74.31 27.14,73.29 26.76,72.91 26.15,72.91 25.87,72.63 25.87,72.27 25.68,72.08 24.41,72.08 23.65,72.85 23.07,72.85 23.07,74.12 23.46,74.5 23.71,74.5
GND on BOTTOM (solid shape): 31.44,126.48 31.44,124.42 31.22,124.19 27.53,124.19 26.82,124.9 26.82,126.5 26.95,126.63 31.29,126.63
GND on BOTTOM (solid shape): 45.17,80.02 45.55,79.64 45.55,73.92 45.17,73.54 42.82,73.54 41.68,72.4 39.01,72.4 38.76,72.65 38.76,75.45 42.06,78.75 42.06,80.02 42.7,80.66 45.17,80.66
GND on BOTTOM (solid shape): 66.44,123.39 66.44,122.06 67.08,121.42 68.41,121.42 68.41,120.6 67.78,120.6 67.59,120.79 64.35,120.79 63.9,121.23 63.02,121.23 63.02,121.87 65.11,121.87 65.37,122.12 65.37,123.39 65.49,123.52 66.32,123.52
GND on BOTTOM (solid shape): 167.92,65.06 167.92,64.4 166.46,62.94 166.46,61.26 166.19,61 163.47,61 162.69,61.78 162.69,63.71 162.08,64.32 162.08,66.11 164.1,68.13 164.84,68.13
GND on BOTTOM (solid shape): 142.44,130.59 142.44,128.99 141.65,128.99 141.5,128.84 141.5,127.85 141.45,127.8 141.3,127.8 141.25,127.85 141.25,128.69 141.17,128.76 141.1,128.76 141.02,128.69 141.02,127.85 140.97,127.8 140.82,127.8 140.77,127.85 140.77,130.64 142.39,130.64
GND on BOTTOM (solid shape): 145.24,72.1 145.24,67.59 145.15,67.5 141.64,67.5 141.59,67.55 141.59,69.52 141.25,69.86 138.52,69.86 138.01,70.37 138.01,70.58 138.12,70.7 141.48,70.7 141.6,70.83 141.6,72.12 141.64,72.16 145.17,72.16
GND on BOTTOM (solid shape): 166.01,92.97 166.01,91.86 165.38,91.22 162.71,91.22 162.46,91.48 162.46,92.06 162.56,92.16 162.86,92.16 162.96,92.06 162.96,91.78 163.12,91.63 164.46,91.63 164.9,92.06 164.9,92.97 165,93.08 165.91,93.08
GND on BOTTOM (solid shape): 170.31,65.26 171.12,65.26 172.06,66.2 172.44,66.2 173.76,64.88 173.76,64.58 173.56,64.37 173.25,64.37 172.72,64.91 172.11,64.91 171.83,64.63 170.76,64.63 170.43,64.3 170.25,64.3 168.45,66.1 168.45,66.2 168.86,66.61 168.96,66.61
GND on BOTTOM (solid shape): 69.37,75.05 69.37,72.65 69.18,72.46 68.67,72.46 68.52,72.32 68.52,70.53 68.51,70.52 67.58,70.52 67.58,73.11 67.4,73.29 67.4,74.84 67.75,75.19 67.75,75.64 67.8,75.69 68.73,75.69
GND on BOTTOM (solid shape): 245.39,128.79 245.64,128.53 247.72,128.53 248.03,128.23 248.03,127.85 247.8,127.62 247.8,127.07 247.67,126.95 245.71,126.95 245.2,126.44 245.2,125.8 245.13,125.74 244.88,125.74 244.82,125.8 244.82,129.42 244.88,129.49 245.39,129.49
GND on BOTTOM (solid shape): 57.94,106.69 58,106.63 58.51,106.63 58.89,106.25 59.18,106.25 59.37,106.05 59.37,104.83 59.19,104.65 58.39,104.65 58.34,104.6 58.32,104.6 58.32,104.57 58.19,104.45 58.19,103.21 58.02,103.04 57.01,103.04 56.86,102.88 55.9,102.88 55.78,103.01 55.78,110.75 57.94,110.75
GND on BOTTOM (solid shape): 157.04,83.9 155.73,83.9 155.73,82.18 157.05,82.18 157.05,80.22 156.95,80.12 155.95,80.12 155.62,80.45 153.07,80.45 152.55,80.97 150.65,80.97 150.58,81.04 150.58,81.99 150.77,82.18 152.4,82.18 153.06,81.52 155.04,81.52 155.19,81.67 155.19,84.11 157.04,84.11
GND on BOTTOM (solid shape): 42.95,117.68 44.47,117.68 44.5,117.65 44.5,116.89 43.78,116.17 43.78,115.71 43.58,115.52 43.58,113.1 42.57,112.09 40.79,112.09 40.79,112.6 41.74,112.6 42.19,113.04 42.19,114.76 41.81,115.14 40.11,115.14 39.08,114.11 37.35,114.11 37.34,114.12 36.85,114.12 36.41,114.56 36.41,117.35 36.73,117.66 39.44,117.66 39.65,117.87 42.76,117.87
GND on BOTTOM (solid shape): 15.84,77.73 15.84,75.13 16.09,74.88 16.09,74.55 16.17,74.47 17.55,74.47 17.59,74.43 17.59,73.57 17.55,73.53 16.09,73.53 16.09,73.12 15.96,73 15.96,71.73 15.31,71.08 13.36,71.08 12.81,71.63 12.81,74.81 12.93,74.93 14.13,74.93 14.63,75.42 14.63,77.66 14.77,77.8 15.77,77.8
GND on BOTTOM (solid shape): 161.12,131.46 161.16,131.46 161.35,131.27 161.55,131.09 161.57,131.07 161.86,130.86 162.17,130.68 162.28,130.62 162.39,130.5 162.39,129.49 162.2,129.3 161.44,129.3 161.38,129.36 161.38,129.55 161.12,129.8 159.92,129.8 159.66,130.06 159.66,131.46 160.23,131.46 160.42,131.65 160.93,131.65
GND on BOTTOM (solid shape): 145.23,133.11 145.78,131.75 146.71,130.6 146.71,130.31 146.65,130.25 146.33,130.25 146.2,130.38 146.2,130.57 145.95,130.82 145.5,130.82 145.5,131.01 145.25,131.27 144.17,131.27 143.72,131.71 143.72,133.11
GND on BOTTOM (solid shape): 10.33,99.33 10.33,96.16 0.61,96.16 0.61,102.18 0.69,102.38 0.9,102.47 3.97,102.47 3.99,102.44 4.77,101.98 5.36,102.67 5.36,102.88 6.78,102.88
GND on BOTTOM (solid shape): 57.74,59.34 57.74,58.56 57.97,58.33 58.98,58.33 59.1,58.2 59.1,57.69 59.03,57.62 58.75,57.62 58.55,57.42 58.55,55.86 58.74,55.67 59.19,55.67 59.32,55.54 59.32,55.06 59.26,55 55.59,55 55.42,54.84 55.42,54.47 55.32,54.37 54.63,54.37 54.63,54.37 54.53,54.37 54.47,54.42 54.47,57.8 54.37,57.91 54.01,57.91 53.92,57.99 53.92,58.58 53.98,58.63 54.34,58.63 54.44,58.62 54.54,58.63 54.87,58.63 55.03,58.8 55.03,58.99 55.12,59.08 55.83,59.08 55.89,59.03 55.89,58.78 56,58.67 56.86,58.67 57.01,58.81 57.01,59.34 57.11,59.43 57.65,59.43
GND on BOTTOM (solid shape): 151.76,76.4 151.76,76.17 152.36,75.58 153.31,75.58 153.69,75.95 155.22,75.95 155.6,75.58 156.54,75.58 157.12,76.16 157.38,76.16 157.48,76.06 157.48,75.47 157.28,75.27 156.74,75.27 156.69,75.32 155.54,75.32 155.41,75.19 155.41,74.62 155.28,74.5 153.62,74.5 153.5,74.61 153.5,74.69 153.33,74.86 152.41,74.86 152.09,74.55 152.09,73.85 152.35,73.59 152.35,69.96 152.12,69.73 150.98,69.73 150.98,76.34 151.15,76.52 151.65,76.52
GND on BOTTOM (solid shape): 128.42,122.5 128.42,121.74 128.34,121.66 127.47,121.66 127.26,121.45 127.26,119.05 127.18,118.96 126.53,118.96 126.44,119.01 126.44,119.11 126.13,119.65 125.83,119.11 125.82,119.01 125.74,118.96 124.99,118.96 123.46,120.49 123.46,122.52 128.4,122.52
GND on BOTTOM (solid shape): 47.5,129.8 43.59,129.8 43.59,129.81 40.89,132.11 42.72,135.15 44.33,135.15 44.44,135.16 44.54,135.19 44.65,135.24 44.74,135.3 47.5,135.3
GND on BOTTOM (solid shape): 271.6,54.65 274.07,53.62 275.1,51.15 275.1,47.75 273.43,47.75 273.04,48.15 266.11,48.15 266.1,51.15 267.13,53.62 269.6,54.65
GND on BOTTOM (solid shape): 299.7,91.39 299.91,91.31 299.99,91.1 299.99,89.25 299.91,89.04 299.7,88.96 297.31,88.96 297.31,86.2 297.22,85.99 297.01,85.91 288.08,85.91 288.06,85.94 287.28,86.4 286.69,85.7 286.69,84.66 283.23,84.66 282.92,84.97 282.92,88.09 283.42,88.59 288.17,88.59 289.41,89.83 289.41,91.34 289.46,91.39
GND on BOTTOM (solid shape): outline of 81 points within 177.19,51.26 187.96,56.35
GND on BOTTOM (solid shape): 12.04,75.35 12.04,71.34 12.97,70.4 14.48,70.4 15.32,69.56 17.02,69.56 17.34,69.24 17.34,68.44 17.07,68.17 13.73,68.17 13.5,68.4 13.5,69.25 13.5,69.35 13.48,69.44 13.4,69.61 13.29,69.75 13.03,69.91 12.73,69.95 12.35,69.79 12.13,69.45 3.18,69.45 2.98,69.54 2.89,69.75 2.89,71.4 2.98,71.61 3.18,71.7 4.3,71.7 4.56,71.77 4.75,71.97 4.79,72.08 4.8,72.2 4.8,74.45 6.67,76.32 11.07,76.32
GND on BOTTOM (solid shape): outline of 81 points within 46.23,88.56 52.96,97.5
GND on BOTTOM (solid shape): 33.29,51.03 35.76,52.05 38.24,51.03 40.61,48.65 38.17,48.65 38.06,48.63 37.96,48.56 37.74,48.34 34.64,45.26 34.6,45.21 34.56,45.16 34.19,44.79 34.12,44.69 34.1,44.58 34.1,42.44 31.87,44.66 30.85,47.14 31.87,49.61
GND on BOTTOM (solid shape): 146.1,51.01 149.96,55.1 154.1,51.29 154.1,51.25 154.1,50.32 153.95,49.77 153.9,49.2 153.9,48.95 153.87,48.88 153.8,48.85 146.1,48.85
GND on BOTTOM (solid shape): 125.01,99.78 125.13,99.74 125.26,99.78 125.27,99.78 125.54,99.78 125.66,99.66 125.66,99.16 125.56,99.05 125.53,98.9 125.51,98.83 125.45,98.79 125.23,98.63 125.21,98.35 125.22,98.32 125.15,98.25 125.13,98.25 124.97,97.8 125.39,98.03 125.38,98.05 125.47,98.14 125.54,98.12 125.54,98.07 125.53,97.95 125.58,97.83 125.61,97.8 125.19,97.37 125.1,97.35 125.03,97.4 124.97,97.48 124.89,97.54 124.53,97.9 124.53,97.91 124.45,98.01 124.33,98.07 124.27,98.12 124.26,98.2 124.21,98.49 123.95,98.62 123.93,98.62 123.89,98.66 123.89,98.69 123.9,98.73 123.95,98.75 124.19,98.83 124.31,99.06 124.31,99.08 124.52,99.29 124.52,99.38 124.52,99.39 124.54,99.51 124.51,99.63 124.5,99.73 124.59,99.78 125,99.78
GND on BOTTOM (solid shape): 286.69,72.1 287.28,71.4 288.06,71.86 288.08,71.89 297.01,71.89 297.22,71.81 297.31,71.6 297.31,69.95 297.22,69.74 297.01,69.66 293.9,69.66 293.54,69.51 293.39,69.15 293.39,66.75 293.54,66.39 293.9,66.24 300.2,66.24 300.41,66.16 300.49,65.95 300.49,50.63 300.41,50.42 300.2,50.34 299.5,50.34 299,50.13 298.79,49.63 298.79,48.03 299,47.53 299.5,47.32 300.2,47.32 300.41,47.24 300.49,47.03 300.49,46.41 295.9,46.41 295.86,46.4 295.67,46.4 295.07,47 295.07,50.28 295.97,51.18 299.02,51.18 299.3,51.46 299.3,62.49 297.39,64.4 294.22,64.4 292.89,63.07 285.84,63.07 285.52,63.38 285.52,64.84 282.92,67.45 282.92,72.78 283.3,73.16 286.69,73.16
GND on BOTTOM (solid shape): outline of 265 points within 1.8,35.31 17.34,56.76
GND on BOTTOM (solid shape): outline of 117 points within 119.58,96.56 124.41,99.78
GND on BOTTOM (solid shape): outline of 127 points within 30.32,0.21 299.29,53.65
GND on BOTTOM (solid shape): outline of 1124 points within 0.6,71.84 299.99,136.99
GND on BOTTOM (solid shape): outline of 9777 points within 75.08,49.86 141.69,64.91
GND on GND1 (solid shape): 222.07,80.09 222.2,75.53 217.67,76.02 216.56,77.51 217.13,77.95 217.41,77.96 217.66,77.82 218.88,76.54 221.36,76.48 221.42,78.96 220.19,80.24 220.06,80.49 220.09,80.78 220.58,81.34 220.74,81.52
GND on IN1 (solid shape): 7.71,101.99 7.71,101.93 10.33,99.31 10.33,96.21 10.28,96.16 0.61,96.16 0.61,102.18 0.69,102.38 0.9,102.47 3.97,102.47 3.99,102.44 4.77,101.98 5.36,102.67 5.36,102.88 6.82,102.88
GND on IN1 (solid shape): 299.7,91.39 299.91,91.31 299.99,91.1 299.99,89.25 299.91,89.04 299.7,88.96 297.31,88.96 297.31,86.2 297.22,85.99 297.01,85.91 288.08,85.91 288.06,85.94 287.28,86.4 286.69,85.7 286.69,84.66 283.23,84.66 282.92,84.97 282.92,88.09 283.42,88.59 288.19,88.59 289.42,89.81 289.42,91.35 289.46,91.39
GND on IN1 (solid shape): 14.69,75.2 14.69,70.19 15.32,69.56 17.02,69.56 17.34,69.24 17.34,68.44 17.07,68.17 13.73,68.17 13.5,68.4 13.5,69.25 13.5,69.35 13.48,69.44 13.4,69.61 13.29,69.75 13.03,69.91 12.73,69.95 12.35,69.79 12.13,69.45 3.18,69.45 2.98,69.54 2.89,69.75 2.89,71.4 2.98,71.61 3.18,71.7 4.3,71.7 4.56,71.77 4.75,71.97 4.79,72.08 4.8,72.2 4.8,74.45 6.67,76.32 13.57,76.32
GND on IN1 (solid shape): 286.69,72.1 287.28,71.4 288.06,71.86 288.08,71.89 297.01,71.89 297.22,71.81 297.31,71.6 297.31,69.95 297.22,69.74 297.01,69.66 293.9,69.66 293.54,69.51 293.39,69.15 293.39,66.75 293.54,66.39 293.9,66.24 300.2,66.24 300.41,66.16 300.49,65.95 300.49,50.63 300.41,50.42 300.2,50.34 299.5,50.34 299,50.13 298.79,49.63 298.79,48.03 299,47.53 299.5,47.32 300.2,47.32 300.41,47.24 300.49,47.03 300.49,46.41 295.9,46.41 295.85,46.4 295.64,46.4 295.17,46.87 295.17,50.18 295.49,50.49 298.22,50.49 298.85,51.13 298.85,60.59 298.41,61.03 298.41,61.42 298.6,61.61 298.6,63.07 297.27,64.4 294.22,64.4 294.16,64.34 288.38,64.34 287.11,63.07 285.84,63.07 285.58,63.32 285.58,63.83 285.84,64.08 285.84,65.67 282.92,68.59 282.92,72.78 283.3,73.16 286.69,73.16
GND on IN1 (solid shape): outline of 263 points within 1.81,35.31 17.37,56.77
GND on IN1 (solid shape): outline of 766 points within 7.2,100.39 26.19,111.59
GND on IN1 (solid shape): outline of 969 points within 30.25,0.21 299.29,53.68
GND on IN1 (solid shape): outline of 229 points within 0.61,71.84 299.99,136.99
GND on IN2 (solid shape): 7.71,101.99 7.71,101.93 10.33,99.31 10.33,96.31 10.18,96.16 0.61,96.16 0.61,102.18 0.69,102.38 0.9,102.47 3.97,102.47 3.99,102.44 4.77,101.98 5.36,102.67 5.36,102.88 6.82,102.88
GND on IN2 (solid shape): 299.7,91.39 299.91,91.31 299.99,91.1 299.99,89.25 299.91,89.04 299.7,88.96 297.31,88.96 297.31,86.2 297.22,85.99 297.01,85.91 288.08,85.91 288.06,85.94 287.28,86.4 286.69,85.7 286.69,84.66 283.23,84.66 282.92,84.97 282.92,88.09 283.42,88.59 288.17,88.59 289.41,89.83 289.41,91.35 289.46,91.39
GND on IN2 (solid shape): 14.7,73.08 14.7,70.18 15.32,69.56 17.02,69.56 17.34,69.24 17.34,68.44 17.07,68.17 13.73,68.17 13.5,68.4 13.5,69.25 13.5,69.35 13.48,69.44 13.4,69.61 13.29,69.75 13.03,69.91 12.73,69.95 12.35,69.79 12.13,69.45 3.18,69.45 2.98,69.54 2.89,69.75 2.89,71.4 2.98,71.61 3.18,71.7 4.3,71.7 4.56,71.77 4.75,71.97 4.79,72.08 4.8,72.2 4.8,74.45 6.67,76.32 11.46,76.32
GND on IN2 (solid shape): outline of 411 points within 282.92,46.4 300.49,73.16
GND on IN2 (solid shape): outline of 1183 points within 1.8,0.21 299.29,56.75
GND on IN2 (solid shape): outline of 1382 points within 0.61,71.84 299.99,136.99
GND on IN2 (solid shape): outline of 10906 points within 75.46,53.53 143.22,99.01
GND on IN3 (solid shape): 7.71,101.99 7.71,101.93 10.33,99.31 10.33,96.16 0.61,96.16 0.61,102.18 0.69,102.38 0.9,102.47 3.97,102.47 3.99,102.44 4.77,101.98 5.36,102.67 5.36,102.88 6.82,102.88
GND on IN3 (solid shape): 299.7,91.39 299.91,91.31 299.99,91.1 299.99,89.25 299.91,89.04 299.7,88.96 297.31,88.96 297.31,86.2 297.22,85.99 297.01,85.91 288.08,85.91 288.06,85.94 287.28,86.4 286.69,85.7 286.69,84.66 283.23,84.66 282.92,84.97 282.92,88.09 283.42,88.59 288.18,88.59 289.4,89.82 289.4,91.34 289.46,91.39
GND on IN3 (solid shape): 14.7,75.2 14.7,70.18 15.32,69.56 17.02,69.56 17.34,69.24 17.34,68.44 17.07,68.17 13.73,68.17 13.5,68.4 13.5,69.25 13.5,69.35 13.48,69.44 13.4,69.61 13.29,69.75 13.03,69.91 12.73,69.95 12.35,69.79 12.13,69.45 3.18,69.45 2.98,69.54 2.89,69.75 2.89,71.4 2.98,71.61 3.18,71.7 4.3,71.7 4.56,71.77 4.75,71.97 4.79,72.08 4.8,72.2 4.8,74.45 6.67,76.32 13.58,76.32
GND on IN3 (solid shape): outline of 265 points within 1.8,35.31 17.31,56.74
GND on IN3 (solid shape): outline of 374 points within 282.92,46.4 300.49,73.16
GND on IN3 (solid shape): outline of 714 points within 28.98,0.21 299.29,53.86
GND on IN3 (solid shape): outline of 850 points within 5.36,100.45 23.07,111.59
GND on IN3 (solid shape): outline of 225 points within 0.61,71.84 299.99,136.99
GND on GND2 (solid shape): 222.18,80 222.08,75.42 217.57,76.18 216.48,77.44 217.13,77.95 217.41,77.96 217.66,77.82 218.88,76.54 221.36,76.48 221.42,78.96 220.19,80.24 220.06,80.49 220.09,80.78 220.6,81.37 220.75,81.53
GND on GND1: outline of 348 points within 0.21,0.21 300.49,136.99 ; 2 cut-outs
GND on VCC: 276.77,1.17 276.77,45.39 276.64,46.03 276.28,46.57 275.09,47.77 282.6,55.28 282.6,88.44 282.73,88.57 288.13,88.57 289.39,89.83 289.39,90.43 299.03,90.43 299.03,89.92 296.35,89.92 296.35,86.87 288.59,86.87 286.77,87.25 285.73,85.7 285.73,72.1 286.77,70.55 288.59,70.93 296.35,70.93 296.35,70.62 293.9,70.62 292.86,70.19 292.43,69.15 292.43,66.75 292.86,65.71 293.9,65.28 299.53,65.28 299.53,51.3 299.5,51.3 298.32,50.81 297.83,49.63 297.83,48.03 297.86,47.69 297.97,47.37 295.9,47.37 295.42,47.29 295,47.06 294.62,47.45 281.31,47.45 279.8,45.94 279.8,33.27 283.03,30.05 298.33,30.05 298.33,23.67 293.9,23.67 292.86,23.24 292.43,22.2 292.43,1.17 ; 1 cut-out
GND on VCC: 6.32,109.42 6.32,111.62 5.28,113.17 3.46,112.79 1.57,112.79 1.57,114.46 2.43,114.96 2.77,115.9 2.77,116.93 9.58,116.93 9.58,116.5 9.96,115.18 10.99,114.27 8.15,111.43 8.15,109.91 7.67,109.42
GND on VCC: 4.92,36.27 5.54,36.81 5.77,37.6 5.77,40 5.34,41.04 4.3,41.47 2.77,41.47 2.77,52.53 3.55,53.06 3.85,53.95 3.85,54.48 11.61,54.48 13.43,54.1 14.47,55.65 14.47,69.25 13.43,70.8 11.61,70.42 3.85,70.42 3.85,70.73 4.3,70.73 5.34,71.16 5.77,72.2 5.77,74.6 5.34,75.64 4.3,76.07 1.17,76.07 1.17,76.73 9.9,76.73 11.45,77.77 11.07,79.59 11.07,91.61 11.45,93.43 9.9,94.47 1.17,94.47 1.17,94.5 1.47,94.96 1.57,95.5 1.57,101.51 3.46,101.51 5.28,101.13 6.32,102.67 6.32,104.91 7.26,104.91 7.39,104.79 12.51,104.79 12.91,105.19 12.91,108.17 14.1,109.36 16.79,109.36 16.79,109.04 18.38,107.45 18.38,104.13 17.55,103.3 17.55,98.69 17.36,98.5 14.4,98.5 13.8,97.91 13.8,73.18 17.42,69.57 17.42,54.41 16.91,53.9 16.91,51.28 17.57,50.62 36.37,50.62 37.31,49.68 33.45,49.38 33.27,45.52 33.02,45.08 32.93,44.58 32.93,36.27 31.52,36.27 31.52,40 30.48,41.55 28.66,41.17 10.74,41.17 8.92,41.55 7.88,40 7.88,36.27 ; 1 cut-out
GND on IN2: 76.86,105.36 87.97,105.36 88.16,105.17 88.16,104.66 87.72,104.21 82.26,104.21 79.34,101.29 74.06,101.29 73.75,101.61 73.75,104.28 74.13,104.66 76.16,104.66
GND on GND2: outline of 390 points within 0.21,0.21 300.49,136.99
GNDA on TOP (solid shape): 252.68,55.36 252.68,54.27 252.83,54.12 253.93,54.12 254.18,54.37 255.61,54.37 255.65,54.33 255.65,52.01 255.45,51.81 251.13,51.81 251.05,51.89 251.05,55 251.31,55.26 252.12,55.26 252.27,55.41 252.63,55.41
GNDA on BOTTOM (solid shape): 291.06,41.79 291.06,40.78 290.9,40.63 289.41,40.63 289.25,40.78 289.25,41.92 289.56,42.23 290.63,42.23
GNDA on BOTTOM (solid shape): 285.72,31.25 286.54,31.25 286.61,31.33 286.61,31.79 286.89,32.07 288.14,32.07 288.39,31.81 288.39,31.25 287.83,30.69 283.26,30.69 283.01,30.95 283.01,32.12 283.44,32.55 284.43,32.55
GNDA on TOP: 264.37,58.62 266.34,58.62 266.53,58.43 266.53,57.8 265.96,57.8 265.96,57.29 266.53,57.29 266.53,56.84 266.22,56.53 264.37,56.53
GNDA on GND1: 251.1,49.29 251.1,56.41 249.83,57.68 249.83,61.4 251.1,62.67 251.1,63.05 251.18,63.13 254.2,63.13 254.72,62.61 254.72,57.73 258.41,57.73 258.41,56.99 258.34,56.92 258.34,56.76 259.48,55.62 259.48,53.78 259.85,53.41 262.42,53.41 262.79,53.78 262.79,56.41 262.48,56.72 261.28,56.72 261.14,56.86 261.14,58.26 261.02,58.37 260.93,58.37 260.81,58.49 259.93,58.49 259.93,59.38 260.9,59.38 261.14,59.19 261.14,59.11 261.25,59 261.69,59 262.14,58.56 266.2,58.56 269.39,55.37 269.39,53.43 265.25,49.29
GNDA on GND1: 283.19,30.43 280.19,33.43 280.19,45.78 281.47,47.06 294.46,47.06 295.43,46.09 295.4,46 295.39,45.9 295.39,43.5 295.54,43.14 295.9,42.99 299,42.99 299.21,42.91 299.29,42.7 299.29,40.75 299.21,40.54 299,40.46 286.6,40.46 285.9,39.85 286.39,39.07 286.39,33.63 285.9,32.85 286.6,32.24 299,32.24 299.21,32.16 299.29,31.95 299.29,30.43
GNDA on VCC: 251.1,49.32 251.1,56.41 249.83,57.68 249.83,61.4 251.1,62.67 251.1,63.05 251.18,63.13 254.2,63.13 254.72,62.61 254.72,57.73 258.41,57.73 258.41,56.99 258.34,56.92 258.34,56.76 259.48,55.62 259.48,53.78 259.85,53.41 262.42,53.41 262.79,53.78 262.79,56.41 262.48,56.72 261.28,56.72 261.14,56.86 261.14,58.26 261.02,58.37 260.93,58.37 260.81,58.49 259.93,58.49 259.93,59.38 260.9,59.38 261.14,59.19 261.14,59.11 261.25,59 261.69,59 262.14,58.56 266.2,58.56 269.39,55.37 269.39,53.43 267.55,51.59 267.55,49.56 267.31,49.32
GNDA on VCC: 283.19,30.43 280.19,33.43 280.19,45.78 281.47,47.06 294.46,47.06 294.73,46.79 294.51,46.37 294.43,45.9 294.43,43.5 294.86,42.46 295.9,42.03 298.33,42.03 298.33,41.42 286.6,41.42 285.05,40.38 285.43,38.56 285.43,34.14 285.05,32.32 286.6,31.28 298.33,31.28 298.33,30.43
